              <name>AOE</name>
              <bitOffset>14</bitOffset>
              <bitWidth>1</bitWidth>
            </field>
            <field>
              <name>MOE</name>
              <bitOffset>15</bitOffset>
              <bitWidth>1</bitWidth>
            </field>
            <field>
              <name>BKF</name>
              <bitOffset>16</bitOffset>
              <bitWidth>4</bitWidth>
            </field>
            <field>
              <name>BK2F</name>
              <bitOffset>20</bitOffset>
              <bitWidth>4</bitWidth>
            </field>
            <field>
              <name>BK2E</name>
              <bitOffset>24</bitOffset>
              <bitWidth>1</bitWidth>
            </field>
            <field>
              <name>BK2P</name>
              <bitOffset>25</bitOffset>
              <bitWidth>1</bitWidth>
            </field>
            <field>
              <name>BKDSRM</name>
              <bitOffset>26</bitOffset>
              <bitWidth>1</bitWidth>
            </field>
            <field>
              <name>BK2DSRM</name>
              <bitOffset>27</bitOffset>
              <bitWidth>1</bitWidth>
            </field>
            <field>
              <name>BKBID</name>
              <bitOffset>28</bitOffset>
              <bitWidth>1</bitWidth>
            </field>
            <field>
              <name>BK2BID</name>
              <bitOffset>29</bitOffset>
              <bitWidth>1</bitWidth>
            </field>
          </fields>
        </register>
        <register>
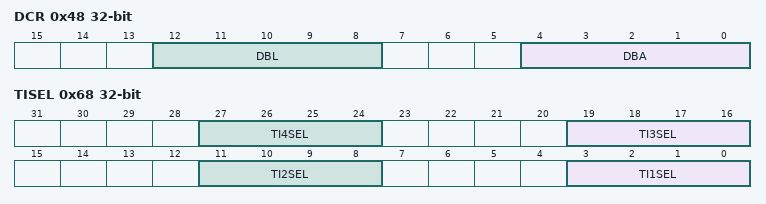
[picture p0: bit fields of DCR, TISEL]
          <name>DCR</name>
          <addressOffset>0x48</addressOffset>
          <size>0x20</size>
          <fields>
            <field>
              <name>DBA</name>
              <bitOffset>0</bitOffset>
              <bitWidth>5</bitWidth>
            </field>
            <field>
              <name>DBL</name>
              <bitOffset>8</bitOffset>
              <bitWidth>5</bitWidth>
            </field>
          </fields>
        </register>
        <register>
          <name>DMAR</name>
          <addressOffset>0x4c</addressOffset>
          <size>0x20</size>
          <fields>
            <field>
              <name>DMAB</name>
              <bitOffset>0</bitOffset>
              <bitWidth>16</bitWidth>
            </field>
          </fields>
        </register>
        <register>
          <name>CCMR3</name>
          <addressOffset>0x54</addressOffset>
          <size>0x20</size>
          <fields>
            <field>
              <name>OC5FE</name>
              <bitOffset>2</bitOffset>
              <bitWidth>1</bitWidth>
            </field>
            <field>
              <name>OC5PE</name>
              <bitOffset>3</bitOffset>
              <bitWidth>1</bitWidth>
            </field>
            <field>
              <name>OC5M</name>
              <bitOffset>4</bitOffset>
              <bitWidth>13</bitWidth>
            </field>
            <field>
              <name>OC5CE</name>
              <bitOffset>7</bitOffset>
              <bitWidth>1</bitWidth>
            </field>
            <field>
              <name>OC6FE</name>
              <bitOffset>10</bitOffset>
              <bitWidth>1</bitWidth>
            </field>
            <field>
              <name>OC6PE</name>
              <bitOffset>11</bitOffset>
              <bitWidth>1</bitWidth>
            </field>
            <field>
              <name>OC6M</name>
              <bitOffset>12</bitOffset>
              <bitWidth>13</bitWidth>
            </field>
            <field>
              <name>OC6CE</name>
              <bitOffset>15</bitOffset>
              <bitWidth>1</bitWidth>
            </field>
          </fields>
        </register>
        <register>
          <name>CCR5</name>
          <addressOffset>0x58</addressOffset>
          <size>0x20</size>
          <fields>
            <field>
              <name>CCR5</name>
              <bitOffset>0</bitOffset>
              <bitWidth>32</bitWidth>
            </field>
            <field>
              <name>GC5C1</name>
              <bitOffset>29</bitOffset>
              <bitWidth>1</bitWidth>
            </field>
            <field>
              <name>GC5C2</name>
              <bitOffset>30</bitOffset>
              <bitWidth>1</bitWidth>
            </field>
            <field>
              <name>GC5C3</name>
              <bitOffset>31</bitOffset>
              <bitWidth>1</bitWidth>
            </field>
          </fields>
        </register>
        <register>
          <name>CCR6</name>
          <addressOffset>0x5c</addressOffset>
          <size>0x20</size>
          <fields>
            <field>
              <name>CCR6</name>
              <bitOffset>0</bitOffset>
              <bitWidth>16</bitWidth>
            </field>
          </fields>
        </register>
        <register>
          <name>AF1</name>
          <addressOffset>0x60</addressOffset>
          <size>0x20</size>
        </register>
        <register>
          <name>AF2</name>
          <addressOffset>0x64</addressOffset>
          <size>0x20</size>
        </register>
        <register>
          <name>TISEL</name>
          <addressOffset>0x68</addressOffset>
          <size>0x20</size>
          <fields>
            <field>
              <name>TI1SEL</name>
              <bitOffset>0</bitOffset>
              <bitWidth>4</bitWidth>
            </field>
            <field>
              <name>TI2SEL</name>
              <bitOffset>8</bitOffset>
              <bitWidth>4</bitWidth>
            </field>
            <field>
              <name>TI3SEL</name>
              <bitOffset>16</bitOffset>
              <bitWidth>4</bitWidth>
            </field>
            <field>
              <name>TI4SEL</name>
              <bitOffset>24</bitOffset>
              <bitWidth>4</bitWidth>
            </field>
          </fields>
        </register>
      </registers>
    </peripheral>
    <peripheral>
      <name>SPI5</name>
      <baseAddress>0x40015000</baseAddress>
      <registers>
        <register>
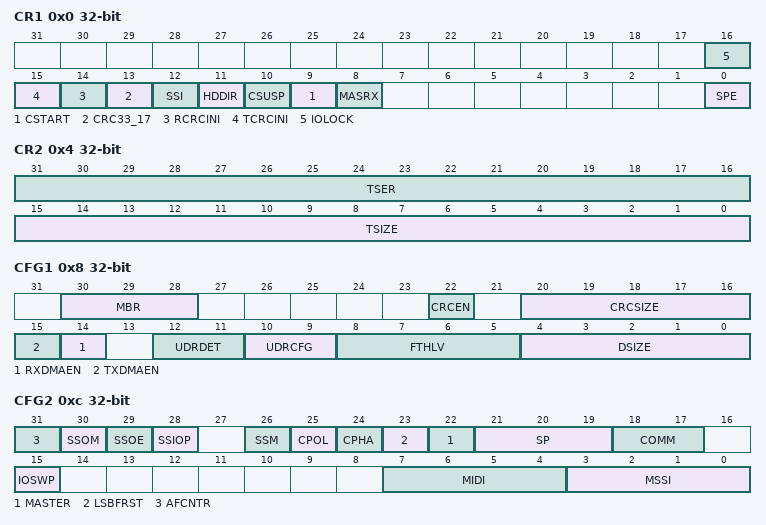
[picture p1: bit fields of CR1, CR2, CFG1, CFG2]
          <name>CR1</name>
          <addressOffset>0x0</addressOffset>
          <size>0x20</size>
          <fields>
            <field>
              <name>SPE</name>
              <bitOffset>0</bitOffset>
              <bitWidth>1</bitWidth>
            </field>
            <field>
              <name>MASRX</name>
              <bitOffset>8</bitOffset>
              <bitWidth>1</bitWidth>
            </field>
            <field>
              <name>CSTART</name>
              <bitOffset>9</bitOffset>
              <bitWidth>1</bitWidth>
            </field>
            <field>
              <name>CSUSP</name>
              <bitOffset>10</bitOffset>
              <bitWidth>1</bitWidth>
            </field>
            <field>
              <name>HDDIR</name>
              <bitOffset>11</bitOffset>
              <bitWidth>1</bitWidth>
            </field>
            <field>
              <name>SSI</name>
              <bitOffset>12</bitOffset>
              <bitWidth>1</bitWidth>
            </field>
            <field>
              <name>CRC33_17</name>
              <bitOffset>13</bitOffset>
              <bitWidth>1</bitWidth>
            </field>
            <field>
              <name>RCRCINI</name>
              <bitOffset>14</bitOffset>
              <bitWidth>1</bitWidth>
            </field>
            <field>
              <name>TCRCINI</name>
              <bitOffset>15</bitOffset>
              <bitWidth>1</bitWidth>
            </field>
            <field>
              <name>IOLOCK</name>
              <bitOffset>16</bitOffset>
              <bitWidth>1</bitWidth>
            </field>
          </fields>
        </register>
        <register>
          <name>CR2</name>
          <addressOffset>0x4</addressOffset>
          <size>0x20</size>
          <fields>
            <field>
              <name>TSIZE</name>
              <bitOffset>0</bitOffset>
              <bitWidth>16</bitWidth>
            </field>
            <field>
              <name>TSER</name>
              <bitOffset>16</bitOffset>
              <bitWidth>16</bitWidth>
            </field>
          </fields>
        </register>
        <register>
          <name>CFG1</name>
          <addressOffset>0x8</addressOffset>
          <size>0x20</size>
          <fields>
            <field>
              <name>DSIZE</name>
              <bitOffset>0</bitOffset>
              <bitWidth>5</bitWidth>
            </field>
            <field>
              <name>FTHLV</name>
              <bitOffset>5</bitOffset>
              <bitWidth>4</bitWidth>
            </field>
            <field>
              <name>UDRCFG</name>
              <bitOffset>9</bitOffset>
              <bitWidth>2</bitWidth>
            </field>
            <field>
              <name>UDRDET</name>
              <bitOffset>11</bitOffset>
              <bitWidth>2</bitWidth>
            </field>
            <field>
              <name>RXDMAEN</name>
              <bitOffset>14</bitOffset>
              <bitWidth>1</bitWidth>
            </field>
            <field>
              <name>TXDMAEN</name>
              <bitOffset>15</bitOffset>
              <bitWidth>1</bitWidth>
            </field>
            <field>
              <name>CRCSIZE</name>
              <bitOffset>16</bitOffset>
              <bitWidth>5</bitWidth>
            </field>
            <field>
              <name>CRCEN</name>
              <bitOffset>22</bitOffset>
              <bitWidth>1</bitWidth>
            </field>
            <field>
              <name>MBR</name>
              <bitOffset>28</bitOffset>
              <bitWidth>3</bitWidth>
            </field>
          </fields>
        </register>
        <register>
          <name>CFG2</name>
          <addressOffset>0xc</addressOffset>
          <size>0x20</size>
          <fields>
            <field>
              <name>MSSI</name>
              <bitOffset>0</bitOffset>
              <bitWidth>4</bitWidth>
            </field>
            <field>
              <name>MIDI</name>
              <bitOffset>4</bitOffset>
              <bitWidth>4</bitWidth>
            </field>
            <field>
              <name>IOSWP</name>
              <bitOffset>15</bitOffset>
              <bitWidth>1</bitWidth>
            </field>
            <field>
              <name>COMM</name>
              <bitOffset>17</bitOffset>
              <bitWidth>2</bitWidth>
            </field>
            <field>
              <name>SP</name>
              <bitOffset>19</bitOffset>
              <bitWidth>3</bitWidth>
            </field>
            <field>
              <name>MASTER</name>
              <bitOffset>22</bitOffset>
              <bitWidth>1</bitWidth>
            </field>
            <field>
              <name>LSBFRST</name>
              <bitOffset>23</bitOffset>
              <bitWidth>1</bitWidth>
            </field>
            <field>
              <name>CPHA</name>
              <bitOffset>24</bitOffset>
              <bitWidth>1</bitWidth>
            </field>
            <field>
              <name>CPOL</name>
              <bitOffset>25</bitOffset>
              <bitWidth>1</bitWidth>
            </field>
            <field>
              <name>SSM</name>
              <bitOffset>26</bitOffset>
              <bitWidth>1</bitWidth>
            </field>
            <field>
              <name>SSIOP</name>
              <bitOffset>28</bitOffset>
              <bitWidth>1</bitWidth>
            </field>
            <field>
              <name>SSOE</name>
              <bitOffset>29</bitOffset>
              <bitWidth>1</bitWidth>
            </field>
            <field>
              <name>SSOM</name>
              <bitOffset>30</bitOffset>
              <bitWidth>1</bitWidth>
            </field>
            <field>
              <name>AFCNTR</name>
              <bitOffset>31</bitOffset>
              <bitWidth>1</bitWidth>
            </field>
          </fields>
        </register>
        <register>
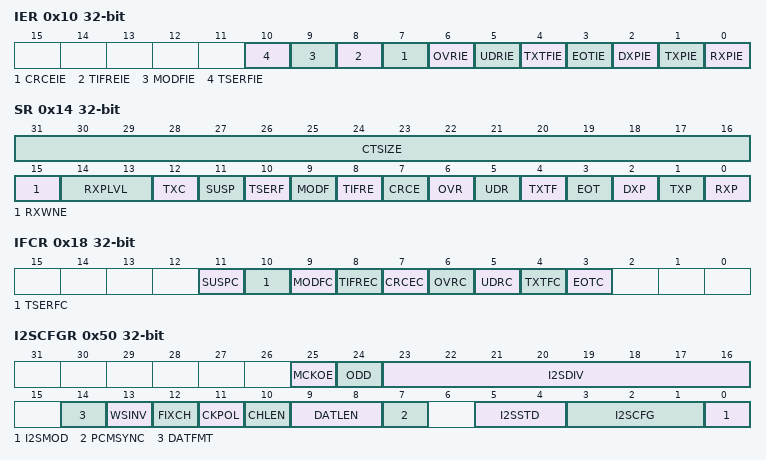
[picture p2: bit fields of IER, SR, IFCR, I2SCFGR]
          <name>IER</name>
          <addressOffset>0x10</addressOffset>
          <size>0x20</size>
          <fields>
            <field>
              <name>RXPIE</name>
              <bitOffset>0</bitOffset>
              <bitWidth>1</bitWidth>
            </field>
            <field>
              <name>TXPIE</name>
              <bitOffset>1</bitOffset>
              <bitWidth>1</bitWidth>
            </field>
            <field>
              <name>DXPIE</name>
              <bitOffset>2</bitOffset>
              <bitWidth>1</bitWidth>
            </field>
            <field>
              <name>EOTIE</name>
              <bitOffset>3</bitOffset>
              <bitWidth>1</bitWidth>
            </field>
            <field>
              <name>TXTFIE</name>
              <bitOffset>4</bitOffset>
              <bitWidth>1</bitWidth>
            </field>
            <field>
              <name>UDRIE</name>
              <bitOffset>5</bitOffset>
              <bitWidth>1</bitWidth>
            </field>
            <field>
              <name>OVRIE</name>
              <bitOffset>6</bitOffset>
              <bitWidth>1</bitWidth>
            </field>
            <field>
              <name>CRCEIE</name>
              <bitOffset>7</bitOffset>
              <bitWidth>1</bitWidth>
            </field>
            <field>
              <name>TIFREIE</name>
              <bitOffset>8</bitOffset>
              <bitWidth>1</bitWidth>
            </field>
            <field>
              <name>MODFIE</name>
              <bitOffset>9</bitOffset>
              <bitWidth>1</bitWidth>
            </field>
            <field>
              <name>TSERFIE</name>
              <bitOffset>10</bitOffset>
              <bitWidth>1</bitWidth>
            </field>
          </fields>
        </register>
        <register>
          <name>SR</name>
          <addressOffset>0x14</addressOffset>
          <size>0x20</size>
          <fields>
            <field>
              <name>RXP</name>
              <bitOffset>0</bitOffset>
              <bitWidth>1</bitWidth>
            </field>
            <field>
              <name>TXP</name>
              <bitOffset>1</bitOffset>
              <bitWidth>1</bitWidth>
            </field>
            <field>
              <name>DXP</name>
              <bitOffset>2</bitOffset>
              <bitWidth>1</bitWidth>
            </field>
            <field>
              <name>EOT</name>
              <bitOffset>3</bitOffset>
              <bitWidth>1</bitWidth>
            </field>
            <field>
              <name>TXTF</name>
              <bitOffset>4</bitOffset>
              <bitWidth>1</bitWidth>
            </field>
            <field>
              <name>UDR</name>
              <bitOffset>5</bitOffset>
              <bitWidth>1</bitWidth>
            </field>
            <field>
              <name>OVR</name>
              <bitOffset>6</bitOffset>
              <bitWidth>1</bitWidth>
            </field>
            <field>
              <name>CRCE</name>
              <bitOffset>7</bitOffset>
              <bitWidth>1</bitWidth>
            </field>
            <field>
              <name>TIFRE</name>
              <bitOffset>8</bitOffset>
              <bitWidth>1</bitWidth>
            </field>
            <field>
              <name>MODF</name>
              <bitOffset>9</bitOffset>
              <bitWidth>1</bitWidth>
            </field>
            <field>
              <name>TSERF</name>
              <bitOffset>10</bitOffset>
              <bitWidth>1</bitWidth>
            </field>
            <field>
              <name>SUSP</name>
              <bitOffset>11</bitOffset>
              <bitWidth>1</bitWidth>
            </field>
            <field>
              <name>TXC</name>
              <bitOffset>12</bitOffset>
              <bitWidth>1</bitWidth>
            </field>
            <field>
              <name>RXPLVL</name>
              <bitOffset>13</bitOffset>
              <bitWidth>2</bitWidth>
            </field>
            <field>
              <name>RXWNE</name>
              <bitOffset>15</bitOffset>
              <bitWidth>1</bitWidth>
            </field>
            <field>
              <name>CTSIZE</name>
              <bitOffset>16</bitOffset>
              <bitWidth>16</bitWidth>
            </field>
          </fields>
        </register>
        <register>
          <name>IFCR</name>
          <addressOffset>0x18</addressOffset>
          <size>0x20</size>
          <fields>
            <field>
              <name>EOTC</name>
              <bitOffset>3</bitOffset>
              <bitWidth>1</bitWidth>
            </field>
            <field>
              <name>TXTFC</name>
              <bitOffset>4</bitOffset>
              <bitWidth>1</bitWidth>
            </field>
            <field>
              <name>UDRC</name>
              <bitOffset>5</bitOffset>
              <bitWidth>1</bitWidth>
            </field>
            <field>
              <name>OVRC</name>
              <bitOffset>6</bitOffset>
              <bitWidth>1</bitWidth>
            </field>
            <field>
              <name>CRCEC</name>
              <bitOffset>7</bitOffset>
              <bitWidth>1</bitWidth>
            </field>
            <field>
              <name>TIFREC</name>
              <bitOffset>8</bitOffset>
              <bitWidth>1</bitWidth>
            </field>
            <field>
              <name>MODFC</name>
              <bitOffset>9</bitOffset>
              <bitWidth>1</bitWidth>
            </field>
            <field>
              <name>TSERFC</name>
              <bitOffset>10</bitOffset>
              <bitWidth>1</bitWidth>
            </field>
            <field>
              <name>SUSPC</name>
              <bitOffset>11</bitOffset>
              <bitWidth>1</bitWidth>
            </field>
          </fields>
        </register>
        <register>
          <name>TXDR</name>
          <addressOffset>0x20</addressOffset>
          <size>0x20</size>
          <fields>
            <field>
              <name>TXDR</name>
              <bitOffset>0</bitOffset>
              <bitWidth>32</bitWidth>
            </field>
          </fields>
        </register>
        <register>
          <name>RXDR</name>
          <addressOffset>0x30</addressOffset>
          <size>0x20</size>
          <fields>
            <field>
              <name>RXDR</name>
              <bitOffset>0</bitOffset>
              <bitWidth>32</bitWidth>
            </field>
          </fields>
        </register>
        <register>
          <name>CRCPOLY</name>
          <addressOffset>0x40</addressOffset>
          <size>0x20</size>
          <fields>
            <field>
              <name>CRCPOLY</name>
              <bitOffset>0</bitOffset>
              <bitWidth>32</bitWidth>
            </field>
          </fields>
        </register>
        <register>
          <name>TXCRC</name>
          <addressOffset>0x44</addressOffset>
          <size>0x20</size>
          <fields>
            <field>
              <name>TXCRC</name>
              <bitOffset>0</bitOffset>
              <bitWidth>32</bitWidth>
            </field>
          </fields>
        </register>
        <register>
          <name>RXCRC</name>
          <addressOffset>0x48</addressOffset>
          <size>0x20</size>
          <fields>
            <field>
              <name>RXCRC</name>
              <bitOffset>0</bitOffset>
              <bitWidth>32</bitWidth>
            </field>
          </fields>
        </register>
        <register>
          <name>UDRDR</name>
          <addressOffset>0x4c</addressOffset>
          <size>0x20</size>
          <fields>
            <field>
              <name>UDRDR</name>
              <bitOffset>0</bitOffset>
              <bitWidth>32</bitWidth>
            </field>
          </fields>
        </register>
        <register>
          <name>I2SCFGR</name>
          <addressOffset>0x50</addressOffset>
          <size>0x20</size>
          <fields>
            <field>
              <name>I2SMOD</name>
              <bitOffset>0</bitOffset>
              <bitWidth>1</bitWidth>
            </field>
            <field>
              <name>I2SCFG</name>
              <bitOffset>1</bitOffset>
              <bitWidth>3</bitWidth>
            </field>
            <field>
              <name>I2SSTD</name>
              <bitOffset>4</bitOffset>
              <bitWidth>2</bitWidth>
            </field>
            <field>
              <name>PCMSYNC</name>
              <bitOffset>7</bitOffset>
              <bitWidth>1</bitWidth>
            </field>
            <field>
              <name>DATLEN</name>
              <bitOffset>8</bitOffset>
              <bitWidth>2</bitWidth>
            </field>
            <field>
              <name>CHLEN</name>
              <bitOffset>10</bitOffset>
              <bitWidth>1</bitWidth>
            </field>
            <field>
              <name>CKPOL</name>
              <bitOffset>11</bitOffset>
              <bitWidth>1</bitWidth>
            </field>
            <field>
              <name>FIXCH</name>
              <bitOffset>12</bitOffset>
              <bitWidth>1</bitWidth>
            </field>
            <field>
              <name>WSINV</name>
              <bitOffset>13</bitOffset>
              <bitWidth>1</bitWidth>
            </field>
            <field>
              <name>DATFMT</name>
              <bitOffset>14</bitOffset>
              <bitWidth>1</bitWidth>
            </field>
            <field>
              <name>I2SDIV</name>
              <bitOffset>16</bitOffset>
              <bitWidth>8</bitWidth>
            </field>
            <field>
              <name>ODD</name>
              <bitOffset>24</bitOffset>
              <bitWidth>1</bitWidth>
            </field>
            <field>
              <name>MCKOE</name>
              <bitOffset>25</bitOffset>
              <bitWidth>1</bitWidth>
            </field>
          </fields>
        </register>
      </registers>
    </peripheral>
    <peripheral>
      <name>SAI1</name>
      <baseAddress>0x40015800</baseAddress>
      <registers>
        <register>
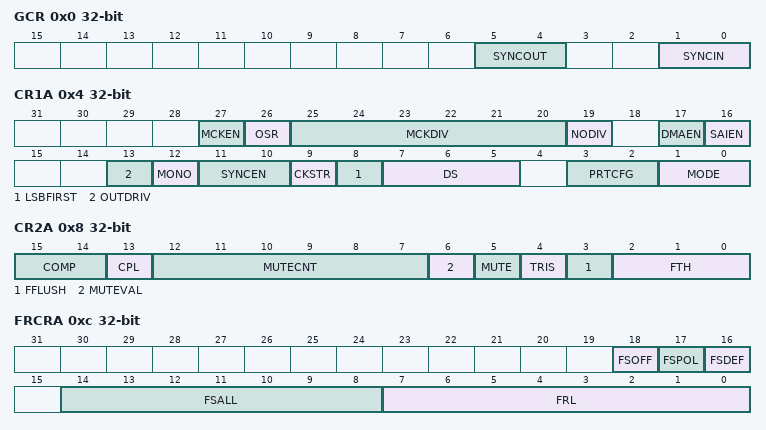
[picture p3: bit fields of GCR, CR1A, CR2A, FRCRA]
          <name>GCR</name>
          <addressOffset>0x0</addressOffset>
          <size>0x20</size>
          <fields>
            <field>
              <name>SYNCIN</name>
              <bitOffset>0</bitOffset>
              <bitWidth>2</bitWidth>
            </field>
            <field>
              <name>SYNCOUT</name>
              <bitOffset>4</bitOffset>
              <bitWidth>2</bitWidth>
            </field>
          </fields>
        </register>
        <register>
          <name>CR1A</name>
          <addressOffset>0x4</addressOffset>
          <size>0x20</size>
          <fields>
            <field>
              <name>MODE</name>
              <bitOffset>0</bitOffset>
              <bitWidth>2</bitWidth>
            </field>
            <field>
              <name>PRTCFG</name>
              <bitOffset>2</bitOffset>
              <bitWidth>2</bitWidth>
            </field>
            <field>
              <name>DS</name>
              <bitOffset>5</bitOffset>
              <bitWidth>3</bitWidth>
            </field>
            <field>
              <name>LSBFIRST</name>
              <bitOffset>8</bitOffset>
              <bitWidth>1</bitWidth>
            </field>
            <field>
              <name>CKSTR</name>
              <bitOffset>9</bitOffset>
              <bitWidth>1</bitWidth>
            </field>
            <field>
              <name>SYNCEN</name>
              <bitOffset>10</bitOffset>
              <bitWidth>2</bitWidth>
            </field>
            <field>
              <name>MONO</name>
              <bitOffset>12</bitOffset>
              <bitWidth>1</bitWidth>
            </field>
            <field>
              <name>OUTDRIV</name>
              <bitOffset>13</bitOffset>
              <bitWidth>1</bitWidth>
            </field>
            <field>
              <name>SAIEN</name>
              <bitOffset>16</bitOffset>
              <bitWidth>1</bitWidth>
            </field>
            <field>
              <name>DMAEN</name>
              <bitOffset>17</bitOffset>
              <bitWidth>1</bitWidth>
            </field>
            <field>
              <name>NODIV</name>
              <bitOffset>19</bitOffset>
              <bitWidth>1</bitWidth>
            </field>
            <field>
              <name>MCKDIV</name>
              <bitOffset>20</bitOffset>
              <bitWidth>6</bitWidth>
            </field>
            <field>
              <name>OSR</name>
              <bitOffset>26</bitOffset>
              <bitWidth>1</bitWidth>
            </field>
            <field>
              <name>MCKEN</name>
              <bitOffset>27</bitOffset>
              <bitWidth>1</bitWidth>
            </field>
          </fields>
        </register>
        <register>
          <name>CR1A</name>
          <addressOffset>0x4</addressOffset>
          <size>0x20</size>
          <fields>
            <field>
              <name>MODE</name>
              <bitOffset>0</bitOffset>
              <bitWidth>2</bitWidth>
            </field>
            <field>
              <name>PRTCFG</name>
              <bitOffset>2</bitOffset>
              <bitWidth>2</bitWidth>
            </field>
            <field>
              <name>DS</name>
              <bitOffset>5</bitOffset>
              <bitWidth>3</bitWidth>
            </field>
            <field>
              <name>LSBFIRST</name>
              <bitOffset>8</bitOffset>
              <bitWidth>1</bitWidth>
            </field>
            <field>
              <name>CKSTR</name>
              <bitOffset>9</bitOffset>
              <bitWidth>1</bitWidth>
            </field>
            <field>
              <name>SYNCEN</name>
              <bitOffset>10</bitOffset>
              <bitWidth>2</bitWidth>
            </field>
            <field>
              <name>MONO</name>
              <bitOffset>12</bitOffset>
              <bitWidth>1</bitWidth>
            </field>
            <field>
              <name>OUTDRIV</name>
              <bitOffset>13</bitOffset>
              <bitWidth>1</bitWidth>
            </field>
            <field>
              <name>SAIEN</name>
              <bitOffset>16</bitOffset>
              <bitWidth>1</bitWidth>
            </field>
            <field>
              <name>DMAEN</name>
              <bitOffset>17</bitOffset>
              <bitWidth>1</bitWidth>
            </field>
            <field>
              <name>NODIV</name>
              <bitOffset>19</bitOffset>
              <bitWidth>1</bitWidth>
            </field>
            <field>
              <name>MCKDIV</name>
              <bitOffset>20</bitOffset>
              <bitWidth>6</bitWidth>
            </field>
            <field>
              <name>OSR</name>
              <bitOffset>26</bitOffset>
              <bitWidth>1</bitWidth>
            </field>
            <field>
              <name>MCKEN</name>
              <bitOffset>27</bitOffset>
              <bitWidth>1</bitWidth>
            </field>
          </fields>
        </register>
        <register>
          <name>CR2A</name>
          <addressOffset>0x8</addressOffset>
          <size>0x20</size>
          <fields>
            <field>
              <name>FTH</name>
              <bitOffset>0</bitOffset>
              <bitWidth>3</bitWidth>
            </field>
            <field>
              <name>FFLUSH</name>
              <bitOffset>3</bitOffset>
              <bitWidth>1</bitWidth>
            </field>
            <field>
              <name>TRIS</name>
              <bitOffset>4</bitOffset>
              <bitWidth>1</bitWidth>
            </field>
            <field>
              <name>MUTE</name>
              <bitOffset>5</bitOffset>
              <bitWidth>1</bitWidth>
            </field>
            <field>
              <name>MUTEVAL</name>
              <bitOffset>6</bitOffset>
              <bitWidth>1</bitWidth>
            </field>
            <field>
              <name>MUTECNT</name>
              <bitOffset>7</bitOffset>
              <bitWidth>6</bitWidth>
            </field>
            <field>
              <name>CPL</name>
              <bitOffset>13</bitOffset>
              <bitWidth>1</bitWidth>
            </field>
            <field>
              <name>COMP</name>
              <bitOffset>14</bitOffset>
              <bitWidth>2</bitWidth>
            </field>
          </fields>
        </register>
        <register>
          <name>CR2A</name>
          <addressOffset>0x8</addressOffset>
          <size>0x20</size>
          <fields>
            <field>
              <name>FTH</name>
              <bitOffset>0</bitOffset>
              <bitWidth>3</bitWidth>
            </field>
            <field>
              <name>FFLUSH</name>
              <bitOffset>3</bitOffset>
              <bitWidth>1</bitWidth>
            </field>
            <field>
              <name>TRIS</name>
              <bitOffset>4</bitOffset>
              <bitWidth>1</bitWidth>
            </field>
            <field>
              <name>MUTE</name>
              <bitOffset>5</bitOffset>
              <bitWidth>1</bitWidth>
            </field>
            <field>
              <name>MUTEVAL</name>
              <bitOffset>6</bitOffset>
              <bitWidth>1</bitWidth>
            </field>
            <field>
              <name>MUTECNT</name>
              <bitOffset>7</bitOffset>
              <bitWidth>6</bitWidth>
            </field>
            <field>
              <name>CPL</name>
              <bitOffset>13</bitOffset>
              <bitWidth>1</bitWidth>
            </field>
            <field>
              <name>COMP</name>
              <bitOffset>14</bitOffset>
              <bitWidth>2</bitWidth>
            </field>
          </fields>
        </register>
        <register>
          <name>FRCRA</name>
          <addressOffset>0xc</addressOffset>
          <size>0x20</size>
          <fields>
            <field>
              <name>FRL</name>
              <bitOffset>0</bitOffset>
              <bitWidth>8</bitWidth>
            </field>
            <field>
              <name>FSALL</name>
              <bitOffset>8</bitOffset>
              <bitWidth>7</bitWidth>
            </field>
            <field>
              <name>FSDEF</name>
              <bitOffset>16</bitOffset>
              <bitWidth>1</bitWidth>
            </field>
            <field>
              <name>FSPOL</name>
              <bitOffset>17</bitOffset>
              <bitWidth>1</bitWidth>
            </field>
            <field>
              <name>FSOFF</name>
              <bitOffset>18</bitOffset>
              <bitWidth>1</bitWidth>
            </field>
          </fields>
        </register>
        <register>
          <name>FRCRA</name>
          <addressOffset>0xc</addressOffset>
          <size>0x20</size>
          <fields>
            <field>
              <name>FRL</name>
              <bitOffset>0</bitOffset>
              <bitWidth>8</bitWidth>
            </field>
            <field>
              <name>FSALL</name>
              <bitOffset>8</bitOffset>
              <bitWidth>7</bitWidth>
            </field>
            <field>
              <name>FSDEF</name>
              <bitOffset>16</bitOffset>
              <bitWidth>1</bitWidth>
            </field>
            <field>
              <name>FSPOL</name>
              <bitOffset>17</bitOffset>
              <bitWidth>1</bitWidth>
            </field>
            <field>
              <name>FSOFF</name>
              <bitOffset>18</bitOffset>
              <bitWidth>1</bitWidth>
            </field>
          </fields>
        </register>
        <register>
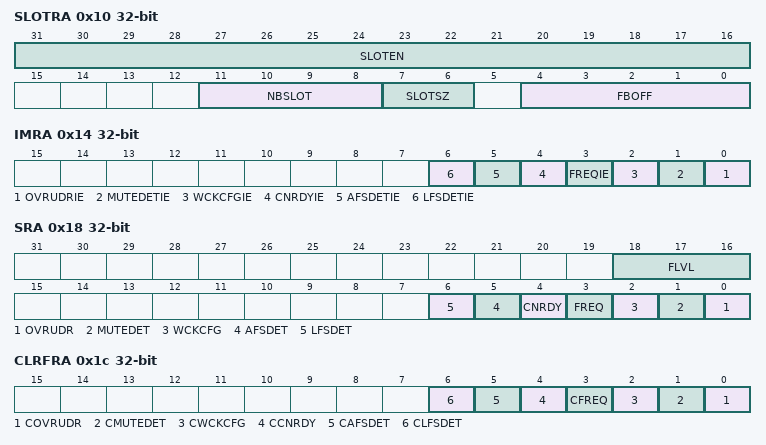
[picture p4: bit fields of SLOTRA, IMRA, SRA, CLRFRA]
          <name>SLOTRA</name>
          <addressOffset>0x10</addressOffset>
          <size>0x20</size>
          <fields>
            <field>
              <name>FBOFF</name>
              <bitOffset>0</bitOffset>
              <bitWidth>5</bitWidth>
            </field>
            <field>
              <name>SLOTSZ</name>
              <bitOffset>6</bitOffset>
              <bitWidth>2</bitWidth>
            </field>
            <field>
              <name>NBSLOT</name>
              <bitOffset>8</bitOffset>
              <bitWidth>4</bitWidth>
            </field>
            <field>
              <name>SLOTEN</name>
              <bitOffset>16</bitOffset>
              <bitWidth>16</bitWidth>
            </field>
          </fields>
        </register>
        <register>
          <name>SLOTRA</name>
          <addressOffset>0x10</addressOffset>
          <size>0x20</size>
          <fields>
            <field>
              <name>FBOFF</name>
              <bitOffset>0</bitOffset>
              <bitWidth>5</bitWidth>
            </field>
            <field>
              <name>SLOTSZ</name>
              <bitOffset>6</bitOffset>
              <bitWidth>2</bitWidth>
            </field>
            <field>
              <name>NBSLOT</name>
              <bitOffset>8</bitOffset>
              <bitWidth>4</bitWidth>
            </field>
            <field>
              <name>SLOTEN</name>
              <bitOffset>16</bitOffset>
              <bitWidth>16</bitWidth>
            </field>
          </fields>
        </register>
        <register>
          <name>IMRA</name>
          <addressOffset>0x14</addressOffset>
          <size>0x20</size>
          <fields>
            <field>
              <name>OVRUDRIE</name>
              <bitOffset>0</bitOffset>
              <bitWidth>1</bitWidth>
            </field>
            <field>
              <name>MUTEDETIE</name>
              <bitOffset>1</bitOffset>
              <bitWidth>1</bitWidth>
            </field>
            <field>
              <name>WCKCFGIE</name>
              <bitOffset>2</bitOffset>
              <bitWidth>1</bitWidth>
            </field>
            <field>
              <name>FREQIE</name>
              <bitOffset>3</bitOffset>
              <bitWidth>1</bitWidth>
            </field>
            <field>
              <name>CNRDYIE</name>
              <bitOffset>4</bitOffset>
              <bitWidth>1</bitWidth>
            </field>
            <field>
              <name>AFSDETIE</name>
              <bitOffset>5</bitOffset>
              <bitWidth>1</bitWidth>
            </field>
            <field>
              <name>LFSDETIE</name>
              <bitOffset>6</bitOffset>
              <bitWidth>1</bitWidth>
            </field>
          </fields>
        </register>
        <register>
          <name>IMRA</name>
          <addressOffset>0x14</addressOffset>
          <size>0x20</size>
          <fields>
            <field>
              <name>OVRUDRIE</name>
              <bitOffset>0</bitOffset>
              <bitWidth>1</bitWidth>
            </field>
            <field>
              <name>MUTEDETIE</name>
              <bitOffset>1</bitOffset>
              <bitWidth>1</bitWidth>
            </field>
            <field>
              <name>WCKCFGIE</name>
              <bitOffset>2</bitOffset>
              <bitWidth>1</bitWidth>
            </field>
            <field>
              <name>FREQIE</name>
              <bitOffset>3</bitOffset>
              <bitWidth>1</bitWidth>
            </field>
            <field>
              <name>CNRDYIE</name>
              <bitOffset>4</bitOffset>
              <bitWidth>1</bitWidth>
            </field>
            <field>
              <name>AFSDETIE</name>
              <bitOffset>5</bitOffset>
              <bitWidth>1</bitWidth>
            </field>
            <field>
              <name>LFSDETIE</name>
              <bitOffset>6</bitOffset>
              <bitWidth>1</bitWidth>
            </field>
          </fields>
        </register>
        <register>
          <name>SRA</name>
          <addressOffset>0x18</addressOffset>
          <size>0x20</size>
          <fields>
            <field>
              <name>OVRUDR</name>
              <bitOffset>0</bitOffset>
              <bitWidth>1</bitWidth>
            </field>
            <field>
              <name>MUTEDET</name>
              <bitOffset>1</bitOffset>
              <bitWidth>1</bitWidth>
            </field>
            <field>
              <name>WCKCFG</name>
              <bitOffset>2</bitOffset>
              <bitWidth>1</bitWidth>
            </field>
            <field>
              <name>FREQ</name>
              <bitOffset>3</bitOffset>
              <bitWidth>1</bitWidth>
            </field>
            <field>
              <name>CNRDY</name>
              <bitOffset>4</bitOffset>
              <bitWidth>1</bitWidth>
            </field>
            <field>
              <name>AFSDET</name>
              <bitOffset>5</bitOffset>
              <bitWidth>1</bitWidth>
            </field>
            <field>
              <name>LFSDET</name>
              <bitOffset>6</bitOffset>
              <bitWidth>1</bitWidth>
            </field>
            <field>
              <name>FLVL</name>
              <bitOffset>16</bitOffset>
              <bitWidth>3</bitWidth>
            </field>
          </fields>
        </register>
        <register>
          <name>SRA</name>
          <addressOffset>0x18</addressOffset>
          <size>0x20</size>
          <fields>
            <field>
              <name>OVRUDR</name>
              <bitOffset>0</bitOffset>
              <bitWidth>1</bitWidth>
            </field>
            <field>
              <name>MUTEDET</name>
              <bitOffset>1</bitOffset>
              <bitWidth>1</bitWidth>
            </field>
            <field>
              <name>WCKCFG</name>
              <bitOffset>2</bitOffset>
              <bitWidth>1</bitWidth>
            </field>
            <field>
              <name>FREQ</name>
              <bitOffset>3</bitOffset>
              <bitWidth>1</bitWidth>
            </field>
            <field>
              <name>CNRDY</name>
              <bitOffset>4</bitOffset>
              <bitWidth>1</bitWidth>
            </field>
            <field>
              <name>AFSDET</name>
              <bitOffset>5</bitOffset>
              <bitWidth>1</bitWidth>
            </field>
            <field>
              <name>LFSDET</name>
              <bitOffset>6</bitOffset>
              <bitWidth>1</bitWidth>
            </field>
            <field>
              <name>FLVL</name>
              <bitOffset>16</bitOffset>
              <bitWidth>3</bitWidth>
            </field>
          </fields>
        </register>
        <register>
          <name>CLRFRA</name>
          <addressOffset>0x1c</addressOffset>
          <size>0x20</size>
          <fields>
            <field>
              <name>COVRUDR</name>
              <bitOffset>0</bitOffset>
              <bitWidth>1</bitWidth>
            </field>
            <field>
              <name>CMUTEDET</name>
              <bitOffset>1</bitOffset>
              <bitWidth>1</bitWidth>
            </field>
            <field>
              <name>CWCKCFG</name>
              <bitOffset>2</bitOffset>
              <bitWidth>1</bitWidth>
            </field>
            <field>
              <name>CFREQ</name>
              <bitOffset>3</bitOffset>
              <bitWidth>1</bitWidth>
            </field>
            <field>
              <name>CCNRDY</name>
              <bitOffset>4</bitOffset>
              <bitWidth>1</bitWidth>
            </field>
            <field>
              <name>CAFSDET</name>
              <bitOffset>5</bitOffset>
              <bitWidth>1</bitWidth>
            </field>
            <field>
              <name>CLFSDET</name>
              <bitOffset>6</bitOffset>
              <bitWidth>1</bitWidth>
            </field>
          </fields>
        </register>
        <register>
          <name>CLRFRA</name>
          <addressOffset>0x1c</addressOffset>
          <size>0x20</size>
          <fields>
            <field>
              <name>COVRUDR</name>
              <bitOffset>0</bitOffset>
              <bitWidth>1</bitWidth>
            </field>
            <field>
              <name>CMUTEDET</name>
              <bitOffset>1</bitOffset>
              <bitWidth>1</bitWidth>
            </field>
            <field>
              <name>CWCKCFG</name>
              <bitOffset>2</bitOffset>
              <bitWidth>1</bitWidth>
            </field>
            <field>
              <name>CFREQ</name>
              <bitOffset>3</bitOffset>
              <bitWidth>1</bitWidth>
            </field>
            <field>
              <name>CCNRDY</name>
              <bitOffset>4</bitOffset>
              <bitWidth>1</bitWidth>
            </field>
            <field>
              <name>CAFSDET</name>
              <bitOffset>5</bitOffset>
              <bitWidth>1</bitWidth>
            </field>
            <field>
              <name>CLFSDET</name>
              <bitOffset>6</bitOffset>
              <bitWidth>1</bitWidth>
            </field>
          </fields>
        </register>
        <register>
          <name>DRA</name>
          <addressOffset>0x20</addressOffset>
          <size>0x20</size>
          <fields>
            <field>
              <name>DATA</name>
              <bitOffset>0</bitOffset>
              <bitWidth>32</bitWidth>
            </field>
          </fields>
        </register>
        <register>
          <name>DRA</name>
          <addressOffset>0x20</addressOffset>
          <size>0x20</size>
          <fields>
            <field>
              <name>DATA</name>
              <bitOffset>0</bitOffset>
              <bitWidth>32</bitWidth>
            </field>
          </fields>
        </register>
        <register>
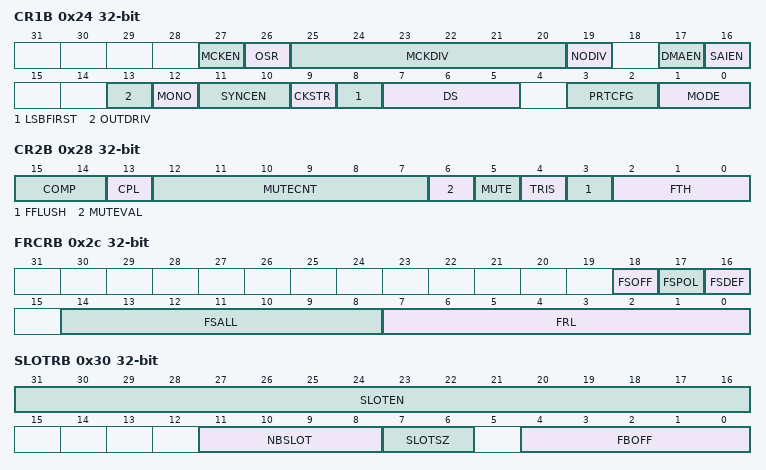
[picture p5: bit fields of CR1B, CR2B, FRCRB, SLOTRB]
          <name>CR1B</name>
          <addressOffset>0x24</addressOffset>
          <size>0x20</size>
          <fields>
            <field>
              <name>MODE</name>
              <bitOffset>0</bitOffset>
              <bitWidth>2</bitWidth>
            </field>
            <field>
              <name>PRTCFG</name>
              <bitOffset>2</bitOffset>
              <bitWidth>2</bitWidth>
            </field>
            <field>
              <name>DS</name>
              <bitOffset>5</bitOffset>
              <bitWidth>3</bitWidth>
            </field>
            <field>
              <name>LSBFIRST</name>
              <bitOffset>8</bitOffset>
              <bitWidth>1</bitWidth>
            </field>
            <field>
              <name>CKSTR</name>
              <bitOffset>9</bitOffset>
              <bitWidth>1</bitWidth>
            </field>
            <field>
              <name>SYNCEN</name>
              <bitOffset>10</bitOffset>
              <bitWidth>2</bitWidth>
            </field>
            <field>
              <name>MONO</name>
              <bitOffset>12</bitOffset>
              <bitWidth>1</bitWidth>
            </field>
            <field>
              <name>OUTDRIV</name>
              <bitOffset>13</bitOffset>
              <bitWidth>1</bitWidth>
            </field>
            <field>
              <name>SAIEN</name>
              <bitOffset>16</bitOffset>
              <bitWidth>1</bitWidth>
            </field>
            <field>
              <name>DMAEN</name>
              <bitOffset>17</bitOffset>
              <bitWidth>1</bitWidth>
            </field>
            <field>
              <name>NODIV</name>
              <bitOffset>19</bitOffset>
              <bitWidth>1</bitWidth>
            </field>
            <field>
              <name>MCKDIV</name>
              <bitOffset>20</bitOffset>
              <bitWidth>6</bitWidth>
            </field>
            <field>
              <name>OSR</name>
              <bitOffset>26</bitOffset>
              <bitWidth>1</bitWidth>
            </field>
            <field>
              <name>MCKEN</name>
              <bitOffset>27</bitOffset>
              <bitWidth>1</bitWidth>
            </field>
          </fields>
        </register>
        <register>
          <name>CR1B</name>
          <addressOffset>0x24</addressOffset>
          <size>0x20</size>
          <fields>
            <field>
              <name>MODE</name>
              <bitOffset>0</bitOffset>
              <bitWidth>2</bitWidth>
            </field>
            <field>
              <name>PRTCFG</name>
              <bitOffset>2</bitOffset>
              <bitWidth>2</bitWidth>
            </field>
            <field>
              <name>DS</name>
              <bitOffset>5</bitOffset>
              <bitWidth>3</bitWidth>
            </field>
            <field>
              <name>LSBFIRST</name>
              <bitOffset>8</bitOffset>
              <bitWidth>1</bitWidth>
            </field>
            <field>
              <name>CKSTR</name>
              <bitOffset>9</bitOffset>
              <bitWidth>1</bitWidth>
            </field>
            <field>
              <name>SYNCEN</name>
              <bitOffset>10</bitOffset>
              <bitWidth>2</bitWidth>
            </field>
            <field>
              <name>MONO</name>
              <bitOffset>12</bitOffset>
              <bitWidth>1</bitWidth>
            </field>
            <field>
              <name>OUTDRIV</name>
              <bitOffset>13</bitOffset>
              <bitWidth>1</bitWidth>
            </field>
            <field>
              <name>SAIEN</name>
              <bitOffset>16</bitOffset>
              <bitWidth>1</bitWidth>
            </field>
            <field>
              <name>DMAEN</name>
              <bitOffset>17</bitOffset>
              <bitWidth>1</bitWidth>
            </field>
            <field>
              <name>NODIV</name>
              <bitOffset>19</bitOffset>
              <bitWidth>1</bitWidth>
            </field>
            <field>
              <name>MCKDIV</name>
              <bitOffset>20</bitOffset>
              <bitWidth>6</bitWidth>
            </field>
            <field>
              <name>OSR</name>
              <bitOffset>26</bitOffset>
              <bitWidth>1</bitWidth>
            </field>
            <field>
              <name>MCKEN</name>
              <bitOffset>27</bitOffset>
              <bitWidth>1</bitWidth>
            </field>
          </fields>
        </register>
        <register>
          <name>CR2B</name>
          <addressOffset>0x28</addressOffset>
          <size>0x20</size>
          <fields>
            <field>
              <name>FTH</name>
              <bitOffset>0</bitOffset>
              <bitWidth>3</bitWidth>
            </field>
            <field>
              <name>FFLUSH</name>
              <bitOffset>3</bitOffset>
              <bitWidth>1</bitWidth>
            </field>
            <field>
              <name>TRIS</name>
              <bitOffset>4</bitOffset>
              <bitWidth>1</bitWidth>
            </field>
            <field>
              <name>MUTE</name>
              <bitOffset>5</bitOffset>
              <bitWidth>1</bitWidth>
            </field>
            <field>
              <name>MUTEVAL</name>
              <bitOffset>6</bitOffset>
              <bitWidth>1</bitWidth>
            </field>
            <field>
              <name>MUTECNT</name>
              <bitOffset>7</bitOffset>
              <bitWidth>6</bitWidth>
            </field>
            <field>
              <name>CPL</name>
              <bitOffset>13</bitOffset>
              <bitWidth>1</bitWidth>
            </field>
            <field>
              <name>COMP</name>
              <bitOffset>14</bitOffset>
              <bitWidth>2</bitWidth>
            </field>
          </fields>
        </register>
        <register>
          <name>CR2B</name>
          <addressOffset>0x28</addressOffset>
          <size>0x20</size>
          <fields>
            <field>
              <name>FTH</name>
              <bitOffset>0</bitOffset>
              <bitWidth>3</bitWidth>
            </field>
            <field>
              <name>FFLUSH</name>
              <bitOffset>3</bitOffset>
              <bitWidth>1</bitWidth>
            </field>
            <field>
              <name>TRIS</name>
              <bitOffset>4</bitOffset>
              <bitWidth>1</bitWidth>
            </field>
            <field>
              <name>MUTE</name>
              <bitOffset>5</bitOffset>
              <bitWidth>1</bitWidth>
            </field>
            <field>
              <name>MUTEVAL</name>
              <bitOffset>6</bitOffset>
              <bitWidth>1</bitWidth>
            </field>
            <field>
              <name>MUTECNT</name>
              <bitOffset>7</bitOffset>
              <bitWidth>6</bitWidth>
            </field>
            <field>
              <name>CPL</name>
              <bitOffset>13</bitOffset>
              <bitWidth>1</bitWidth>
            </field>
            <field>
              <name>COMP</name>
              <bitOffset>14</bitOffset>
              <bitWidth>2</bitWidth>
            </field>
          </fields>
        </register>
        <register>
          <name>FRCRB</name>
          <addressOffset>0x2c</addressOffset>
          <size>0x20</size>
          <fields>
            <field>
              <name>FRL</name>
              <bitOffset>0</bitOffset>
              <bitWidth>8</bitWidth>
            </field>
            <field>
              <name>FSALL</name>
              <bitOffset>8</bitOffset>
              <bitWidth>7</bitWidth>
            </field>
            <field>
              <name>FSDEF</name>
              <bitOffset>16</bitOffset>
              <bitWidth>1</bitWidth>
            </field>
            <field>
              <name>FSPOL</name>
              <bitOffset>17</bitOffset>
              <bitWidth>1</bitWidth>
            </field>
            <field>
              <name>FSOFF</name>
              <bitOffset>18</bitOffset>
              <bitWidth>1</bitWidth>
            </field>
          </fields>
        </register>
        <register>
          <name>FRCRB</name>
          <addressOffset>0x2c</addressOffset>
          <size>0x20</size>
          <fields>
            <field>
              <name>FRL</name>
              <bitOffset>0</bitOffset>
              <bitWidth>8</bitWidth>
            </field>
            <field>
              <name>FSALL</name>
              <bitOffset>8</bitOffset>
              <bitWidth>7</bitWidth>
            </field>
            <field>
              <name>FSDEF</name>
              <bitOffset>16</bitOffset>
              <bitWidth>1</bitWidth>
            </field>
            <field>
              <name>FSPOL</name>
              <bitOffset>17</bitOffset>
              <bitWidth>1</bitWidth>
            </field>
            <field>
              <name>FSOFF</name>
              <bitOffset>18</bitOffset>
              <bitWidth>1</bitWidth>
            </field>
          </fields>
        </register>
        <register>
          <name>SLOTRB</name>
          <addressOffset>0x30</addressOffset>
          <size>0x20</size>
          <fields>
            <field>
              <name>FBOFF</name>
              <bitOffset>0</bitOffset>
              <bitWidth>5</bitWidth>
            </field>
            <field>
              <name>SLOTSZ</name>
              <bitOffset>6</bitOffset>
              <bitWidth>2</bitWidth>
            </field>
            <field>
              <name>NBSLOT</name>
              <bitOffset>8</bitOffset>
              <bitWidth>4</bitWidth>
            </field>
            <field>
              <name>SLOTEN</name>
              <bitOffset>16</bitOffset>
              <bitWidth>16</bitWidth>
            </field>
          </fields>
        </register>
        <register>
          <name>SLOTRB</name>
          <addressOffset>0x30</addressOffset>
          <size>0x20</size>
          <fields>
            <field>
              <name>FBOFF</name>
              <bitOffset>0</bitOffset>
              <bitWidth>5</bitWidth>
            </field>
            <field>
              <name>SLOTSZ</name>
              <bitOffset>6</bitOffset>
              <bitWidth>2</bitWidth>
            </field>
            <field>
              <name>NBSLOT</name>
              <bitOffset>8</bitOffset>
              <bitWidth>4</bitWidth>
            </field>
            <field>
              <name>SLOTEN</name>
              <bitOffset>16</bitOffset>
              <bitWidth>16</bitWidth>
            </field>
          </fields>
        </register>
        <register>
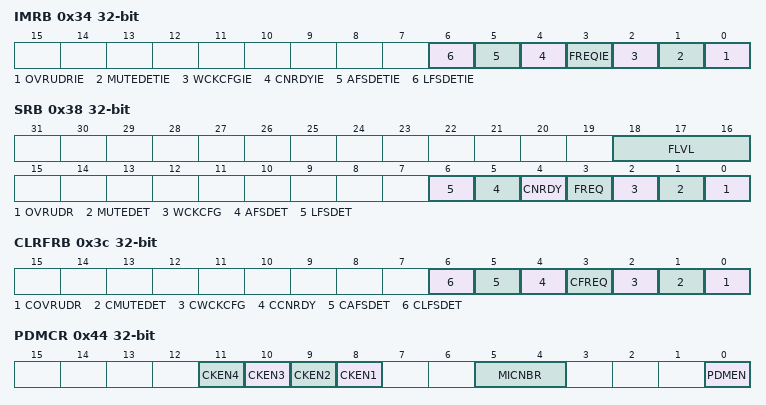
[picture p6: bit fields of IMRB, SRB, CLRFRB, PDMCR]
          <name>IMRB</name>
          <addressOffset>0x34</addressOffset>
          <size>0x20</size>
          <fields>
            <field>
              <name>OVRUDRIE</name>
              <bitOffset>0</bitOffset>
              <bitWidth>1</bitWidth>
            </field>
            <field>
              <name>MUTEDETIE</name>
              <bitOffset>1</bitOffset>
              <bitWidth>1</bitWidth>
            </field>
            <field>
              <name>WCKCFGIE</name>
              <bitOffset>2</bitOffset>
              <bitWidth>1</bitWidth>
            </field>
            <field>
              <name>FREQIE</name>
              <bitOffset>3</bitOffset>
              <bitWidth>1</bitWidth>
            </field>
            <field>
              <name>CNRDYIE</name>
              <bitOffset>4</bitOffset>
              <bitWidth>1</bitWidth>
            </field>
            <field>
              <name>AFSDETIE</name>
              <bitOffset>5</bitOffset>
              <bitWidth>1</bitWidth>
            </field>
            <field>
              <name>LFSDETIE</name>
              <bitOffset>6</bitOffset>
              <bitWidth>1</bitWidth>
            </field>
          </fields>
        </register>
        <register>
          <name>IMRB</name>
          <addressOffset>0x34</addressOffset>
          <size>0x20</size>
          <fields>
            <field>
              <name>OVRUDRIE</name>
              <bitOffset>0</bitOffset>
              <bitWidth>1</bitWidth>
            </field>
            <field>
              <name>MUTEDETIE</name>
              <bitOffset>1</bitOffset>
              <bitWidth>1</bitWidth>
            </field>
            <field>
              <name>WCKCFGIE</name>
              <bitOffset>2</bitOffset>
              <bitWidth>1</bitWidth>
            </field>
            <field>
              <name>FREQIE</name>
              <bitOffset>3</bitOffset>
              <bitWidth>1</bitWidth>
            </field>
            <field>
              <name>CNRDYIE</name>
              <bitOffset>4</bitOffset>
              <bitWidth>1</bitWidth>
            </field>
            <field>
              <name>AFSDETIE</name>
              <bitOffset>5</bitOffset>
              <bitWidth>1</bitWidth>
            </field>
            <field>
              <name>LFSDETIE</name>
              <bitOffset>6</bitOffset>
              <bitWidth>1</bitWidth>
            </field>
          </fields>
        </register>
        <register>
          <name>SRB</name>
          <addressOffset>0x38</addressOffset>
          <size>0x20</size>
          <fields>
            <field>
              <name>OVRUDR</name>
              <bitOffset>0</bitOffset>
              <bitWidth>1</bitWidth>
            </field>
            <field>
              <name>MUTEDET</name>
              <bitOffset>1</bitOffset>
              <bitWidth>1</bitWidth>
            </field>
            <field>
              <name>WCKCFG</name>
              <bitOffset>2</bitOffset>
              <bitWidth>1</bitWidth>
            </field>
            <field>
              <name>FREQ</name>
              <bitOffset>3</bitOffset>
              <bitWidth>1</bitWidth>
            </field>
            <field>
              <name>CNRDY</name>
              <bitOffset>4</bitOffset>
              <bitWidth>1</bitWidth>
            </field>
            <field>
              <name>AFSDET</name>
              <bitOffset>5</bitOffset>
              <bitWidth>1</bitWidth>
            </field>
            <field>
              <name>LFSDET</name>
              <bitOffset>6</bitOffset>
              <bitWidth>1</bitWidth>
            </field>
            <field>
              <name>FLVL</name>
              <bitOffset>16</bitOffset>
              <bitWidth>3</bitWidth>
            </field>
          </fields>
        </register>
        <register>
          <name>SRB</name>
          <addressOffset>0x38</addressOffset>
          <size>0x20</size>
          <fields>
            <field>
              <name>OVRUDR</name>
              <bitOffset>0</bitOffset>
              <bitWidth>1</bitWidth>
            </field>
            <field>
              <name>MUTEDET</name>
              <bitOffset>1</bitOffset>
              <bitWidth>1</bitWidth>
            </field>
            <field>
              <name>WCKCFG</name>
              <bitOffset>2</bitOffset>
              <bitWidth>1</bitWidth>
            </field>
            <field>
              <name>FREQ</name>
              <bitOffset>3</bitOffset>
              <bitWidth>1</bitWidth>
            </field>
            <field>
              <name>CNRDY</name>
              <bitOffset>4</bitOffset>
              <bitWidth>1</bitWidth>
            </field>
            <field>
              <name>AFSDET</name>
              <bitOffset>5</bitOffset>
              <bitWidth>1</bitWidth>
            </field>
            <field>
              <name>LFSDET</name>
              <bitOffset>6</bitOffset>
              <bitWidth>1</bitWidth>
            </field>
            <field>
              <name>FLVL</name>
              <bitOffset>16</bitOffset>
              <bitWidth>3</bitWidth>
            </field>
          </fields>
        </register>
        <register>
          <name>CLRFRB</name>
          <addressOffset>0x3c</addressOffset>
          <size>0x20</size>
          <fields>
            <field>
              <name>COVRUDR</name>
              <bitOffset>0</bitOffset>
              <bitWidth>1</bitWidth>
            </field>
            <field>
              <name>CMUTEDET</name>
              <bitOffset>1</bitOffset>
              <bitWidth>1</bitWidth>
            </field>
            <field>
              <name>CWCKCFG</name>
              <bitOffset>2</bitOffset>
              <bitWidth>1</bitWidth>
            </field>
            <field>
              <name>CFREQ</name>
              <bitOffset>3</bitOffset>
              <bitWidth>1</bitWidth>
            </field>
            <field>
              <name>CCNRDY</name>
              <bitOffset>4</bitOffset>
              <bitWidth>1</bitWidth>
            </field>
            <field>
              <name>CAFSDET</name>
              <bitOffset>5</bitOffset>
              <bitWidth>1</bitWidth>
            </field>
            <field>
              <name>CLFSDET</name>
              <bitOffset>6</bitOffset>
              <bitWidth>1</bitWidth>
            </field>
          </fields>
        </register>
        <register>
          <name>CLRFRB</name>
          <addressOffset>0x3c</addressOffset>
          <size>0x20</size>
          <fields>
            <field>
              <name>COVRUDR</name>
              <bitOffset>0</bitOffset>
              <bitWidth>1</bitWidth>
            </field>
            <field>
              <name>CMUTEDET</name>
              <bitOffset>1</bitOffset>
              <bitWidth>1</bitWidth>
            </field>
            <field>
              <name>CWCKCFG</name>
              <bitOffset>2</bitOffset>
              <bitWidth>1</bitWidth>
            </field>
            <field>
              <name>CFREQ</name>
              <bitOffset>3</bitOffset>
              <bitWidth>1</bitWidth>
            </field>
            <field>
              <name>CCNRDY</name>
              <bitOffset>4</bitOffset>
              <bitWidth>1</bitWidth>
            </field>
            <field>
              <name>CAFSDET</name>
              <bitOffset>5</bitOffset>
              <bitWidth>1</bitWidth>
            </field>
            <field>
              <name>CLFSDET</name>
              <bitOffset>6</bitOffset>
              <bitWidth>1</bitWidth>
            </field>
          </fields>
        </register>
        <register>
          <name>DRB</name>
          <addressOffset>0x40</addressOffset>
          <size>0x20</size>
          <fields>
            <field>
              <name>DATA</name>
              <bitOffset>0</bitOffset>
              <bitWidth>32</bitWidth>
            </field>
          </fields>
        </register>
        <register>
          <name>DRB</name>
          <addressOffset>0x40</addressOffset>
          <size>0x20</size>
          <fields>
            <field>
              <name>DATA</name>
              <bitOffset>0</bitOffset>
              <bitWidth>32</bitWidth>
            </field>
          </fields>
        </register>
        <register>
          <name>PDMCR</name>
          <addressOffset>0x44</addressOffset>
          <size>0x20</size>
          <fields>
            <field>
              <name>PDMEN</name>
              <bitOffset>0</bitOffset>
              <bitWidth>1</bitWidth>
            </field>
            <field>
              <name>MICNBR</name>
              <bitOffset>4</bitOffset>
              <bitWidth>2</bitWidth>
            </field>
            <field>
              <name>CKEN1</name>
              <bitOffset>8</bitOffset>
              <bitWidth>1</bitWidth>
            </field>
            <field>
              <name>CKEN2</name>
              <bitOffset>9</bitOffset>
              <bitWidth>1</bitWidth>
            </field>
            <field>
              <name>CKEN3</name>
              <bitOffset>10</bitOffset>
              <bitWidth>1</bitWidth>
            </field>
            <field>
              <name>CKEN4</name>
              <bitOffset>11</bitOffset>
              <bitWidth>1</bitWidth>
            </field>
          </fields>
        </register>
        <register>
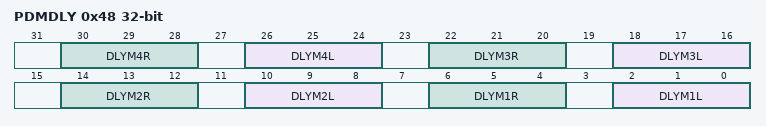
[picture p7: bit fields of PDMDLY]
          <name>PDMDLY</name>
          <addressOffset>0x48</addressOffset>
          <size>0x20</size>
          <fields>
            <field>
              <name>DLYM1L</name>
              <bitOffset>0</bitOffset>
              <bitWidth>3</bitWidth>
            </field>
            <field>
              <name>DLYM1R</name>
              <bitOffset>4</bitOffset>
              <bitWidth>3</bitWidth>
            </field>
            <field>
              <name>DLYM2L</name>
              <bitOffset>8</bitOffset>
              <bitWidth>3</bitWidth>
            </field>
            <field>
              <name>DLYM2R</name>
              <bitOffset>12</bitOffset>
              <bitWidth>3</bitWidth>
            </field>
            <field>
              <name>DLYM3L</name>
              <bitOffset>16</bitOffset>
              <bitWidth>3</bitWidth>
            </field>
            <field>
              <name>DLYM3R</name>
              <bitOffset>20</bitOffset>
              <bitWidth>3</bitWidth>
            </field>
            <field>
              <name>DLYM4L</name>
              <bitOffset>24</bitOffset>
              <bitWidth>3</bitWidth>
            </field>
            <field>
              <name>DLYM4R</name>
              <bitOffset>28</bitOffset>
              <bitWidth>3</bitWidth>
            </field>
          </fields>
        </register>
      </registers>
    </peripheral>
    <peripheral>
      <name>DFSDM1</name>
      <baseAddress>0x40017800</baseAddress>
      <registers>
        <register>
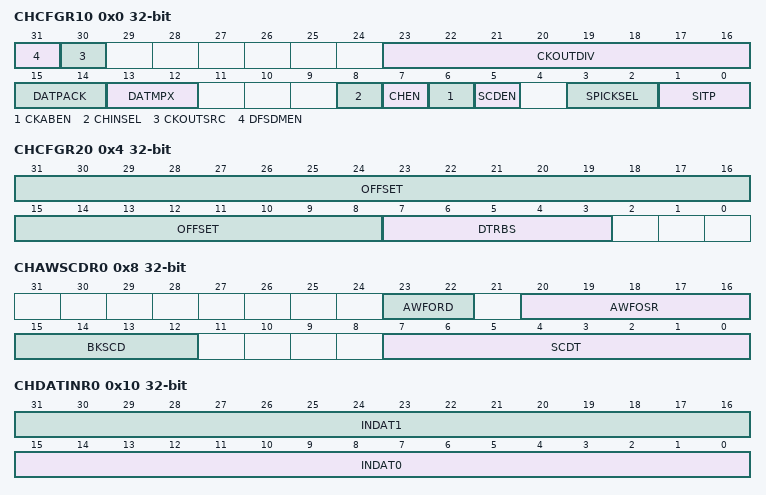
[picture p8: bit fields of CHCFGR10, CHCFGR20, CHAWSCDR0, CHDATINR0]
          <name>CHCFGR10</name>
          <addressOffset>0x0</addressOffset>
          <size>0x20</size>
          <fields>
            <field>
              <name>SITP</name>
              <bitOffset>0</bitOffset>
              <bitWidth>2</bitWidth>
            </field>
            <field>
              <name>SPICKSEL</name>
              <bitOffset>2</bitOffset>
              <bitWidth>2</bitWidth>
            </field>
            <field>
              <name>SCDEN</name>
              <bitOffset>5</bitOffset>
              <bitWidth>1</bitWidth>
            </field>
            <field>
              <name>CKABEN</name>
              <bitOffset>6</bitOffset>
              <bitWidth>1</bitWidth>
            </field>
            <field>
              <name>CHEN</name>
              <bitOffset>7</bitOffset>
              <bitWidth>1</bitWidth>
            </field>
            <field>
              <name>CHINSEL</name>
              <bitOffset>8</bitOffset>
              <bitWidth>1</bitWidth>
            </field>
            <field>
              <name>DATMPX</name>
              <bitOffset>12</bitOffset>
              <bitWidth>2</bitWidth>
            </field>
            <field>
              <name>DATPACK</name>
              <bitOffset>14</bitOffset>
              <bitWidth>2</bitWidth>
            </field>
            <field>
              <name>CKOUTDIV</name>
              <bitOffset>16</bitOffset>
              <bitWidth>8</bitWidth>
            </field>
            <field>
              <name>CKOUTSRC</name>
              <bitOffset>30</bitOffset>
              <bitWidth>1</bitWidth>
            </field>
            <field>
              <name>DFSDMEN</name>
              <bitOffset>31</bitOffset>
              <bitWidth>1</bitWidth>
            </field>
          </fields>
        </register>
        <register>
          <name>CHCFGR20</name>
          <addressOffset>0x4</addressOffset>
          <size>0x20</size>
          <fields>
            <field>
              <name>DTRBS</name>
              <bitOffset>3</bitOffset>
              <bitWidth>5</bitWidth>
            </field>
            <field>
              <name>OFFSET</name>
              <bitOffset>8</bitOffset>
              <bitWidth>24</bitWidth>
            </field>
          </fields>
        </register>
        <register>
          <name>CHAWSCDR0</name>
          <addressOffset>0x8</addressOffset>
          <size>0x20</size>
          <fields>
            <field>
              <name>SCDT</name>
              <bitOffset>0</bitOffset>
              <bitWidth>8</bitWidth>
            </field>
            <field>
              <name>BKSCD</name>
              <bitOffset>12</bitOffset>
              <bitWidth>4</bitWidth>
            </field>
            <field>
              <name>AWFOSR</name>
              <bitOffset>16</bitOffset>
              <bitWidth>5</bitWidth>
            </field>
            <field>
              <name>AWFORD</name>
              <bitOffset>22</bitOffset>
              <bitWidth>2</bitWidth>
            </field>
          </fields>
        </register>
        <register>
          <name>CHWDATAR0</name>
          <addressOffset>0xc</addressOffset>
          <size>0x20</size>
        </register>
        <register>
          <name>CHDATINR0</name>
          <addressOffset>0x10</addressOffset>
          <size>0x20</size>
          <fields>
            <field>
              <name>INDAT0</name>
              <bitOffset>0</bitOffset>
              <bitWidth>16</bitWidth>
            </field>
            <field>
              <name>INDAT1</name>
              <bitOffset>16</bitOffset>
              <bitWidth>16</bitWidth>
            </field>
          </fields>
        </register>
        <register>
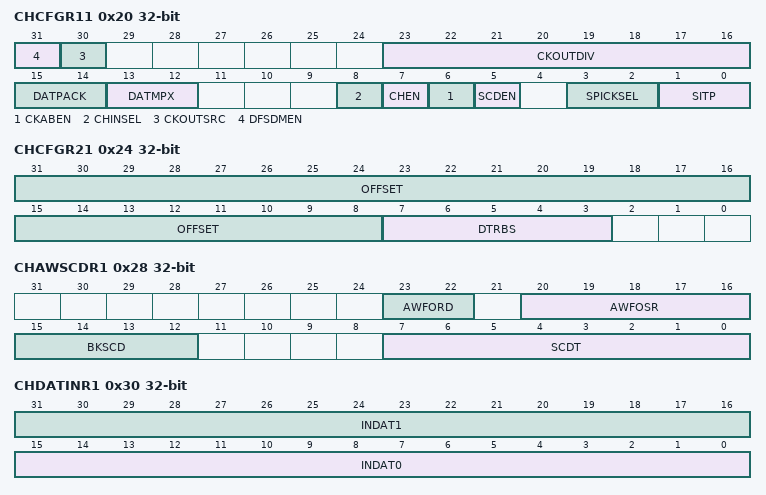
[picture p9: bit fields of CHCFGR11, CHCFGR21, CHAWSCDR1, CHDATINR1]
          <name>CHCFGR11</name>
          <addressOffset>0x20</addressOffset>
          <size>0x20</size>
          <fields>
            <field>
              <name>SITP</name>
              <bitOffset>0</bitOffset>
              <bitWidth>2</bitWidth>
            </field>
            <field>
              <name>SPICKSEL</name>
              <bitOffset>2</bitOffset>
              <bitWidth>2</bitWidth>
            </field>
            <field>
              <name>SCDEN</name>
              <bitOffset>5</bitOffset>
              <bitWidth>1</bitWidth>
            </field>
            <field>
              <name>CKABEN</name>
              <bitOffset>6</bitOffset>
              <bitWidth>1</bitWidth>
            </field>
            <field>
              <name>CHEN</name>
              <bitOffset>7</bitOffset>
              <bitWidth>1</bitWidth>
            </field>
            <field>
              <name>CHINSEL</name>
              <bitOffset>8</bitOffset>
              <bitWidth>1</bitWidth>
            </field>
            <field>
              <name>DATMPX</name>
              <bitOffset>12</bitOffset>
              <bitWidth>2</bitWidth>
            </field>
            <field>
              <name>DATPACK</name>
              <bitOffset>14</bitOffset>
              <bitWidth>2</bitWidth>
            </field>
            <field>
              <name>CKOUTDIV</name>
              <bitOffset>16</bitOffset>
              <bitWidth>8</bitWidth>
            </field>
            <field>
              <name>CKOUTSRC</name>
              <bitOffset>30</bitOffset>
              <bitWidth>1</bitWidth>
            </field>
            <field>
              <name>DFSDMEN</name>
              <bitOffset>31</bitOffset>
              <bitWidth>1</bitWidth>
            </field>
          </fields>
        </register>
        <register>
          <name>CHCFGR21</name>
          <addressOffset>0x24</addressOffset>
          <size>0x20</size>
          <fields>
            <field>
              <name>DTRBS</name>
              <bitOffset>3</bitOffset>
              <bitWidth>5</bitWidth>
            </field>
            <field>
              <name>OFFSET</name>
              <bitOffset>8</bitOffset>
              <bitWidth>24</bitWidth>
            </field>
          </fields>
        </register>
        <register>
          <name>CHAWSCDR1</name>
          <addressOffset>0x28</addressOffset>
          <size>0x20</size>
          <fields>
            <field>
              <name>SCDT</name>
              <bitOffset>0</bitOffset>
              <bitWidth>8</bitWidth>
            </field>
            <field>
              <name>BKSCD</name>
              <bitOffset>12</bitOffset>
              <bitWidth>4</bitWidth>
            </field>
            <field>
              <name>AWFOSR</name>
              <bitOffset>16</bitOffset>
              <bitWidth>5</bitWidth>
            </field>
            <field>
              <name>AWFORD</name>
              <bitOffset>22</bitOffset>
              <bitWidth>2</bitWidth>
            </field>
          </fields>
        </register>
        <register>
          <name>CHWDATAR1</name>
          <addressOffset>0x2c</addressOffset>
          <size>0x20</size>
        </register>
        <register>
          <name>CHDATINR1</name>
          <addressOffset>0x30</addressOffset>
          <size>0x20</size>
          <fields>
            <field>
              <name>INDAT0</name>
              <bitOffset>0</bitOffset>
              <bitWidth>16</bitWidth>
            </field>
            <field>
              <name>INDAT1</name>
              <bitOffset>16</bitOffset>
              <bitWidth>16</bitWidth>
            </field>
          </fields>
        </register>
        <register>
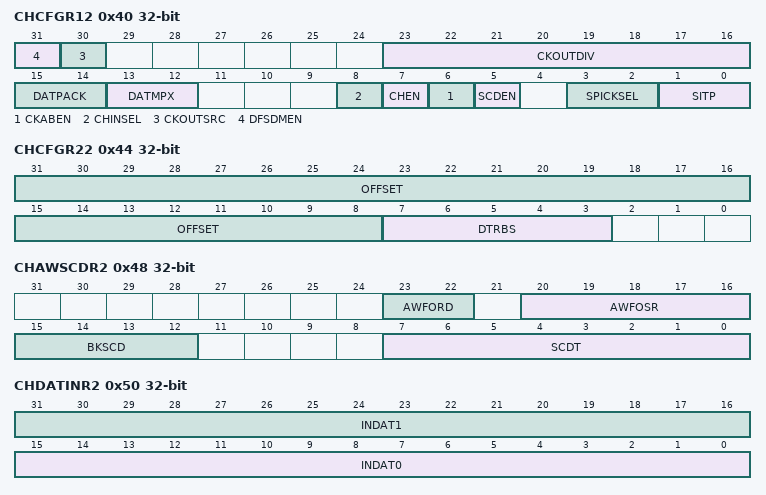
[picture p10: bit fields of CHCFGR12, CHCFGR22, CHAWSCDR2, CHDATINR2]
          <name>CHCFGR12</name>
          <addressOffset>0x40</addressOffset>
          <size>0x20</size>
          <fields>
            <field>
              <name>SITP</name>
              <bitOffset>0</bitOffset>
              <bitWidth>2</bitWidth>
            </field>
            <field>
              <name>SPICKSEL</name>
              <bitOffset>2</bitOffset>
              <bitWidth>2</bitWidth>
            </field>
            <field>
              <name>SCDEN</name>
              <bitOffset>5</bitOffset>
              <bitWidth>1</bitWidth>
            </field>
            <field>
              <name>CKABEN</name>
              <bitOffset>6</bitOffset>
              <bitWidth>1</bitWidth>
            </field>
            <field>
              <name>CHEN</name>
              <bitOffset>7</bitOffset>
              <bitWidth>1</bitWidth>
            </field>
            <field>
              <name>CHINSEL</name>
              <bitOffset>8</bitOffset>
              <bitWidth>1</bitWidth>
            </field>
            <field>
              <name>DATMPX</name>
              <bitOffset>12</bitOffset>
              <bitWidth>2</bitWidth>
            </field>
            <field>
              <name>DATPACK</name>
              <bitOffset>14</bitOffset>
              <bitWidth>2</bitWidth>
            </field>
            <field>
              <name>CKOUTDIV</name>
              <bitOffset>16</bitOffset>
              <bitWidth>8</bitWidth>
            </field>
            <field>
              <name>CKOUTSRC</name>
              <bitOffset>30</bitOffset>
              <bitWidth>1</bitWidth>
            </field>
            <field>
              <name>DFSDMEN</name>
              <bitOffset>31</bitOffset>
              <bitWidth>1</bitWidth>
            </field>
          </fields>
        </register>
        <register>
          <name>CHCFGR22</name>
          <addressOffset>0x44</addressOffset>
          <size>0x20</size>
          <fields>
            <field>
              <name>DTRBS</name>
              <bitOffset>3</bitOffset>
              <bitWidth>5</bitWidth>
            </field>
            <field>
              <name>OFFSET</name>
              <bitOffset>8</bitOffset>
              <bitWidth>24</bitWidth>
            </field>
          </fields>
        </register>
        <register>
          <name>CHAWSCDR2</name>
          <addressOffset>0x48</addressOffset>
          <size>0x20</size>
          <fields>
            <field>
              <name>SCDT</name>
              <bitOffset>0</bitOffset>
              <bitWidth>8</bitWidth>
            </field>
            <field>
              <name>BKSCD</name>
              <bitOffset>12</bitOffset>
              <bitWidth>4</bitWidth>
            </field>
            <field>
              <name>AWFOSR</name>
              <bitOffset>16</bitOffset>
              <bitWidth>5</bitWidth>
            </field>
            <field>
              <name>AWFORD</name>
              <bitOffset>22</bitOffset>
              <bitWidth>2</bitWidth>
            </field>
          </fields>
        </register>
        <register>
          <name>CHWDATAR2</name>
          <addressOffset>0x4c</addressOffset>
          <size>0x20</size>
        </register>
        <register>
          <name>CHDATINR2</name>
          <addressOffset>0x50</addressOffset>
          <size>0x20</size>
          <fields>
            <field>
              <name>INDAT0</name>
              <bitOffset>0</bitOffset>
              <bitWidth>16</bitWidth>
            </field>
            <field>
              <name>INDAT1</name>
              <bitOffset>16</bitOffset>
              <bitWidth>16</bitWidth>
            </field>
          </fields>
        </register>
        <register>
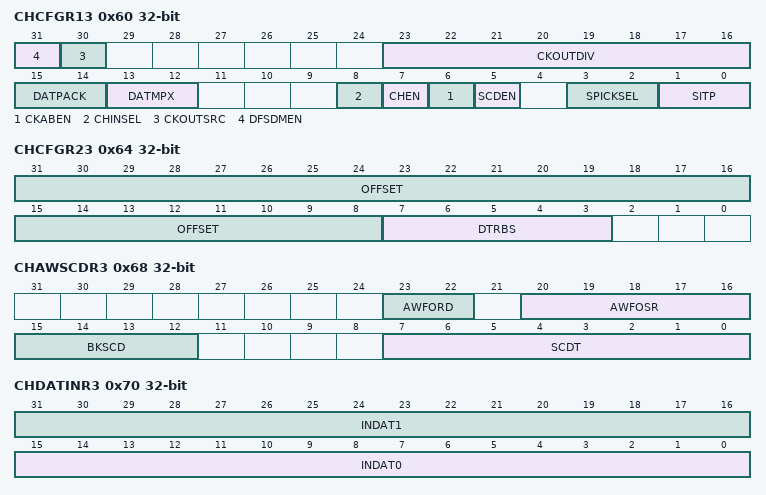
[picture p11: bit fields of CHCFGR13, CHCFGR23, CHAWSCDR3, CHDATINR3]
          <name>CHCFGR13</name>
          <addressOffset>0x60</addressOffset>
          <size>0x20</size>
          <fields>
            <field>
              <name>SITP</name>
              <bitOffset>0</bitOffset>
              <bitWidth>2</bitWidth>
            </field>
            <field>
              <name>SPICKSEL</name>
              <bitOffset>2</bitOffset>
              <bitWidth>2</bitWidth>
            </field>
            <field>
              <name>SCDEN</name>
              <bitOffset>5</bitOffset>
              <bitWidth>1</bitWidth>
            </field>
            <field>
              <name>CKABEN</name>
              <bitOffset>6</bitOffset>
              <bitWidth>1</bitWidth>
            </field>
            <field>
              <name>CHEN</name>
              <bitOffset>7</bitOffset>
              <bitWidth>1</bitWidth>
            </field>
            <field>
              <name>CHINSEL</name>
              <bitOffset>8</bitOffset>
              <bitWidth>1</bitWidth>
            </field>
            <field>
              <name>DATMPX</name>
              <bitOffset>12</bitOffset>
              <bitWidth>2</bitWidth>
            </field>
            <field>
              <name>DATPACK</name>
              <bitOffset>14</bitOffset>
              <bitWidth>2</bitWidth>
            </field>
            <field>
              <name>CKOUTDIV</name>
              <bitOffset>16</bitOffset>
              <bitWidth>8</bitWidth>
            </field>
            <field>
              <name>CKOUTSRC</name>
              <bitOffset>30</bitOffset>
              <bitWidth>1</bitWidth>
            </field>
            <field>
              <name>DFSDMEN</name>
              <bitOffset>31</bitOffset>
              <bitWidth>1</bitWidth>
            </field>
          </fields>
        </register>
        <register>
          <name>CHCFGR23</name>
          <addressOffset>0x64</addressOffset>
          <size>0x20</size>
          <fields>
            <field>
              <name>DTRBS</name>
              <bitOffset>3</bitOffset>
              <bitWidth>5</bitWidth>
            </field>
            <field>
              <name>OFFSET</name>
              <bitOffset>8</bitOffset>
              <bitWidth>24</bitWidth>
            </field>
          </fields>
        </register>
        <register>
          <name>CHAWSCDR3</name>
          <addressOffset>0x68</addressOffset>
          <size>0x20</size>
          <fields>
            <field>
              <name>SCDT</name>
              <bitOffset>0</bitOffset>
              <bitWidth>8</bitWidth>
            </field>
            <field>
              <name>BKSCD</name>
              <bitOffset>12</bitOffset>
              <bitWidth>4</bitWidth>
            </field>
            <field>
              <name>AWFOSR</name>
              <bitOffset>16</bitOffset>
              <bitWidth>5</bitWidth>
            </field>
            <field>
              <name>AWFORD</name>
              <bitOffset>22</bitOffset>
              <bitWidth>2</bitWidth>
            </field>
          </fields>
        </register>
        <register>
          <name>CHWDATAR3</name>
          <addressOffset>0x6c</addressOffset>
          <size>0x20</size>
        </register>
        <register>
          <name>CHDATINR3</name>
          <addressOffset>0x70</addressOffset>
          <size>0x20</size>
          <fields>
            <field>
              <name>INDAT0</name>
              <bitOffset>0</bitOffset>
              <bitWidth>16</bitWidth>
            </field>
            <field>
              <name>INDAT1</name>
              <bitOffset>16</bitOffset>
              <bitWidth>16</bitWidth>
            </field>
          </fields>
        </register>
        <register>
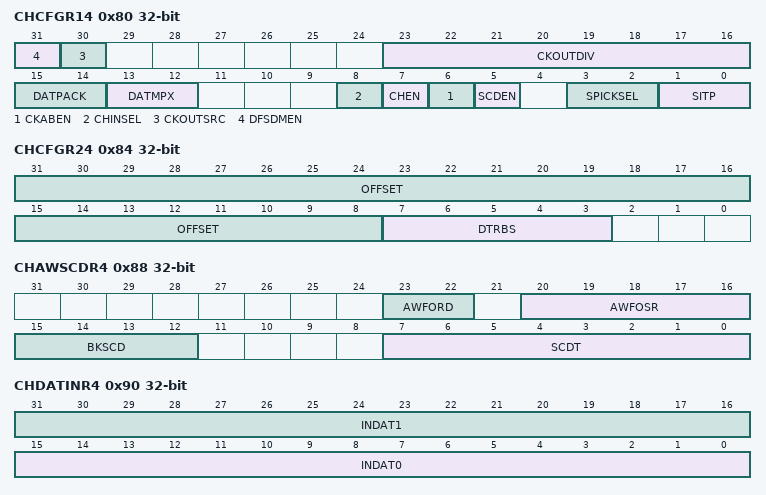
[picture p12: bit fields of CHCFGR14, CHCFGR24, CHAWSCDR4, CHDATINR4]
          <name>CHCFGR14</name>
          <addressOffset>0x80</addressOffset>
          <size>0x20</size>
          <fields>
            <field>
              <name>SITP</name>
              <bitOffset>0</bitOffset>
              <bitWidth>2</bitWidth>
            </field>
            <field>
              <name>SPICKSEL</name>
              <bitOffset>2</bitOffset>
              <bitWidth>2</bitWidth>
            </field>
            <field>
              <name>SCDEN</name>
              <bitOffset>5</bitOffset>
              <bitWidth>1</bitWidth>
            </field>
            <field>
              <name>CKABEN</name>
              <bitOffset>6</bitOffset>
              <bitWidth>1</bitWidth>
            </field>
            <field>
              <name>CHEN</name>
              <bitOffset>7</bitOffset>
              <bitWidth>1</bitWidth>
            </field>
            <field>
              <name>CHINSEL</name>
              <bitOffset>8</bitOffset>
              <bitWidth>1</bitWidth>
            </field>
            <field>
              <name>DATMPX</name>
              <bitOffset>12</bitOffset>
              <bitWidth>2</bitWidth>
            </field>
            <field>
              <name>DATPACK</name>
              <bitOffset>14</bitOffset>
              <bitWidth>2</bitWidth>
            </field>
            <field>
              <name>CKOUTDIV</name>
              <bitOffset>16</bitOffset>
              <bitWidth>8</bitWidth>
            </field>
            <field>
              <name>CKOUTSRC</name>
              <bitOffset>30</bitOffset>
              <bitWidth>1</bitWidth>
            </field>
            <field>
              <name>DFSDMEN</name>
              <bitOffset>31</bitOffset>
              <bitWidth>1</bitWidth>
            </field>
          </fields>
        </register>
        <register>
          <name>CHCFGR24</name>
          <addressOffset>0x84</addressOffset>
          <size>0x20</size>
          <fields>
            <field>
              <name>DTRBS</name>
              <bitOffset>3</bitOffset>
              <bitWidth>5</bitWidth>
            </field>
            <field>
              <name>OFFSET</name>
              <bitOffset>8</bitOffset>
              <bitWidth>24</bitWidth>
            </field>
          </fields>
        </register>
        <register>
          <name>CHAWSCDR4</name>
          <addressOffset>0x88</addressOffset>
          <size>0x20</size>
          <fields>
            <field>
              <name>SCDT</name>
              <bitOffset>0</bitOffset>
              <bitWidth>8</bitWidth>
            </field>
            <field>
              <name>BKSCD</name>
              <bitOffset>12</bitOffset>
              <bitWidth>4</bitWidth>
            </field>
            <field>
              <name>AWFOSR</name>
              <bitOffset>16</bitOffset>
              <bitWidth>5</bitWidth>
            </field>
            <field>
              <name>AWFORD</name>
              <bitOffset>22</bitOffset>
              <bitWidth>2</bitWidth>
            </field>
          </fields>
        </register>
        <register>
          <name>CHWDATAR4</name>
          <addressOffset>0x8c</addressOffset>
          <size>0x20</size>
        </register>
        <register>
          <name>CHDATINR4</name>
          <addressOffset>0x90</addressOffset>
          <size>0x20</size>
          <fields>
            <field>
              <name>INDAT0</name>
              <bitOffset>0</bitOffset>
              <bitWidth>16</bitWidth>
            </field>
            <field>
              <name>INDAT1</name>
              <bitOffset>16</bitOffset>
              <bitWidth>16</bitWidth>
            </field>
          </fields>
        </register>
        <register>
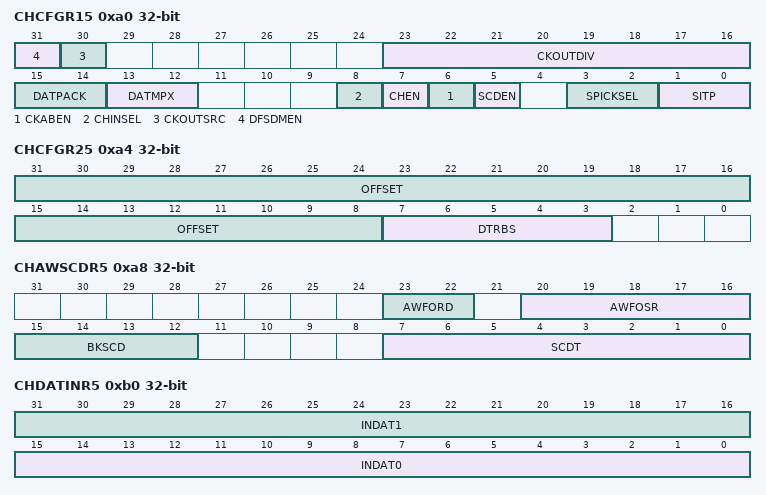
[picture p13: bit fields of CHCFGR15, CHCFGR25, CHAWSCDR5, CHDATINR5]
          <name>CHCFGR15</name>
          <addressOffset>0xa0</addressOffset>
          <size>0x20</size>
          <fields>
            <field>
              <name>SITP</name>
              <bitOffset>0</bitOffset>
              <bitWidth>2</bitWidth>
            </field>
            <field>
              <name>SPICKSEL</name>
              <bitOffset>2</bitOffset>
              <bitWidth>2</bitWidth>
            </field>
            <field>
              <name>SCDEN</name>
              <bitOffset>5</bitOffset>
              <bitWidth>1</bitWidth>
            </field>
            <field>
              <name>CKABEN</name>
              <bitOffset>6</bitOffset>
              <bitWidth>1</bitWidth>
            </field>
            <field>
              <name>CHEN</name>
              <bitOffset>7</bitOffset>
              <bitWidth>1</bitWidth>
            </field>
            <field>
              <name>CHINSEL</name>
              <bitOffset>8</bitOffset>
              <bitWidth>1</bitWidth>
            </field>
            <field>
              <name>DATMPX</name>
              <bitOffset>12</bitOffset>
              <bitWidth>2</bitWidth>
            </field>
            <field>
              <name>DATPACK</name>
              <bitOffset>14</bitOffset>
              <bitWidth>2</bitWidth>
            </field>
            <field>
              <name>CKOUTDIV</name>
              <bitOffset>16</bitOffset>
              <bitWidth>8</bitWidth>
            </field>
            <field>
              <name>CKOUTSRC</name>
              <bitOffset>30</bitOffset>
              <bitWidth>1</bitWidth>
            </field>
            <field>
              <name>DFSDMEN</name>
              <bitOffset>31</bitOffset>
              <bitWidth>1</bitWidth>
            </field>
          </fields>
        </register>
        <register>
          <name>CHCFGR25</name>
          <addressOffset>0xa4</addressOffset>
          <size>0x20</size>
          <fields>
            <field>
              <name>DTRBS</name>
              <bitOffset>3</bitOffset>
              <bitWidth>5</bitWidth>
            </field>
            <field>
              <name>OFFSET</name>
              <bitOffset>8</bitOffset>
              <bitWidth>24</bitWidth>
            </field>
          </fields>
        </register>
        <register>
          <name>CHAWSCDR5</name>
          <addressOffset>0xa8</addressOffset>
          <size>0x20</size>
          <fields>
            <field>
              <name>SCDT</name>
              <bitOffset>0</bitOffset>
              <bitWidth>8</bitWidth>
            </field>
            <field>
              <name>BKSCD</name>
              <bitOffset>12</bitOffset>
              <bitWidth>4</bitWidth>
            </field>
            <field>
              <name>AWFOSR</name>
              <bitOffset>16</bitOffset>
              <bitWidth>5</bitWidth>
            </field>
            <field>
              <name>AWFORD</name>
              <bitOffset>22</bitOffset>
              <bitWidth>2</bitWidth>
            </field>
          </fields>
        </register>
        <register>
          <name>CHWDATAR5</name>
          <addressOffset>0xac</addressOffset>
          <size>0x20</size>
        </register>
        <register>
          <name>CHDATINR5</name>
          <addressOffset>0xb0</addressOffset>
          <size>0x20</size>
          <fields>
            <field>
              <name>INDAT0</name>
              <bitOffset>0</bitOffset>
              <bitWidth>16</bitWidth>
            </field>
            <field>
              <name>INDAT1</name>
              <bitOffset>16</bitOffset>
              <bitWidth>16</bitWidth>
            </field>
          </fields>
        </register>
        <register>
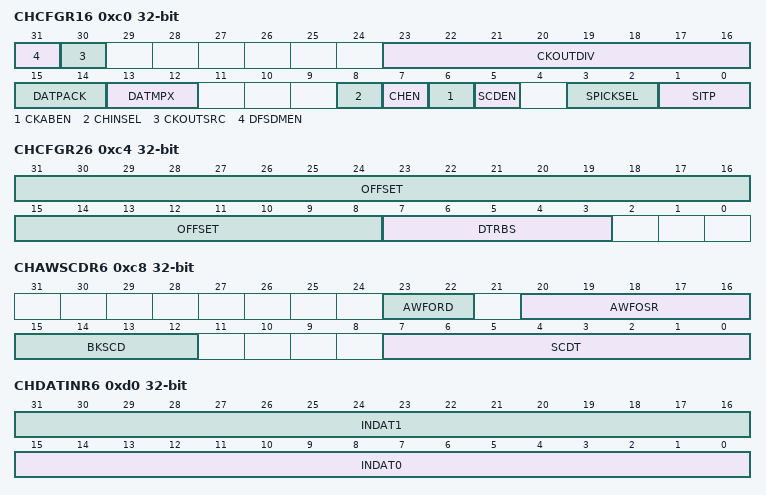
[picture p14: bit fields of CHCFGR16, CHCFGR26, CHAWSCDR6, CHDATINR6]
          <name>CHCFGR16</name>
          <addressOffset>0xc0</addressOffset>
          <size>0x20</size>
          <fields>
            <field>
              <name>SITP</name>
              <bitOffset>0</bitOffset>
              <bitWidth>2</bitWidth>
            </field>
            <field>
              <name>SPICKSEL</name>
              <bitOffset>2</bitOffset>
              <bitWidth>2</bitWidth>
            </field>
            <field>
              <name>SCDEN</name>
              <bitOffset>5</bitOffset>
              <bitWidth>1</bitWidth>
            </field>
            <field>
              <name>CKABEN</name>
              <bitOffset>6</bitOffset>
              <bitWidth>1</bitWidth>
            </field>
            <field>
              <name>CHEN</name>
              <bitOffset>7</bitOffset>
              <bitWidth>1</bitWidth>
            </field>
            <field>
              <name>CHINSEL</name>
              <bitOffset>8</bitOffset>
              <bitWidth>1</bitWidth>
            </field>
            <field>
              <name>DATMPX</name>
              <bitOffset>12</bitOffset>
              <bitWidth>2</bitWidth>
            </field>
            <field>
              <name>DATPACK</name>
              <bitOffset>14</bitOffset>
              <bitWidth>2</bitWidth>
            </field>
            <field>
              <name>CKOUTDIV</name>
              <bitOffset>16</bitOffset>
              <bitWidth>8</bitWidth>
            </field>
            <field>
              <name>CKOUTSRC</name>
              <bitOffset>30</bitOffset>
              <bitWidth>1</bitWidth>
            </field>
            <field>
              <name>DFSDMEN</name>
              <bitOffset>31</bitOffset>
              <bitWidth>1</bitWidth>
            </field>
          </fields>
        </register>
        <register>
          <name>CHCFGR26</name>
          <addressOffset>0xc4</addressOffset>
          <size>0x20</size>
          <fields>
            <field>
              <name>DTRBS</name>
              <bitOffset>3</bitOffset>
              <bitWidth>5</bitWidth>
            </field>
            <field>
              <name>OFFSET</name>
              <bitOffset>8</bitOffset>
              <bitWidth>24</bitWidth>
            </field>
          </fields>
        </register>
        <register>
          <name>CHAWSCDR6</name>
          <addressOffset>0xc8</addressOffset>
          <size>0x20</size>
          <fields>
            <field>
              <name>SCDT</name>
              <bitOffset>0</bitOffset>
              <bitWidth>8</bitWidth>
            </field>
            <field>
              <name>BKSCD</name>
              <bitOffset>12</bitOffset>
              <bitWidth>4</bitWidth>
            </field>
            <field>
              <name>AWFOSR</name>
              <bitOffset>16</bitOffset>
              <bitWidth>5</bitWidth>
            </field>
            <field>
              <name>AWFORD</name>
              <bitOffset>22</bitOffset>
              <bitWidth>2</bitWidth>
            </field>
          </fields>
        </register>
        <register>
          <name>CHWDATAR6</name>
          <addressOffset>0xcc</addressOffset>
          <size>0x20</size>
        </register>
        <register>
          <name>CHDATINR6</name>
          <addressOffset>0xd0</addressOffset>
          <size>0x20</size>
          <fields>
            <field>
              <name>INDAT0</name>
              <bitOffset>0</bitOffset>
              <bitWidth>16</bitWidth>
            </field>
            <field>
              <name>INDAT1</name>
              <bitOffset>16</bitOffset>
              <bitWidth>16</bitWidth>
            </field>
          </fields>
        </register>
        <register>
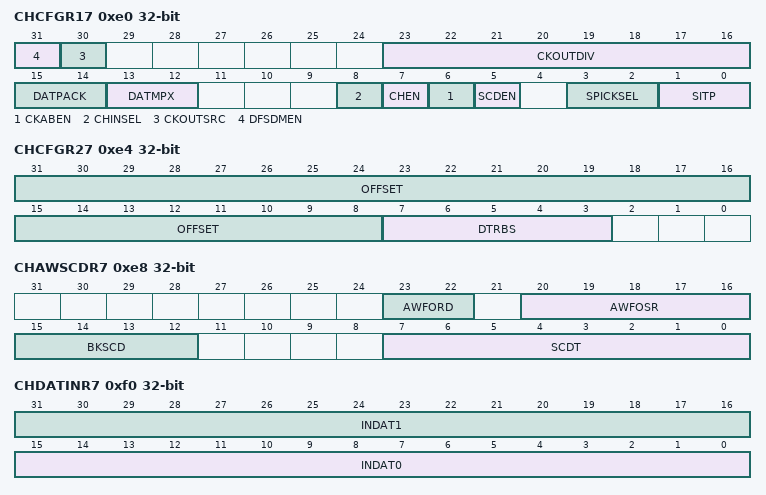
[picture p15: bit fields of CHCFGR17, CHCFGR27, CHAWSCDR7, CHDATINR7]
          <name>CHCFGR17</name>
          <addressOffset>0xe0</addressOffset>
          <size>0x20</size>
          <fields>
            <field>
              <name>SITP</name>
              <bitOffset>0</bitOffset>
              <bitWidth>2</bitWidth>
            </field>
            <field>
              <name>SPICKSEL</name>
              <bitOffset>2</bitOffset>
              <bitWidth>2</bitWidth>
            </field>
            <field>
              <name>SCDEN</name>
              <bitOffset>5</bitOffset>
              <bitWidth>1</bitWidth>
            </field>
            <field>
              <name>CKABEN</name>
              <bitOffset>6</bitOffset>
              <bitWidth>1</bitWidth>
            </field>
            <field>
              <name>CHEN</name>
              <bitOffset>7</bitOffset>
              <bitWidth>1</bitWidth>
            </field>
            <field>
              <name>CHINSEL</name>
              <bitOffset>8</bitOffset>
              <bitWidth>1</bitWidth>
            </field>
            <field>
              <name>DATMPX</name>
              <bitOffset>12</bitOffset>
              <bitWidth>2</bitWidth>
            </field>
            <field>
              <name>DATPACK</name>
              <bitOffset>14</bitOffset>
              <bitWidth>2</bitWidth>
            </field>
            <field>
              <name>CKOUTDIV</name>
              <bitOffset>16</bitOffset>
              <bitWidth>8</bitWidth>
            </field>
            <field>
              <name>CKOUTSRC</name>
              <bitOffset>30</bitOffset>
              <bitWidth>1</bitWidth>
            </field>
            <field>
              <name>DFSDMEN</name>
              <bitOffset>31</bitOffset>
              <bitWidth>1</bitWidth>
            </field>
          </fields>
        </register>
        <register>
          <name>CHCFGR27</name>
          <addressOffset>0xe4</addressOffset>
          <size>0x20</size>
          <fields>
            <field>
              <name>DTRBS</name>
              <bitOffset>3</bitOffset>
              <bitWidth>5</bitWidth>
            </field>
            <field>
              <name>OFFSET</name>
              <bitOffset>8</bitOffset>
              <bitWidth>24</bitWidth>
            </field>
          </fields>
        </register>
        <register>
          <name>CHAWSCDR7</name>
          <addressOffset>0xe8</addressOffset>
          <size>0x20</size>
          <fields>
            <field>
              <name>SCDT</name>
              <bitOffset>0</bitOffset>
              <bitWidth>8</bitWidth>
            </field>
            <field>
              <name>BKSCD</name>
              <bitOffset>12</bitOffset>
              <bitWidth>4</bitWidth>
            </field>
            <field>
              <name>AWFOSR</name>
              <bitOffset>16</bitOffset>
              <bitWidth>5</bitWidth>
            </field>
            <field>
              <name>AWFORD</name>
              <bitOffset>22</bitOffset>
              <bitWidth>2</bitWidth>
            </field>
          </fields>
        </register>
        <register>
          <name>CHWDATAR7</name>
          <addressOffset>0xec</addressOffset>
          <size>0x20</size>
        </register>
        <register>
          <name>CHDATINR7</name>
          <addressOffset>0xf0</addressOffset>
          <size>0x20</size>
          <fields>
            <field>
              <name>INDAT0</name>
              <bitOffset>0</bitOffset>
              <bitWidth>16</bitWidth>
            </field>
            <field>
              <name>INDAT1</name>
              <bitOffset>16</bitOffset>
              <bitWidth>16</bitWidth>
            </field>
          </fields>
        </register>
        <register>
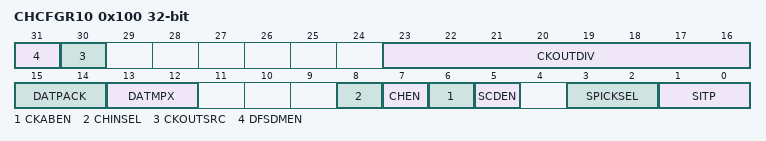
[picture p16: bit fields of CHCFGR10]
          <name>CHCFGR10</name>
          <addressOffset>0x100</addressOffset>
          <size>0x20</size>
          <fields>
            <field>
              <name>SITP</name>
              <bitOffset>0</bitOffset>
              <bitWidth>2</bitWidth>
            </field>
            <field>
              <name>SPICKSEL</name>
              <bitOffset>2</bitOffset>
              <bitWidth>2</bitWidth>
            </field>
            <field>
              <name>SCDEN</name>
              <bitOffset>5</bitOffset>
              <bitWidth>1</bitWidth>
            </field>
            <field>
              <name>CKABEN</name>
              <bitOffset>6</bitOffset>
              <bitWidth>1</bitWidth>
            </field>
            <field>
              <name>CHEN</name>
              <bitOffset>7</bitOffset>
              <bitWidth>1</bitWidth>
            </field>
            <field>
              <name>CHINSEL</name>
              <bitOffset>8</bitOffset>
              <bitWidth>1</bitWidth>
            </field>
            <field>
              <name>DATMPX</name>
              <bitOffset>12</bitOffset>
              <bitWidth>2</bitWidth>
            </field>
            <field>
              <name>DATPACK</name>
              <bitOffset>14</bitOffset>
              <bitWidth>2</bitWidth>
            </field>
            <field>
              <name>CKOUTDIV</name>
              <bitOffset>16</bitOffset>
              <bitWidth>8</bitWidth>
            </field>
            <field>
              <name>CKOUTSRC</name>
              <bitOffset>30</bitOffset>
              <bitWidth>1</bitWidth>
            </field>
            <field>
              <name>DFSDMEN</name>
              <bitOffset>31</bitOffset>
              <bitWidth>1</bitWidth>
            </field>
          </fields>
        </register>
        <register>
          <name>CHCFGR20</name>
          <addressOffset>0x104</addressOffset>
          <size>0x20</size>
          <fields>
            <field>
              <name>DTRBS</name>
              <bitOffset>3</bitOffset>
              <bitWidth>5</bitWidth>
            </field>
            <field>
              <name>OFFSET</name>
              <bitOffset>8</bitOffset>
              <bitWidth>24</bitWidth>
            </field>
          </fields>
        </register>
        <register>
          <name>CHAWSCDR0</name>
          <addressOffset>0x108</addressOffset>
          <size>0x20</size>
          <fields>
            <field>
              <name>SCDT</name>
              <bitOffset>0</bitOffset>
              <bitWidth>8</bitWidth>
            </field>
            <field>
              <name>BKSCD</name>
              <bitOffset>12</bitOffset>
              <bitWidth>4</bitWidth>
            </field>
            <field>
              <name>AWFOSR</name>
              <bitOffset>16</bitOffset>
              <bitWidth>5</bitWidth>
            </field>
            <field>
              <name>AWFORD</name>
              <bitOffset>22</bitOffset>
              <bitWidth>2</bitWidth>
            </field>
          </fields>
        </register>
        <register>
          <name>CHWDATAR0</name>
          <addressOffset>0x10c</addressOffset>
          <size>0x20</size>
        </register>
        <register>
          <name>CHDATINR0</name>
          <addressOffset>0x110</addressOffset>
          <size>0x20</size>
          <fields>
            <field>
              <name>INDAT0</name>
              <bitOffset>0</bitOffset>
              <bitWidth>16</bitWidth>
            </field>
            <field>
              <name>INDAT1</name>
              <bitOffset>16</bitOffset>
              <bitWidth>16</bitWidth>
            </field>
          </fields>
        </register>
        <register>
          <name>CHCFGR11</name>
          <addressOffset>0x180</addressOffset>
          <size>0x20</size>
          <fields>
            <field>
              <name>SITP</name>
              <bitOffset>0</bitOffset>
              <bitWidth>2</bitWidth>
            </field>
            <field>
              <name>SPICKSEL</name>
              <bitOffset>2</bitOffset>
              <bitWidth>2</bitWidth>
            </field>
            <field>
              <name>SCDEN</name>
              <bitOffset>5</bitOffset>
              <bitWidth>1</bitWidth>
            </field>
            <field>
              <name>CKABEN</name>
              <bitOffset>6</bitOffset>
              <bitWidth>1</bitWidth>
            </field>
            <field>
              <name>CHEN</name>
              <bitOffset>7</bitOffset>
              <bitWidth>1</bitWidth>
            </field>
            <field>
              <name>CHINSEL</name>
              <bitOffset>8</bitOffset>
              <bitWidth>1</bitWidth>
            </field>
            <field>
              <name>DATMPX</name>
              <bitOffset>12</bitOffset>
              <bitWidth>2</bitWidth>
            </field>
            <field>
              <name>DATPACK</name>
              <bitOffset>14</bitOffset>
              <bitWidth>2</bitWidth>
            </field>
            <field>
              <name>CKOUTDIV</name>
              <bitOffset>16</bitOffset>
              <bitWidth>8</bitWidth>
            </field>
            <field>
              <name>CKOUTSRC</name>
              <bitOffset>30</bitOffset>
              <bitWidth>1</bitWidth>
            </field>
            <field>
              <name>DFSDMEN</name>
              <bitOffset>31</bitOffset>
              <bitWidth>1</bitWidth>
            </field>
          </fields>
        </register>
        <register>
          <name>CHCFGR21</name>
          <addressOffset>0x184</addressOffset>
          <size>0x20</size>
          <fields>
            <field>
              <name>DTRBS</name>
              <bitOffset>3</bitOffset>
              <bitWidth>5</bitWidth>
            </field>
            <field>
              <name>OFFSET</name>
              <bitOffset>8</bitOffset>
              <bitWidth>24</bitWidth>
            </field>
          </fields>
        </register>
        <register>
          <name>CHAWSCDR1</name>
          <addressOffset>0x188</addressOffset>
          <size>0x20</size>
          <fields>
            <field>
              <name>SCDT</name>
              <bitOffset>0</bitOffset>
              <bitWidth>8</bitWidth>
            </field>
            <field>
              <name>BKSCD</name>
              <bitOffset>12</bitOffset>
              <bitWidth>4</bitWidth>
            </field>
            <field>
              <name>AWFOSR</name>
              <bitOffset>16</bitOffset>
              <bitWidth>5</bitWidth>
            </field>
            <field>
              <name>AWFORD</name>
              <bitOffset>22</bitOffset>
              <bitWidth>2</bitWidth>
            </field>
          </fields>
        </register>
        <register>
          <name>CHWDATAR1</name>
          <addressOffset>0x18c</addressOffset>
          <size>0x20</size>
        </register>
        <register>
          <name>CHDATINR1</name>
          <addressOffset>0x190</addressOffset>
          <size>0x20</size>
          <fields>
            <field>
              <name>INDAT0</name>
              <bitOffset>0</bitOffset>
              <bitWidth>16</bitWidth>
            </field>
            <field>
              <name>INDAT1</name>
              <bitOffset>16</bitOffset>
              <bitWidth>16</bitWidth>
            </field>
          </fields>
        </register>
        <register>
          <name>CHCFGR12</name>
          <addressOffset>0x200</addressOffset>
          <size>0x20</size>
          <fields>
            <field>
              <name>SITP</name>
              <bitOffset>0</bitOffset>
              <bitWidth>2</bitWidth>
            </field>
            <field>
              <name>SPICKSEL</name>
              <bitOffset>2</bitOffset>
              <bitWidth>2</bitWidth>
            </field>
            <field>
              <name>SCDEN</name>
              <bitOffset>5</bitOffset>
              <bitWidth>1</bitWidth>
            </field>
            <field>
              <name>CKABEN</name>
              <bitOffset>6</bitOffset>
              <bitWidth>1</bitWidth>
            </field>
            <field>
              <name>CHEN</name>
              <bitOffset>7</bitOffset>
              <bitWidth>1</bitWidth>
            </field>
            <field>
              <name>CHINSEL</name>
              <bitOffset>8</bitOffset>
              <bitWidth>1</bitWidth>
            </field>
            <field>
              <name>DATMPX</name>
              <bitOffset>12</bitOffset>
              <bitWidth>2</bitWidth>
            </field>
            <field>
              <name>DATPACK</name>
              <bitOffset>14</bitOffset>
              <bitWidth>2</bitWidth>
            </field>
            <field>
              <name>CKOUTDIV</name>
              <bitOffset>16</bitOffset>
              <bitWidth>8</bitWidth>
            </field>
            <field>
              <name>CKOUTSRC</name>
              <bitOffset>30</bitOffset>
              <bitWidth>1</bitWidth>
            </field>
            <field>
              <name>DFSDMEN</name>
              <bitOffset>31</bitOffset>
              <bitWidth>1</bitWidth>
            </field>
          </fields>
        </register>
        <register>
          <name>CHCFGR22</name>
          <addressOffset>0x204</addressOffset>
          <size>0x20</size>
          <fields>
            <field>
              <name>DTRBS</name>
              <bitOffset>3</bitOffset>
              <bitWidth>5</bitWidth>
            </field>
            <field>
              <name>OFFSET</name>
              <bitOffset>8</bitOffset>
              <bitWidth>24</bitWidth>
            </field>
          </fields>
        </register>
        <register>
          <name>CHAWSCDR2</name>
          <addressOffset>0x208</addressOffset>
          <size>0x20</size>
          <fields>
            <field>
              <name>SCDT</name>
              <bitOffset>0</bitOffset>
              <bitWidth>8</bitWidth>
            </field>
            <field>
              <name>BKSCD</name>
              <bitOffset>12</bitOffset>
              <bitWidth>4</bitWidth>
            </field>
            <field>
              <name>AWFOSR</name>
              <bitOffset>16</bitOffset>
              <bitWidth>5</bitWidth>
            </field>
            <field>
              <name>AWFORD</name>
              <bitOffset>22</bitOffset>
              <bitWidth>2</bitWidth>
            </field>
          </fields>
        </register>
        <register>
          <name>CHWDATAR2</name>
          <addressOffset>0x20c</addressOffset>
          <size>0x20</size>
        </register>
        <register>
          <name>CHDATINR2</name>
          <addressOffset>0x210</addressOffset>
          <size>0x20</size>
          <fields>
            <field>
              <name>INDAT0</name>
              <bitOffset>0</bitOffset>
              <bitWidth>16</bitWidth>
            </field>
            <field>
              <name>INDAT1</name>
              <bitOffset>16</bitOffset>
              <bitWidth>16</bitWidth>
            </field>
          </fields>
        </register>
        <register>
          <name>CHCFGR13</name>
          <addressOffset>0x280</addressOffset>
          <size>0x20</size>
          <fields>
            <field>
              <name>SITP</name>
              <bitOffset>0</bitOffset>
              <bitWidth>2</bitWidth>
            </field>
            <field>
              <name>SPICKSEL</name>
              <bitOffset>2</bitOffset>
              <bitWidth>2</bitWidth>
            </field>
            <field>
              <name>SCDEN</name>
              <bitOffset>5</bitOffset>
              <bitWidth>1</bitWidth>
            </field>
            <field>
              <name>CKABEN</name>
              <bitOffset>6</bitOffset>
              <bitWidth>1</bitWidth>
            </field>
            <field>
              <name>CHEN</name>
              <bitOffset>7</bitOffset>
              <bitWidth>1</bitWidth>
            </field>
            <field>
              <name>CHINSEL</name>
              <bitOffset>8</bitOffset>
              <bitWidth>1</bitWidth>
            </field>
            <field>
              <name>DATMPX</name>
              <bitOffset>12</bitOffset>
              <bitWidth>2</bitWidth>
            </field>
            <field>
              <name>DATPACK</name>
              <bitOffset>14</bitOffset>
              <bitWidth>2</bitWidth>
            </field>
            <field>
              <name>CKOUTDIV</name>
              <bitOffset>16</bitOffset>
              <bitWidth>8</bitWidth>
            </field>
            <field>
              <name>CKOUTSRC</name>
              <bitOffset>30</bitOffset>
              <bitWidth>1</bitWidth>
            </field>
            <field>
              <name>DFSDMEN</name>
              <bitOffset>31</bitOffset>
              <bitWidth>1</bitWidth>
            </field>
          </fields>
        </register>
        <register>
          <name>CHCFGR23</name>
          <addressOffset>0x284</addressOffset>
          <size>0x20</size>
          <fields>
            <field>
              <name>DTRBS</name>
              <bitOffset>3</bitOffset>
              <bitWidth>5</bitWidth>
            </field>
            <field>
              <name>OFFSET</name>
              <bitOffset>8</bitOffset>
              <bitWidth>24</bitWidth>
            </field>
          </fields>
        </register>
        <register>
          <name>CHAWSCDR3</name>
          <addressOffset>0x288</addressOffset>
          <size>0x20</size>
          <fields>
            <field>
              <name>SCDT</name>
              <bitOffset>0</bitOffset>
              <bitWidth>8</bitWidth>
            </field>
            <field>
              <name>BKSCD</name>
              <bitOffset>12</bitOffset>
              <bitWidth>4</bitWidth>
            </field>
            <field>
              <name>AWFOSR</name>
              <bitOffset>16</bitOffset>
              <bitWidth>5</bitWidth>
            </field>
            <field>
              <name>AWFORD</name>
              <bitOffset>22</bitOffset>
              <bitWidth>2</bitWidth>
            </field>
          </fields>
        </register>
        <register>
          <name>CHWDATAR3</name>
          <addressOffset>0x28c</addressOffset>
          <size>0x20</size>
        </register>
        <register>
          <name>CHDATINR3</name>
          <addressOffset>0x290</addressOffset>
          <size>0x20</size>
          <fields>
            <field>
              <name>INDAT0</name>
              <bitOffset>0</bitOffset>
              <bitWidth>16</bitWidth>
            </field>
            <field>
              <name>INDAT1</name>
              <bitOffset>16</bitOffset>
              <bitWidth>16</bitWidth>
            </field>
          </fields>
        </register>
      </registers>
    </peripheral>
    <peripheral>
      <name>DMA1</name>
      <baseAddress>0x40020000</baseAddress>
      <registers>
        <register>
          <name>LISR</name>
          <addressOffset>0x0</addressOffset>
          <size>0x20</size>
          <fields>
            <field>
              <name>FEIF0</name>
              <bitOffset>0</bitOffset>
              <bitWidth>1</bitWidth>
            </field>
            <field>
              <name>DMEIF0</name>
              <bitOffset>2</bitOffset>
              <bitWidth>1</bitWidth>
            </field>
            <field>
              <name>TEIF0</name>
              <bitOffset>3</bitOffset>
              <bitWidth>1</bitWidth>
            </field>
            <field>
              <name>HTIF0</name>
              <bitOffset>4</bitOffset>
              <bitWidth>1</bitWidth>
            </field>
            <field>
              <name>TCIF0</name>
              <bitOffset>5</bitOffset>
              <bitWidth>1</bitWidth>
            </field>
            <field>
              <name>FEIF1</name>
              <bitOffset>6</bitOffset>
              <bitWidth>1</bitWidth>
            </field>
            <field>
              <name>DMEIF1</name>
              <bitOffset>8</bitOffset>
              <bitWidth>1</bitWidth>
            </field>
            <field>
              <name>TEIF1</name>
              <bitOffset>9</bitOffset>
              <bitWidth>1</bitWidth>
            </field>
            <field>
              <name>HTIF1</name>
              <bitOffset>10</bitOffset>
              <bitWidth>1</bitWidth>
            </field>
            <field>
              <name>TCIF1</name>
              <bitOffset>11</bitOffset>
              <bitWidth>1</bitWidth>
            </field>
            <field>
              <name>FEIF2</name>
              <bitOffset>16</bitOffset>
              <bitWidth>1</bitWidth>
            </field>
            <field>
              <name>DMEIF2</name>
              <bitOffset>18</bitOffset>
              <bitWidth>1</bitWidth>
            </field>
            <field>
              <name>TEIF2</name>
              <bitOffset>19</bitOffset>
              <bitWidth>1</bitWidth>
            </field>
            <field>
              <name>HTIF2</name>
              <bitOffset>20</bitOffset>
              <bitWidth>1</bitWidth>
            </field>
            <field>
              <name>TCIF2</name>
              <bitOffset>21</bitOffset>
              <bitWidth>1</bitWidth>
            </field>
            <field>
              <name>FEIF3</name>
              <bitOffset>22</bitOffset>
              <bitWidth>1</bitWidth>
            </field>
            <field>
              <name>DMEIF3</name>
              <bitOffset>24</bitOffset>
              <bitWidth>1</bitWidth>
            </field>
            <field>
              <name>TEIF3</name>
              <bitOffset>25</bitOffset>
              <bitWidth>1</bitWidth>
            </field>
            <field>
              <name>HTIF3</name>
              <bitOffset>26</bitOffset>
              <bitWidth>1</bitWidth>
            </field>
            <field>
              <name>TCIF3</name>
              <bitOffset>27</bitOffset>
              <bitWidth>1</bitWidth>
            </field>
          </fields>
        </register>
        <register>
          <name>HISR</name>
          <addressOffset>0x4</addressOffset>
          <size>0x20</size>
          <fields>
            <field>
              <name>FEIF4</name>
              <bitOffset>0</bitOffset>
              <bitWidth>1</bitWidth>
            </field>
            <field>
              <name>DMEIF4</name>
              <bitOffset>2</bitOffset>
              <bitWidth>1</bitWidth>
            </field>
            <field>
              <name>TEIF4</name>
              <bitOffset>3</bitOffset>
              <bitWidth>1</bitWidth>
            </field>
            <field>
              <name>HTIF4</name>
              <bitOffset>4</bitOffset>
              <bitWidth>1</bitWidth>
            </field>
            <field>
              <name>TCIF4</name>
              <bitOffset>5</bitOffset>
              <bitWidth>1</bitWidth>
            </field>
            <field>
              <name>FEIF5</name>
              <bitOffset>6</bitOffset>
              <bitWidth>1</bitWidth>
            </field>
            <field>
              <name>DMEIF5</name>
              <bitOffset>8</bitOffset>
              <bitWidth>1</bitWidth>
            </field>
            <field>
              <name>TEIF5</name>
              <bitOffset>9</bitOffset>
              <bitWidth>1</bitWidth>
            </field>
            <field>
              <name>HTIF5</name>
              <bitOffset>10</bitOffset>
              <bitWidth>1</bitWidth>
            </field>
            <field>
              <name>TCIF5</name>
              <bitOffset>11</bitOffset>
              <bitWidth>1</bitWidth>
            </field>
            <field>
              <name>FEIF6</name>
              <bitOffset>16</bitOffset>
              <bitWidth>1</bitWidth>
            </field>
            <field>
              <name>DMEIF6</name>
              <bitOffset>18</bitOffset>
              <bitWidth>1</bitWidth>
            </field>
            <field>
              <name>TEIF6</name>
              <bitOffset>19</bitOffset>
              <bitWidth>1</bitWidth>
            </field>
            <field>
              <name>HTIF6</name>
              <bitOffset>20</bitOffset>
              <bitWidth>1</bitWidth>
            </field>
            <field>
              <name>TCIF6</name>
              <bitOffset>21</bitOffset>
              <bitWidth>1</bitWidth>
            </field>
            <field>
              <name>FEIF7</name>
              <bitOffset>22</bitOffset>
              <bitWidth>1</bitWidth>
            </field>
            <field>
              <name>DMEIF7</name>
              <bitOffset>24</bitOffset>
              <bitWidth>1</bitWidth>
            </field>
            <field>
              <name>TEIF7</name>
              <bitOffset>25</bitOffset>
              <bitWidth>1</bitWidth>
            </field>
            <field>
              <name>HTIF7</name>
              <bitOffset>26</bitOffset>
              <bitWidth>1</bitWidth>
            </field>
            <field>
              <name>TCIF7</name>
              <bitOffset>27</bitOffset>
              <bitWidth>1</bitWidth>
            </field>
          </fields>
        </register>
        <register>
          <name>LIFCR</name>
          <addressOffset>0x8</addressOffset>
          <size>0x20</size>
          <fields>
            <field>
              <name>CFEIF0</name>
              <bitOffset>0</bitOffset>
              <bitWidth>1</bitWidth>
            </field>
            <field>
              <name>CDMEIF0</name>
              <bitOffset>2</bitOffset>
              <bitWidth>1</bitWidth>
            </field>
            <field>
              <name>CTEIF0</name>
              <bitOffset>3</bitOffset>
              <bitWidth>1</bitWidth>
            </field>
            <field>
              <name>CHTIF0</name>
              <bitOffset>4</bitOffset>
              <bitWidth>1</bitWidth>
            </field>
            <field>
              <name>CTCIF0</name>
              <bitOffset>5</bitOffset>
              <bitWidth>1</bitWidth>
            </field>
            <field>
              <name>CFEIF1</name>
              <bitOffset>6</bitOffset>
              <bitWidth>1</bitWidth>
            </field>
            <field>
              <name>CDMEIF1</name>
              <bitOffset>8</bitOffset>
              <bitWidth>1</bitWidth>
            </field>
            <field>
              <name>CTEIF1</name>
              <bitOffset>9</bitOffset>
              <bitWidth>1</bitWidth>
            </field>
            <field>
              <name>CHTIF1</name>
              <bitOffset>10</bitOffset>
              <bitWidth>1</bitWidth>
            </field>
            <field>
              <name>CTCIF1</name>
              <bitOffset>11</bitOffset>
              <bitWidth>1</bitWidth>
            </field>
            <field>
              <name>CFEIF2</name>
              <bitOffset>16</bitOffset>
              <bitWidth>1</bitWidth>
            </field>
            <field>
              <name>CDMEIF2</name>
              <bitOffset>18</bitOffset>
              <bitWidth>1</bitWidth>
            </field>
            <field>
              <name>CTEIF2</name>
              <bitOffset>19</bitOffset>
              <bitWidth>1</bitWidth>
            </field>
            <field>
              <name>CHTIF2</name>
              <bitOffset>20</bitOffset>
              <bitWidth>1</bitWidth>
            </field>
            <field>
              <name>CTCIF2</name>
              <bitOffset>21</bitOffset>
              <bitWidth>1</bitWidth>
            </field>
            <field>
              <name>CFEIF3</name>
              <bitOffset>22</bitOffset>
              <bitWidth>1</bitWidth>
            </field>
            <field>
              <name>CDMEIF3</name>
              <bitOffset>24</bitOffset>
              <bitWidth>1</bitWidth>
            </field>
            <field>
              <name>CTEIF3</name>
              <bitOffset>25</bitOffset>
              <bitWidth>1</bitWidth>
            </field>
            <field>
              <name>CHTIF3</name>
              <bitOffset>26</bitOffset>
              <bitWidth>1</bitWidth>
            </field>
            <field>
              <name>CTCIF3</name>
              <bitOffset>27</bitOffset>
              <bitWidth>1</bitWidth>
            </field>
          </fields>
        </register>
        <register>
          <name>HIFCR</name>
          <addressOffset>0xc</addressOffset>
          <size>0x20</size>
          <fields>
            <field>
              <name>CFEIF4</name>
              <bitOffset>0</bitOffset>
              <bitWidth>1</bitWidth>
            </field>
            <field>
              <name>CDMEIF4</name>
              <bitOffset>2</bitOffset>
              <bitWidth>1</bitWidth>
            </field>
            <field>
              <name>CTEIF4</name>
              <bitOffset>3</bitOffset>
              <bitWidth>1</bitWidth>
            </field>
            <field>
              <name>CHTIF4</name>
              <bitOffset>4</bitOffset>
              <bitWidth>1</bitWidth>
            </field>
            <field>
              <name>CTCIF4</name>
              <bitOffset>5</bitOffset>
              <bitWidth>1</bitWidth>
            </field>
            <field>
              <name>CFEIF5</name>
              <bitOffset>6</bitOffset>
              <bitWidth>1</bitWidth>
            </field>
            <field>
              <name>CDMEIF5</name>
              <bitOffset>8</bitOffset>
              <bitWidth>1</bitWidth>
            </field>
            <field>
              <name>CTEIF5</name>
              <bitOffset>9</bitOffset>
              <bitWidth>1</bitWidth>
            </field>
            <field>
              <name>CHTIF5</name>
              <bitOffset>10</bitOffset>
              <bitWidth>1</bitWidth>
            </field>
            <field>
              <name>CTCIF5</name>
              <bitOffset>11</bitOffset>
              <bitWidth>1</bitWidth>
            </field>
            <field>
              <name>CFEIF6</name>
              <bitOffset>16</bitOffset>
              <bitWidth>1</bitWidth>
            </field>
            <field>
              <name>CDMEIF6</name>
              <bitOffset>18</bitOffset>
              <bitWidth>1</bitWidth>
            </field>
            <field>
              <name>CTEIF6</name>
              <bitOffset>19</bitOffset>
              <bitWidth>1</bitWidth>
            </field>
            <field>
              <name>CHTIF6</name>
              <bitOffset>20</bitOffset>
              <bitWidth>1</bitWidth>
            </field>
            <field>
              <name>CTCIF6</name>
              <bitOffset>21</bitOffset>
              <bitWidth>1</bitWidth>
            </field>
            <field>
              <name>CFEIF7</name>
              <bitOffset>22</bitOffset>
              <bitWidth>1</bitWidth>
            </field>
            <field>
              <name>CDMEIF7</name>
              <bitOffset>24</bitOffset>
              <bitWidth>1</bitWidth>
            </field>
            <field>
              <name>CTEIF7</name>
              <bitOffset>25</bitOffset>
              <bitWidth>1</bitWidth>
            </field>
            <field>
              <name>CHTIF7</name>
              <bitOffset>26</bitOffset>
              <bitWidth>1</bitWidth>
            </field>
            <field>
              <name>CTCIF7</name>
              <bitOffset>27</bitOffset>
              <bitWidth>1</bitWidth>
            </field>
          </fields>
        </register>
        <register>
          <name>CR0</name>
          <addressOffset>0x10</addressOffset>
          <size>0x20</size>
        </register>
        <register>
          <name>CR0</name>
          <addressOffset>0x10</addressOffset>
          <size>0x20</size>
        </register>
        <register>
          <name>NDTR0</name>
          <addressOffset>0x14</addressOffset>
          <size>0x20</size>
        </register>
        <register>
          <name>NDTR0</name>
          <addressOffset>0x14</addressOffset>
          <size>0x20</size>
        </register>
        <register>
          <name>PAR0</name>
          <addressOffset>0x18</addressOffset>
          <size>0x20</size>
        </register>
        <register>
          <name>PAR0</name>
          <addressOffset>0x18</addressOffset>
          <size>0x20</size>
        </register>
        <register>
          <name>M0AR0</name>
          <addressOffset>0x1c</addressOffset>
          <size>0x20</size>
        </register>
        <register>
          <name>M0AR0</name>
          <addressOffset>0x1c</addressOffset>
          <size>0x20</size>
        </register>
        <register>
          <name>M1AR0</name>
          <addressOffset>0x20</addressOffset>
          <size>0x20</size>
        </register>
        <register>
          <name>M1AR0</name>
          <addressOffset>0x20</addressOffset>
          <size>0x20</size>
        </register>
        <register>
          <name>FCR0</name>
          <addressOffset>0x24</addressOffset>
          <size>0x20</size>
        </register>
        <register>
          <name>FCR0</name>
          <addressOffset>0x24</addressOffset>
          <size>0x20</size>
        </register>
        <register>
          <name>CR1</name>
          <addressOffset>0x28</addressOffset>
          <size>0x20</size>
        </register>
        <register>
          <name>CR1</name>
          <addressOffset>0x28</addressOffset>
          <size>0x20</size>
        </register>
        <register>
          <name>NDTR1</name>
          <addressOffset>0x2c</addressOffset>
          <size>0x20</size>
        </register>
        <register>
          <name>NDTR1</name>
          <addressOffset>0x2c</addressOffset>
          <size>0x20</size>
        </register>
        <register>
          <name>PAR1</name>
          <addressOffset>0x30</addressOffset>
          <size>0x20</size>
        </register>
        <register>
          <name>PAR1</name>
          <addressOffset>0x30</addressOffset>
          <size>0x20</size>
        </register>
        <register>
          <name>M0AR1</name>
          <addressOffset>0x34</addressOffset>
          <size>0x20</size>
        </register>
        <register>
          <name>M0AR1</name>
          <addressOffset>0x34</addressOffset>
          <size>0x20</size>
        </register>
        <register>
          <name>M1AR1</name>
          <addressOffset>0x38</addressOffset>
          <size>0x20</size>
        </register>
        <register>
          <name>M1AR1</name>
          <addressOffset>0x38</addressOffset>
          <size>0x20</size>
        </register>
        <register>
          <name>FCR1</name>
          <addressOffset>0x3c</addressOffset>
          <size>0x20</size>
        </register>
        <register>
          <name>FCR1</name>
          <addressOffset>0x3c</addressOffset>
          <size>0x20</size>
        </register>
        <register>
          <name>CR2</name>
          <addressOffset>0x40</addressOffset>
          <size>0x20</size>
        </register>
        <register>
          <name>CR2</name>
          <addressOffset>0x40</addressOffset>
          <size>0x20</size>
        </register>
        <register>
          <name>NDTR2</name>
          <addressOffset>0x44</addressOffset>
          <size>0x20</size>
        </register>
        <register>
          <name>NDTR2</name>
          <addressOffset>0x44</addressOffset>
          <size>0x20</size>
        </register>
        <register>
          <name>PAR2</name>
          <addressOffset>0x48</addressOffset>
          <size>0x20</size>
        </register>
        <register>
          <name>PAR2</name>
          <addressOffset>0x48</addressOffset>
          <size>0x20</size>
        </register>
        <register>
          <name>M0AR2</name>
          <addressOffset>0x4c</addressOffset>
          <size>0x20</size>
        </register>
        <register>
          <name>M0AR2</name>
          <addressOffset>0x4c</addressOffset>
          <size>0x20</size>
        </register>
        <register>
          <name>M1AR2</name>
          <addressOffset>0x50</addressOffset>
          <size>0x20</size>
        </register>
        <register>
          <name>M1AR2</name>
          <addressOffset>0x50</addressOffset>
          <size>0x20</size>
        </register>
        <register>
          <name>FCR2</name>
          <addressOffset>0x54</addressOffset>
          <size>0x20</size>
        </register>
        <register>
          <name>FCR2</name>
          <addressOffset>0x54</addressOffset>
          <size>0x20</size>
        </register>
        <register>
          <name>CR3</name>
          <addressOffset>0x58</addressOffset>
          <size>0x20</size>
        </register>
        <register>
          <name>CR3</name>
          <addressOffset>0x58</addressOffset>
          <size>0x20</size>
        </register>
        <register>
          <name>NDTR3</name>
          <addressOffset>0x5c</addressOffset>
          <size>0x20</size>
        </register>
        <register>
          <name>NDTR3</name>
          <addressOffset>0x5c</addressOffset>
          <size>0x20</size>
        </register>
        <register>
          <name>PAR3</name>
          <addressOffset>0x60</addressOffset>
          <size>0x20</size>
        </register>
        <register>
          <name>PAR3</name>
          <addressOffset>0x60</addressOffset>
          <size>0x20</size>
        </register>
        <register>
          <name>M0AR3</name>
          <addressOffset>0x64</addressOffset>
          <size>0x20</size>
        </register>
        <register>
          <name>M0AR3</name>
          <addressOffset>0x64</addressOffset>
          <size>0x20</size>
        </register>
        <register>
          <name>M1AR3</name>
          <addressOffset>0x68</addressOffset>
          <size>0x20</size>
        </register>
        <register>
          <name>M1AR3</name>
          <addressOffset>0x68</addressOffset>
          <size>0x20</size>
        </register>
        <register>
          <name>FCR3</name>
          <addressOffset>0x6c</addressOffset>
          <size>0x20</size>
        </register>
        <register>
          <name>FCR3</name>
          <addressOffset>0x6c</addressOffset>
          <size>0x20</size>
        </register>
        <register>
          <name>CR4</name>
          <addressOffset>0x70</addressOffset>
          <size>0x20</size>
        </register>
        <register>
          <name>CR4</name>
          <addressOffset>0x70</addressOffset>
          <size>0x20</size>
        </register>
        <register>
          <name>NDTR4</name>
          <addressOffset>0x74</addressOffset>
          <size>0x20</size>
        </register>
        <register>
          <name>NDTR4</name>
          <addressOffset>0x74</addressOffset>
          <size>0x20</size>
        </register>
        <register>
          <name>PAR4</name>
          <addressOffset>0x78</addressOffset>
          <size>0x20</size>
        </register>
        <register>
          <name>PAR4</name>
          <addressOffset>0x78</addressOffset>
          <size>0x20</size>
        </register>
        <register>
          <name>M0AR4</name>
          <addressOffset>0x7c</addressOffset>
          <size>0x20</size>
        </register>
        <register>
          <name>M0AR4</name>
          <addressOffset>0x7c</addressOffset>
          <size>0x20</size>
        </register>
        <register>
          <name>M1AR4</name>
          <addressOffset>0x80</addressOffset>
          <size>0x20</size>
        </register>
        <register>
          <name>M1AR4</name>
          <addressOffset>0x80</addressOffset>
          <size>0x20</size>
        </register>
        <register>
          <name>FCR4</name>
          <addressOffset>0x84</addressOffset>
          <size>0x20</size>
        </register>
        <register>
          <name>FCR4</name>
          <addressOffset>0x84</addressOffset>
          <size>0x20</size>
        </register>
        <register>
          <name>CR5</name>
          <addressOffset>0x88</addressOffset>
          <size>0x20</size>
        </register>
        <register>
          <name>CR5</name>
          <addressOffset>0x88</addressOffset>
          <size>0x20</size>
        </register>
        <register>
          <name>NDTR5</name>
          <addressOffset>0x8c</addressOffset>
          <size>0x20</size>
        </register>
        <register>
          <name>NDTR5</name>
          <addressOffset>0x8c</addressOffset>
          <size>0x20</size>
        </register>
        <register>
          <name>PAR5</name>
          <addressOffset>0x90</addressOffset>
          <size>0x20</size>
        </register>
        <register>
          <name>PAR5</name>
          <addressOffset>0x90</addressOffset>
          <size>0x20</size>
        </register>
        <register>
          <name>M0AR5</name>
          <addressOffset>0x94</addressOffset>
          <size>0x20</size>
        </register>
        <register>
          <name>M0AR5</name>
          <addressOffset>0x94</addressOffset>
          <size>0x20</size>
        </register>
        <register>
          <name>M1AR5</name>
          <addressOffset>0x98</addressOffset>
          <size>0x20</size>
        </register>
        <register>
          <name>M1AR5</name>
          <addressOffset>0x98</addressOffset>
          <size>0x20</size>
        </register>
        <register>
          <name>FCR5</name>
          <addressOffset>0x9c</addressOffset>
          <size>0x20</size>
        </register>
        <register>
          <name>FCR5</name>
          <addressOffset>0x9c</addressOffset>
          <size>0x20</size>
        </register>
        <register>
          <name>CR6</name>
          <addressOffset>0xa0</addressOffset>
          <size>0x20</size>
        </register>
        <register>
          <name>CR6</name>
          <addressOffset>0xa0</addressOffset>
          <size>0x20</size>
        </register>
        <register>
          <name>NDTR6</name>
          <addressOffset>0xa4</addressOffset>
          <size>0x20</size>
        </register>
        <register>
          <name>NDTR6</name>
          <addressOffset>0xa4</addressOffset>
          <size>0x20</size>
        </register>
        <register>
          <name>PAR6</name>
          <addressOffset>0xa8</addressOffset>
          <size>0x20</size>
        </register>
        <register>
          <name>PAR6</name>
          <addressOffset>0xa8</addressOffset>
          <size>0x20</size>
        </register>
        <register>
          <name>M0AR6</name>
          <addressOffset>0xac</addressOffset>
          <size>0x20</size>
        </register>
        <register>
          <name>M0AR6</name>
          <addressOffset>0xac</addressOffset>
          <size>0x20</size>
        </register>
        <register>
          <name>M1AR6</name>
          <addressOffset>0xb0</addressOffset>
          <size>0x20</size>
        </register>
        <register>
          <name>M1AR6</name>
          <addressOffset>0xb0</addressOffset>
          <size>0x20</size>
        </register>
        <register>
          <name>FCR6</name>
          <addressOffset>0xb4</addressOffset>
          <size>0x20</size>
        </register>
        <register>
          <name>FCR6</name>
          <addressOffset>0xb4</addressOffset>
          <size>0x20</size>
        </register>
        <register>
          <name>CR7</name>
          <addressOffset>0xb8</addressOffset>
          <size>0x20</size>
        </register>
        <register>
          <name>CR7</name>
          <addressOffset>0xb8</addressOffset>
          <size>0x20</size>
        </register>
        <register>
          <name>NDTR7</name>
          <addressOffset>0xbc</addressOffset>
          <size>0x20</size>
        </register>
        <register>
          <name>NDTR7</name>
          <addressOffset>0xbc</addressOffset>
          <size>0x20</size>
        </register>
        <register>
          <name>PAR7</name>
          <addressOffset>0xc0</addressOffset>
          <size>0x20</size>
        </register>
        <register>
          <name>PAR7</name>
          <addressOffset>0xc0</addressOffset>
          <size>0x20</size>
        </register>
        <register>
          <name>M0AR7</name>
          <addressOffset>0xc4</addressOffset>
          <size>0x20</size>
        </register>
        <register>
          <name>M0AR7</name>
          <addressOffset>0xc4</addressOffset>
          <size>0x20</size>
        </register>
        <register>
          <name>M1AR7</name>
          <addressOffset>0xc8</addressOffset>
          <size>0x20</size>
        </register>
        <register>
          <name>M1AR7</name>
          <addressOffset>0xc8</addressOffset>
          <size>0x20</size>
        </register>
        <register>
          <name>FCR7</name>
          <addressOffset>0xcc</addressOffset>
          <size>0x20</size>
        </register>
        <register>
          <name>FCR7</name>
          <addressOffset>0xcc</addressOffset>
          <size>0x20</size>
        </register>
      </registers>
    </peripheral>
    <peripheral>
      <name>DMA2</name>
      <baseAddress>0x40020400</baseAddress>
      <registers>
        <register>
          <name>LISR</name>
          <addressOffset>0x0</addressOffset>
          <size>0x20</size>
          <fields>
            <field>
              <name>FEIF0</name>
              <bitOffset>0</bitOffset>
              <bitWidth>1</bitWidth>
            </field>
            <field>
              <name>DMEIF0</name>
              <bitOffset>2</bitOffset>
              <bitWidth>1</bitWidth>
            </field>
            <field>
              <name>TEIF0</name>
              <bitOffset>3</bitOffset>
              <bitWidth>1</bitWidth>
            </field>
            <field>
              <name>HTIF0</name>
              <bitOffset>4</bitOffset>
              <bitWidth>1</bitWidth>
            </field>
            <field>
              <name>TCIF0</name>
              <bitOffset>5</bitOffset>
              <bitWidth>1</bitWidth>
            </field>
            <field>
              <name>FEIF1</name>
              <bitOffset>6</bitOffset>
              <bitWidth>1</bitWidth>
            </field>
            <field>
              <name>DMEIF1</name>
              <bitOffset>8</bitOffset>
              <bitWidth>1</bitWidth>
            </field>
            <field>
              <name>TEIF1</name>
              <bitOffset>9</bitOffset>
              <bitWidth>1</bitWidth>
            </field>
            <field>
              <name>HTIF1</name>
              <bitOffset>10</bitOffset>
              <bitWidth>1</bitWidth>
            </field>
            <field>
              <name>TCIF1</name>
              <bitOffset>11</bitOffset>
              <bitWidth>1</bitWidth>
            </field>
            <field>
              <name>FEIF2</name>
              <bitOffset>16</bitOffset>
              <bitWidth>1</bitWidth>
            </field>
            <field>
              <name>DMEIF2</name>
              <bitOffset>18</bitOffset>
              <bitWidth>1</bitWidth>
            </field>
            <field>
              <name>TEIF2</name>
              <bitOffset>19</bitOffset>
              <bitWidth>1</bitWidth>
            </field>
            <field>
              <name>HTIF2</name>
              <bitOffset>20</bitOffset>
              <bitWidth>1</bitWidth>
            </field>
            <field>
              <name>TCIF2</name>
              <bitOffset>21</bitOffset>
              <bitWidth>1</bitWidth>
            </field>
            <field>
              <name>FEIF3</name>
              <bitOffset>22</bitOffset>
              <bitWidth>1</bitWidth>
            </field>
            <field>
              <name>DMEIF3</name>
              <bitOffset>24</bitOffset>
              <bitWidth>1</bitWidth>
            </field>
            <field>
              <name>TEIF3</name>
              <bitOffset>25</bitOffset>
              <bitWidth>1</bitWidth>
            </field>
            <field>
              <name>HTIF3</name>
              <bitOffset>26</bitOffset>
              <bitWidth>1</bitWidth>
            </field>
            <field>
              <name>TCIF3</name>
              <bitOffset>27</bitOffset>
              <bitWidth>1</bitWidth>
            </field>
          </fields>
        </register>
        <register>
          <name>HISR</name>
          <addressOffset>0x4</addressOffset>
          <size>0x20</size>
          <fields>
            <field>
              <name>FEIF4</name>
              <bitOffset>0</bitOffset>
              <bitWidth>1</bitWidth>
            </field>
            <field>
              <name>DMEIF4</name>
              <bitOffset>2</bitOffset>
              <bitWidth>1</bitWidth>
            </field>
            <field>
              <name>TEIF4</name>
              <bitOffset>3</bitOffset>
              <bitWidth>1</bitWidth>
            </field>
            <field>
              <name>HTIF4</name>
              <bitOffset>4</bitOffset>
              <bitWidth>1</bitWidth>
            </field>
            <field>
              <name>TCIF4</name>
              <bitOffset>5</bitOffset>
              <bitWidth>1</bitWidth>
            </field>
            <field>
              <name>FEIF5</name>
              <bitOffset>6</bitOffset>
              <bitWidth>1</bitWidth>
            </field>
            <field>
              <name>DMEIF5</name>
              <bitOffset>8</bitOffset>
              <bitWidth>1</bitWidth>
            </field>
            <field>
              <name>TEIF5</name>
              <bitOffset>9</bitOffset>
              <bitWidth>1</bitWidth>
            </field>
            <field>
              <name>HTIF5</name>
              <bitOffset>10</bitOffset>
              <bitWidth>1</bitWidth>
            </field>
            <field>
              <name>TCIF5</name>
              <bitOffset>11</bitOffset>
              <bitWidth>1</bitWidth>
            </field>
            <field>
              <name>FEIF6</name>
              <bitOffset>16</bitOffset>
              <bitWidth>1</bitWidth>
            </field>
            <field>
              <name>DMEIF6</name>
              <bitOffset>18</bitOffset>
              <bitWidth>1</bitWidth>
            </field>
            <field>
              <name>TEIF6</name>
              <bitOffset>19</bitOffset>
              <bitWidth>1</bitWidth>
            </field>
            <field>
              <name>HTIF6</name>
              <bitOffset>20</bitOffset>
              <bitWidth>1</bitWidth>
            </field>
            <field>
              <name>TCIF6</name>
              <bitOffset>21</bitOffset>
              <bitWidth>1</bitWidth>
            </field>
            <field>
              <name>FEIF7</name>
              <bitOffset>22</bitOffset>
              <bitWidth>1</bitWidth>
            </field>
            <field>
              <name>DMEIF7</name>
              <bitOffset>24</bitOffset>
              <bitWidth>1</bitWidth>
            </field>
            <field>
              <name>TEIF7</name>
              <bitOffset>25</bitOffset>
              <bitWidth>1</bitWidth>
            </field>
            <field>
              <name>HTIF7</name>
              <bitOffset>26</bitOffset>
              <bitWidth>1</bitWidth>
            </field>
            <field>
              <name>TCIF7</name>
              <bitOffset>27</bitOffset>
              <bitWidth>1</bitWidth>
            </field>
          </fields>
        </register>
        <register>
          <name>LIFCR</name>
          <addressOffset>0x8</addressOffset>
          <size>0x20</size>
          <fields>
            <field>
              <name>CFEIF0</name>
              <bitOffset>0</bitOffset>
              <bitWidth>1</bitWidth>
            </field>
            <field>
              <name>CDMEIF0</name>
              <bitOffset>2</bitOffset>
              <bitWidth>1</bitWidth>
            </field>
            <field>
              <name>CTEIF0</name>
              <bitOffset>3</bitOffset>
              <bitWidth>1</bitWidth>
            </field>
            <field>
              <name>CHTIF0</name>
              <bitOffset>4</bitOffset>
              <bitWidth>1</bitWidth>
            </field>
            <field>
              <name>CTCIF0</name>
              <bitOffset>5</bitOffset>
              <bitWidth>1</bitWidth>
            </field>
            <field>
              <name>CFEIF1</name>
              <bitOffset>6</bitOffset>
              <bitWidth>1</bitWidth>
            </field>
            <field>
              <name>CDMEIF1</name>
              <bitOffset>8</bitOffset>
              <bitWidth>1</bitWidth>
            </field>
            <field>
              <name>CTEIF1</name>
              <bitOffset>9</bitOffset>
              <bitWidth>1</bitWidth>
            </field>
            <field>
              <name>CHTIF1</name>
              <bitOffset>10</bitOffset>
              <bitWidth>1</bitWidth>
            </field>
            <field>
              <name>CTCIF1</name>
              <bitOffset>11</bitOffset>
              <bitWidth>1</bitWidth>
            </field>
            <field>
              <name>CFEIF2</name>
              <bitOffset>16</bitOffset>
              <bitWidth>1</bitWidth>
            </field>
            <field>
              <name>CDMEIF2</name>
              <bitOffset>18</bitOffset>
              <bitWidth>1</bitWidth>
            </field>
            <field>
              <name>CTEIF2</name>
              <bitOffset>19</bitOffset>
              <bitWidth>1</bitWidth>
            </field>
            <field>
              <name>CHTIF2</name>
              <bitOffset>20</bitOffset>
              <bitWidth>1</bitWidth>
            </field>
            <field>
              <name>CTCIF2</name>
              <bitOffset>21</bitOffset>
              <bitWidth>1</bitWidth>
            </field>
            <field>
              <name>CFEIF3</name>
              <bitOffset>22</bitOffset>
              <bitWidth>1</bitWidth>
            </field>
            <field>
              <name>CDMEIF3</name>
              <bitOffset>24</bitOffset>
              <bitWidth>1</bitWidth>
            </field>
            <field>
              <name>CTEIF3</name>
              <bitOffset>25</bitOffset>
              <bitWidth>1</bitWidth>
            </field>
            <field>
              <name>CHTIF3</name>
              <bitOffset>26</bitOffset>
              <bitWidth>1</bitWidth>
            </field>
            <field>
              <name>CTCIF3</name>
              <bitOffset>27</bitOffset>
              <bitWidth>1</bitWidth>
            </field>
          </fields>
        </register>
        <register>
          <name>HIFCR</name>
          <addressOffset>0xc</addressOffset>
          <size>0x20</size>
          <fields>
            <field>
              <name>CFEIF4</name>
              <bitOffset>0</bitOffset>
              <bitWidth>1</bitWidth>
            </field>
            <field>
              <name>CDMEIF4</name>
              <bitOffset>2</bitOffset>
              <bitWidth>1</bitWidth>
            </field>
            <field>
              <name>CTEIF4</name>
              <bitOffset>3</bitOffset>
              <bitWidth>1</bitWidth>
            </field>
            <field>
              <name>CHTIF4</name>
              <bitOffset>4</bitOffset>
              <bitWidth>1</bitWidth>
            </field>
            <field>
              <name>CTCIF4</name>
              <bitOffset>5</bitOffset>
              <bitWidth>1</bitWidth>
            </field>
            <field>
              <name>CFEIF5</name>
              <bitOffset>6</bitOffset>
              <bitWidth>1</bitWidth>
            </field>
            <field>
              <name>CDMEIF5</name>
              <bitOffset>8</bitOffset>
              <bitWidth>1</bitWidth>
            </field>
            <field>
              <name>CTEIF5</name>
              <bitOffset>9</bitOffset>
              <bitWidth>1</bitWidth>
            </field>
            <field>
              <name>CHTIF5</name>
              <bitOffset>10</bitOffset>
              <bitWidth>1</bitWidth>
            </field>
            <field>
              <name>CTCIF5</name>
              <bitOffset>11</bitOffset>
              <bitWidth>1</bitWidth>
            </field>
            <field>
              <name>CFEIF6</name>
              <bitOffset>16</bitOffset>
              <bitWidth>1</bitWidth>
            </field>
            <field>
              <name>CDMEIF6</name>
              <bitOffset>18</bitOffset>
              <bitWidth>1</bitWidth>
            </field>
            <field>
              <name>CTEIF6</name>
              <bitOffset>19</bitOffset>
              <bitWidth>1</bitWidth>
            </field>
            <field>
              <name>CHTIF6</name>
              <bitOffset>20</bitOffset>
              <bitWidth>1</bitWidth>
            </field>
            <field>
              <name>CTCIF6</name>
              <bitOffset>21</bitOffset>
              <bitWidth>1</bitWidth>
            </field>
            <field>
              <name>CFEIF7</name>
              <bitOffset>22</bitOffset>
              <bitWidth>1</bitWidth>
            </field>
            <field>
              <name>CDMEIF7</name>
              <bitOffset>24</bitOffset>
              <bitWidth>1</bitWidth>
            </field>
            <field>
              <name>CTEIF7</name>
              <bitOffset>25</bitOffset>
              <bitWidth>1</bitWidth>
            </field>
            <field>
              <name>CHTIF7</name>
              <bitOffset>26</bitOffset>
              <bitWidth>1</bitWidth>
            </field>
            <field>
              <name>CTCIF7</name>
              <bitOffset>27</bitOffset>
              <bitWidth>1</bitWidth>
            </field>
          </fields>
        </register>
        <register>
          <name>CR0</name>
          <addressOffset>0x10</addressOffset>
          <size>0x20</size>
        </register>
        <register>
          <name>CR0</name>
          <addressOffset>0x10</addressOffset>
          <size>0x20</size>
        </register>
        <register>
          <name>NDTR0</name>
          <addressOffset>0x14</addressOffset>
          <size>0x20</size>
        </register>
        <register>
          <name>NDTR0</name>
          <addressOffset>0x14</addressOffset>
          <size>0x20</size>
        </register>
        <register>
          <name>PAR0</name>
          <addressOffset>0x18</addressOffset>
          <size>0x20</size>
        </register>
        <register>
          <name>PAR0</name>
          <addressOffset>0x18</addressOffset>
          <size>0x20</size>
        </register>
        <register>
          <name>M0AR0</name>
          <addressOffset>0x1c</addressOffset>
          <size>0x20</size>
        </register>
        <register>
          <name>M0AR0</name>
          <addressOffset>0x1c</addressOffset>
          <size>0x20</size>
        </register>
        <register>
          <name>M1AR0</name>
          <addressOffset>0x20</addressOffset>
          <size>0x20</size>
        </register>
        <register>
          <name>M1AR0</name>
          <addressOffset>0x20</addressOffset>
          <size>0x20</size>
        </register>
        <register>
          <name>FCR0</name>
          <addressOffset>0x24</addressOffset>
          <size>0x20</size>
        </register>
        <register>
          <name>FCR0</name>
          <addressOffset>0x24</addressOffset>
          <size>0x20</size>
        </register>
        <register>
          <name>CR1</name>
          <addressOffset>0x28</addressOffset>
          <size>0x20</size>
        </register>
        <register>
          <name>CR1</name>
          <addressOffset>0x28</addressOffset>
          <size>0x20</size>
        </register>
        <register>
          <name>NDTR1</name>
          <addressOffset>0x2c</addressOffset>
          <size>0x20</size>
        </register>
        <register>
          <name>NDTR1</name>
          <addressOffset>0x2c</addressOffset>
          <size>0x20</size>
        </register>
        <register>
          <name>PAR1</name>
          <addressOffset>0x30</addressOffset>
          <size>0x20</size>
        </register>
        <register>
          <name>PAR1</name>
          <addressOffset>0x30</addressOffset>
          <size>0x20</size>
        </register>
        <register>
          <name>M0AR1</name>
          <addressOffset>0x34</addressOffset>
          <size>0x20</size>
        </register>
        <register>
          <name>M0AR1</name>
          <addressOffset>0x34</addressOffset>
          <size>0x20</size>
        </register>
        <register>
          <name>M1AR1</name>
          <addressOffset>0x38</addressOffset>
          <size>0x20</size>
        </register>
        <register>
          <name>M1AR1</name>
          <addressOffset>0x38</addressOffset>
          <size>0x20</size>
        </register>
        <register>
          <name>FCR1</name>
          <addressOffset>0x3c</addressOffset>
          <size>0x20</size>
        </register>
        <register>
          <name>FCR1</name>
          <addressOffset>0x3c</addressOffset>
          <size>0x20</size>
        </register>
        <register>
          <name>CR2</name>
          <addressOffset>0x40</addressOffset>
          <size>0x20</size>
        </register>
        <register>
          <name>CR2</name>
          <addressOffset>0x40</addressOffset>
          <size>0x20</size>
        </register>
        <register>
          <name>NDTR2</name>
          <addressOffset>0x44</addressOffset>
          <size>0x20</size>
        </register>
        <register>
          <name>NDTR2</name>
          <addressOffset>0x44</addressOffset>
          <size>0x20</size>
        </register>
        <register>
          <name>PAR2</name>
          <addressOffset>0x48</addressOffset>
          <size>0x20</size>
        </register>
        <register>
          <name>PAR2</name>
          <addressOffset>0x48</addressOffset>
          <size>0x20</size>
        </register>
        <register>
          <name>M0AR2</name>
          <addressOffset>0x4c</addressOffset>
          <size>0x20</size>
        </register>
        <register>
          <name>M0AR2</name>
          <addressOffset>0x4c</addressOffset>
          <size>0x20</size>
        </register>
        <register>
          <name>M1AR2</name>
          <addressOffset>0x50</addressOffset>
          <size>0x20</size>
        </register>
        <register>
          <name>M1AR2</name>
          <addressOffset>0x50</addressOffset>
          <size>0x20</size>
        </register>
        <register>
          <name>FCR2</name>
          <addressOffset>0x54</addressOffset>
          <size>0x20</size>
        </register>
        <register>
          <name>FCR2</name>
          <addressOffset>0x54</addressOffset>
          <size>0x20</size>
        </register>
        <register>
          <name>CR3</name>
          <addressOffset>0x58</addressOffset>
          <size>0x20</size>
        </register>
        <register>
          <name>CR3</name>
          <addressOffset>0x58</addressOffset>
          <size>0x20</size>
        </register>
        <register>
          <name>NDTR3</name>
          <addressOffset>0x5c</addressOffset>
          <size>0x20</size>
        </register>
        <register>
          <name>NDTR3</name>
          <addressOffset>0x5c</addressOffset>
          <size>0x20</size>
        </register>
        <register>
          <name>PAR3</name>
          <addressOffset>0x60</addressOffset>
          <size>0x20</size>
        </register>
        <register>
          <name>PAR3</name>
          <addressOffset>0x60</addressOffset>
          <size>0x20</size>
        </register>
        <register>
          <name>M0AR3</name>
          <addressOffset>0x64</addressOffset>
          <size>0x20</size>
        </register>
        <register>
          <name>M0AR3</name>
          <addressOffset>0x64</addressOffset>
          <size>0x20</size>
        </register>
        <register>
          <name>M1AR3</name>
          <addressOffset>0x68</addressOffset>
          <size>0x20</size>
        </register>
        <register>
          <name>M1AR3</name>
          <addressOffset>0x68</addressOffset>
          <size>0x20</size>
        </register>
        <register>
          <name>FCR3</name>
          <addressOffset>0x6c</addressOffset>
          <size>0x20</size>
        </register>
        <register>
          <name>FCR3</name>
          <addressOffset>0x6c</addressOffset>
          <size>0x20</size>
        </register>
        <register>
          <name>CR4</name>
          <addressOffset>0x70</addressOffset>
          <size>0x20</size>
        </register>
        <register>
          <name>CR4</name>
          <addressOffset>0x70</addressOffset>
          <size>0x20</size>
        </register>
        <register>
          <name>NDTR4</name>
          <addressOffset>0x74</addressOffset>
          <size>0x20</size>
        </register>
        <register>
          <name>NDTR4</name>
          <addressOffset>0x74</addressOffset>
          <size>0x20</size>
        </register>
        <register>
          <name>PAR4</name>
          <addressOffset>0x78</addressOffset>
          <size>0x20</size>
        </register>
        <register>
          <name>PAR4</name>
          <addressOffset>0x78</addressOffset>
          <size>0x20</size>
        </register>
        <register>
          <name>M0AR4</name>
          <addressOffset>0x7c</addressOffset>
          <size>0x20</size>
        </register>
        <register>
          <name>M0AR4</name>
          <addressOffset>0x7c</addressOffset>
          <size>0x20</size>
        </register>
        <register>
          <name>M1AR4</name>
          <addressOffset>0x80</addressOffset>
          <size>0x20</size>
        </register>
        <register>
          <name>M1AR4</name>
          <addressOffset>0x80</addressOffset>
          <size>0x20</size>
        </register>
        <register>
          <name>FCR4</name>
          <addressOffset>0x84</addressOffset>
          <size>0x20</size>
        </register>
        <register>
          <name>FCR4</name>
          <addressOffset>0x84</addressOffset>
          <size>0x20</size>
        </register>
        <register>
          <name>CR5</name>
          <addressOffset>0x88</addressOffset>
          <size>0x20</size>
        </register>
        <register>
          <name>CR5</name>
          <addressOffset>0x88</addressOffset>
          <size>0x20</size>
        </register>
        <register>
          <name>NDTR5</name>
          <addressOffset>0x8c</addressOffset>
          <size>0x20</size>
        </register>
        <register>
          <name>NDTR5</name>
          <addressOffset>0x8c</addressOffset>
          <size>0x20</size>
        </register>
        <register>
          <name>PAR5</name>
          <addressOffset>0x90</addressOffset>
          <size>0x20</size>
        </register>
        <register>
          <name>PAR5</name>
          <addressOffset>0x90</addressOffset>
          <size>0x20</size>
        </register>
        <register>
          <name>M0AR5</name>
          <addressOffset>0x94</addressOffset>
          <size>0x20</size>
        </register>
        <register>
          <name>M0AR5</name>
          <addressOffset>0x94</addressOffset>
          <size>0x20</size>
        </register>
        <register>
          <name>M1AR5</name>
          <addressOffset>0x98</addressOffset>
          <size>0x20</size>
        </register>
        <register>
          <name>M1AR5</name>
          <addressOffset>0x98</addressOffset>
          <size>0x20</size>
        </register>
        <register>
          <name>FCR5</name>
          <addressOffset>0x9c</addressOffset>
          <size>0x20</size>
        </register>
        <register>
          <name>FCR5</name>
          <addressOffset>0x9c</addressOffset>
          <size>0x20</size>
        </register>
        <register>
          <name>CR6</name>
          <addressOffset>0xa0</addressOffset>
          <size>0x20</size>
        </register>
        <register>
          <name>CR6</name>
          <addressOffset>0xa0</addressOffset>
          <size>0x20</size>
        </register>
        <register>
          <name>NDTR6</name>
          <addressOffset>0xa4</addressOffset>
          <size>0x20</size>
        </register>
        <register>
          <name>NDTR6</name>
          <addressOffset>0xa4</addressOffset>
          <size>0x20</size>
        </register>
        <register>
          <name>PAR6</name>
          <addressOffset>0xa8</addressOffset>
          <size>0x20</size>
        </register>
        <register>
          <name>PAR6</name>
          <addressOffset>0xa8</addressOffset>
          <size>0x20</size>
        </register>
        <register>
          <name>M0AR6</name>
          <addressOffset>0xac</addressOffset>
          <size>0x20</size>
        </register>
        <register>
          <name>M0AR6</name>
          <addressOffset>0xac</addressOffset>
          <size>0x20</size>
        </register>
        <register>
          <name>M1AR6</name>
          <addressOffset>0xb0</addressOffset>
          <size>0x20</size>
        </register>
        <register>
          <name>M1AR6</name>
          <addressOffset>0xb0</addressOffset>
          <size>0x20</size>
        </register>
        <register>
          <name>FCR6</name>
          <addressOffset>0xb4</addressOffset>
          <size>0x20</size>
        </register>
        <register>
          <name>FCR6</name>
          <addressOffset>0xb4</addressOffset>
          <size>0x20</size>
        </register>
        <register>
          <name>CR7</name>
          <addressOffset>0xb8</addressOffset>
          <size>0x20</size>
        </register>
        <register>
          <name>CR7</name>
          <addressOffset>0xb8</addressOffset>
          <size>0x20</size>
        </register>
        <register>
          <name>NDTR7</name>
          <addressOffset>0xbc</addressOffset>
          <size>0x20</size>
        </register>
        <register>
          <name>NDTR7</name>
          <addressOffset>0xbc</addressOffset>
          <size>0x20</size>
        </register>
        <register>
          <name>PAR7</name>
          <addressOffset>0xc0</addressOffset>
          <size>0x20</size>
        </register>
        <register>
          <name>PAR7</name>
          <addressOffset>0xc0</addressOffset>
          <size>0x20</size>
        </register>
        <register>
          <name>M0AR7</name>
          <addressOffset>0xc4</addressOffset>
          <size>0x20</size>
        </register>
        <register>
          <name>M0AR7</name>
          <addressOffset>0xc4</addressOffset>
          <size>0x20</size>
        </register>
        <register>
          <name>M1AR7</name>
          <addressOffset>0xc8</addressOffset>
          <size>0x20</size>
        </register>
        <register>
          <name>M1AR7</name>
          <addressOffset>0xc8</addressOffset>
          <size>0x20</size>
        </register>
        <register>
          <name>FCR7</name>
          <addressOffset>0xcc</addressOffset>
          <size>0x20</size>
        </register>
        <register>
          <name>FCR7</name>
          <addressOffset>0xcc</addressOffset>
          <size>0x20</size>
        </register>
      </registers>
    </peripheral>
    <peripheral>
      <name>DMAMUX1</name>
      <baseAddress>0x40020800</baseAddress>
      <registers>
        <register>
          <name>CCR0</name>
          <addressOffset>0x0</addressOffset>
          <size>0x20</size>
        </register>
        <register>
          <name>CCR0</name>
          <addressOffset>0x0</addressOffset>
          <size>0x20</size>
        </register>
        <register>
          <name>CCR1</name>
          <addressOffset>0x4</addressOffset>
          <size>0x20</size>
        </register>
        <register>
          <name>CCR1</name>
          <addressOffset>0x4</addressOffset>
          <size>0x20</size>
        </register>
        <register>
          <name>CCR2</name>
          <addressOffset>0x8</addressOffset>
          <size>0x20</size>
        </register>
        <register>
          <name>CCR2</name>
          <addressOffset>0x8</addressOffset>
          <size>0x20</size>
        </register>
        <register>
          <name>CCR3</name>
          <addressOffset>0xc</addressOffset>
          <size>0x20</size>
        </register>
        <register>
          <name>CCR3</name>
          <addressOffset>0xc</addressOffset>
          <size>0x20</size>
        </register>
        <register>
          <name>CCR4</name>
          <addressOffset>0x10</addressOffset>
          <size>0x20</size>
        </register>
        <register>
          <name>CCR4</name>
          <addressOffset>0x10</addressOffset>
          <size>0x20</size>
        </register>
        <register>
          <name>CCR5</name>
          <addressOffset>0x14</addressOffset>
          <size>0x20</size>
        </register>
        <register>
          <name>CCR5</name>
          <addressOffset>0x14</addressOffset>
          <size>0x20</size>
        </register>
        <register>
          <name>CCR6</name>
          <addressOffset>0x18</addressOffset>
          <size>0x20</size>
        </register>
        <register>
          <name>CCR6</name>
          <addressOffset>0x18</addressOffset>
          <size>0x20</size>
        </register>
        <register>
          <name>CCR7</name>
          <addressOffset>0x1c</addressOffset>
          <size>0x20</size>
        </register>
        <register>
          <name>CCR7</name>
          <addressOffset>0x1c</addressOffset>
          <size>0x20</size>
        </register>
        <register>
          <name>CCR8</name>
          <addressOffset>0x20</addressOffset>
          <size>0x20</size>
        </register>
        <register>
          <name>CCR9</name>
          <addressOffset>0x24</addressOffset>
          <size>0x20</size>
        </register>
        <register>
          <name>CCR0</name>
          <addressOffset>0x28</addressOffset>
          <size>0x20</size>
        </register>
        <register>
          <name>CCR1</name>
          <addressOffset>0x2c</addressOffset>
          <size>0x20</size>
        </register>
        <register>
          <name>CCR2</name>
          <addressOffset>0x30</addressOffset>
          <size>0x20</size>
        </register>
        <register>
          <name>CCR3</name>
          <addressOffset>0x34</addressOffset>
          <size>0x20</size>
        </register>
        <register>
          <name>CCR4</name>
          <addressOffset>0x38</addressOffset>
          <size>0x20</size>
        </register>
        <register>
          <name>CCR5</name>
          <addressOffset>0x3c</addressOffset>
          <size>0x20</size>
        </register>
        <register>
          <name>CCRs</name>
          <addressOffset>0x80</addressOffset>
          <size>0x20</size>
        </register>
        <register>
          <name>CCRs</name>
          <addressOffset>0x80</addressOffset>
          <size>0x20</size>
        </register>
        <register>
          <name>CCR0</name>
          <addressOffset>0x100</addressOffset>
          <size>0x20</size>
        </register>
        <register>
          <name>CCR0</name>
          <addressOffset>0x100</addressOffset>
          <size>0x20</size>
        </register>
        <register>
          <name>CCR1</name>
          <addressOffset>0x104</addressOffset>
          <size>0x20</size>
        </register>
        <register>
          <name>CCR1</name>
          <addressOffset>0x104</addressOffset>
          <size>0x20</size>
        </register>
        <register>
          <name>CCR2</name>
          <addressOffset>0x108</addressOffset>
          <size>0x20</size>
        </register>
        <register>
          <name>CCR2</name>
          <addressOffset>0x108</addressOffset>
          <size>0x20</size>
        </register>
        <register>
          <name>CCR3</name>
          <addressOffset>0x10c</addressOffset>
          <size>0x20</size>
        </register>
        <register>
          <name>CCR3</name>
          <addressOffset>0x10c</addressOffset>
          <size>0x20</size>
        </register>
        <register>
          <name>CCR4</name>
          <addressOffset>0x110</addressOffset>
          <size>0x20</size>
        </register>
        <register>
          <name>CCR4</name>
          <addressOffset>0x110</addressOffset>
          <size>0x20</size>
        </register>
        <register>
          <name>CCR5</name>
          <addressOffset>0x114</addressOffset>
          <size>0x20</size>
        </register>
        <register>
          <name>CCR5</name>
          <addressOffset>0x114</addressOffset>
          <size>0x20</size>
        </register>
        <register>
          <name>CCR6</name>
          <addressOffset>0x118</addressOffset>
          <size>0x20</size>
        </register>
        <register>
          <name>CCR6</name>
          <addressOffset>0x118</addressOffset>
          <size>0x20</size>
        </register>
        <register>
          <name>CCR7</name>
          <addressOffset>0x11c</addressOffset>
          <size>0x20</size>
        </register>
        <register>
          <name>CCR7</name>
          <addressOffset>0x11c</addressOffset>
          <size>0x20</size>
        </register>
        <register>
          <name>CCRs</name>
          <addressOffset>0x140</addressOffset>
          <size>0x20</size>
        </register>
        <register>
          <name>CCRs</name>
          <addressOffset>0x140</addressOffset>
          <size>0x20</size>
        </register>
      </registers>
    </peripheral>
    <peripheral>
      <name>ADC1</name>
      <baseAddress>0x40022000</baseAddress>
      <registers>
        <register>
          <name>ISR</name>
          <addressOffset>0x0</addressOffset>
          <size>0x20</size>
          <fields>
            <field>
              <name>ADRDY</name>
              <bitOffset>0</bitOffset>
              <bitWidth>1</bitWidth>
            </field>
            <field>
              <name>EOSMP</name>
              <bitOffset>1</bitOffset>
              <bitWidth>1</bitWidth>
            </field>
            <field>
              <name>EOC</name>
              <bitOffset>2</bitOffset>
              <bitWidth>1</bitWidth>
            </field>
            <field>
              <name>EOS</name>
              <bitOffset>3</bitOffset>
              <bitWidth>1</bitWidth>
            </field>
            <field>
              <name>OVR</name>
              <bitOffset>4</bitOffset>
              <bitWidth>1</bitWidth>
            </field>
            <field>
              <name>JEOC</name>
              <bitOffset>5</bitOffset>
              <bitWidth>1</bitWidth>
            </field>
            <field>
              <name>JEOS</name>
              <bitOffset>6</bitOffset>
              <bitWidth>1</bitWidth>
            </field>
            <field>
              <name>AWD1</name>
              <bitOffset>7</bitOffset>
              <bitWidth>1</bitWidth>
            </field>
            <field>
              <name>AWD2</name>
              <bitOffset>8</bitOffset>
              <bitWidth>1</bitWidth>
            </field>
            <field>
              <name>AWD3</name>
              <bitOffset>9</bitOffset>
              <bitWidth>1</bitWidth>
            </field>
            <field>
              <name>JQOVF</name>
              <bitOffset>10</bitOffset>
              <bitWidth>1</bitWidth>
            </field>
            <field>
              <name>LDORDY</name>
              <bitOffset>12</bitOffset>
              <bitWidth>1</bitWidth>
            </field>
          </fields>
        </register>
        <register>
          <name>IER</name>
          <addressOffset>0x4</addressOffset>
          <size>0x20</size>
          <fields>
            <field>
              <name>ADRDYIE</name>
              <bitOffset>0</bitOffset>
              <bitWidth>1</bitWidth>
            </field>
            <field>
              <name>EOSMPIE</name>
              <bitOffset>1</bitOffset>
              <bitWidth>1</bitWidth>
            </field>
            <field>
              <name>EOCIE</name>
              <bitOffset>2</bitOffset>
              <bitWidth>1</bitWidth>
            </field>
            <field>
              <name>EOSIE</name>
              <bitOffset>3</bitOffset>
              <bitWidth>1</bitWidth>
            </field>
            <field>
              <name>OVRIE</name>
              <bitOffset>4</bitOffset>
              <bitWidth>1</bitWidth>
            </field>
            <field>
              <name>JEOCIE</name>
              <bitOffset>5</bitOffset>
              <bitWidth>1</bitWidth>
            </field>
            <field>
              <name>JEOSIE</name>
              <bitOffset>6</bitOffset>
              <bitWidth>1</bitWidth>
            </field>
            <field>
              <name>AWD1IE</name>
              <bitOffset>7</bitOffset>
              <bitWidth>1</bitWidth>
            </field>
            <field>
              <name>AWD2IE</name>
              <bitOffset>8</bitOffset>
              <bitWidth>1</bitWidth>
            </field>
            <field>
              <name>AWD3IE</name>
              <bitOffset>9</bitOffset>
              <bitWidth>1</bitWidth>
            </field>
            <field>
              <name>JQOVFIE</name>
              <bitOffset>10</bitOffset>
              <bitWidth>1</bitWidth>
            </field>
          </fields>
        </register>
        <register>
          <name>CR</name>
          <addressOffset>0x8</addressOffset>
          <size>0x20</size>
          <fields>
            <field>
              <name>ADEN</name>
              <bitOffset>0</bitOffset>
              <bitWidth>1</bitWidth>
            </field>
            <field>
              <name>ADDIS</name>
              <bitOffset>1</bitOffset>
              <bitWidth>1</bitWidth>
            </field>
            <field>
              <name>ADSTART</name>
              <bitOffset>2</bitOffset>
              <bitWidth>1</bitWidth>
            </field>
            <field>
              <name>JADSTART</name>
              <bitOffset>3</bitOffset>
              <bitWidth>1</bitWidth>
            </field>
            <field>
              <name>ADSTP</name>
              <bitOffset>4</bitOffset>
              <bitWidth>1</bitWidth>
            </field>
            <field>
              <name>JADSTP</name>
              <bitOffset>5</bitOffset>
              <bitWidth>1</bitWidth>
            </field>
            <field>
              <name>BOOST</name>
              <bitOffset>8</bitOffset>
              <bitWidth>2</bitWidth>
            </field>
            <field>
              <name>ADCALLIN</name>
              <bitOffset>16</bitOffset>
              <bitWidth>1</bitWidth>
            </field>
            <field>
              <name>LINCALRDYW1</name>
              <bitOffset>22</bitOffset>
              <bitWidth>1</bitWidth>
            </field>
            <field>
              <name>LINCALRDYW2</name>
              <bitOffset>23</bitOffset>
              <bitWidth>1</bitWidth>
            </field>
            <field>
              <name>LINCALRDYW3</name>
              <bitOffset>24</bitOffset>
              <bitWidth>1</bitWidth>
            </field>
            <field>
              <name>LINCALRDYW4</name>
              <bitOffset>25</bitOffset>
              <bitWidth>1</bitWidth>
            </field>
            <field>
              <name>LINCALRDYW5</name>
              <bitOffset>26</bitOffset>
              <bitWidth>1</bitWidth>
            </field>
            <field>
              <name>LINCALRDYW6</name>
              <bitOffset>27</bitOffset>
              <bitWidth>1</bitWidth>
            </field>
            <field>
              <name>ADVREGEN</name>
              <bitOffset>28</bitOffset>
              <bitWidth>1</bitWidth>
            </field>
            <field>
              <name>DEEPPWD</name>
              <bitOffset>29</bitOffset>
              <bitWidth>1</bitWidth>
            </field>
            <field>
              <name>ADCALDIF</name>
              <bitOffset>30</bitOffset>
              <bitWidth>1</bitWidth>
            </field>
            <field>
              <name>ADCAL</name>
              <bitOffset>31</bitOffset>
              <bitWidth>1</bitWidth>
            </field>
          </fields>
        </register>
        <register>
          <name>CFGR</name>
          <addressOffset>0xc</addressOffset>
          <size>0x20</size>
          <fields>
            <field>
              <name>DMNGT</name>
              <bitOffset>0</bitOffset>
              <bitWidth>2</bitWidth>
            </field>
            <field>
              <name>RES</name>
              <bitOffset>2</bitOffset>
              <bitWidth>3</bitWidth>
            </field>
            <field>
              <name>EXTSEL</name>
              <bitOffset>5</bitOffset>
              <bitWidth>5</bitWidth>
            </field>
            <field>
              <name>EXTEN</name>
              <bitOffset>10</bitOffset>
              <bitWidth>2</bitWidth>
            </field>
            <field>
              <name>OVRMOD</name>
              <bitOffset>12</bitOffset>
              <bitWidth>1</bitWidth>
            </field>
            <field>
              <name>CONT</name>
              <bitOffset>13</bitOffset>
              <bitWidth>1</bitWidth>
            </field>
            <field>
              <name>AUTDLY</name>
              <bitOffset>14</bitOffset>
              <bitWidth>1</bitWidth>
            </field>
            <field>
              <name>DISCEN</name>
              <bitOffset>16</bitOffset>
              <bitWidth>1</bitWidth>
            </field>
            <field>
              <name>DISCNUM</name>
              <bitOffset>17</bitOffset>
              <bitWidth>3</bitWidth>
            </field>
            <field>
              <name>JDISCEN</name>
              <bitOffset>20</bitOffset>
              <bitWidth>1</bitWidth>
            </field>
            <field>
              <name>JQM</name>
              <bitOffset>21</bitOffset>
              <bitWidth>1</bitWidth>
            </field>
            <field>
              <name>AWD1SGL</name>
              <bitOffset>22</bitOffset>
              <bitWidth>1</bitWidth>
            </field>
            <field>
              <name>AWD1EN</name>
              <bitOffset>23</bitOffset>
              <bitWidth>1</bitWidth>
            </field>
            <field>
              <name>JAWD1EN</name>
              <bitOffset>24</bitOffset>
              <bitWidth>1</bitWidth>
            </field>
            <field>
              <name>JAUTO</name>
              <bitOffset>25</bitOffset>
              <bitWidth>1</bitWidth>
            </field>
            <field>
              <name>AWD1CH</name>
              <bitOffset>26</bitOffset>
              <bitWidth>5</bitWidth>
            </field>
            <field>
              <name>JQDIS</name>
              <bitOffset>31</bitOffset>
              <bitWidth>1</bitWidth>
            </field>
          </fields>
        </register>
        <register>
          <name>CFGR2</name>
          <addressOffset>0x10</addressOffset>
          <size>0x20</size>
          <fields>
            <field>
              <name>ROVSE</name>
              <bitOffset>0</bitOffset>
              <bitWidth>1</bitWidth>
            </field>
            <field>
              <name>JOVSE</name>
              <bitOffset>1</bitOffset>
              <bitWidth>1</bitWidth>
            </field>
            <field>
              <name>OVSS</name>
              <bitOffset>5</bitOffset>
              <bitWidth>4</bitWidth>
            </field>
            <field>
              <name>TROVS</name>
              <bitOffset>9</bitOffset>
              <bitWidth>1</bitWidth>
            </field>
            <field>
              <name>ROVSM</name>
              <bitOffset>10</bitOffset>
              <bitWidth>1</bitWidth>
            </field>
            <field>
              <name>RSHIFT1</name>
              <bitOffset>11</bitOffset>
              <bitWidth>1</bitWidth>
            </field>
            <field>
              <name>RSHIFT2</name>
              <bitOffset>12</bitOffset>
              <bitWidth>1</bitWidth>
            </field>
            <field>
              <name>RSHIFT3</name>
              <bitOffset>13</bitOffset>
              <bitWidth>1</bitWidth>
            </field>
            <field>
              <name>RSHIFT4</name>
              <bitOffset>14</bitOffset>
              <bitWidth>1</bitWidth>
            </field>
            <field>
              <name>OVSR</name>
              <bitOffset>16</bitOffset>
              <bitWidth>10</bitWidth>
            </field>
            <field>
              <name>LSHIFT</name>
              <bitOffset>28</bitOffset>
              <bitWidth>4</bitWidth>
            </field>
          </fields>
        </register>
        <register>
          <name>SMPR1</name>
          <addressOffset>0x14</addressOffset>
          <size>0x20</size>
          <fields>
            <field>
              <name>SMP0</name>
              <bitOffset>0</bitOffset>
              <bitWidth>3</bitWidth>
            </field>
            <field>
              <name>SMP1</name>
              <bitOffset>3</bitOffset>
              <bitWidth>3</bitWidth>
            </field>
            <field>
              <name>SMP2</name>
              <bitOffset>6</bitOffset>
              <bitWidth>3</bitWidth>
            </field>
            <field>
              <name>SMP3</name>
              <bitOffset>9</bitOffset>
              <bitWidth>3</bitWidth>
            </field>
            <field>
              <name>SMP4</name>
              <bitOffset>12</bitOffset>
              <bitWidth>3</bitWidth>
            </field>
            <field>
              <name>SMP5</name>
              <bitOffset>15</bitOffset>
              <bitWidth>3</bitWidth>
            </field>
            <field>
              <name>SMP6</name>
              <bitOffset>18</bitOffset>
              <bitWidth>3</bitWidth>
            </field>
            <field>
              <name>SMP7</name>
              <bitOffset>21</bitOffset>
              <bitWidth>3</bitWidth>
            </field>
            <field>
              <name>SMP8</name>
              <bitOffset>24</bitOffset>
              <bitWidth>3</bitWidth>
            </field>
            <field>
              <name>SMP9</name>
              <bitOffset>27</bitOffset>
              <bitWidth>3</bitWidth>
            </field>
          </fields>
        </register>
        <register>
          <name>SMPR2</name>
          <addressOffset>0x18</addressOffset>
          <size>0x20</size>
          <fields>
            <field>
              <name>SMP10</name>
              <bitOffset>0</bitOffset>
              <bitWidth>3</bitWidth>
            </field>
            <field>
              <name>SMP11</name>
              <bitOffset>3</bitOffset>
              <bitWidth>3</bitWidth>
            </field>
            <field>
              <name>SMP12</name>
              <bitOffset>6</bitOffset>
              <bitWidth>3</bitWidth>
            </field>
            <field>
              <name>SMP13</name>
              <bitOffset>9</bitOffset>
              <bitWidth>3</bitWidth>
            </field>
            <field>
              <name>SMP14</name>
              <bitOffset>12</bitOffset>
              <bitWidth>3</bitWidth>
            </field>
            <field>
              <name>SMP15</name>
              <bitOffset>15</bitOffset>
              <bitWidth>3</bitWidth>
            </field>
            <field>
              <name>SMP16</name>
              <bitOffset>18</bitOffset>
              <bitWidth>3</bitWidth>
            </field>
            <field>
              <name>SMP17</name>
              <bitOffset>21</bitOffset>
              <bitWidth>3</bitWidth>
            </field>
            <field>
              <name>SMP18</name>
              <bitOffset>24</bitOffset>
              <bitWidth>3</bitWidth>
            </field>
            <field>
              <name>SMP19</name>
              <bitOffset>27</bitOffset>
              <bitWidth>3</bitWidth>
            </field>
          </fields>
        </register>
        <register>
          <name>PCSEL_RES0</name>
          <addressOffset>0x1c</addressOffset>
          <size>0x20</size>
        </register>
        <register>
          <name>LTR1_TR1</name>
          <addressOffset>0x20</addressOffset>
          <size>0x20</size>
        </register>
        <register>
          <name>HTR1_TR2</name>
          <addressOffset>0x24</addressOffset>
          <size>0x20</size>
        </register>
        <register>
          <name>RES1_TR3</name>
          <addressOffset>0x28</addressOffset>
          <size>0x20</size>
        </register>
        <register>
          <name>SQR1</name>
          <addressOffset>0x30</addressOffset>
          <size>0x20</size>
          <fields>
            <field>
              <name>L</name>
              <bitOffset>0</bitOffset>
              <bitWidth>4</bitWidth>
            </field>
            <field>
              <name>SQ1</name>
              <bitOffset>6</bitOffset>
              <bitWidth>5</bitWidth>
            </field>
            <field>
              <name>SQ2</name>
              <bitOffset>12</bitOffset>
              <bitWidth>5</bitWidth>
            </field>
            <field>
              <name>SQ3</name>
              <bitOffset>18</bitOffset>
              <bitWidth>5</bitWidth>
            </field>
            <field>
              <name>SQ4</name>
              <bitOffset>24</bitOffset>
              <bitWidth>5</bitWidth>
            </field>
          </fields>
        </register>
        <register>
          <name>SQR2</name>
          <addressOffset>0x34</addressOffset>
          <size>0x20</size>
          <fields>
            <field>
              <name>SQ5</name>
              <bitOffset>0</bitOffset>
              <bitWidth>5</bitWidth>
            </field>
            <field>
              <name>SQ6</name>
              <bitOffset>6</bitOffset>
              <bitWidth>5</bitWidth>
            </field>
            <field>
              <name>SQ7</name>
              <bitOffset>12</bitOffset>
              <bitWidth>5</bitWidth>
            </field>
            <field>
              <name>SQ8</name>
              <bitOffset>18</bitOffset>
              <bitWidth>5</bitWidth>
            </field>
            <field>
              <name>SQ9</name>
              <bitOffset>24</bitOffset>
              <bitWidth>5</bitWidth>
            </field>
          </fields>
        </register>
        <register>
          <name>SQR3</name>
          <addressOffset>0x38</addressOffset>
          <size>0x20</size>
          <fields>
            <field>
              <name>SQ10</name>
              <bitOffset>0</bitOffset>
              <bitWidth>5</bitWidth>
            </field>
            <field>
              <name>SQ11</name>
              <bitOffset>6</bitOffset>
              <bitWidth>5</bitWidth>
            </field>
            <field>
              <name>SQ12</name>
              <bitOffset>12</bitOffset>
              <bitWidth>5</bitWidth>
            </field>
            <field>
              <name>SQ13</name>
              <bitOffset>18</bitOffset>
              <bitWidth>5</bitWidth>
            </field>
            <field>
              <name>SQ14</name>
              <bitOffset>24</bitOffset>
              <bitWidth>5</bitWidth>
            </field>
          </fields>
        </register>
        <register>
          <name>SQR4</name>
          <addressOffset>0x3c</addressOffset>
          <size>0x20</size>
          <fields>
            <field>
              <name>SQ15</name>
              <bitOffset>0</bitOffset>
              <bitWidth>5</bitWidth>
            </field>
            <field>
              <name>SQ16</name>
              <bitOffset>6</bitOffset>
              <bitWidth>5</bitWidth>
            </field>
          </fields>
        </register>
        <register>
          <name>DR</name>
          <addressOffset>0x40</addressOffset>
          <size>0x20</size>
          <fields>
            <field>
              <name>RDATA</name>
              <bitOffset>0</bitOffset>
              <bitWidth>32</bitWidth>
            </field>
          </fields>
        </register>
        <register>
          <name>JSQR</name>
          <addressOffset>0x4c</addressOffset>
          <size>0x20</size>
          <fields>
            <field>
              <name>JL</name>
              <bitOffset>0</bitOffset>
              <bitWidth>2</bitWidth>
            </field>
            <field>
              <name>JEXTSEL</name>
              <bitOffset>2</bitOffset>
              <bitWidth>5</bitWidth>
            </field>
            <field>
              <name>JEXTEN</name>
              <bitOffset>7</bitOffset>
              <bitWidth>2</bitWidth>
            </field>
            <field>
              <name>JSQ1</name>
              <bitOffset>9</bitOffset>
              <bitWidth>5</bitWidth>
            </field>
            <field>
              <name>JSQ2</name>
              <bitOffset>15</bitOffset>
              <bitWidth>5</bitWidth>
            </field>
            <field>
              <name>JSQ3</name>
              <bitOffset>21</bitOffset>
              <bitWidth>5</bitWidth>
            </field>
            <field>
              <name>JSQ4</name>
              <bitOffset>27</bitOffset>
              <bitWidth>5</bitWidth>
            </field>
          </fields>
        </register>
        <register>
          <name>OFR1</name>
          <addressOffset>0x60</addressOffset>
          <size>0x20</size>
          <fields>
            <field>
              <name>OFFSET1</name>
              <bitOffset>0</bitOffset>
              <bitWidth>26</bitWidth>
            </field>
            <field>
              <name>OFFSET1_CH</name>
              <bitOffset>26</bitOffset>
              <bitWidth>5</bitWidth>
            </field>
            <field>
              <name>SSATE</name>
              <bitOffset>31</bitOffset>
              <bitWidth>1</bitWidth>
            </field>
          </fields>
        </register>
        <register>
          <name>OFR2</name>
          <addressOffset>0x64</addressOffset>
          <size>0x20</size>
          <fields>
            <field>
              <name>OFFSET2</name>
              <bitOffset>0</bitOffset>
              <bitWidth>26</bitWidth>
            </field>
            <field>
              <name>OFFSET2_CH</name>
              <bitOffset>26</bitOffset>
              <bitWidth>5</bitWidth>
            </field>
            <field>
              <name>SSATE</name>
              <bitOffset>31</bitOffset>
              <bitWidth>1</bitWidth>
            </field>
          </fields>
        </register>
        <register>
          <name>OFR3</name>
          <addressOffset>0x68</addressOffset>
          <size>0x20</size>
          <fields>
            <field>
              <name>OFFSET3</name>
              <bitOffset>0</bitOffset>
              <bitWidth>26</bitWidth>
            </field>
            <field>
              <name>OFFSET3_CH</name>
              <bitOffset>26</bitOffset>
              <bitWidth>5</bitWidth>
            </field>
            <field>
              <name>SSATE</name>
              <bitOffset>31</bitOffset>
              <bitWidth>1</bitWidth>
            </field>
          </fields>
        </register>
        <register>
          <name>OFR4</name>
          <addressOffset>0x6c</addressOffset>
          <size>0x20</size>
          <fields>
            <field>
              <name>OFFSET4</name>
              <bitOffset>0</bitOffset>
              <bitWidth>26</bitWidth>
            </field>
            <field>
              <name>OFFSET4_CH</name>
              <bitOffset>26</bitOffset>
              <bitWidth>5</bitWidth>
            </field>
            <field>
              <name>SSATE</name>
              <bitOffset>31</bitOffset>
              <bitWidth>1</bitWidth>
            </field>
          </fields>
        </register>
        <register>
          <name>JDR1</name>
          <addressOffset>0x80</addressOffset>
          <size>0x20</size>
          <fields>
            <field>
              <name>JDATA</name>
              <bitOffset>0</bitOffset>
              <bitWidth>32</bitWidth>
            </field>
          </fields>
        </register>
        <register>
          <name>JDR2</name>
          <addressOffset>0x84</addressOffset>
          <size>0x20</size>
          <fields>
            <field>
              <name>JDATA</name>
              <bitOffset>0</bitOffset>
              <bitWidth>32</bitWidth>
            </field>
          </fields>
        </register>
        <register>
          <name>JDR3</name>
          <addressOffset>0x88</addressOffset>
          <size>0x20</size>
          <fields>
            <field>
              <name>JDATA</name>
              <bitOffset>0</bitOffset>
              <bitWidth>32</bitWidth>
            </field>
          </fields>
        </register>
        <register>
          <name>JDR4</name>
          <addressOffset>0x8c</addressOffset>
          <size>0x20</size>
          <fields>
            <field>
              <name>JDATA</name>
              <bitOffset>0</bitOffset>
              <bitWidth>32</bitWidth>
            </field>
          </fields>
        </register>
        <register>
          <name>AWD2CR</name>
          <addressOffset>0xa0</addressOffset>
          <size>0x20</size>
          <fields>
            <field>
              <name>AWD2CH</name>
              <bitOffset>0</bitOffset>
              <bitWidth>20</bitWidth>
            </field>
          </fields>
        </register>
        <register>
          <name>AWD3CR</name>
          <addressOffset>0xa4</addressOffset>
          <size>0x20</size>
          <fields>
            <field>
              <name>AWD3CH</name>
              <bitOffset>0</bitOffset>
              <bitWidth>20</bitWidth>
            </field>
          </fields>
        </register>
        <register>
          <name>LTR2_DIFSEL</name>
          <addressOffset>0xb0</addressOffset>
          <size>0x20</size>
        </register>
        <register>
          <name>HTR2_CALFACT</name>
          <addressOffset>0xb4</addressOffset>
          <size>0x20</size>
        </register>
        <register>
          <name>LTR3_RES10</name>
          <addressOffset>0xb8</addressOffset>
          <size>0x20</size>
        </register>
        <register>
          <name>HTR3_RES11</name>
          <addressOffset>0xbc</addressOffset>
          <size>0x20</size>
        </register>
        <register>
          <name>DIFSEL_RES12</name>
          <addressOffset>0xc0</addressOffset>
          <size>0x20</size>
        </register>
        <register>
          <name>CALFACT_RES13</name>
          <addressOffset>0xc4</addressOffset>
          <size>0x20</size>
        </register>
        <register>
          <name>CALFACT2_RES14</name>
          <addressOffset>0xc8</addressOffset>
          <size>0x20</size>
        </register>
      </registers>
    </peripheral>
    <peripheral>
      <name>ADC2</name>
      <baseAddress>0x40022100</baseAddress>
      <registers>
        <register>
          <name>ISR</name>
          <addressOffset>0x0</addressOffset>
          <size>0x20</size>
          <fields>
            <field>
              <name>ADRDY</name>
              <bitOffset>0</bitOffset>
              <bitWidth>1</bitWidth>
            </field>
            <field>
              <name>EOSMP</name>
              <bitOffset>1</bitOffset>
              <bitWidth>1</bitWidth>
            </field>
            <field>
              <name>EOC</name>
              <bitOffset>2</bitOffset>
              <bitWidth>1</bitWidth>
            </field>
            <field>
              <name>EOS</name>
              <bitOffset>3</bitOffset>
              <bitWidth>1</bitWidth>
            </field>
            <field>
              <name>OVR</name>
              <bitOffset>4</bitOffset>
              <bitWidth>1</bitWidth>
            </field>
            <field>
              <name>JEOC</name>
              <bitOffset>5</bitOffset>
              <bitWidth>1</bitWidth>
            </field>
            <field>
              <name>JEOS</name>
              <bitOffset>6</bitOffset>
              <bitWidth>1</bitWidth>
            </field>
            <field>
              <name>AWD1</name>
              <bitOffset>7</bitOffset>
              <bitWidth>1</bitWidth>
            </field>
            <field>
              <name>AWD2</name>
              <bitOffset>8</bitOffset>
              <bitWidth>1</bitWidth>
            </field>
            <field>
              <name>AWD3</name>
              <bitOffset>9</bitOffset>
              <bitWidth>1</bitWidth>
            </field>
            <field>
              <name>JQOVF</name>
              <bitOffset>10</bitOffset>
              <bitWidth>1</bitWidth>
            </field>
            <field>
              <name>LDORDY</name>
              <bitOffset>12</bitOffset>
              <bitWidth>1</bitWidth>
            </field>
          </fields>
        </register>
        <register>
          <name>IER</name>
          <addressOffset>0x4</addressOffset>
          <size>0x20</size>
          <fields>
            <field>
              <name>ADRDYIE</name>
              <bitOffset>0</bitOffset>
              <bitWidth>1</bitWidth>
            </field>
            <field>
              <name>EOSMPIE</name>
              <bitOffset>1</bitOffset>
              <bitWidth>1</bitWidth>
            </field>
            <field>
              <name>EOCIE</name>
              <bitOffset>2</bitOffset>
              <bitWidth>1</bitWidth>
            </field>
            <field>
              <name>EOSIE</name>
              <bitOffset>3</bitOffset>
              <bitWidth>1</bitWidth>
            </field>
            <field>
              <name>OVRIE</name>
              <bitOffset>4</bitOffset>
              <bitWidth>1</bitWidth>
            </field>
            <field>
              <name>JEOCIE</name>
              <bitOffset>5</bitOffset>
              <bitWidth>1</bitWidth>
            </field>
            <field>
              <name>JEOSIE</name>
              <bitOffset>6</bitOffset>
              <bitWidth>1</bitWidth>
            </field>
            <field>
              <name>AWD1IE</name>
              <bitOffset>7</bitOffset>
              <bitWidth>1</bitWidth>
            </field>
            <field>
              <name>AWD2IE</name>
              <bitOffset>8</bitOffset>
              <bitWidth>1</bitWidth>
            </field>
            <field>
              <name>AWD3IE</name>
              <bitOffset>9</bitOffset>
              <bitWidth>1</bitWidth>
            </field>
            <field>
              <name>JQOVFIE</name>
              <bitOffset>10</bitOffset>
              <bitWidth>1</bitWidth>
            </field>
          </fields>
        </register>
        <register>
          <name>CR</name>
          <addressOffset>0x8</addressOffset>
          <size>0x20</size>
          <fields>
            <field>
              <name>ADEN</name>
              <bitOffset>0</bitOffset>
              <bitWidth>1</bitWidth>
            </field>
            <field>
              <name>ADDIS</name>
              <bitOffset>1</bitOffset>
              <bitWidth>1</bitWidth>
            </field>
            <field>
              <name>ADSTART</name>
              <bitOffset>2</bitOffset>
              <bitWidth>1</bitWidth>
            </field>
            <field>
              <name>JADSTART</name>
              <bitOffset>3</bitOffset>
              <bitWidth>1</bitWidth>
            </field>
            <field>
              <name>ADSTP</name>
              <bitOffset>4</bitOffset>
              <bitWidth>1</bitWidth>
            </field>
            <field>
              <name>JADSTP</name>
              <bitOffset>5</bitOffset>
              <bitWidth>1</bitWidth>
            </field>
            <field>
              <name>BOOST</name>
              <bitOffset>8</bitOffset>
              <bitWidth>2</bitWidth>
            </field>
            <field>
              <name>ADCALLIN</name>
              <bitOffset>16</bitOffset>
              <bitWidth>1</bitWidth>
            </field>
            <field>
              <name>LINCALRDYW1</name>
              <bitOffset>22</bitOffset>
              <bitWidth>1</bitWidth>
            </field>
            <field>
              <name>LINCALRDYW2</name>
              <bitOffset>23</bitOffset>
              <bitWidth>1</bitWidth>
            </field>
            <field>
              <name>LINCALRDYW3</name>
              <bitOffset>24</bitOffset>
              <bitWidth>1</bitWidth>
            </field>
            <field>
              <name>LINCALRDYW4</name>
              <bitOffset>25</bitOffset>
              <bitWidth>1</bitWidth>
            </field>
            <field>
              <name>LINCALRDYW5</name>
              <bitOffset>26</bitOffset>
              <bitWidth>1</bitWidth>
            </field>
            <field>
              <name>LINCALRDYW6</name>
              <bitOffset>27</bitOffset>
              <bitWidth>1</bitWidth>
            </field>
            <field>
              <name>ADVREGEN</name>
              <bitOffset>28</bitOffset>
              <bitWidth>1</bitWidth>
            </field>
            <field>
              <name>DEEPPWD</name>
              <bitOffset>29</bitOffset>
              <bitWidth>1</bitWidth>
            </field>
            <field>
              <name>ADCALDIF</name>
              <bitOffset>30</bitOffset>
              <bitWidth>1</bitWidth>
            </field>
            <field>
              <name>ADCAL</name>
              <bitOffset>31</bitOffset>
              <bitWidth>1</bitWidth>
            </field>
          </fields>
        </register>
        <register>
          <name>CFGR</name>
          <addressOffset>0xc</addressOffset>
          <size>0x20</size>
          <fields>
            <field>
              <name>DMNGT</name>
              <bitOffset>0</bitOffset>
              <bitWidth>2</bitWidth>
            </field>
            <field>
              <name>RES</name>
              <bitOffset>2</bitOffset>
              <bitWidth>3</bitWidth>
            </field>
            <field>
              <name>EXTSEL</name>
              <bitOffset>5</bitOffset>
              <bitWidth>5</bitWidth>
            </field>
            <field>
              <name>EXTEN</name>
              <bitOffset>10</bitOffset>
              <bitWidth>2</bitWidth>
            </field>
            <field>
              <name>OVRMOD</name>
              <bitOffset>12</bitOffset>
              <bitWidth>1</bitWidth>
            </field>
            <field>
              <name>CONT</name>
              <bitOffset>13</bitOffset>
              <bitWidth>1</bitWidth>
            </field>
            <field>
              <name>AUTDLY</name>
              <bitOffset>14</bitOffset>
              <bitWidth>1</bitWidth>
            </field>
            <field>
              <name>DISCEN</name>
              <bitOffset>16</bitOffset>
              <bitWidth>1</bitWidth>
            </field>
            <field>
              <name>DISCNUM</name>
              <bitOffset>17</bitOffset>
              <bitWidth>3</bitWidth>
            </field>
            <field>
              <name>JDISCEN</name>
              <bitOffset>20</bitOffset>
              <bitWidth>1</bitWidth>
            </field>
            <field>
              <name>JQM</name>
              <bitOffset>21</bitOffset>
              <bitWidth>1</bitWidth>
            </field>
            <field>
              <name>AWD1SGL</name>
              <bitOffset>22</bitOffset>
              <bitWidth>1</bitWidth>
            </field>
            <field>
              <name>AWD1EN</name>
              <bitOffset>23</bitOffset>
              <bitWidth>1</bitWidth>
            </field>
            <field>
              <name>JAWD1EN</name>
              <bitOffset>24</bitOffset>
              <bitWidth>1</bitWidth>
            </field>
            <field>
              <name>JAUTO</name>
              <bitOffset>25</bitOffset>
              <bitWidth>1</bitWidth>
            </field>
            <field>
              <name>AWD1CH</name>
              <bitOffset>26</bitOffset>
              <bitWidth>5</bitWidth>
            </field>
            <field>
              <name>JQDIS</name>
              <bitOffset>31</bitOffset>
              <bitWidth>1</bitWidth>
            </field>
          </fields>
        </register>
        <register>
          <name>CFGR2</name>
          <addressOffset>0x10</addressOffset>
          <size>0x20</size>
          <fields>
            <field>
              <name>ROVSE</name>
              <bitOffset>0</bitOffset>
              <bitWidth>1</bitWidth>
            </field>
            <field>
              <name>JOVSE</name>
              <bitOffset>1</bitOffset>
              <bitWidth>1</bitWidth>
            </field>
            <field>
              <name>OVSS</name>
              <bitOffset>5</bitOffset>
              <bitWidth>4</bitWidth>
            </field>
            <field>
              <name>TROVS</name>
              <bitOffset>9</bitOffset>
              <bitWidth>1</bitWidth>
            </field>
            <field>
              <name>ROVSM</name>
              <bitOffset>10</bitOffset>
              <bitWidth>1</bitWidth>
            </field>
            <field>
              <name>RSHIFT1</name>
              <bitOffset>11</bitOffset>
              <bitWidth>1</bitWidth>
            </field>
            <field>
              <name>RSHIFT2</name>
              <bitOffset>12</bitOffset>
              <bitWidth>1</bitWidth>
            </field>
            <field>
              <name>RSHIFT3</name>
              <bitOffset>13</bitOffset>
              <bitWidth>1</bitWidth>
            </field>
            <field>
              <name>RSHIFT4</name>
              <bitOffset>14</bitOffset>
              <bitWidth>1</bitWidth>
            </field>
            <field>
              <name>OVSR</name>
              <bitOffset>16</bitOffset>
              <bitWidth>10</bitWidth>
            </field>
            <field>
              <name>LSHIFT</name>
              <bitOffset>28</bitOffset>
              <bitWidth>4</bitWidth>
            </field>
          </fields>
        </register>
        <register>
          <name>SMPR1</name>
          <addressOffset>0x14</addressOffset>
          <size>0x20</size>
          <fields>
            <field>
              <name>SMP0</name>
              <bitOffset>0</bitOffset>
              <bitWidth>3</bitWidth>
            </field>
            <field>
              <name>SMP1</name>
              <bitOffset>3</bitOffset>
              <bitWidth>3</bitWidth>
            </field>
            <field>
              <name>SMP2</name>
              <bitOffset>6</bitOffset>
              <bitWidth>3</bitWidth>
            </field>
            <field>
              <name>SMP3</name>
              <bitOffset>9</bitOffset>
              <bitWidth>3</bitWidth>
            </field>
            <field>
              <name>SMP4</name>
              <bitOffset>12</bitOffset>
              <bitWidth>3</bitWidth>
            </field>
            <field>
              <name>SMP5</name>
              <bitOffset>15</bitOffset>
              <bitWidth>3</bitWidth>
            </field>
            <field>
              <name>SMP6</name>
              <bitOffset>18</bitOffset>
              <bitWidth>3</bitWidth>
            </field>
            <field>
              <name>SMP7</name>
              <bitOffset>21</bitOffset>
              <bitWidth>3</bitWidth>
            </field>
            <field>
              <name>SMP8</name>
              <bitOffset>24</bitOffset>
              <bitWidth>3</bitWidth>
            </field>
            <field>
              <name>SMP9</name>
              <bitOffset>27</bitOffset>
              <bitWidth>3</bitWidth>
            </field>
          </fields>
        </register>
        <register>
          <name>SMPR2</name>
          <addressOffset>0x18</addressOffset>
          <size>0x20</size>
          <fields>
            <field>
              <name>SMP10</name>
              <bitOffset>0</bitOffset>
              <bitWidth>3</bitWidth>
            </field>
            <field>
              <name>SMP11</name>
              <bitOffset>3</bitOffset>
              <bitWidth>3</bitWidth>
            </field>
            <field>
              <name>SMP12</name>
              <bitOffset>6</bitOffset>
              <bitWidth>3</bitWidth>
            </field>
            <field>
              <name>SMP13</name>
              <bitOffset>9</bitOffset>
              <bitWidth>3</bitWidth>
            </field>
            <field>
              <name>SMP14</name>
              <bitOffset>12</bitOffset>
              <bitWidth>3</bitWidth>
            </field>
            <field>
              <name>SMP15</name>
              <bitOffset>15</bitOffset>
              <bitWidth>3</bitWidth>
            </field>
            <field>
              <name>SMP16</name>
              <bitOffset>18</bitOffset>
              <bitWidth>3</bitWidth>
            </field>
            <field>
              <name>SMP17</name>
              <bitOffset>21</bitOffset>
              <bitWidth>3</bitWidth>
            </field>
            <field>
              <name>SMP18</name>
              <bitOffset>24</bitOffset>
              <bitWidth>3</bitWidth>
            </field>
            <field>
              <name>SMP19</name>
              <bitOffset>27</bitOffset>
              <bitWidth>3</bitWidth>
            </field>
          </fields>
        </register>
        <register>
          <name>PCSEL_RES0</name>
          <addressOffset>0x1c</addressOffset>
          <size>0x20</size>
        </register>
        <register>
          <name>LTR1_TR1</name>
          <addressOffset>0x20</addressOffset>
          <size>0x20</size>
        </register>
        <register>
          <name>HTR1_TR2</name>
          <addressOffset>0x24</addressOffset>
          <size>0x20</size>
        </register>
        <register>
          <name>RES1_TR3</name>
          <addressOffset>0x28</addressOffset>
          <size>0x20</size>
        </register>
        <register>
          <name>SQR1</name>
          <addressOffset>0x30</addressOffset>
          <size>0x20</size>
          <fields>
            <field>
              <name>L</name>
              <bitOffset>0</bitOffset>
              <bitWidth>4</bitWidth>
            </field>
            <field>
              <name>SQ1</name>
              <bitOffset>6</bitOffset>
              <bitWidth>5</bitWidth>
            </field>
            <field>
              <name>SQ2</name>
              <bitOffset>12</bitOffset>
              <bitWidth>5</bitWidth>
            </field>
            <field>
              <name>SQ3</name>
              <bitOffset>18</bitOffset>
              <bitWidth>5</bitWidth>
            </field>
            <field>
              <name>SQ4</name>
              <bitOffset>24</bitOffset>
              <bitWidth>5</bitWidth>
            </field>
          </fields>
        </register>
        <register>
          <name>SQR2</name>
          <addressOffset>0x34</addressOffset>
          <size>0x20</size>
          <fields>
            <field>
              <name>SQ5</name>
              <bitOffset>0</bitOffset>
              <bitWidth>5</bitWidth>
            </field>
            <field>
              <name>SQ6</name>
              <bitOffset>6</bitOffset>
              <bitWidth>5</bitWidth>
            </field>
            <field>
              <name>SQ7</name>
              <bitOffset>12</bitOffset>
              <bitWidth>5</bitWidth>
            </field>
            <field>
              <name>SQ8</name>
              <bitOffset>18</bitOffset>
              <bitWidth>5</bitWidth>
            </field>
            <field>
              <name>SQ9</name>
              <bitOffset>24</bitOffset>
              <bitWidth>5</bitWidth>
            </field>
          </fields>
        </register>
        <register>
          <name>SQR3</name>
          <addressOffset>0x38</addressOffset>
          <size>0x20</size>
          <fields>
            <field>
              <name>SQ10</name>
              <bitOffset>0</bitOffset>
              <bitWidth>5</bitWidth>
            </field>
            <field>
              <name>SQ11</name>
              <bitOffset>6</bitOffset>
              <bitWidth>5</bitWidth>
            </field>
            <field>
              <name>SQ12</name>
              <bitOffset>12</bitOffset>
              <bitWidth>5</bitWidth>
            </field>
            <field>
              <name>SQ13</name>
              <bitOffset>18</bitOffset>
              <bitWidth>5</bitWidth>
            </field>
            <field>
              <name>SQ14</name>
              <bitOffset>24</bitOffset>
              <bitWidth>5</bitWidth>
            </field>
          </fields>
        </register>
        <register>
          <name>SQR4</name>
          <addressOffset>0x3c</addressOffset>
          <size>0x20</size>
          <fields>
            <field>
              <name>SQ15</name>
              <bitOffset>0</bitOffset>
              <bitWidth>5</bitWidth>
            </field>
            <field>
              <name>SQ16</name>
              <bitOffset>6</bitOffset>
              <bitWidth>5</bitWidth>
            </field>
          </fields>
        </register>
        <register>
          <name>DR</name>
          <addressOffset>0x40</addressOffset>
          <size>0x20</size>
          <fields>
            <field>
              <name>RDATA</name>
              <bitOffset>0</bitOffset>
              <bitWidth>32</bitWidth>
            </field>
          </fields>
        </register>
        <register>
          <name>JSQR</name>
          <addressOffset>0x4c</addressOffset>
          <size>0x20</size>
          <fields>
            <field>
              <name>JL</name>
              <bitOffset>0</bitOffset>
              <bitWidth>2</bitWidth>
            </field>
            <field>
              <name>JEXTSEL</name>
              <bitOffset>2</bitOffset>
              <bitWidth>5</bitWidth>
            </field>
            <field>
              <name>JEXTEN</name>
              <bitOffset>7</bitOffset>
              <bitWidth>2</bitWidth>
            </field>
            <field>
              <name>JSQ1</name>
              <bitOffset>9</bitOffset>
              <bitWidth>5</bitWidth>
            </field>
            <field>
              <name>JSQ2</name>
              <bitOffset>15</bitOffset>
              <bitWidth>5</bitWidth>
            </field>
            <field>
              <name>JSQ3</name>
              <bitOffset>21</bitOffset>
              <bitWidth>5</bitWidth>
            </field>
            <field>
              <name>JSQ4</name>
              <bitOffset>27</bitOffset>
              <bitWidth>5</bitWidth>
            </field>
          </fields>
        </register>
        <register>
          <name>OFR1</name>
          <addressOffset>0x60</addressOffset>
          <size>0x20</size>
          <fields>
            <field>
              <name>OFFSET1</name>
              <bitOffset>0</bitOffset>
              <bitWidth>26</bitWidth>
            </field>
            <field>
              <name>OFFSET1_CH</name>
              <bitOffset>26</bitOffset>
              <bitWidth>5</bitWidth>
            </field>
            <field>
              <name>SSATE</name>
              <bitOffset>31</bitOffset>
              <bitWidth>1</bitWidth>
            </field>
          </fields>
        </register>
        <register>
          <name>OFR2</name>
          <addressOffset>0x64</addressOffset>
          <size>0x20</size>
          <fields>
            <field>
              <name>OFFSET2</name>
              <bitOffset>0</bitOffset>
              <bitWidth>26</bitWidth>
            </field>
            <field>
              <name>OFFSET2_CH</name>
              <bitOffset>26</bitOffset>
              <bitWidth>5</bitWidth>
            </field>
            <field>
              <name>SSATE</name>
              <bitOffset>31</bitOffset>
              <bitWidth>1</bitWidth>
            </field>
          </fields>
        </register>
        <register>
          <name>OFR3</name>
          <addressOffset>0x68</addressOffset>
          <size>0x20</size>
          <fields>
            <field>
              <name>OFFSET3</name>
              <bitOffset>0</bitOffset>
              <bitWidth>26</bitWidth>
            </field>
            <field>
              <name>OFFSET3_CH</name>
              <bitOffset>26</bitOffset>
              <bitWidth>5</bitWidth>
            </field>
            <field>
              <name>SSATE</name>
              <bitOffset>31</bitOffset>
              <bitWidth>1</bitWidth>
            </field>
          </fields>
        </register>
        <register>
          <name>OFR4</name>
          <addressOffset>0x6c</addressOffset>
          <size>0x20</size>
          <fields>
            <field>
              <name>OFFSET4</name>
              <bitOffset>0</bitOffset>
              <bitWidth>26</bitWidth>
            </field>
            <field>
              <name>OFFSET4_CH</name>
              <bitOffset>26</bitOffset>
              <bitWidth>5</bitWidth>
            </field>
            <field>
              <name>SSATE</name>
              <bitOffset>31</bitOffset>
              <bitWidth>1</bitWidth>
            </field>
          </fields>
        </register>
        <register>
          <name>JDR1</name>
          <addressOffset>0x80</addressOffset>
          <size>0x20</size>
          <fields>
            <field>
              <name>JDATA</name>
              <bitOffset>0</bitOffset>
              <bitWidth>32</bitWidth>
            </field>
          </fields>
        </register>
        <register>
          <name>JDR2</name>
          <addressOffset>0x84</addressOffset>
          <size>0x20</size>
          <fields>
            <field>
              <name>JDATA</name>
              <bitOffset>0</bitOffset>
              <bitWidth>32</bitWidth>
            </field>
          </fields>
        </register>
        <register>
          <name>JDR3</name>
          <addressOffset>0x88</addressOffset>
          <size>0x20</size>
          <fields>
            <field>
              <name>JDATA</name>
              <bitOffset>0</bitOffset>
              <bitWidth>32</bitWidth>
            </field>
          </fields>
        </register>
        <register>
          <name>JDR4</name>
          <addressOffset>0x8c</addressOffset>
          <size>0x20</size>
          <fields>
            <field>
              <name>JDATA</name>
              <bitOffset>0</bitOffset>
              <bitWidth>32</bitWidth>
            </field>
          </fields>
        </register>
        <register>
          <name>AWD2CR</name>
          <addressOffset>0xa0</addressOffset>
          <size>0x20</size>
          <fields>
            <field>
              <name>AWD2CH</name>
              <bitOffset>0</bitOffset>
              <bitWidth>20</bitWidth>
            </field>
          </fields>
        </register>
        <register>
          <name>AWD3CR</name>
          <addressOffset>0xa4</addressOffset>
          <size>0x20</size>
          <fields>
            <field>
              <name>AWD3CH</name>
              <bitOffset>0</bitOffset>
              <bitWidth>20</bitWidth>
            </field>
          </fields>
        </register>
        <register>
          <name>LTR2_DIFSEL</name>
          <addressOffset>0xb0</addressOffset>
          <size>0x20</size>
        </register>
        <register>
          <name>HTR2_CALFACT</name>
          <addressOffset>0xb4</addressOffset>
          <size>0x20</size>
        </register>
        <register>
          <name>LTR3_RES10</name>
          <addressOffset>0xb8</addressOffset>
          <size>0x20</size>
        </register>
        <register>
          <name>HTR3_RES11</name>
          <addressOffset>0xbc</addressOffset>
          <size>0x20</size>
        </register>
        <register>
          <name>DIFSEL_RES12</name>
          <addressOffset>0xc0</addressOffset>
          <size>0x20</size>
        </register>
        <register>
          <name>CALFACT_RES13</name>
          <addressOffset>0xc4</addressOffset>
          <size>0x20</size>
        </register>
        <register>
          <name>CALFACT2_RES14</name>
          <addressOffset>0xc8</addressOffset>
          <size>0x20</size>
        </register>
      </registers>
    </peripheral>
    <peripheral>
      <name>ADC12_COMMON</name>
      <baseAddress>0x40022300</baseAddress>
      <registers>
        <register>
          <name>CSR</name>
          <addressOffset>0x0</addressOffset>
          <size>0x20</size>
          <fields>
            <field>
              <name>ADRDY_MST</name>
              <bitOffset>0</bitOffset>
              <bitWidth>1</bitWidth>
            </field>
            <field>
              <name>EOSMP_MST</name>
              <bitOffset>1</bitOffset>
              <bitWidth>1</bitWidth>
            </field>
            <field>
              <name>EOC_MST</name>
              <bitOffset>2</bitOffset>
              <bitWidth>1</bitWidth>
            </field>
            <field>
              <name>EOS_MST</name>
              <bitOffset>3</bitOffset>
              <bitWidth>1</bitWidth>
            </field>
            <field>
              <name>OVR_MST</name>
              <bitOffset>4</bitOffset>
              <bitWidth>1</bitWidth>
            </field>
            <field>
              <name>JEOC_MST</name>
              <bitOffset>5</bitOffset>
              <bitWidth>1</bitWidth>
            </field>
            <field>
              <name>JEOS_MST</name>
              <bitOffset>6</bitOffset>
              <bitWidth>1</bitWidth>
            </field>
            <field>
              <name>AWD1_MST</name>
              <bitOffset>7</bitOffset>
              <bitWidth>1</bitWidth>
            </field>
            <field>
              <name>AWD2_MST</name>
              <bitOffset>8</bitOffset>
              <bitWidth>1</bitWidth>
            </field>
            <field>
              <name>AWD3_MST</name>
              <bitOffset>9</bitOffset>
              <bitWidth>1</bitWidth>
            </field>
            <field>
              <name>JQOVF_MST</name>
              <bitOffset>10</bitOffset>
              <bitWidth>1</bitWidth>
            </field>
            <field>
              <name>ADRDY_SLV</name>
              <bitOffset>16</bitOffset>
              <bitWidth>1</bitWidth>
            </field>
            <field>
              <name>EOSMP_SLV</name>
              <bitOffset>17</bitOffset>
              <bitWidth>1</bitWidth>
            </field>
            <field>
              <name>EOC_SLV</name>
              <bitOffset>18</bitOffset>
              <bitWidth>1</bitWidth>
            </field>
            <field>
              <name>EOS_SLV</name>
              <bitOffset>19</bitOffset>
              <bitWidth>1</bitWidth>
            </field>
            <field>
              <name>OVR_SLV</name>
              <bitOffset>20</bitOffset>
              <bitWidth>1</bitWidth>
            </field>
            <field>
              <name>JEOC_SLV</name>
              <bitOffset>21</bitOffset>
              <bitWidth>1</bitWidth>
            </field>
            <field>
              <name>JEOS_SLV</name>
              <bitOffset>22</bitOffset>
              <bitWidth>1</bitWidth>
            </field>
            <field>
              <name>AWD1_SLV</name>
              <bitOffset>23</bitOffset>
              <bitWidth>1</bitWidth>
            </field>
            <field>
              <name>AWD2_SLV</name>
              <bitOffset>24</bitOffset>
              <bitWidth>1</bitWidth>
            </field>
            <field>
              <name>AWD3_SLV</name>
              <bitOffset>25</bitOffset>
              <bitWidth>1</bitWidth>
            </field>
            <field>
              <name>JQOVF_SLV</name>
              <bitOffset>26</bitOffset>
              <bitWidth>1</bitWidth>
            </field>
          </fields>
        </register>
        <register>
          <name>CCR</name>
          <addressOffset>0x8</addressOffset>
          <size>0x20</size>
          <fields>
            <field>
              <name>DUAL</name>
              <bitOffset>0</bitOffset>
              <bitWidth>5</bitWidth>
            </field>
            <field>
              <name>DELAY</name>
              <bitOffset>8</bitOffset>
              <bitWidth>4</bitWidth>
            </field>
            <field>
              <name>DAMDF</name>
              <bitOffset>14</bitOffset>
              <bitWidth>2</bitWidth>
            </field>
            <field>
              <name>CKMODE</name>
              <bitOffset>16</bitOffset>
              <bitWidth>2</bitWidth>
            </field>
            <field>
              <name>PRESC</name>
              <bitOffset>18</bitOffset>
              <bitWidth>4</bitWidth>
            </field>
            <field>
              <name>VREFEN</name>
              <bitOffset>22</bitOffset>
              <bitWidth>1</bitWidth>
            </field>
            <field>
              <name>TSEN</name>
              <bitOffset>23</bitOffset>
              <bitWidth>1</bitWidth>
            </field>
            <field>
              <name>VBATEN</name>
              <bitOffset>24</bitOffset>
              <bitWidth>1</bitWidth>
            </field>
          </fields>
        </register>
        <register>
          <name>CDR</name>
          <addressOffset>0xc</addressOffset>
          <size>0x20</size>
          <fields>
            <field>
              <name>RDATA_MST</name>
              <bitOffset>0</bitOffset>
              <bitWidth>16</bitWidth>
            </field>
            <field>
              <name>RDATA_SLV</name>
              <bitOffset>16</bitOffset>
              <bitWidth>16</bitWidth>
            </field>
          </fields>
        </register>
        <register>
          <name>CDR2</name>
          <addressOffset>0x10</addressOffset>
          <size>0x20</size>
          <fields>
            <field>
              <name>RDATA_ALT</name>
              <bitOffset>0</bitOffset>
              <bitWidth>32</bitWidth>
            </field>
          </fields>
        </register>
      </registers>
    </peripheral>
    <peripheral>
      <name>ETH</name>
      <baseAddress>0x40028000</baseAddress>
      <registers>
        <register>
          <name>MACCR</name>
          <addressOffset>0x0</addressOffset>
          <size>0x20</size>
          <fields>
            <field>
              <name>RE</name>
              <bitOffset>0</bitOffset>
              <bitWidth>1</bitWidth>
            </field>
            <field>
              <name>TE</name>
              <bitOffset>1</bitOffset>
              <bitWidth>1</bitWidth>
            </field>
            <field>
              <name>PRELEN</name>
              <bitOffset>2</bitOffset>
              <bitWidth>2</bitWidth>
            </field>
            <field>
              <name>DC</name>
              <bitOffset>4</bitOffset>
              <bitWidth>1</bitWidth>
            </field>
            <field>
              <name>BL</name>
              <bitOffset>5</bitOffset>
              <bitWidth>2</bitWidth>
            </field>
            <field>
              <name>DR</name>
              <bitOffset>8</bitOffset>
              <bitWidth>1</bitWidth>
            </field>
            <field>
              <name>DCRS</name>
              <bitOffset>9</bitOffset>
              <bitWidth>1</bitWidth>
            </field>
            <field>
              <name>DO</name>
              <bitOffset>10</bitOffset>
              <bitWidth>1</bitWidth>
            </field>
            <field>
              <name>ECRSFD</name>
              <bitOffset>11</bitOffset>
              <bitWidth>1</bitWidth>
            </field>
            <field>
              <name>LM</name>
              <bitOffset>12</bitOffset>
              <bitWidth>1</bitWidth>
            </field>
            <field>
              <name>DM</name>
              <bitOffset>13</bitOffset>
              <bitWidth>1</bitWidth>
            </field>
            <field>
              <name>FES</name>
              <bitOffset>14</bitOffset>
              <bitWidth>1</bitWidth>
            </field>
            <field>
              <name>JE</name>
              <bitOffset>16</bitOffset>
              <bitWidth>1</bitWidth>
            </field>
            <field>
              <name>JD</name>
              <bitOffset>17</bitOffset>
              <bitWidth>1</bitWidth>
            </field>
            <field>
              <name>WD</name>
              <bitOffset>19</bitOffset>
              <bitWidth>1</bitWidth>
            </field>
            <field>
              <name>ACS</name>
              <bitOffset>20</bitOffset>
              <bitWidth>1</bitWidth>
            </field>
            <field>
              <name>CST</name>
              <bitOffset>21</bitOffset>
              <bitWidth>1</bitWidth>
            </field>
            <field>
              <name>S2KP</name>
              <bitOffset>22</bitOffset>
              <bitWidth>1</bitWidth>
            </field>
            <field>
              <name>GPSLCE</name>
              <bitOffset>23</bitOffset>
              <bitWidth>1</bitWidth>
            </field>
            <field>
              <name>IPG</name>
              <bitOffset>24</bitOffset>
              <bitWidth>3</bitWidth>
            </field>
            <field>
              <name>IPC</name>
              <bitOffset>27</bitOffset>
              <bitWidth>1</bitWidth>
            </field>
            <field>
              <name>SARC_REPADDR1</name>
              <bitOffset>28</bitOffset>
              <bitWidth>3</bitWidth>
            </field>
            <field>
              <name>SARC_INSADDR1</name>
              <bitOffset>29</bitOffset>
              <bitWidth>2</bitWidth>
            </field>
            <field>
              <name>ARP</name>
              <bitOffset>31</bitOffset>
              <bitWidth>1</bitWidth>
            </field>
          </fields>
        </register>
        <register>
          <name>MACECR</name>
          <addressOffset>0x4</addressOffset>
          <size>0x20</size>
          <fields>
            <field>
              <name>GPSL</name>
              <bitOffset>0</bitOffset>
              <bitWidth>14</bitWidth>
            </field>
            <field>
              <name>DCRCC</name>
              <bitOffset>16</bitOffset>
              <bitWidth>1</bitWidth>
            </field>
            <field>
              <name>SPEN</name>
              <bitOffset>17</bitOffset>
              <bitWidth>1</bitWidth>
            </field>
            <field>
              <name>USP</name>
              <bitOffset>18</bitOffset>
              <bitWidth>1</bitWidth>
            </field>
            <field>
              <name>EIPGEN</name>
              <bitOffset>24</bitOffset>
              <bitWidth>1</bitWidth>
            </field>
            <field>
              <name>EIPG</name>
              <bitOffset>25</bitOffset>
              <bitWidth>5</bitWidth>
            </field>
          </fields>
        </register>
        <register>
          <name>MACPFR</name>
          <addressOffset>0x8</addressOffset>
          <size>0x20</size>
          <fields>
            <field>
              <name>PR</name>
              <bitOffset>0</bitOffset>
              <bitWidth>1</bitWidth>
            </field>
            <field>
              <name>HUC</name>
              <bitOffset>1</bitOffset>
              <bitWidth>1</bitWidth>
            </field>
            <field>
              <name>HMC</name>
              <bitOffset>2</bitOffset>
              <bitWidth>1</bitWidth>
            </field>
            <field>
              <name>DAIF</name>
              <bitOffset>3</bitOffset>
              <bitWidth>1</bitWidth>
            </field>
            <field>
              <name>PM</name>
              <bitOffset>4</bitOffset>
              <bitWidth>1</bitWidth>
            </field>
            <field>
              <name>DBF</name>
              <bitOffset>5</bitOffset>
              <bitWidth>1</bitWidth>
            </field>
            <field>
              <name>PCF_FORWARDPASSEDADDRFILTER</name>
              <bitOffset>6</bitOffset>
              <bitWidth>2</bitWidth>
            </field>
            <field>
              <name>PCF_FORWARDALL</name>
              <bitOffset>7</bitOffset>
              <bitWidth>1</bitWidth>
            </field>
            <field>
              <name>SAIF</name>
              <bitOffset>8</bitOffset>
              <bitWidth>1</bitWidth>
            </field>
            <field>
              <name>SAF</name>
              <bitOffset>9</bitOffset>
              <bitWidth>1</bitWidth>
            </field>
            <field>
              <name>HPF</name>
              <bitOffset>10</bitOffset>
              <bitWidth>1</bitWidth>
            </field>
            <field>
              <name>VTFE</name>
              <bitOffset>16</bitOffset>
              <bitWidth>1</bitWidth>
            </field>
            <field>
              <name>IPFE</name>
              <bitOffset>20</bitOffset>
              <bitWidth>1</bitWidth>
            </field>
            <field>
              <name>DNTU</name>
              <bitOffset>21</bitOffset>
              <bitWidth>1</bitWidth>
            </field>
            <field>
              <name>RA</name>
              <bitOffset>31</bitOffset>
              <bitWidth>1</bitWidth>
            </field>
          </fields>
        </register>
        <register>
          <name>MACWTR</name>
          <addressOffset>0xc</addressOffset>
          <size>0x20</size>
          <fields>
            <field>
              <name>WTO</name>
              <bitOffset>0</bitOffset>
              <bitWidth>4</bitWidth>
            </field>
            <field>
              <name>PWE</name>
              <bitOffset>8</bitOffset>
              <bitWidth>1</bitWidth>
            </field>
          </fields>
        </register>
        <register>
          <name>MACHT0R</name>
          <addressOffset>0x10</addressOffset>
          <size>0x20</size>
        </register>
        <register>
          <name>MACHT1R</name>
          <addressOffset>0x14</addressOffset>
          <size>0x20</size>
        </register>
        <register>
          <name>MACVTR</name>
          <addressOffset>0x50</addressOffset>
          <size>0x20</size>
          <fields>
            <field>
              <name>VL_VID</name>
              <bitOffset>0</bitOffset>
              <bitWidth>12</bitWidth>
            </field>
            <field>
              <name>VL_CFIDEI</name>
              <bitOffset>12</bitOffset>
              <bitWidth>1</bitWidth>
            </field>
            <field>
              <name>VL_UP</name>
              <bitOffset>13</bitOffset>
              <bitWidth>3</bitWidth>
            </field>
            <field>
              <name>ETV</name>
              <bitOffset>16</bitOffset>
              <bitWidth>1</bitWidth>
            </field>
            <field>
              <name>VTIM</name>
              <bitOffset>17</bitOffset>
              <bitWidth>1</bitWidth>
            </field>
            <field>
              <name>ESVL</name>
              <bitOffset>18</bitOffset>
              <bitWidth>1</bitWidth>
            </field>
            <field>
              <name>ERSVLM</name>
              <bitOffset>19</bitOffset>
              <bitWidth>1</bitWidth>
            </field>
            <field>
              <name>DOVLTC</name>
              <bitOffset>20</bitOffset>
              <bitWidth>1</bitWidth>
            </field>
            <field>
              <name>EVLS_STRIPIFPASS</name>
              <bitOffset>21</bitOffset>
              <bitWidth>1</bitWidth>
            </field>
            <field>
              <name>EVLS_STRIPIFFAILS</name>
              <bitOffset>22</bitOffset>
              <bitWidth>1</bitWidth>
            </field>
            <field>
              <name>EVLRXS</name>
              <bitOffset>24</bitOffset>
              <bitWidth>1</bitWidth>
            </field>
            <field>
              <name>VTHM</name>
              <bitOffset>25</bitOffset>
              <bitWidth>1</bitWidth>
            </field>
            <field>
              <name>EDVLP</name>
              <bitOffset>26</bitOffset>
              <bitWidth>1</bitWidth>
            </field>
            <field>
              <name>ERIVLT</name>
              <bitOffset>27</bitOffset>
              <bitWidth>1</bitWidth>
            </field>
            <field>
              <name>EIVLS_STRIPIFPASS</name>
              <bitOffset>28</bitOffset>
              <bitWidth>1</bitWidth>
            </field>
            <field>
              <name>EIVLS_STRIPIFFAILS</name>
              <bitOffset>29</bitOffset>
              <bitWidth>1</bitWidth>
            </field>
            <field>
              <name>EIVLRXS</name>
              <bitOffset>31</bitOffset>
              <bitWidth>1</bitWidth>
            </field>
          </fields>
        </register>
        <register>
          <name>MACVHTR</name>
          <addressOffset>0x58</addressOffset>
          <size>0x20</size>
          <fields>
            <field>
              <name>VLHT</name>
              <bitOffset>0</bitOffset>
              <bitWidth>16</bitWidth>
            </field>
          </fields>
        </register>
        <register>
          <name>MACVIR</name>
          <addressOffset>0x60</addressOffset>
          <size>0x20</size>
          <fields>
            <field>
              <name>VLT_VID</name>
              <bitOffset>0</bitOffset>
              <bitWidth>12</bitWidth>
            </field>
            <field>
              <name>VLT_CFIDEI</name>
              <bitOffset>12</bitOffset>
              <bitWidth>1</bitWidth>
            </field>
            <field>
              <name>VLT_UP</name>
              <bitOffset>13</bitOffset>
              <bitWidth>3</bitWidth>
            </field>
            <field>
              <name>VLC_VLANTAGREPLACE</name>
              <bitOffset>16</bitOffset>
              <bitWidth>2</bitWidth>
            </field>
            <field>
              <name>VLC_VLANTAGINSERT</name>
              <bitOffset>17</bitOffset>
              <bitWidth>1</bitWidth>
            </field>
            <field>
              <name>VLP</name>
              <bitOffset>18</bitOffset>
              <bitWidth>1</bitWidth>
            </field>
            <field>
              <name>CSVL</name>
              <bitOffset>19</bitOffset>
              <bitWidth>1</bitWidth>
            </field>
            <field>
              <name>VLTI</name>
              <bitOffset>20</bitOffset>
              <bitWidth>1</bitWidth>
            </field>
          </fields>
        </register>
        <register>
          <name>MACIVIR</name>
          <addressOffset>0x64</addressOffset>
          <size>0x20</size>
          <fields>
            <field>
              <name>VLT_VID</name>
              <bitOffset>0</bitOffset>
              <bitWidth>12</bitWidth>
            </field>
            <field>
              <name>VLT_CFIDEI</name>
              <bitOffset>12</bitOffset>
              <bitWidth>1</bitWidth>
            </field>
            <field>
              <name>VLT_UP</name>
              <bitOffset>13</bitOffset>
              <bitWidth>3</bitWidth>
            </field>
            <field>
              <name>VLC_VLANTAGREPLACE</name>
              <bitOffset>16</bitOffset>
              <bitWidth>2</bitWidth>
            </field>
            <field>
              <name>VLC_VLANTAGINSERT</name>
              <bitOffset>17</bitOffset>
              <bitWidth>1</bitWidth>
            </field>
            <field>
              <name>VLP</name>
              <bitOffset>18</bitOffset>
              <bitWidth>1</bitWidth>
            </field>
            <field>
              <name>CSVL</name>
              <bitOffset>19</bitOffset>
              <bitWidth>1</bitWidth>
            </field>
            <field>
              <name>VLTI</name>
              <bitOffset>20</bitOffset>
              <bitWidth>1</bitWidth>
            </field>
          </fields>
        </register>
        <register>
          <name>MACTFCR</name>
          <addressOffset>0x70</addressOffset>
          <size>0x20</size>
          <fields>
            <field>
              <name>FCB</name>
              <bitOffset>0</bitOffset>
              <bitWidth>1</bitWidth>
            </field>
            <field>
              <name>TFE</name>
              <bitOffset>1</bitOffset>
              <bitWidth>1</bitWidth>
            </field>
            <field>
              <name>PLT_MINUS512</name>
              <bitOffset>4</bitOffset>
              <bitWidth>3</bitWidth>
            </field>
            <field>
              <name>PLT_MINUS36</name>
              <bitOffset>5</bitOffset>
              <bitWidth>1</bitWidth>
            </field>
            <field>
              <name>PLT_MINUS256</name>
              <bitOffset>6</bitOffset>
              <bitWidth>1</bitWidth>
            </field>
            <field>
              <name>DZPQ</name>
              <bitOffset>7</bitOffset>
              <bitWidth>1</bitWidth>
            </field>
            <field>
              <name>PT</name>
              <bitOffset>16</bitOffset>
              <bitWidth>16</bitWidth>
            </field>
          </fields>
        </register>
        <register>
          <name>MACRFCR</name>
          <addressOffset>0x90</addressOffset>
          <size>0x20</size>
          <fields>
            <field>
              <name>RFE</name>
              <bitOffset>0</bitOffset>
              <bitWidth>1</bitWidth>
            </field>
            <field>
              <name>UP</name>
              <bitOffset>1</bitOffset>
              <bitWidth>1</bitWidth>
            </field>
          </fields>
        </register>
        <register>
          <name>MACISR</name>
          <addressOffset>0xb0</addressOffset>
          <size>0x20</size>
          <fields>
            <field>
              <name>PHYIS</name>
              <bitOffset>3</bitOffset>
              <bitWidth>1</bitWidth>
            </field>
            <field>
              <name>PMTIS</name>
              <bitOffset>4</bitOffset>
              <bitWidth>1</bitWidth>
            </field>
            <field>
              <name>LPIIS</name>
              <bitOffset>5</bitOffset>
              <bitWidth>1</bitWidth>
            </field>
            <field>
              <name>MMCIS</name>
              <bitOffset>8</bitOffset>
              <bitWidth>1</bitWidth>
            </field>
            <field>
              <name>MMCRXIS</name>
              <bitOffset>9</bitOffset>
              <bitWidth>1</bitWidth>
            </field>
            <field>
              <name>MMCTXIS</name>
              <bitOffset>10</bitOffset>
              <bitWidth>1</bitWidth>
            </field>
            <field>
              <name>TSIS</name>
              <bitOffset>12</bitOffset>
              <bitWidth>1</bitWidth>
            </field>
            <field>
              <name>TXSTSIS</name>
              <bitOffset>13</bitOffset>
              <bitWidth>1</bitWidth>
            </field>
            <field>
              <name>RXSTSIS</name>
              <bitOffset>14</bitOffset>
              <bitWidth>1</bitWidth>
            </field>
          </fields>
        </register>
        <register>
          <name>MACIER</name>
          <addressOffset>0xb4</addressOffset>
          <size>0x20</size>
          <fields>
            <field>
              <name>PHYIE</name>
              <bitOffset>3</bitOffset>
              <bitWidth>1</bitWidth>
            </field>
            <field>
              <name>PMTIE</name>
              <bitOffset>4</bitOffset>
              <bitWidth>1</bitWidth>
            </field>
            <field>
              <name>LPIIE</name>
              <bitOffset>5</bitOffset>
              <bitWidth>1</bitWidth>
            </field>
            <field>
              <name>TSIE</name>
              <bitOffset>12</bitOffset>
              <bitWidth>1</bitWidth>
            </field>
            <field>
              <name>TXSTSIE</name>
              <bitOffset>13</bitOffset>
              <bitWidth>1</bitWidth>
            </field>
            <field>
              <name>RXSTSIE</name>
              <bitOffset>14</bitOffset>
              <bitWidth>1</bitWidth>
            </field>
          </fields>
        </register>
        <register>
          <name>MACRXTXSR</name>
          <addressOffset>0xb8</addressOffset>
          <size>0x20</size>
          <fields>
            <field>
              <name>TJT</name>
              <bitOffset>0</bitOffset>
              <bitWidth>1</bitWidth>
            </field>
            <field>
              <name>NCARR</name>
              <bitOffset>1</bitOffset>
              <bitWidth>1</bitWidth>
            </field>
            <field>
              <name>LCARR</name>
              <bitOffset>2</bitOffset>
              <bitWidth>1</bitWidth>
            </field>
            <field>
              <name>EXDEF</name>
              <bitOffset>3</bitOffset>
              <bitWidth>1</bitWidth>
            </field>
            <field>
              <name>LCOL</name>
              <bitOffset>4</bitOffset>
              <bitWidth>1</bitWidth>
            </field>
            <field>
              <name>EXCOL</name>
              <bitOffset>5</bitOffset>
              <bitWidth>1</bitWidth>
            </field>
            <field>
              <name>RWT</name>
              <bitOffset>8</bitOffset>
              <bitWidth>1</bitWidth>
            </field>
          </fields>
        </register>
        <register>
          <name>MACPCSR</name>
          <addressOffset>0xc0</addressOffset>
          <size>0x20</size>
          <fields>
            <field>
              <name>PWRDWN</name>
              <bitOffset>0</bitOffset>
              <bitWidth>1</bitWidth>
            </field>
            <field>
              <name>MGKPKTEN</name>
              <bitOffset>1</bitOffset>
              <bitWidth>1</bitWidth>
            </field>
            <field>
              <name>RWKPKTEN</name>
              <bitOffset>2</bitOffset>
              <bitWidth>1</bitWidth>
            </field>
            <field>
              <name>MGKPRCVD</name>
              <bitOffset>5</bitOffset>
              <bitWidth>1</bitWidth>
            </field>
            <field>
              <name>RWKPRCVD</name>
              <bitOffset>6</bitOffset>
              <bitWidth>1</bitWidth>
            </field>
            <field>
              <name>GLBLUCAST</name>
              <bitOffset>9</bitOffset>
              <bitWidth>1</bitWidth>
            </field>
            <field>
              <name>RWKPFE</name>
              <bitOffset>10</bitOffset>
              <bitWidth>1</bitWidth>
            </field>
            <field>
              <name>RWKPTR</name>
              <bitOffset>24</bitOffset>
              <bitWidth>5</bitWidth>
            </field>
            <field>
              <name>RWKFILTRST</name>
              <bitOffset>31</bitOffset>
              <bitWidth>1</bitWidth>
            </field>
          </fields>
        </register>
        <register>
          <name>MACRWKPFR</name>
          <addressOffset>0xc4</addressOffset>
          <size>0x20</size>
        </register>
        <register>
          <name>MACLCSR</name>
          <addressOffset>0xd0</addressOffset>
          <size>0x20</size>
          <fields>
            <field>
              <name>TLPIEN</name>
              <bitOffset>0</bitOffset>
              <bitWidth>1</bitWidth>
            </field>
            <field>
              <name>TLPIEX</name>
              <bitOffset>1</bitOffset>
              <bitWidth>1</bitWidth>
            </field>
            <field>
              <name>RLPIEN</name>
              <bitOffset>2</bitOffset>
              <bitWidth>1</bitWidth>
            </field>
            <field>
              <name>RLPIEX</name>
              <bitOffset>3</bitOffset>
              <bitWidth>1</bitWidth>
            </field>
            <field>
              <name>TLPIST</name>
              <bitOffset>8</bitOffset>
              <bitWidth>1</bitWidth>
            </field>
            <field>
              <name>RLPIST</name>
              <bitOffset>9</bitOffset>
              <bitWidth>1</bitWidth>
            </field>
            <field>
              <name>LPIEN</name>
              <bitOffset>16</bitOffset>
              <bitWidth>1</bitWidth>
            </field>
            <field>
              <name>PLS</name>
              <bitOffset>17</bitOffset>
              <bitWidth>1</bitWidth>
            </field>
            <field>
              <name>LPITXA</name>
              <bitOffset>19</bitOffset>
              <bitWidth>1</bitWidth>
            </field>
            <field>
              <name>LPITE</name>
              <bitOffset>20</bitOffset>
              <bitWidth>1</bitWidth>
            </field>
            <field>
              <name>LPITCSE</name>
              <bitOffset>21</bitOffset>
              <bitWidth>1</bitWidth>
            </field>
          </fields>
        </register>
        <register>
          <name>MACLTCR</name>
          <addressOffset>0xd4</addressOffset>
          <size>0x20</size>
          <fields>
            <field>
              <name>TWT</name>
              <bitOffset>0</bitOffset>
              <bitWidth>16</bitWidth>
            </field>
            <field>
              <name>LST</name>
              <bitOffset>16</bitOffset>
              <bitWidth>10</bitWidth>
            </field>
          </fields>
        </register>
        <register>
          <name>MACLETR</name>
          <addressOffset>0xd8</addressOffset>
          <size>0x20</size>
          <fields>
            <field>
              <name>LPIET</name>
              <bitOffset>0</bitOffset>
              <bitWidth>20</bitWidth>
            </field>
          </fields>
        </register>
        <register>
          <name>MAC1USTCR</name>
          <addressOffset>0xdc</addressOffset>
          <size>0x20</size>
          <fields>
            <field>
              <name>TIC1USCNTR</name>
              <bitOffset>0</bitOffset>
              <bitWidth>12</bitWidth>
            </field>
          </fields>
        </register>
        <register>
          <name>MACVR</name>
          <addressOffset>0x110</addressOffset>
          <size>0x20</size>
          <fields>
            <field>
              <name>SNPSVER</name>
              <bitOffset>0</bitOffset>
              <bitWidth>8</bitWidth>
            </field>
            <field>
              <name>USERVER</name>
              <bitOffset>8</bitOffset>
              <bitWidth>8</bitWidth>
            </field>
          </fields>
        </register>
        <register>
          <name>MACDR</name>
          <addressOffset>0x114</addressOffset>
          <size>0x20</size>
          <fields>
            <field>
              <name>RPESTS</name>
              <bitOffset>0</bitOffset>
              <bitWidth>1</bitWidth>
            </field>
            <field>
              <name>RFCFCSTS</name>
              <bitOffset>1</bitOffset>
              <bitWidth>2</bitWidth>
            </field>
            <field>
              <name>TPESTS</name>
              <bitOffset>16</bitOffset>
              <bitWidth>1</bitWidth>
            </field>
            <field>
              <name>TFCSTS_WAIT</name>
              <bitOffset>17</bitOffset>
              <bitWidth>1</bitWidth>
            </field>
            <field>
              <name>TFCSTS_GENERATEPCP</name>
              <bitOffset>18</bitOffset>
              <bitWidth>1</bitWidth>
            </field>
          </fields>
        </register>
        <register>
          <name>MACHWF0R</name>
          <addressOffset>0x11c</addressOffset>
          <size>0x20</size>
          <fields>
            <field>
              <name>MIISEL</name>
              <bitOffset>0</bitOffset>
              <bitWidth>1</bitWidth>
            </field>
            <field>
              <name>GMIISEL</name>
              <bitOffset>1</bitOffset>
              <bitWidth>1</bitWidth>
            </field>
            <field>
              <name>HDSEL</name>
              <bitOffset>2</bitOffset>
              <bitWidth>1</bitWidth>
            </field>
            <field>
              <name>PCSSEL</name>
              <bitOffset>3</bitOffset>
              <bitWidth>1</bitWidth>
            </field>
            <field>
              <name>VLHASH</name>
              <bitOffset>4</bitOffset>
              <bitWidth>1</bitWidth>
            </field>
            <field>
              <name>SMASEL</name>
              <bitOffset>5</bitOffset>
              <bitWidth>1</bitWidth>
            </field>
            <field>
              <name>RWKSEL</name>
              <bitOffset>6</bitOffset>
              <bitWidth>1</bitWidth>
            </field>
            <field>
              <name>MGKSEL</name>
              <bitOffset>7</bitOffset>
              <bitWidth>1</bitWidth>
            </field>
            <field>
              <name>MMCSEL</name>
              <bitOffset>8</bitOffset>
              <bitWidth>1</bitWidth>
            </field>
            <field>
              <name>ARPOFFSEL</name>
              <bitOffset>9</bitOffset>
              <bitWidth>1</bitWidth>
            </field>
            <field>
              <name>TSSEL</name>
              <bitOffset>12</bitOffset>
              <bitWidth>1</bitWidth>
            </field>
            <field>
              <name>EEESEL</name>
              <bitOffset>13</bitOffset>
              <bitWidth>1</bitWidth>
            </field>
            <field>
              <name>TXCOESEL</name>
              <bitOffset>14</bitOffset>
              <bitWidth>1</bitWidth>
            </field>
            <field>
              <name>RXCOESEL</name>
              <bitOffset>16</bitOffset>
              <bitWidth>1</bitWidth>
            </field>
            <field>
              <name>ADDMACADRSEL</name>
              <bitOffset>18</bitOffset>
              <bitWidth>5</bitWidth>
            </field>
            <field>
              <name>MACADR32SEL</name>
              <bitOffset>23</bitOffset>
              <bitWidth>1</bitWidth>
            </field>
            <field>
              <name>MACADR64SEL</name>
              <bitOffset>24</bitOffset>
              <bitWidth>1</bitWidth>
            </field>
            <field>
              <name>TSSTSSEL_INTERNAL</name>
              <bitOffset>25</bitOffset>
              <bitWidth>1</bitWidth>
            </field>
            <field>
              <name>TSSTSSEL_EXTERNAL</name>
              <bitOffset>26</bitOffset>
              <bitWidth>1</bitWidth>
            </field>
            <field>
              <name>SAVLANINS</name>
              <bitOffset>27</bitOffset>
              <bitWidth>1</bitWidth>
            </field>
            <field>
              <name>ACTPHYSEL_REVMII</name>
              <bitOffset>28</bitOffset>
              <bitWidth>3</bitWidth>
            </field>
            <field>
              <name>ACTPHYSEL_RMII</name>
              <bitOffset>30</bitOffset>
              <bitWidth>1</bitWidth>
            </field>
          </fields>
        </register>
        <register>
          <name>MACHWF1R</name>
          <addressOffset>0x120</addressOffset>
          <size>0x20</size>
          <fields>
            <field>
              <name>RXFIFOSIZE</name>
              <bitOffset>0</bitOffset>
              <bitWidth>5</bitWidth>
            </field>
            <field>
              <name>TXFIFOSIZE</name>
              <bitOffset>6</bitOffset>
              <bitWidth>5</bitWidth>
            </field>
            <field>
              <name>OSTEN</name>
              <bitOffset>11</bitOffset>
              <bitWidth>1</bitWidth>
            </field>
            <field>
              <name>PTOEN</name>
              <bitOffset>12</bitOffset>
              <bitWidth>1</bitWidth>
            </field>
            <field>
              <name>ADVTHWORD</name>
              <bitOffset>13</bitOffset>
              <bitWidth>1</bitWidth>
            </field>
            <field>
              <name>ADDR64</name>
              <bitOffset>14</bitOffset>
              <bitWidth>2</bitWidth>
            </field>
            <field>
              <name>DCBEN</name>
              <bitOffset>16</bitOffset>
              <bitWidth>1</bitWidth>
            </field>
            <field>
              <name>SPHEN</name>
              <bitOffset>17</bitOffset>
              <bitWidth>1</bitWidth>
            </field>
            <field>
              <name>TSOEN</name>
              <bitOffset>18</bitOffset>
              <bitWidth>1</bitWidth>
            </field>
            <field>
              <name>DBGMEMA</name>
              <bitOffset>19</bitOffset>
              <bitWidth>1</bitWidth>
            </field>
            <field>
              <name>AVSEL</name>
              <bitOffset>20</bitOffset>
              <bitWidth>1</bitWidth>
            </field>
            <field>
              <name>HASHTBLSZ</name>
              <bitOffset>24</bitOffset>
              <bitWidth>2</bitWidth>
            </field>
            <field>
              <name>L3L4FNUM</name>
              <bitOffset>27</bitOffset>
              <bitWidth>4</bitWidth>
            </field>
          </fields>
        </register>
        <register>
          <name>MACHWF2R</name>
          <addressOffset>0x124</addressOffset>
          <size>0x20</size>
          <fields>
            <field>
              <name>RXQCNT</name>
              <bitOffset>0</bitOffset>
              <bitWidth>4</bitWidth>
            </field>
            <field>
              <name>TXQCNT</name>
              <bitOffset>6</bitOffset>
              <bitWidth>4</bitWidth>
            </field>
            <field>
              <name>RXCHCNT</name>
              <bitOffset>13</bitOffset>
              <bitWidth>3</bitWidth>
            </field>
            <field>
              <name>TXCHCNT</name>
              <bitOffset>18</bitOffset>
              <bitWidth>4</bitWidth>
            </field>
            <field>
              <name>PPSOUTNUM</name>
              <bitOffset>24</bitOffset>
              <bitWidth>3</bitWidth>
            </field>
            <field>
              <name>AUXSNAPNUM</name>
              <bitOffset>28</bitOffset>
              <bitWidth>3</bitWidth>
            </field>
          </fields>
        </register>
        <register>
          <name>MACMDIOAR</name>
          <addressOffset>0x200</addressOffset>
          <size>0x20</size>
          <fields>
            <field>
              <name>MB</name>
              <bitOffset>0</bitOffset>
              <bitWidth>1</bitWidth>
            </field>
            <field>
              <name>C45E</name>
              <bitOffset>1</bitOffset>
              <bitWidth>1</bitWidth>
            </field>
            <field>
              <name>MOC_WR</name>
              <bitOffset>2</bitOffset>
              <bitWidth>1</bitWidth>
            </field>
            <field>
              <name>MOC_PRDIA</name>
              <bitOffset>3</bitOffset>
              <bitWidth>1</bitWidth>
            </field>
            <field>
              <name>SKAP</name>
              <bitOffset>4</bitOffset>
              <bitWidth>1</bitWidth>
            </field>
            <field>
              <name>CR_DIV6AR</name>
              <bitOffset>8</bitOffset>
              <bitWidth>4</bitWidth>
            </field>
            <field>
              <name>CR_DIV8AR</name>
              <bitOffset>9</bitOffset>
              <bitWidth>3</bitWidth>
            </field>
            <field>
              <name>CR_DIV12AR</name>
              <bitOffset>10</bitOffset>
              <bitWidth>2</bitWidth>
            </field>
            <field>
              <name>CR_DIV4AR</name>
              <bitOffset>11</bitOffset>
              <bitWidth>1</bitWidth>
            </field>
            <field>
              <name>NTC</name>
              <bitOffset>12</bitOffset>
              <bitWidth>3</bitWidth>
            </field>
            <field>
              <name>RDA</name>
              <bitOffset>16</bitOffset>
              <bitWidth>5</bitWidth>
            </field>
            <field>
              <name>PA</name>
              <bitOffset>21</bitOffset>
              <bitWidth>5</bitWidth>
            </field>
            <field>
              <name>BTB</name>
              <bitOffset>26</bitOffset>
              <bitWidth>1</bitWidth>
            </field>
            <field>
              <name>PSE</name>
              <bitOffset>27</bitOffset>
              <bitWidth>1</bitWidth>
            </field>
          </fields>
        </register>
        <register>
          <name>MACMDIODR</name>
          <addressOffset>0x204</addressOffset>
          <size>0x20</size>
          <fields>
            <field>
              <name>MD</name>
              <bitOffset>0</bitOffset>
              <bitWidth>16</bitWidth>
            </field>
            <field>
              <name>RA</name>
              <bitOffset>16</bitOffset>
              <bitWidth>16</bitWidth>
            </field>
          </fields>
        </register>
        <register>
          <name>MACARPAR</name>
          <addressOffset>0x210</addressOffset>
          <size>0x20</size>
          <fields>
            <field>
              <name>ARPPA</name>
              <bitOffset>0</bitOffset>
              <bitWidth>32</bitWidth>
            </field>
          </fields>
        </register>
        <register>
          <name>MACA0HR</name>
          <addressOffset>0x300</addressOffset>
          <size>0x20</size>
          <fields>
            <field>
              <name>ADDRHI</name>
              <bitOffset>0</bitOffset>
              <bitWidth>16</bitWidth>
            </field>
            <field>
              <name>AE</name>
              <bitOffset>31</bitOffset>
              <bitWidth>1</bitWidth>
            </field>
          </fields>
        </register>
        <register>
          <name>MACA0LR</name>
          <addressOffset>0x304</addressOffset>
          <size>0x20</size>
          <fields>
            <field>
              <name>ADDRLO</name>
              <bitOffset>0</bitOffset>
              <bitWidth>32</bitWidth>
            </field>
          </fields>
        </register>
        <register>
          <name>MACA1HR</name>
          <addressOffset>0x308</addressOffset>
          <size>0x20</size>
          <fields>
            <field>
              <name>ADDRHI</name>
              <bitOffset>0</bitOffset>
              <bitWidth>16</bitWidth>
            </field>
            <field>
              <name>MBC</name>
              <bitOffset>24</bitOffset>
              <bitWidth>6</bitWidth>
            </field>
            <field>
              <name>SA</name>
              <bitOffset>30</bitOffset>
              <bitWidth>1</bitWidth>
            </field>
            <field>
              <name>AE</name>
              <bitOffset>31</bitOffset>
              <bitWidth>1</bitWidth>
            </field>
          </fields>
        </register>
        <register>
          <name>MACA1LR</name>
          <addressOffset>0x30c</addressOffset>
          <size>0x20</size>
          <fields>
            <field>
              <name>ADDRLO</name>
              <bitOffset>0</bitOffset>
              <bitWidth>32</bitWidth>
            </field>
          </fields>
        </register>
        <register>
          <name>MACA2HR</name>
          <addressOffset>0x310</addressOffset>
          <size>0x20</size>
          <fields>
            <field>
              <name>ADDRHI</name>
              <bitOffset>0</bitOffset>
              <bitWidth>16</bitWidth>
            </field>
            <field>
              <name>MBC</name>
              <bitOffset>24</bitOffset>
              <bitWidth>6</bitWidth>
            </field>
            <field>
              <name>SA</name>
              <bitOffset>30</bitOffset>
              <bitWidth>1</bitWidth>
            </field>
            <field>
              <name>AE</name>
              <bitOffset>31</bitOffset>
              <bitWidth>1</bitWidth>
            </field>
          </fields>
        </register>
        <register>
          <name>MACA2LR</name>
          <addressOffset>0x314</addressOffset>
          <size>0x20</size>
          <fields>
            <field>
              <name>ADDRLO</name>
              <bitOffset>0</bitOffset>
              <bitWidth>32</bitWidth>
            </field>
          </fields>
        </register>
        <register>
          <name>MACA3HR</name>
          <addressOffset>0x318</addressOffset>
          <size>0x20</size>
          <fields>
            <field>
              <name>ADDRHI</name>
              <bitOffset>0</bitOffset>
              <bitWidth>16</bitWidth>
            </field>
            <field>
              <name>MBC</name>
              <bitOffset>24</bitOffset>
              <bitWidth>6</bitWidth>
            </field>
            <field>
              <name>SA</name>
              <bitOffset>30</bitOffset>
              <bitWidth>1</bitWidth>
            </field>
            <field>
              <name>AE</name>
              <bitOffset>31</bitOffset>
              <bitWidth>1</bitWidth>
            </field>
          </fields>
        </register>
        <register>
          <name>MACA3LR</name>
          <addressOffset>0x31c</addressOffset>
          <size>0x20</size>
          <fields>
            <field>
              <name>ADDRLO</name>
              <bitOffset>0</bitOffset>
              <bitWidth>32</bitWidth>
            </field>
          </fields>
        </register>
        <register>
          <name>MMCCR</name>
          <addressOffset>0x700</addressOffset>
          <size>0x20</size>
          <fields>
            <field>
              <name>CNTRST</name>
              <bitOffset>0</bitOffset>
              <bitWidth>1</bitWidth>
            </field>
            <field>
              <name>CNTSTOPRO</name>
              <bitOffset>1</bitOffset>
              <bitWidth>1</bitWidth>
            </field>
            <field>
              <name>RSTONRD</name>
              <bitOffset>2</bitOffset>
              <bitWidth>1</bitWidth>
            </field>
            <field>
              <name>CNTFREEZ</name>
              <bitOffset>3</bitOffset>
              <bitWidth>1</bitWidth>
            </field>
            <field>
              <name>CNTPRST</name>
              <bitOffset>4</bitOffset>
              <bitWidth>1</bitWidth>
            </field>
            <field>
              <name>CNTPRSTLVL</name>
              <bitOffset>5</bitOffset>
              <bitWidth>1</bitWidth>
            </field>
            <field>
              <name>UCDBC</name>
              <bitOffset>8</bitOffset>
              <bitWidth>1</bitWidth>
            </field>
          </fields>
        </register>
        <register>
          <name>MMCRIR</name>
          <addressOffset>0x704</addressOffset>
          <size>0x20</size>
          <fields>
            <field>
              <name>RXCRCERPIS</name>
              <bitOffset>5</bitOffset>
              <bitWidth>1</bitWidth>
            </field>
            <field>
              <name>RXALGNERPIS</name>
              <bitOffset>6</bitOffset>
              <bitWidth>1</bitWidth>
            </field>
            <field>
              <name>RXUCGPIS</name>
              <bitOffset>17</bitOffset>
              <bitWidth>1</bitWidth>
            </field>
            <field>
              <name>RXLPIUSCIS</name>
              <bitOffset>26</bitOffset>
              <bitWidth>1</bitWidth>
            </field>
            <field>
              <name>RXLPITRCIS</name>
              <bitOffset>27</bitOffset>
              <bitWidth>1</bitWidth>
            </field>
          </fields>
        </register>
        <register>
          <name>MMCTIR</name>
          <addressOffset>0x708</addressOffset>
          <size>0x20</size>
          <fields>
            <field>
              <name>TXSCOLGPIS</name>
              <bitOffset>14</bitOffset>
              <bitWidth>1</bitWidth>
            </field>
            <field>
              <name>TXMCOLGPIS</name>
              <bitOffset>15</bitOffset>
              <bitWidth>1</bitWidth>
            </field>
            <field>
              <name>TXGPKTIS</name>
              <bitOffset>21</bitOffset>
              <bitWidth>1</bitWidth>
            </field>
            <field>
              <name>TXLPIUSCIS</name>
              <bitOffset>26</bitOffset>
              <bitWidth>1</bitWidth>
            </field>
            <field>
              <name>TXLPITRCIS</name>
              <bitOffset>27</bitOffset>
              <bitWidth>1</bitWidth>
            </field>
          </fields>
        </register>
        <register>
          <name>MMCRIMR</name>
          <addressOffset>0x70c</addressOffset>
          <size>0x20</size>
          <fields>
            <field>
              <name>RXCRCERPIM</name>
              <bitOffset>5</bitOffset>
              <bitWidth>1</bitWidth>
            </field>
            <field>
              <name>RXALGNERPIM</name>
              <bitOffset>6</bitOffset>
              <bitWidth>1</bitWidth>
            </field>
            <field>
              <name>RXUCGPIM</name>
              <bitOffset>17</bitOffset>
              <bitWidth>1</bitWidth>
            </field>
            <field>
              <name>RXLPIUSCIM</name>
              <bitOffset>26</bitOffset>
              <bitWidth>1</bitWidth>
            </field>
            <field>
              <name>RXLPITRCIM</name>
              <bitOffset>27</bitOffset>
              <bitWidth>1</bitWidth>
            </field>
          </fields>
        </register>
        <register>
          <name>MMCTIMR</name>
          <addressOffset>0x710</addressOffset>
          <size>0x20</size>
          <fields>
            <field>
              <name>TXSCOLGPIM</name>
              <bitOffset>14</bitOffset>
              <bitWidth>1</bitWidth>
            </field>
            <field>
              <name>TXMCOLGPIM</name>
              <bitOffset>15</bitOffset>
              <bitWidth>1</bitWidth>
            </field>
            <field>
              <name>TXGPKTIM</name>
              <bitOffset>21</bitOffset>
              <bitWidth>1</bitWidth>
            </field>
            <field>
              <name>TXLPIUSCIM</name>
              <bitOffset>26</bitOffset>
              <bitWidth>1</bitWidth>
            </field>
            <field>
              <name>TXLPITRCIM</name>
              <bitOffset>27</bitOffset>
              <bitWidth>1</bitWidth>
            </field>
          </fields>
        </register>
        <register>
          <name>MMCTSCGPR</name>
          <addressOffset>0x74c</addressOffset>
          <size>0x20</size>
        </register>
        <register>
          <name>MMCTMCGPR</name>
          <addressOffset>0x750</addressOffset>
          <size>0x20</size>
        </register>
        <register>
          <name>MMCTPCGR</name>
          <addressOffset>0x768</addressOffset>
          <size>0x20</size>
        </register>
        <register>
          <name>MMCRCRCEPR</name>
          <addressOffset>0x794</addressOffset>
          <size>0x20</size>
        </register>
        <register>
          <name>MMCRAEPR</name>
          <addressOffset>0x798</addressOffset>
          <size>0x20</size>
        </register>
        <register>
          <name>MMCRUPGR</name>
          <addressOffset>0x7c4</addressOffset>
          <size>0x20</size>
        </register>
        <register>
          <name>MMCTLPIMSTR</name>
          <addressOffset>0x7ec</addressOffset>
          <size>0x20</size>
        </register>
        <register>
          <name>MMCTLPITCR</name>
          <addressOffset>0x7f0</addressOffset>
          <size>0x20</size>
        </register>
        <register>
          <name>MMCRLPIMSTR</name>
          <addressOffset>0x7f4</addressOffset>
          <size>0x20</size>
        </register>
        <register>
          <name>MMCRLPITCR</name>
          <addressOffset>0x7f8</addressOffset>
          <size>0x20</size>
        </register>
        <register>
          <name>MACL3L4C0R</name>
          <addressOffset>0x900</addressOffset>
          <size>0x20</size>
        </register>
        <register>
          <name>MACL4A0R</name>
          <addressOffset>0x904</addressOffset>
          <size>0x20</size>
        </register>
        <register>
          <name>MACL3A0R0R</name>
          <addressOffset>0x910</addressOffset>
          <size>0x20</size>
        </register>
        <register>
          <name>MACL3A1R0R</name>
          <addressOffset>0x914</addressOffset>
          <size>0x20</size>
        </register>
        <register>
          <name>MACL3A2R0R</name>
          <addressOffset>0x918</addressOffset>
          <size>0x20</size>
        </register>
        <register>
          <name>MACL3A3R0R</name>
          <addressOffset>0x91c</addressOffset>
          <size>0x20</size>
        </register>
        <register>
          <name>MACL3L4C1R</name>
          <addressOffset>0x930</addressOffset>
          <size>0x20</size>
        </register>
        <register>
          <name>MACL4A1R</name>
          <addressOffset>0x934</addressOffset>
          <size>0x20</size>
        </register>
        <register>
          <name>MACL3A0R1R</name>
          <addressOffset>0x940</addressOffset>
          <size>0x20</size>
        </register>
        <register>
          <name>MACL3A1R1R</name>
          <addressOffset>0x944</addressOffset>
          <size>0x20</size>
        </register>
        <register>
          <name>MACL3A2R1R</name>
          <addressOffset>0x948</addressOffset>
          <size>0x20</size>
        </register>
        <register>
          <name>MACL3A3R1R</name>
          <addressOffset>0x94c</addressOffset>
          <size>0x20</size>
        </register>
        <register>
          <name>MACTSCR</name>
          <addressOffset>0xb00</addressOffset>
          <size>0x20</size>
          <fields>
            <field>
              <name>TSENA</name>
              <bitOffset>0</bitOffset>
              <bitWidth>1</bitWidth>
            </field>
            <field>
              <name>TSCFUPDT</name>
              <bitOffset>1</bitOffset>
              <bitWidth>1</bitWidth>
            </field>
            <field>
              <name>TSINIT</name>
              <bitOffset>2</bitOffset>
              <bitWidth>1</bitWidth>
            </field>
            <field>
              <name>TSUPDT</name>
              <bitOffset>3</bitOffset>
              <bitWidth>1</bitWidth>
            </field>
            <field>
              <name>TSADDREG</name>
              <bitOffset>5</bitOffset>
              <bitWidth>1</bitWidth>
            </field>
            <field>
              <name>TSENALL</name>
              <bitOffset>8</bitOffset>
              <bitWidth>1</bitWidth>
            </field>
            <field>
              <name>TSCTRLSSR</name>
              <bitOffset>9</bitOffset>
              <bitWidth>1</bitWidth>
            </field>
            <field>
              <name>TSVER2ENA</name>
              <bitOffset>10</bitOffset>
              <bitWidth>1</bitWidth>
            </field>
            <field>
              <name>TSIPENA</name>
              <bitOffset>11</bitOffset>
              <bitWidth>1</bitWidth>
            </field>
            <field>
              <name>TSIPV6ENA</name>
              <bitOffset>12</bitOffset>
              <bitWidth>1</bitWidth>
            </field>
            <field>
              <name>TSIPV4ENA</name>
              <bitOffset>13</bitOffset>
              <bitWidth>1</bitWidth>
            </field>
            <field>
              <name>TSEVNTENA</name>
              <bitOffset>14</bitOffset>
              <bitWidth>1</bitWidth>
            </field>
            <field>
              <name>TSMSTRENA</name>
              <bitOffset>15</bitOffset>
              <bitWidth>1</bitWidth>
            </field>
            <field>
              <name>SNAPTYPSEL</name>
              <bitOffset>16</bitOffset>
              <bitWidth>2</bitWidth>
            </field>
            <field>
              <name>TSENMACADDR</name>
              <bitOffset>18</bitOffset>
              <bitWidth>1</bitWidth>
            </field>
            <field>
              <name>CSC</name>
              <bitOffset>19</bitOffset>
              <bitWidth>1</bitWidth>
            </field>
            <field>
              <name>TXTSSTSM</name>
              <bitOffset>24</bitOffset>
              <bitWidth>1</bitWidth>
            </field>
          </fields>
        </register>
        <register>
          <name>MACSSIR</name>
          <addressOffset>0xb04</addressOffset>
          <size>0x20</size>
        </register>
        <register>
          <name>MACSTSR</name>
          <addressOffset>0xb08</addressOffset>
          <size>0x20</size>
          <fields>
            <field>
              <name>TSS</name>
              <bitOffset>0</bitOffset>
              <bitWidth>32</bitWidth>
            </field>
          </fields>
        </register>
        <register>
          <name>MACSTNR</name>
          <addressOffset>0xb0c</addressOffset>
          <size>0x20</size>
          <fields>
            <field>
              <name>TSSS</name>
              <bitOffset>0</bitOffset>
              <bitWidth>31</bitWidth>
            </field>
          </fields>
        </register>
        <register>
          <name>MACSTSUR</name>
          <addressOffset>0xb10</addressOffset>
          <size>0x20</size>
          <fields>
            <field>
              <name>TSS</name>
              <bitOffset>0</bitOffset>
              <bitWidth>32</bitWidth>
            </field>
          </fields>
        </register>
        <register>
          <name>MACSTNUR</name>
          <addressOffset>0xb14</addressOffset>
          <size>0x20</size>
          <fields>
            <field>
              <name>TSSS</name>
              <bitOffset>0</bitOffset>
              <bitWidth>31</bitWidth>
            </field>
            <field>
              <name>ADDSUB</name>
              <bitOffset>31</bitOffset>
              <bitWidth>1</bitWidth>
            </field>
          </fields>
        </register>
        <register>
          <name>MACTSAR</name>
          <addressOffset>0xb18</addressOffset>
          <size>0x20</size>
          <fields>
            <field>
              <name>TSAR</name>
              <bitOffset>0</bitOffset>
              <bitWidth>32</bitWidth>
            </field>
          </fields>
        </register>
        <register>
          <name>MACTSSR</name>
          <addressOffset>0xb20</addressOffset>
          <size>0x20</size>
          <fields>
            <field>
              <name>TSSOVF</name>
              <bitOffset>0</bitOffset>
              <bitWidth>1</bitWidth>
            </field>
            <field>
              <name>TSTARGT0</name>
              <bitOffset>1</bitOffset>
              <bitWidth>1</bitWidth>
            </field>
            <field>
              <name>AUXTSTRIG</name>
              <bitOffset>2</bitOffset>
              <bitWidth>1</bitWidth>
            </field>
            <field>
              <name>TSTRGTERR0</name>
              <bitOffset>3</bitOffset>
              <bitWidth>1</bitWidth>
            </field>
            <field>
              <name>TXTSSIS</name>
              <bitOffset>15</bitOffset>
              <bitWidth>1</bitWidth>
            </field>
            <field>
              <name>ATSSTN</name>
              <bitOffset>16</bitOffset>
              <bitWidth>4</bitWidth>
            </field>
            <field>
              <name>ATSSTM</name>
              <bitOffset>24</bitOffset>
              <bitWidth>1</bitWidth>
            </field>
            <field>
              <name>ATSNS</name>
              <bitOffset>25</bitOffset>
              <bitWidth>5</bitWidth>
            </field>
          </fields>
        </register>
        <register>
          <name>MACTTSSNR</name>
          <addressOffset>0xb30</addressOffset>
          <size>0x20</size>
          <fields>
            <field>
              <name>TXTSSLO</name>
              <bitOffset>0</bitOffset>
              <bitWidth>31</bitWidth>
            </field>
            <field>
              <name>TXTSSMIS</name>
              <bitOffset>31</bitOffset>
              <bitWidth>1</bitWidth>
            </field>
          </fields>
        </register>
        <register>
          <name>MACTTSSSR</name>
          <addressOffset>0xb34</addressOffset>
          <size>0x20</size>
          <fields>
            <field>
              <name>TXTSSHI</name>
              <bitOffset>0</bitOffset>
              <bitWidth>32</bitWidth>
            </field>
          </fields>
        </register>
        <register>
          <name>MACACR</name>
          <addressOffset>0xb40</addressOffset>
          <size>0x20</size>
          <fields>
            <field>
              <name>ATSFC</name>
              <bitOffset>0</bitOffset>
              <bitWidth>1</bitWidth>
            </field>
            <field>
              <name>ATSEN0</name>
              <bitOffset>4</bitOffset>
              <bitWidth>1</bitWidth>
            </field>
            <field>
              <name>ATSEN1</name>
              <bitOffset>5</bitOffset>
              <bitWidth>1</bitWidth>
            </field>
            <field>
              <name>ATSEN2</name>
              <bitOffset>6</bitOffset>
              <bitWidth>1</bitWidth>
            </field>
            <field>
              <name>ATSEN3</name>
              <bitOffset>7</bitOffset>
              <bitWidth>1</bitWidth>
            </field>
          </fields>
        </register>
        <register>
          <name>MACATSNR</name>
          <addressOffset>0xb48</addressOffset>
          <size>0x20</size>
          <fields>
            <field>
              <name>AUXTSLO</name>
              <bitOffset>0</bitOffset>
              <bitWidth>31</bitWidth>
            </field>
          </fields>
        </register>
        <register>
          <name>MACATSSR</name>
          <addressOffset>0xb4c</addressOffset>
          <size>0x20</size>
          <fields>
            <field>
              <name>AUXTSHI</name>
              <bitOffset>0</bitOffset>
              <bitWidth>32</bitWidth>
            </field>
          </fields>
        </register>
        <register>
          <name>MACTSIACR</name>
          <addressOffset>0xb50</addressOffset>
          <size>0x20</size>
          <fields>
            <field>
              <name>OSTIAC</name>
              <bitOffset>0</bitOffset>
              <bitWidth>32</bitWidth>
            </field>
          </fields>
        </register>
        <register>
          <name>MACTSEACR</name>
          <addressOffset>0xb54</addressOffset>
          <size>0x20</size>
          <fields>
            <field>
              <name>OSTEAC</name>
              <bitOffset>0</bitOffset>
              <bitWidth>32</bitWidth>
            </field>
          </fields>
        </register>
        <register>
          <name>MACTSICNR</name>
          <addressOffset>0xb58</addressOffset>
          <size>0x20</size>
          <fields>
            <field>
              <name>TSIC</name>
              <bitOffset>0</bitOffset>
              <bitWidth>32</bitWidth>
            </field>
          </fields>
        </register>
        <register>
          <name>MACTSECNR</name>
          <addressOffset>0xb5c</addressOffset>
          <size>0x20</size>
          <fields>
            <field>
              <name>TSEC</name>
              <bitOffset>0</bitOffset>
              <bitWidth>32</bitWidth>
            </field>
          </fields>
        </register>
        <register>
          <name>MACPPSCR</name>
          <addressOffset>0xb70</addressOffset>
          <size>0x20</size>
          <fields>
            <field>
              <name>PPSCTRL</name>
              <bitOffset>0</bitOffset>
              <bitWidth>4</bitWidth>
            </field>
            <field>
              <name>PPSEN0</name>
              <bitOffset>4</bitOffset>
              <bitWidth>1</bitWidth>
            </field>
            <field>
              <name>TRGTMODSEL0</name>
              <bitOffset>5</bitOffset>
              <bitWidth>2</bitWidth>
            </field>
          </fields>
        </register>
        <register>
          <name>MACPPSTTSR</name>
          <addressOffset>0xb80</addressOffset>
          <size>0x20</size>
          <fields>
            <field>
              <name>TSTRH0</name>
              <bitOffset>0</bitOffset>
              <bitWidth>32</bitWidth>
            </field>
          </fields>
        </register>
        <register>
          <name>MACPPSTTNR</name>
          <addressOffset>0xb84</addressOffset>
          <size>0x20</size>
          <fields>
            <field>
              <name>TTSL0</name>
              <bitOffset>0</bitOffset>
              <bitWidth>31</bitWidth>
            </field>
            <field>
              <name>TRGTBUSY0</name>
              <bitOffset>31</bitOffset>
              <bitWidth>1</bitWidth>
            </field>
          </fields>
        </register>
        <register>
          <name>MACPPSIR</name>
          <addressOffset>0xb88</addressOffset>
          <size>0x20</size>
          <fields>
            <field>
              <name>PPSINT0</name>
              <bitOffset>0</bitOffset>
              <bitWidth>32</bitWidth>
            </field>
          </fields>
        </register>
        <register>
          <name>MACPPSWR</name>
          <addressOffset>0xb8c</addressOffset>
          <size>0x20</size>
          <fields>
            <field>
              <name>PPSWIDTH0</name>
              <bitOffset>0</bitOffset>
              <bitWidth>32</bitWidth>
            </field>
          </fields>
        </register>
        <register>
          <name>MACPOCR</name>
          <addressOffset>0xbc0</addressOffset>
          <size>0x20</size>
          <fields>
            <field>
              <name>PTOEN</name>
              <bitOffset>0</bitOffset>
              <bitWidth>1</bitWidth>
            </field>
            <field>
              <name>ASYNCEN</name>
              <bitOffset>1</bitOffset>
              <bitWidth>1</bitWidth>
            </field>
            <field>
              <name>APDREQEN</name>
              <bitOffset>2</bitOffset>
              <bitWidth>1</bitWidth>
            </field>
            <field>
              <name>ASYNCTRIG</name>
              <bitOffset>4</bitOffset>
              <bitWidth>1</bitWidth>
            </field>
            <field>
              <name>APDREQTRIG</name>
              <bitOffset>5</bitOffset>
              <bitWidth>1</bitWidth>
            </field>
            <field>
              <name>DRRDIS</name>
              <bitOffset>6</bitOffset>
              <bitWidth>1</bitWidth>
            </field>
            <field>
              <name>DN</name>
              <bitOffset>8</bitOffset>
              <bitWidth>8</bitWidth>
            </field>
          </fields>
        </register>
        <register>
          <name>MACSPI0R</name>
          <addressOffset>0xbc4</addressOffset>
          <size>0x20</size>
          <fields>
            <field>
              <name>SPI0</name>
              <bitOffset>0</bitOffset>
              <bitWidth>32</bitWidth>
            </field>
          </fields>
        </register>
        <register>
          <name>MACSPI1R</name>
          <addressOffset>0xbc8</addressOffset>
          <size>0x20</size>
          <fields>
            <field>
              <name>SPI1</name>
              <bitOffset>0</bitOffset>
              <bitWidth>32</bitWidth>
            </field>
          </fields>
        </register>
        <register>
          <name>MACSPI2R</name>
          <addressOffset>0xbcc</addressOffset>
          <size>0x20</size>
          <fields>
            <field>
              <name>SPI2</name>
              <bitOffset>0</bitOffset>
              <bitWidth>16</bitWidth>
            </field>
          </fields>
        </register>
        <register>
          <name>MACLMIR</name>
          <addressOffset>0xbd0</addressOffset>
          <size>0x20</size>
          <fields>
            <field>
              <name>LSI</name>
              <bitOffset>0</bitOffset>
              <bitWidth>8</bitWidth>
            </field>
            <field>
              <name>DRSYNCR</name>
              <bitOffset>8</bitOffset>
              <bitWidth>3</bitWidth>
            </field>
            <field>
              <name>LMPDRI</name>
              <bitOffset>24</bitOffset>
              <bitWidth>8</bitWidth>
            </field>
          </fields>
        </register>
        <register>
          <name>MTLOMR</name>
          <addressOffset>0xc00</addressOffset>
          <size>0x20</size>
          <fields>
            <field>
              <name>DTXSTS</name>
              <bitOffset>1</bitOffset>
              <bitWidth>1</bitWidth>
            </field>
            <field>
              <name>CNTPRST</name>
              <bitOffset>8</bitOffset>
              <bitWidth>1</bitWidth>
            </field>
            <field>
              <name>CNTCLR</name>
              <bitOffset>9</bitOffset>
              <bitWidth>1</bitWidth>
            </field>
          </fields>
        </register>
        <register>
          <name>MTLISR</name>
          <addressOffset>0xc20</addressOffset>
          <size>0x20</size>
          <fields>
            <field>
              <name>QIS</name>
              <bitOffset>0</bitOffset>
              <bitWidth>1</bitWidth>
            </field>
            <field>
              <name>MACIS</name>
              <bitOffset>16</bitOffset>
              <bitWidth>1</bitWidth>
            </field>
          </fields>
        </register>
        <register>
          <name>MTLTQOMR</name>
          <addressOffset>0xd00</addressOffset>
          <size>0x20</size>
          <fields>
            <field>
              <name>FTQ</name>
              <bitOffset>0</bitOffset>
              <bitWidth>1</bitWidth>
            </field>
            <field>
              <name>TSF</name>
              <bitOffset>1</bitOffset>
              <bitWidth>1</bitWidth>
            </field>
            <field>
              <name>TTC</name>
              <bitOffset>4</bitOffset>
              <bitWidth>3</bitWidth>
            </field>
          </fields>
        </register>
        <register>
          <name>MTLTQUR</name>
          <addressOffset>0xd04</addressOffset>
          <size>0x20</size>
          <fields>
            <field>
              <name>UFPKTCNT</name>
              <bitOffset>0</bitOffset>
              <bitWidth>11</bitWidth>
            </field>
            <field>
              <name>UFCNTOVF</name>
              <bitOffset>11</bitOffset>
              <bitWidth>1</bitWidth>
            </field>
          </fields>
        </register>
        <register>
          <name>MTLTQDR</name>
          <addressOffset>0xd08</addressOffset>
          <size>0x20</size>
          <fields>
            <field>
              <name>TXQPAUSED</name>
              <bitOffset>0</bitOffset>
              <bitWidth>1</bitWidth>
            </field>
            <field>
              <name>TRCSTS</name>
              <bitOffset>1</bitOffset>
              <bitWidth>2</bitWidth>
            </field>
            <field>
              <name>TWCSTS</name>
              <bitOffset>3</bitOffset>
              <bitWidth>1</bitWidth>
            </field>
            <field>
              <name>TXQSTS</name>
              <bitOffset>4</bitOffset>
              <bitWidth>1</bitWidth>
            </field>
            <field>
              <name>TXSTSFSTS</name>
              <bitOffset>5</bitOffset>
              <bitWidth>1</bitWidth>
            </field>
            <field>
              <name>PTXQ</name>
              <bitOffset>16</bitOffset>
              <bitWidth>3</bitWidth>
            </field>
            <field>
              <name>STXSTSF</name>
              <bitOffset>20</bitOffset>
              <bitWidth>3</bitWidth>
            </field>
          </fields>
        </register>
        <register>
          <name>MTLQICSR</name>
          <addressOffset>0xd2c</addressOffset>
          <size>0x20</size>
          <fields>
            <field>
              <name>TXUNFIS</name>
              <bitOffset>0</bitOffset>
              <bitWidth>1</bitWidth>
            </field>
            <field>
              <name>TXUIE</name>
              <bitOffset>8</bitOffset>
              <bitWidth>1</bitWidth>
            </field>
            <field>
              <name>RXOVFIS</name>
              <bitOffset>16</bitOffset>
              <bitWidth>1</bitWidth>
            </field>
            <field>
              <name>RXOIE</name>
              <bitOffset>24</bitOffset>
              <bitWidth>1</bitWidth>
            </field>
          </fields>
        </register>
        <register>
          <name>MTLRQOMR</name>
          <addressOffset>0xd30</addressOffset>
          <size>0x20</size>
          <fields>
            <field>
              <name>RTC</name>
              <bitOffset>0</bitOffset>
              <bitWidth>2</bitWidth>
            </field>
            <field>
              <name>FUP</name>
              <bitOffset>3</bitOffset>
              <bitWidth>1</bitWidth>
            </field>
            <field>
              <name>FEP</name>
              <bitOffset>4</bitOffset>
              <bitWidth>1</bitWidth>
            </field>
            <field>
              <name>RSF</name>
              <bitOffset>5</bitOffset>
              <bitWidth>1</bitWidth>
            </field>
            <field>
              <name>DISTCPEF</name>
              <bitOffset>6</bitOffset>
              <bitWidth>1</bitWidth>
            </field>
            <field>
              <name>EHFC</name>
              <bitOffset>7</bitOffset>
              <bitWidth>1</bitWidth>
            </field>
            <field>
              <name>RFA</name>
              <bitOffset>8</bitOffset>
              <bitWidth>3</bitWidth>
            </field>
            <field>
              <name>RFD</name>
              <bitOffset>14</bitOffset>
              <bitWidth>3</bitWidth>
            </field>
            <field>
              <name>RQS</name>
              <bitOffset>20</bitOffset>
              <bitWidth>3</bitWidth>
            </field>
          </fields>
        </register>
        <register>
          <name>MTLRQMPOCR</name>
          <addressOffset>0xd34</addressOffset>
          <size>0x20</size>
          <fields>
            <field>
              <name>OVFPKTCNT</name>
              <bitOffset>0</bitOffset>
              <bitWidth>11</bitWidth>
            </field>
            <field>
              <name>OVFCNTOVF</name>
              <bitOffset>11</bitOffset>
              <bitWidth>1</bitWidth>
            </field>
            <field>
              <name>MISPKTCNT</name>
              <bitOffset>16</bitOffset>
              <bitWidth>11</bitWidth>
            </field>
            <field>
              <name>MISCNTOVF</name>
              <bitOffset>27</bitOffset>
              <bitWidth>1</bitWidth>
            </field>
          </fields>
        </register>
        <register>
          <name>MTLRQDR</name>
          <addressOffset>0xd38</addressOffset>
          <size>0x20</size>
          <fields>
            <field>
              <name>RWCSTS</name>
              <bitOffset>0</bitOffset>
              <bitWidth>1</bitWidth>
            </field>
            <field>
              <name>RRCSTS_READINGDATA</name>
              <bitOffset>1</bitOffset>
              <bitWidth>1</bitWidth>
            </field>
            <field>
              <name>RRCSTS_READINGSTATUS</name>
              <bitOffset>2</bitOffset>
              <bitWidth>1</bitWidth>
            </field>
            <field>
              <name>RXQSTS_FULL</name>
              <bitOffset>4</bitOffset>
              <bitWidth>2</bitWidth>
            </field>
            <field>
              <name>RXQSTS_ABOVETHRESHOLD</name>
              <bitOffset>5</bitOffset>
              <bitWidth>1</bitWidth>
            </field>
            <field>
              <name>PRXQ</name>
              <bitOffset>16</bitOffset>
              <bitWidth>14</bitWidth>
            </field>
          </fields>
        </register>
        <register>
          <name>DMAMR</name>
          <addressOffset>0x1000</addressOffset>
          <size>0x20</size>
          <fields>
            <field>
              <name>SWR</name>
              <bitOffset>0</bitOffset>
              <bitWidth>1</bitWidth>
            </field>
            <field>
              <name>DA</name>
              <bitOffset>1</bitOffset>
              <bitWidth>1</bitWidth>
            </field>
            <field>
              <name>TXPR</name>
              <bitOffset>11</bitOffset>
              <bitWidth>1</bitWidth>
            </field>
            <field>
              <name>PR</name>
              <bitOffset>12</bitOffset>
              <bitWidth>3</bitWidth>
            </field>
            <field>
              <name>INTM</name>
              <bitOffset>16</bitOffset>
              <bitWidth>2</bitWidth>
            </field>
          </fields>
        </register>
        <register>
          <name>DMASBMR</name>
          <addressOffset>0x1004</addressOffset>
          <size>0x20</size>
          <fields>
            <field>
              <name>FB</name>
              <bitOffset>0</bitOffset>
              <bitWidth>1</bitWidth>
            </field>
            <field>
              <name>AAL</name>
              <bitOffset>12</bitOffset>
              <bitWidth>1</bitWidth>
            </field>
            <field>
              <name>MB</name>
              <bitOffset>14</bitOffset>
              <bitWidth>1</bitWidth>
            </field>
            <field>
              <name>RB</name>
              <bitOffset>15</bitOffset>
              <bitWidth>1</bitWidth>
            </field>
          </fields>
        </register>
        <register>
          <name>DMAISR</name>
          <addressOffset>0x1008</addressOffset>
          <size>0x20</size>
          <fields>
            <field>
              <name>DMACIS</name>
              <bitOffset>0</bitOffset>
              <bitWidth>1</bitWidth>
            </field>
            <field>
              <name>MTLIS</name>
              <bitOffset>16</bitOffset>
              <bitWidth>1</bitWidth>
            </field>
            <field>
              <name>MACIS</name>
              <bitOffset>17</bitOffset>
              <bitWidth>1</bitWidth>
            </field>
          </fields>
        </register>
        <register>
          <name>DMADSR</name>
          <addressOffset>0x100c</addressOffset>
          <size>0x20</size>
          <fields>
            <field>
              <name>RPS</name>
              <bitOffset>8</bitOffset>
              <bitWidth>4</bitWidth>
            </field>
            <field>
              <name>TPS_READING</name>
              <bitOffset>12</bitOffset>
              <bitWidth>2</bitWidth>
            </field>
            <field>
              <name>TPS_WAITING</name>
              <bitOffset>13</bitOffset>
              <bitWidth>1</bitWidth>
            </field>
            <field>
              <name>TPS_TIMESTAMP_WR</name>
              <bitOffset>14</bitOffset>
              <bitWidth>1</bitWidth>
            </field>
          </fields>
        </register>
        <register>
          <name>DMACCR</name>
          <addressOffset>0x1100</addressOffset>
          <size>0x20</size>
          <fields>
            <field>
              <name>MSS</name>
              <bitOffset>0</bitOffset>
              <bitWidth>14</bitWidth>
            </field>
            <field>
              <name>DSL</name>
              <bitOffset>18</bitOffset>
              <bitWidth>3</bitWidth>
            </field>
          </fields>
        </register>
        <register>
          <name>DMACTCR</name>
          <addressOffset>0x1104</addressOffset>
          <size>0x20</size>
          <fields>
            <field>
              <name>ST</name>
              <bitOffset>0</bitOffset>
              <bitWidth>1</bitWidth>
            </field>
            <field>
              <name>OSP</name>
              <bitOffset>4</bitOffset>
              <bitWidth>1</bitWidth>
            </field>
            <field>
              <name>TSE</name>
              <bitOffset>12</bitOffset>
              <bitWidth>1</bitWidth>
            </field>
            <field>
              <name>TPBL</name>
              <bitOffset>16</bitOffset>
              <bitWidth>6</bitWidth>
            </field>
          </fields>
        </register>
        <register>
          <name>DMACRCR</name>
          <addressOffset>0x1108</addressOffset>
          <size>0x20</size>
          <fields>
            <field>
              <name>SR</name>
              <bitOffset>0</bitOffset>
              <bitWidth>1</bitWidth>
            </field>
            <field>
              <name>RBSZ</name>
              <bitOffset>1</bitOffset>
              <bitWidth>14</bitWidth>
            </field>
            <field>
              <name>RPBL</name>
              <bitOffset>16</bitOffset>
              <bitWidth>6</bitWidth>
            </field>
            <field>
              <name>RPF</name>
              <bitOffset>31</bitOffset>
              <bitWidth>1</bitWidth>
            </field>
          </fields>
        </register>
        <register>
          <name>DMACTDLAR</name>
          <addressOffset>0x1114</addressOffset>
          <size>0x20</size>
          <fields>
            <field>
              <name>TDESLA</name>
              <bitOffset>2</bitOffset>
              <bitWidth>30</bitWidth>
            </field>
          </fields>
        </register>
        <register>
          <name>DMACRDLAR</name>
          <addressOffset>0x111c</addressOffset>
          <size>0x20</size>
          <fields>
            <field>
              <name>RDESLA</name>
              <bitOffset>2</bitOffset>
              <bitWidth>30</bitWidth>
            </field>
          </fields>
        </register>
        <register>
          <name>DMACTDTPR</name>
          <addressOffset>0x1120</addressOffset>
          <size>0x20</size>
          <fields>
            <field>
              <name>TDT</name>
              <bitOffset>2</bitOffset>
              <bitWidth>30</bitWidth>
            </field>
          </fields>
        </register>
        <register>
          <name>DMACRDTPR</name>
          <addressOffset>0x1128</addressOffset>
          <size>0x20</size>
          <fields>
            <field>
              <name>RDT</name>
              <bitOffset>2</bitOffset>
              <bitWidth>30</bitWidth>
            </field>
          </fields>
        </register>
        <register>
          <name>DMACTDRLR</name>
          <addressOffset>0x112c</addressOffset>
          <size>0x20</size>
          <fields>
            <field>
              <name>TDRL</name>
              <bitOffset>0</bitOffset>
              <bitWidth>10</bitWidth>
            </field>
          </fields>
        </register>
        <register>
          <name>DMACRDRLR</name>
          <addressOffset>0x1130</addressOffset>
          <size>0x20</size>
          <fields>
            <field>
              <name>RDRL</name>
              <bitOffset>0</bitOffset>
              <bitWidth>10</bitWidth>
            </field>
          </fields>
        </register>
        <register>
          <name>DMACIER</name>
          <addressOffset>0x1134</addressOffset>
          <size>0x20</size>
          <fields>
            <field>
              <name>TIE</name>
              <bitOffset>0</bitOffset>
              <bitWidth>1</bitWidth>
            </field>
            <field>
              <name>TXSE</name>
              <bitOffset>1</bitOffset>
              <bitWidth>1</bitWidth>
            </field>
            <field>
              <name>TBUE</name>
              <bitOffset>2</bitOffset>
              <bitWidth>1</bitWidth>
            </field>
            <field>
              <name>RIE</name>
              <bitOffset>6</bitOffset>
              <bitWidth>1</bitWidth>
            </field>
            <field>
              <name>RBUE</name>
              <bitOffset>7</bitOffset>
              <bitWidth>1</bitWidth>
            </field>
            <field>
              <name>RSE</name>
              <bitOffset>8</bitOffset>
              <bitWidth>1</bitWidth>
            </field>
            <field>
              <name>RWTE</name>
              <bitOffset>9</bitOffset>
              <bitWidth>1</bitWidth>
            </field>
            <field>
              <name>ETIE</name>
              <bitOffset>10</bitOffset>
              <bitWidth>1</bitWidth>
            </field>
            <field>
              <name>ERIE</name>
              <bitOffset>11</bitOffset>
              <bitWidth>1</bitWidth>
            </field>
            <field>
              <name>FBEE</name>
              <bitOffset>12</bitOffset>
              <bitWidth>1</bitWidth>
            </field>
            <field>
              <name>CDEE</name>
              <bitOffset>13</bitOffset>
              <bitWidth>1</bitWidth>
            </field>
            <field>
              <name>AIE</name>
              <bitOffset>14</bitOffset>
              <bitWidth>1</bitWidth>
            </field>
            <field>
              <name>NIE</name>
              <bitOffset>15</bitOffset>
              <bitWidth>1</bitWidth>
            </field>
          </fields>
        </register>
        <register>
          <name>DMACRIWTR</name>
          <addressOffset>0x1138</addressOffset>
          <size>0x20</size>
          <fields>
            <field>
              <name>RWT</name>
              <bitOffset>0</bitOffset>
              <bitWidth>8</bitWidth>
            </field>
          </fields>
        </register>
        <register>
          <name>DMACSFCSR</name>
          <addressOffset>0x113c</addressOffset>
          <size>0x20</size>
        </register>
        <register>
          <name>DMACCATDR</name>
          <addressOffset>0x1144</addressOffset>
          <size>0x20</size>
          <fields>
            <field>
              <name>CURTDESAPTR</name>
              <bitOffset>0</bitOffset>
              <bitWidth>32</bitWidth>
            </field>
          </fields>
        </register>
        <register>
          <name>DMACCARDR</name>
          <addressOffset>0x114c</addressOffset>
          <size>0x20</size>
          <fields>
            <field>
              <name>CURRDESAPTR</name>
              <bitOffset>0</bitOffset>
              <bitWidth>32</bitWidth>
            </field>
          </fields>
        </register>
        <register>
          <name>DMACCATBR</name>
          <addressOffset>0x1154</addressOffset>
          <size>0x20</size>
          <fields>
            <field>
              <name>CURTBUFAPTR</name>
              <bitOffset>0</bitOffset>
              <bitWidth>32</bitWidth>
            </field>
          </fields>
        </register>
        <register>
          <name>DMACCARBR</name>
          <addressOffset>0x115c</addressOffset>
          <size>0x20</size>
          <fields>
            <field>
              <name>CURRBUFAPTR</name>
              <bitOffset>0</bitOffset>
              <bitWidth>32</bitWidth>
            </field>
          </fields>
        </register>
        <register>
          <name>DMACSR</name>
          <addressOffset>0x1160</addressOffset>
          <size>0x20</size>
          <fields>
            <field>
              <name>TI</name>
              <bitOffset>0</bitOffset>
              <bitWidth>1</bitWidth>
            </field>
            <field>
              <name>TPS</name>
              <bitOffset>1</bitOffset>
              <bitWidth>1</bitWidth>
            </field>
            <field>
              <name>TBU</name>
              <bitOffset>2</bitOffset>
              <bitWidth>1</bitWidth>
            </field>
            <field>
              <name>RI</name>
              <bitOffset>6</bitOffset>
              <bitWidth>1</bitWidth>
            </field>
            <field>
              <name>RBU</name>
              <bitOffset>7</bitOffset>
              <bitWidth>1</bitWidth>
            </field>
            <field>
              <name>RPS</name>
              <bitOffset>8</bitOffset>
              <bitWidth>1</bitWidth>
            </field>
            <field>
              <name>RWT</name>
              <bitOffset>9</bitOffset>
              <bitWidth>1</bitWidth>
            </field>
            <field>
              <name>ETI</name>
              <bitOffset>10</bitOffset>
              <bitWidth>1</bitWidth>
            </field>
            <field>
              <name>ERI</name>
              <bitOffset>11</bitOffset>
              <bitWidth>1</bitWidth>
            </field>
            <field>
              <name>FBE</name>
              <bitOffset>12</bitOffset>
              <bitWidth>1</bitWidth>
            </field>
            <field>
              <name>CDE</name>
              <bitOffset>13</bitOffset>
              <bitWidth>1</bitWidth>
            </field>
            <field>
              <name>AIS</name>
              <bitOffset>14</bitOffset>
              <bitWidth>1</bitWidth>
            </field>
            <field>
              <name>NIS</name>
              <bitOffset>15</bitOffset>
              <bitWidth>1</bitWidth>
            </field>
            <field>
              <name>TEB</name>
              <bitOffset>16</bitOffset>
              <bitWidth>3</bitWidth>
            </field>
            <field>
              <name>REB</name>
              <bitOffset>19</bitOffset>
              <bitWidth>3</bitWidth>
            </field>
          </fields>
        </register>
        <register>
          <name>DMACMFCR</name>
          <addressOffset>0x116c</addressOffset>
          <size>0x20</size>
          <fields>
            <field>
              <name>MFC</name>
              <bitOffset>0</bitOffset>
              <bitWidth>11</bitWidth>
            </field>
            <field>
              <name>MFCO</name>
              <bitOffset>15</bitOffset>
              <bitWidth>1</bitWidth>
            </field>
          </fields>
        </register>
      </registers>
    </peripheral>
    <peripheral>
      <name>USB1_OTG_HS</name>
      <baseAddress>0x40040000</baseAddress>
      <registers>
        <register>
          <name>GOTGCTL</name>
          <addressOffset>0x0</addressOffset>
          <size>0x20</size>
          <fields>
            <field>
              <name>SRQSCS</name>
              <bitOffset>0</bitOffset>
              <bitWidth>1</bitWidth>
            </field>
            <field>
              <name>SRQ</name>
              <bitOffset>1</bitOffset>
              <bitWidth>1</bitWidth>
            </field>
            <field>
              <name>VBVALOEN</name>
              <bitOffset>2</bitOffset>
              <bitWidth>1</bitWidth>
            </field>
            <field>
              <name>VBVALOVAL</name>
              <bitOffset>3</bitOffset>
              <bitWidth>1</bitWidth>
            </field>
            <field>
              <name>AVALOEN</name>
              <bitOffset>4</bitOffset>
              <bitWidth>1</bitWidth>
            </field>
            <field>
              <name>AVALOVAL</name>
              <bitOffset>5</bitOffset>
              <bitWidth>1</bitWidth>
            </field>
            <field>
              <name>BVALOEN</name>
              <bitOffset>6</bitOffset>
              <bitWidth>1</bitWidth>
            </field>
            <field>
              <name>BVALOVAL</name>
              <bitOffset>7</bitOffset>
              <bitWidth>1</bitWidth>
            </field>
            <field>
              <name>HNGSCS</name>
              <bitOffset>8</bitOffset>
              <bitWidth>1</bitWidth>
            </field>
            <field>
              <name>HNPRQ</name>
              <bitOffset>9</bitOffset>
              <bitWidth>1</bitWidth>
            </field>
            <field>
              <name>HSHNPEN</name>
              <bitOffset>10</bitOffset>
              <bitWidth>1</bitWidth>
            </field>
            <field>
              <name>DHNPEN</name>
              <bitOffset>11</bitOffset>
              <bitWidth>1</bitWidth>
            </field>
            <field>
              <name>EHEN</name>
              <bitOffset>12</bitOffset>
              <bitWidth>1</bitWidth>
            </field>
            <field>
              <name>CIDSTS</name>
              <bitOffset>16</bitOffset>
              <bitWidth>1</bitWidth>
            </field>
            <field>
              <name>DBCT</name>
              <bitOffset>17</bitOffset>
              <bitWidth>1</bitWidth>
            </field>
            <field>
              <name>ASVLD</name>
              <bitOffset>18</bitOffset>
              <bitWidth>1</bitWidth>
            </field>
            <field>
              <name>BSESVLD</name>
              <bitOffset>19</bitOffset>
              <bitWidth>1</bitWidth>
            </field>
            <field>
              <name>OTGVER</name>
              <bitOffset>20</bitOffset>
              <bitWidth>1</bitWidth>
            </field>
          </fields>
        </register>
        <register>
          <name>GOTGINT</name>
          <addressOffset>0x4</addressOffset>
          <size>0x20</size>
          <fields>
            <field>
              <name>SEDET</name>
              <bitOffset>2</bitOffset>
              <bitWidth>1</bitWidth>
            </field>
            <field>
              <name>SRSSCHG</name>
              <bitOffset>8</bitOffset>
              <bitWidth>1</bitWidth>
            </field>
            <field>
              <name>HNSSCHG</name>
              <bitOffset>9</bitOffset>
              <bitWidth>1</bitWidth>
            </field>
            <field>
              <name>HNGDET</name>
              <bitOffset>17</bitOffset>
              <bitWidth>1</bitWidth>
            </field>
            <field>
              <name>ADTOCHG</name>
              <bitOffset>18</bitOffset>
              <bitWidth>1</bitWidth>
            </field>
            <field>
              <name>DBCDNE</name>
              <bitOffset>19</bitOffset>
              <bitWidth>1</bitWidth>
            </field>
          </fields>
        </register>
        <register>
          <name>GAHBCFG</name>
          <addressOffset>0x8</addressOffset>
          <size>0x20</size>
          <fields>
            <field>
              <name>GINT</name>
              <bitOffset>0</bitOffset>
              <bitWidth>1</bitWidth>
            </field>
            <field>
              <name>HBSTLEN</name>
              <bitOffset>1</bitOffset>
              <bitWidth>4</bitWidth>
            </field>
            <field>
              <name>DMAEN</name>
              <bitOffset>5</bitOffset>
              <bitWidth>1</bitWidth>
            </field>
            <field>
              <name>TXFELVL</name>
              <bitOffset>7</bitOffset>
              <bitWidth>1</bitWidth>
            </field>
            <field>
              <name>PTXFELVL</name>
              <bitOffset>8</bitOffset>
              <bitWidth>1</bitWidth>
            </field>
          </fields>
        </register>
        <register>
          <name>GUSBCFG</name>
          <addressOffset>0xc</addressOffset>
          <size>0x20</size>
          <fields>
            <field>
              <name>TOCAL</name>
              <bitOffset>0</bitOffset>
              <bitWidth>3</bitWidth>
            </field>
            <field>
              <name>PHYSEL</name>
              <bitOffset>6</bitOffset>
              <bitWidth>1</bitWidth>
            </field>
            <field>
              <name>SRPCAP</name>
              <bitOffset>8</bitOffset>
              <bitWidth>1</bitWidth>
            </field>
            <field>
              <name>HNPCAP</name>
              <bitOffset>9</bitOffset>
              <bitWidth>1</bitWidth>
            </field>
            <field>
              <name>TRDT</name>
              <bitOffset>10</bitOffset>
              <bitWidth>4</bitWidth>
            </field>
            <field>
              <name>PHYLPCS</name>
              <bitOffset>15</bitOffset>
              <bitWidth>1</bitWidth>
            </field>
            <field>
              <name>ULPIFSLS</name>
              <bitOffset>17</bitOffset>
              <bitWidth>1</bitWidth>
            </field>
            <field>
              <name>ULPIAR</name>
              <bitOffset>18</bitOffset>
              <bitWidth>1</bitWidth>
            </field>
            <field>
              <name>ULPICSM</name>
              <bitOffset>19</bitOffset>
              <bitWidth>1</bitWidth>
            </field>
            <field>
              <name>ULPIEVBUSD</name>
              <bitOffset>20</bitOffset>
              <bitWidth>1</bitWidth>
            </field>
            <field>
              <name>ULPIEVBUSI</name>
              <bitOffset>21</bitOffset>
              <bitWidth>1</bitWidth>
            </field>
            <field>
              <name>TSDPS</name>
              <bitOffset>22</bitOffset>
              <bitWidth>1</bitWidth>
            </field>
            <field>
              <name>PCCI</name>
              <bitOffset>23</bitOffset>
              <bitWidth>1</bitWidth>
            </field>
            <field>
              <name>PTCI</name>
              <bitOffset>24</bitOffset>
              <bitWidth>1</bitWidth>
            </field>
            <field>
              <name>ULPIIPD</name>
              <bitOffset>25</bitOffset>
              <bitWidth>1</bitWidth>
            </field>
            <field>
              <name>FHMOD</name>
              <bitOffset>29</bitOffset>
              <bitWidth>1</bitWidth>
            </field>
            <field>
              <name>FDMOD</name>
              <bitOffset>30</bitOffset>
              <bitWidth>1</bitWidth>
            </field>
            <field>
              <name>CTXPKT</name>
              <bitOffset>31</bitOffset>
              <bitWidth>1</bitWidth>
            </field>
          </fields>
        </register>
        <register>
          <name>GRSTCTL</name>
          <addressOffset>0x10</addressOffset>
          <size>0x20</size>
          <fields>
            <field>
              <name>CSRST</name>
              <bitOffset>0</bitOffset>
              <bitWidth>1</bitWidth>
            </field>
            <field>
              <name>HSRST</name>
              <bitOffset>1</bitOffset>
              <bitWidth>1</bitWidth>
            </field>
            <field>
              <name>FCRST</name>
              <bitOffset>2</bitOffset>
              <bitWidth>1</bitWidth>
            </field>
            <field>
              <name>RXFFLSH</name>
              <bitOffset>4</bitOffset>
              <bitWidth>1</bitWidth>
            </field>
            <field>
              <name>TXFFLSH</name>
              <bitOffset>5</bitOffset>
              <bitWidth>1</bitWidth>
            </field>
            <field>
              <name>TXFNUM</name>
              <bitOffset>6</bitOffset>
              <bitWidth>5</bitWidth>
            </field>
            <field>
              <name>DMAREQ</name>
              <bitOffset>30</bitOffset>
              <bitWidth>1</bitWidth>
            </field>
            <field>
              <name>AHBIDL</name>
              <bitOffset>31</bitOffset>
              <bitWidth>1</bitWidth>
            </field>
          </fields>
        </register>
        <register>
          <name>GINTSTS</name>
          <addressOffset>0x14</addressOffset>
          <size>0x20</size>
          <fields>
            <field>
              <name>CMOD</name>
              <bitOffset>0</bitOffset>
              <bitWidth>1</bitWidth>
            </field>
            <field>
              <name>MMIS</name>
              <bitOffset>1</bitOffset>
              <bitWidth>1</bitWidth>
            </field>
            <field>
              <name>OTGINT</name>
              <bitOffset>2</bitOffset>
              <bitWidth>1</bitWidth>
            </field>
            <field>
              <name>SOF</name>
              <bitOffset>3</bitOffset>
              <bitWidth>1</bitWidth>
            </field>
            <field>
              <name>RXFLVL</name>
              <bitOffset>4</bitOffset>
              <bitWidth>1</bitWidth>
            </field>
            <field>
              <name>NPTXFE</name>
              <bitOffset>5</bitOffset>
              <bitWidth>1</bitWidth>
            </field>
            <field>
              <name>GINAKEFF</name>
              <bitOffset>6</bitOffset>
              <bitWidth>1</bitWidth>
            </field>
            <field>
              <name>BOUTNAKEFF</name>
              <bitOffset>7</bitOffset>
              <bitWidth>1</bitWidth>
            </field>
            <field>
              <name>ESUSP</name>
              <bitOffset>10</bitOffset>
              <bitWidth>1</bitWidth>
            </field>
            <field>
              <name>USBSUSP</name>
              <bitOffset>11</bitOffset>
              <bitWidth>1</bitWidth>
            </field>
            <field>
              <name>USBRST</name>
              <bitOffset>12</bitOffset>
              <bitWidth>1</bitWidth>
            </field>
            <field>
              <name>ENUMDNE</name>
              <bitOffset>13</bitOffset>
              <bitWidth>1</bitWidth>
            </field>
            <field>
              <name>ISOODRP</name>
              <bitOffset>14</bitOffset>
              <bitWidth>1</bitWidth>
            </field>
            <field>
              <name>EOPF</name>
              <bitOffset>15</bitOffset>
              <bitWidth>1</bitWidth>
            </field>
            <field>
              <name>IEPINT</name>
              <bitOffset>18</bitOffset>
              <bitWidth>1</bitWidth>
            </field>
            <field>
              <name>OEPINT</name>
              <bitOffset>19</bitOffset>
              <bitWidth>1</bitWidth>
            </field>
            <field>
              <name>IISOIXFR</name>
              <bitOffset>20</bitOffset>
              <bitWidth>1</bitWidth>
            </field>
            <field>
              <name>PXFR_INCOMPISOOUT</name>
              <bitOffset>21</bitOffset>
              <bitWidth>1</bitWidth>
            </field>
            <field>
              <name>DATAFSUSP</name>
              <bitOffset>22</bitOffset>
              <bitWidth>1</bitWidth>
            </field>
            <field>
              <name>RSTDET</name>
              <bitOffset>23</bitOffset>
              <bitWidth>1</bitWidth>
            </field>
            <field>
              <name>HPRTINT</name>
              <bitOffset>24</bitOffset>
              <bitWidth>1</bitWidth>
            </field>
            <field>
              <name>HCINT</name>
              <bitOffset>25</bitOffset>
              <bitWidth>1</bitWidth>
            </field>
            <field>
              <name>PTXFE</name>
              <bitOffset>26</bitOffset>
              <bitWidth>1</bitWidth>
            </field>
            <field>
              <name>LPMINT</name>
              <bitOffset>27</bitOffset>
              <bitWidth>1</bitWidth>
            </field>
            <field>
              <name>CIDSCHG</name>
              <bitOffset>28</bitOffset>
              <bitWidth>1</bitWidth>
            </field>
            <field>
              <name>DISCINT</name>
              <bitOffset>29</bitOffset>
              <bitWidth>1</bitWidth>
            </field>
            <field>
              <name>SRQINT</name>
              <bitOffset>30</bitOffset>
              <bitWidth>1</bitWidth>
            </field>
            <field>
              <name>WKUINT</name>
              <bitOffset>31</bitOffset>
              <bitWidth>1</bitWidth>
            </field>
          </fields>
        </register>
        <register>
          <name>GINTMSK</name>
          <addressOffset>0x18</addressOffset>
          <size>0x20</size>
          <fields>
            <field>
              <name>MMISM</name>
              <bitOffset>1</bitOffset>
              <bitWidth>1</bitWidth>
            </field>
            <field>
              <name>OTGINT</name>
              <bitOffset>2</bitOffset>
              <bitWidth>1</bitWidth>
            </field>
            <field>
              <name>SOFM</name>
              <bitOffset>3</bitOffset>
              <bitWidth>1</bitWidth>
            </field>
            <field>
              <name>RXFLVLM</name>
              <bitOffset>4</bitOffset>
              <bitWidth>1</bitWidth>
            </field>
            <field>
              <name>NPTXFEM</name>
              <bitOffset>5</bitOffset>
              <bitWidth>1</bitWidth>
            </field>
            <field>
              <name>GINAKEFFM</name>
              <bitOffset>6</bitOffset>
              <bitWidth>1</bitWidth>
            </field>
            <field>
              <name>GONAKEFFM</name>
              <bitOffset>7</bitOffset>
              <bitWidth>1</bitWidth>
            </field>
            <field>
              <name>ESUSPM</name>
              <bitOffset>10</bitOffset>
              <bitWidth>1</bitWidth>
            </field>
            <field>
              <name>USBSUSPM</name>
              <bitOffset>11</bitOffset>
              <bitWidth>1</bitWidth>
            </field>
            <field>
              <name>USBRST</name>
              <bitOffset>12</bitOffset>
              <bitWidth>1</bitWidth>
            </field>
            <field>
              <name>ENUMDNEM</name>
              <bitOffset>13</bitOffset>
              <bitWidth>1</bitWidth>
            </field>
            <field>
              <name>ISOODRPM</name>
              <bitOffset>14</bitOffset>
              <bitWidth>1</bitWidth>
            </field>
            <field>
              <name>EOPFM</name>
              <bitOffset>15</bitOffset>
              <bitWidth>1</bitWidth>
            </field>
            <field>
              <name>EPMISM</name>
              <bitOffset>17</bitOffset>
              <bitWidth>1</bitWidth>
            </field>
            <field>
              <name>IEPINT</name>
              <bitOffset>18</bitOffset>
              <bitWidth>1</bitWidth>
            </field>
            <field>
              <name>OEPINT</name>
              <bitOffset>19</bitOffset>
              <bitWidth>1</bitWidth>
            </field>
            <field>
              <name>IISOIXFRM</name>
              <bitOffset>20</bitOffset>
              <bitWidth>1</bitWidth>
            </field>
            <field>
              <name>PXFRM_IISOOXFRM</name>
              <bitOffset>21</bitOffset>
              <bitWidth>1</bitWidth>
            </field>
            <field>
              <name>FSUSPM</name>
              <bitOffset>22</bitOffset>
              <bitWidth>1</bitWidth>
            </field>
            <field>
              <name>RSTDEM</name>
              <bitOffset>23</bitOffset>
              <bitWidth>1</bitWidth>
            </field>
            <field>
              <name>PRTIM</name>
              <bitOffset>24</bitOffset>
              <bitWidth>1</bitWidth>
            </field>
            <field>
              <name>HCIM</name>
              <bitOffset>25</bitOffset>
              <bitWidth>1</bitWidth>
            </field>
            <field>
              <name>PTXFEM</name>
              <bitOffset>26</bitOffset>
              <bitWidth>1</bitWidth>
            </field>
            <field>
              <name>LPMINTM</name>
              <bitOffset>27</bitOffset>
              <bitWidth>1</bitWidth>
            </field>
            <field>
              <name>CIDSCHGM</name>
              <bitOffset>28</bitOffset>
              <bitWidth>1</bitWidth>
            </field>
            <field>
              <name>DISCINT</name>
              <bitOffset>29</bitOffset>
              <bitWidth>1</bitWidth>
            </field>
            <field>
              <name>SRQIM</name>
              <bitOffset>30</bitOffset>
              <bitWidth>1</bitWidth>
            </field>
            <field>
              <name>WUIM</name>
              <bitOffset>31</bitOffset>
              <bitWidth>1</bitWidth>
            </field>
          </fields>
        </register>
        <register>
          <name>GRXSTSR</name>
          <addressOffset>0x1c</addressOffset>
          <size>0x20</size>
        </register>
        <register>
          <name>GRXSTSP</name>
          <addressOffset>0x20</addressOffset>
          <size>0x20</size>
          <fields>
            <field>
              <name>EPNUM</name>
              <bitOffset>0</bitOffset>
              <bitWidth>4</bitWidth>
            </field>
            <field>
              <name>BCNT</name>
              <bitOffset>4</bitOffset>
              <bitWidth>11</bitWidth>
            </field>
            <field>
              <name>DPID</name>
              <bitOffset>15</bitOffset>
              <bitWidth>2</bitWidth>
            </field>
            <field>
              <name>PKTSTS</name>
              <bitOffset>17</bitOffset>
              <bitWidth>4</bitWidth>
            </field>
          </fields>
        </register>
        <register>
          <name>GRXFSIZ</name>
          <addressOffset>0x24</addressOffset>
          <size>0x20</size>
          <fields>
            <field>
              <name>RXFD</name>
              <bitOffset>0</bitOffset>
              <bitWidth>16</bitWidth>
            </field>
          </fields>
        </register>
        <register>
          <name>DIEPTXF0_HNPTXFSIZ</name>
          <addressOffset>0x28</addressOffset>
          <size>0x20</size>
        </register>
        <register>
          <name>HNPTXSTS</name>
          <addressOffset>0x2c</addressOffset>
          <size>0x20</size>
        </register>
        <register>
          <name>GCCFG</name>
          <addressOffset>0x38</addressOffset>
          <size>0x20</size>
          <fields>
            <field>
              <name>DCDET</name>
              <bitOffset>0</bitOffset>
              <bitWidth>1</bitWidth>
            </field>
            <field>
              <name>PDET</name>
              <bitOffset>1</bitOffset>
              <bitWidth>1</bitWidth>
            </field>
            <field>
              <name>SDET</name>
              <bitOffset>2</bitOffset>
              <bitWidth>1</bitWidth>
            </field>
            <field>
              <name>PS2DET</name>
              <bitOffset>3</bitOffset>
              <bitWidth>1</bitWidth>
            </field>
            <field>
              <name>PWRDWN</name>
              <bitOffset>16</bitOffset>
              <bitWidth>1</bitWidth>
            </field>
            <field>
              <name>BCDEN</name>
              <bitOffset>17</bitOffset>
              <bitWidth>1</bitWidth>
            </field>
            <field>
              <name>DCDEN</name>
              <bitOffset>18</bitOffset>
              <bitWidth>1</bitWidth>
            </field>
            <field>
              <name>PDEN</name>
              <bitOffset>19</bitOffset>
              <bitWidth>1</bitWidth>
            </field>
            <field>
              <name>SDEN</name>
              <bitOffset>20</bitOffset>
              <bitWidth>1</bitWidth>
            </field>
            <field>
              <name>VBDEN</name>
              <bitOffset>21</bitOffset>
              <bitWidth>1</bitWidth>
            </field>
          </fields>
        </register>
        <register>
          <name>CID</name>
          <addressOffset>0x3c</addressOffset>
          <size>0x20</size>
          <fields>
            <field>
              <name>PRODUCT_ID</name>
              <bitOffset>0</bitOffset>
              <bitWidth>32</bitWidth>
            </field>
          </fields>
        </register>
        <register>
          <name>GSNPSID</name>
          <addressOffset>0x40</addressOffset>
          <size>0x20</size>
        </register>
        <register>
          <name>GHWCFG1</name>
          <addressOffset>0x44</addressOffset>
          <size>0x20</size>
        </register>
        <register>
          <name>GHWCFG2</name>
          <addressOffset>0x48</addressOffset>
          <size>0x20</size>
        </register>
        <register>
          <name>GHWCFG3</name>
          <addressOffset>0x4c</addressOffset>
          <size>0x20</size>
        </register>
        <register>
          <name>GLPMCFG</name>
          <addressOffset>0x54</addressOffset>
          <size>0x20</size>
          <fields>
            <field>
              <name>LPMEN</name>
              <bitOffset>0</bitOffset>
              <bitWidth>1</bitWidth>
            </field>
            <field>
              <name>LPMACK</name>
              <bitOffset>1</bitOffset>
              <bitWidth>1</bitWidth>
            </field>
            <field>
              <name>BESL</name>
              <bitOffset>2</bitOffset>
              <bitWidth>4</bitWidth>
            </field>
            <field>
              <name>REMWAKE</name>
              <bitOffset>6</bitOffset>
              <bitWidth>1</bitWidth>
            </field>
            <field>
              <name>L1SSEN</name>
              <bitOffset>7</bitOffset>
              <bitWidth>1</bitWidth>
            </field>
            <field>
              <name>BESLTHRS</name>
              <bitOffset>8</bitOffset>
              <bitWidth>4</bitWidth>
            </field>
            <field>
              <name>L1DSEN</name>
              <bitOffset>12</bitOffset>
              <bitWidth>1</bitWidth>
            </field>
            <field>
              <name>LPMRSP</name>
              <bitOffset>13</bitOffset>
              <bitWidth>2</bitWidth>
            </field>
            <field>
              <name>SLPSTS</name>
              <bitOffset>15</bitOffset>
              <bitWidth>1</bitWidth>
            </field>
            <field>
              <name>L1RSMOK</name>
              <bitOffset>16</bitOffset>
              <bitWidth>1</bitWidth>
            </field>
            <field>
              <name>LPMCHIDX</name>
              <bitOffset>17</bitOffset>
              <bitWidth>4</bitWidth>
            </field>
            <field>
              <name>LPMRCNT</name>
              <bitOffset>21</bitOffset>
              <bitWidth>3</bitWidth>
            </field>
            <field>
              <name>SNDLPM</name>
              <bitOffset>24</bitOffset>
              <bitWidth>1</bitWidth>
            </field>
            <field>
              <name>LPMRCNTSTS</name>
              <bitOffset>25</bitOffset>
              <bitWidth>3</bitWidth>
            </field>
            <field>
              <name>ENBESL</name>
              <bitOffset>28</bitOffset>
              <bitWidth>1</bitWidth>
            </field>
          </fields>
        </register>
        <register>
          <name>GPWRDN</name>
          <addressOffset>0x58</addressOffset>
          <size>0x20</size>
          <fields>
            <field>
              <name>ADPMEN</name>
              <bitOffset>0</bitOffset>
              <bitWidth>1</bitWidth>
            </field>
            <field>
              <name>ADPIF</name>
              <bitOffset>23</bitOffset>
              <bitWidth>1</bitWidth>
            </field>
          </fields>
        </register>
        <register>
          <name>GDFIFOCFG</name>
          <addressOffset>0x5c</addressOffset>
          <size>0x20</size>
        </register>
        <register>
          <name>GADPCTL</name>
          <addressOffset>0x60</addressOffset>
          <size>0x20</size>
        </register>
        <register>
          <name>HPTXFSIZ</name>
          <addressOffset>0x100</addressOffset>
          <size>0x20</size>
          <fields>
            <field>
              <name>PTXSA</name>
              <bitOffset>0</bitOffset>
              <bitWidth>16</bitWidth>
            </field>
            <field>
              <name>PTXFD</name>
              <bitOffset>16</bitOffset>
              <bitWidth>16</bitWidth>
            </field>
          </fields>
        </register>
        <register>
          <name>DIEPTXF.0</name>
          <addressOffset>0x104</addressOffset>
          <size>0x20</size>
          <fields>
            <field>
              <name>INEPTXSA</name>
              <bitOffset>0</bitOffset>
              <bitWidth>16</bitWidth>
            </field>
            <field>
              <name>INEPTXFD</name>
              <bitOffset>16</bitOffset>
              <bitWidth>16</bitWidth>
            </field>
          </fields>
        </register>
        <register>
          <name>DIEPTXF.1</name>
          <addressOffset>0x108</addressOffset>
          <size>0x20</size>
          <fields>
            <field>
              <name>INEPTXSA</name>
              <bitOffset>0</bitOffset>
              <bitWidth>16</bitWidth>
            </field>
            <field>
              <name>INEPTXFD</name>
              <bitOffset>16</bitOffset>
              <bitWidth>16</bitWidth>
            </field>
          </fields>
        </register>
        <register>
          <name>DIEPTXF.2</name>
          <addressOffset>0x10c</addressOffset>
          <size>0x20</size>
          <fields>
            <field>
              <name>INEPTXSA</name>
              <bitOffset>0</bitOffset>
              <bitWidth>16</bitWidth>
            </field>
            <field>
              <name>INEPTXFD</name>
              <bitOffset>16</bitOffset>
              <bitWidth>16</bitWidth>
            </field>
          </fields>
        </register>
        <register>
          <name>DIEPTXF.3</name>
          <addressOffset>0x110</addressOffset>
          <size>0x20</size>
          <fields>
            <field>
              <name>INEPTXSA</name>
              <bitOffset>0</bitOffset>
              <bitWidth>16</bitWidth>
            </field>
            <field>
              <name>INEPTXFD</name>
              <bitOffset>16</bitOffset>
              <bitWidth>16</bitWidth>
            </field>
          </fields>
        </register>
        <register>
          <name>DIEPTXF.4</name>
          <addressOffset>0x114</addressOffset>
          <size>0x20</size>
          <fields>
            <field>
              <name>INEPTXSA</name>
              <bitOffset>0</bitOffset>
              <bitWidth>16</bitWidth>
            </field>
            <field>
              <name>INEPTXFD</name>
              <bitOffset>16</bitOffset>
              <bitWidth>16</bitWidth>
            </field>
          </fields>
        </register>
        <register>
          <name>DIEPTXF.5</name>
          <addressOffset>0x118</addressOffset>
          <size>0x20</size>
          <fields>
            <field>
              <name>INEPTXSA</name>
              <bitOffset>0</bitOffset>
              <bitWidth>16</bitWidth>
            </field>
            <field>
              <name>INEPTXFD</name>
              <bitOffset>16</bitOffset>
              <bitWidth>16</bitWidth>
            </field>
          </fields>
        </register>
        <register>
          <name>DIEPTXF.6</name>
          <addressOffset>0x11c</addressOffset>
          <size>0x20</size>
          <fields>
            <field>
              <name>INEPTXSA</name>
              <bitOffset>0</bitOffset>
              <bitWidth>16</bitWidth>
            </field>
            <field>
              <name>INEPTXFD</name>
              <bitOffset>16</bitOffset>
              <bitWidth>16</bitWidth>
            </field>
          </fields>
        </register>
        <register>
          <name>DIEPTXF.7</name>
          <addressOffset>0x120</addressOffset>
          <size>0x20</size>
          <fields>
            <field>
              <name>INEPTXSA</name>
              <bitOffset>0</bitOffset>
              <bitWidth>16</bitWidth>
            </field>
            <field>
              <name>INEPTXFD</name>
              <bitOffset>16</bitOffset>
              <bitWidth>16</bitWidth>
            </field>
          </fields>
        </register>
        <register>
          <name>DIEPTXF.8</name>
          <addressOffset>0x124</addressOffset>
          <size>0x20</size>
          <fields>
            <field>
              <name>INEPTXSA</name>
              <bitOffset>0</bitOffset>
              <bitWidth>16</bitWidth>
            </field>
            <field>
              <name>INEPTXFD</name>
              <bitOffset>16</bitOffset>
              <bitWidth>16</bitWidth>
            </field>
          </fields>
        </register>
        <register>
          <name>DIEPTXF.9</name>
          <addressOffset>0x128</addressOffset>
          <size>0x20</size>
          <fields>
            <field>
              <name>INEPTXSA</name>
              <bitOffset>0</bitOffset>
              <bitWidth>16</bitWidth>
            </field>
            <field>
              <name>INEPTXFD</name>
              <bitOffset>16</bitOffset>
              <bitWidth>16</bitWidth>
            </field>
          </fields>
        </register>
        <register>
          <name>DIEPTXF.10</name>
          <addressOffset>0x12c</addressOffset>
          <size>0x20</size>
          <fields>
            <field>
              <name>INEPTXSA</name>
              <bitOffset>0</bitOffset>
              <bitWidth>16</bitWidth>
            </field>
            <field>
              <name>INEPTXFD</name>
              <bitOffset>16</bitOffset>
              <bitWidth>16</bitWidth>
            </field>
          </fields>
        </register>
        <register>
          <name>DIEPTXF.11</name>
          <addressOffset>0x130</addressOffset>
          <size>0x20</size>
          <fields>
            <field>
              <name>INEPTXSA</name>
              <bitOffset>0</bitOffset>
              <bitWidth>16</bitWidth>
            </field>
            <field>
              <name>INEPTXFD</name>
              <bitOffset>16</bitOffset>
              <bitWidth>16</bitWidth>
            </field>
          </fields>
        </register>
        <register>
          <name>DIEPTXF.12</name>
          <addressOffset>0x134</addressOffset>
          <size>0x20</size>
          <fields>
            <field>
              <name>INEPTXSA</name>
              <bitOffset>0</bitOffset>
              <bitWidth>16</bitWidth>
            </field>
            <field>
              <name>INEPTXFD</name>
              <bitOffset>16</bitOffset>
              <bitWidth>16</bitWidth>
            </field>
          </fields>
        </register>
        <register>
          <name>DIEPTXF.13</name>
          <addressOffset>0x138</addressOffset>
          <size>0x20</size>
          <fields>
            <field>
              <name>INEPTXSA</name>
              <bitOffset>0</bitOffset>
              <bitWidth>16</bitWidth>
            </field>
            <field>
              <name>INEPTXFD</name>
              <bitOffset>16</bitOffset>
              <bitWidth>16</bitWidth>
            </field>
          </fields>
        </register>
        <register>
          <name>DIEPTXF.14</name>
          <addressOffset>0x13c</addressOffset>
          <size>0x20</size>
          <fields>
            <field>
              <name>INEPTXSA</name>
              <bitOffset>0</bitOffset>
              <bitWidth>16</bitWidth>
            </field>
            <field>
              <name>INEPTXFD</name>
              <bitOffset>16</bitOffset>
              <bitWidth>16</bitWidth>
            </field>
          </fields>
        </register>
      </registers>
    </peripheral>
    <peripheral>
      <name>DCMI</name>
      <baseAddress>0x48020000</baseAddress>
      <registers>
        <register>
          <name>CR</name>
          <addressOffset>0x0</addressOffset>
          <size>0x20</size>
          <fields>
            <field>
              <name>CAPTURE</name>
              <bitOffset>0</bitOffset>
              <bitWidth>1</bitWidth>
            </field>
            <field>
              <name>CM</name>
              <bitOffset>1</bitOffset>
              <bitWidth>1</bitWidth>
            </field>
            <field>
              <name>CROP</name>
              <bitOffset>2</bitOffset>
              <bitWidth>1</bitWidth>
            </field>
            <field>
              <name>JPEG</name>
              <bitOffset>3</bitOffset>
              <bitWidth>1</bitWidth>
            </field>
            <field>
              <name>ESS</name>
              <bitOffset>4</bitOffset>
              <bitWidth>1</bitWidth>
            </field>
            <field>
              <name>PCKPOL</name>
              <bitOffset>5</bitOffset>
              <bitWidth>1</bitWidth>
            </field>
            <field>
              <name>HSPOL</name>
              <bitOffset>6</bitOffset>
              <bitWidth>1</bitWidth>
            </field>
            <field>
              <name>VSPOL</name>
              <bitOffset>7</bitOffset>
              <bitWidth>1</bitWidth>
            </field>
            <field>
              <name>CRE</name>
              <bitOffset>12</bitOffset>
              <bitWidth>1</bitWidth>
            </field>
            <field>
              <name>ENABLE</name>
              <bitOffset>14</bitOffset>
              <bitWidth>1</bitWidth>
            </field>
            <field>
              <name>BSM</name>
              <bitOffset>16</bitOffset>
              <bitWidth>2</bitWidth>
            </field>
            <field>
              <name>OEBS</name>
              <bitOffset>18</bitOffset>
              <bitWidth>1</bitWidth>
            </field>
            <field>
              <name>LSM</name>
              <bitOffset>19</bitOffset>
              <bitWidth>1</bitWidth>
            </field>
            <field>
              <name>OELS</name>
              <bitOffset>20</bitOffset>
              <bitWidth>1</bitWidth>
            </field>
          </fields>
        </register>
        <register>
          <name>SR</name>
          <addressOffset>0x4</addressOffset>
          <size>0x20</size>
          <fields>
            <field>
              <name>HSYNC</name>
              <bitOffset>0</bitOffset>
              <bitWidth>1</bitWidth>
            </field>
            <field>
              <name>VSYNC</name>
              <bitOffset>1</bitOffset>
              <bitWidth>1</bitWidth>
            </field>
            <field>
              <name>FNE</name>
              <bitOffset>2</bitOffset>
              <bitWidth>1</bitWidth>
            </field>
          </fields>
        </register>
        <register>
          <name>RISR</name>
          <addressOffset>0x8</addressOffset>
          <size>0x20</size>
        </register>
        <register>
          <name>IER</name>
          <addressOffset>0xc</addressOffset>
          <size>0x20</size>
          <fields>
            <field>
              <name>FRAME_IE</name>
              <bitOffset>0</bitOffset>
              <bitWidth>1</bitWidth>
            </field>
            <field>
              <name>OVR_IE</name>
              <bitOffset>1</bitOffset>
              <bitWidth>1</bitWidth>
            </field>
            <field>
              <name>ERR_IE</name>
              <bitOffset>2</bitOffset>
              <bitWidth>1</bitWidth>
            </field>
            <field>
              <name>VSYNC_IE</name>
              <bitOffset>3</bitOffset>
              <bitWidth>1</bitWidth>
            </field>
            <field>
              <name>LINE_IE</name>
              <bitOffset>4</bitOffset>
              <bitWidth>1</bitWidth>
            </field>
          </fields>
        </register>
        <register>
          <name>MISR</name>
          <addressOffset>0x10</addressOffset>
          <size>0x20</size>
        </register>
        <register>
          <name>ICR</name>
          <addressOffset>0x14</addressOffset>
          <size>0x20</size>
          <fields>
            <field>
              <name>FRAME_ISC</name>
              <bitOffset>0</bitOffset>
              <bitWidth>1</bitWidth>
            </field>
            <field>
              <name>OVR_ISC</name>
              <bitOffset>1</bitOffset>
              <bitWidth>1</bitWidth>
            </field>
            <field>
              <name>ERR_ISC</name>
              <bitOffset>2</bitOffset>
              <bitWidth>1</bitWidth>
            </field>
            <field>
              <name>VSYNC_ISC</name>
              <bitOffset>3</bitOffset>
              <bitWidth>1</bitWidth>
            </field>
            <field>
              <name>LINE_ISC</name>
              <bitOffset>4</bitOffset>
              <bitWidth>1</bitWidth>
            </field>
          </fields>
        </register>
        <register>
          <name>ESCR</name>
          <addressOffset>0x18</addressOffset>
          <size>0x20</size>
          <fields>
            <field>
              <name>FSC</name>
              <bitOffset>0</bitOffset>
              <bitWidth>8</bitWidth>
            </field>
            <field>
              <name>LSC</name>
              <bitOffset>8</bitOffset>
              <bitWidth>8</bitWidth>
            </field>
            <field>
              <name>LEC</name>
              <bitOffset>16</bitOffset>
              <bitWidth>8</bitWidth>
            </field>
            <field>
              <name>FEC</name>
              <bitOffset>24</bitOffset>
              <bitWidth>8</bitWidth>
            </field>
          </fields>
        </register>
        <register>
          <name>ESUR</name>
          <addressOffset>0x1c</addressOffset>
          <size>0x20</size>
          <fields>
            <field>
              <name>FSU</name>
              <bitOffset>0</bitOffset>
              <bitWidth>8</bitWidth>
            </field>
            <field>
              <name>LSU</name>
              <bitOffset>8</bitOffset>
              <bitWidth>8</bitWidth>
            </field>
            <field>
              <name>LEU</name>
              <bitOffset>16</bitOffset>
              <bitWidth>8</bitWidth>
            </field>
            <field>
              <name>FEU</name>
              <bitOffset>24</bitOffset>
              <bitWidth>8</bitWidth>
            </field>
          </fields>
        </register>
        <register>
          <name>CWSTRTR</name>
          <addressOffset>0x20</addressOffset>
          <size>0x20</size>
        </register>
        <register>
          <name>CWSIZER</name>
          <addressOffset>0x24</addressOffset>
          <size>0x20</size>
        </register>
        <register>
          <name>DR</name>
          <addressOffset>0x28</addressOffset>
          <size>0x20</size>
          <fields>
            <field>
              <name>BYTE0</name>
              <bitOffset>0</bitOffset>
              <bitWidth>8</bitWidth>
            </field>
            <field>
              <name>BYTE1</name>
              <bitOffset>8</bitOffset>
              <bitWidth>8</bitWidth>
            </field>
            <field>
              <name>BYTE2</name>
              <bitOffset>16</bitOffset>
              <bitWidth>8</bitWidth>
            </field>
            <field>
              <name>BYTE3</name>
              <bitOffset>24</bitOffset>
              <bitWidth>8</bitWidth>
            </field>
          </fields>
        </register>
      </registers>
    </peripheral>
    <peripheral>
      <name>PSSI</name>
      <baseAddress>0x48020400</baseAddress>
      <registers>
        <register>
          <name>CR</name>
          <addressOffset>0x0</addressOffset>
          <size>0x20</size>
          <fields>
            <field>
              <name>CKPOL</name>
              <bitOffset>5</bitOffset>
              <bitWidth>1</bitWidth>
            </field>
            <field>
              <name>DEPOL</name>
              <bitOffset>6</bitOffset>
              <bitWidth>1</bitWidth>
            </field>
            <field>
              <name>RDYPOL</name>
              <bitOffset>8</bitOffset>
              <bitWidth>1</bitWidth>
            </field>
            <field>
              <name>EDM</name>
              <bitOffset>10</bitOffset>
              <bitWidth>2</bitWidth>
            </field>
            <field>
              <name>ENABLE</name>
              <bitOffset>14</bitOffset>
              <bitWidth>1</bitWidth>
            </field>
            <field>
              <name>DERDYCFG</name>
              <bitOffset>18</bitOffset>
              <bitWidth>3</bitWidth>
            </field>
            <field>
              <name>DMAEN</name>
              <bitOffset>30</bitOffset>
              <bitWidth>1</bitWidth>
            </field>
            <field>
              <name>OUTEN</name>
              <bitOffset>31</bitOffset>
              <bitWidth>1</bitWidth>
            </field>
          </fields>
        </register>
        <register>
          <name>SR</name>
          <addressOffset>0x4</addressOffset>
          <size>0x20</size>
          <fields>
            <field>
              <name>RTT4B</name>
              <bitOffset>2</bitOffset>
              <bitWidth>1</bitWidth>
            </field>
            <field>
              <name>RTT1B</name>
              <bitOffset>3</bitOffset>
              <bitWidth>1</bitWidth>
            </field>
          </fields>
        </register>
        <register>
          <name>RIS</name>
          <addressOffset>0x8</addressOffset>
          <size>0x20</size>
          <fields>
            <field>
              <name>OVR_RIS</name>
              <bitOffset>1</bitOffset>
              <bitWidth>1</bitWidth>
            </field>
          </fields>
        </register>
        <register>
          <name>IER</name>
          <addressOffset>0xc</addressOffset>
          <size>0x20</size>
          <fields>
            <field>
              <name>OVR_IE</name>
              <bitOffset>1</bitOffset>
              <bitWidth>1</bitWidth>
            </field>
          </fields>
        </register>
        <register>
          <name>MIS</name>
          <addressOffset>0x10</addressOffset>
          <size>0x20</size>
          <fields>
            <field>
              <name>OVR_MIS</name>
              <bitOffset>1</bitOffset>
              <bitWidth>1</bitWidth>
            </field>
          </fields>
        </register>
        <register>
          <name>ICR</name>
          <addressOffset>0x14</addressOffset>
          <size>0x20</size>
          <fields>
            <field>
              <name>OVR_ISC</name>
              <bitOffset>1</bitOffset>
              <bitWidth>1</bitWidth>
            </field>
          </fields>
        </register>
        <register>
          <name>DR</name>
          <addressOffset>0x28</addressOffset>
          <size>0x20</size>
          <fields>
            <field>
              <name>DR</name>
              <bitOffset>0</bitOffset>
              <bitWidth>32</bitWidth>
            </field>
          </fields>
        </register>
        <register>
          <name>HWCFGR</name>
          <addressOffset>0x3f0</addressOffset>
          <size>0x20</size>
        </register>
        <register>
          <name>VERR</name>
          <addressOffset>0x3f4</addressOffset>
          <size>0x20</size>
        </register>
        <register>
          <name>IPIDR</name>
          <addressOffset>0x3f8</addressOffset>
          <size>0x20</size>
        </register>
        <register>
          <name>SIDR</name>
          <addressOffset>0x3fc</addressOffset>
          <size>0x20</size>
        </register>
      </registers>
    </peripheral>
    <peripheral>
      <name>RNG</name>
      <baseAddress>0x48021800</baseAddress>
      <registers>
        <register>
          <name>CR</name>
          <addressOffset>0x0</addressOffset>
          <size>0x20</size>
          <fields>
            <field>
              <name>RNGEN</name>
              <bitOffset>2</bitOffset>
              <bitWidth>1</bitWidth>
            </field>
            <field>
              <name>IE</name>
              <bitOffset>3</bitOffset>
              <bitWidth>1</bitWidth>
            </field>
            <field>
              <name>CED</name>
              <bitOffset>5</bitOffset>
              <bitWidth>1</bitWidth>
            </field>
            <field>
              <name>RNG_CONFIG3</name>
              <bitOffset>8</bitOffset>
              <bitWidth>4</bitWidth>
            </field>
            <field>
              <name>NISTC</name>
              <bitOffset>12</bitOffset>
              <bitWidth>1</bitWidth>
            </field>
            <field>
              <name>RNG_CONFIG2</name>
              <bitOffset>13</bitOffset>
              <bitWidth>3</bitWidth>
            </field>
            <field>
              <name>CLKDIV</name>
              <bitOffset>16</bitOffset>
              <bitWidth>4</bitWidth>
            </field>
            <field>
              <name>RNG_CONFIG1</name>
              <bitOffset>20</bitOffset>
              <bitWidth>6</bitWidth>
            </field>
            <field>
              <name>CONDRST</name>
              <bitOffset>30</bitOffset>
              <bitWidth>1</bitWidth>
            </field>
            <field>
              <name>CONFIGLOCK</name>
              <bitOffset>31</bitOffset>
              <bitWidth>1</bitWidth>
            </field>
          </fields>
        </register>
        <register>
          <name>SR</name>
          <addressOffset>0x4</addressOffset>
          <size>0x20</size>
          <fields>
            <field>
              <name>DRDY</name>
              <bitOffset>0</bitOffset>
              <bitWidth>1</bitWidth>
            </field>
            <field>
              <name>CECS</name>
              <bitOffset>1</bitOffset>
              <bitWidth>1</bitWidth>
            </field>
            <field>
              <name>SECS</name>
              <bitOffset>2</bitOffset>
              <bitWidth>1</bitWidth>
            </field>
            <field>
              <name>CEIS</name>
              <bitOffset>5</bitOffset>
              <bitWidth>1</bitWidth>
            </field>
            <field>
              <name>SEIS</name>
              <bitOffset>6</bitOffset>
              <bitWidth>1</bitWidth>
            </field>
          </fields>
        </register>
        <register>
          <name>DR</name>
          <addressOffset>0x8</addressOffset>
          <size>0x20</size>
        </register>
        <register>
          <name>HTCR</name>
          <addressOffset>0x10</addressOffset>
          <size>0x20</size>
        </register>
      </registers>
    </peripheral>
    <peripheral>
      <name>SDMMC2</name>
      <baseAddress>0x48022400</baseAddress>
      <registers>
        <register>
          <name>POWER</name>
          <addressOffset>0x0</addressOffset>
          <size>0x20</size>
          <fields>
            <field>
              <name>PWRCTRL</name>
              <bitOffset>0</bitOffset>
              <bitWidth>2</bitWidth>
            </field>
            <field>
              <name>VSWITCH</name>
              <bitOffset>2</bitOffset>
              <bitWidth>1</bitWidth>
            </field>
            <field>
              <name>VSWITCHEN</name>
              <bitOffset>3</bitOffset>
              <bitWidth>1</bitWidth>
            </field>
            <field>
              <name>DIRPOL</name>
              <bitOffset>4</bitOffset>
              <bitWidth>1</bitWidth>
            </field>
          </fields>
        </register>
        <register>
          <name>CLKCR</name>
          <addressOffset>0x4</addressOffset>
          <size>0x20</size>
          <fields>
            <field>
              <name>CLKDIV</name>
              <bitOffset>0</bitOffset>
              <bitWidth>10</bitWidth>
            </field>
            <field>
              <name>PWRSAV</name>
              <bitOffset>12</bitOffset>
              <bitWidth>1</bitWidth>
            </field>
            <field>
              <name>WIDBUS</name>
              <bitOffset>14</bitOffset>
              <bitWidth>2</bitWidth>
            </field>
            <field>
              <name>NEGEDGE</name>
              <bitOffset>16</bitOffset>
              <bitWidth>1</bitWidth>
            </field>
            <field>
              <name>HWFC_EN</name>
              <bitOffset>17</bitOffset>
              <bitWidth>1</bitWidth>
            </field>
            <field>
              <name>DDR</name>
              <bitOffset>18</bitOffset>
              <bitWidth>1</bitWidth>
            </field>
            <field>
              <name>BUSSPEED</name>
              <bitOffset>19</bitOffset>
              <bitWidth>1</bitWidth>
            </field>
            <field>
              <name>SELCLKRX</name>
              <bitOffset>20</bitOffset>
              <bitWidth>2</bitWidth>
            </field>
          </fields>
        </register>
        <register>
          <name>ARG</name>
          <addressOffset>0x8</addressOffset>
          <size>0x20</size>
          <fields>
            <field>
              <name>CMDARG</name>
              <bitOffset>0</bitOffset>
              <bitWidth>32</bitWidth>
            </field>
          </fields>
        </register>
        <register>
          <name>CMD</name>
          <addressOffset>0xc</addressOffset>
          <size>0x20</size>
          <fields>
            <field>
              <name>CMDINDEX</name>
              <bitOffset>0</bitOffset>
              <bitWidth>6</bitWidth>
            </field>
            <field>
              <name>CMDTRANS</name>
              <bitOffset>6</bitOffset>
              <bitWidth>1</bitWidth>
            </field>
            <field>
              <name>CMDSTOP</name>
              <bitOffset>7</bitOffset>
              <bitWidth>1</bitWidth>
            </field>
            <field>
              <name>WAITRESP</name>
              <bitOffset>8</bitOffset>
              <bitWidth>2</bitWidth>
            </field>
            <field>
              <name>WAITINT</name>
              <bitOffset>10</bitOffset>
              <bitWidth>1</bitWidth>
            </field>
            <field>
              <name>WAITPEND</name>
              <bitOffset>11</bitOffset>
              <bitWidth>1</bitWidth>
            </field>
            <field>
              <name>CPSMEN</name>
              <bitOffset>12</bitOffset>
              <bitWidth>1</bitWidth>
            </field>
            <field>
              <name>DTHOLD</name>
              <bitOffset>13</bitOffset>
              <bitWidth>1</bitWidth>
            </field>
            <field>
              <name>BOOTMODE</name>
              <bitOffset>14</bitOffset>
              <bitWidth>1</bitWidth>
            </field>
            <field>
              <name>BOOTEN</name>
              <bitOffset>15</bitOffset>
              <bitWidth>1</bitWidth>
            </field>
            <field>
              <name>CMDSUSPEND</name>
              <bitOffset>16</bitOffset>
              <bitWidth>1</bitWidth>
            </field>
          </fields>
        </register>
        <register>
          <name>RESPCMD</name>
          <addressOffset>0x10</addressOffset>
          <size>0x20</size>
          <fields>
            <field>
              <name>RESPCMD</name>
              <bitOffset>0</bitOffset>
              <bitWidth>6</bitWidth>
            </field>
          </fields>
        </register>
        <register>
          <name>RESP1</name>
          <addressOffset>0x14</addressOffset>
          <size>0x20</size>
          <fields>
            <field>
              <name>CARDSTATUS1</name>
              <bitOffset>0</bitOffset>
              <bitWidth>32</bitWidth>
            </field>
          </fields>
        </register>
        <register>
          <name>RESP2</name>
          <addressOffset>0x18</addressOffset>
          <size>0x20</size>
          <fields>
            <field>
              <name>CARDSTATUS2</name>
              <bitOffset>0</bitOffset>
              <bitWidth>32</bitWidth>
            </field>
          </fields>
        </register>
        <register>
          <name>RESP3</name>
          <addressOffset>0x1c</addressOffset>
          <size>0x20</size>
          <fields>
            <field>
              <name>CARDSTATUS3</name>
              <bitOffset>0</bitOffset>
              <bitWidth>32</bitWidth>
            </field>
          </fields>
        </register>
        <register>
          <name>RESP4</name>
          <addressOffset>0x20</addressOffset>
          <size>0x20</size>
          <fields>
            <field>
              <name>CARDSTATUS4</name>
              <bitOffset>0</bitOffset>
              <bitWidth>32</bitWidth>
            </field>
          </fields>
        </register>
        <register>
          <name>DTIMER</name>
          <addressOffset>0x24</addressOffset>
          <size>0x20</size>
          <fields>
            <field>
              <name>DATATIME</name>
              <bitOffset>0</bitOffset>
              <bitWidth>32</bitWidth>
            </field>
          </fields>
        </register>
        <register>
          <name>DLEN</name>
          <addressOffset>0x28</addressOffset>
          <size>0x20</size>
          <fields>
            <field>
              <name>DATALENGTH</name>
              <bitOffset>0</bitOffset>
              <bitWidth>25</bitWidth>
            </field>
          </fields>
        </register>
        <register>
          <name>DCTRL</name>
          <addressOffset>0x2c</addressOffset>
          <size>0x20</size>
          <fields>
            <field>
              <name>DTEN</name>
              <bitOffset>0</bitOffset>
              <bitWidth>1</bitWidth>
            </field>
            <field>
              <name>DTDIR</name>
              <bitOffset>1</bitOffset>
              <bitWidth>1</bitWidth>
            </field>
            <field>
              <name>DTMODE</name>
              <bitOffset>2</bitOffset>
              <bitWidth>2</bitWidth>
            </field>
            <field>
              <name>DBLOCKSIZE</name>
              <bitOffset>4</bitOffset>
              <bitWidth>4</bitWidth>
            </field>
            <field>
              <name>RWSTART</name>
              <bitOffset>8</bitOffset>
              <bitWidth>1</bitWidth>
            </field>
            <field>
              <name>RWSTOP</name>
              <bitOffset>9</bitOffset>
              <bitWidth>1</bitWidth>
            </field>
            <field>
              <name>RWMOD</name>
              <bitOffset>10</bitOffset>
              <bitWidth>1</bitWidth>
            </field>
            <field>
              <name>SDIOEN</name>
              <bitOffset>11</bitOffset>
              <bitWidth>1</bitWidth>
            </field>
            <field>
              <name>BOOTACKEN</name>
              <bitOffset>12</bitOffset>
              <bitWidth>1</bitWidth>
            </field>
            <field>
              <name>FIFORST</name>
              <bitOffset>13</bitOffset>
              <bitWidth>1</bitWidth>
            </field>
          </fields>
        </register>
        <register>
          <name>DCOUNT</name>
          <addressOffset>0x30</addressOffset>
          <size>0x20</size>
          <fields>
            <field>
              <name>DATACOUNT</name>
              <bitOffset>0</bitOffset>
              <bitWidth>25</bitWidth>
            </field>
          </fields>
        </register>
        <register>
          <name>STA</name>
          <addressOffset>0x34</addressOffset>
          <size>0x20</size>
          <fields>
            <field>
              <name>CCRCFAIL</name>
              <bitOffset>0</bitOffset>
              <bitWidth>1</bitWidth>
            </field>
            <field>
              <name>DCRCFAIL</name>
              <bitOffset>1</bitOffset>
              <bitWidth>1</bitWidth>
            </field>
            <field>
              <name>CTIMEOUT</name>
              <bitOffset>2</bitOffset>
              <bitWidth>1</bitWidth>
            </field>
            <field>
              <name>DTIMEOUT</name>
              <bitOffset>3</bitOffset>
              <bitWidth>1</bitWidth>
            </field>
            <field>
              <name>TXUNDERR</name>
              <bitOffset>4</bitOffset>
              <bitWidth>1</bitWidth>
            </field>
            <field>
              <name>RXOVERR</name>
              <bitOffset>5</bitOffset>
              <bitWidth>1</bitWidth>
            </field>
            <field>
              <name>CMDREND</name>
              <bitOffset>6</bitOffset>
              <bitWidth>1</bitWidth>
            </field>
            <field>
              <name>CMDSENT</name>
              <bitOffset>7</bitOffset>
              <bitWidth>1</bitWidth>
            </field>
            <field>
              <name>DATAEND</name>
              <bitOffset>8</bitOffset>
              <bitWidth>1</bitWidth>
            </field>
            <field>
              <name>DHOLD</name>
              <bitOffset>9</bitOffset>
              <bitWidth>1</bitWidth>
            </field>
            <field>
              <name>DBCKEND</name>
              <bitOffset>10</bitOffset>
              <bitWidth>1</bitWidth>
            </field>
            <field>
              <name>DABORT</name>
              <bitOffset>11</bitOffset>
              <bitWidth>1</bitWidth>
            </field>
            <field>
              <name>DPSMACT</name>
              <bitOffset>12</bitOffset>
              <bitWidth>1</bitWidth>
            </field>
            <field>
              <name>CPSMACT</name>
              <bitOffset>13</bitOffset>
              <bitWidth>1</bitWidth>
            </field>
            <field>
              <name>TXFIFOHE</name>
              <bitOffset>14</bitOffset>
              <bitWidth>1</bitWidth>
            </field>
            <field>
              <name>RXFIFOHF</name>
              <bitOffset>15</bitOffset>
              <bitWidth>1</bitWidth>
            </field>
            <field>
              <name>TXFIFOF</name>
              <bitOffset>16</bitOffset>
              <bitWidth>1</bitWidth>
            </field>
            <field>
              <name>RXFIFOF</name>
              <bitOffset>17</bitOffset>
              <bitWidth>1</bitWidth>
            </field>
            <field>
              <name>TXFIFOE</name>
              <bitOffset>18</bitOffset>
              <bitWidth>1</bitWidth>
            </field>
            <field>
              <name>RXFIFOE</name>
              <bitOffset>19</bitOffset>
              <bitWidth>1</bitWidth>
            </field>
            <field>
              <name>BUSYD0</name>
              <bitOffset>20</bitOffset>
              <bitWidth>1</bitWidth>
            </field>
            <field>
              <name>BUSYD0END</name>
              <bitOffset>21</bitOffset>
              <bitWidth>1</bitWidth>
            </field>
            <field>
              <name>SDIOIT</name>
              <bitOffset>22</bitOffset>
              <bitWidth>1</bitWidth>
            </field>
            <field>
              <name>ACKFAIL</name>
              <bitOffset>23</bitOffset>
              <bitWidth>1</bitWidth>
            </field>
            <field>
              <name>ACKTIMEOUT</name>
              <bitOffset>24</bitOffset>
              <bitWidth>1</bitWidth>
            </field>
            <field>
              <name>VSWEND</name>
              <bitOffset>25</bitOffset>
              <bitWidth>1</bitWidth>
            </field>
            <field>
              <name>CKSTOP</name>
              <bitOffset>26</bitOffset>
              <bitWidth>1</bitWidth>
            </field>
            <field>
              <name>IDMATE</name>
              <bitOffset>27</bitOffset>
              <bitWidth>1</bitWidth>
            </field>
            <field>
              <name>IDMABTC</name>
              <bitOffset>28</bitOffset>
              <bitWidth>1</bitWidth>
            </field>
          </fields>
        </register>
        <register>
          <name>ICR</name>
          <addressOffset>0x38</addressOffset>
          <size>0x20</size>
          <fields>
            <field>
              <name>CCRCFAILC</name>
              <bitOffset>0</bitOffset>
              <bitWidth>1</bitWidth>
            </field>
            <field>
              <name>DCRCFAILC</name>
              <bitOffset>1</bitOffset>
              <bitWidth>1</bitWidth>
            </field>
            <field>
              <name>CTIMEOUTC</name>
              <bitOffset>2</bitOffset>
              <bitWidth>1</bitWidth>
            </field>
            <field>
              <name>DTIMEOUTC</name>
              <bitOffset>3</bitOffset>
              <bitWidth>1</bitWidth>
            </field>
            <field>
              <name>TXUNDERRC</name>
              <bitOffset>4</bitOffset>
              <bitWidth>1</bitWidth>
            </field>
            <field>
              <name>RXOVERRC</name>
              <bitOffset>5</bitOffset>
              <bitWidth>1</bitWidth>
            </field>
            <field>
              <name>CMDRENDC</name>
              <bitOffset>6</bitOffset>
              <bitWidth>1</bitWidth>
            </field>
            <field>
              <name>CMDSENTC</name>
              <bitOffset>7</bitOffset>
              <bitWidth>1</bitWidth>
            </field>
            <field>
              <name>DATAENDC</name>
              <bitOffset>8</bitOffset>
              <bitWidth>1</bitWidth>
            </field>
            <field>
              <name>DHOLDC</name>
              <bitOffset>9</bitOffset>
              <bitWidth>1</bitWidth>
            </field>
            <field>
              <name>DBCKENDC</name>
              <bitOffset>10</bitOffset>
              <bitWidth>1</bitWidth>
            </field>
            <field>
              <name>DABORTC</name>
              <bitOffset>11</bitOffset>
              <bitWidth>1</bitWidth>
            </field>
            <field>
              <name>BUSYD0ENDC</name>
              <bitOffset>21</bitOffset>
              <bitWidth>1</bitWidth>
            </field>
            <field>
              <name>SDIOITC</name>
              <bitOffset>22</bitOffset>
              <bitWidth>1</bitWidth>
            </field>
            <field>
              <name>ACKFAILC</name>
              <bitOffset>23</bitOffset>
              <bitWidth>1</bitWidth>
            </field>
            <field>
              <name>ACKTIMEOUTC</name>
              <bitOffset>24</bitOffset>
              <bitWidth>1</bitWidth>
            </field>
            <field>
              <name>VSWENDC</name>
              <bitOffset>25</bitOffset>
              <bitWidth>1</bitWidth>
            </field>
            <field>
              <name>CKSTOPC</name>
              <bitOffset>26</bitOffset>
              <bitWidth>1</bitWidth>
            </field>
            <field>
              <name>IDMATEC</name>
              <bitOffset>27</bitOffset>
              <bitWidth>1</bitWidth>
            </field>
            <field>
              <name>IDMABTCC</name>
              <bitOffset>28</bitOffset>
              <bitWidth>1</bitWidth>
            </field>
          </fields>
        </register>
        <register>
          <name>MASK</name>
          <addressOffset>0x3c</addressOffset>
          <size>0x20</size>
          <fields>
            <field>
              <name>CCRCFAILIE</name>
              <bitOffset>0</bitOffset>
              <bitWidth>1</bitWidth>
            </field>
            <field>
              <name>DCRCFAILIE</name>
              <bitOffset>1</bitOffset>
              <bitWidth>1</bitWidth>
            </field>
            <field>
              <name>CTIMEOUTIE</name>
              <bitOffset>2</bitOffset>
              <bitWidth>1</bitWidth>
            </field>
            <field>
              <name>DTIMEOUTIE</name>
              <bitOffset>3</bitOffset>
              <bitWidth>1</bitWidth>
            </field>
            <field>
              <name>TXUNDERRIE</name>
              <bitOffset>4</bitOffset>
              <bitWidth>1</bitWidth>
            </field>
            <field>
              <name>RXOVERRIE</name>
              <bitOffset>5</bitOffset>
              <bitWidth>1</bitWidth>
            </field>
            <field>
              <name>CMDRENDIE</name>
              <bitOffset>6</bitOffset>
              <bitWidth>1</bitWidth>
            </field>
            <field>
              <name>CMDSENTIE</name>
              <bitOffset>7</bitOffset>
              <bitWidth>1</bitWidth>
            </field>
            <field>
              <name>DATAENDIE</name>
              <bitOffset>8</bitOffset>
              <bitWidth>1</bitWidth>
            </field>
            <field>
              <name>DHOLDIE</name>
              <bitOffset>9</bitOffset>
              <bitWidth>1</bitWidth>
            </field>
            <field>
              <name>DBCKENDIE</name>
              <bitOffset>10</bitOffset>
              <bitWidth>1</bitWidth>
            </field>
            <field>
              <name>DABORTIE</name>
              <bitOffset>11</bitOffset>
              <bitWidth>1</bitWidth>
            </field>
            <field>
              <name>TXFIFOHEIE</name>
              <bitOffset>14</bitOffset>
              <bitWidth>1</bitWidth>
            </field>
            <field>
              <name>RXFIFOHFIE</name>
              <bitOffset>15</bitOffset>
              <bitWidth>1</bitWidth>
            </field>
            <field>
              <name>RXFIFOFIE</name>
              <bitOffset>17</bitOffset>
              <bitWidth>1</bitWidth>
            </field>
            <field>
              <name>TXFIFOEIE</name>
              <bitOffset>18</bitOffset>
              <bitWidth>1</bitWidth>
            </field>
            <field>
              <name>BUSYD0ENDIE</name>
              <bitOffset>21</bitOffset>
              <bitWidth>1</bitWidth>
            </field>
            <field>
              <name>SDIOITIE</name>
              <bitOffset>22</bitOffset>
              <bitWidth>1</bitWidth>
            </field>
            <field>
              <name>ACKFAILIE</name>
              <bitOffset>23</bitOffset>
              <bitWidth>1</bitWidth>
            </field>
            <field>
              <name>ACKTIMEOUTIE</name>
              <bitOffset>24</bitOffset>
              <bitWidth>1</bitWidth>
            </field>
            <field>
              <name>VSWENDIE</name>
              <bitOffset>25</bitOffset>
              <bitWidth>1</bitWidth>
            </field>
            <field>
              <name>CKSTOPIE</name>
              <bitOffset>26</bitOffset>
              <bitWidth>1</bitWidth>
            </field>
            <field>
              <name>IDMABTCIE</name>
              <bitOffset>28</bitOffset>
              <bitWidth>1</bitWidth>
            </field>
          </fields>
        </register>
        <register>
          <name>ACKTIME</name>
          <addressOffset>0x40</addressOffset>
          <size>0x20</size>
          <fields>
            <field>
              <name>ACKTIME</name>
              <bitOffset>0</bitOffset>
              <bitWidth>25</bitWidth>
            </field>
          </fields>
        </register>
        <register>
          <name>IDMACTRL</name>
          <addressOffset>0x50</addressOffset>
          <size>0x20</size>
        </register>
        <register>
          <name>IDMABSIZE</name>
          <addressOffset>0x54</addressOffset>
          <size>0x20</size>
          <fields>
            <field>
              <name>IDMABNDT</name>
              <bitOffset>5</bitOffset>
              <bitWidth>8</bitWidth>
            </field>
          </fields>
        </register>
        <register>
          <name>IDMABASE0</name>
          <addressOffset>0x58</addressOffset>
          <size>0x20</size>
        </register>
        <register>
          <name>IDMABASE1</name>
          <addressOffset>0x5c</addressOffset>
          <size>0x20</size>
        </register>
        <register>
          <name>FIFO</name>
          <addressOffset>0x80</addressOffset>
          <size>0x20</size>
          <fields>
            <field>
              <name>FIFODATA</name>
              <bitOffset>0</bitOffset>
              <bitWidth>32</bitWidth>
            </field>
          </fields>
        </register>
        <register>
          <name>IPVR</name>
          <addressOffset>0x3fc</addressOffset>
          <size>0x20</size>
        </register>
      </registers>
    </peripheral>
    <peripheral>
      <name>DLYB_SDMMC2</name>
      <baseAddress>0x48022800</baseAddress>
      <registers>
        <register>
          <name>CR</name>
          <addressOffset>0x0</addressOffset>
          <size>0x20</size>
          <fields>
            <field>
              <name>DEN</name>
              <bitOffset>0</bitOffset>
              <bitWidth>1</bitWidth>
            </field>
            <field>
              <name>SEN</name>
              <bitOffset>1</bitOffset>
              <bitWidth>1</bitWidth>
            </field>
          </fields>
        </register>
        <register>
          <name>CFGR</name>
          <addressOffset>0x4</addressOffset>
          <size>0x20</size>
          <fields>
            <field>
              <name>SEL</name>
              <bitOffset>0</bitOffset>
              <bitWidth>4</bitWidth>
            </field>
            <field>
              <name>UNIT</name>
              <bitOffset>8</bitOffset>
              <bitWidth>7</bitWidth>
            </field>
            <field>
              <name>LNG</name>
              <bitOffset>16</bitOffset>
              <bitWidth>12</bitWidth>
            </field>
            <field>
              <name>LNGF</name>
              <bitOffset>31</bitOffset>
              <bitWidth>1</bitWidth>
            </field>
          </fields>
        </register>
      </registers>
    </peripheral>
    <peripheral>
      <name>RAMECC2</name>
      <baseAddress>0x48023000</baseAddress>
      <registers>
        <register>
          <name>IER</name>
          <addressOffset>0x0</addressOffset>
          <size>0x20</size>
          <fields>
            <field>
              <name>GIE</name>
              <bitOffset>0</bitOffset>
              <bitWidth>1</bitWidth>
            </field>
            <field>
              <name>GECCSEIE</name>
              <bitOffset>1</bitOffset>
              <bitWidth>1</bitWidth>
            </field>
            <field>
              <name>GECCDEIE</name>
              <bitOffset>2</bitOffset>
              <bitWidth>1</bitWidth>
            </field>
            <field>
              <name>GECCDEBWIE</name>
              <bitOffset>3</bitOffset>
              <bitWidth>1</bitWidth>
            </field>
          </fields>
        </register>
        <register>
          <name>CR1</name>
          <addressOffset>0x20</addressOffset>
          <size>0x20</size>
          <fields>
            <field>
              <name>ECCSEIE</name>
              <bitOffset>2</bitOffset>
              <bitWidth>1</bitWidth>
            </field>
            <field>
              <name>ECCDEIE</name>
              <bitOffset>3</bitOffset>
              <bitWidth>1</bitWidth>
            </field>
            <field>
              <name>ECCDEBWIE</name>
              <bitOffset>4</bitOffset>
              <bitWidth>1</bitWidth>
            </field>
            <field>
              <name>ECCELEN</name>
              <bitOffset>5</bitOffset>
              <bitWidth>1</bitWidth>
            </field>
          </fields>
        </register>
        <register>
          <name>CR1</name>
          <addressOffset>0x20</addressOffset>
          <size>0x20</size>
          <fields>
            <field>
              <name>ECCSEIE</name>
              <bitOffset>2</bitOffset>
              <bitWidth>1</bitWidth>
            </field>
            <field>
              <name>ECCDEIE</name>
              <bitOffset>3</bitOffset>
              <bitWidth>1</bitWidth>
            </field>
            <field>
              <name>ECCDEBWIE</name>
              <bitOffset>4</bitOffset>
              <bitWidth>1</bitWidth>
            </field>
            <field>
              <name>ECCELEN</name>
              <bitOffset>5</bitOffset>
              <bitWidth>1</bitWidth>
            </field>
          </fields>
        </register>
        <register>
          <name>CR1</name>
          <addressOffset>0x20</addressOffset>
          <size>0x20</size>
          <fields>
            <field>
              <name>ECCSEIE</name>
              <bitOffset>2</bitOffset>
              <bitWidth>1</bitWidth>
            </field>
            <field>
              <name>ECCDEIE</name>
              <bitOffset>3</bitOffset>
              <bitWidth>1</bitWidth>
            </field>
            <field>
              <name>ECCDEBWIE</name>
              <bitOffset>4</bitOffset>
              <bitWidth>1</bitWidth>
            </field>
            <field>
              <name>ECCELEN</name>
              <bitOffset>5</bitOffset>
              <bitWidth>1</bitWidth>
            </field>
          </fields>
        </register>
        <register>
          <name>SR1</name>
          <addressOffset>0x24</addressOffset>
          <size>0x20</size>
          <fields>
            <field>
              <name>SEDCF</name>
              <bitOffset>0</bitOffset>
              <bitWidth>1</bitWidth>
            </field>
            <field>
              <name>DEDF</name>
              <bitOffset>1</bitOffset>
              <bitWidth>1</bitWidth>
            </field>
            <field>
              <name>DEBWDF</name>
              <bitOffset>2</bitOffset>
              <bitWidth>1</bitWidth>
            </field>
          </fields>
        </register>
        <register>
          <name>SR1</name>
          <addressOffset>0x24</addressOffset>
          <size>0x20</size>
          <fields>
            <field>
              <name>SEDCF</name>
              <bitOffset>0</bitOffset>
              <bitWidth>1</bitWidth>
            </field>
            <field>
              <name>DEDF</name>
              <bitOffset>1</bitOffset>
              <bitWidth>1</bitWidth>
            </field>
            <field>
              <name>DEBWDF</name>
              <bitOffset>2</bitOffset>
              <bitWidth>1</bitWidth>
            </field>
          </fields>
        </register>
        <register>
          <name>SR1</name>
          <addressOffset>0x24</addressOffset>
          <size>0x20</size>
          <fields>
            <field>
              <name>SEDCF</name>
              <bitOffset>0</bitOffset>
              <bitWidth>1</bitWidth>
            </field>
            <field>
              <name>DEDF</name>
              <bitOffset>1</bitOffset>
              <bitWidth>1</bitWidth>
            </field>
            <field>
              <name>DEBWDF</name>
              <bitOffset>2</bitOffset>
              <bitWidth>1</bitWidth>
            </field>
          </fields>
        </register>
        <register>
          <name>FAR1</name>
          <addressOffset>0x28</addressOffset>
          <size>0x20</size>
          <fields>
            <field>
              <name>FDATAL</name>
              <bitOffset>0</bitOffset>
              <bitWidth>32</bitWidth>
            </field>
          </fields>
        </register>
        <register>
          <name>FAR1</name>
          <addressOffset>0x28</addressOffset>
          <size>0x20</size>
          <fields>
            <field>
              <name>FDATAL</name>
              <bitOffset>0</bitOffset>
              <bitWidth>32</bitWidth>
            </field>
          </fields>
        </register>
        <register>
          <name>FAR1</name>
          <addressOffset>0x28</addressOffset>
          <size>0x20</size>
          <fields>
            <field>
              <name>FDATAL</name>
              <bitOffset>0</bitOffset>
              <bitWidth>32</bitWidth>
            </field>
          </fields>
        </register>
        <register>
          <name>FDRL1</name>
          <addressOffset>0x2c</addressOffset>
          <size>0x20</size>
        </register>
        <register>
          <name>FDRL1</name>
          <addressOffset>0x2c</addressOffset>
          <size>0x20</size>
        </register>
        <register>
          <name>FDRL1</name>
          <addressOffset>0x2c</addressOffset>
          <size>0x20</size>
        </register>
        <register>
          <name>FDRH1</name>
          <addressOffset>0x30</addressOffset>
          <size>0x20</size>
        </register>
        <register>
          <name>FDRH1</name>
          <addressOffset>0x30</addressOffset>
          <size>0x20</size>
        </register>
        <register>
          <name>FDRH1</name>
          <addressOffset>0x30</addressOffset>
          <size>0x20</size>
        </register>
        <register>
          <name>FECR1</name>
          <addressOffset>0x34</addressOffset>
          <size>0x20</size>
          <fields>
            <field>
              <name>FEC</name>
              <bitOffset>0</bitOffset>
              <bitWidth>32</bitWidth>
            </field>
          </fields>
        </register>
        <register>
          <name>FECR1</name>
          <addressOffset>0x34</addressOffset>
          <size>0x20</size>
          <fields>
            <field>
              <name>FEC</name>
              <bitOffset>0</bitOffset>
              <bitWidth>32</bitWidth>
            </field>
          </fields>
        </register>
        <register>
          <name>FECR1</name>
          <addressOffset>0x34</addressOffset>
          <size>0x20</size>
          <fields>
            <field>
              <name>FEC</name>
              <bitOffset>0</bitOffset>
              <bitWidth>32</bitWidth>
            </field>
          </fields>
        </register>
        <register>
          <name>CR2</name>
          <addressOffset>0x40</addressOffset>
          <size>0x20</size>
          <fields>
            <field>
              <name>ECCSEIE</name>
              <bitOffset>2</bitOffset>
              <bitWidth>1</bitWidth>
            </field>
            <field>
              <name>ECCDEIE</name>
              <bitOffset>3</bitOffset>
              <bitWidth>1</bitWidth>
            </field>
            <field>
              <name>ECCDEBWIE</name>
              <bitOffset>4</bitOffset>
              <bitWidth>1</bitWidth>
            </field>
            <field>
              <name>ECCELEN</name>
              <bitOffset>5</bitOffset>
              <bitWidth>1</bitWidth>
            </field>
          </fields>
        </register>
        <register>
          <name>CR2</name>
          <addressOffset>0x40</addressOffset>
          <size>0x20</size>
          <fields>
            <field>
              <name>ECCSEIE</name>
              <bitOffset>2</bitOffset>
              <bitWidth>1</bitWidth>
            </field>
            <field>
              <name>ECCDEIE</name>
              <bitOffset>3</bitOffset>
              <bitWidth>1</bitWidth>
            </field>
            <field>
              <name>ECCDEBWIE</name>
              <bitOffset>4</bitOffset>
              <bitWidth>1</bitWidth>
            </field>
            <field>
              <name>ECCELEN</name>
              <bitOffset>5</bitOffset>
              <bitWidth>1</bitWidth>
            </field>
          </fields>
        </register>
        <register>
          <name>CR2</name>
          <addressOffset>0x40</addressOffset>
          <size>0x20</size>
          <fields>
            <field>
              <name>ECCSEIE</name>
              <bitOffset>2</bitOffset>
              <bitWidth>1</bitWidth>
            </field>
            <field>
              <name>ECCDEIE</name>
              <bitOffset>3</bitOffset>
              <bitWidth>1</bitWidth>
            </field>
            <field>
              <name>ECCDEBWIE</name>
              <bitOffset>4</bitOffset>
              <bitWidth>1</bitWidth>
            </field>
            <field>
              <name>ECCELEN</name>
              <bitOffset>5</bitOffset>
              <bitWidth>1</bitWidth>
            </field>
          </fields>
        </register>
        <register>
          <name>SR2</name>
          <addressOffset>0x44</addressOffset>
          <size>0x20</size>
          <fields>
            <field>
              <name>SEDCF</name>
              <bitOffset>0</bitOffset>
              <bitWidth>1</bitWidth>
            </field>
            <field>
              <name>DEDF</name>
              <bitOffset>1</bitOffset>
              <bitWidth>1</bitWidth>
            </field>
            <field>
              <name>DEBWDF</name>
              <bitOffset>2</bitOffset>
              <bitWidth>1</bitWidth>
            </field>
          </fields>
        </register>
        <register>
          <name>SR2</name>
          <addressOffset>0x44</addressOffset>
          <size>0x20</size>
          <fields>
            <field>
              <name>SEDCF</name>
              <bitOffset>0</bitOffset>
              <bitWidth>1</bitWidth>
            </field>
            <field>
              <name>DEDF</name>
              <bitOffset>1</bitOffset>
              <bitWidth>1</bitWidth>
            </field>
            <field>
              <name>DEBWDF</name>
              <bitOffset>2</bitOffset>
              <bitWidth>1</bitWidth>
            </field>
          </fields>
        </register>
        <register>
          <name>SR2</name>
          <addressOffset>0x44</addressOffset>
          <size>0x20</size>
          <fields>
            <field>
              <name>SEDCF</name>
              <bitOffset>0</bitOffset>
              <bitWidth>1</bitWidth>
            </field>
            <field>
              <name>DEDF</name>
              <bitOffset>1</bitOffset>
              <bitWidth>1</bitWidth>
            </field>
            <field>
              <name>DEBWDF</name>
              <bitOffset>2</bitOffset>
              <bitWidth>1</bitWidth>
            </field>
          </fields>
        </register>
        <register>
          <name>FAR2</name>
          <addressOffset>0x48</addressOffset>
          <size>0x20</size>
          <fields>
            <field>
              <name>FDATAL</name>
              <bitOffset>0</bitOffset>
              <bitWidth>32</bitWidth>
            </field>
          </fields>
        </register>
        <register>
          <name>FAR2</name>
          <addressOffset>0x48</addressOffset>
          <size>0x20</size>
          <fields>
            <field>
              <name>FDATAL</name>
              <bitOffset>0</bitOffset>
              <bitWidth>32</bitWidth>
            </field>
          </fields>
        </register>
        <register>
          <name>FAR2</name>
          <addressOffset>0x48</addressOffset>
          <size>0x20</size>
          <fields>
            <field>
              <name>FDATAL</name>
              <bitOffset>0</bitOffset>
              <bitWidth>32</bitWidth>
            </field>
          </fields>
        </register>
        <register>
          <name>FDRL2</name>
          <addressOffset>0x4c</addressOffset>
          <size>0x20</size>
        </register>
        <register>
          <name>FDRL2</name>
          <addressOffset>0x4c</addressOffset>
          <size>0x20</size>
        </register>
        <register>
          <name>FDRL2</name>
          <addressOffset>0x4c</addressOffset>
          <size>0x20</size>
        </register>
        <register>
          <name>FDRH2</name>
          <addressOffset>0x50</addressOffset>
          <size>0x20</size>
        </register>
        <register>
          <name>FDRH2</name>
          <addressOffset>0x50</addressOffset>
          <size>0x20</size>
        </register>
        <register>
          <name>FDRH2</name>
          <addressOffset>0x50</addressOffset>
          <size>0x20</size>
        </register>
        <register>
          <name>FECR2</name>
          <addressOffset>0x54</addressOffset>
          <size>0x20</size>
          <fields>
            <field>
              <name>FEC</name>
              <bitOffset>0</bitOffset>
              <bitWidth>32</bitWidth>
            </field>
          </fields>
        </register>
        <register>
          <name>FECR2</name>
          <addressOffset>0x54</addressOffset>
          <size>0x20</size>
          <fields>
            <field>
              <name>FEC</name>
              <bitOffset>0</bitOffset>
              <bitWidth>32</bitWidth>
            </field>
          </fields>
        </register>
        <register>
          <name>FECR2</name>
          <addressOffset>0x54</addressOffset>
          <size>0x20</size>
          <fields>
            <field>
              <name>FEC</name>
              <bitOffset>0</bitOffset>
              <bitWidth>32</bitWidth>
            </field>
          </fields>
        </register>
        <register>
          <name>CR3</name>
          <addressOffset>0x60</addressOffset>
          <size>0x20</size>
          <fields>
            <field>
              <name>ECCSEIE</name>
              <bitOffset>2</bitOffset>
              <bitWidth>1</bitWidth>
            </field>
            <field>
              <name>ECCDEIE</name>
              <bitOffset>3</bitOffset>
              <bitWidth>1</bitWidth>
            </field>
            <field>
              <name>ECCDEBWIE</name>
              <bitOffset>4</bitOffset>
              <bitWidth>1</bitWidth>
            </field>
            <field>
              <name>ECCELEN</name>
              <bitOffset>5</bitOffset>
              <bitWidth>1</bitWidth>
            </field>
          </fields>
        </register>
        <register>
          <name>CR3</name>
          <addressOffset>0x60</addressOffset>
          <size>0x20</size>
          <fields>
            <field>
              <name>ECCSEIE</name>
              <bitOffset>2</bitOffset>
              <bitWidth>1</bitWidth>
            </field>
            <field>
              <name>ECCDEIE</name>
              <bitOffset>3</bitOffset>
              <bitWidth>1</bitWidth>
            </field>
            <field>
              <name>ECCDEBWIE</name>
              <bitOffset>4</bitOffset>
              <bitWidth>1</bitWidth>
            </field>
            <field>
              <name>ECCELEN</name>
              <bitOffset>5</bitOffset>
              <bitWidth>1</bitWidth>
            </field>
          </fields>
        </register>
        <register>
          <name>SR3</name>
          <addressOffset>0x64</addressOffset>
          <size>0x20</size>
          <fields>
            <field>
              <name>SEDCF</name>
              <bitOffset>0</bitOffset>
              <bitWidth>1</bitWidth>
            </field>
            <field>
              <name>DEDF</name>
              <bitOffset>1</bitOffset>
              <bitWidth>1</bitWidth>
            </field>
            <field>
              <name>DEBWDF</name>
              <bitOffset>2</bitOffset>
              <bitWidth>1</bitWidth>
            </field>
          </fields>
        </register>
        <register>
          <name>SR3</name>
          <addressOffset>0x64</addressOffset>
          <size>0x20</size>
          <fields>
            <field>
              <name>SEDCF</name>
              <bitOffset>0</bitOffset>
              <bitWidth>1</bitWidth>
            </field>
            <field>
              <name>DEDF</name>
              <bitOffset>1</bitOffset>
              <bitWidth>1</bitWidth>
            </field>
            <field>
              <name>DEBWDF</name>
              <bitOffset>2</bitOffset>
              <bitWidth>1</bitWidth>
            </field>
          </fields>
        </register>
        <register>
          <name>FAR3</name>
          <addressOffset>0x68</addressOffset>
          <size>0x20</size>
          <fields>
            <field>
              <name>FDATAL</name>
              <bitOffset>0</bitOffset>
              <bitWidth>32</bitWidth>
            </field>
          </fields>
        </register>
        <register>
          <name>FAR3</name>
          <addressOffset>0x68</addressOffset>
          <size>0x20</size>
          <fields>
            <field>
              <name>FDATAL</name>
              <bitOffset>0</bitOffset>
              <bitWidth>32</bitWidth>
            </field>
          </fields>
        </register>
        <register>
          <name>FDRL3</name>
          <addressOffset>0x6c</addressOffset>
          <size>0x20</size>
        </register>
        <register>
          <name>FDRL3</name>
          <addressOffset>0x6c</addressOffset>
          <size>0x20</size>
        </register>
        <register>
          <name>FDRH3</name>
          <addressOffset>0x70</addressOffset>
          <size>0x20</size>
        </register>
        <register>
          <name>FDRH3</name>
          <addressOffset>0x70</addressOffset>
          <size>0x20</size>
        </register>
        <register>
          <name>FECR3</name>
          <addressOffset>0x74</addressOffset>
          <size>0x20</size>
          <fields>
            <field>
              <name>FEC</name>
              <bitOffset>0</bitOffset>
              <bitWidth>32</bitWidth>
            </field>
          </fields>
        </register>
        <register>
          <name>FECR3</name>
          <addressOffset>0x74</addressOffset>
          <size>0x20</size>
          <fields>
            <field>
              <name>FEC</name>
              <bitOffset>0</bitOffset>
              <bitWidth>32</bitWidth>
            </field>
          </fields>
        </register>
        <register>
          <name>CR4</name>
          <addressOffset>0x80</addressOffset>
          <size>0x20</size>
          <fields>
            <field>
              <name>ECCSEIE</name>
              <bitOffset>2</bitOffset>
              <bitWidth>1</bitWidth>
            </field>
            <field>
              <name>ECCDEIE</name>
              <bitOffset>3</bitOffset>
              <bitWidth>1</bitWidth>
            </field>
            <field>
              <name>ECCDEBWIE</name>
              <bitOffset>4</bitOffset>
              <bitWidth>1</bitWidth>
            </field>
            <field>
              <name>ECCELEN</name>
              <bitOffset>5</bitOffset>
              <bitWidth>1</bitWidth>
            </field>
          </fields>
        </register>
        <register>
          <name>SR4</name>
          <addressOffset>0x84</addressOffset>
          <size>0x20</size>
          <fields>
            <field>
              <name>SEDCF</name>
              <bitOffset>0</bitOffset>
              <bitWidth>1</bitWidth>
            </field>
            <field>
              <name>DEDF</name>
              <bitOffset>1</bitOffset>
              <bitWidth>1</bitWidth>
            </field>
            <field>
              <name>DEBWDF</name>
              <bitOffset>2</bitOffset>
              <bitWidth>1</bitWidth>
            </field>
          </fields>
        </register>
        <register>
          <name>FAR4</name>
          <addressOffset>0x88</addressOffset>
          <size>0x20</size>
          <fields>
            <field>
              <name>FDATAL</name>
              <bitOffset>0</bitOffset>
              <bitWidth>32</bitWidth>
            </field>
          </fields>
        </register>
        <register>
          <name>FDRL4</name>
          <addressOffset>0x8c</addressOffset>
          <size>0x20</size>
        </register>
        <register>
          <name>FDRH4</name>
          <addressOffset>0x90</addressOffset>
          <size>0x20</size>
        </register>
        <register>
          <name>FECR4</name>
          <addressOffset>0x94</addressOffset>
          <size>0x20</size>
          <fields>
            <field>
              <name>FEC</name>
              <bitOffset>0</bitOffset>
              <bitWidth>32</bitWidth>
            </field>
          </fields>
        </register>
        <register>
          <name>CR5</name>
          <addressOffset>0xa0</addressOffset>
          <size>0x20</size>
          <fields>
            <field>
              <name>ECCSEIE</name>
              <bitOffset>2</bitOffset>
              <bitWidth>1</bitWidth>
            </field>
            <field>
              <name>ECCDEIE</name>
              <bitOffset>3</bitOffset>
              <bitWidth>1</bitWidth>
            </field>
            <field>
              <name>ECCDEBWIE</name>
              <bitOffset>4</bitOffset>
              <bitWidth>1</bitWidth>
            </field>
            <field>
              <name>ECCELEN</name>
              <bitOffset>5</bitOffset>
              <bitWidth>1</bitWidth>
            </field>
          </fields>
        </register>
        <register>
          <name>SR5</name>
          <addressOffset>0xa4</addressOffset>
          <size>0x20</size>
          <fields>
            <field>
              <name>SEDCF</name>
              <bitOffset>0</bitOffset>
              <bitWidth>1</bitWidth>
            </field>
            <field>
              <name>DEDF</name>
              <bitOffset>1</bitOffset>
              <bitWidth>1</bitWidth>
            </field>
            <field>
              <name>DEBWDF</name>
              <bitOffset>2</bitOffset>
              <bitWidth>1</bitWidth>
            </field>
          </fields>
        </register>
        <register>
          <name>FAR5</name>
          <addressOffset>0xa8</addressOffset>
          <size>0x20</size>
          <fields>
            <field>
              <name>FDATAL</name>
              <bitOffset>0</bitOffset>
              <bitWidth>32</bitWidth>
            </field>
          </fields>
        </register>
        <register>
          <name>FDRL5</name>
          <addressOffset>0xac</addressOffset>
          <size>0x20</size>
        </register>
        <register>
          <name>FDRH5</name>
          <addressOffset>0xb0</addressOffset>
          <size>0x20</size>
        </register>
        <register>
          <name>FECR5</name>
          <addressOffset>0xb4</addressOffset>
          <size>0x20</size>
          <fields>
            <field>
              <name>FEC</name>
              <bitOffset>0</bitOffset>
              <bitWidth>32</bitWidth>
            </field>
          </fields>
        </register>
        <register>
          <name>CR6</name>
          <addressOffset>0xc0</addressOffset>
          <size>0x20</size>
          <fields>
            <field>
              <name>ECCSEIE</name>
              <bitOffset>2</bitOffset>
              <bitWidth>1</bitWidth>
            </field>
            <field>
              <name>ECCDEIE</name>
              <bitOffset>3</bitOffset>
              <bitWidth>1</bitWidth>
            </field>
            <field>
              <name>ECCDEBWIE</name>
              <bitOffset>4</bitOffset>
              <bitWidth>1</bitWidth>
            </field>
            <field>
              <name>ECCELEN</name>
              <bitOffset>5</bitOffset>
              <bitWidth>1</bitWidth>
            </field>
          </fields>
        </register>
        <register>
          <name>SR6</name>
          <addressOffset>0xc4</addressOffset>
          <size>0x20</size>
          <fields>
            <field>
              <name>SEDCF</name>
              <bitOffset>0</bitOffset>
              <bitWidth>1</bitWidth>
            </field>
            <field>
              <name>DEDF</name>
              <bitOffset>1</bitOffset>
              <bitWidth>1</bitWidth>
            </field>
            <field>
              <name>DEBWDF</name>
              <bitOffset>2</bitOffset>
              <bitWidth>1</bitWidth>
            </field>
          </fields>
        </register>
        <register>
          <name>FAR6</name>
          <addressOffset>0xc8</addressOffset>
          <size>0x20</size>
          <fields>
            <field>
              <name>FDATAL</name>
              <bitOffset>0</bitOffset>
              <bitWidth>32</bitWidth>
            </field>
          </fields>
        </register>
        <register>
          <name>FDRL6</name>
          <addressOffset>0xcc</addressOffset>
          <size>0x20</size>
        </register>
        <register>
          <name>FDRH6</name>
          <addressOffset>0xd0</addressOffset>
          <size>0x20</size>
        </register>
        <register>
          <name>FECR6</name>
          <addressOffset>0xd4</addressOffset>
          <size>0x20</size>
          <fields>
            <field>
              <name>FEC</name>
              <bitOffset>0</bitOffset>
              <bitWidth>32</bitWidth>
            </field>
          </fields>
        </register>
      </registers>
    </peripheral>
    <peripheral>
      <name>FMAC</name>
      <baseAddress>0x48024000</baseAddress>
      <registers>
        <register>
          <name>X1BUFCFG</name>
          <addressOffset>0x0</addressOffset>
          <size>0x20</size>
          <fields>
            <field>
              <name>X1_BASE</name>
              <bitOffset>0</bitOffset>
              <bitWidth>8</bitWidth>
            </field>
            <field>
              <name>X1_BUF_SIZE</name>
              <bitOffset>8</bitOffset>
              <bitWidth>8</bitWidth>
            </field>
            <field>
              <name>FULL_WM</name>
              <bitOffset>24</bitOffset>
              <bitWidth>2</bitWidth>
            </field>
          </fields>
        </register>
        <register>
          <name>X2BUFCFG</name>
          <addressOffset>0x4</addressOffset>
          <size>0x20</size>
          <fields>
            <field>
              <name>X2_BASE</name>
              <bitOffset>0</bitOffset>
              <bitWidth>8</bitWidth>
            </field>
            <field>
              <name>X2_BUF_SIZE</name>
              <bitOffset>8</bitOffset>
              <bitWidth>8</bitWidth>
            </field>
          </fields>
        </register>
        <register>
          <name>YBUFCFG</name>
          <addressOffset>0x8</addressOffset>
          <size>0x20</size>
          <fields>
            <field>
              <name>Y_BASE</name>
              <bitOffset>0</bitOffset>
              <bitWidth>8</bitWidth>
            </field>
            <field>
              <name>Y_BUF_SIZE</name>
              <bitOffset>8</bitOffset>
              <bitWidth>8</bitWidth>
            </field>
            <field>
              <name>EMPTY_WM</name>
              <bitOffset>24</bitOffset>
              <bitWidth>2</bitWidth>
            </field>
          </fields>
        </register>
        <register>
          <name>PARAM</name>
          <addressOffset>0xc</addressOffset>
          <size>0x20</size>
          <fields>
            <field>
              <name>P</name>
              <bitOffset>0</bitOffset>
              <bitWidth>8</bitWidth>
            </field>
            <field>
              <name>Q</name>
              <bitOffset>8</bitOffset>
              <bitWidth>8</bitWidth>
            </field>
            <field>
              <name>R</name>
              <bitOffset>16</bitOffset>
              <bitWidth>8</bitWidth>
            </field>
            <field>
              <name>FUNC</name>
              <bitOffset>24</bitOffset>
              <bitWidth>7</bitWidth>
            </field>
            <field>
              <name>START</name>
              <bitOffset>31</bitOffset>
              <bitWidth>1</bitWidth>
            </field>
          </fields>
        </register>
        <register>
          <name>CR</name>
          <addressOffset>0x10</addressOffset>
          <size>0x20</size>
          <fields>
            <field>
              <name>RIEN</name>
              <bitOffset>0</bitOffset>
              <bitWidth>1</bitWidth>
            </field>
            <field>
              <name>WIEN</name>
              <bitOffset>1</bitOffset>
              <bitWidth>1</bitWidth>
            </field>
            <field>
              <name>OVFLIEN</name>
              <bitOffset>2</bitOffset>
              <bitWidth>1</bitWidth>
            </field>
            <field>
              <name>UNFLIEN</name>
              <bitOffset>3</bitOffset>
              <bitWidth>1</bitWidth>
            </field>
            <field>
              <name>SATIEN</name>
              <bitOffset>4</bitOffset>
              <bitWidth>1</bitWidth>
            </field>
            <field>
              <name>DMAREN</name>
              <bitOffset>8</bitOffset>
              <bitWidth>1</bitWidth>
            </field>
            <field>
              <name>DMAWEN</name>
              <bitOffset>9</bitOffset>
              <bitWidth>1</bitWidth>
            </field>
            <field>
              <name>CLIPEN</name>
              <bitOffset>15</bitOffset>
              <bitWidth>1</bitWidth>
            </field>
            <field>
              <name>RESET</name>
              <bitOffset>16</bitOffset>
              <bitWidth>1</bitWidth>
            </field>
          </fields>
        </register>
        <register>
          <name>SR</name>
          <addressOffset>0x14</addressOffset>
          <size>0x20</size>
          <fields>
            <field>
              <name>YEMPTY</name>
              <bitOffset>0</bitOffset>
              <bitWidth>1</bitWidth>
            </field>
            <field>
              <name>X1FULL</name>
              <bitOffset>1</bitOffset>
              <bitWidth>1</bitWidth>
            </field>
            <field>
              <name>OVFL</name>
              <bitOffset>8</bitOffset>
              <bitWidth>1</bitWidth>
            </field>
            <field>
              <name>UNFL</name>
              <bitOffset>9</bitOffset>
              <bitWidth>1</bitWidth>
            </field>
            <field>
              <name>SAT</name>
              <bitOffset>10</bitOffset>
              <bitWidth>1</bitWidth>
            </field>
          </fields>
        </register>
        <register>
          <name>WDATA</name>
          <addressOffset>0x18</addressOffset>
          <size>0x20</size>
          <fields>
            <field>
              <name>WDATA</name>
              <bitOffset>0</bitOffset>
              <bitWidth>16</bitWidth>
            </field>
          </fields>
        </register>
        <register>
          <name>RDATA</name>
          <addressOffset>0x1c</addressOffset>
          <size>0x20</size>
          <fields>
            <field>
              <name>RDATA</name>
              <bitOffset>0</bitOffset>
              <bitWidth>16</bitWidth>
            </field>
          </fields>
        </register>
      </registers>
    </peripheral>
    <peripheral>
      <name>CORDIC</name>
      <baseAddress>0x48024400</baseAddress>
      <registers>
        <register>
          <name>CSR</name>
          <addressOffset>0x0</addressOffset>
          <size>0x20</size>
          <fields>
            <field>
              <name>FUNC</name>
              <bitOffset>0</bitOffset>
              <bitWidth>4</bitWidth>
            </field>
            <field>
              <name>PRECISION</name>
              <bitOffset>4</bitOffset>
              <bitWidth>4</bitWidth>
            </field>
            <field>
              <name>SCALE</name>
              <bitOffset>8</bitOffset>
              <bitWidth>3</bitWidth>
            </field>
            <field>
              <name>IEN</name>
              <bitOffset>16</bitOffset>
              <bitWidth>1</bitWidth>
            </field>
            <field>
              <name>DMAREN</name>
              <bitOffset>17</bitOffset>
              <bitWidth>1</bitWidth>
            </field>
            <field>
              <name>DMAWEN</name>
              <bitOffset>18</bitOffset>
              <bitWidth>1</bitWidth>
            </field>
            <field>
              <name>NRES</name>
              <bitOffset>19</bitOffset>
              <bitWidth>1</bitWidth>
            </field>
            <field>
              <name>NARGS</name>
              <bitOffset>20</bitOffset>
              <bitWidth>1</bitWidth>
            </field>
            <field>
              <name>RESSIZE</name>
              <bitOffset>21</bitOffset>
              <bitWidth>1</bitWidth>
            </field>
            <field>
              <name>ARGSIZE</name>
              <bitOffset>22</bitOffset>
              <bitWidth>1</bitWidth>
            </field>
            <field>
              <name>RRDY</name>
              <bitOffset>31</bitOffset>
              <bitWidth>1</bitWidth>
            </field>
          </fields>
        </register>
        <register>
          <name>WDATA</name>
          <addressOffset>0x4</addressOffset>
          <size>0x20</size>
          <fields>
            <field>
              <name>ARG</name>
              <bitOffset>0</bitOffset>
              <bitWidth>32</bitWidth>
            </field>
          </fields>
        </register>
        <register>
          <name>RDATA</name>
          <addressOffset>0x8</addressOffset>
          <size>0x20</size>
          <fields>
            <field>
              <name>RES</name>
              <bitOffset>0</bitOffset>
              <bitWidth>32</bitWidth>
            </field>
          </fields>
        </register>
      </registers>
    </peripheral>
    <peripheral>
      <name>LTDC</name>
      <baseAddress>0x50001000</baseAddress>
      <registers>
        <register>
          <name>SSCR</name>
          <addressOffset>0x8</addressOffset>
          <size>0x20</size>
          <fields>
            <field>
              <name>VSH</name>
              <bitOffset>0</bitOffset>
              <bitWidth>11</bitWidth>
            </field>
            <field>
              <name>HSW</name>
              <bitOffset>16</bitOffset>
              <bitWidth>12</bitWidth>
            </field>
          </fields>
        </register>
        <register>
          <name>BPCR</name>
          <addressOffset>0xc</addressOffset>
          <size>0x20</size>
          <fields>
            <field>
              <name>AVBP</name>
              <bitOffset>0</bitOffset>
              <bitWidth>11</bitWidth>
            </field>
            <field>
              <name>AHBP</name>
              <bitOffset>16</bitOffset>
              <bitWidth>12</bitWidth>
            </field>
          </fields>
        </register>
        <register>
          <name>AWCR</name>
          <addressOffset>0x10</addressOffset>
          <size>0x20</size>
          <fields>
            <field>
              <name>AAH</name>
              <bitOffset>0</bitOffset>
              <bitWidth>11</bitWidth>
            </field>
            <field>
              <name>AAW</name>
              <bitOffset>16</bitOffset>
              <bitWidth>12</bitWidth>
            </field>
          </fields>
        </register>
        <register>
          <name>TWCR</name>
          <addressOffset>0x14</addressOffset>
          <size>0x20</size>
          <fields>
            <field>
              <name>TOTALH</name>
              <bitOffset>0</bitOffset>
              <bitWidth>11</bitWidth>
            </field>
            <field>
              <name>TOTALW</name>
              <bitOffset>16</bitOffset>
              <bitWidth>12</bitWidth>
            </field>
          </fields>
        </register>
        <register>
          <name>GCR</name>
          <addressOffset>0x18</addressOffset>
          <size>0x20</size>
          <fields>
            <field>
              <name>LTDCEN</name>
              <bitOffset>0</bitOffset>
              <bitWidth>1</bitWidth>
            </field>
            <field>
              <name>DBW</name>
              <bitOffset>4</bitOffset>
              <bitWidth>3</bitWidth>
            </field>
            <field>
              <name>DGW</name>
              <bitOffset>8</bitOffset>
              <bitWidth>3</bitWidth>
            </field>
            <field>
              <name>DRW</name>
              <bitOffset>12</bitOffset>
              <bitWidth>3</bitWidth>
            </field>
            <field>
              <name>DEN</name>
              <bitOffset>16</bitOffset>
              <bitWidth>1</bitWidth>
            </field>
            <field>
              <name>PCPOL</name>
              <bitOffset>28</bitOffset>
              <bitWidth>1</bitWidth>
            </field>
            <field>
              <name>DEPOL</name>
              <bitOffset>29</bitOffset>
              <bitWidth>1</bitWidth>
            </field>
            <field>
              <name>VSPOL</name>
              <bitOffset>30</bitOffset>
              <bitWidth>1</bitWidth>
            </field>
            <field>
              <name>HSPOL</name>
              <bitOffset>31</bitOffset>
              <bitWidth>1</bitWidth>
            </field>
          </fields>
        </register>
        <register>
          <name>SRCR</name>
          <addressOffset>0x24</addressOffset>
          <size>0x20</size>
          <fields>
            <field>
              <name>IMR</name>
              <bitOffset>0</bitOffset>
              <bitWidth>1</bitWidth>
            </field>
            <field>
              <name>VBR</name>
              <bitOffset>1</bitOffset>
              <bitWidth>1</bitWidth>
            </field>
          </fields>
        </register>
        <register>
          <name>BCCR</name>
          <addressOffset>0x2c</addressOffset>
          <size>0x20</size>
          <fields>
            <field>
              <name>BCBLUE</name>
              <bitOffset>0</bitOffset>
              <bitWidth>8</bitWidth>
            </field>
            <field>
              <name>BCGREEN</name>
              <bitOffset>8</bitOffset>
              <bitWidth>8</bitWidth>
            </field>
            <field>
              <name>BCRED</name>
              <bitOffset>16</bitOffset>
              <bitWidth>8</bitWidth>
            </field>
          </fields>
        </register>
        <register>
          <name>IER</name>
          <addressOffset>0x34</addressOffset>
          <size>0x20</size>
          <fields>
            <field>
              <name>LIE</name>
              <bitOffset>0</bitOffset>
              <bitWidth>1</bitWidth>
            </field>
            <field>
              <name>FUIE</name>
              <bitOffset>1</bitOffset>
              <bitWidth>1</bitWidth>
            </field>
            <field>
              <name>TERRIE</name>
              <bitOffset>2</bitOffset>
              <bitWidth>1</bitWidth>
            </field>
            <field>
              <name>RRIE</name>
              <bitOffset>3</bitOffset>
              <bitWidth>1</bitWidth>
            </field>
          </fields>
        </register>
        <register>
          <name>ISR</name>
          <addressOffset>0x38</addressOffset>
          <size>0x20</size>
          <fields>
            <field>
              <name>LIF</name>
              <bitOffset>0</bitOffset>
              <bitWidth>1</bitWidth>
            </field>
            <field>
              <name>FUIF</name>
              <bitOffset>1</bitOffset>
              <bitWidth>1</bitWidth>
            </field>
            <field>
              <name>TERRIF</name>
              <bitOffset>2</bitOffset>
              <bitWidth>1</bitWidth>
            </field>
            <field>
              <name>RRIF</name>
              <bitOffset>3</bitOffset>
              <bitWidth>1</bitWidth>
            </field>
          </fields>
        </register>
        <register>
          <name>ICR</name>
          <addressOffset>0x3c</addressOffset>
          <size>0x20</size>
          <fields>
            <field>
              <name>CLIF</name>
              <bitOffset>0</bitOffset>
              <bitWidth>1</bitWidth>
            </field>
            <field>
              <name>CFUIF</name>
              <bitOffset>1</bitOffset>
              <bitWidth>1</bitWidth>
            </field>
            <field>
              <name>CTERRIF</name>
              <bitOffset>2</bitOffset>
              <bitWidth>1</bitWidth>
            </field>
            <field>
              <name>CRRIF</name>
              <bitOffset>3</bitOffset>
              <bitWidth>1</bitWidth>
            </field>
          </fields>
        </register>
        <register>
          <name>LIPCR</name>
          <addressOffset>0x40</addressOffset>
          <size>0x20</size>
          <fields>
            <field>
              <name>LIPOS</name>
              <bitOffset>0</bitOffset>
              <bitWidth>11</bitWidth>
            </field>
          </fields>
        </register>
        <register>
          <name>CPSR</name>
          <addressOffset>0x44</addressOffset>
          <size>0x20</size>
          <fields>
            <field>
              <name>CYPOS</name>
              <bitOffset>0</bitOffset>
              <bitWidth>16</bitWidth>
            </field>
            <field>
              <name>CXPOS</name>
              <bitOffset>16</bitOffset>
              <bitWidth>16</bitWidth>
            </field>
          </fields>
        </register>
        <register>
          <name>CDSR</name>
          <addressOffset>0x48</addressOffset>
          <size>0x20</size>
          <fields>
            <field>
              <name>VDES</name>
              <bitOffset>0</bitOffset>
              <bitWidth>1</bitWidth>
            </field>
            <field>
              <name>HDES</name>
              <bitOffset>1</bitOffset>
              <bitWidth>1</bitWidth>
            </field>
            <field>
              <name>VSYNCS</name>
              <bitOffset>2</bitOffset>
              <bitWidth>1</bitWidth>
            </field>
            <field>
              <name>HSYNCS</name>
              <bitOffset>3</bitOffset>
              <bitWidth>1</bitWidth>
            </field>
          </fields>
        </register>
        <register>
          <name>CR1</name>
          <addressOffset>0x84</addressOffset>
          <size>0x20</size>
        </register>
        <register>
          <name>WHPCR1</name>
          <addressOffset>0x88</addressOffset>
          <size>0x20</size>
        </register>
        <register>
          <name>WVPCR1</name>
          <addressOffset>0x8c</addressOffset>
          <size>0x20</size>
        </register>
        <register>
          <name>CKCR1</name>
          <addressOffset>0x90</addressOffset>
          <size>0x20</size>
        </register>
        <register>
          <name>PFCR1</name>
          <addressOffset>0x94</addressOffset>
          <size>0x20</size>
        </register>
        <register>
          <name>CACR1</name>
          <addressOffset>0x98</addressOffset>
          <size>0x20</size>
        </register>
        <register>
          <name>DCCR1</name>
          <addressOffset>0x9c</addressOffset>
          <size>0x20</size>
        </register>
        <register>
          <name>BFCR1</name>
          <addressOffset>0xa0</addressOffset>
          <size>0x20</size>
        </register>
        <register>
          <name>CFBAR1</name>
          <addressOffset>0xac</addressOffset>
          <size>0x20</size>
        </register>
        <register>
          <name>CFBLR1</name>
          <addressOffset>0xb0</addressOffset>
          <size>0x20</size>
        </register>
        <register>
          <name>CFBLNR1</name>
          <addressOffset>0xb4</addressOffset>
          <size>0x20</size>
        </register>
        <register>
          <name>CLUTWR1</name>
          <addressOffset>0xc4</addressOffset>
          <size>0x20</size>
        </register>
        <register>
          <name>CR2</name>
          <addressOffset>0x104</addressOffset>
          <size>0x20</size>
        </register>
        <register>
          <name>WHPCR2</name>
          <addressOffset>0x108</addressOffset>
          <size>0x20</size>
        </register>
        <register>
          <name>WVPCR2</name>
          <addressOffset>0x10c</addressOffset>
          <size>0x20</size>
        </register>
        <register>
          <name>CKCR2</name>
          <addressOffset>0x110</addressOffset>
          <size>0x20</size>
        </register>
        <register>
          <name>PFCR2</name>
          <addressOffset>0x114</addressOffset>
          <size>0x20</size>
        </register>
        <register>
          <name>CACR2</name>
          <addressOffset>0x118</addressOffset>
          <size>0x20</size>
        </register>
        <register>
          <name>DCCR2</name>
          <addressOffset>0x11c</addressOffset>
          <size>0x20</size>
        </register>
        <register>
          <name>BFCR2</name>
          <addressOffset>0x120</addressOffset>
          <size>0x20</size>
        </register>
        <register>
          <name>CFBAR2</name>
          <addressOffset>0x12c</addressOffset>
          <size>0x20</size>
        </register>
        <register>
          <name>CFBLR2</name>
          <addressOffset>0x130</addressOffset>
          <size>0x20</size>
        </register>
        <register>
          <name>CFBLNR2</name>
          <addressOffset>0x134</addressOffset>
          <size>0x20</size>
        </register>
        <register>
          <name>CLUTWR2</name>
          <addressOffset>0x144</addressOffset>
          <size>0x20</size>
        </register>
      </registers>
    </peripheral>
    <peripheral>
      <name>WWDG1</name>
      <baseAddress>0x50003000</baseAddress>
      <registers>
        <register>
          <name>CR</name>
          <addressOffset>0x0</addressOffset>
          <size>0x20</size>
          <fields>
            <field>
              <name>T</name>
              <bitOffset>0</bitOffset>
              <bitWidth>7</bitWidth>
            </field>
            <field>
              <name>WDGA</name>
              <bitOffset>7</bitOffset>
              <bitWidth>1</bitWidth>
            </field>
          </fields>
        </register>
        <register>
          <name>CFR</name>
          <addressOffset>0x4</addressOffset>
          <size>0x20</size>
          <fields>
            <field>
              <name>W</name>
              <bitOffset>0</bitOffset>
              <bitWidth>7</bitWidth>
            </field>
            <field>
              <name>EWI</name>
              <bitOffset>9</bitOffset>
              <bitWidth>1</bitWidth>
            </field>
            <field>
              <name>WDGTB</name>
              <bitOffset>11</bitOffset>
              <bitWidth>3</bitWidth>
            </field>
          </fields>
        </register>
        <register>
          <name>SR</name>
          <addressOffset>0x8</addressOffset>
          <size>0x20</size>
          <fields>
            <field>
              <name>EWIF</name>
              <bitOffset>0</bitOffset>
              <bitWidth>1</bitWidth>
            </field>
          </fields>
        </register>
      </registers>
    </peripheral>
    <peripheral>
      <name>GPV</name>
      <baseAddress>0x51000000</baseAddress>
      <registers>
        <register>
          <name>AXI_PERIPH_ID_4</name>
          <addressOffset>0x1fd0</addressOffset>
          <size>0x20</size>
        </register>
        <register>
          <name>AXI_PERIPH_ID_5</name>
          <addressOffset>0x1fd4</addressOffset>
          <size>0x20</size>
        </register>
        <register>
          <name>AXI_PERIPH_ID_6</name>
          <addressOffset>0x1fd8</addressOffset>
          <size>0x20</size>
        </register>
        <register>
          <name>AXI_PERIPH_ID_7</name>
          <addressOffset>0x1fdc</addressOffset>
          <size>0x20</size>
        </register>
        <register>
          <name>AXI_PERIPH_ID_0</name>
          <addressOffset>0x1fe0</addressOffset>
          <size>0x20</size>
        </register>
        <register>
          <name>AXI_PERIPH_ID_1</name>
          <addressOffset>0x1fe4</addressOffset>
          <size>0x20</size>
        </register>
        <register>
          <name>AXI_PERIPH_ID_2</name>
          <addressOffset>0x1fe8</addressOffset>
          <size>0x20</size>
        </register>
        <register>
          <name>AXI_PERIPH_ID_3</name>
          <addressOffset>0x1fec</addressOffset>
          <size>0x20</size>
        </register>
        <register>
          <name>AXI_COMP_ID_0</name>
          <addressOffset>0x1ff0</addressOffset>
          <size>0x20</size>
        </register>
        <register>
          <name>AXI_COMP_ID_1</name>
          <addressOffset>0x1ff4</addressOffset>
          <size>0x20</size>
        </register>
        <register>
          <name>AXI_COMP_ID_2</name>
          <addressOffset>0x1ff8</addressOffset>
          <size>0x20</size>
        </register>
        <register>
          <name>AXI_COMP_ID_3</name>
          <addressOffset>0x1ffc</addressOffset>
          <size>0x20</size>
        </register>
        <register>
          <name>AXI_TARG1_FN_MOD_ISS_BM</name>
          <addressOffset>0x2008</addressOffset>
          <size>0x20</size>
        </register>
        <register>
          <name>AXI_TARG1_FN_MOD2</name>
          <addressOffset>0x2024</addressOffset>
          <size>0x20</size>
        </register>
        <register>
          <name>AXI_TARG1_FN_MOD_LB</name>
          <addressOffset>0x202c</addressOffset>
          <size>0x20</size>
        </register>
        <register>
          <name>AXI_TARG1_FN_MOD</name>
          <addressOffset>0x2108</addressOffset>
          <size>0x20</size>
        </register>
        <register>
          <name>AXI_TARG2_FN_MOD_ISS_BM</name>
          <addressOffset>0x3008</addressOffset>
          <size>0x20</size>
        </register>
        <register>
          <name>AXI_TARG2_FN_MOD2</name>
          <addressOffset>0x3024</addressOffset>
          <size>0x20</size>
        </register>
        <register>
          <name>AXI_TARG2_FN_MOD_LB</name>
          <addressOffset>0x302c</addressOffset>
          <size>0x20</size>
        </register>
        <register>
          <name>AXI_TARG2_FN_MOD</name>
          <addressOffset>0x3108</addressOffset>
          <size>0x20</size>
        </register>
        <register>
          <name>AXI_TARG3_FN_MOD_ISS_BM</name>
          <addressOffset>0x4008</addressOffset>
          <size>0x20</size>
        </register>
        <register>
          <name>AXI_TARG4_FN_MOD_ISS_BM</name>
          <addressOffset>0x5008</addressOffset>
          <size>0x20</size>
        </register>
        <register>
          <name>AXI_TARG5_FN_MOD_ISS_BM</name>
          <addressOffset>0x6008</addressOffset>
          <size>0x20</size>
        </register>
        <register>
          <name>AXI_TARG6_FN_MOD_ISS_BM</name>
          <addressOffset>0x7008</addressOffset>
          <size>0x20</size>
        </register>
        <register>
          <name>AXI_TARG7_FN_MOD_ISS_BM</name>
          <addressOffset>0x8008</addressOffset>
          <size>0x20</size>
        </register>
        <register>
          <name>AXI_TARG7_FN_MOD2</name>
          <addressOffset>0x8024</addressOffset>
          <size>0x20</size>
        </register>
        <register>
          <name>AXI_TARG7_FN_MOD_LB</name>
          <addressOffset>0x802c</addressOffset>
          <size>0x20</size>
        </register>
        <register>
          <name>AXI_TARG7_FN_MOD</name>
          <addressOffset>0x8108</addressOffset>
          <size>0x20</size>
        </register>
        <register>
          <name>AXI_TARG8_FN_MOD_ISS_BM</name>
          <addressOffset>0x9008</addressOffset>
          <size>0x20</size>
        </register>
        <register>
          <name>AXI_TARG8_FN_MOD2</name>
          <addressOffset>0x9024</addressOffset>
          <size>0x20</size>
        </register>
        <register>
          <name>AXI_TARG8_FN_MOD</name>
          <addressOffset>0x9108</addressOffset>
          <size>0x20</size>
        </register>
        <register>
          <name>AXI_INI1_FN_MOD2</name>
          <addressOffset>0x42024</addressOffset>
          <size>0x20</size>
        </register>
        <register>
          <name>AXI_INI1_FN_MOD_AHB</name>
          <addressOffset>0x42028</addressOffset>
          <size>0x20</size>
        </register>
        <register>
          <name>AXI_INI1_READ_QOS</name>
          <addressOffset>0x42100</addressOffset>
          <size>0x20</size>
        </register>
        <register>
          <name>AXI_INI1_WRITE_QOS</name>
          <addressOffset>0x42104</addressOffset>
          <size>0x20</size>
        </register>
        <register>
          <name>AXI_INI1_FN_MOD</name>
          <addressOffset>0x42108</addressOffset>
          <size>0x20</size>
        </register>
        <register>
          <name>AXI_INI2_READ_QOS</name>
          <addressOffset>0x43100</addressOffset>
          <size>0x20</size>
        </register>
        <register>
          <name>AXI_INI2_WRITE_QOS</name>
          <addressOffset>0x43104</addressOffset>
          <size>0x20</size>
        </register>
        <register>
          <name>AXI_INI2_FN_MOD</name>
          <addressOffset>0x43108</addressOffset>
          <size>0x20</size>
        </register>
        <register>
          <name>AXI_INI3_FN_MOD2</name>
          <addressOffset>0x44024</addressOffset>
          <size>0x20</size>
        </register>
        <register>
          <name>AXI_INI3_FN_MOD_AHB</name>
          <addressOffset>0x44028</addressOffset>
          <size>0x20</size>
        </register>
        <register>
          <name>AXI_INI3_READ_QOS</name>
          <addressOffset>0x44100</addressOffset>
          <size>0x20</size>
        </register>
        <register>
          <name>AXI_INI3_WRITE_QOS</name>
          <addressOffset>0x44104</addressOffset>
          <size>0x20</size>
        </register>
        <register>
          <name>AXI_INI3_FN_MOD</name>
          <addressOffset>0x44108</addressOffset>
          <size>0x20</size>
        </register>
        <register>
          <name>AXI_INI4_READ_QOS</name>
          <addressOffset>0x45100</addressOffset>
          <size>0x20</size>
        </register>
        <register>
          <name>AXI_INI4_WRITE_QOS</name>
          <addressOffset>0x45104</addressOffset>
          <size>0x20</size>
        </register>
        <register>
          <name>AXI_INI4_FN_MOD</name>
          <addressOffset>0x45108</addressOffset>
          <size>0x20</size>
        </register>
        <register>
          <name>AXI_INI5_READ_QOS</name>
          <addressOffset>0x46100</addressOffset>
          <size>0x20</size>
        </register>
        <register>
          <name>AXI_INI5_WRITE_QOS</name>
          <addressOffset>0x46104</addressOffset>
          <size>0x20</size>
        </register>
        <register>
          <name>AXI_INI5_FN_MOD</name>
          <addressOffset>0x46108</addressOffset>
          <size>0x20</size>
        </register>
        <register>
          <name>AXI_INI6_READ_QOS</name>
          <addressOffset>0x47100</addressOffset>
          <size>0x20</size>
        </register>
        <register>
          <name>AXI_INI6_WRITE_QOS</name>
          <addressOffset>0x47104</addressOffset>
          <size>0x20</size>
        </register>
        <register>
          <name>AXI_INI6_FN_MOD</name>
          <addressOffset>0x47108</addressOffset>
          <size>0x20</size>
        </register>
      </registers>
    </peripheral>
    <peripheral>
      <name>MDMA</name>
      <baseAddress>0x52000000</baseAddress>
      <registers>
        <register>
          <name>GISR0</name>
          <addressOffset>0x0</addressOffset>
          <size>0x20</size>
          <fields>
            <field>
              <name>GIF0</name>
              <bitOffset>0</bitOffset>
              <bitWidth>1</bitWidth>
            </field>
            <field>
              <name>GIF1</name>
              <bitOffset>1</bitOffset>
              <bitWidth>1</bitWidth>
            </field>
            <field>
              <name>GIF2</name>
              <bitOffset>2</bitOffset>
              <bitWidth>1</bitWidth>
            </field>
            <field>
              <name>GIF3</name>
              <bitOffset>3</bitOffset>
              <bitWidth>1</bitWidth>
            </field>
            <field>
              <name>GIF4</name>
              <bitOffset>4</bitOffset>
              <bitWidth>1</bitWidth>
            </field>
            <field>
              <name>GIF5</name>
              <bitOffset>5</bitOffset>
              <bitWidth>1</bitWidth>
            </field>
            <field>
              <name>GIF6</name>
              <bitOffset>6</bitOffset>
              <bitWidth>1</bitWidth>
            </field>
            <field>
              <name>GIF7</name>
              <bitOffset>7</bitOffset>
              <bitWidth>1</bitWidth>
            </field>
            <field>
              <name>GIF8</name>
              <bitOffset>8</bitOffset>
              <bitWidth>1</bitWidth>
            </field>
            <field>
              <name>GIF9</name>
              <bitOffset>9</bitOffset>
              <bitWidth>1</bitWidth>
            </field>
            <field>
              <name>GIF10</name>
              <bitOffset>10</bitOffset>
              <bitWidth>1</bitWidth>
            </field>
            <field>
              <name>GIF11</name>
              <bitOffset>11</bitOffset>
              <bitWidth>1</bitWidth>
            </field>
            <field>
              <name>GIF12</name>
              <bitOffset>12</bitOffset>
              <bitWidth>1</bitWidth>
            </field>
            <field>
              <name>GIF13</name>
              <bitOffset>13</bitOffset>
              <bitWidth>1</bitWidth>
            </field>
            <field>
              <name>GIF14</name>
              <bitOffset>14</bitOffset>
              <bitWidth>1</bitWidth>
            </field>
            <field>
              <name>GIF15</name>
              <bitOffset>15</bitOffset>
              <bitWidth>1</bitWidth>
            </field>
          </fields>
        </register>
        <register>
          <name>CISR0</name>
          <addressOffset>0x40</addressOffset>
          <size>0x20</size>
          <fields>
            <field>
              <name>TEIF</name>
              <bitOffset>0</bitOffset>
              <bitWidth>1</bitWidth>
            </field>
            <field>
              <name>CTCIF</name>
              <bitOffset>1</bitOffset>
              <bitWidth>1</bitWidth>
            </field>
            <field>
              <name>BRTIF</name>
              <bitOffset>2</bitOffset>
              <bitWidth>1</bitWidth>
            </field>
            <field>
              <name>BTIF</name>
              <bitOffset>3</bitOffset>
              <bitWidth>1</bitWidth>
            </field>
            <field>
              <name>TCIF</name>
              <bitOffset>4</bitOffset>
              <bitWidth>1</bitWidth>
            </field>
            <field>
              <name>CRQA</name>
              <bitOffset>16</bitOffset>
              <bitWidth>1</bitWidth>
            </field>
          </fields>
        </register>
        <register>
          <name>CIFCR0</name>
          <addressOffset>0x44</addressOffset>
          <size>0x20</size>
          <fields>
            <field>
              <name>CTEIF</name>
              <bitOffset>0</bitOffset>
              <bitWidth>1</bitWidth>
            </field>
            <field>
              <name>CCTCIF</name>
              <bitOffset>1</bitOffset>
              <bitWidth>1</bitWidth>
            </field>
            <field>
              <name>CBRTIF</name>
              <bitOffset>2</bitOffset>
              <bitWidth>1</bitWidth>
            </field>
            <field>
              <name>CBTIF</name>
              <bitOffset>3</bitOffset>
              <bitWidth>1</bitWidth>
            </field>
            <field>
              <name>CLTCIF</name>
              <bitOffset>4</bitOffset>
              <bitWidth>1</bitWidth>
            </field>
          </fields>
        </register>
        <register>
          <name>CESR0</name>
          <addressOffset>0x48</addressOffset>
          <size>0x20</size>
          <fields>
            <field>
              <name>TEA</name>
              <bitOffset>0</bitOffset>
              <bitWidth>7</bitWidth>
            </field>
            <field>
              <name>TED</name>
              <bitOffset>7</bitOffset>
              <bitWidth>1</bitWidth>
            </field>
            <field>
              <name>TELD</name>
              <bitOffset>8</bitOffset>
              <bitWidth>1</bitWidth>
            </field>
            <field>
              <name>TEMD</name>
              <bitOffset>9</bitOffset>
              <bitWidth>1</bitWidth>
            </field>
            <field>
              <name>ASE</name>
              <bitOffset>10</bitOffset>
              <bitWidth>1</bitWidth>
            </field>
            <field>
              <name>BSE</name>
              <bitOffset>11</bitOffset>
              <bitWidth>1</bitWidth>
            </field>
          </fields>
        </register>
        <register>
          <name>CCR0</name>
          <addressOffset>0x4c</addressOffset>
          <size>0x20</size>
          <fields>
            <field>
              <name>EN</name>
              <bitOffset>0</bitOffset>
              <bitWidth>1</bitWidth>
            </field>
            <field>
              <name>TEIE</name>
              <bitOffset>1</bitOffset>
              <bitWidth>1</bitWidth>
            </field>
            <field>
              <name>CTCIE</name>
              <bitOffset>2</bitOffset>
              <bitWidth>1</bitWidth>
            </field>
            <field>
              <name>BRTIE</name>
              <bitOffset>3</bitOffset>
              <bitWidth>1</bitWidth>
            </field>
            <field>
              <name>BTIE</name>
              <bitOffset>4</bitOffset>
              <bitWidth>1</bitWidth>
            </field>
            <field>
              <name>TCIE</name>
              <bitOffset>5</bitOffset>
              <bitWidth>1</bitWidth>
            </field>
            <field>
              <name>PL</name>
              <bitOffset>6</bitOffset>
              <bitWidth>2</bitWidth>
            </field>
            <field>
              <name>BEX</name>
              <bitOffset>12</bitOffset>
              <bitWidth>1</bitWidth>
            </field>
            <field>
              <name>HEX</name>
              <bitOffset>13</bitOffset>
              <bitWidth>1</bitWidth>
            </field>
            <field>
              <name>WEX</name>
              <bitOffset>14</bitOffset>
              <bitWidth>1</bitWidth>
            </field>
            <field>
              <name>SWRQ</name>
              <bitOffset>16</bitOffset>
              <bitWidth>1</bitWidth>
            </field>
          </fields>
        </register>
        <register>
          <name>CTCR0</name>
          <addressOffset>0x50</addressOffset>
          <size>0x20</size>
          <fields>
            <field>
              <name>SINC</name>
              <bitOffset>0</bitOffset>
              <bitWidth>2</bitWidth>
            </field>
            <field>
              <name>DINC</name>
              <bitOffset>2</bitOffset>
              <bitWidth>2</bitWidth>
            </field>
            <field>
              <name>SSIZE</name>
              <bitOffset>4</bitOffset>
              <bitWidth>2</bitWidth>
            </field>
            <field>
              <name>DSIZE</name>
              <bitOffset>6</bitOffset>
              <bitWidth>2</bitWidth>
            </field>
            <field>
              <name>SINCOS</name>
              <bitOffset>8</bitOffset>
              <bitWidth>2</bitWidth>
            </field>
            <field>
              <name>DINCOS</name>
              <bitOffset>10</bitOffset>
              <bitWidth>2</bitWidth>
            </field>
            <field>
              <name>SBURST</name>
              <bitOffset>12</bitOffset>
              <bitWidth>3</bitWidth>
            </field>
            <field>
              <name>DBURST</name>
              <bitOffset>15</bitOffset>
              <bitWidth>3</bitWidth>
            </field>
            <field>
              <name>TLEN</name>
              <bitOffset>18</bitOffset>
              <bitWidth>7</bitWidth>
            </field>
            <field>
              <name>PKE</name>
              <bitOffset>25</bitOffset>
              <bitWidth>1</bitWidth>
            </field>
            <field>
              <name>PAM</name>
              <bitOffset>26</bitOffset>
              <bitWidth>2</bitWidth>
            </field>
            <field>
              <name>TRGM</name>
              <bitOffset>28</bitOffset>
              <bitWidth>2</bitWidth>
            </field>
            <field>
              <name>SWRM</name>
              <bitOffset>30</bitOffset>
              <bitWidth>1</bitWidth>
            </field>
            <field>
              <name>BWM</name>
              <bitOffset>31</bitOffset>
              <bitWidth>1</bitWidth>
            </field>
          </fields>
        </register>
        <register>
          <name>CBNDTR0</name>
          <addressOffset>0x54</addressOffset>
          <size>0x20</size>
          <fields>
            <field>
              <name>BNDT</name>
              <bitOffset>0</bitOffset>
              <bitWidth>17</bitWidth>
            </field>
            <field>
              <name>BRSUM</name>
              <bitOffset>18</bitOffset>
              <bitWidth>1</bitWidth>
            </field>
            <field>
              <name>BRDUM</name>
              <bitOffset>19</bitOffset>
              <bitWidth>1</bitWidth>
            </field>
            <field>
              <name>BRC</name>
              <bitOffset>20</bitOffset>
              <bitWidth>12</bitWidth>
            </field>
          </fields>
        </register>
        <register>
          <name>CSAR0</name>
          <addressOffset>0x58</addressOffset>
          <size>0x20</size>
          <fields>
            <field>
              <name>SAR</name>
              <bitOffset>0</bitOffset>
              <bitWidth>32</bitWidth>
            </field>
          </fields>
        </register>
        <register>
          <name>CDAR0</name>
          <addressOffset>0x5c</addressOffset>
          <size>0x20</size>
          <fields>
            <field>
              <name>DAR</name>
              <bitOffset>0</bitOffset>
              <bitWidth>32</bitWidth>
            </field>
          </fields>
        </register>
        <register>
          <name>CBRUR0</name>
          <addressOffset>0x60</addressOffset>
          <size>0x20</size>
          <fields>
            <field>
              <name>SUV</name>
              <bitOffset>0</bitOffset>
              <bitWidth>16</bitWidth>
            </field>
            <field>
              <name>DUV</name>
              <bitOffset>16</bitOffset>
              <bitWidth>16</bitWidth>
            </field>
          </fields>
        </register>
        <register>
          <name>CLAR0</name>
          <addressOffset>0x64</addressOffset>
          <size>0x20</size>
          <fields>
            <field>
              <name>LAR</name>
              <bitOffset>0</bitOffset>
              <bitWidth>32</bitWidth>
            </field>
          </fields>
        </register>
        <register>
          <name>CTBR0</name>
          <addressOffset>0x68</addressOffset>
          <size>0x20</size>
          <fields>
            <field>
              <name>TSEL</name>
              <bitOffset>0</bitOffset>
              <bitWidth>8</bitWidth>
            </field>
            <field>
              <name>SBUS</name>
              <bitOffset>16</bitOffset>
              <bitWidth>1</bitWidth>
            </field>
            <field>
              <name>DBUS</name>
              <bitOffset>17</bitOffset>
              <bitWidth>1</bitWidth>
            </field>
          </fields>
        </register>
        <register>
          <name>CMAR0</name>
          <addressOffset>0x70</addressOffset>
          <size>0x20</size>
          <fields>
            <field>
              <name>MAR</name>
              <bitOffset>0</bitOffset>
              <bitWidth>32</bitWidth>
            </field>
          </fields>
        </register>
        <register>
          <name>CMDR0</name>
          <addressOffset>0x74</addressOffset>
          <size>0x20</size>
          <fields>
            <field>
              <name>MDR</name>
              <bitOffset>0</bitOffset>
              <bitWidth>32</bitWidth>
            </field>
          </fields>
        </register>
        <register>
          <name>CISR1</name>
          <addressOffset>0x80</addressOffset>
          <size>0x20</size>
          <fields>
            <field>
              <name>TEIF</name>
              <bitOffset>0</bitOffset>
              <bitWidth>1</bitWidth>
            </field>
            <field>
              <name>CTCIF</name>
              <bitOffset>1</bitOffset>
              <bitWidth>1</bitWidth>
            </field>
            <field>
              <name>BRTIF</name>
              <bitOffset>2</bitOffset>
              <bitWidth>1</bitWidth>
            </field>
            <field>
              <name>BTIF</name>
              <bitOffset>3</bitOffset>
              <bitWidth>1</bitWidth>
            </field>
            <field>
              <name>TCIF</name>
              <bitOffset>4</bitOffset>
              <bitWidth>1</bitWidth>
            </field>
            <field>
              <name>CRQA</name>
              <bitOffset>16</bitOffset>
              <bitWidth>1</bitWidth>
            </field>
          </fields>
        </register>
        <register>
          <name>CIFCR1</name>
          <addressOffset>0x84</addressOffset>
          <size>0x20</size>
          <fields>
            <field>
              <name>CTEIF</name>
              <bitOffset>0</bitOffset>
              <bitWidth>1</bitWidth>
            </field>
            <field>
              <name>CCTCIF</name>
              <bitOffset>1</bitOffset>
              <bitWidth>1</bitWidth>
            </field>
            <field>
              <name>CBRTIF</name>
              <bitOffset>2</bitOffset>
              <bitWidth>1</bitWidth>
            </field>
            <field>
              <name>CBTIF</name>
              <bitOffset>3</bitOffset>
              <bitWidth>1</bitWidth>
            </field>
            <field>
              <name>CLTCIF</name>
              <bitOffset>4</bitOffset>
              <bitWidth>1</bitWidth>
            </field>
          </fields>
        </register>
        <register>
          <name>CESR1</name>
          <addressOffset>0x88</addressOffset>
          <size>0x20</size>
          <fields>
            <field>
              <name>TEA</name>
              <bitOffset>0</bitOffset>
              <bitWidth>7</bitWidth>
            </field>
            <field>
              <name>TED</name>
              <bitOffset>7</bitOffset>
              <bitWidth>1</bitWidth>
            </field>
            <field>
              <name>TELD</name>
              <bitOffset>8</bitOffset>
              <bitWidth>1</bitWidth>
            </field>
            <field>
              <name>TEMD</name>
              <bitOffset>9</bitOffset>
              <bitWidth>1</bitWidth>
            </field>
            <field>
              <name>ASE</name>
              <bitOffset>10</bitOffset>
              <bitWidth>1</bitWidth>
            </field>
            <field>
              <name>BSE</name>
              <bitOffset>11</bitOffset>
              <bitWidth>1</bitWidth>
            </field>
          </fields>
        </register>
        <register>
          <name>CCR1</name>
          <addressOffset>0x8c</addressOffset>
          <size>0x20</size>
          <fields>
            <field>
              <name>EN</name>
              <bitOffset>0</bitOffset>
              <bitWidth>1</bitWidth>
            </field>
            <field>
              <name>TEIE</name>
              <bitOffset>1</bitOffset>
              <bitWidth>1</bitWidth>
            </field>
            <field>
              <name>CTCIE</name>
              <bitOffset>2</bitOffset>
              <bitWidth>1</bitWidth>
            </field>
            <field>
              <name>BRTIE</name>
              <bitOffset>3</bitOffset>
              <bitWidth>1</bitWidth>
            </field>
            <field>
              <name>BTIE</name>
              <bitOffset>4</bitOffset>
              <bitWidth>1</bitWidth>
            </field>
            <field>
              <name>TCIE</name>
              <bitOffset>5</bitOffset>
              <bitWidth>1</bitWidth>
            </field>
            <field>
              <name>PL</name>
              <bitOffset>6</bitOffset>
              <bitWidth>2</bitWidth>
            </field>
            <field>
              <name>BEX</name>
              <bitOffset>12</bitOffset>
              <bitWidth>1</bitWidth>
            </field>
            <field>
              <name>HEX</name>
              <bitOffset>13</bitOffset>
              <bitWidth>1</bitWidth>
            </field>
            <field>
              <name>WEX</name>
              <bitOffset>14</bitOffset>
              <bitWidth>1</bitWidth>
            </field>
            <field>
              <name>SWRQ</name>
              <bitOffset>16</bitOffset>
              <bitWidth>1</bitWidth>
            </field>
          </fields>
        </register>
        <register>
          <name>CTCR1</name>
          <addressOffset>0x90</addressOffset>
          <size>0x20</size>
          <fields>
            <field>
              <name>SINC</name>
              <bitOffset>0</bitOffset>
              <bitWidth>2</bitWidth>
            </field>
            <field>
              <name>DINC</name>
              <bitOffset>2</bitOffset>
              <bitWidth>2</bitWidth>
            </field>
            <field>
              <name>SSIZE</name>
              <bitOffset>4</bitOffset>
              <bitWidth>2</bitWidth>
            </field>
            <field>
              <name>DSIZE</name>
              <bitOffset>6</bitOffset>
              <bitWidth>2</bitWidth>
            </field>
            <field>
              <name>SINCOS</name>
              <bitOffset>8</bitOffset>
              <bitWidth>2</bitWidth>
            </field>
            <field>
              <name>DINCOS</name>
              <bitOffset>10</bitOffset>
              <bitWidth>2</bitWidth>
            </field>
            <field>
              <name>SBURST</name>
              <bitOffset>12</bitOffset>
              <bitWidth>3</bitWidth>
            </field>
            <field>
              <name>DBURST</name>
              <bitOffset>15</bitOffset>
              <bitWidth>3</bitWidth>
            </field>
            <field>
              <name>TLEN</name>
              <bitOffset>18</bitOffset>
              <bitWidth>7</bitWidth>
            </field>
            <field>
              <name>PKE</name>
              <bitOffset>25</bitOffset>
              <bitWidth>1</bitWidth>
            </field>
            <field>
              <name>PAM</name>
              <bitOffset>26</bitOffset>
              <bitWidth>2</bitWidth>
            </field>
            <field>
              <name>TRGM</name>
              <bitOffset>28</bitOffset>
              <bitWidth>2</bitWidth>
            </field>
            <field>
              <name>SWRM</name>
              <bitOffset>30</bitOffset>
              <bitWidth>1</bitWidth>
            </field>
            <field>
              <name>BWM</name>
              <bitOffset>31</bitOffset>
              <bitWidth>1</bitWidth>
            </field>
          </fields>
        </register>
        <register>
          <name>CBNDTR1</name>
          <addressOffset>0x94</addressOffset>
          <size>0x20</size>
          <fields>
            <field>
              <name>BNDT</name>
              <bitOffset>0</bitOffset>
              <bitWidth>17</bitWidth>
            </field>
            <field>
              <name>BRSUM</name>
              <bitOffset>18</bitOffset>
              <bitWidth>1</bitWidth>
            </field>
            <field>
              <name>BRDUM</name>
              <bitOffset>19</bitOffset>
              <bitWidth>1</bitWidth>
            </field>
            <field>
              <name>BRC</name>
              <bitOffset>20</bitOffset>
              <bitWidth>12</bitWidth>
            </field>
          </fields>
        </register>
        <register>
          <name>CSAR1</name>
          <addressOffset>0x98</addressOffset>
          <size>0x20</size>
          <fields>
            <field>
              <name>SAR</name>
              <bitOffset>0</bitOffset>
              <bitWidth>32</bitWidth>
            </field>
          </fields>
        </register>
        <register>
          <name>CDAR1</name>
          <addressOffset>0x9c</addressOffset>
          <size>0x20</size>
          <fields>
            <field>
              <name>DAR</name>
              <bitOffset>0</bitOffset>
              <bitWidth>32</bitWidth>
            </field>
          </fields>
        </register>
        <register>
          <name>CBRUR1</name>
          <addressOffset>0xa0</addressOffset>
          <size>0x20</size>
          <fields>
            <field>
              <name>SUV</name>
              <bitOffset>0</bitOffset>
              <bitWidth>16</bitWidth>
            </field>
            <field>
              <name>DUV</name>
              <bitOffset>16</bitOffset>
              <bitWidth>16</bitWidth>
            </field>
          </fields>
        </register>
        <register>
          <name>CLAR1</name>
          <addressOffset>0xa4</addressOffset>
          <size>0x20</size>
          <fields>
            <field>
              <name>LAR</name>
              <bitOffset>0</bitOffset>
              <bitWidth>32</bitWidth>
            </field>
          </fields>
        </register>
        <register>
          <name>CTBR1</name>
          <addressOffset>0xa8</addressOffset>
          <size>0x20</size>
          <fields>
            <field>
              <name>TSEL</name>
              <bitOffset>0</bitOffset>
              <bitWidth>8</bitWidth>
            </field>
            <field>
              <name>SBUS</name>
              <bitOffset>16</bitOffset>
              <bitWidth>1</bitWidth>
            </field>
            <field>
              <name>DBUS</name>
              <bitOffset>17</bitOffset>
              <bitWidth>1</bitWidth>
            </field>
          </fields>
        </register>
        <register>
          <name>CMAR1</name>
          <addressOffset>0xb0</addressOffset>
          <size>0x20</size>
          <fields>
            <field>
              <name>MAR</name>
              <bitOffset>0</bitOffset>
              <bitWidth>32</bitWidth>
            </field>
          </fields>
        </register>
        <register>
          <name>CMDR1</name>
          <addressOffset>0xb4</addressOffset>
          <size>0x20</size>
          <fields>
            <field>
              <name>MDR</name>
              <bitOffset>0</bitOffset>
              <bitWidth>32</bitWidth>
            </field>
          </fields>
        </register>
        <register>
          <name>CISR2</name>
          <addressOffset>0xc0</addressOffset>
          <size>0x20</size>
          <fields>
            <field>
              <name>TEIF</name>
              <bitOffset>0</bitOffset>
              <bitWidth>1</bitWidth>
            </field>
            <field>
              <name>CTCIF</name>
              <bitOffset>1</bitOffset>
              <bitWidth>1</bitWidth>
            </field>
            <field>
              <name>BRTIF</name>
              <bitOffset>2</bitOffset>
              <bitWidth>1</bitWidth>
            </field>
            <field>
              <name>BTIF</name>
              <bitOffset>3</bitOffset>
              <bitWidth>1</bitWidth>
            </field>
            <field>
              <name>TCIF</name>
              <bitOffset>4</bitOffset>
              <bitWidth>1</bitWidth>
            </field>
            <field>
              <name>CRQA</name>
              <bitOffset>16</bitOffset>
              <bitWidth>1</bitWidth>
            </field>
          </fields>
        </register>
        <register>
          <name>CIFCR2</name>
          <addressOffset>0xc4</addressOffset>
          <size>0x20</size>
          <fields>
            <field>
              <name>CTEIF</name>
              <bitOffset>0</bitOffset>
              <bitWidth>1</bitWidth>
            </field>
            <field>
              <name>CCTCIF</name>
              <bitOffset>1</bitOffset>
              <bitWidth>1</bitWidth>
            </field>
            <field>
              <name>CBRTIF</name>
              <bitOffset>2</bitOffset>
              <bitWidth>1</bitWidth>
            </field>
            <field>
              <name>CBTIF</name>
              <bitOffset>3</bitOffset>
              <bitWidth>1</bitWidth>
            </field>
            <field>
              <name>CLTCIF</name>
              <bitOffset>4</bitOffset>
              <bitWidth>1</bitWidth>
            </field>
          </fields>
        </register>
        <register>
          <name>CESR2</name>
          <addressOffset>0xc8</addressOffset>
          <size>0x20</size>
          <fields>
            <field>
              <name>TEA</name>
              <bitOffset>0</bitOffset>
              <bitWidth>7</bitWidth>
            </field>
            <field>
              <name>TED</name>
              <bitOffset>7</bitOffset>
              <bitWidth>1</bitWidth>
            </field>
            <field>
              <name>TELD</name>
              <bitOffset>8</bitOffset>
              <bitWidth>1</bitWidth>
            </field>
            <field>
              <name>TEMD</name>
              <bitOffset>9</bitOffset>
              <bitWidth>1</bitWidth>
            </field>
            <field>
              <name>ASE</name>
              <bitOffset>10</bitOffset>
              <bitWidth>1</bitWidth>
            </field>
            <field>
              <name>BSE</name>
              <bitOffset>11</bitOffset>
              <bitWidth>1</bitWidth>
            </field>
          </fields>
        </register>
        <register>
          <name>CCR2</name>
          <addressOffset>0xcc</addressOffset>
          <size>0x20</size>
          <fields>
            <field>
              <name>EN</name>
              <bitOffset>0</bitOffset>
              <bitWidth>1</bitWidth>
            </field>
            <field>
              <name>TEIE</name>
              <bitOffset>1</bitOffset>
              <bitWidth>1</bitWidth>
            </field>
            <field>
              <name>CTCIE</name>
              <bitOffset>2</bitOffset>
              <bitWidth>1</bitWidth>
            </field>
            <field>
              <name>BRTIE</name>
              <bitOffset>3</bitOffset>
              <bitWidth>1</bitWidth>
            </field>
            <field>
              <name>BTIE</name>
              <bitOffset>4</bitOffset>
              <bitWidth>1</bitWidth>
            </field>
            <field>
              <name>TCIE</name>
              <bitOffset>5</bitOffset>
              <bitWidth>1</bitWidth>
            </field>
            <field>
              <name>PL</name>
              <bitOffset>6</bitOffset>
              <bitWidth>2</bitWidth>
            </field>
            <field>
              <name>BEX</name>
              <bitOffset>12</bitOffset>
              <bitWidth>1</bitWidth>
            </field>
            <field>
              <name>HEX</name>
              <bitOffset>13</bitOffset>
              <bitWidth>1</bitWidth>
            </field>
            <field>
              <name>WEX</name>
              <bitOffset>14</bitOffset>
              <bitWidth>1</bitWidth>
            </field>
            <field>
              <name>SWRQ</name>
              <bitOffset>16</bitOffset>
              <bitWidth>1</bitWidth>
            </field>
          </fields>
        </register>
        <register>
          <name>CTCR2</name>
          <addressOffset>0xd0</addressOffset>
          <size>0x20</size>
          <fields>
            <field>
              <name>SINC</name>
              <bitOffset>0</bitOffset>
              <bitWidth>2</bitWidth>
            </field>
            <field>
              <name>DINC</name>
              <bitOffset>2</bitOffset>
              <bitWidth>2</bitWidth>
            </field>
            <field>
              <name>SSIZE</name>
              <bitOffset>4</bitOffset>
              <bitWidth>2</bitWidth>
            </field>
            <field>
              <name>DSIZE</name>
              <bitOffset>6</bitOffset>
              <bitWidth>2</bitWidth>
            </field>
            <field>
              <name>SINCOS</name>
              <bitOffset>8</bitOffset>
              <bitWidth>2</bitWidth>
            </field>
            <field>
              <name>DINCOS</name>
              <bitOffset>10</bitOffset>
              <bitWidth>2</bitWidth>
            </field>
            <field>
              <name>SBURST</name>
              <bitOffset>12</bitOffset>
              <bitWidth>3</bitWidth>
            </field>
            <field>
              <name>DBURST</name>
              <bitOffset>15</bitOffset>
              <bitWidth>3</bitWidth>
            </field>
            <field>
              <name>TLEN</name>
              <bitOffset>18</bitOffset>
              <bitWidth>7</bitWidth>
            </field>
            <field>
              <name>PKE</name>
              <bitOffset>25</bitOffset>
              <bitWidth>1</bitWidth>
            </field>
            <field>
              <name>PAM</name>
              <bitOffset>26</bitOffset>
              <bitWidth>2</bitWidth>
            </field>
            <field>
              <name>TRGM</name>
              <bitOffset>28</bitOffset>
              <bitWidth>2</bitWidth>
            </field>
            <field>
              <name>SWRM</name>
              <bitOffset>30</bitOffset>
              <bitWidth>1</bitWidth>
            </field>
            <field>
              <name>BWM</name>
              <bitOffset>31</bitOffset>
              <bitWidth>1</bitWidth>
            </field>
          </fields>
        </register>
        <register>
          <name>CBNDTR2</name>
          <addressOffset>0xd4</addressOffset>
          <size>0x20</size>
          <fields>
            <field>
              <name>BNDT</name>
              <bitOffset>0</bitOffset>
              <bitWidth>17</bitWidth>
            </field>
            <field>
              <name>BRSUM</name>
              <bitOffset>18</bitOffset>
              <bitWidth>1</bitWidth>
            </field>
            <field>
              <name>BRDUM</name>
              <bitOffset>19</bitOffset>
              <bitWidth>1</bitWidth>
            </field>
            <field>
              <name>BRC</name>
              <bitOffset>20</bitOffset>
              <bitWidth>12</bitWidth>
            </field>
          </fields>
        </register>
        <register>
          <name>CSAR2</name>
          <addressOffset>0xd8</addressOffset>
          <size>0x20</size>
          <fields>
            <field>
              <name>SAR</name>
              <bitOffset>0</bitOffset>
              <bitWidth>32</bitWidth>
            </field>
          </fields>
        </register>
        <register>
          <name>CDAR2</name>
          <addressOffset>0xdc</addressOffset>
          <size>0x20</size>
          <fields>
            <field>
              <name>DAR</name>
              <bitOffset>0</bitOffset>
              <bitWidth>32</bitWidth>
            </field>
          </fields>
        </register>
        <register>
          <name>CBRUR2</name>
          <addressOffset>0xe0</addressOffset>
          <size>0x20</size>
          <fields>
            <field>
              <name>SUV</name>
              <bitOffset>0</bitOffset>
              <bitWidth>16</bitWidth>
            </field>
            <field>
              <name>DUV</name>
              <bitOffset>16</bitOffset>
              <bitWidth>16</bitWidth>
            </field>
          </fields>
        </register>
        <register>
          <name>CLAR2</name>
          <addressOffset>0xe4</addressOffset>
          <size>0x20</size>
          <fields>
            <field>
              <name>LAR</name>
              <bitOffset>0</bitOffset>
              <bitWidth>32</bitWidth>
            </field>
          </fields>
        </register>
        <register>
          <name>CTBR2</name>
          <addressOffset>0xe8</addressOffset>
          <size>0x20</size>
          <fields>
            <field>
              <name>TSEL</name>
              <bitOffset>0</bitOffset>
              <bitWidth>8</bitWidth>
            </field>
            <field>
              <name>SBUS</name>
              <bitOffset>16</bitOffset>
              <bitWidth>1</bitWidth>
            </field>
            <field>
              <name>DBUS</name>
              <bitOffset>17</bitOffset>
              <bitWidth>1</bitWidth>
            </field>
          </fields>
        </register>
        <register>
          <name>CMAR2</name>
          <addressOffset>0xf0</addressOffset>
          <size>0x20</size>
          <fields>
            <field>
              <name>MAR</name>
              <bitOffset>0</bitOffset>
              <bitWidth>32</bitWidth>
            </field>
          </fields>
        </register>
        <register>
          <name>CMDR2</name>
          <addressOffset>0xf4</addressOffset>
          <size>0x20</size>
          <fields>
            <field>
              <name>MDR</name>
              <bitOffset>0</bitOffset>
              <bitWidth>32</bitWidth>
            </field>
          </fields>
        </register>
        <register>
          <name>CISR3</name>
          <addressOffset>0x100</addressOffset>
          <size>0x20</size>
          <fields>
            <field>
              <name>TEIF</name>
              <bitOffset>0</bitOffset>
              <bitWidth>1</bitWidth>
            </field>
            <field>
              <name>CTCIF</name>
              <bitOffset>1</bitOffset>
              <bitWidth>1</bitWidth>
            </field>
            <field>
              <name>BRTIF</name>
              <bitOffset>2</bitOffset>
              <bitWidth>1</bitWidth>
            </field>
            <field>
              <name>BTIF</name>
              <bitOffset>3</bitOffset>
              <bitWidth>1</bitWidth>
            </field>
            <field>
              <name>TCIF</name>
              <bitOffset>4</bitOffset>
              <bitWidth>1</bitWidth>
            </field>
            <field>
              <name>CRQA</name>
              <bitOffset>16</bitOffset>
              <bitWidth>1</bitWidth>
            </field>
          </fields>
        </register>
        <register>
          <name>CIFCR3</name>
          <addressOffset>0x104</addressOffset>
          <size>0x20</size>
          <fields>
            <field>
              <name>CTEIF</name>
              <bitOffset>0</bitOffset>
              <bitWidth>1</bitWidth>
            </field>
            <field>
              <name>CCTCIF</name>
              <bitOffset>1</bitOffset>
              <bitWidth>1</bitWidth>
            </field>
            <field>
              <name>CBRTIF</name>
              <bitOffset>2</bitOffset>
              <bitWidth>1</bitWidth>
            </field>
            <field>
              <name>CBTIF</name>
              <bitOffset>3</bitOffset>
              <bitWidth>1</bitWidth>
            </field>
            <field>
              <name>CLTCIF</name>
              <bitOffset>4</bitOffset>
              <bitWidth>1</bitWidth>
            </field>
          </fields>
        </register>
        <register>
          <name>CESR3</name>
          <addressOffset>0x108</addressOffset>
          <size>0x20</size>
          <fields>
            <field>
              <name>TEA</name>
              <bitOffset>0</bitOffset>
              <bitWidth>7</bitWidth>
            </field>
            <field>
              <name>TED</name>
              <bitOffset>7</bitOffset>
              <bitWidth>1</bitWidth>
            </field>
            <field>
              <name>TELD</name>
              <bitOffset>8</bitOffset>
              <bitWidth>1</bitWidth>
            </field>
            <field>
              <name>TEMD</name>
              <bitOffset>9</bitOffset>
              <bitWidth>1</bitWidth>
            </field>
            <field>
              <name>ASE</name>
              <bitOffset>10</bitOffset>
              <bitWidth>1</bitWidth>
            </field>
            <field>
              <name>BSE</name>
              <bitOffset>11</bitOffset>
              <bitWidth>1</bitWidth>
            </field>
          </fields>
        </register>
        <register>
          <name>CCR3</name>
          <addressOffset>0x10c</addressOffset>
          <size>0x20</size>
          <fields>
            <field>
              <name>EN</name>
              <bitOffset>0</bitOffset>
              <bitWidth>1</bitWidth>
            </field>
            <field>
              <name>TEIE</name>
              <bitOffset>1</bitOffset>
              <bitWidth>1</bitWidth>
            </field>
            <field>
              <name>CTCIE</name>
              <bitOffset>2</bitOffset>
              <bitWidth>1</bitWidth>
            </field>
            <field>
              <name>BRTIE</name>
              <bitOffset>3</bitOffset>
              <bitWidth>1</bitWidth>
            </field>
            <field>
              <name>BTIE</name>
              <bitOffset>4</bitOffset>
              <bitWidth>1</bitWidth>
            </field>
            <field>
              <name>TCIE</name>
              <bitOffset>5</bitOffset>
              <bitWidth>1</bitWidth>
            </field>
            <field>
              <name>PL</name>
              <bitOffset>6</bitOffset>
              <bitWidth>2</bitWidth>
            </field>
            <field>
              <name>BEX</name>
              <bitOffset>12</bitOffset>
              <bitWidth>1</bitWidth>
            </field>
            <field>
              <name>HEX</name>
              <bitOffset>13</bitOffset>
              <bitWidth>1</bitWidth>
            </field>
            <field>
              <name>WEX</name>
              <bitOffset>14</bitOffset>
              <bitWidth>1</bitWidth>
            </field>
            <field>
              <name>SWRQ</name>
              <bitOffset>16</bitOffset>
              <bitWidth>1</bitWidth>
            </field>
          </fields>
        </register>
        <register>
          <name>CTCR3</name>
          <addressOffset>0x110</addressOffset>
          <size>0x20</size>
          <fields>
            <field>
              <name>SINC</name>
              <bitOffset>0</bitOffset>
              <bitWidth>2</bitWidth>
            </field>
            <field>
              <name>DINC</name>
              <bitOffset>2</bitOffset>
              <bitWidth>2</bitWidth>
            </field>
            <field>
              <name>SSIZE</name>
              <bitOffset>4</bitOffset>
              <bitWidth>2</bitWidth>
            </field>
            <field>
              <name>DSIZE</name>
              <bitOffset>6</bitOffset>
              <bitWidth>2</bitWidth>
            </field>
            <field>
              <name>SINCOS</name>
              <bitOffset>8</bitOffset>
              <bitWidth>2</bitWidth>
            </field>
            <field>
              <name>DINCOS</name>
              <bitOffset>10</bitOffset>
              <bitWidth>2</bitWidth>
            </field>
            <field>
              <name>SBURST</name>
              <bitOffset>12</bitOffset>
              <bitWidth>3</bitWidth>
            </field>
            <field>
              <name>DBURST</name>
              <bitOffset>15</bitOffset>
              <bitWidth>3</bitWidth>
            </field>
            <field>
              <name>TLEN</name>
              <bitOffset>18</bitOffset>
              <bitWidth>7</bitWidth>
            </field>
            <field>
              <name>PKE</name>
              <bitOffset>25</bitOffset>
              <bitWidth>1</bitWidth>
            </field>
            <field>
              <name>PAM</name>
              <bitOffset>26</bitOffset>
              <bitWidth>2</bitWidth>
            </field>
            <field>
              <name>TRGM</name>
              <bitOffset>28</bitOffset>
              <bitWidth>2</bitWidth>
            </field>
            <field>
              <name>SWRM</name>
              <bitOffset>30</bitOffset>
              <bitWidth>1</bitWidth>
            </field>
            <field>
              <name>BWM</name>
              <bitOffset>31</bitOffset>
              <bitWidth>1</bitWidth>
            </field>
          </fields>
        </register>
        <register>
          <name>CBNDTR3</name>
          <addressOffset>0x114</addressOffset>
          <size>0x20</size>
          <fields>
            <field>
              <name>BNDT</name>
              <bitOffset>0</bitOffset>
              <bitWidth>17</bitWidth>
            </field>
            <field>
              <name>BRSUM</name>
              <bitOffset>18</bitOffset>
              <bitWidth>1</bitWidth>
            </field>
            <field>
              <name>BRDUM</name>
              <bitOffset>19</bitOffset>
              <bitWidth>1</bitWidth>
            </field>
            <field>
              <name>BRC</name>
              <bitOffset>20</bitOffset>
              <bitWidth>12</bitWidth>
            </field>
          </fields>
        </register>
        <register>
          <name>CSAR3</name>
          <addressOffset>0x118</addressOffset>
          <size>0x20</size>
          <fields>
            <field>
              <name>SAR</name>
              <bitOffset>0</bitOffset>
              <bitWidth>32</bitWidth>
            </field>
          </fields>
        </register>
        <register>
          <name>CDAR3</name>
          <addressOffset>0x11c</addressOffset>
          <size>0x20</size>
          <fields>
            <field>
              <name>DAR</name>
              <bitOffset>0</bitOffset>
              <bitWidth>32</bitWidth>
            </field>
          </fields>
        </register>
        <register>
          <name>CBRUR3</name>
          <addressOffset>0x120</addressOffset>
          <size>0x20</size>
          <fields>
            <field>
              <name>SUV</name>
              <bitOffset>0</bitOffset>
              <bitWidth>16</bitWidth>
            </field>
            <field>
              <name>DUV</name>
              <bitOffset>16</bitOffset>
              <bitWidth>16</bitWidth>
            </field>
          </fields>
        </register>
        <register>
          <name>CLAR3</name>
          <addressOffset>0x124</addressOffset>
          <size>0x20</size>
          <fields>
            <field>
              <name>LAR</name>
              <bitOffset>0</bitOffset>
              <bitWidth>32</bitWidth>
            </field>
          </fields>
        </register>
        <register>
          <name>CTBR3</name>
          <addressOffset>0x128</addressOffset>
          <size>0x20</size>
          <fields>
            <field>
              <name>TSEL</name>
              <bitOffset>0</bitOffset>
              <bitWidth>8</bitWidth>
            </field>
            <field>
              <name>SBUS</name>
              <bitOffset>16</bitOffset>
              <bitWidth>1</bitWidth>
            </field>
            <field>
              <name>DBUS</name>
              <bitOffset>17</bitOffset>
              <bitWidth>1</bitWidth>
            </field>
          </fields>
        </register>
        <register>
          <name>CMAR3</name>
          <addressOffset>0x130</addressOffset>
          <size>0x20</size>
          <fields>
            <field>
              <name>MAR</name>
              <bitOffset>0</bitOffset>
              <bitWidth>32</bitWidth>
            </field>
          </fields>
        </register>
        <register>
          <name>CMDR3</name>
          <addressOffset>0x134</addressOffset>
          <size>0x20</size>
          <fields>
            <field>
              <name>MDR</name>
              <bitOffset>0</bitOffset>
              <bitWidth>32</bitWidth>
            </field>
          </fields>
        </register>
        <register>
          <name>CISR4</name>
          <addressOffset>0x140</addressOffset>
          <size>0x20</size>
          <fields>
            <field>
              <name>TEIF</name>
              <bitOffset>0</bitOffset>
              <bitWidth>1</bitWidth>
            </field>
            <field>
              <name>CTCIF</name>
              <bitOffset>1</bitOffset>
              <bitWidth>1</bitWidth>
            </field>
            <field>
              <name>BRTIF</name>
              <bitOffset>2</bitOffset>
              <bitWidth>1</bitWidth>
            </field>
            <field>
              <name>BTIF</name>
              <bitOffset>3</bitOffset>
              <bitWidth>1</bitWidth>
            </field>
            <field>
              <name>TCIF</name>
              <bitOffset>4</bitOffset>
              <bitWidth>1</bitWidth>
            </field>
            <field>
              <name>CRQA</name>
              <bitOffset>16</bitOffset>
              <bitWidth>1</bitWidth>
            </field>
          </fields>
        </register>
        <register>
          <name>CIFCR4</name>
          <addressOffset>0x144</addressOffset>
          <size>0x20</size>
          <fields>
            <field>
              <name>CTEIF</name>
              <bitOffset>0</bitOffset>
              <bitWidth>1</bitWidth>
            </field>
            <field>
              <name>CCTCIF</name>
              <bitOffset>1</bitOffset>
              <bitWidth>1</bitWidth>
            </field>
            <field>
              <name>CBRTIF</name>
              <bitOffset>2</bitOffset>
              <bitWidth>1</bitWidth>
            </field>
            <field>
              <name>CBTIF</name>
              <bitOffset>3</bitOffset>
              <bitWidth>1</bitWidth>
            </field>
            <field>
              <name>CLTCIF</name>
              <bitOffset>4</bitOffset>
              <bitWidth>1</bitWidth>
            </field>
          </fields>
        </register>
        <register>
          <name>CESR4</name>
          <addressOffset>0x148</addressOffset>
          <size>0x20</size>
          <fields>
            <field>
              <name>TEA</name>
              <bitOffset>0</bitOffset>
              <bitWidth>7</bitWidth>
            </field>
            <field>
              <name>TED</name>
              <bitOffset>7</bitOffset>
              <bitWidth>1</bitWidth>
            </field>
            <field>
              <name>TELD</name>
              <bitOffset>8</bitOffset>
              <bitWidth>1</bitWidth>
            </field>
            <field>
              <name>TEMD</name>
              <bitOffset>9</bitOffset>
              <bitWidth>1</bitWidth>
            </field>
            <field>
              <name>ASE</name>
              <bitOffset>10</bitOffset>
              <bitWidth>1</bitWidth>
            </field>
            <field>
              <name>BSE</name>
              <bitOffset>11</bitOffset>
              <bitWidth>1</bitWidth>
            </field>
          </fields>
        </register>
        <register>
          <name>CCR4</name>
          <addressOffset>0x14c</addressOffset>
          <size>0x20</size>
          <fields>
            <field>
              <name>EN</name>
              <bitOffset>0</bitOffset>
              <bitWidth>1</bitWidth>
            </field>
            <field>
              <name>TEIE</name>
              <bitOffset>1</bitOffset>
              <bitWidth>1</bitWidth>
            </field>
            <field>
              <name>CTCIE</name>
              <bitOffset>2</bitOffset>
              <bitWidth>1</bitWidth>
            </field>
            <field>
              <name>BRTIE</name>
              <bitOffset>3</bitOffset>
              <bitWidth>1</bitWidth>
            </field>
            <field>
              <name>BTIE</name>
              <bitOffset>4</bitOffset>
              <bitWidth>1</bitWidth>
            </field>
            <field>
              <name>TCIE</name>
              <bitOffset>5</bitOffset>
              <bitWidth>1</bitWidth>
            </field>
            <field>
              <name>PL</name>
              <bitOffset>6</bitOffset>
              <bitWidth>2</bitWidth>
            </field>
            <field>
              <name>BEX</name>
              <bitOffset>12</bitOffset>
              <bitWidth>1</bitWidth>
            </field>
            <field>
              <name>HEX</name>
              <bitOffset>13</bitOffset>
              <bitWidth>1</bitWidth>
            </field>
            <field>
              <name>WEX</name>
              <bitOffset>14</bitOffset>
              <bitWidth>1</bitWidth>
            </field>
            <field>
              <name>SWRQ</name>
              <bitOffset>16</bitOffset>
              <bitWidth>1</bitWidth>
            </field>
          </fields>
        </register>
        <register>
          <name>CTCR4</name>
          <addressOffset>0x150</addressOffset>
          <size>0x20</size>
          <fields>
            <field>
              <name>SINC</name>
              <bitOffset>0</bitOffset>
              <bitWidth>2</bitWidth>
            </field>
            <field>
              <name>DINC</name>
              <bitOffset>2</bitOffset>
              <bitWidth>2</bitWidth>
            </field>
            <field>
              <name>SSIZE</name>
              <bitOffset>4</bitOffset>
              <bitWidth>2</bitWidth>
            </field>
            <field>
              <name>DSIZE</name>
              <bitOffset>6</bitOffset>
              <bitWidth>2</bitWidth>
            </field>
            <field>
              <name>SINCOS</name>
              <bitOffset>8</bitOffset>
              <bitWidth>2</bitWidth>
            </field>
            <field>
              <name>DINCOS</name>
              <bitOffset>10</bitOffset>
              <bitWidth>2</bitWidth>
            </field>
            <field>
              <name>SBURST</name>
              <bitOffset>12</bitOffset>
              <bitWidth>3</bitWidth>
            </field>
            <field>
              <name>DBURST</name>
              <bitOffset>15</bitOffset>
              <bitWidth>3</bitWidth>
            </field>
            <field>
              <name>TLEN</name>
              <bitOffset>18</bitOffset>
              <bitWidth>7</bitWidth>
            </field>
            <field>
              <name>PKE</name>
              <bitOffset>25</bitOffset>
              <bitWidth>1</bitWidth>
            </field>
            <field>
              <name>PAM</name>
              <bitOffset>26</bitOffset>
              <bitWidth>2</bitWidth>
            </field>
            <field>
              <name>TRGM</name>
              <bitOffset>28</bitOffset>
              <bitWidth>2</bitWidth>
            </field>
            <field>
              <name>SWRM</name>
              <bitOffset>30</bitOffset>
              <bitWidth>1</bitWidth>
            </field>
            <field>
              <name>BWM</name>
              <bitOffset>31</bitOffset>
              <bitWidth>1</bitWidth>
            </field>
          </fields>
        </register>
        <register>
          <name>CBNDTR4</name>
          <addressOffset>0x154</addressOffset>
          <size>0x20</size>
          <fields>
            <field>
              <name>BNDT</name>
              <bitOffset>0</bitOffset>
              <bitWidth>17</bitWidth>
            </field>
            <field>
              <name>BRSUM</name>
              <bitOffset>18</bitOffset>
              <bitWidth>1</bitWidth>
            </field>
            <field>
              <name>BRDUM</name>
              <bitOffset>19</bitOffset>
              <bitWidth>1</bitWidth>
            </field>
            <field>
              <name>BRC</name>
              <bitOffset>20</bitOffset>
              <bitWidth>12</bitWidth>
            </field>
          </fields>
        </register>
        <register>
          <name>CSAR4</name>
          <addressOffset>0x158</addressOffset>
          <size>0x20</size>
          <fields>
            <field>
              <name>SAR</name>
              <bitOffset>0</bitOffset>
              <bitWidth>32</bitWidth>
            </field>
          </fields>
        </register>
        <register>
          <name>CDAR4</name>
          <addressOffset>0x15c</addressOffset>
          <size>0x20</size>
          <fields>
            <field>
              <name>DAR</name>
              <bitOffset>0</bitOffset>
              <bitWidth>32</bitWidth>
            </field>
          </fields>
        </register>
        <register>
          <name>CBRUR4</name>
          <addressOffset>0x160</addressOffset>
          <size>0x20</size>
          <fields>
            <field>
              <name>SUV</name>
              <bitOffset>0</bitOffset>
              <bitWidth>16</bitWidth>
            </field>
            <field>
              <name>DUV</name>
              <bitOffset>16</bitOffset>
              <bitWidth>16</bitWidth>
            </field>
          </fields>
        </register>
        <register>
          <name>CLAR4</name>
          <addressOffset>0x164</addressOffset>
          <size>0x20</size>
          <fields>
            <field>
              <name>LAR</name>
              <bitOffset>0</bitOffset>
              <bitWidth>32</bitWidth>
            </field>
          </fields>
        </register>
        <register>
          <name>CTBR4</name>
          <addressOffset>0x168</addressOffset>
          <size>0x20</size>
          <fields>
            <field>
              <name>TSEL</name>
              <bitOffset>0</bitOffset>
              <bitWidth>8</bitWidth>
            </field>
            <field>
              <name>SBUS</name>
              <bitOffset>16</bitOffset>
              <bitWidth>1</bitWidth>
            </field>
            <field>
              <name>DBUS</name>
              <bitOffset>17</bitOffset>
              <bitWidth>1</bitWidth>
            </field>
          </fields>
        </register>
        <register>
          <name>CMAR4</name>
          <addressOffset>0x170</addressOffset>
          <size>0x20</size>
          <fields>
            <field>
              <name>MAR</name>
              <bitOffset>0</bitOffset>
              <bitWidth>32</bitWidth>
            </field>
          </fields>
        </register>
        <register>
          <name>CMDR4</name>
          <addressOffset>0x174</addressOffset>
          <size>0x20</size>
          <fields>
            <field>
              <name>MDR</name>
              <bitOffset>0</bitOffset>
              <bitWidth>32</bitWidth>
            </field>
          </fields>
        </register>
        <register>
          <name>CISR5</name>
          <addressOffset>0x180</addressOffset>
          <size>0x20</size>
          <fields>
            <field>
              <name>TEIF</name>
              <bitOffset>0</bitOffset>
              <bitWidth>1</bitWidth>
            </field>
            <field>
              <name>CTCIF</name>
              <bitOffset>1</bitOffset>
              <bitWidth>1</bitWidth>
            </field>
            <field>
              <name>BRTIF</name>
              <bitOffset>2</bitOffset>
              <bitWidth>1</bitWidth>
            </field>
            <field>
              <name>BTIF</name>
              <bitOffset>3</bitOffset>
              <bitWidth>1</bitWidth>
            </field>
            <field>
              <name>TCIF</name>
              <bitOffset>4</bitOffset>
              <bitWidth>1</bitWidth>
            </field>
            <field>
              <name>CRQA</name>
              <bitOffset>16</bitOffset>
              <bitWidth>1</bitWidth>
            </field>
          </fields>
        </register>
        <register>
          <name>CIFCR5</name>
          <addressOffset>0x184</addressOffset>
          <size>0x20</size>
          <fields>
            <field>
              <name>CTEIF</name>
              <bitOffset>0</bitOffset>
              <bitWidth>1</bitWidth>
            </field>
            <field>
              <name>CCTCIF</name>
              <bitOffset>1</bitOffset>
              <bitWidth>1</bitWidth>
            </field>
            <field>
              <name>CBRTIF</name>
              <bitOffset>2</bitOffset>
              <bitWidth>1</bitWidth>
            </field>
            <field>
              <name>CBTIF</name>
              <bitOffset>3</bitOffset>
              <bitWidth>1</bitWidth>
            </field>
            <field>
              <name>CLTCIF</name>
              <bitOffset>4</bitOffset>
              <bitWidth>1</bitWidth>
            </field>
          </fields>
        </register>
        <register>
          <name>CESR5</name>
          <addressOffset>0x188</addressOffset>
          <size>0x20</size>
          <fields>
            <field>
              <name>TEA</name>
              <bitOffset>0</bitOffset>
              <bitWidth>7</bitWidth>
            </field>
            <field>
              <name>TED</name>
              <bitOffset>7</bitOffset>
              <bitWidth>1</bitWidth>
            </field>
            <field>
              <name>TELD</name>
              <bitOffset>8</bitOffset>
              <bitWidth>1</bitWidth>
            </field>
            <field>
              <name>TEMD</name>
              <bitOffset>9</bitOffset>
              <bitWidth>1</bitWidth>
            </field>
            <field>
              <name>ASE</name>
              <bitOffset>10</bitOffset>
              <bitWidth>1</bitWidth>
            </field>
            <field>
              <name>BSE</name>
              <bitOffset>11</bitOffset>
              <bitWidth>1</bitWidth>
            </field>
          </fields>
        </register>
        <register>
          <name>CCR5</name>
          <addressOffset>0x18c</addressOffset>
          <size>0x20</size>
          <fields>
            <field>
              <name>EN</name>
              <bitOffset>0</bitOffset>
              <bitWidth>1</bitWidth>
            </field>
            <field>
              <name>TEIE</name>
              <bitOffset>1</bitOffset>
              <bitWidth>1</bitWidth>
            </field>
            <field>
              <name>CTCIE</name>
              <bitOffset>2</bitOffset>
              <bitWidth>1</bitWidth>
            </field>
            <field>
              <name>BRTIE</name>
              <bitOffset>3</bitOffset>
              <bitWidth>1</bitWidth>
            </field>
            <field>
              <name>BTIE</name>
              <bitOffset>4</bitOffset>
              <bitWidth>1</bitWidth>
            </field>
            <field>
              <name>TCIE</name>
              <bitOffset>5</bitOffset>
              <bitWidth>1</bitWidth>
            </field>
            <field>
              <name>PL</name>
              <bitOffset>6</bitOffset>
              <bitWidth>2</bitWidth>
            </field>
            <field>
              <name>BEX</name>
              <bitOffset>12</bitOffset>
              <bitWidth>1</bitWidth>
            </field>
            <field>
              <name>HEX</name>
              <bitOffset>13</bitOffset>
              <bitWidth>1</bitWidth>
            </field>
            <field>
              <name>WEX</name>
              <bitOffset>14</bitOffset>
              <bitWidth>1</bitWidth>
            </field>
            <field>
              <name>SWRQ</name>
              <bitOffset>16</bitOffset>
              <bitWidth>1</bitWidth>
            </field>
          </fields>
        </register>
        <register>
          <name>CTCR5</name>
          <addressOffset>0x190</addressOffset>
          <size>0x20</size>
          <fields>
            <field>
              <name>SINC</name>
              <bitOffset>0</bitOffset>
              <bitWidth>2</bitWidth>
            </field>
            <field>
              <name>DINC</name>
              <bitOffset>2</bitOffset>
              <bitWidth>2</bitWidth>
            </field>
            <field>
              <name>SSIZE</name>
              <bitOffset>4</bitOffset>
              <bitWidth>2</bitWidth>
            </field>
            <field>
              <name>DSIZE</name>
              <bitOffset>6</bitOffset>
              <bitWidth>2</bitWidth>
            </field>
            <field>
              <name>SINCOS</name>
              <bitOffset>8</bitOffset>
              <bitWidth>2</bitWidth>
            </field>
            <field>
              <name>DINCOS</name>
              <bitOffset>10</bitOffset>
              <bitWidth>2</bitWidth>
            </field>
            <field>
              <name>SBURST</name>
              <bitOffset>12</bitOffset>
              <bitWidth>3</bitWidth>
            </field>
            <field>
              <name>DBURST</name>
              <bitOffset>15</bitOffset>
              <bitWidth>3</bitWidth>
            </field>
            <field>
              <name>TLEN</name>
              <bitOffset>18</bitOffset>
              <bitWidth>7</bitWidth>
            </field>
            <field>
              <name>PKE</name>
              <bitOffset>25</bitOffset>
              <bitWidth>1</bitWidth>
            </field>
            <field>
              <name>PAM</name>
              <bitOffset>26</bitOffset>
              <bitWidth>2</bitWidth>
            </field>
            <field>
              <name>TRGM</name>
              <bitOffset>28</bitOffset>
              <bitWidth>2</bitWidth>
            </field>
            <field>
              <name>SWRM</name>
              <bitOffset>30</bitOffset>
              <bitWidth>1</bitWidth>
            </field>
            <field>
              <name>BWM</name>
              <bitOffset>31</bitOffset>
              <bitWidth>1</bitWidth>
            </field>
          </fields>
        </register>
        <register>
          <name>CBNDTR5</name>
          <addressOffset>0x194</addressOffset>
          <size>0x20</size>
          <fields>
            <field>
              <name>BNDT</name>
              <bitOffset>0</bitOffset>
              <bitWidth>17</bitWidth>
            </field>
            <field>
              <name>BRSUM</name>
              <bitOffset>18</bitOffset>
              <bitWidth>1</bitWidth>
            </field>
            <field>
              <name>BRDUM</name>
              <bitOffset>19</bitOffset>
              <bitWidth>1</bitWidth>
            </field>
            <field>
              <name>BRC</name>
              <bitOffset>20</bitOffset>
              <bitWidth>12</bitWidth>
            </field>
          </fields>
        </register>
        <register>
          <name>CSAR5</name>
          <addressOffset>0x198</addressOffset>
          <size>0x20</size>
          <fields>
            <field>
              <name>SAR</name>
              <bitOffset>0</bitOffset>
              <bitWidth>32</bitWidth>
            </field>
          </fields>
        </register>
        <register>
          <name>CDAR5</name>
          <addressOffset>0x19c</addressOffset>
          <size>0x20</size>
          <fields>
            <field>
              <name>DAR</name>
              <bitOffset>0</bitOffset>
              <bitWidth>32</bitWidth>
            </field>
          </fields>
        </register>
        <register>
          <name>CBRUR5</name>
          <addressOffset>0x1a0</addressOffset>
          <size>0x20</size>
          <fields>
            <field>
              <name>SUV</name>
              <bitOffset>0</bitOffset>
              <bitWidth>16</bitWidth>
            </field>
            <field>
              <name>DUV</name>
              <bitOffset>16</bitOffset>
              <bitWidth>16</bitWidth>
            </field>
          </fields>
        </register>
        <register>
          <name>CLAR5</name>
          <addressOffset>0x1a4</addressOffset>
          <size>0x20</size>
          <fields>
            <field>
              <name>LAR</name>
              <bitOffset>0</bitOffset>
              <bitWidth>32</bitWidth>
            </field>
          </fields>
        </register>
        <register>
          <name>CTBR5</name>
          <addressOffset>0x1a8</addressOffset>
          <size>0x20</size>
          <fields>
            <field>
              <name>TSEL</name>
              <bitOffset>0</bitOffset>
              <bitWidth>8</bitWidth>
            </field>
            <field>
              <name>SBUS</name>
              <bitOffset>16</bitOffset>
              <bitWidth>1</bitWidth>
            </field>
            <field>
              <name>DBUS</name>
              <bitOffset>17</bitOffset>
              <bitWidth>1</bitWidth>
            </field>
          </fields>
        </register>
        <register>
          <name>CMAR5</name>
          <addressOffset>0x1b0</addressOffset>
          <size>0x20</size>
          <fields>
            <field>
              <name>MAR</name>
              <bitOffset>0</bitOffset>
              <bitWidth>32</bitWidth>
            </field>
          </fields>
        </register>
        <register>
          <name>CMDR5</name>
          <addressOffset>0x1b4</addressOffset>
          <size>0x20</size>
          <fields>
            <field>
              <name>MDR</name>
              <bitOffset>0</bitOffset>
              <bitWidth>32</bitWidth>
            </field>
          </fields>
        </register>
        <register>
          <name>CISR6</name>
          <addressOffset>0x1c0</addressOffset>
          <size>0x20</size>
          <fields>
            <field>
              <name>TEIF</name>
              <bitOffset>0</bitOffset>
              <bitWidth>1</bitWidth>
            </field>
            <field>
              <name>CTCIF</name>
              <bitOffset>1</bitOffset>
              <bitWidth>1</bitWidth>
            </field>
            <field>
              <name>BRTIF</name>
              <bitOffset>2</bitOffset>
              <bitWidth>1</bitWidth>
            </field>
            <field>
              <name>BTIF</name>
              <bitOffset>3</bitOffset>
              <bitWidth>1</bitWidth>
            </field>
            <field>
              <name>TCIF</name>
              <bitOffset>4</bitOffset>
              <bitWidth>1</bitWidth>
            </field>
            <field>
              <name>CRQA</name>
              <bitOffset>16</bitOffset>
              <bitWidth>1</bitWidth>
            </field>
          </fields>
        </register>
        <register>
          <name>CIFCR6</name>
          <addressOffset>0x1c4</addressOffset>
          <size>0x20</size>
          <fields>
            <field>
              <name>CTEIF</name>
              <bitOffset>0</bitOffset>
              <bitWidth>1</bitWidth>
            </field>
            <field>
              <name>CCTCIF</name>
              <bitOffset>1</bitOffset>
              <bitWidth>1</bitWidth>
            </field>
            <field>
              <name>CBRTIF</name>
              <bitOffset>2</bitOffset>
              <bitWidth>1</bitWidth>
            </field>
            <field>
              <name>CBTIF</name>
              <bitOffset>3</bitOffset>
              <bitWidth>1</bitWidth>
            </field>
            <field>
              <name>CLTCIF</name>
              <bitOffset>4</bitOffset>
              <bitWidth>1</bitWidth>
            </field>
          </fields>
        </register>
        <register>
          <name>CESR6</name>
          <addressOffset>0x1c8</addressOffset>
          <size>0x20</size>
          <fields>
            <field>
              <name>TEA</name>
              <bitOffset>0</bitOffset>
              <bitWidth>7</bitWidth>
            </field>
            <field>
              <name>TED</name>
              <bitOffset>7</bitOffset>
              <bitWidth>1</bitWidth>
            </field>
            <field>
              <name>TELD</name>
              <bitOffset>8</bitOffset>
              <bitWidth>1</bitWidth>
            </field>
            <field>
              <name>TEMD</name>
              <bitOffset>9</bitOffset>
              <bitWidth>1</bitWidth>
            </field>
            <field>
              <name>ASE</name>
              <bitOffset>10</bitOffset>
              <bitWidth>1</bitWidth>
            </field>
            <field>
              <name>BSE</name>
              <bitOffset>11</bitOffset>
              <bitWidth>1</bitWidth>
            </field>
          </fields>
        </register>
        <register>
          <name>CCR6</name>
          <addressOffset>0x1cc</addressOffset>
          <size>0x20</size>
          <fields>
            <field>
              <name>EN</name>
              <bitOffset>0</bitOffset>
              <bitWidth>1</bitWidth>
            </field>
            <field>
              <name>TEIE</name>
              <bitOffset>1</bitOffset>
              <bitWidth>1</bitWidth>
            </field>
            <field>
              <name>CTCIE</name>
              <bitOffset>2</bitOffset>
              <bitWidth>1</bitWidth>
            </field>
            <field>
              <name>BRTIE</name>
              <bitOffset>3</bitOffset>
              <bitWidth>1</bitWidth>
            </field>
            <field>
              <name>BTIE</name>
              <bitOffset>4</bitOffset>
              <bitWidth>1</bitWidth>
            </field>
            <field>
              <name>TCIE</name>
              <bitOffset>5</bitOffset>
              <bitWidth>1</bitWidth>
            </field>
            <field>
              <name>PL</name>
              <bitOffset>6</bitOffset>
              <bitWidth>2</bitWidth>
            </field>
            <field>
              <name>BEX</name>
              <bitOffset>12</bitOffset>
              <bitWidth>1</bitWidth>
            </field>
            <field>
              <name>HEX</name>
              <bitOffset>13</bitOffset>
              <bitWidth>1</bitWidth>
            </field>
            <field>
              <name>WEX</name>
              <bitOffset>14</bitOffset>
              <bitWidth>1</bitWidth>
            </field>
            <field>
              <name>SWRQ</name>
              <bitOffset>16</bitOffset>
              <bitWidth>1</bitWidth>
            </field>
          </fields>
        </register>
        <register>
          <name>CTCR6</name>
          <addressOffset>0x1d0</addressOffset>
          <size>0x20</size>
          <fields>
            <field>
              <name>SINC</name>
              <bitOffset>0</bitOffset>
              <bitWidth>2</bitWidth>
            </field>
            <field>
              <name>DINC</name>
              <bitOffset>2</bitOffset>
              <bitWidth>2</bitWidth>
            </field>
            <field>
              <name>SSIZE</name>
              <bitOffset>4</bitOffset>
              <bitWidth>2</bitWidth>
            </field>
            <field>
              <name>DSIZE</name>
              <bitOffset>6</bitOffset>
              <bitWidth>2</bitWidth>
            </field>
            <field>
              <name>SINCOS</name>
              <bitOffset>8</bitOffset>
              <bitWidth>2</bitWidth>
            </field>
            <field>
              <name>DINCOS</name>
              <bitOffset>10</bitOffset>
              <bitWidth>2</bitWidth>
            </field>
            <field>
              <name>SBURST</name>
              <bitOffset>12</bitOffset>
              <bitWidth>3</bitWidth>
            </field>
            <field>
              <name>DBURST</name>
              <bitOffset>15</bitOffset>
              <bitWidth>3</bitWidth>
            </field>
            <field>
              <name>TLEN</name>
              <bitOffset>18</bitOffset>
              <bitWidth>7</bitWidth>
            </field>
            <field>
              <name>PKE</name>
              <bitOffset>25</bitOffset>
              <bitWidth>1</bitWidth>
            </field>
            <field>
              <name>PAM</name>
              <bitOffset>26</bitOffset>
              <bitWidth>2</bitWidth>
            </field>
            <field>
              <name>TRGM</name>
              <bitOffset>28</bitOffset>
              <bitWidth>2</bitWidth>
            </field>
            <field>
              <name>SWRM</name>
              <bitOffset>30</bitOffset>
              <bitWidth>1</bitWidth>
            </field>
            <field>
              <name>BWM</name>
              <bitOffset>31</bitOffset>
              <bitWidth>1</bitWidth>
            </field>
          </fields>
        </register>
        <register>
          <name>CBNDTR6</name>
          <addressOffset>0x1d4</addressOffset>
          <size>0x20</size>
          <fields>
            <field>
              <name>BNDT</name>
              <bitOffset>0</bitOffset>
              <bitWidth>17</bitWidth>
            </field>
            <field>
              <name>BRSUM</name>
              <bitOffset>18</bitOffset>
              <bitWidth>1</bitWidth>
            </field>
            <field>
              <name>BRDUM</name>
              <bitOffset>19</bitOffset>
              <bitWidth>1</bitWidth>
            </field>
            <field>
              <name>BRC</name>
              <bitOffset>20</bitOffset>
              <bitWidth>12</bitWidth>
            </field>
          </fields>
        </register>
        <register>
          <name>CSAR6</name>
          <addressOffset>0x1d8</addressOffset>
          <size>0x20</size>
          <fields>
            <field>
              <name>SAR</name>
              <bitOffset>0</bitOffset>
              <bitWidth>32</bitWidth>
            </field>
          </fields>
        </register>
        <register>
          <name>CDAR6</name>
          <addressOffset>0x1dc</addressOffset>
          <size>0x20</size>
          <fields>
            <field>
              <name>DAR</name>
              <bitOffset>0</bitOffset>
              <bitWidth>32</bitWidth>
            </field>
          </fields>
        </register>
        <register>
          <name>CBRUR6</name>
          <addressOffset>0x1e0</addressOffset>
          <size>0x20</size>
          <fields>
            <field>
              <name>SUV</name>
              <bitOffset>0</bitOffset>
              <bitWidth>16</bitWidth>
            </field>
            <field>
              <name>DUV</name>
              <bitOffset>16</bitOffset>
              <bitWidth>16</bitWidth>
            </field>
          </fields>
        </register>
        <register>
          <name>CLAR6</name>
          <addressOffset>0x1e4</addressOffset>
          <size>0x20</size>
          <fields>
            <field>
              <name>LAR</name>
              <bitOffset>0</bitOffset>
              <bitWidth>32</bitWidth>
            </field>
          </fields>
        </register>
        <register>
          <name>CTBR6</name>
          <addressOffset>0x1e8</addressOffset>
          <size>0x20</size>
          <fields>
            <field>
              <name>TSEL</name>
              <bitOffset>0</bitOffset>
              <bitWidth>8</bitWidth>
            </field>
            <field>
              <name>SBUS</name>
              <bitOffset>16</bitOffset>
              <bitWidth>1</bitWidth>
            </field>
            <field>
              <name>DBUS</name>
              <bitOffset>17</bitOffset>
              <bitWidth>1</bitWidth>
            </field>
          </fields>
        </register>
        <register>
          <name>CMAR6</name>
          <addressOffset>0x1f0</addressOffset>
          <size>0x20</size>
          <fields>
            <field>
              <name>MAR</name>
              <bitOffset>0</bitOffset>
              <bitWidth>32</bitWidth>
            </field>
          </fields>
        </register>
        <register>
          <name>CMDR6</name>
          <addressOffset>0x1f4</addressOffset>
          <size>0x20</size>
          <fields>
            <field>
              <name>MDR</name>
              <bitOffset>0</bitOffset>
              <bitWidth>32</bitWidth>
            </field>
          </fields>
        </register>
        <register>
          <name>CISR7</name>
          <addressOffset>0x200</addressOffset>
          <size>0x20</size>
          <fields>
            <field>
              <name>TEIF</name>
              <bitOffset>0</bitOffset>
              <bitWidth>1</bitWidth>
            </field>
            <field>
              <name>CTCIF</name>
              <bitOffset>1</bitOffset>
              <bitWidth>1</bitWidth>
            </field>
            <field>
              <name>BRTIF</name>
              <bitOffset>2</bitOffset>
              <bitWidth>1</bitWidth>
            </field>
            <field>
              <name>BTIF</name>
              <bitOffset>3</bitOffset>
              <bitWidth>1</bitWidth>
            </field>
            <field>
              <name>TCIF</name>
              <bitOffset>4</bitOffset>
              <bitWidth>1</bitWidth>
            </field>
            <field>
              <name>CRQA</name>
              <bitOffset>16</bitOffset>
              <bitWidth>1</bitWidth>
            </field>
          </fields>
        </register>
        <register>
          <name>CIFCR7</name>
          <addressOffset>0x204</addressOffset>
          <size>0x20</size>
          <fields>
            <field>
              <name>CTEIF</name>
              <bitOffset>0</bitOffset>
              <bitWidth>1</bitWidth>
            </field>
            <field>
              <name>CCTCIF</name>
              <bitOffset>1</bitOffset>
              <bitWidth>1</bitWidth>
            </field>
            <field>
              <name>CBRTIF</name>
              <bitOffset>2</bitOffset>
              <bitWidth>1</bitWidth>
            </field>
            <field>
              <name>CBTIF</name>
              <bitOffset>3</bitOffset>
              <bitWidth>1</bitWidth>
            </field>
            <field>
              <name>CLTCIF</name>
              <bitOffset>4</bitOffset>
              <bitWidth>1</bitWidth>
            </field>
          </fields>
        </register>
        <register>
          <name>CESR7</name>
          <addressOffset>0x208</addressOffset>
          <size>0x20</size>
          <fields>
            <field>
              <name>TEA</name>
              <bitOffset>0</bitOffset>
              <bitWidth>7</bitWidth>
            </field>
            <field>
              <name>TED</name>
              <bitOffset>7</bitOffset>
              <bitWidth>1</bitWidth>
            </field>
            <field>
              <name>TELD</name>
              <bitOffset>8</bitOffset>
              <bitWidth>1</bitWidth>
            </field>
            <field>
              <name>TEMD</name>
              <bitOffset>9</bitOffset>
              <bitWidth>1</bitWidth>
            </field>
            <field>
              <name>ASE</name>
              <bitOffset>10</bitOffset>
              <bitWidth>1</bitWidth>
            </field>
            <field>
              <name>BSE</name>
              <bitOffset>11</bitOffset>
              <bitWidth>1</bitWidth>
            </field>
          </fields>
        </register>
        <register>
          <name>CCR7</name>
          <addressOffset>0x20c</addressOffset>
          <size>0x20</size>
          <fields>
            <field>
              <name>EN</name>
              <bitOffset>0</bitOffset>
              <bitWidth>1</bitWidth>
            </field>
            <field>
              <name>TEIE</name>
              <bitOffset>1</bitOffset>
              <bitWidth>1</bitWidth>
            </field>
            <field>
              <name>CTCIE</name>
              <bitOffset>2</bitOffset>
              <bitWidth>1</bitWidth>
            </field>
            <field>
              <name>BRTIE</name>
              <bitOffset>3</bitOffset>
              <bitWidth>1</bitWidth>
            </field>
            <field>
              <name>BTIE</name>
              <bitOffset>4</bitOffset>
              <bitWidth>1</bitWidth>
            </field>
            <field>
              <name>TCIE</name>
              <bitOffset>5</bitOffset>
              <bitWidth>1</bitWidth>
            </field>
            <field>
              <name>PL</name>
              <bitOffset>6</bitOffset>
              <bitWidth>2</bitWidth>
            </field>
            <field>
              <name>BEX</name>
              <bitOffset>12</bitOffset>
              <bitWidth>1</bitWidth>
            </field>
            <field>
              <name>HEX</name>
              <bitOffset>13</bitOffset>
              <bitWidth>1</bitWidth>
            </field>
            <field>
              <name>WEX</name>
              <bitOffset>14</bitOffset>
              <bitWidth>1</bitWidth>
            </field>
            <field>
              <name>SWRQ</name>
              <bitOffset>16</bitOffset>
              <bitWidth>1</bitWidth>
            </field>
          </fields>
        </register>
        <register>
          <name>CTCR7</name>
          <addressOffset>0x210</addressOffset>
          <size>0x20</size>
          <fields>
            <field>
              <name>SINC</name>
              <bitOffset>0</bitOffset>
              <bitWidth>2</bitWidth>
            </field>
            <field>
              <name>DINC</name>
              <bitOffset>2</bitOffset>
              <bitWidth>2</bitWidth>
            </field>
            <field>
              <name>SSIZE</name>
              <bitOffset>4</bitOffset>
              <bitWidth>2</bitWidth>
            </field>
            <field>
              <name>DSIZE</name>
              <bitOffset>6</bitOffset>
              <bitWidth>2</bitWidth>
            </field>
            <field>
              <name>SINCOS</name>
              <bitOffset>8</bitOffset>
              <bitWidth>2</bitWidth>
            </field>
            <field>
              <name>DINCOS</name>
              <bitOffset>10</bitOffset>
              <bitWidth>2</bitWidth>
            </field>
            <field>
              <name>SBURST</name>
              <bitOffset>12</bitOffset>
              <bitWidth>3</bitWidth>
            </field>
            <field>
              <name>DBURST</name>
              <bitOffset>15</bitOffset>
              <bitWidth>3</bitWidth>
            </field>
            <field>
              <name>TLEN</name>
              <bitOffset>18</bitOffset>
              <bitWidth>7</bitWidth>
            </field>
            <field>
              <name>PKE</name>
              <bitOffset>25</bitOffset>
              <bitWidth>1</bitWidth>
            </field>
            <field>
              <name>PAM</name>
              <bitOffset>26</bitOffset>
              <bitWidth>2</bitWidth>
            </field>
            <field>
              <name>TRGM</name>
              <bitOffset>28</bitOffset>
              <bitWidth>2</bitWidth>
            </field>
            <field>
              <name>SWRM</name>
              <bitOffset>30</bitOffset>
              <bitWidth>1</bitWidth>
            </field>
            <field>
              <name>BWM</name>
              <bitOffset>31</bitOffset>
              <bitWidth>1</bitWidth>
            </field>
          </fields>
        </register>
        <register>
          <name>CBNDTR7</name>
          <addressOffset>0x214</addressOffset>
          <size>0x20</size>
          <fields>
            <field>
              <name>BNDT</name>
              <bitOffset>0</bitOffset>
              <bitWidth>17</bitWidth>
            </field>
            <field>
              <name>BRSUM</name>
              <bitOffset>18</bitOffset>
              <bitWidth>1</bitWidth>
            </field>
            <field>
              <name>BRDUM</name>
              <bitOffset>19</bitOffset>
              <bitWidth>1</bitWidth>
            </field>
            <field>
              <name>BRC</name>
              <bitOffset>20</bitOffset>
              <bitWidth>12</bitWidth>
            </field>
          </fields>
        </register>
        <register>
          <name>CSAR7</name>
          <addressOffset>0x218</addressOffset>
          <size>0x20</size>
          <fields>
            <field>
              <name>SAR</name>
              <bitOffset>0</bitOffset>
              <bitWidth>32</bitWidth>
            </field>
          </fields>
        </register>
        <register>
          <name>CDAR7</name>
          <addressOffset>0x21c</addressOffset>
          <size>0x20</size>
          <fields>
            <field>
              <name>DAR</name>
              <bitOffset>0</bitOffset>
              <bitWidth>32</bitWidth>
            </field>
          </fields>
        </register>
        <register>
          <name>CBRUR7</name>
          <addressOffset>0x220</addressOffset>
          <size>0x20</size>
          <fields>
            <field>
              <name>SUV</name>
              <bitOffset>0</bitOffset>
              <bitWidth>16</bitWidth>
            </field>
            <field>
              <name>DUV</name>
              <bitOffset>16</bitOffset>
              <bitWidth>16</bitWidth>
            </field>
          </fields>
        </register>
        <register>
          <name>CLAR7</name>
          <addressOffset>0x224</addressOffset>
          <size>0x20</size>
          <fields>
            <field>
              <name>LAR</name>
              <bitOffset>0</bitOffset>
              <bitWidth>32</bitWidth>
            </field>
          </fields>
        </register>
        <register>
          <name>CTBR7</name>
          <addressOffset>0x228</addressOffset>
          <size>0x20</size>
          <fields>
            <field>
              <name>TSEL</name>
              <bitOffset>0</bitOffset>
              <bitWidth>8</bitWidth>
            </field>
            <field>
              <name>SBUS</name>
              <bitOffset>16</bitOffset>
              <bitWidth>1</bitWidth>
            </field>
            <field>
              <name>DBUS</name>
              <bitOffset>17</bitOffset>
              <bitWidth>1</bitWidth>
            </field>
          </fields>
        </register>
        <register>
          <name>CMAR7</name>
          <addressOffset>0x230</addressOffset>
          <size>0x20</size>
          <fields>
            <field>
              <name>MAR</name>
              <bitOffset>0</bitOffset>
              <bitWidth>32</bitWidth>
            </field>
          </fields>
        </register>
        <register>
          <name>CMDR7</name>
          <addressOffset>0x234</addressOffset>
          <size>0x20</size>
          <fields>
            <field>
              <name>MDR</name>
              <bitOffset>0</bitOffset>
              <bitWidth>32</bitWidth>
            </field>
          </fields>
        </register>
        <register>
          <name>CISR8</name>
          <addressOffset>0x240</addressOffset>
          <size>0x20</size>
          <fields>
            <field>
              <name>TEIF</name>
              <bitOffset>0</bitOffset>
              <bitWidth>1</bitWidth>
            </field>
            <field>
              <name>CTCIF</name>
              <bitOffset>1</bitOffset>
              <bitWidth>1</bitWidth>
            </field>
            <field>
              <name>BRTIF</name>
              <bitOffset>2</bitOffset>
              <bitWidth>1</bitWidth>
            </field>
            <field>
              <name>BTIF</name>
              <bitOffset>3</bitOffset>
              <bitWidth>1</bitWidth>
            </field>
            <field>
              <name>TCIF</name>
              <bitOffset>4</bitOffset>
              <bitWidth>1</bitWidth>
            </field>
            <field>
              <name>CRQA</name>
              <bitOffset>16</bitOffset>
              <bitWidth>1</bitWidth>
            </field>
          </fields>
        </register>
        <register>
          <name>CIFCR8</name>
          <addressOffset>0x244</addressOffset>
          <size>0x20</size>
          <fields>
            <field>
              <name>CTEIF</name>
              <bitOffset>0</bitOffset>
              <bitWidth>1</bitWidth>
            </field>
            <field>
              <name>CCTCIF</name>
              <bitOffset>1</bitOffset>
              <bitWidth>1</bitWidth>
            </field>
            <field>
              <name>CBRTIF</name>
              <bitOffset>2</bitOffset>
              <bitWidth>1</bitWidth>
            </field>
            <field>
              <name>CBTIF</name>
              <bitOffset>3</bitOffset>
              <bitWidth>1</bitWidth>
            </field>
            <field>
              <name>CLTCIF</name>
              <bitOffset>4</bitOffset>
              <bitWidth>1</bitWidth>
            </field>
          </fields>
        </register>
        <register>
          <name>CESR8</name>
          <addressOffset>0x248</addressOffset>
          <size>0x20</size>
          <fields>
            <field>
              <name>TEA</name>
              <bitOffset>0</bitOffset>
              <bitWidth>7</bitWidth>
            </field>
            <field>
              <name>TED</name>
              <bitOffset>7</bitOffset>
              <bitWidth>1</bitWidth>
            </field>
            <field>
              <name>TELD</name>
              <bitOffset>8</bitOffset>
              <bitWidth>1</bitWidth>
            </field>
            <field>
              <name>TEMD</name>
              <bitOffset>9</bitOffset>
              <bitWidth>1</bitWidth>
            </field>
            <field>
              <name>ASE</name>
              <bitOffset>10</bitOffset>
              <bitWidth>1</bitWidth>
            </field>
            <field>
              <name>BSE</name>
              <bitOffset>11</bitOffset>
              <bitWidth>1</bitWidth>
            </field>
          </fields>
        </register>
        <register>
          <name>CCR8</name>
          <addressOffset>0x24c</addressOffset>
          <size>0x20</size>
          <fields>
            <field>
              <name>EN</name>
              <bitOffset>0</bitOffset>
              <bitWidth>1</bitWidth>
            </field>
            <field>
              <name>TEIE</name>
              <bitOffset>1</bitOffset>
              <bitWidth>1</bitWidth>
            </field>
            <field>
              <name>CTCIE</name>
              <bitOffset>2</bitOffset>
              <bitWidth>1</bitWidth>
            </field>
            <field>
              <name>BRTIE</name>
              <bitOffset>3</bitOffset>
              <bitWidth>1</bitWidth>
            </field>
            <field>
              <name>BTIE</name>
              <bitOffset>4</bitOffset>
              <bitWidth>1</bitWidth>
            </field>
            <field>
              <name>TCIE</name>
              <bitOffset>5</bitOffset>
              <bitWidth>1</bitWidth>
            </field>
            <field>
              <name>PL</name>
              <bitOffset>6</bitOffset>
              <bitWidth>2</bitWidth>
            </field>
            <field>
              <name>BEX</name>
              <bitOffset>12</bitOffset>
              <bitWidth>1</bitWidth>
            </field>
            <field>
              <name>HEX</name>
              <bitOffset>13</bitOffset>
              <bitWidth>1</bitWidth>
            </field>
            <field>
              <name>WEX</name>
              <bitOffset>14</bitOffset>
              <bitWidth>1</bitWidth>
            </field>
            <field>
              <name>SWRQ</name>
              <bitOffset>16</bitOffset>
              <bitWidth>1</bitWidth>
            </field>
          </fields>
        </register>
        <register>
          <name>CTCR8</name>
          <addressOffset>0x250</addressOffset>
          <size>0x20</size>
          <fields>
            <field>
              <name>SINC</name>
              <bitOffset>0</bitOffset>
              <bitWidth>2</bitWidth>
            </field>
            <field>
              <name>DINC</name>
              <bitOffset>2</bitOffset>
              <bitWidth>2</bitWidth>
            </field>
            <field>
              <name>SSIZE</name>
              <bitOffset>4</bitOffset>
              <bitWidth>2</bitWidth>
            </field>
            <field>
              <name>DSIZE</name>
              <bitOffset>6</bitOffset>
              <bitWidth>2</bitWidth>
            </field>
            <field>
              <name>SINCOS</name>
              <bitOffset>8</bitOffset>
              <bitWidth>2</bitWidth>
            </field>
            <field>
              <name>DINCOS</name>
              <bitOffset>10</bitOffset>
              <bitWidth>2</bitWidth>
            </field>
            <field>
              <name>SBURST</name>
              <bitOffset>12</bitOffset>
              <bitWidth>3</bitWidth>
            </field>
            <field>
              <name>DBURST</name>
              <bitOffset>15</bitOffset>
              <bitWidth>3</bitWidth>
            </field>
            <field>
              <name>TLEN</name>
              <bitOffset>18</bitOffset>
              <bitWidth>7</bitWidth>
            </field>
            <field>
              <name>PKE</name>
              <bitOffset>25</bitOffset>
              <bitWidth>1</bitWidth>
            </field>
            <field>
              <name>PAM</name>
              <bitOffset>26</bitOffset>
              <bitWidth>2</bitWidth>
            </field>
            <field>
              <name>TRGM</name>
              <bitOffset>28</bitOffset>
              <bitWidth>2</bitWidth>
            </field>
            <field>
              <name>SWRM</name>
              <bitOffset>30</bitOffset>
              <bitWidth>1</bitWidth>
            </field>
            <field>
              <name>BWM</name>
              <bitOffset>31</bitOffset>
              <bitWidth>1</bitWidth>
            </field>
          </fields>
        </register>
        <register>
          <name>CBNDTR8</name>
          <addressOffset>0x254</addressOffset>
          <size>0x20</size>
          <fields>
            <field>
              <name>BNDT</name>
              <bitOffset>0</bitOffset>
              <bitWidth>17</bitWidth>
            </field>
            <field>
              <name>BRSUM</name>
              <bitOffset>18</bitOffset>
              <bitWidth>1</bitWidth>
            </field>
            <field>
              <name>BRDUM</name>
              <bitOffset>19</bitOffset>
              <bitWidth>1</bitWidth>
            </field>
            <field>
              <name>BRC</name>
              <bitOffset>20</bitOffset>
              <bitWidth>12</bitWidth>
            </field>
          </fields>
        </register>
        <register>
          <name>CSAR8</name>
          <addressOffset>0x258</addressOffset>
          <size>0x20</size>
          <fields>
            <field>
              <name>SAR</name>
              <bitOffset>0</bitOffset>
              <bitWidth>32</bitWidth>
            </field>
          </fields>
        </register>
        <register>
          <name>CDAR8</name>
          <addressOffset>0x25c</addressOffset>
          <size>0x20</size>
          <fields>
            <field>
              <name>DAR</name>
              <bitOffset>0</bitOffset>
              <bitWidth>32</bitWidth>
            </field>
          </fields>
        </register>
        <register>
          <name>CBRUR8</name>
          <addressOffset>0x260</addressOffset>
          <size>0x20</size>
          <fields>
            <field>
              <name>SUV</name>
              <bitOffset>0</bitOffset>
              <bitWidth>16</bitWidth>
            </field>
            <field>
              <name>DUV</name>
              <bitOffset>16</bitOffset>
              <bitWidth>16</bitWidth>
            </field>
          </fields>
        </register>
        <register>
          <name>CLAR8</name>
          <addressOffset>0x264</addressOffset>
          <size>0x20</size>
          <fields>
            <field>
              <name>LAR</name>
              <bitOffset>0</bitOffset>
              <bitWidth>32</bitWidth>
            </field>
          </fields>
        </register>
        <register>
          <name>CTBR8</name>
          <addressOffset>0x268</addressOffset>
          <size>0x20</size>
          <fields>
            <field>
              <name>TSEL</name>
              <bitOffset>0</bitOffset>
              <bitWidth>8</bitWidth>
            </field>
            <field>
              <name>SBUS</name>
              <bitOffset>16</bitOffset>
              <bitWidth>1</bitWidth>
            </field>
            <field>
              <name>DBUS</name>
              <bitOffset>17</bitOffset>
              <bitWidth>1</bitWidth>
            </field>
          </fields>
        </register>
        <register>
          <name>CMAR8</name>
          <addressOffset>0x270</addressOffset>
          <size>0x20</size>
          <fields>
            <field>
              <name>MAR</name>
              <bitOffset>0</bitOffset>
              <bitWidth>32</bitWidth>
            </field>
          </fields>
        </register>
        <register>
          <name>CMDR8</name>
          <addressOffset>0x274</addressOffset>
          <size>0x20</size>
          <fields>
            <field>
              <name>MDR</name>
              <bitOffset>0</bitOffset>
              <bitWidth>32</bitWidth>
            </field>
          </fields>
        </register>
        <register>
          <name>CISR9</name>
          <addressOffset>0x280</addressOffset>
          <size>0x20</size>
          <fields>
            <field>
              <name>TEIF</name>
              <bitOffset>0</bitOffset>
              <bitWidth>1</bitWidth>
            </field>
            <field>
              <name>CTCIF</name>
              <bitOffset>1</bitOffset>
              <bitWidth>1</bitWidth>
            </field>
            <field>
              <name>BRTIF</name>
              <bitOffset>2</bitOffset>
              <bitWidth>1</bitWidth>
            </field>
            <field>
              <name>BTIF</name>
              <bitOffset>3</bitOffset>
              <bitWidth>1</bitWidth>
            </field>
            <field>
              <name>TCIF</name>
              <bitOffset>4</bitOffset>
              <bitWidth>1</bitWidth>
            </field>
            <field>
              <name>CRQA</name>
              <bitOffset>16</bitOffset>
              <bitWidth>1</bitWidth>
            </field>
          </fields>
        </register>
        <register>
          <name>CIFCR9</name>
          <addressOffset>0x284</addressOffset>
          <size>0x20</size>
          <fields>
            <field>
              <name>CTEIF</name>
              <bitOffset>0</bitOffset>
              <bitWidth>1</bitWidth>
            </field>
            <field>
              <name>CCTCIF</name>
              <bitOffset>1</bitOffset>
              <bitWidth>1</bitWidth>
            </field>
            <field>
              <name>CBRTIF</name>
              <bitOffset>2</bitOffset>
              <bitWidth>1</bitWidth>
            </field>
            <field>
              <name>CBTIF</name>
              <bitOffset>3</bitOffset>
              <bitWidth>1</bitWidth>
            </field>
            <field>
              <name>CLTCIF</name>
              <bitOffset>4</bitOffset>
              <bitWidth>1</bitWidth>
            </field>
          </fields>
        </register>
        <register>
          <name>CESR9</name>
          <addressOffset>0x288</addressOffset>
          <size>0x20</size>
          <fields>
            <field>
              <name>TEA</name>
              <bitOffset>0</bitOffset>
              <bitWidth>7</bitWidth>
            </field>
            <field>
              <name>TED</name>
              <bitOffset>7</bitOffset>
              <bitWidth>1</bitWidth>
            </field>
            <field>
              <name>TELD</name>
              <bitOffset>8</bitOffset>
              <bitWidth>1</bitWidth>
            </field>
            <field>
              <name>TEMD</name>
              <bitOffset>9</bitOffset>
              <bitWidth>1</bitWidth>
            </field>
            <field>
              <name>ASE</name>
              <bitOffset>10</bitOffset>
              <bitWidth>1</bitWidth>
            </field>
            <field>
              <name>BSE</name>
              <bitOffset>11</bitOffset>
              <bitWidth>1</bitWidth>
            </field>
          </fields>
        </register>
        <register>
          <name>CCR9</name>
          <addressOffset>0x28c</addressOffset>
          <size>0x20</size>
          <fields>
            <field>
              <name>EN</name>
              <bitOffset>0</bitOffset>
              <bitWidth>1</bitWidth>
            </field>
            <field>
              <name>TEIE</name>
              <bitOffset>1</bitOffset>
              <bitWidth>1</bitWidth>
            </field>
            <field>
              <name>CTCIE</name>
              <bitOffset>2</bitOffset>
              <bitWidth>1</bitWidth>
            </field>
            <field>
              <name>BRTIE</name>
              <bitOffset>3</bitOffset>
              <bitWidth>1</bitWidth>
            </field>
            <field>
              <name>BTIE</name>
              <bitOffset>4</bitOffset>
              <bitWidth>1</bitWidth>
            </field>
            <field>
              <name>TCIE</name>
              <bitOffset>5</bitOffset>
              <bitWidth>1</bitWidth>
            </field>
            <field>
              <name>PL</name>
              <bitOffset>6</bitOffset>
              <bitWidth>2</bitWidth>
            </field>
            <field>
              <name>BEX</name>
              <bitOffset>12</bitOffset>
              <bitWidth>1</bitWidth>
            </field>
            <field>
              <name>HEX</name>
              <bitOffset>13</bitOffset>
              <bitWidth>1</bitWidth>
            </field>
            <field>
              <name>WEX</name>
              <bitOffset>14</bitOffset>
              <bitWidth>1</bitWidth>
            </field>
            <field>
              <name>SWRQ</name>
              <bitOffset>16</bitOffset>
              <bitWidth>1</bitWidth>
            </field>
          </fields>
        </register>
        <register>
          <name>CTCR9</name>
          <addressOffset>0x290</addressOffset>
          <size>0x20</size>
          <fields>
            <field>
              <name>SINC</name>
              <bitOffset>0</bitOffset>
              <bitWidth>2</bitWidth>
            </field>
            <field>
              <name>DINC</name>
              <bitOffset>2</bitOffset>
              <bitWidth>2</bitWidth>
            </field>
            <field>
              <name>SSIZE</name>
              <bitOffset>4</bitOffset>
              <bitWidth>2</bitWidth>
            </field>
            <field>
              <name>DSIZE</name>
              <bitOffset>6</bitOffset>
              <bitWidth>2</bitWidth>
            </field>
            <field>
              <name>SINCOS</name>
              <bitOffset>8</bitOffset>
              <bitWidth>2</bitWidth>
            </field>
            <field>
              <name>DINCOS</name>
              <bitOffset>10</bitOffset>
              <bitWidth>2</bitWidth>
            </field>
            <field>
              <name>SBURST</name>
              <bitOffset>12</bitOffset>
              <bitWidth>3</bitWidth>
            </field>
            <field>
              <name>DBURST</name>
              <bitOffset>15</bitOffset>
              <bitWidth>3</bitWidth>
            </field>
            <field>
              <name>TLEN</name>
              <bitOffset>18</bitOffset>
              <bitWidth>7</bitWidth>
            </field>
            <field>
              <name>PKE</name>
              <bitOffset>25</bitOffset>
              <bitWidth>1</bitWidth>
            </field>
            <field>
              <name>PAM</name>
              <bitOffset>26</bitOffset>
              <bitWidth>2</bitWidth>
            </field>
            <field>
              <name>TRGM</name>
              <bitOffset>28</bitOffset>
              <bitWidth>2</bitWidth>
            </field>
            <field>
              <name>SWRM</name>
              <bitOffset>30</bitOffset>
              <bitWidth>1</bitWidth>
            </field>
            <field>
              <name>BWM</name>
              <bitOffset>31</bitOffset>
              <bitWidth>1</bitWidth>
            </field>
          </fields>
        </register>
        <register>
          <name>CBNDTR9</name>
          <addressOffset>0x294</addressOffset>
          <size>0x20</size>
          <fields>
            <field>
              <name>BNDT</name>
              <bitOffset>0</bitOffset>
              <bitWidth>17</bitWidth>
            </field>
            <field>
              <name>BRSUM</name>
              <bitOffset>18</bitOffset>
              <bitWidth>1</bitWidth>
            </field>
            <field>
              <name>BRDUM</name>
              <bitOffset>19</bitOffset>
              <bitWidth>1</bitWidth>
            </field>
            <field>
              <name>BRC</name>
              <bitOffset>20</bitOffset>
              <bitWidth>12</bitWidth>
            </field>
          </fields>
        </register>
        <register>
          <name>CSAR9</name>
          <addressOffset>0x298</addressOffset>
          <size>0x20</size>
          <fields>
            <field>
              <name>SAR</name>
              <bitOffset>0</bitOffset>
              <bitWidth>32</bitWidth>
            </field>
          </fields>
        </register>
        <register>
          <name>CDAR9</name>
          <addressOffset>0x29c</addressOffset>
          <size>0x20</size>
          <fields>
            <field>
              <name>DAR</name>
              <bitOffset>0</bitOffset>
              <bitWidth>32</bitWidth>
            </field>
          </fields>
        </register>
        <register>
          <name>CBRUR9</name>
          <addressOffset>0x2a0</addressOffset>
          <size>0x20</size>
          <fields>
            <field>
              <name>SUV</name>
              <bitOffset>0</bitOffset>
              <bitWidth>16</bitWidth>
            </field>
            <field>
              <name>DUV</name>
              <bitOffset>16</bitOffset>
              <bitWidth>16</bitWidth>
            </field>
          </fields>
        </register>
        <register>
          <name>CLAR9</name>
          <addressOffset>0x2a4</addressOffset>
          <size>0x20</size>
          <fields>
            <field>
              <name>LAR</name>
              <bitOffset>0</bitOffset>
              <bitWidth>32</bitWidth>
            </field>
          </fields>
        </register>
        <register>
          <name>CTBR9</name>
          <addressOffset>0x2a8</addressOffset>
          <size>0x20</size>
          <fields>
            <field>
              <name>TSEL</name>
              <bitOffset>0</bitOffset>
              <bitWidth>8</bitWidth>
            </field>
            <field>
              <name>SBUS</name>
              <bitOffset>16</bitOffset>
              <bitWidth>1</bitWidth>
            </field>
            <field>
              <name>DBUS</name>
              <bitOffset>17</bitOffset>
              <bitWidth>1</bitWidth>
            </field>
          </fields>
        </register>
        <register>
          <name>CMAR9</name>
          <addressOffset>0x2b0</addressOffset>
          <size>0x20</size>
          <fields>
            <field>
              <name>MAR</name>
              <bitOffset>0</bitOffset>
              <bitWidth>32</bitWidth>
            </field>
          </fields>
        </register>
        <register>
          <name>CMDR9</name>
          <addressOffset>0x2b4</addressOffset>
          <size>0x20</size>
          <fields>
            <field>
              <name>MDR</name>
              <bitOffset>0</bitOffset>
              <bitWidth>32</bitWidth>
            </field>
          </fields>
        </register>
        <register>
          <name>CISR0</name>
          <addressOffset>0x2c0</addressOffset>
          <size>0x20</size>
          <fields>
            <field>
              <name>TEIF</name>
              <bitOffset>0</bitOffset>
              <bitWidth>1</bitWidth>
            </field>
            <field>
              <name>CTCIF</name>
              <bitOffset>1</bitOffset>
              <bitWidth>1</bitWidth>
            </field>
            <field>
              <name>BRTIF</name>
              <bitOffset>2</bitOffset>
              <bitWidth>1</bitWidth>
            </field>
            <field>
              <name>BTIF</name>
              <bitOffset>3</bitOffset>
              <bitWidth>1</bitWidth>
            </field>
            <field>
              <name>TCIF</name>
              <bitOffset>4</bitOffset>
              <bitWidth>1</bitWidth>
            </field>
            <field>
              <name>CRQA</name>
              <bitOffset>16</bitOffset>
              <bitWidth>1</bitWidth>
            </field>
          </fields>
        </register>
        <register>
          <name>CIFCR0</name>
          <addressOffset>0x2c4</addressOffset>
          <size>0x20</size>
          <fields>
            <field>
              <name>CTEIF</name>
              <bitOffset>0</bitOffset>
              <bitWidth>1</bitWidth>
            </field>
            <field>
              <name>CCTCIF</name>
              <bitOffset>1</bitOffset>
              <bitWidth>1</bitWidth>
            </field>
            <field>
              <name>CBRTIF</name>
              <bitOffset>2</bitOffset>
              <bitWidth>1</bitWidth>
            </field>
            <field>
              <name>CBTIF</name>
              <bitOffset>3</bitOffset>
              <bitWidth>1</bitWidth>
            </field>
            <field>
              <name>CLTCIF</name>
              <bitOffset>4</bitOffset>
              <bitWidth>1</bitWidth>
            </field>
          </fields>
        </register>
        <register>
          <name>CESR0</name>
          <addressOffset>0x2c8</addressOffset>
          <size>0x20</size>
          <fields>
            <field>
              <name>TEA</name>
              <bitOffset>0</bitOffset>
              <bitWidth>7</bitWidth>
            </field>
            <field>
              <name>TED</name>
              <bitOffset>7</bitOffset>
              <bitWidth>1</bitWidth>
            </field>
            <field>
              <name>TELD</name>
              <bitOffset>8</bitOffset>
              <bitWidth>1</bitWidth>
            </field>
            <field>
              <name>TEMD</name>
              <bitOffset>9</bitOffset>
              <bitWidth>1</bitWidth>
            </field>
            <field>
              <name>ASE</name>
              <bitOffset>10</bitOffset>
              <bitWidth>1</bitWidth>
            </field>
            <field>
              <name>BSE</name>
              <bitOffset>11</bitOffset>
              <bitWidth>1</bitWidth>
            </field>
          </fields>
        </register>
        <register>
          <name>CCR0</name>
          <addressOffset>0x2cc</addressOffset>
          <size>0x20</size>
          <fields>
            <field>
              <name>EN</name>
              <bitOffset>0</bitOffset>
              <bitWidth>1</bitWidth>
            </field>
            <field>
              <name>TEIE</name>
              <bitOffset>1</bitOffset>
              <bitWidth>1</bitWidth>
            </field>
            <field>
              <name>CTCIE</name>
              <bitOffset>2</bitOffset>
              <bitWidth>1</bitWidth>
            </field>
            <field>
              <name>BRTIE</name>
              <bitOffset>3</bitOffset>
              <bitWidth>1</bitWidth>
            </field>
            <field>
              <name>BTIE</name>
              <bitOffset>4</bitOffset>
              <bitWidth>1</bitWidth>
            </field>
            <field>
              <name>TCIE</name>
              <bitOffset>5</bitOffset>
              <bitWidth>1</bitWidth>
            </field>
            <field>
              <name>PL</name>
              <bitOffset>6</bitOffset>
              <bitWidth>2</bitWidth>
            </field>
            <field>
              <name>BEX</name>
              <bitOffset>12</bitOffset>
              <bitWidth>1</bitWidth>
            </field>
            <field>
              <name>HEX</name>
              <bitOffset>13</bitOffset>
              <bitWidth>1</bitWidth>
            </field>
            <field>
              <name>WEX</name>
              <bitOffset>14</bitOffset>
              <bitWidth>1</bitWidth>
            </field>
            <field>
              <name>SWRQ</name>
              <bitOffset>16</bitOffset>
              <bitWidth>1</bitWidth>
            </field>
          </fields>
        </register>
        <register>
          <name>CTCR0</name>
          <addressOffset>0x2d0</addressOffset>
          <size>0x20</size>
          <fields>
            <field>
              <name>SINC</name>
              <bitOffset>0</bitOffset>
              <bitWidth>2</bitWidth>
            </field>
            <field>
              <name>DINC</name>
              <bitOffset>2</bitOffset>
              <bitWidth>2</bitWidth>
            </field>
            <field>
              <name>SSIZE</name>
              <bitOffset>4</bitOffset>
              <bitWidth>2</bitWidth>
            </field>
            <field>
              <name>DSIZE</name>
              <bitOffset>6</bitOffset>
              <bitWidth>2</bitWidth>
            </field>
            <field>
              <name>SINCOS</name>
              <bitOffset>8</bitOffset>
              <bitWidth>2</bitWidth>
            </field>
            <field>
              <name>DINCOS</name>
              <bitOffset>10</bitOffset>
              <bitWidth>2</bitWidth>
            </field>
            <field>
              <name>SBURST</name>
              <bitOffset>12</bitOffset>
              <bitWidth>3</bitWidth>
            </field>
            <field>
              <name>DBURST</name>
              <bitOffset>15</bitOffset>
              <bitWidth>3</bitWidth>
            </field>
            <field>
              <name>TLEN</name>
              <bitOffset>18</bitOffset>
              <bitWidth>7</bitWidth>
            </field>
            <field>
              <name>PKE</name>
              <bitOffset>25</bitOffset>
              <bitWidth>1</bitWidth>
            </field>
            <field>
              <name>PAM</name>
              <bitOffset>26</bitOffset>
              <bitWidth>2</bitWidth>
            </field>
            <field>
              <name>TRGM</name>
              <bitOffset>28</bitOffset>
              <bitWidth>2</bitWidth>
            </field>
            <field>
              <name>SWRM</name>
              <bitOffset>30</bitOffset>
              <bitWidth>1</bitWidth>
            </field>
            <field>
              <name>BWM</name>
              <bitOffset>31</bitOffset>
              <bitWidth>1</bitWidth>
            </field>
          </fields>
        </register>
        <register>
          <name>CBNDTR0</name>
          <addressOffset>0x2d4</addressOffset>
          <size>0x20</size>
          <fields>
            <field>
              <name>BNDT</name>
              <bitOffset>0</bitOffset>
              <bitWidth>17</bitWidth>
            </field>
            <field>
              <name>BRSUM</name>
              <bitOffset>18</bitOffset>
              <bitWidth>1</bitWidth>
            </field>
            <field>
              <name>BRDUM</name>
              <bitOffset>19</bitOffset>
              <bitWidth>1</bitWidth>
            </field>
            <field>
              <name>BRC</name>
              <bitOffset>20</bitOffset>
              <bitWidth>12</bitWidth>
            </field>
          </fields>
        </register>
        <register>
          <name>CSAR0</name>
          <addressOffset>0x2d8</addressOffset>
          <size>0x20</size>
          <fields>
            <field>
              <name>SAR</name>
              <bitOffset>0</bitOffset>
              <bitWidth>32</bitWidth>
            </field>
          </fields>
        </register>
        <register>
          <name>CDAR0</name>
          <addressOffset>0x2dc</addressOffset>
          <size>0x20</size>
          <fields>
            <field>
              <name>DAR</name>
              <bitOffset>0</bitOffset>
              <bitWidth>32</bitWidth>
            </field>
          </fields>
        </register>
        <register>
          <name>CBRUR0</name>
          <addressOffset>0x2e0</addressOffset>
          <size>0x20</size>
          <fields>
            <field>
              <name>SUV</name>
              <bitOffset>0</bitOffset>
              <bitWidth>16</bitWidth>
            </field>
            <field>
              <name>DUV</name>
              <bitOffset>16</bitOffset>
              <bitWidth>16</bitWidth>
            </field>
          </fields>
        </register>
        <register>
          <name>CLAR0</name>
          <addressOffset>0x2e4</addressOffset>
          <size>0x20</size>
          <fields>
            <field>
              <name>LAR</name>
              <bitOffset>0</bitOffset>
              <bitWidth>32</bitWidth>
            </field>
          </fields>
        </register>
        <register>
          <name>CTBR0</name>
          <addressOffset>0x2e8</addressOffset>
          <size>0x20</size>
          <fields>
            <field>
              <name>TSEL</name>
              <bitOffset>0</bitOffset>
              <bitWidth>8</bitWidth>
            </field>
            <field>
              <name>SBUS</name>
              <bitOffset>16</bitOffset>
              <bitWidth>1</bitWidth>
            </field>
            <field>
              <name>DBUS</name>
              <bitOffset>17</bitOffset>
              <bitWidth>1</bitWidth>
            </field>
          </fields>
        </register>
        <register>
          <name>CMAR0</name>
          <addressOffset>0x2f0</addressOffset>
          <size>0x20</size>
          <fields>
            <field>
              <name>MAR</name>
              <bitOffset>0</bitOffset>
              <bitWidth>32</bitWidth>
            </field>
          </fields>
        </register>
        <register>
          <name>CMDR0</name>
          <addressOffset>0x2f4</addressOffset>
          <size>0x20</size>
          <fields>
            <field>
              <name>MDR</name>
              <bitOffset>0</bitOffset>
              <bitWidth>32</bitWidth>
            </field>
          </fields>
        </register>
        <register>
          <name>CISR1</name>
          <addressOffset>0x300</addressOffset>
          <size>0x20</size>
          <fields>
            <field>
              <name>TEIF</name>
              <bitOffset>0</bitOffset>
              <bitWidth>1</bitWidth>
            </field>
            <field>
              <name>CTCIF</name>
              <bitOffset>1</bitOffset>
              <bitWidth>1</bitWidth>
            </field>
            <field>
              <name>BRTIF</name>
              <bitOffset>2</bitOffset>
              <bitWidth>1</bitWidth>
            </field>
            <field>
              <name>BTIF</name>
              <bitOffset>3</bitOffset>
              <bitWidth>1</bitWidth>
            </field>
            <field>
              <name>TCIF</name>
              <bitOffset>4</bitOffset>
              <bitWidth>1</bitWidth>
            </field>
            <field>
              <name>CRQA</name>
              <bitOffset>16</bitOffset>
              <bitWidth>1</bitWidth>
            </field>
          </fields>
        </register>
        <register>
          <name>CIFCR1</name>
          <addressOffset>0x304</addressOffset>
          <size>0x20</size>
          <fields>
            <field>
              <name>CTEIF</name>
              <bitOffset>0</bitOffset>
              <bitWidth>1</bitWidth>
            </field>
            <field>
              <name>CCTCIF</name>
              <bitOffset>1</bitOffset>
              <bitWidth>1</bitWidth>
            </field>
            <field>
              <name>CBRTIF</name>
              <bitOffset>2</bitOffset>
              <bitWidth>1</bitWidth>
            </field>
            <field>
              <name>CBTIF</name>
              <bitOffset>3</bitOffset>
              <bitWidth>1</bitWidth>
            </field>
            <field>
              <name>CLTCIF</name>
              <bitOffset>4</bitOffset>
              <bitWidth>1</bitWidth>
            </field>
          </fields>
        </register>
        <register>
          <name>CESR1</name>
          <addressOffset>0x308</addressOffset>
          <size>0x20</size>
          <fields>
            <field>
              <name>TEA</name>
              <bitOffset>0</bitOffset>
              <bitWidth>7</bitWidth>
            </field>
            <field>
              <name>TED</name>
              <bitOffset>7</bitOffset>
              <bitWidth>1</bitWidth>
            </field>
            <field>
              <name>TELD</name>
              <bitOffset>8</bitOffset>
              <bitWidth>1</bitWidth>
            </field>
            <field>
              <name>TEMD</name>
              <bitOffset>9</bitOffset>
              <bitWidth>1</bitWidth>
            </field>
            <field>
              <name>ASE</name>
              <bitOffset>10</bitOffset>
              <bitWidth>1</bitWidth>
            </field>
            <field>
              <name>BSE</name>
              <bitOffset>11</bitOffset>
              <bitWidth>1</bitWidth>
            </field>
          </fields>
        </register>
        <register>
          <name>CCR1</name>
          <addressOffset>0x30c</addressOffset>
          <size>0x20</size>
          <fields>
            <field>
              <name>EN</name>
              <bitOffset>0</bitOffset>
              <bitWidth>1</bitWidth>
            </field>
            <field>
              <name>TEIE</name>
              <bitOffset>1</bitOffset>
              <bitWidth>1</bitWidth>
            </field>
            <field>
              <name>CTCIE</name>
              <bitOffset>2</bitOffset>
              <bitWidth>1</bitWidth>
            </field>
            <field>
              <name>BRTIE</name>
              <bitOffset>3</bitOffset>
              <bitWidth>1</bitWidth>
            </field>
            <field>
              <name>BTIE</name>
              <bitOffset>4</bitOffset>
              <bitWidth>1</bitWidth>
            </field>
            <field>
              <name>TCIE</name>
              <bitOffset>5</bitOffset>
              <bitWidth>1</bitWidth>
            </field>
            <field>
              <name>PL</name>
              <bitOffset>6</bitOffset>
              <bitWidth>2</bitWidth>
            </field>
            <field>
              <name>BEX</name>
              <bitOffset>12</bitOffset>
              <bitWidth>1</bitWidth>
            </field>
            <field>
              <name>HEX</name>
              <bitOffset>13</bitOffset>
              <bitWidth>1</bitWidth>
            </field>
            <field>
              <name>WEX</name>
              <bitOffset>14</bitOffset>
              <bitWidth>1</bitWidth>
            </field>
            <field>
              <name>SWRQ</name>
              <bitOffset>16</bitOffset>
              <bitWidth>1</bitWidth>
            </field>
          </fields>
        </register>
        <register>
          <name>CTCR1</name>
          <addressOffset>0x310</addressOffset>
          <size>0x20</size>
          <fields>
            <field>
              <name>SINC</name>
              <bitOffset>0</bitOffset>
              <bitWidth>2</bitWidth>
            </field>
            <field>
              <name>DINC</name>
              <bitOffset>2</bitOffset>
              <bitWidth>2</bitWidth>
            </field>
            <field>
              <name>SSIZE</name>
              <bitOffset>4</bitOffset>
              <bitWidth>2</bitWidth>
            </field>
            <field>
              <name>DSIZE</name>
              <bitOffset>6</bitOffset>
              <bitWidth>2</bitWidth>
            </field>
            <field>
              <name>SINCOS</name>
              <bitOffset>8</bitOffset>
              <bitWidth>2</bitWidth>
            </field>
            <field>
              <name>DINCOS</name>
              <bitOffset>10</bitOffset>
              <bitWidth>2</bitWidth>
            </field>
            <field>
              <name>SBURST</name>
              <bitOffset>12</bitOffset>
              <bitWidth>3</bitWidth>
            </field>
            <field>
              <name>DBURST</name>
              <bitOffset>15</bitOffset>
              <bitWidth>3</bitWidth>
            </field>
            <field>
              <name>TLEN</name>
              <bitOffset>18</bitOffset>
              <bitWidth>7</bitWidth>
            </field>
            <field>
              <name>PKE</name>
              <bitOffset>25</bitOffset>
              <bitWidth>1</bitWidth>
            </field>
            <field>
              <name>PAM</name>
              <bitOffset>26</bitOffset>
              <bitWidth>2</bitWidth>
            </field>
            <field>
              <name>TRGM</name>
              <bitOffset>28</bitOffset>
              <bitWidth>2</bitWidth>
            </field>
            <field>
              <name>SWRM</name>
              <bitOffset>30</bitOffset>
              <bitWidth>1</bitWidth>
            </field>
            <field>
              <name>BWM</name>
              <bitOffset>31</bitOffset>
              <bitWidth>1</bitWidth>
            </field>
          </fields>
        </register>
        <register>
          <name>CBNDTR1</name>
          <addressOffset>0x314</addressOffset>
          <size>0x20</size>
          <fields>
            <field>
              <name>BNDT</name>
              <bitOffset>0</bitOffset>
              <bitWidth>17</bitWidth>
            </field>
            <field>
              <name>BRSUM</name>
              <bitOffset>18</bitOffset>
              <bitWidth>1</bitWidth>
            </field>
            <field>
              <name>BRDUM</name>
              <bitOffset>19</bitOffset>
              <bitWidth>1</bitWidth>
            </field>
            <field>
              <name>BRC</name>
              <bitOffset>20</bitOffset>
              <bitWidth>12</bitWidth>
            </field>
          </fields>
        </register>
        <register>
          <name>CSAR1</name>
          <addressOffset>0x318</addressOffset>
          <size>0x20</size>
          <fields>
            <field>
              <name>SAR</name>
              <bitOffset>0</bitOffset>
              <bitWidth>32</bitWidth>
            </field>
          </fields>
        </register>
        <register>
          <name>CDAR1</name>
          <addressOffset>0x31c</addressOffset>
          <size>0x20</size>
          <fields>
            <field>
              <name>DAR</name>
              <bitOffset>0</bitOffset>
              <bitWidth>32</bitWidth>
            </field>
          </fields>
        </register>
        <register>
          <name>CBRUR1</name>
          <addressOffset>0x320</addressOffset>
          <size>0x20</size>
          <fields>
            <field>
              <name>SUV</name>
              <bitOffset>0</bitOffset>
              <bitWidth>16</bitWidth>
            </field>
            <field>
              <name>DUV</name>
              <bitOffset>16</bitOffset>
              <bitWidth>16</bitWidth>
            </field>
          </fields>
        </register>
        <register>
          <name>CLAR1</name>
          <addressOffset>0x324</addressOffset>
          <size>0x20</size>
          <fields>
            <field>
              <name>LAR</name>
              <bitOffset>0</bitOffset>
              <bitWidth>32</bitWidth>
            </field>
          </fields>
        </register>
        <register>
          <name>CTBR1</name>
          <addressOffset>0x328</addressOffset>
          <size>0x20</size>
          <fields>
            <field>
              <name>TSEL</name>
              <bitOffset>0</bitOffset>
              <bitWidth>8</bitWidth>
            </field>
            <field>
              <name>SBUS</name>
              <bitOffset>16</bitOffset>
              <bitWidth>1</bitWidth>
            </field>
            <field>
              <name>DBUS</name>
              <bitOffset>17</bitOffset>
              <bitWidth>1</bitWidth>
            </field>
          </fields>
        </register>
        <register>
          <name>CMAR1</name>
          <addressOffset>0x330</addressOffset>
          <size>0x20</size>
          <fields>
            <field>
              <name>MAR</name>
              <bitOffset>0</bitOffset>
              <bitWidth>32</bitWidth>
            </field>
          </fields>
        </register>
        <register>
          <name>CMDR1</name>
          <addressOffset>0x334</addressOffset>
          <size>0x20</size>
          <fields>
            <field>
              <name>MDR</name>
              <bitOffset>0</bitOffset>
              <bitWidth>32</bitWidth>
            </field>
          </fields>
        </register>
        <register>
          <name>CISR2</name>
          <addressOffset>0x340</addressOffset>
          <size>0x20</size>
          <fields>
            <field>
              <name>TEIF</name>
              <bitOffset>0</bitOffset>
              <bitWidth>1</bitWidth>
            </field>
            <field>
              <name>CTCIF</name>
              <bitOffset>1</bitOffset>
              <bitWidth>1</bitWidth>
            </field>
            <field>
              <name>BRTIF</name>
              <bitOffset>2</bitOffset>
              <bitWidth>1</bitWidth>
            </field>
            <field>
              <name>BTIF</name>
              <bitOffset>3</bitOffset>
              <bitWidth>1</bitWidth>
            </field>
            <field>
              <name>TCIF</name>
              <bitOffset>4</bitOffset>
              <bitWidth>1</bitWidth>
            </field>
            <field>
              <name>CRQA</name>
              <bitOffset>16</bitOffset>
              <bitWidth>1</bitWidth>
            </field>
          </fields>
        </register>
        <register>
          <name>CIFCR2</name>
          <addressOffset>0x344</addressOffset>
          <size>0x20</size>
          <fields>
            <field>
              <name>CTEIF</name>
              <bitOffset>0</bitOffset>
              <bitWidth>1</bitWidth>
            </field>
            <field>
              <name>CCTCIF</name>
              <bitOffset>1</bitOffset>
              <bitWidth>1</bitWidth>
            </field>
            <field>
              <name>CBRTIF</name>
              <bitOffset>2</bitOffset>
              <bitWidth>1</bitWidth>
            </field>
            <field>
              <name>CBTIF</name>
              <bitOffset>3</bitOffset>
              <bitWidth>1</bitWidth>
            </field>
            <field>
              <name>CLTCIF</name>
              <bitOffset>4</bitOffset>
              <bitWidth>1</bitWidth>
            </field>
          </fields>
        </register>
        <register>
          <name>CESR2</name>
          <addressOffset>0x348</addressOffset>
          <size>0x20</size>
          <fields>
            <field>
              <name>TEA</name>
              <bitOffset>0</bitOffset>
              <bitWidth>7</bitWidth>
            </field>
            <field>
              <name>TED</name>
              <bitOffset>7</bitOffset>
              <bitWidth>1</bitWidth>
            </field>
            <field>
              <name>TELD</name>
              <bitOffset>8</bitOffset>
              <bitWidth>1</bitWidth>
            </field>
            <field>
              <name>TEMD</name>
              <bitOffset>9</bitOffset>
              <bitWidth>1</bitWidth>
            </field>
            <field>
              <name>ASE</name>
              <bitOffset>10</bitOffset>
              <bitWidth>1</bitWidth>
            </field>
            <field>
              <name>BSE</name>
              <bitOffset>11</bitOffset>
              <bitWidth>1</bitWidth>
            </field>
          </fields>
        </register>
        <register>
          <name>CCR2</name>
          <addressOffset>0x34c</addressOffset>
          <size>0x20</size>
          <fields>
            <field>
              <name>EN</name>
              <bitOffset>0</bitOffset>
              <bitWidth>1</bitWidth>
            </field>
            <field>
              <name>TEIE</name>
              <bitOffset>1</bitOffset>
              <bitWidth>1</bitWidth>
            </field>
            <field>
              <name>CTCIE</name>
              <bitOffset>2</bitOffset>
              <bitWidth>1</bitWidth>
            </field>
            <field>
              <name>BRTIE</name>
              <bitOffset>3</bitOffset>
              <bitWidth>1</bitWidth>
            </field>
            <field>
              <name>BTIE</name>
              <bitOffset>4</bitOffset>
              <bitWidth>1</bitWidth>
            </field>
            <field>
              <name>TCIE</name>
              <bitOffset>5</bitOffset>
              <bitWidth>1</bitWidth>
            </field>
            <field>
              <name>PL</name>
              <bitOffset>6</bitOffset>
              <bitWidth>2</bitWidth>
            </field>
            <field>
              <name>BEX</name>
              <bitOffset>12</bitOffset>
              <bitWidth>1</bitWidth>
            </field>
            <field>
              <name>HEX</name>
              <bitOffset>13</bitOffset>
              <bitWidth>1</bitWidth>
            </field>
            <field>
              <name>WEX</name>
              <bitOffset>14</bitOffset>
              <bitWidth>1</bitWidth>
            </field>
            <field>
              <name>SWRQ</name>
              <bitOffset>16</bitOffset>
              <bitWidth>1</bitWidth>
            </field>
          </fields>
        </register>
        <register>
          <name>CTCR2</name>
          <addressOffset>0x350</addressOffset>
          <size>0x20</size>
          <fields>
            <field>
              <name>SINC</name>
              <bitOffset>0</bitOffset>
              <bitWidth>2</bitWidth>
            </field>
            <field>
              <name>DINC</name>
              <bitOffset>2</bitOffset>
              <bitWidth>2</bitWidth>
            </field>
            <field>
              <name>SSIZE</name>
              <bitOffset>4</bitOffset>
              <bitWidth>2</bitWidth>
            </field>
            <field>
              <name>DSIZE</name>
              <bitOffset>6</bitOffset>
              <bitWidth>2</bitWidth>
            </field>
            <field>
              <name>SINCOS</name>
              <bitOffset>8</bitOffset>
              <bitWidth>2</bitWidth>
            </field>
            <field>
              <name>DINCOS</name>
              <bitOffset>10</bitOffset>
              <bitWidth>2</bitWidth>
            </field>
            <field>
              <name>SBURST</name>
              <bitOffset>12</bitOffset>
              <bitWidth>3</bitWidth>
            </field>
            <field>
              <name>DBURST</name>
              <bitOffset>15</bitOffset>
              <bitWidth>3</bitWidth>
            </field>
            <field>
              <name>TLEN</name>
              <bitOffset>18</bitOffset>
              <bitWidth>7</bitWidth>
            </field>
            <field>
              <name>PKE</name>
              <bitOffset>25</bitOffset>
              <bitWidth>1</bitWidth>
            </field>
            <field>
              <name>PAM</name>
              <bitOffset>26</bitOffset>
              <bitWidth>2</bitWidth>
            </field>
            <field>
              <name>TRGM</name>
              <bitOffset>28</bitOffset>
              <bitWidth>2</bitWidth>
            </field>
            <field>
              <name>SWRM</name>
              <bitOffset>30</bitOffset>
              <bitWidth>1</bitWidth>
            </field>
            <field>
              <name>BWM</name>
              <bitOffset>31</bitOffset>
              <bitWidth>1</bitWidth>
            </field>
          </fields>
        </register>
        <register>
          <name>CBNDTR2</name>
          <addressOffset>0x354</addressOffset>
          <size>0x20</size>
          <fields>
            <field>
              <name>BNDT</name>
              <bitOffset>0</bitOffset>
              <bitWidth>17</bitWidth>
            </field>
            <field>
              <name>BRSUM</name>
              <bitOffset>18</bitOffset>
              <bitWidth>1</bitWidth>
            </field>
            <field>
              <name>BRDUM</name>
              <bitOffset>19</bitOffset>
              <bitWidth>1</bitWidth>
            </field>
            <field>
              <name>BRC</name>
              <bitOffset>20</bitOffset>
              <bitWidth>12</bitWidth>
            </field>
          </fields>
        </register>
        <register>
          <name>CSAR2</name>
          <addressOffset>0x358</addressOffset>
          <size>0x20</size>
          <fields>
            <field>
              <name>SAR</name>
              <bitOffset>0</bitOffset>
              <bitWidth>32</bitWidth>
            </field>
          </fields>
        </register>
        <register>
          <name>CDAR2</name>
          <addressOffset>0x35c</addressOffset>
          <size>0x20</size>
          <fields>
            <field>
              <name>DAR</name>
              <bitOffset>0</bitOffset>
              <bitWidth>32</bitWidth>
            </field>
          </fields>
        </register>
        <register>
          <name>CBRUR2</name>
          <addressOffset>0x360</addressOffset>
          <size>0x20</size>
          <fields>
            <field>
              <name>SUV</name>
              <bitOffset>0</bitOffset>
              <bitWidth>16</bitWidth>
            </field>
            <field>
              <name>DUV</name>
              <bitOffset>16</bitOffset>
              <bitWidth>16</bitWidth>
            </field>
          </fields>
        </register>
        <register>
          <name>CLAR2</name>
          <addressOffset>0x364</addressOffset>
          <size>0x20</size>
          <fields>
            <field>
              <name>LAR</name>
              <bitOffset>0</bitOffset>
              <bitWidth>32</bitWidth>
            </field>
          </fields>
        </register>
        <register>
          <name>CTBR2</name>
          <addressOffset>0x368</addressOffset>
          <size>0x20</size>
          <fields>
            <field>
              <name>TSEL</name>
              <bitOffset>0</bitOffset>
              <bitWidth>8</bitWidth>
            </field>
            <field>
              <name>SBUS</name>
              <bitOffset>16</bitOffset>
              <bitWidth>1</bitWidth>
            </field>
            <field>
              <name>DBUS</name>
              <bitOffset>17</bitOffset>
              <bitWidth>1</bitWidth>
            </field>
          </fields>
        </register>
        <register>
          <name>CMAR2</name>
          <addressOffset>0x370</addressOffset>
          <size>0x20</size>
          <fields>
            <field>
              <name>MAR</name>
              <bitOffset>0</bitOffset>
              <bitWidth>32</bitWidth>
            </field>
          </fields>
        </register>
        <register>
          <name>CMDR2</name>
          <addressOffset>0x374</addressOffset>
          <size>0x20</size>
          <fields>
            <field>
              <name>MDR</name>
              <bitOffset>0</bitOffset>
              <bitWidth>32</bitWidth>
            </field>
          </fields>
        </register>
        <register>
          <name>CISR3</name>
          <addressOffset>0x380</addressOffset>
          <size>0x20</size>
          <fields>
            <field>
              <name>TEIF</name>
              <bitOffset>0</bitOffset>
              <bitWidth>1</bitWidth>
            </field>
            <field>
              <name>CTCIF</name>
              <bitOffset>1</bitOffset>
              <bitWidth>1</bitWidth>
            </field>
            <field>
              <name>BRTIF</name>
              <bitOffset>2</bitOffset>
              <bitWidth>1</bitWidth>
            </field>
            <field>
              <name>BTIF</name>
              <bitOffset>3</bitOffset>
              <bitWidth>1</bitWidth>
            </field>
            <field>
              <name>TCIF</name>
              <bitOffset>4</bitOffset>
              <bitWidth>1</bitWidth>
            </field>
            <field>
              <name>CRQA</name>
              <bitOffset>16</bitOffset>
              <bitWidth>1</bitWidth>
            </field>
          </fields>
        </register>
        <register>
          <name>CIFCR3</name>
          <addressOffset>0x384</addressOffset>
          <size>0x20</size>
          <fields>
            <field>
              <name>CTEIF</name>
              <bitOffset>0</bitOffset>
              <bitWidth>1</bitWidth>
            </field>
            <field>
              <name>CCTCIF</name>
              <bitOffset>1</bitOffset>
              <bitWidth>1</bitWidth>
            </field>
            <field>
              <name>CBRTIF</name>
              <bitOffset>2</bitOffset>
              <bitWidth>1</bitWidth>
            </field>
            <field>
              <name>CBTIF</name>
              <bitOffset>3</bitOffset>
              <bitWidth>1</bitWidth>
            </field>
            <field>
              <name>CLTCIF</name>
              <bitOffset>4</bitOffset>
              <bitWidth>1</bitWidth>
            </field>
          </fields>
        </register>
        <register>
          <name>CESR3</name>
          <addressOffset>0x388</addressOffset>
          <size>0x20</size>
          <fields>
            <field>
              <name>TEA</name>
              <bitOffset>0</bitOffset>
              <bitWidth>7</bitWidth>
            </field>
            <field>
              <name>TED</name>
              <bitOffset>7</bitOffset>
              <bitWidth>1</bitWidth>
            </field>
            <field>
              <name>TELD</name>
              <bitOffset>8</bitOffset>
              <bitWidth>1</bitWidth>
            </field>
            <field>
              <name>TEMD</name>
              <bitOffset>9</bitOffset>
              <bitWidth>1</bitWidth>
            </field>
            <field>
              <name>ASE</name>
              <bitOffset>10</bitOffset>
              <bitWidth>1</bitWidth>
            </field>
            <field>
              <name>BSE</name>
              <bitOffset>11</bitOffset>
              <bitWidth>1</bitWidth>
            </field>
          </fields>
        </register>
        <register>
          <name>CCR3</name>
          <addressOffset>0x38c</addressOffset>
          <size>0x20</size>
          <fields>
            <field>
              <name>EN</name>
              <bitOffset>0</bitOffset>
              <bitWidth>1</bitWidth>
            </field>
            <field>
              <name>TEIE</name>
              <bitOffset>1</bitOffset>
              <bitWidth>1</bitWidth>
            </field>
            <field>
              <name>CTCIE</name>
              <bitOffset>2</bitOffset>
              <bitWidth>1</bitWidth>
            </field>
            <field>
              <name>BRTIE</name>
              <bitOffset>3</bitOffset>
              <bitWidth>1</bitWidth>
            </field>
            <field>
              <name>BTIE</name>
              <bitOffset>4</bitOffset>
              <bitWidth>1</bitWidth>
            </field>
            <field>
              <name>TCIE</name>
              <bitOffset>5</bitOffset>
              <bitWidth>1</bitWidth>
            </field>
            <field>
              <name>PL</name>
              <bitOffset>6</bitOffset>
              <bitWidth>2</bitWidth>
            </field>
            <field>
              <name>BEX</name>
              <bitOffset>12</bitOffset>
              <bitWidth>1</bitWidth>
            </field>
            <field>
              <name>HEX</name>
              <bitOffset>13</bitOffset>
              <bitWidth>1</bitWidth>
            </field>
            <field>
              <name>WEX</name>
              <bitOffset>14</bitOffset>
              <bitWidth>1</bitWidth>
            </field>
            <field>
              <name>SWRQ</name>
              <bitOffset>16</bitOffset>
              <bitWidth>1</bitWidth>
            </field>
          </fields>
        </register>
        <register>
          <name>CTCR3</name>
          <addressOffset>0x390</addressOffset>
          <size>0x20</size>
          <fields>
            <field>
              <name>SINC</name>
              <bitOffset>0</bitOffset>
              <bitWidth>2</bitWidth>
            </field>
            <field>
              <name>DINC</name>
              <bitOffset>2</bitOffset>
              <bitWidth>2</bitWidth>
            </field>
            <field>
              <name>SSIZE</name>
              <bitOffset>4</bitOffset>
              <bitWidth>2</bitWidth>
            </field>
            <field>
              <name>DSIZE</name>
              <bitOffset>6</bitOffset>
              <bitWidth>2</bitWidth>
            </field>
            <field>
              <name>SINCOS</name>
              <bitOffset>8</bitOffset>
              <bitWidth>2</bitWidth>
            </field>
            <field>
              <name>DINCOS</name>
              <bitOffset>10</bitOffset>
              <bitWidth>2</bitWidth>
            </field>
            <field>
              <name>SBURST</name>
              <bitOffset>12</bitOffset>
              <bitWidth>3</bitWidth>
            </field>
            <field>
              <name>DBURST</name>
              <bitOffset>15</bitOffset>
              <bitWidth>3</bitWidth>
            </field>
            <field>
              <name>TLEN</name>
              <bitOffset>18</bitOffset>
              <bitWidth>7</bitWidth>
            </field>
            <field>
              <name>PKE</name>
              <bitOffset>25</bitOffset>
              <bitWidth>1</bitWidth>
            </field>
            <field>
              <name>PAM</name>
              <bitOffset>26</bitOffset>
              <bitWidth>2</bitWidth>
            </field>
            <field>
              <name>TRGM</name>
              <bitOffset>28</bitOffset>
              <bitWidth>2</bitWidth>
            </field>
            <field>
              <name>SWRM</name>
              <bitOffset>30</bitOffset>
              <bitWidth>1</bitWidth>
            </field>
            <field>
              <name>BWM</name>
              <bitOffset>31</bitOffset>
              <bitWidth>1</bitWidth>
            </field>
          </fields>
        </register>
        <register>
          <name>CBNDTR3</name>
          <addressOffset>0x394</addressOffset>
          <size>0x20</size>
          <fields>
            <field>
              <name>BNDT</name>
              <bitOffset>0</bitOffset>
              <bitWidth>17</bitWidth>
            </field>
            <field>
              <name>BRSUM</name>
              <bitOffset>18</bitOffset>
              <bitWidth>1</bitWidth>
            </field>
            <field>
              <name>BRDUM</name>
              <bitOffset>19</bitOffset>
              <bitWidth>1</bitWidth>
            </field>
            <field>
              <name>BRC</name>
              <bitOffset>20</bitOffset>
              <bitWidth>12</bitWidth>
            </field>
          </fields>
        </register>
        <register>
          <name>CSAR3</name>
          <addressOffset>0x398</addressOffset>
          <size>0x20</size>
          <fields>
            <field>
              <name>SAR</name>
              <bitOffset>0</bitOffset>
              <bitWidth>32</bitWidth>
            </field>
          </fields>
        </register>
        <register>
          <name>CDAR3</name>
          <addressOffset>0x39c</addressOffset>
          <size>0x20</size>
          <fields>
            <field>
              <name>DAR</name>
              <bitOffset>0</bitOffset>
              <bitWidth>32</bitWidth>
            </field>
          </fields>
        </register>
        <register>
          <name>CBRUR3</name>
          <addressOffset>0x3a0</addressOffset>
          <size>0x20</size>
          <fields>
            <field>
              <name>SUV</name>
              <bitOffset>0</bitOffset>
              <bitWidth>16</bitWidth>
            </field>
            <field>
              <name>DUV</name>
              <bitOffset>16</bitOffset>
              <bitWidth>16</bitWidth>
            </field>
          </fields>
        </register>
        <register>
          <name>CLAR3</name>
          <addressOffset>0x3a4</addressOffset>
          <size>0x20</size>
          <fields>
            <field>
              <name>LAR</name>
              <bitOffset>0</bitOffset>
              <bitWidth>32</bitWidth>
            </field>
          </fields>
        </register>
        <register>
          <name>CTBR3</name>
          <addressOffset>0x3a8</addressOffset>
          <size>0x20</size>
          <fields>
            <field>
              <name>TSEL</name>
              <bitOffset>0</bitOffset>
              <bitWidth>8</bitWidth>
            </field>
            <field>
              <name>SBUS</name>
              <bitOffset>16</bitOffset>
              <bitWidth>1</bitWidth>
            </field>
            <field>
              <name>DBUS</name>
              <bitOffset>17</bitOffset>
              <bitWidth>1</bitWidth>
            </field>
          </fields>
        </register>
        <register>
          <name>CMAR3</name>
          <addressOffset>0x3b0</addressOffset>
          <size>0x20</size>
          <fields>
            <field>
              <name>MAR</name>
              <bitOffset>0</bitOffset>
              <bitWidth>32</bitWidth>
            </field>
          </fields>
        </register>
        <register>
          <name>CMDR3</name>
          <addressOffset>0x3b4</addressOffset>
          <size>0x20</size>
          <fields>
            <field>
              <name>MDR</name>
              <bitOffset>0</bitOffset>
              <bitWidth>32</bitWidth>
            </field>
          </fields>
        </register>
        <register>
          <name>CISR4</name>
          <addressOffset>0x3c0</addressOffset>
          <size>0x20</size>
          <fields>
            <field>
              <name>TEIF</name>
              <bitOffset>0</bitOffset>
              <bitWidth>1</bitWidth>
            </field>
            <field>
              <name>CTCIF</name>
              <bitOffset>1</bitOffset>
              <bitWidth>1</bitWidth>
            </field>
            <field>
              <name>BRTIF</name>
              <bitOffset>2</bitOffset>
              <bitWidth>1</bitWidth>
            </field>
            <field>
              <name>BTIF</name>
              <bitOffset>3</bitOffset>
              <bitWidth>1</bitWidth>
            </field>
            <field>
              <name>TCIF</name>
              <bitOffset>4</bitOffset>
              <bitWidth>1</bitWidth>
            </field>
            <field>
              <name>CRQA</name>
              <bitOffset>16</bitOffset>
              <bitWidth>1</bitWidth>
            </field>
          </fields>
        </register>
        <register>
          <name>CIFCR4</name>
          <addressOffset>0x3c4</addressOffset>
          <size>0x20</size>
          <fields>
            <field>
              <name>CTEIF</name>
              <bitOffset>0</bitOffset>
              <bitWidth>1</bitWidth>
            </field>
            <field>
              <name>CCTCIF</name>
              <bitOffset>1</bitOffset>
              <bitWidth>1</bitWidth>
            </field>
            <field>
              <name>CBRTIF</name>
              <bitOffset>2</bitOffset>
              <bitWidth>1</bitWidth>
            </field>
            <field>
              <name>CBTIF</name>
              <bitOffset>3</bitOffset>
              <bitWidth>1</bitWidth>
            </field>
            <field>
              <name>CLTCIF</name>
              <bitOffset>4</bitOffset>
              <bitWidth>1</bitWidth>
            </field>
          </fields>
        </register>
        <register>
          <name>CESR4</name>
          <addressOffset>0x3c8</addressOffset>
          <size>0x20</size>
          <fields>
            <field>
              <name>TEA</name>
              <bitOffset>0</bitOffset>
              <bitWidth>7</bitWidth>
            </field>
            <field>
              <name>TED</name>
              <bitOffset>7</bitOffset>
              <bitWidth>1</bitWidth>
            </field>
            <field>
              <name>TELD</name>
              <bitOffset>8</bitOffset>
              <bitWidth>1</bitWidth>
            </field>
            <field>
              <name>TEMD</name>
              <bitOffset>9</bitOffset>
              <bitWidth>1</bitWidth>
            </field>
            <field>
              <name>ASE</name>
              <bitOffset>10</bitOffset>
              <bitWidth>1</bitWidth>
            </field>
            <field>
              <name>BSE</name>
              <bitOffset>11</bitOffset>
              <bitWidth>1</bitWidth>
            </field>
          </fields>
        </register>
        <register>
          <name>CCR4</name>
          <addressOffset>0x3cc</addressOffset>
          <size>0x20</size>
          <fields>
            <field>
              <name>EN</name>
              <bitOffset>0</bitOffset>
              <bitWidth>1</bitWidth>
            </field>
            <field>
              <name>TEIE</name>
              <bitOffset>1</bitOffset>
              <bitWidth>1</bitWidth>
            </field>
            <field>
              <name>CTCIE</name>
              <bitOffset>2</bitOffset>
              <bitWidth>1</bitWidth>
            </field>
            <field>
              <name>BRTIE</name>
              <bitOffset>3</bitOffset>
              <bitWidth>1</bitWidth>
            </field>
            <field>
              <name>BTIE</name>
              <bitOffset>4</bitOffset>
              <bitWidth>1</bitWidth>
            </field>
            <field>
              <name>TCIE</name>
              <bitOffset>5</bitOffset>
              <bitWidth>1</bitWidth>
            </field>
            <field>
              <name>PL</name>
              <bitOffset>6</bitOffset>
              <bitWidth>2</bitWidth>
            </field>
            <field>
              <name>BEX</name>
              <bitOffset>12</bitOffset>
              <bitWidth>1</bitWidth>
            </field>
            <field>
              <name>HEX</name>
              <bitOffset>13</bitOffset>
              <bitWidth>1</bitWidth>
            </field>
            <field>
              <name>WEX</name>
              <bitOffset>14</bitOffset>
              <bitWidth>1</bitWidth>
            </field>
            <field>
              <name>SWRQ</name>
              <bitOffset>16</bitOffset>
              <bitWidth>1</bitWidth>
            </field>
          </fields>
        </register>
        <register>
          <name>CTCR4</name>
          <addressOffset>0x3d0</addressOffset>
          <size>0x20</size>
          <fields>
            <field>
              <name>SINC</name>
              <bitOffset>0</bitOffset>
              <bitWidth>2</bitWidth>
            </field>
            <field>
              <name>DINC</name>
              <bitOffset>2</bitOffset>
              <bitWidth>2</bitWidth>
            </field>
            <field>
              <name>SSIZE</name>
              <bitOffset>4</bitOffset>
              <bitWidth>2</bitWidth>
            </field>
            <field>
              <name>DSIZE</name>
              <bitOffset>6</bitOffset>
              <bitWidth>2</bitWidth>
            </field>
            <field>
              <name>SINCOS</name>
              <bitOffset>8</bitOffset>
              <bitWidth>2</bitWidth>
            </field>
            <field>
              <name>DINCOS</name>
              <bitOffset>10</bitOffset>
              <bitWidth>2</bitWidth>
            </field>
            <field>
              <name>SBURST</name>
              <bitOffset>12</bitOffset>
              <bitWidth>3</bitWidth>
            </field>
            <field>
              <name>DBURST</name>
              <bitOffset>15</bitOffset>
              <bitWidth>3</bitWidth>
            </field>
            <field>
              <name>TLEN</name>
              <bitOffset>18</bitOffset>
              <bitWidth>7</bitWidth>
            </field>
            <field>
              <name>PKE</name>
              <bitOffset>25</bitOffset>
              <bitWidth>1</bitWidth>
            </field>
            <field>
              <name>PAM</name>
              <bitOffset>26</bitOffset>
              <bitWidth>2</bitWidth>
            </field>
            <field>
              <name>TRGM</name>
              <bitOffset>28</bitOffset>
              <bitWidth>2</bitWidth>
            </field>
            <field>
              <name>SWRM</name>
              <bitOffset>30</bitOffset>
              <bitWidth>1</bitWidth>
            </field>
            <field>
              <name>BWM</name>
              <bitOffset>31</bitOffset>
              <bitWidth>1</bitWidth>
            </field>
          </fields>
        </register>
        <register>
          <name>CBNDTR4</name>
          <addressOffset>0x3d4</addressOffset>
          <size>0x20</size>
          <fields>
            <field>
              <name>BNDT</name>
              <bitOffset>0</bitOffset>
              <bitWidth>17</bitWidth>
            </field>
            <field>
              <name>BRSUM</name>
              <bitOffset>18</bitOffset>
              <bitWidth>1</bitWidth>
            </field>
            <field>
              <name>BRDUM</name>
              <bitOffset>19</bitOffset>
              <bitWidth>1</bitWidth>
            </field>
            <field>
              <name>BRC</name>
              <bitOffset>20</bitOffset>
              <bitWidth>12</bitWidth>
            </field>
          </fields>
        </register>
        <register>
          <name>CSAR4</name>
          <addressOffset>0x3d8</addressOffset>
          <size>0x20</size>
          <fields>
            <field>
              <name>SAR</name>
              <bitOffset>0</bitOffset>
              <bitWidth>32</bitWidth>
            </field>
          </fields>
        </register>
        <register>
          <name>CDAR4</name>
          <addressOffset>0x3dc</addressOffset>
          <size>0x20</size>
          <fields>
            <field>
              <name>DAR</name>
              <bitOffset>0</bitOffset>
              <bitWidth>32</bitWidth>
            </field>
          </fields>
        </register>
        <register>
          <name>CBRUR4</name>
          <addressOffset>0x3e0</addressOffset>
          <size>0x20</size>
          <fields>
            <field>
              <name>SUV</name>
              <bitOffset>0</bitOffset>
              <bitWidth>16</bitWidth>
            </field>
            <field>
              <name>DUV</name>
              <bitOffset>16</bitOffset>
              <bitWidth>16</bitWidth>
            </field>
          </fields>
        </register>
        <register>
          <name>CLAR4</name>
          <addressOffset>0x3e4</addressOffset>
          <size>0x20</size>
          <fields>
            <field>
              <name>LAR</name>
              <bitOffset>0</bitOffset>
              <bitWidth>32</bitWidth>
            </field>
          </fields>
        </register>
        <register>
          <name>CTBR4</name>
          <addressOffset>0x3e8</addressOffset>
          <size>0x20</size>
          <fields>
            <field>
              <name>TSEL</name>
              <bitOffset>0</bitOffset>
              <bitWidth>8</bitWidth>
            </field>
            <field>
              <name>SBUS</name>
              <bitOffset>16</bitOffset>
              <bitWidth>1</bitWidth>
            </field>
            <field>
              <name>DBUS</name>
              <bitOffset>17</bitOffset>
              <bitWidth>1</bitWidth>
            </field>
          </fields>
        </register>
        <register>
          <name>CMAR4</name>
          <addressOffset>0x3f0</addressOffset>
          <size>0x20</size>
          <fields>
            <field>
              <name>MAR</name>
              <bitOffset>0</bitOffset>
              <bitWidth>32</bitWidth>
            </field>
          </fields>
        </register>
        <register>
          <name>CMDR4</name>
          <addressOffset>0x3f4</addressOffset>
          <size>0x20</size>
          <fields>
            <field>
              <name>MDR</name>
              <bitOffset>0</bitOffset>
              <bitWidth>32</bitWidth>
            </field>
          </fields>
        </register>
        <register>
          <name>CISR5</name>
          <addressOffset>0x400</addressOffset>
          <size>0x20</size>
          <fields>
            <field>
              <name>TEIF</name>
              <bitOffset>0</bitOffset>
              <bitWidth>1</bitWidth>
            </field>
            <field>
              <name>CTCIF</name>
              <bitOffset>1</bitOffset>
              <bitWidth>1</bitWidth>
            </field>
            <field>
              <name>BRTIF</name>
              <bitOffset>2</bitOffset>
              <bitWidth>1</bitWidth>
            </field>
            <field>
              <name>BTIF</name>
              <bitOffset>3</bitOffset>
              <bitWidth>1</bitWidth>
            </field>
            <field>
              <name>TCIF</name>
              <bitOffset>4</bitOffset>
              <bitWidth>1</bitWidth>
            </field>
            <field>
              <name>CRQA</name>
              <bitOffset>16</bitOffset>
              <bitWidth>1</bitWidth>
            </field>
          </fields>
        </register>
        <register>
          <name>CIFCR5</name>
          <addressOffset>0x404</addressOffset>
          <size>0x20</size>
          <fields>
            <field>
              <name>CTEIF</name>
              <bitOffset>0</bitOffset>
              <bitWidth>1</bitWidth>
            </field>
            <field>
              <name>CCTCIF</name>
              <bitOffset>1</bitOffset>
              <bitWidth>1</bitWidth>
            </field>
            <field>
              <name>CBRTIF</name>
              <bitOffset>2</bitOffset>
              <bitWidth>1</bitWidth>
            </field>
            <field>
              <name>CBTIF</name>
              <bitOffset>3</bitOffset>
              <bitWidth>1</bitWidth>
            </field>
            <field>
              <name>CLTCIF</name>
              <bitOffset>4</bitOffset>
              <bitWidth>1</bitWidth>
            </field>
          </fields>
        </register>
        <register>
          <name>CESR5</name>
          <addressOffset>0x408</addressOffset>
          <size>0x20</size>
          <fields>
            <field>
              <name>TEA</name>
              <bitOffset>0</bitOffset>
              <bitWidth>7</bitWidth>
            </field>
            <field>
              <name>TED</name>
              <bitOffset>7</bitOffset>
              <bitWidth>1</bitWidth>
            </field>
            <field>
              <name>TELD</name>
              <bitOffset>8</bitOffset>
              <bitWidth>1</bitWidth>
            </field>
            <field>
              <name>TEMD</name>
              <bitOffset>9</bitOffset>
              <bitWidth>1</bitWidth>
            </field>
            <field>
              <name>ASE</name>
              <bitOffset>10</bitOffset>
              <bitWidth>1</bitWidth>
            </field>
            <field>
              <name>BSE</name>
              <bitOffset>11</bitOffset>
              <bitWidth>1</bitWidth>
            </field>
          </fields>
        </register>
        <register>
          <name>CCR5</name>
          <addressOffset>0x40c</addressOffset>
          <size>0x20</size>
          <fields>
            <field>
              <name>EN</name>
              <bitOffset>0</bitOffset>
              <bitWidth>1</bitWidth>
            </field>
            <field>
              <name>TEIE</name>
              <bitOffset>1</bitOffset>
              <bitWidth>1</bitWidth>
            </field>
            <field>
              <name>CTCIE</name>
              <bitOffset>2</bitOffset>
              <bitWidth>1</bitWidth>
            </field>
            <field>
              <name>BRTIE</name>
              <bitOffset>3</bitOffset>
              <bitWidth>1</bitWidth>
            </field>
            <field>
              <name>BTIE</name>
              <bitOffset>4</bitOffset>
              <bitWidth>1</bitWidth>
            </field>
            <field>
              <name>TCIE</name>
              <bitOffset>5</bitOffset>
              <bitWidth>1</bitWidth>
            </field>
            <field>
              <name>PL</name>
              <bitOffset>6</bitOffset>
              <bitWidth>2</bitWidth>
            </field>
            <field>
              <name>BEX</name>
              <bitOffset>12</bitOffset>
              <bitWidth>1</bitWidth>
            </field>
            <field>
              <name>HEX</name>
              <bitOffset>13</bitOffset>
              <bitWidth>1</bitWidth>
            </field>
            <field>
              <name>WEX</name>
              <bitOffset>14</bitOffset>
              <bitWidth>1</bitWidth>
            </field>
            <field>
              <name>SWRQ</name>
              <bitOffset>16</bitOffset>
              <bitWidth>1</bitWidth>
            </field>
          </fields>
        </register>
        <register>
          <name>CTCR5</name>
          <addressOffset>0x410</addressOffset>
          <size>0x20</size>
          <fields>
            <field>
              <name>SINC</name>
              <bitOffset>0</bitOffset>
              <bitWidth>2</bitWidth>
            </field>
            <field>
              <name>DINC</name>
              <bitOffset>2</bitOffset>
              <bitWidth>2</bitWidth>
            </field>
            <field>
              <name>SSIZE</name>
              <bitOffset>4</bitOffset>
              <bitWidth>2</bitWidth>
            </field>
            <field>
              <name>DSIZE</name>
              <bitOffset>6</bitOffset>
              <bitWidth>2</bitWidth>
            </field>
            <field>
              <name>SINCOS</name>
              <bitOffset>8</bitOffset>
              <bitWidth>2</bitWidth>
            </field>
            <field>
              <name>DINCOS</name>
              <bitOffset>10</bitOffset>
              <bitWidth>2</bitWidth>
            </field>
            <field>
              <name>SBURST</name>
              <bitOffset>12</bitOffset>
              <bitWidth>3</bitWidth>
            </field>
            <field>
              <name>DBURST</name>
              <bitOffset>15</bitOffset>
              <bitWidth>3</bitWidth>
            </field>
            <field>
              <name>TLEN</name>
              <bitOffset>18</bitOffset>
              <bitWidth>7</bitWidth>
            </field>
            <field>
              <name>PKE</name>
              <bitOffset>25</bitOffset>
              <bitWidth>1</bitWidth>
            </field>
            <field>
              <name>PAM</name>
              <bitOffset>26</bitOffset>
              <bitWidth>2</bitWidth>
            </field>
            <field>
              <name>TRGM</name>
              <bitOffset>28</bitOffset>
              <bitWidth>2</bitWidth>
            </field>
            <field>
              <name>SWRM</name>
              <bitOffset>30</bitOffset>
              <bitWidth>1</bitWidth>
            </field>
            <field>
              <name>BWM</name>
              <bitOffset>31</bitOffset>
              <bitWidth>1</bitWidth>
            </field>
          </fields>
        </register>
        <register>
          <name>CBNDTR5</name>
          <addressOffset>0x414</addressOffset>
          <size>0x20</size>
          <fields>
            <field>
              <name>BNDT</name>
              <bitOffset>0</bitOffset>
              <bitWidth>17</bitWidth>
            </field>
            <field>
              <name>BRSUM</name>
              <bitOffset>18</bitOffset>
              <bitWidth>1</bitWidth>
            </field>
            <field>
              <name>BRDUM</name>
              <bitOffset>19</bitOffset>
              <bitWidth>1</bitWidth>
            </field>
            <field>
              <name>BRC</name>
              <bitOffset>20</bitOffset>
              <bitWidth>12</bitWidth>
            </field>
          </fields>
        </register>
        <register>
          <name>CSAR5</name>
          <addressOffset>0x418</addressOffset>
          <size>0x20</size>
          <fields>
            <field>
              <name>SAR</name>
              <bitOffset>0</bitOffset>
              <bitWidth>32</bitWidth>
            </field>
          </fields>
        </register>
        <register>
          <name>CDAR5</name>
          <addressOffset>0x41c</addressOffset>
          <size>0x20</size>
          <fields>
            <field>
              <name>DAR</name>
              <bitOffset>0</bitOffset>
              <bitWidth>32</bitWidth>
            </field>
          </fields>
        </register>
        <register>
          <name>CBRUR5</name>
          <addressOffset>0x420</addressOffset>
          <size>0x20</size>
          <fields>
            <field>
              <name>SUV</name>
              <bitOffset>0</bitOffset>
              <bitWidth>16</bitWidth>
            </field>
            <field>
              <name>DUV</name>
              <bitOffset>16</bitOffset>
              <bitWidth>16</bitWidth>
            </field>
          </fields>
        </register>
        <register>
          <name>CLAR5</name>
          <addressOffset>0x424</addressOffset>
          <size>0x20</size>
          <fields>
            <field>
              <name>LAR</name>
              <bitOffset>0</bitOffset>
              <bitWidth>32</bitWidth>
            </field>
          </fields>
        </register>
        <register>
          <name>CTBR5</name>
          <addressOffset>0x428</addressOffset>
          <size>0x20</size>
          <fields>
            <field>
              <name>TSEL</name>
              <bitOffset>0</bitOffset>
              <bitWidth>8</bitWidth>
            </field>
            <field>
              <name>SBUS</name>
              <bitOffset>16</bitOffset>
              <bitWidth>1</bitWidth>
            </field>
            <field>
              <name>DBUS</name>
              <bitOffset>17</bitOffset>
              <bitWidth>1</bitWidth>
            </field>
          </fields>
        </register>
        <register>
          <name>CMAR5</name>
          <addressOffset>0x430</addressOffset>
          <size>0x20</size>
          <fields>
            <field>
              <name>MAR</name>
              <bitOffset>0</bitOffset>
              <bitWidth>32</bitWidth>
            </field>
          </fields>
        </register>
        <register>
          <name>CMDR5</name>
          <addressOffset>0x434</addressOffset>
          <size>0x20</size>
          <fields>
            <field>
              <name>MDR</name>
              <bitOffset>0</bitOffset>
              <bitWidth>32</bitWidth>
            </field>
          </fields>
        </register>
      </registers>
    </peripheral>
    <peripheral>
      <name>DMA2D</name>
      <baseAddress>0x52001000</baseAddress>
      <registers>
        <register>
          <name>CR</name>
          <addressOffset>0x0</addressOffset>
          <size>0x20</size>
          <fields>
            <field>
              <name>START</name>
              <bitOffset>0</bitOffset>
              <bitWidth>1</bitWidth>
            </field>
            <field>
              <name>SUSP</name>
              <bitOffset>1</bitOffset>
              <bitWidth>1</bitWidth>
            </field>
            <field>
              <name>ABORT</name>
              <bitOffset>2</bitOffset>
              <bitWidth>1</bitWidth>
            </field>
            <field>
              <name>LOM</name>
              <bitOffset>6</bitOffset>
              <bitWidth>1</bitWidth>
            </field>
            <field>
              <name>TEIE</name>
              <bitOffset>8</bitOffset>
              <bitWidth>1</bitWidth>
            </field>
            <field>
              <name>TCIE</name>
              <bitOffset>9</bitOffset>
              <bitWidth>1</bitWidth>
            </field>
            <field>
              <name>TWIE</name>
              <bitOffset>10</bitOffset>
              <bitWidth>1</bitWidth>
            </field>
            <field>
              <name>CAEIE</name>
              <bitOffset>11</bitOffset>
              <bitWidth>1</bitWidth>
            </field>
            <field>
              <name>CTCIE</name>
              <bitOffset>12</bitOffset>
              <bitWidth>1</bitWidth>
            </field>
            <field>
              <name>CEIE</name>
              <bitOffset>13</bitOffset>
              <bitWidth>1</bitWidth>
            </field>
            <field>
              <name>MODE</name>
              <bitOffset>16</bitOffset>
              <bitWidth>3</bitWidth>
            </field>
          </fields>
        </register>
        <register>
          <name>ISR</name>
          <addressOffset>0x4</addressOffset>
          <size>0x20</size>
          <fields>
            <field>
              <name>TEIF</name>
              <bitOffset>0</bitOffset>
              <bitWidth>1</bitWidth>
            </field>
            <field>
              <name>TCIF</name>
              <bitOffset>1</bitOffset>
              <bitWidth>1</bitWidth>
            </field>
            <field>
              <name>TWIF</name>
              <bitOffset>2</bitOffset>
              <bitWidth>1</bitWidth>
            </field>
            <field>
              <name>CAEIF</name>
              <bitOffset>3</bitOffset>
              <bitWidth>1</bitWidth>
            </field>
            <field>
              <name>CTCIF</name>
              <bitOffset>4</bitOffset>
              <bitWidth>1</bitWidth>
            </field>
            <field>
              <name>CEIF</name>
              <bitOffset>5</bitOffset>
              <bitWidth>1</bitWidth>
            </field>
          </fields>
        </register>
        <register>
          <name>IFCR</name>
          <addressOffset>0x8</addressOffset>
          <size>0x20</size>
          <fields>
            <field>
              <name>CTEIF</name>
              <bitOffset>0</bitOffset>
              <bitWidth>1</bitWidth>
            </field>
            <field>
              <name>CTCIF</name>
              <bitOffset>1</bitOffset>
              <bitWidth>1</bitWidth>
            </field>
            <field>
              <name>CTWIF</name>
              <bitOffset>2</bitOffset>
              <bitWidth>1</bitWidth>
            </field>
            <field>
              <name>CAECIF</name>
              <bitOffset>3</bitOffset>
              <bitWidth>1</bitWidth>
            </field>
            <field>
              <name>CCTCIF</name>
              <bitOffset>4</bitOffset>
              <bitWidth>1</bitWidth>
            </field>
            <field>
              <name>CCEIF</name>
              <bitOffset>5</bitOffset>
              <bitWidth>1</bitWidth>
            </field>
          </fields>
        </register>
        <register>
          <name>FGMAR</name>
          <addressOffset>0xc</addressOffset>
          <size>0x20</size>
          <fields>
            <field>
              <name>MA</name>
              <bitOffset>0</bitOffset>
              <bitWidth>32</bitWidth>
            </field>
          </fields>
        </register>
        <register>
          <name>FGOR</name>
          <addressOffset>0x10</addressOffset>
          <size>0x20</size>
          <fields>
            <field>
              <name>LO</name>
              <bitOffset>0</bitOffset>
              <bitWidth>16</bitWidth>
            </field>
          </fields>
        </register>
        <register>
          <name>BGMAR</name>
          <addressOffset>0x14</addressOffset>
          <size>0x20</size>
          <fields>
            <field>
              <name>MA</name>
              <bitOffset>0</bitOffset>
              <bitWidth>32</bitWidth>
            </field>
          </fields>
        </register>
        <register>
          <name>BGOR</name>
          <addressOffset>0x18</addressOffset>
          <size>0x20</size>
          <fields>
            <field>
              <name>LO</name>
              <bitOffset>0</bitOffset>
              <bitWidth>16</bitWidth>
            </field>
          </fields>
        </register>
        <register>
          <name>FGPFCCR</name>
          <addressOffset>0x1c</addressOffset>
          <size>0x20</size>
          <fields>
            <field>
              <name>CM</name>
              <bitOffset>0</bitOffset>
              <bitWidth>4</bitWidth>
            </field>
            <field>
              <name>CCM</name>
              <bitOffset>4</bitOffset>
              <bitWidth>1</bitWidth>
            </field>
            <field>
              <name>START</name>
              <bitOffset>5</bitOffset>
              <bitWidth>1</bitWidth>
            </field>
            <field>
              <name>CS</name>
              <bitOffset>8</bitOffset>
              <bitWidth>8</bitWidth>
            </field>
            <field>
              <name>AM</name>
              <bitOffset>16</bitOffset>
              <bitWidth>2</bitWidth>
            </field>
            <field>
              <name>CSS</name>
              <bitOffset>18</bitOffset>
              <bitWidth>2</bitWidth>
            </field>
            <field>
              <name>AI</name>
              <bitOffset>20</bitOffset>
              <bitWidth>1</bitWidth>
            </field>
            <field>
              <name>RBS</name>
              <bitOffset>21</bitOffset>
              <bitWidth>1</bitWidth>
            </field>
            <field>
              <name>ALPHA</name>
              <bitOffset>24</bitOffset>
              <bitWidth>8</bitWidth>
            </field>
          </fields>
        </register>
        <register>
          <name>FGCOLR</name>
          <addressOffset>0x20</addressOffset>
          <size>0x20</size>
          <fields>
            <field>
              <name>BLUE</name>
              <bitOffset>0</bitOffset>
              <bitWidth>8</bitWidth>
            </field>
            <field>
              <name>GREEN</name>
              <bitOffset>8</bitOffset>
              <bitWidth>8</bitWidth>
            </field>
            <field>
              <name>RED</name>
              <bitOffset>16</bitOffset>
              <bitWidth>8</bitWidth>
            </field>
          </fields>
        </register>
        <register>
          <name>BGPFCCR</name>
          <addressOffset>0x24</addressOffset>
          <size>0x20</size>
          <fields>
            <field>
              <name>CM</name>
              <bitOffset>0</bitOffset>
              <bitWidth>4</bitWidth>
            </field>
            <field>
              <name>CCM</name>
              <bitOffset>4</bitOffset>
              <bitWidth>1</bitWidth>
            </field>
            <field>
              <name>START</name>
              <bitOffset>5</bitOffset>
              <bitWidth>1</bitWidth>
            </field>
            <field>
              <name>CS</name>
              <bitOffset>8</bitOffset>
              <bitWidth>8</bitWidth>
            </field>
            <field>
              <name>AM</name>
              <bitOffset>16</bitOffset>
              <bitWidth>2</bitWidth>
            </field>
            <field>
              <name>AI</name>
              <bitOffset>20</bitOffset>
              <bitWidth>1</bitWidth>
            </field>
            <field>
              <name>RBS</name>
              <bitOffset>21</bitOffset>
              <bitWidth>1</bitWidth>
            </field>
            <field>
              <name>ALPHA</name>
              <bitOffset>24</bitOffset>
              <bitWidth>8</bitWidth>
            </field>
          </fields>
        </register>
        <register>
          <name>BGCOLR</name>
          <addressOffset>0x28</addressOffset>
          <size>0x20</size>
          <fields>
            <field>
              <name>BLUE</name>
              <bitOffset>0</bitOffset>
              <bitWidth>8</bitWidth>
            </field>
            <field>
              <name>GREEN</name>
              <bitOffset>8</bitOffset>
              <bitWidth>8</bitWidth>
            </field>
            <field>
              <name>RED</name>
              <bitOffset>16</bitOffset>
              <bitWidth>8</bitWidth>
            </field>
          </fields>
        </register>
        <register>
          <name>FGCMAR</name>
          <addressOffset>0x2c</addressOffset>
          <size>0x20</size>
          <fields>
            <field>
              <name>MA</name>
              <bitOffset>0</bitOffset>
              <bitWidth>32</bitWidth>
            </field>
          </fields>
        </register>
        <register>
          <name>BGCMAR</name>
          <addressOffset>0x30</addressOffset>
          <size>0x20</size>
          <fields>
            <field>
              <name>MA</name>
              <bitOffset>0</bitOffset>
              <bitWidth>32</bitWidth>
            </field>
          </fields>
        </register>
        <register>
          <name>OPFCCR</name>
          <addressOffset>0x34</addressOffset>
          <size>0x20</size>
          <fields>
            <field>
              <name>CM</name>
              <bitOffset>0</bitOffset>
              <bitWidth>3</bitWidth>
            </field>
            <field>
              <name>SB</name>
              <bitOffset>8</bitOffset>
              <bitWidth>1</bitWidth>
            </field>
            <field>
              <name>AI</name>
              <bitOffset>20</bitOffset>
              <bitWidth>1</bitWidth>
            </field>
            <field>
              <name>RBS</name>
              <bitOffset>21</bitOffset>
              <bitWidth>1</bitWidth>
            </field>
          </fields>
        </register>
        <register>
          <name>OCOLR</name>
          <addressOffset>0x38</addressOffset>
          <size>0x20</size>
          <fields>
            <field>
              <name>BLUE_4</name>
              <bitOffset>0</bitOffset>
              <bitWidth>4</bitWidth>
            </field>
            <field>
              <name>GREEN_4</name>
              <bitOffset>4</bitOffset>
              <bitWidth>4</bitWidth>
            </field>
            <field>
              <name>GREEN_3</name>
              <bitOffset>5</bitOffset>
              <bitWidth>6</bitWidth>
            </field>
            <field>
              <name>RED_4</name>
              <bitOffset>8</bitOffset>
              <bitWidth>4</bitWidth>
            </field>
            <field>
              <name>RED_3</name>
              <bitOffset>10</bitOffset>
              <bitWidth>7</bitWidth>
            </field>
            <field>
              <name>RED_2</name>
              <bitOffset>11</bitOffset>
              <bitWidth>8</bitWidth>
            </field>
            <field>
              <name>ALPHA_4</name>
              <bitOffset>12</bitOffset>
              <bitWidth>4</bitWidth>
            </field>
            <field>
              <name>ALPHA_3</name>
              <bitOffset>15</bitOffset>
              <bitWidth>1</bitWidth>
            </field>
            <field>
              <name>RED_1</name>
              <bitOffset>16</bitOffset>
              <bitWidth>8</bitWidth>
            </field>
            <field>
              <name>ALPHA_1</name>
              <bitOffset>24</bitOffset>
              <bitWidth>8</bitWidth>
            </field>
          </fields>
        </register>
        <register>
          <name>OMAR</name>
          <addressOffset>0x3c</addressOffset>
          <size>0x20</size>
          <fields>
            <field>
              <name>MA</name>
              <bitOffset>0</bitOffset>
              <bitWidth>32</bitWidth>
            </field>
          </fields>
        </register>
        <register>
          <name>OOR</name>
          <addressOffset>0x40</addressOffset>
          <size>0x20</size>
          <fields>
            <field>
              <name>LO</name>
              <bitOffset>0</bitOffset>
              <bitWidth>16</bitWidth>
            </field>
          </fields>
        </register>
        <register>
          <name>NLR</name>
          <addressOffset>0x44</addressOffset>
          <size>0x20</size>
          <fields>
            <field>
              <name>NL</name>
              <bitOffset>0</bitOffset>
              <bitWidth>16</bitWidth>
            </field>
            <field>
              <name>PL</name>
              <bitOffset>16</bitOffset>
              <bitWidth>14</bitWidth>
            </field>
          </fields>
        </register>
        <register>
          <name>LWR</name>
          <addressOffset>0x48</addressOffset>
          <size>0x20</size>
          <fields>
            <field>
              <name>LW</name>
              <bitOffset>0</bitOffset>
              <bitWidth>16</bitWidth>
            </field>
          </fields>
        </register>
        <register>
          <name>AMTCR</name>
          <addressOffset>0x4c</addressOffset>
          <size>0x20</size>
          <fields>
            <field>
              <name>EN</name>
              <bitOffset>0</bitOffset>
              <bitWidth>1</bitWidth>
            </field>
            <field>
              <name>DT</name>
              <bitOffset>8</bitOffset>
              <bitWidth>8</bitWidth>
            </field>
          </fields>
        </register>
        <register>
          <name>FGCLUT.0</name>
          <addressOffset>0x400</addressOffset>
          <size>0x20</size>
        </register>
        <register>
          <name>FGCLUT.1</name>
          <addressOffset>0x404</addressOffset>
          <size>0x20</size>
        </register>
        <register>
          <name>FGCLUT.2</name>
          <addressOffset>0x408</addressOffset>
          <size>0x20</size>
        </register>
        <register>
          <name>FGCLUT.3</name>
          <addressOffset>0x40c</addressOffset>
          <size>0x20</size>
        </register>
        <register>
          <name>FGCLUT.4</name>
          <addressOffset>0x410</addressOffset>
          <size>0x20</size>
        </register>
        <register>
          <name>FGCLUT.5</name>
          <addressOffset>0x414</addressOffset>
          <size>0x20</size>
        </register>
        <register>
          <name>FGCLUT.6</name>
          <addressOffset>0x418</addressOffset>
          <size>0x20</size>
        </register>
        <register>
          <name>FGCLUT.7</name>
          <addressOffset>0x41c</addressOffset>
          <size>0x20</size>
        </register>
        <register>
          <name>FGCLUT.8</name>
          <addressOffset>0x420</addressOffset>
          <size>0x20</size>
        </register>
        <register>
          <name>FGCLUT.9</name>
          <addressOffset>0x424</addressOffset>
          <size>0x20</size>
        </register>
        <register>
          <name>FGCLUT.10</name>
          <addressOffset>0x428</addressOffset>
          <size>0x20</size>
        </register>
        <register>
          <name>FGCLUT.11</name>
          <addressOffset>0x42c</addressOffset>
          <size>0x20</size>
        </register>
        <register>
          <name>FGCLUT.12</name>
          <addressOffset>0x430</addressOffset>
          <size>0x20</size>
        </register>
        <register>
          <name>FGCLUT.13</name>
          <addressOffset>0x434</addressOffset>
          <size>0x20</size>
        </register>
        <register>
          <name>FGCLUT.14</name>
          <addressOffset>0x438</addressOffset>
          <size>0x20</size>
        </register>
        <register>
          <name>FGCLUT.15</name>
          <addressOffset>0x43c</addressOffset>
          <size>0x20</size>
        </register>
        <register>
          <name>FGCLUT.16</name>
          <addressOffset>0x440</addressOffset>
          <size>0x20</size>
        </register>
        <register>
          <name>FGCLUT.17</name>
          <addressOffset>0x444</addressOffset>
          <size>0x20</size>
        </register>
        <register>
          <name>FGCLUT.18</name>
          <addressOffset>0x448</addressOffset>
          <size>0x20</size>
        </register>
        <register>
          <name>FGCLUT.19</name>
          <addressOffset>0x44c</addressOffset>
          <size>0x20</size>
        </register>
        <register>
          <name>FGCLUT.20</name>
          <addressOffset>0x450</addressOffset>
          <size>0x20</size>
        </register>
        <register>
          <name>FGCLUT.21</name>
          <addressOffset>0x454</addressOffset>
          <size>0x20</size>
        </register>
        <register>
          <name>FGCLUT.22</name>
          <addressOffset>0x458</addressOffset>
          <size>0x20</size>
        </register>
        <register>
          <name>FGCLUT.23</name>
          <addressOffset>0x45c</addressOffset>
          <size>0x20</size>
        </register>
        <register>
          <name>FGCLUT.24</name>
          <addressOffset>0x460</addressOffset>
          <size>0x20</size>
        </register>
        <register>
          <name>FGCLUT.25</name>
          <addressOffset>0x464</addressOffset>
          <size>0x20</size>
        </register>
        <register>
          <name>FGCLUT.26</name>
          <addressOffset>0x468</addressOffset>
          <size>0x20</size>
        </register>
        <register>
          <name>FGCLUT.27</name>
          <addressOffset>0x46c</addressOffset>
          <size>0x20</size>
        </register>
        <register>
          <name>FGCLUT.28</name>
          <addressOffset>0x470</addressOffset>
          <size>0x20</size>
        </register>
        <register>
          <name>FGCLUT.29</name>
          <addressOffset>0x474</addressOffset>
          <size>0x20</size>
        </register>
        <register>
          <name>FGCLUT.30</name>
          <addressOffset>0x478</addressOffset>
          <size>0x20</size>
        </register>
        <register>
          <name>FGCLUT.31</name>
          <addressOffset>0x47c</addressOffset>
          <size>0x20</size>
        </register>
        <register>
          <name>FGCLUT.32</name>
          <addressOffset>0x480</addressOffset>
          <size>0x20</size>
        </register>
        <register>
          <name>FGCLUT.33</name>
          <addressOffset>0x484</addressOffset>
          <size>0x20</size>
        </register>
        <register>
          <name>FGCLUT.34</name>
          <addressOffset>0x488</addressOffset>
          <size>0x20</size>
        </register>
        <register>
          <name>FGCLUT.35</name>
          <addressOffset>0x48c</addressOffset>
          <size>0x20</size>
        </register>
        <register>
          <name>FGCLUT.36</name>
          <addressOffset>0x490</addressOffset>
          <size>0x20</size>
        </register>
        <register>
          <name>FGCLUT.37</name>
          <addressOffset>0x494</addressOffset>
          <size>0x20</size>
        </register>
        <register>
          <name>FGCLUT.38</name>
          <addressOffset>0x498</addressOffset>
          <size>0x20</size>
        </register>
        <register>
          <name>FGCLUT.39</name>
          <addressOffset>0x49c</addressOffset>
          <size>0x20</size>
        </register>
        <register>
          <name>FGCLUT.40</name>
          <addressOffset>0x4a0</addressOffset>
          <size>0x20</size>
        </register>
        <register>
          <name>FGCLUT.41</name>
          <addressOffset>0x4a4</addressOffset>
          <size>0x20</size>
        </register>
        <register>
          <name>FGCLUT.42</name>
          <addressOffset>0x4a8</addressOffset>
          <size>0x20</size>
        </register>
        <register>
          <name>FGCLUT.43</name>
          <addressOffset>0x4ac</addressOffset>
          <size>0x20</size>
        </register>
        <register>
          <name>FGCLUT.44</name>
          <addressOffset>0x4b0</addressOffset>
          <size>0x20</size>
        </register>
        <register>
          <name>FGCLUT.45</name>
          <addressOffset>0x4b4</addressOffset>
          <size>0x20</size>
        </register>
        <register>
          <name>FGCLUT.46</name>
          <addressOffset>0x4b8</addressOffset>
          <size>0x20</size>
        </register>
        <register>
          <name>FGCLUT.47</name>
          <addressOffset>0x4bc</addressOffset>
          <size>0x20</size>
        </register>
        <register>
          <name>FGCLUT.48</name>
          <addressOffset>0x4c0</addressOffset>
          <size>0x20</size>
        </register>
        <register>
          <name>FGCLUT.49</name>
          <addressOffset>0x4c4</addressOffset>
          <size>0x20</size>
        </register>
        <register>
          <name>FGCLUT.50</name>
          <addressOffset>0x4c8</addressOffset>
          <size>0x20</size>
        </register>
        <register>
          <name>FGCLUT.51</name>
          <addressOffset>0x4cc</addressOffset>
          <size>0x20</size>
        </register>
        <register>
          <name>FGCLUT.52</name>
          <addressOffset>0x4d0</addressOffset>
          <size>0x20</size>
        </register>
        <register>
          <name>FGCLUT.53</name>
          <addressOffset>0x4d4</addressOffset>
          <size>0x20</size>
        </register>
        <register>
          <name>FGCLUT.54</name>
          <addressOffset>0x4d8</addressOffset>
          <size>0x20</size>
        </register>
        <register>
          <name>FGCLUT.55</name>
          <addressOffset>0x4dc</addressOffset>
          <size>0x20</size>
        </register>
        <register>
          <name>FGCLUT.56</name>
          <addressOffset>0x4e0</addressOffset>
          <size>0x20</size>
        </register>
        <register>
          <name>FGCLUT.57</name>
          <addressOffset>0x4e4</addressOffset>
          <size>0x20</size>
        </register>
        <register>
          <name>FGCLUT.58</name>
          <addressOffset>0x4e8</addressOffset>
          <size>0x20</size>
        </register>
        <register>
          <name>FGCLUT.59</name>
          <addressOffset>0x4ec</addressOffset>
          <size>0x20</size>
        </register>
        <register>
          <name>FGCLUT.60</name>
          <addressOffset>0x4f0</addressOffset>
          <size>0x20</size>
        </register>
        <register>
          <name>FGCLUT.61</name>
          <addressOffset>0x4f4</addressOffset>
          <size>0x20</size>
        </register>
        <register>
          <name>FGCLUT.62</name>
          <addressOffset>0x4f8</addressOffset>
          <size>0x20</size>
        </register>
        <register>
          <name>FGCLUT.63</name>
          <addressOffset>0x4fc</addressOffset>
          <size>0x20</size>
        </register>
        <register>
          <name>FGCLUT.64</name>
          <addressOffset>0x500</addressOffset>
          <size>0x20</size>
        </register>
        <register>
          <name>FGCLUT.65</name>
          <addressOffset>0x504</addressOffset>
          <size>0x20</size>
        </register>
        <register>
          <name>FGCLUT.66</name>
          <addressOffset>0x508</addressOffset>
          <size>0x20</size>
        </register>
        <register>
          <name>FGCLUT.67</name>
          <addressOffset>0x50c</addressOffset>
          <size>0x20</size>
        </register>
        <register>
          <name>FGCLUT.68</name>
          <addressOffset>0x510</addressOffset>
          <size>0x20</size>
        </register>
        <register>
          <name>FGCLUT.69</name>
          <addressOffset>0x514</addressOffset>
          <size>0x20</size>
        </register>
        <register>
          <name>FGCLUT.70</name>
          <addressOffset>0x518</addressOffset>
          <size>0x20</size>
        </register>
        <register>
          <name>FGCLUT.71</name>
          <addressOffset>0x51c</addressOffset>
          <size>0x20</size>
        </register>
        <register>
          <name>FGCLUT.72</name>
          <addressOffset>0x520</addressOffset>
          <size>0x20</size>
        </register>
        <register>
          <name>FGCLUT.73</name>
          <addressOffset>0x524</addressOffset>
          <size>0x20</size>
        </register>
        <register>
          <name>FGCLUT.74</name>
          <addressOffset>0x528</addressOffset>
          <size>0x20</size>
        </register>
        <register>
          <name>FGCLUT.75</name>
          <addressOffset>0x52c</addressOffset>
          <size>0x20</size>
        </register>
        <register>
          <name>FGCLUT.76</name>
          <addressOffset>0x530</addressOffset>
          <size>0x20</size>
        </register>
        <register>
          <name>FGCLUT.77</name>
          <addressOffset>0x534</addressOffset>
          <size>0x20</size>
        </register>
        <register>
          <name>FGCLUT.78</name>
          <addressOffset>0x538</addressOffset>
          <size>0x20</size>
        </register>
        <register>
          <name>FGCLUT.79</name>
          <addressOffset>0x53c</addressOffset>
          <size>0x20</size>
        </register>
        <register>
          <name>FGCLUT.80</name>
          <addressOffset>0x540</addressOffset>
          <size>0x20</size>
        </register>
        <register>
          <name>FGCLUT.81</name>
          <addressOffset>0x544</addressOffset>
          <size>0x20</size>
        </register>
        <register>
          <name>FGCLUT.82</name>
          <addressOffset>0x548</addressOffset>
          <size>0x20</size>
        </register>
        <register>
          <name>FGCLUT.83</name>
          <addressOffset>0x54c</addressOffset>
          <size>0x20</size>
        </register>
        <register>
          <name>FGCLUT.84</name>
          <addressOffset>0x550</addressOffset>
          <size>0x20</size>
        </register>
        <register>
          <name>FGCLUT.85</name>
          <addressOffset>0x554</addressOffset>
          <size>0x20</size>
        </register>
        <register>
          <name>FGCLUT.86</name>
          <addressOffset>0x558</addressOffset>
          <size>0x20</size>
        </register>
        <register>
          <name>FGCLUT.87</name>
          <addressOffset>0x55c</addressOffset>
          <size>0x20</size>
        </register>
        <register>
          <name>FGCLUT.88</name>
          <addressOffset>0x560</addressOffset>
          <size>0x20</size>
        </register>
        <register>
          <name>FGCLUT.89</name>
          <addressOffset>0x564</addressOffset>
          <size>0x20</size>
        </register>
        <register>
          <name>FGCLUT.90</name>
          <addressOffset>0x568</addressOffset>
          <size>0x20</size>
        </register>
        <register>
          <name>FGCLUT.91</name>
          <addressOffset>0x56c</addressOffset>
          <size>0x20</size>
        </register>
        <register>
          <name>FGCLUT.92</name>
          <addressOffset>0x570</addressOffset>
          <size>0x20</size>
        </register>
        <register>
          <name>FGCLUT.93</name>
          <addressOffset>0x574</addressOffset>
          <size>0x20</size>
        </register>
        <register>
          <name>FGCLUT.94</name>
          <addressOffset>0x578</addressOffset>
          <size>0x20</size>
        </register>
        <register>
          <name>FGCLUT.95</name>
          <addressOffset>0x57c</addressOffset>
          <size>0x20</size>
        </register>
        <register>
          <name>FGCLUT.96</name>
          <addressOffset>0x580</addressOffset>
          <size>0x20</size>
        </register>
        <register>
          <name>FGCLUT.97</name>
          <addressOffset>0x584</addressOffset>
          <size>0x20</size>
        </register>
        <register>
          <name>FGCLUT.98</name>
          <addressOffset>0x588</addressOffset>
          <size>0x20</size>
        </register>
        <register>
          <name>FGCLUT.99</name>
          <addressOffset>0x58c</addressOffset>
          <size>0x20</size>
        </register>
        <register>
          <name>FGCLUT.100</name>
          <addressOffset>0x590</addressOffset>
          <size>0x20</size>
        </register>
        <register>
          <name>FGCLUT.101</name>
          <addressOffset>0x594</addressOffset>
          <size>0x20</size>
        </register>
        <register>
          <name>FGCLUT.102</name>
          <addressOffset>0x598</addressOffset>
          <size>0x20</size>
        </register>
        <register>
          <name>FGCLUT.103</name>
          <addressOffset>0x59c</addressOffset>
          <size>0x20</size>
        </register>
        <register>
          <name>FGCLUT.104</name>
          <addressOffset>0x5a0</addressOffset>
          <size>0x20</size>
        </register>
        <register>
          <name>FGCLUT.105</name>
          <addressOffset>0x5a4</addressOffset>
          <size>0x20</size>
        </register>
        <register>
          <name>FGCLUT.106</name>
          <addressOffset>0x5a8</addressOffset>
          <size>0x20</size>
        </register>
        <register>
          <name>FGCLUT.107</name>
          <addressOffset>0x5ac</addressOffset>
          <size>0x20</size>
        </register>
        <register>
          <name>FGCLUT.108</name>
          <addressOffset>0x5b0</addressOffset>
          <size>0x20</size>
        </register>
        <register>
          <name>FGCLUT.109</name>
          <addressOffset>0x5b4</addressOffset>
          <size>0x20</size>
        </register>
        <register>
          <name>FGCLUT.110</name>
          <addressOffset>0x5b8</addressOffset>
          <size>0x20</size>
        </register>
        <register>
          <name>FGCLUT.111</name>
          <addressOffset>0x5bc</addressOffset>
          <size>0x20</size>
        </register>
        <register>
          <name>FGCLUT.112</name>
          <addressOffset>0x5c0</addressOffset>
          <size>0x20</size>
        </register>
        <register>
          <name>FGCLUT.113</name>
          <addressOffset>0x5c4</addressOffset>
          <size>0x20</size>
        </register>
        <register>
          <name>FGCLUT.114</name>
          <addressOffset>0x5c8</addressOffset>
          <size>0x20</size>
        </register>
        <register>
          <name>FGCLUT.115</name>
          <addressOffset>0x5cc</addressOffset>
          <size>0x20</size>
        </register>
        <register>
          <name>FGCLUT.116</name>
          <addressOffset>0x5d0</addressOffset>
          <size>0x20</size>
        </register>
        <register>
          <name>FGCLUT.117</name>
          <addressOffset>0x5d4</addressOffset>
          <size>0x20</size>
        </register>
        <register>
          <name>FGCLUT.118</name>
          <addressOffset>0x5d8</addressOffset>
          <size>0x20</size>
        </register>
        <register>
          <name>FGCLUT.119</name>
          <addressOffset>0x5dc</addressOffset>
          <size>0x20</size>
        </register>
        <register>
          <name>FGCLUT.120</name>
          <addressOffset>0x5e0</addressOffset>
          <size>0x20</size>
        </register>
        <register>
          <name>FGCLUT.121</name>
          <addressOffset>0x5e4</addressOffset>
          <size>0x20</size>
        </register>
        <register>
          <name>FGCLUT.122</name>
          <addressOffset>0x5e8</addressOffset>
          <size>0x20</size>
        </register>
        <register>
          <name>FGCLUT.123</name>
          <addressOffset>0x5ec</addressOffset>
          <size>0x20</size>
        </register>
        <register>
          <name>FGCLUT.124</name>
          <addressOffset>0x5f0</addressOffset>
          <size>0x20</size>
        </register>
        <register>
          <name>FGCLUT.125</name>
          <addressOffset>0x5f4</addressOffset>
          <size>0x20</size>
        </register>
        <register>
          <name>FGCLUT.126</name>
          <addressOffset>0x5f8</addressOffset>
          <size>0x20</size>
        </register>
        <register>
          <name>FGCLUT.127</name>
          <addressOffset>0x5fc</addressOffset>
          <size>0x20</size>
        </register>
        <register>
          <name>FGCLUT.128</name>
          <addressOffset>0x600</addressOffset>
          <size>0x20</size>
        </register>
        <register>
          <name>FGCLUT.129</name>
          <addressOffset>0x604</addressOffset>
          <size>0x20</size>
        </register>
        <register>
          <name>FGCLUT.130</name>
          <addressOffset>0x608</addressOffset>
          <size>0x20</size>
        </register>
        <register>
          <name>FGCLUT.131</name>
          <addressOffset>0x60c</addressOffset>
          <size>0x20</size>
        </register>
        <register>
          <name>FGCLUT.132</name>
          <addressOffset>0x610</addressOffset>
          <size>0x20</size>
        </register>
        <register>
          <name>FGCLUT.133</name>
          <addressOffset>0x614</addressOffset>
          <size>0x20</size>
        </register>
        <register>
          <name>FGCLUT.134</name>
          <addressOffset>0x618</addressOffset>
          <size>0x20</size>
        </register>
        <register>
          <name>FGCLUT.135</name>
          <addressOffset>0x61c</addressOffset>
          <size>0x20</size>
        </register>
        <register>
          <name>FGCLUT.136</name>
          <addressOffset>0x620</addressOffset>
          <size>0x20</size>
        </register>
        <register>
          <name>FGCLUT.137</name>
          <addressOffset>0x624</addressOffset>
          <size>0x20</size>
        </register>
        <register>
          <name>FGCLUT.138</name>
          <addressOffset>0x628</addressOffset>
          <size>0x20</size>
        </register>
        <register>
          <name>FGCLUT.139</name>
          <addressOffset>0x62c</addressOffset>
          <size>0x20</size>
        </register>
        <register>
          <name>FGCLUT.140</name>
          <addressOffset>0x630</addressOffset>
          <size>0x20</size>
        </register>
        <register>
          <name>FGCLUT.141</name>
          <addressOffset>0x634</addressOffset>
          <size>0x20</size>
        </register>
        <register>
          <name>FGCLUT.142</name>
          <addressOffset>0x638</addressOffset>
          <size>0x20</size>
        </register>
        <register>
          <name>FGCLUT.143</name>
          <addressOffset>0x63c</addressOffset>
          <size>0x20</size>
        </register>
        <register>
          <name>FGCLUT.144</name>
          <addressOffset>0x640</addressOffset>
          <size>0x20</size>
        </register>
        <register>
          <name>FGCLUT.145</name>
          <addressOffset>0x644</addressOffset>
          <size>0x20</size>
        </register>
        <register>
          <name>FGCLUT.146</name>
          <addressOffset>0x648</addressOffset>
          <size>0x20</size>
        </register>
        <register>
          <name>FGCLUT.147</name>
          <addressOffset>0x64c</addressOffset>
          <size>0x20</size>
        </register>
        <register>
          <name>FGCLUT.148</name>
          <addressOffset>0x650</addressOffset>
          <size>0x20</size>
        </register>
        <register>
          <name>FGCLUT.149</name>
          <addressOffset>0x654</addressOffset>
          <size>0x20</size>
        </register>
        <register>
          <name>FGCLUT.150</name>
          <addressOffset>0x658</addressOffset>
          <size>0x20</size>
        </register>
        <register>
          <name>FGCLUT.151</name>
          <addressOffset>0x65c</addressOffset>
          <size>0x20</size>
        </register>
        <register>
          <name>FGCLUT.152</name>
          <addressOffset>0x660</addressOffset>
          <size>0x20</size>
        </register>
        <register>
          <name>FGCLUT.153</name>
          <addressOffset>0x664</addressOffset>
          <size>0x20</size>
        </register>
        <register>
          <name>FGCLUT.154</name>
          <addressOffset>0x668</addressOffset>
          <size>0x20</size>
        </register>
        <register>
          <name>FGCLUT.155</name>
          <addressOffset>0x66c</addressOffset>
          <size>0x20</size>
        </register>
        <register>
          <name>FGCLUT.156</name>
          <addressOffset>0x670</addressOffset>
          <size>0x20</size>
        </register>
        <register>
          <name>FGCLUT.157</name>
          <addressOffset>0x674</addressOffset>
          <size>0x20</size>
        </register>
        <register>
          <name>FGCLUT.158</name>
          <addressOffset>0x678</addressOffset>
          <size>0x20</size>
        </register>
        <register>
          <name>FGCLUT.159</name>
          <addressOffset>0x67c</addressOffset>
          <size>0x20</size>
        </register>
        <register>
          <name>FGCLUT.160</name>
          <addressOffset>0x680</addressOffset>
          <size>0x20</size>
        </register>
        <register>
          <name>FGCLUT.161</name>
          <addressOffset>0x684</addressOffset>
          <size>0x20</size>
        </register>
        <register>
          <name>FGCLUT.162</name>
          <addressOffset>0x688</addressOffset>
          <size>0x20</size>
        </register>
        <register>
          <name>FGCLUT.163</name>
          <addressOffset>0x68c</addressOffset>
          <size>0x20</size>
        </register>
        <register>
          <name>FGCLUT.164</name>
          <addressOffset>0x690</addressOffset>
          <size>0x20</size>
        </register>
        <register>
          <name>FGCLUT.165</name>
          <addressOffset>0x694</addressOffset>
          <size>0x20</size>
        </register>
        <register>
          <name>FGCLUT.166</name>
          <addressOffset>0x698</addressOffset>
          <size>0x20</size>
        </register>
        <register>
          <name>FGCLUT.167</name>
          <addressOffset>0x69c</addressOffset>
          <size>0x20</size>
        </register>
        <register>
          <name>FGCLUT.168</name>
          <addressOffset>0x6a0</addressOffset>
          <size>0x20</size>
        </register>
        <register>
          <name>FGCLUT.169</name>
          <addressOffset>0x6a4</addressOffset>
          <size>0x20</size>
        </register>
        <register>
          <name>FGCLUT.170</name>
          <addressOffset>0x6a8</addressOffset>
          <size>0x20</size>
        </register>
        <register>
          <name>FGCLUT.171</name>
          <addressOffset>0x6ac</addressOffset>
          <size>0x20</size>
        </register>
        <register>
          <name>FGCLUT.172</name>
          <addressOffset>0x6b0</addressOffset>
          <size>0x20</size>
        </register>
        <register>
          <name>FGCLUT.173</name>
          <addressOffset>0x6b4</addressOffset>
          <size>0x20</size>
        </register>
        <register>
          <name>FGCLUT.174</name>
          <addressOffset>0x6b8</addressOffset>
          <size>0x20</size>
        </register>
        <register>
          <name>FGCLUT.175</name>
          <addressOffset>0x6bc</addressOffset>
          <size>0x20</size>
        </register>
        <register>
          <name>FGCLUT.176</name>
          <addressOffset>0x6c0</addressOffset>
          <size>0x20</size>
        </register>
        <register>
          <name>FGCLUT.177</name>
          <addressOffset>0x6c4</addressOffset>
          <size>0x20</size>
        </register>
        <register>
          <name>FGCLUT.178</name>
          <addressOffset>0x6c8</addressOffset>
          <size>0x20</size>
        </register>
        <register>
          <name>FGCLUT.179</name>
          <addressOffset>0x6cc</addressOffset>
          <size>0x20</size>
        </register>
        <register>
          <name>FGCLUT.180</name>
          <addressOffset>0x6d0</addressOffset>
          <size>0x20</size>
        </register>
        <register>
          <name>FGCLUT.181</name>
          <addressOffset>0x6d4</addressOffset>
          <size>0x20</size>
        </register>
        <register>
          <name>FGCLUT.182</name>
          <addressOffset>0x6d8</addressOffset>
          <size>0x20</size>
        </register>
        <register>
          <name>FGCLUT.183</name>
          <addressOffset>0x6dc</addressOffset>
          <size>0x20</size>
        </register>
        <register>
          <name>FGCLUT.184</name>
          <addressOffset>0x6e0</addressOffset>
          <size>0x20</size>
        </register>
        <register>
          <name>FGCLUT.185</name>
          <addressOffset>0x6e4</addressOffset>
          <size>0x20</size>
        </register>
        <register>
          <name>FGCLUT.186</name>
          <addressOffset>0x6e8</addressOffset>
          <size>0x20</size>
        </register>
        <register>
          <name>FGCLUT.187</name>
          <addressOffset>0x6ec</addressOffset>
          <size>0x20</size>
        </register>
        <register>
          <name>FGCLUT.188</name>
          <addressOffset>0x6f0</addressOffset>
          <size>0x20</size>
        </register>
        <register>
          <name>FGCLUT.189</name>
          <addressOffset>0x6f4</addressOffset>
          <size>0x20</size>
        </register>
        <register>
          <name>FGCLUT.190</name>
          <addressOffset>0x6f8</addressOffset>
          <size>0x20</size>
        </register>
        <register>
          <name>FGCLUT.191</name>
          <addressOffset>0x6fc</addressOffset>
          <size>0x20</size>
        </register>
        <register>
          <name>FGCLUT.192</name>
          <addressOffset>0x700</addressOffset>
          <size>0x20</size>
        </register>
        <register>
          <name>FGCLUT.193</name>
          <addressOffset>0x704</addressOffset>
          <size>0x20</size>
        </register>
        <register>
          <name>FGCLUT.194</name>
          <addressOffset>0x708</addressOffset>
          <size>0x20</size>
        </register>
        <register>
          <name>FGCLUT.195</name>
          <addressOffset>0x70c</addressOffset>
          <size>0x20</size>
        </register>
        <register>
          <name>FGCLUT.196</name>
          <addressOffset>0x710</addressOffset>
          <size>0x20</size>
        </register>
        <register>
          <name>FGCLUT.197</name>
          <addressOffset>0x714</addressOffset>
          <size>0x20</size>
        </register>
        <register>
          <name>FGCLUT.198</name>
          <addressOffset>0x718</addressOffset>
          <size>0x20</size>
        </register>
        <register>
          <name>FGCLUT.199</name>
          <addressOffset>0x71c</addressOffset>
          <size>0x20</size>
        </register>
        <register>
          <name>FGCLUT.200</name>
          <addressOffset>0x720</addressOffset>
          <size>0x20</size>
        </register>
        <register>
          <name>FGCLUT.201</name>
          <addressOffset>0x724</addressOffset>
          <size>0x20</size>
        </register>
        <register>
          <name>FGCLUT.202</name>
          <addressOffset>0x728</addressOffset>
          <size>0x20</size>
        </register>
        <register>
          <name>FGCLUT.203</name>
          <addressOffset>0x72c</addressOffset>
          <size>0x20</size>
        </register>
        <register>
          <name>FGCLUT.204</name>
          <addressOffset>0x730</addressOffset>
          <size>0x20</size>
        </register>
        <register>
          <name>FGCLUT.205</name>
          <addressOffset>0x734</addressOffset>
          <size>0x20</size>
        </register>
        <register>
          <name>FGCLUT.206</name>
          <addressOffset>0x738</addressOffset>
          <size>0x20</size>
        </register>
        <register>
          <name>FGCLUT.207</name>
          <addressOffset>0x73c</addressOffset>
          <size>0x20</size>
        </register>
        <register>
          <name>FGCLUT.208</name>
          <addressOffset>0x740</addressOffset>
          <size>0x20</size>
        </register>
        <register>
          <name>FGCLUT.209</name>
          <addressOffset>0x744</addressOffset>
          <size>0x20</size>
        </register>
        <register>
          <name>FGCLUT.210</name>
          <addressOffset>0x748</addressOffset>
          <size>0x20</size>
        </register>
        <register>
          <name>FGCLUT.211</name>
          <addressOffset>0x74c</addressOffset>
          <size>0x20</size>
        </register>
        <register>
          <name>FGCLUT.212</name>
          <addressOffset>0x750</addressOffset>
          <size>0x20</size>
        </register>
        <register>
          <name>FGCLUT.213</name>
          <addressOffset>0x754</addressOffset>
          <size>0x20</size>
        </register>
        <register>
          <name>FGCLUT.214</name>
          <addressOffset>0x758</addressOffset>
          <size>0x20</size>
        </register>
        <register>
          <name>FGCLUT.215</name>
          <addressOffset>0x75c</addressOffset>
          <size>0x20</size>
        </register>
        <register>
          <name>FGCLUT.216</name>
          <addressOffset>0x760</addressOffset>
          <size>0x20</size>
        </register>
        <register>
          <name>FGCLUT.217</name>
          <addressOffset>0x764</addressOffset>
          <size>0x20</size>
        </register>
        <register>
          <name>FGCLUT.218</name>
          <addressOffset>0x768</addressOffset>
          <size>0x20</size>
        </register>
        <register>
          <name>FGCLUT.219</name>
          <addressOffset>0x76c</addressOffset>
          <size>0x20</size>
        </register>
        <register>
          <name>FGCLUT.220</name>
          <addressOffset>0x770</addressOffset>
          <size>0x20</size>
        </register>
        <register>
          <name>FGCLUT.221</name>
          <addressOffset>0x774</addressOffset>
          <size>0x20</size>
        </register>
        <register>
          <name>FGCLUT.222</name>
          <addressOffset>0x778</addressOffset>
          <size>0x20</size>
        </register>
        <register>
          <name>FGCLUT.223</name>
          <addressOffset>0x77c</addressOffset>
          <size>0x20</size>
        </register>
        <register>
          <name>FGCLUT.224</name>
          <addressOffset>0x780</addressOffset>
          <size>0x20</size>
        </register>
        <register>
          <name>FGCLUT.225</name>
          <addressOffset>0x784</addressOffset>
          <size>0x20</size>
        </register>
        <register>
          <name>FGCLUT.226</name>
          <addressOffset>0x788</addressOffset>
          <size>0x20</size>
        </register>
        <register>
          <name>FGCLUT.227</name>
          <addressOffset>0x78c</addressOffset>
          <size>0x20</size>
        </register>
        <register>
          <name>FGCLUT.228</name>
          <addressOffset>0x790</addressOffset>
          <size>0x20</size>
        </register>
        <register>
          <name>FGCLUT.229</name>
          <addressOffset>0x794</addressOffset>
          <size>0x20</size>
        </register>
        <register>
          <name>FGCLUT.230</name>
          <addressOffset>0x798</addressOffset>
          <size>0x20</size>
        </register>
        <register>
          <name>FGCLUT.231</name>
          <addressOffset>0x79c</addressOffset>
          <size>0x20</size>
        </register>
        <register>
          <name>FGCLUT.232</name>
          <addressOffset>0x7a0</addressOffset>
          <size>0x20</size>
        </register>
        <register>
          <name>FGCLUT.233</name>
          <addressOffset>0x7a4</addressOffset>
          <size>0x20</size>
        </register>
        <register>
          <name>FGCLUT.234</name>
          <addressOffset>0x7a8</addressOffset>
          <size>0x20</size>
        </register>
        <register>
          <name>FGCLUT.235</name>
          <addressOffset>0x7ac</addressOffset>
          <size>0x20</size>
        </register>
        <register>
          <name>FGCLUT.236</name>
          <addressOffset>0x7b0</addressOffset>
          <size>0x20</size>
        </register>
        <register>
          <name>FGCLUT.237</name>
          <addressOffset>0x7b4</addressOffset>
          <size>0x20</size>
        </register>
        <register>
          <name>FGCLUT.238</name>
          <addressOffset>0x7b8</addressOffset>
          <size>0x20</size>
        </register>
        <register>
          <name>FGCLUT.239</name>
          <addressOffset>0x7bc</addressOffset>
          <size>0x20</size>
        </register>
        <register>
          <name>FGCLUT.240</name>
          <addressOffset>0x7c0</addressOffset>
          <size>0x20</size>
        </register>
        <register>
          <name>FGCLUT.241</name>
          <addressOffset>0x7c4</addressOffset>
          <size>0x20</size>
        </register>
        <register>
          <name>FGCLUT.242</name>
          <addressOffset>0x7c8</addressOffset>
          <size>0x20</size>
        </register>
        <register>
          <name>FGCLUT.243</name>
          <addressOffset>0x7cc</addressOffset>
          <size>0x20</size>
        </register>
        <register>
          <name>FGCLUT.244</name>
          <addressOffset>0x7d0</addressOffset>
          <size>0x20</size>
        </register>
        <register>
          <name>FGCLUT.245</name>
          <addressOffset>0x7d4</addressOffset>
          <size>0x20</size>
        </register>
        <register>
          <name>FGCLUT.246</name>
          <addressOffset>0x7d8</addressOffset>
          <size>0x20</size>
        </register>
        <register>
          <name>FGCLUT.247</name>
          <addressOffset>0x7dc</addressOffset>
          <size>0x20</size>
        </register>
        <register>
          <name>FGCLUT.248</name>
          <addressOffset>0x7e0</addressOffset>
          <size>0x20</size>
        </register>
        <register>
          <name>FGCLUT.249</name>
          <addressOffset>0x7e4</addressOffset>
          <size>0x20</size>
        </register>
        <register>
          <name>FGCLUT.250</name>
          <addressOffset>0x7e8</addressOffset>
          <size>0x20</size>
        </register>
        <register>
          <name>FGCLUT.251</name>
          <addressOffset>0x7ec</addressOffset>
          <size>0x20</size>
        </register>
        <register>
          <name>FGCLUT.252</name>
          <addressOffset>0x7f0</addressOffset>
          <size>0x20</size>
        </register>
        <register>
          <name>FGCLUT.253</name>
          <addressOffset>0x7f4</addressOffset>
          <size>0x20</size>
        </register>
        <register>
          <name>FGCLUT.254</name>
          <addressOffset>0x7f8</addressOffset>
          <size>0x20</size>
        </register>
        <register>
          <name>FGCLUT.255</name>
          <addressOffset>0x7fc</addressOffset>
          <size>0x20</size>
        </register>
        <register>
          <name>BGCLUT.0</name>
          <addressOffset>0x800</addressOffset>
          <size>0x20</size>
        </register>
        <register>
          <name>BGCLUT.1</name>
          <addressOffset>0x804</addressOffset>
          <size>0x20</size>
        </register>
        <register>
          <name>BGCLUT.2</name>
          <addressOffset>0x808</addressOffset>
          <size>0x20</size>
        </register>
        <register>
          <name>BGCLUT.3</name>
          <addressOffset>0x80c</addressOffset>
          <size>0x20</size>
        </register>
        <register>
          <name>BGCLUT.4</name>
          <addressOffset>0x810</addressOffset>
          <size>0x20</size>
        </register>
        <register>
          <name>BGCLUT.5</name>
          <addressOffset>0x814</addressOffset>
          <size>0x20</size>
        </register>
        <register>
          <name>BGCLUT.6</name>
          <addressOffset>0x818</addressOffset>
          <size>0x20</size>
        </register>
        <register>
          <name>BGCLUT.7</name>
          <addressOffset>0x81c</addressOffset>
          <size>0x20</size>
        </register>
        <register>
          <name>BGCLUT.8</name>
          <addressOffset>0x820</addressOffset>
          <size>0x20</size>
        </register>
        <register>
          <name>BGCLUT.9</name>
          <addressOffset>0x824</addressOffset>
          <size>0x20</size>
        </register>
        <register>
          <name>BGCLUT.10</name>
          <addressOffset>0x828</addressOffset>
          <size>0x20</size>
        </register>
        <register>
          <name>BGCLUT.11</name>
          <addressOffset>0x82c</addressOffset>
          <size>0x20</size>
        </register>
        <register>
          <name>BGCLUT.12</name>
          <addressOffset>0x830</addressOffset>
          <size>0x20</size>
        </register>
        <register>
          <name>BGCLUT.13</name>
          <addressOffset>0x834</addressOffset>
          <size>0x20</size>
        </register>
        <register>
          <name>BGCLUT.14</name>
          <addressOffset>0x838</addressOffset>
          <size>0x20</size>
        </register>
        <register>
          <name>BGCLUT.15</name>
          <addressOffset>0x83c</addressOffset>
          <size>0x20</size>
        </register>
        <register>
          <name>BGCLUT.16</name>
          <addressOffset>0x840</addressOffset>
          <size>0x20</size>
        </register>
        <register>
          <name>BGCLUT.17</name>
          <addressOffset>0x844</addressOffset>
          <size>0x20</size>
        </register>
        <register>
          <name>BGCLUT.18</name>
          <addressOffset>0x848</addressOffset>
          <size>0x20</size>
        </register>
        <register>
          <name>BGCLUT.19</name>
          <addressOffset>0x84c</addressOffset>
          <size>0x20</size>
        </register>
        <register>
          <name>BGCLUT.20</name>
          <addressOffset>0x850</addressOffset>
          <size>0x20</size>
        </register>
        <register>
          <name>BGCLUT.21</name>
          <addressOffset>0x854</addressOffset>
          <size>0x20</size>
        </register>
        <register>
          <name>BGCLUT.22</name>
          <addressOffset>0x858</addressOffset>
          <size>0x20</size>
        </register>
        <register>
          <name>BGCLUT.23</name>
          <addressOffset>0x85c</addressOffset>
          <size>0x20</size>
        </register>
        <register>
          <name>BGCLUT.24</name>
          <addressOffset>0x860</addressOffset>
          <size>0x20</size>
        </register>
        <register>
          <name>BGCLUT.25</name>
          <addressOffset>0x864</addressOffset>
          <size>0x20</size>
        </register>
        <register>
          <name>BGCLUT.26</name>
          <addressOffset>0x868</addressOffset>
          <size>0x20</size>
        </register>
        <register>
          <name>BGCLUT.27</name>
          <addressOffset>0x86c</addressOffset>
          <size>0x20</size>
        </register>
        <register>
          <name>BGCLUT.28</name>
          <addressOffset>0x870</addressOffset>
          <size>0x20</size>
        </register>
        <register>
          <name>BGCLUT.29</name>
          <addressOffset>0x874</addressOffset>
          <size>0x20</size>
        </register>
        <register>
          <name>BGCLUT.30</name>
          <addressOffset>0x878</addressOffset>
          <size>0x20</size>
        </register>
        <register>
          <name>BGCLUT.31</name>
          <addressOffset>0x87c</addressOffset>
          <size>0x20</size>
        </register>
        <register>
          <name>BGCLUT.32</name>
          <addressOffset>0x880</addressOffset>
          <size>0x20</size>
        </register>
        <register>
          <name>BGCLUT.33</name>
          <addressOffset>0x884</addressOffset>
          <size>0x20</size>
        </register>
        <register>
          <name>BGCLUT.34</name>
          <addressOffset>0x888</addressOffset>
          <size>0x20</size>
        </register>
        <register>
          <name>BGCLUT.35</name>
          <addressOffset>0x88c</addressOffset>
          <size>0x20</size>
        </register>
        <register>
          <name>BGCLUT.36</name>
          <addressOffset>0x890</addressOffset>
          <size>0x20</size>
        </register>
        <register>
          <name>BGCLUT.37</name>
          <addressOffset>0x894</addressOffset>
          <size>0x20</size>
        </register>
        <register>
          <name>BGCLUT.38</name>
          <addressOffset>0x898</addressOffset>
          <size>0x20</size>
        </register>
        <register>
          <name>BGCLUT.39</name>
          <addressOffset>0x89c</addressOffset>
          <size>0x20</size>
        </register>
        <register>
          <name>BGCLUT.40</name>
          <addressOffset>0x8a0</addressOffset>
          <size>0x20</size>
        </register>
        <register>
          <name>BGCLUT.41</name>
          <addressOffset>0x8a4</addressOffset>
          <size>0x20</size>
        </register>
        <register>
          <name>BGCLUT.42</name>
          <addressOffset>0x8a8</addressOffset>
          <size>0x20</size>
        </register>
        <register>
          <name>BGCLUT.43</name>
          <addressOffset>0x8ac</addressOffset>
          <size>0x20</size>
        </register>
        <register>
          <name>BGCLUT.44</name>
          <addressOffset>0x8b0</addressOffset>
          <size>0x20</size>
        </register>
        <register>
          <name>BGCLUT.45</name>
          <addressOffset>0x8b4</addressOffset>
          <size>0x20</size>
        </register>
        <register>
          <name>BGCLUT.46</name>
          <addressOffset>0x8b8</addressOffset>
          <size>0x20</size>
        </register>
        <register>
          <name>BGCLUT.47</name>
          <addressOffset>0x8bc</addressOffset>
          <size>0x20</size>
        </register>
        <register>
          <name>BGCLUT.48</name>
          <addressOffset>0x8c0</addressOffset>
          <size>0x20</size>
        </register>
        <register>
          <name>BGCLUT.49</name>
          <addressOffset>0x8c4</addressOffset>
          <size>0x20</size>
        </register>
        <register>
          <name>BGCLUT.50</name>
          <addressOffset>0x8c8</addressOffset>
          <size>0x20</size>
        </register>
        <register>
          <name>BGCLUT.51</name>
          <addressOffset>0x8cc</addressOffset>
          <size>0x20</size>
        </register>
        <register>
          <name>BGCLUT.52</name>
          <addressOffset>0x8d0</addressOffset>
          <size>0x20</size>
        </register>
        <register>
          <name>BGCLUT.53</name>
          <addressOffset>0x8d4</addressOffset>
          <size>0x20</size>
        </register>
        <register>
          <name>BGCLUT.54</name>
          <addressOffset>0x8d8</addressOffset>
          <size>0x20</size>
        </register>
        <register>
          <name>BGCLUT.55</name>
          <addressOffset>0x8dc</addressOffset>
          <size>0x20</size>
        </register>
        <register>
          <name>BGCLUT.56</name>
          <addressOffset>0x8e0</addressOffset>
          <size>0x20</size>
        </register>
        <register>
          <name>BGCLUT.57</name>
          <addressOffset>0x8e4</addressOffset>
          <size>0x20</size>
        </register>
        <register>
          <name>BGCLUT.58</name>
          <addressOffset>0x8e8</addressOffset>
          <size>0x20</size>
        </register>
        <register>
          <name>BGCLUT.59</name>
          <addressOffset>0x8ec</addressOffset>
          <size>0x20</size>
        </register>
        <register>
          <name>BGCLUT.60</name>
          <addressOffset>0x8f0</addressOffset>
          <size>0x20</size>
        </register>
        <register>
          <name>BGCLUT.61</name>
          <addressOffset>0x8f4</addressOffset>
          <size>0x20</size>
        </register>
        <register>
          <name>BGCLUT.62</name>
          <addressOffset>0x8f8</addressOffset>
          <size>0x20</size>
        </register>
        <register>
          <name>BGCLUT.63</name>
          <addressOffset>0x8fc</addressOffset>
          <size>0x20</size>
        </register>
        <register>
          <name>BGCLUT.64</name>
          <addressOffset>0x900</addressOffset>
          <size>0x20</size>
        </register>
        <register>
          <name>BGCLUT.65</name>
          <addressOffset>0x904</addressOffset>
          <size>0x20</size>
        </register>
        <register>
          <name>BGCLUT.66</name>
          <addressOffset>0x908</addressOffset>
          <size>0x20</size>
        </register>
        <register>
          <name>BGCLUT.67</name>
          <addressOffset>0x90c</addressOffset>
          <size>0x20</size>
        </register>
        <register>
          <name>BGCLUT.68</name>
          <addressOffset>0x910</addressOffset>
          <size>0x20</size>
        </register>
        <register>
          <name>BGCLUT.69</name>
          <addressOffset>0x914</addressOffset>
          <size>0x20</size>
        </register>
        <register>
          <name>BGCLUT.70</name>
          <addressOffset>0x918</addressOffset>
          <size>0x20</size>
        </register>
        <register>
          <name>BGCLUT.71</name>
          <addressOffset>0x91c</addressOffset>
          <size>0x20</size>
        </register>
        <register>
          <name>BGCLUT.72</name>
          <addressOffset>0x920</addressOffset>
          <size>0x20</size>
        </register>
        <register>
          <name>BGCLUT.73</name>
          <addressOffset>0x924</addressOffset>
          <size>0x20</size>
        </register>
        <register>
          <name>BGCLUT.74</name>
          <addressOffset>0x928</addressOffset>
          <size>0x20</size>
        </register>
        <register>
          <name>BGCLUT.75</name>
          <addressOffset>0x92c</addressOffset>
          <size>0x20</size>
        </register>
        <register>
          <name>BGCLUT.76</name>
          <addressOffset>0x930</addressOffset>
          <size>0x20</size>
        </register>
        <register>
          <name>BGCLUT.77</name>
          <addressOffset>0x934</addressOffset>
          <size>0x20</size>
        </register>
        <register>
          <name>BGCLUT.78</name>
          <addressOffset>0x938</addressOffset>
          <size>0x20</size>
        </register>
        <register>
          <name>BGCLUT.79</name>
          <addressOffset>0x93c</addressOffset>
          <size>0x20</size>
        </register>
        <register>
          <name>BGCLUT.80</name>
          <addressOffset>0x940</addressOffset>
          <size>0x20</size>
        </register>
        <register>
          <name>BGCLUT.81</name>
          <addressOffset>0x944</addressOffset>
          <size>0x20</size>
        </register>
        <register>
          <name>BGCLUT.82</name>
          <addressOffset>0x948</addressOffset>
          <size>0x20</size>
        </register>
        <register>
          <name>BGCLUT.83</name>
          <addressOffset>0x94c</addressOffset>
          <size>0x20</size>
        </register>
        <register>
          <name>BGCLUT.84</name>
          <addressOffset>0x950</addressOffset>
          <size>0x20</size>
        </register>
        <register>
          <name>BGCLUT.85</name>
          <addressOffset>0x954</addressOffset>
          <size>0x20</size>
        </register>
        <register>
          <name>BGCLUT.86</name>
          <addressOffset>0x958</addressOffset>
          <size>0x20</size>
        </register>
        <register>
          <name>BGCLUT.87</name>
          <addressOffset>0x95c</addressOffset>
          <size>0x20</size>
        </register>
        <register>
          <name>BGCLUT.88</name>
          <addressOffset>0x960</addressOffset>
          <size>0x20</size>
        </register>
        <register>
          <name>BGCLUT.89</name>
          <addressOffset>0x964</addressOffset>
          <size>0x20</size>
        </register>
        <register>
          <name>BGCLUT.90</name>
          <addressOffset>0x968</addressOffset>
          <size>0x20</size>
        </register>
        <register>
          <name>BGCLUT.91</name>
          <addressOffset>0x96c</addressOffset>
          <size>0x20</size>
        </register>
        <register>
          <name>BGCLUT.92</name>
          <addressOffset>0x970</addressOffset>
          <size>0x20</size>
        </register>
        <register>
          <name>BGCLUT.93</name>
          <addressOffset>0x974</addressOffset>
          <size>0x20</size>
        </register>
        <register>
          <name>BGCLUT.94</name>
          <addressOffset>0x978</addressOffset>
          <size>0x20</size>
        </register>
        <register>
          <name>BGCLUT.95</name>
          <addressOffset>0x97c</addressOffset>
          <size>0x20</size>
        </register>
        <register>
          <name>BGCLUT.96</name>
          <addressOffset>0x980</addressOffset>
          <size>0x20</size>
        </register>
        <register>
          <name>BGCLUT.97</name>
          <addressOffset>0x984</addressOffset>
          <size>0x20</size>
        </register>
        <register>
          <name>BGCLUT.98</name>
          <addressOffset>0x988</addressOffset>
          <size>0x20</size>
        </register>
        <register>
          <name>BGCLUT.99</name>
          <addressOffset>0x98c</addressOffset>
          <size>0x20</size>
        </register>
        <register>
          <name>BGCLUT.100</name>
          <addressOffset>0x990</addressOffset>
          <size>0x20</size>
        </register>
        <register>
          <name>BGCLUT.101</name>
          <addressOffset>0x994</addressOffset>
          <size>0x20</size>
        </register>
        <register>
          <name>BGCLUT.102</name>
          <addressOffset>0x998</addressOffset>
          <size>0x20</size>
        </register>
        <register>
          <name>BGCLUT.103</name>
          <addressOffset>0x99c</addressOffset>
          <size>0x20</size>
        </register>
        <register>
          <name>BGCLUT.104</name>
          <addressOffset>0x9a0</addressOffset>
          <size>0x20</size>
        </register>
        <register>
          <name>BGCLUT.105</name>
          <addressOffset>0x9a4</addressOffset>
          <size>0x20</size>
        </register>
        <register>
          <name>BGCLUT.106</name>
          <addressOffset>0x9a8</addressOffset>
          <size>0x20</size>
        </register>
        <register>
          <name>BGCLUT.107</name>
          <addressOffset>0x9ac</addressOffset>
          <size>0x20</size>
        </register>
        <register>
          <name>BGCLUT.108</name>
          <addressOffset>0x9b0</addressOffset>
          <size>0x20</size>
        </register>
        <register>
          <name>BGCLUT.109</name>
          <addressOffset>0x9b4</addressOffset>
          <size>0x20</size>
        </register>
        <register>
          <name>BGCLUT.110</name>
          <addressOffset>0x9b8</addressOffset>
          <size>0x20</size>
        </register>
        <register>
          <name>BGCLUT.111</name>
          <addressOffset>0x9bc</addressOffset>
          <size>0x20</size>
        </register>
        <register>
          <name>BGCLUT.112</name>
          <addressOffset>0x9c0</addressOffset>
          <size>0x20</size>
        </register>
        <register>
          <name>BGCLUT.113</name>
          <addressOffset>0x9c4</addressOffset>
          <size>0x20</size>
        </register>
        <register>
          <name>BGCLUT.114</name>
          <addressOffset>0x9c8</addressOffset>
          <size>0x20</size>
        </register>
        <register>
          <name>BGCLUT.115</name>
          <addressOffset>0x9cc</addressOffset>
          <size>0x20</size>
        </register>
        <register>
          <name>BGCLUT.116</name>
          <addressOffset>0x9d0</addressOffset>
          <size>0x20</size>
        </register>
        <register>
          <name>BGCLUT.117</name>
          <addressOffset>0x9d4</addressOffset>
          <size>0x20</size>
        </register>
        <register>
          <name>BGCLUT.118</name>
          <addressOffset>0x9d8</addressOffset>
          <size>0x20</size>
        </register>
        <register>
          <name>BGCLUT.119</name>
          <addressOffset>0x9dc</addressOffset>
          <size>0x20</size>
        </register>
        <register>
          <name>BGCLUT.120</name>
          <addressOffset>0x9e0</addressOffset>
          <size>0x20</size>
        </register>
        <register>
          <name>BGCLUT.121</name>
          <addressOffset>0x9e4</addressOffset>
          <size>0x20</size>
        </register>
        <register>
          <name>BGCLUT.122</name>
          <addressOffset>0x9e8</addressOffset>
          <size>0x20</size>
        </register>
        <register>
          <name>BGCLUT.123</name>
          <addressOffset>0x9ec</addressOffset>
          <size>0x20</size>
        </register>
        <register>
          <name>BGCLUT.124</name>
          <addressOffset>0x9f0</addressOffset>
          <size>0x20</size>
        </register>
        <register>
          <name>BGCLUT.125</name>
          <addressOffset>0x9f4</addressOffset>
          <size>0x20</size>
        </register>
        <register>
          <name>BGCLUT.126</name>
          <addressOffset>0x9f8</addressOffset>
          <size>0x20</size>
        </register>
        <register>
          <name>BGCLUT.127</name>
          <addressOffset>0x9fc</addressOffset>
          <size>0x20</size>
        </register>
        <register>
          <name>BGCLUT.128</name>
          <addressOffset>0xa00</addressOffset>
          <size>0x20</size>
        </register>
        <register>
          <name>BGCLUT.129</name>
          <addressOffset>0xa04</addressOffset>
          <size>0x20</size>
        </register>
        <register>
          <name>BGCLUT.130</name>
          <addressOffset>0xa08</addressOffset>
          <size>0x20</size>
        </register>
        <register>
          <name>BGCLUT.131</name>
          <addressOffset>0xa0c</addressOffset>
          <size>0x20</size>
        </register>
        <register>
          <name>BGCLUT.132</name>
          <addressOffset>0xa10</addressOffset>
          <size>0x20</size>
        </register>
        <register>
          <name>BGCLUT.133</name>
          <addressOffset>0xa14</addressOffset>
          <size>0x20</size>
        </register>
        <register>
          <name>BGCLUT.134</name>
          <addressOffset>0xa18</addressOffset>
          <size>0x20</size>
        </register>
        <register>
          <name>BGCLUT.135</name>
          <addressOffset>0xa1c</addressOffset>
          <size>0x20</size>
        </register>
        <register>
          <name>BGCLUT.136</name>
          <addressOffset>0xa20</addressOffset>
          <size>0x20</size>
        </register>
        <register>
          <name>BGCLUT.137</name>
          <addressOffset>0xa24</addressOffset>
          <size>0x20</size>
        </register>
        <register>
          <name>BGCLUT.138</name>
          <addressOffset>0xa28</addressOffset>
          <size>0x20</size>
        </register>
        <register>
          <name>BGCLUT.139</name>
          <addressOffset>0xa2c</addressOffset>
          <size>0x20</size>
        </register>
        <register>
          <name>BGCLUT.140</name>
          <addressOffset>0xa30</addressOffset>
          <size>0x20</size>
        </register>
        <register>
          <name>BGCLUT.141</name>
          <addressOffset>0xa34</addressOffset>
          <size>0x20</size>
        </register>
        <register>
          <name>BGCLUT.142</name>
          <addressOffset>0xa38</addressOffset>
          <size>0x20</size>
        </register>
        <register>
          <name>BGCLUT.143</name>
          <addressOffset>0xa3c</addressOffset>
          <size>0x20</size>
        </register>
        <register>
          <name>BGCLUT.144</name>
          <addressOffset>0xa40</addressOffset>
          <size>0x20</size>
        </register>
        <register>
          <name>BGCLUT.145</name>
          <addressOffset>0xa44</addressOffset>
          <size>0x20</size>
        </register>
        <register>
          <name>BGCLUT.146</name>
          <addressOffset>0xa48</addressOffset>
          <size>0x20</size>
        </register>
        <register>
          <name>BGCLUT.147</name>
          <addressOffset>0xa4c</addressOffset>
          <size>0x20</size>
        </register>
        <register>
          <name>BGCLUT.148</name>
          <addressOffset>0xa50</addressOffset>
          <size>0x20</size>
        </register>
        <register>
          <name>BGCLUT.149</name>
          <addressOffset>0xa54</addressOffset>
          <size>0x20</size>
        </register>
        <register>
          <name>BGCLUT.150</name>
          <addressOffset>0xa58</addressOffset>
          <size>0x20</size>
        </register>
        <register>
          <name>BGCLUT.151</name>
          <addressOffset>0xa5c</addressOffset>
          <size>0x20</size>
        </register>
        <register>
          <name>BGCLUT.152</name>
          <addressOffset>0xa60</addressOffset>
          <size>0x20</size>
        </register>
        <register>
          <name>BGCLUT.153</name>
          <addressOffset>0xa64</addressOffset>
          <size>0x20</size>
        </register>
        <register>
          <name>BGCLUT.154</name>
          <addressOffset>0xa68</addressOffset>
          <size>0x20</size>
        </register>
        <register>
          <name>BGCLUT.155</name>
          <addressOffset>0xa6c</addressOffset>
          <size>0x20</size>
        </register>
        <register>
          <name>BGCLUT.156</name>
          <addressOffset>0xa70</addressOffset>
          <size>0x20</size>
        </register>
        <register>
          <name>BGCLUT.157</name>
          <addressOffset>0xa74</addressOffset>
          <size>0x20</size>
        </register>
        <register>
          <name>BGCLUT.158</name>
          <addressOffset>0xa78</addressOffset>
          <size>0x20</size>
        </register>
        <register>
          <name>BGCLUT.159</name>
          <addressOffset>0xa7c</addressOffset>
          <size>0x20</size>
        </register>
        <register>
          <name>BGCLUT.160</name>
          <addressOffset>0xa80</addressOffset>
          <size>0x20</size>
        </register>
        <register>
          <name>BGCLUT.161</name>
          <addressOffset>0xa84</addressOffset>
          <size>0x20</size>
        </register>
        <register>
          <name>BGCLUT.162</name>
          <addressOffset>0xa88</addressOffset>
          <size>0x20</size>
        </register>
        <register>
          <name>BGCLUT.163</name>
          <addressOffset>0xa8c</addressOffset>
          <size>0x20</size>
        </register>
        <register>
          <name>BGCLUT.164</name>
          <addressOffset>0xa90</addressOffset>
          <size>0x20</size>
        </register>
        <register>
          <name>BGCLUT.165</name>
          <addressOffset>0xa94</addressOffset>
          <size>0x20</size>
        </register>
        <register>
          <name>BGCLUT.166</name>
          <addressOffset>0xa98</addressOffset>
          <size>0x20</size>
        </register>
        <register>
          <name>BGCLUT.167</name>
          <addressOffset>0xa9c</addressOffset>
          <size>0x20</size>
        </register>
        <register>
          <name>BGCLUT.168</name>
          <addressOffset>0xaa0</addressOffset>
          <size>0x20</size>
        </register>
        <register>
          <name>BGCLUT.169</name>
          <addressOffset>0xaa4</addressOffset>
          <size>0x20</size>
        </register>
        <register>
          <name>BGCLUT.170</name>
          <addressOffset>0xaa8</addressOffset>
          <size>0x20</size>
        </register>
        <register>
          <name>BGCLUT.171</name>
          <addressOffset>0xaac</addressOffset>
          <size>0x20</size>
        </register>
        <register>
          <name>BGCLUT.172</name>
          <addressOffset>0xab0</addressOffset>
          <size>0x20</size>
        </register>
        <register>
          <name>BGCLUT.173</name>
          <addressOffset>0xab4</addressOffset>
          <size>0x20</size>
        </register>
        <register>
          <name>BGCLUT.174</name>
          <addressOffset>0xab8</addressOffset>
          <size>0x20</size>
        </register>
        <register>
          <name>BGCLUT.175</name>
          <addressOffset>0xabc</addressOffset>
          <size>0x20</size>
        </register>
        <register>
          <name>BGCLUT.176</name>
          <addressOffset>0xac0</addressOffset>
          <size>0x20</size>
        </register>
        <register>
          <name>BGCLUT.177</name>
          <addressOffset>0xac4</addressOffset>
          <size>0x20</size>
        </register>
        <register>
          <name>BGCLUT.178</name>
          <addressOffset>0xac8</addressOffset>
          <size>0x20</size>
        </register>
        <register>
          <name>BGCLUT.179</name>
          <addressOffset>0xacc</addressOffset>
          <size>0x20</size>
        </register>
        <register>
          <name>BGCLUT.180</name>
          <addressOffset>0xad0</addressOffset>
          <size>0x20</size>
        </register>
        <register>
          <name>BGCLUT.181</name>
          <addressOffset>0xad4</addressOffset>
          <size>0x20</size>
        </register>
        <register>
          <name>BGCLUT.182</name>
          <addressOffset>0xad8</addressOffset>
          <size>0x20</size>
        </register>
        <register>
          <name>BGCLUT.183</name>
          <addressOffset>0xadc</addressOffset>
          <size>0x20</size>
        </register>
        <register>
          <name>BGCLUT.184</name>
          <addressOffset>0xae0</addressOffset>
          <size>0x20</size>
        </register>
        <register>
          <name>BGCLUT.185</name>
          <addressOffset>0xae4</addressOffset>
          <size>0x20</size>
        </register>
        <register>
          <name>BGCLUT.186</name>
          <addressOffset>0xae8</addressOffset>
          <size>0x20</size>
        </register>
        <register>
          <name>BGCLUT.187</name>
          <addressOffset>0xaec</addressOffset>
          <size>0x20</size>
        </register>
        <register>
          <name>BGCLUT.188</name>
          <addressOffset>0xaf0</addressOffset>
          <size>0x20</size>
        </register>
        <register>
          <name>BGCLUT.189</name>
          <addressOffset>0xaf4</addressOffset>
          <size>0x20</size>
        </register>
        <register>
          <name>BGCLUT.190</name>
          <addressOffset>0xaf8</addressOffset>
          <size>0x20</size>
        </register>
        <register>
          <name>BGCLUT.191</name>
          <addressOffset>0xafc</addressOffset>
          <size>0x20</size>
        </register>
        <register>
          <name>BGCLUT.192</name>
          <addressOffset>0xb00</addressOffset>
          <size>0x20</size>
        </register>
        <register>
          <name>BGCLUT.193</name>
          <addressOffset>0xb04</addressOffset>
          <size>0x20</size>
        </register>
        <register>
          <name>BGCLUT.194</name>
          <addressOffset>0xb08</addressOffset>
          <size>0x20</size>
        </register>
        <register>
          <name>BGCLUT.195</name>
          <addressOffset>0xb0c</addressOffset>
          <size>0x20</size>
        </register>
        <register>
          <name>BGCLUT.196</name>
          <addressOffset>0xb10</addressOffset>
          <size>0x20</size>
        </register>
        <register>
          <name>BGCLUT.197</name>
          <addressOffset>0xb14</addressOffset>
          <size>0x20</size>
        </register>
        <register>
          <name>BGCLUT.198</name>
          <addressOffset>0xb18</addressOffset>
          <size>0x20</size>
        </register>
        <register>
          <name>BGCLUT.199</name>
          <addressOffset>0xb1c</addressOffset>
          <size>0x20</size>
        </register>
        <register>
          <name>BGCLUT.200</name>
          <addressOffset>0xb20</addressOffset>
          <size>0x20</size>
        </register>
        <register>
          <name>BGCLUT.201</name>
          <addressOffset>0xb24</addressOffset>
          <size>0x20</size>
        </register>
        <register>
          <name>BGCLUT.202</name>
          <addressOffset>0xb28</addressOffset>
          <size>0x20</size>
        </register>
        <register>
          <name>BGCLUT.203</name>
          <addressOffset>0xb2c</addressOffset>
          <size>0x20</size>
        </register>
        <register>
          <name>BGCLUT.204</name>
          <addressOffset>0xb30</addressOffset>
          <size>0x20</size>
        </register>
        <register>
          <name>BGCLUT.205</name>
          <addressOffset>0xb34</addressOffset>
          <size>0x20</size>
        </register>
        <register>
          <name>BGCLUT.206</name>
          <addressOffset>0xb38</addressOffset>
          <size>0x20</size>
        </register>
        <register>
          <name>BGCLUT.207</name>
          <addressOffset>0xb3c</addressOffset>
          <size>0x20</size>
        </register>
        <register>
          <name>BGCLUT.208</name>
          <addressOffset>0xb40</addressOffset>
          <size>0x20</size>
        </register>
        <register>
          <name>BGCLUT.209</name>
          <addressOffset>0xb44</addressOffset>
          <size>0x20</size>
        </register>
        <register>
          <name>BGCLUT.210</name>
          <addressOffset>0xb48</addressOffset>
          <size>0x20</size>
        </register>
        <register>
          <name>BGCLUT.211</name>
          <addressOffset>0xb4c</addressOffset>
          <size>0x20</size>
        </register>
        <register>
          <name>BGCLUT.212</name>
          <addressOffset>0xb50</addressOffset>
          <size>0x20</size>
        </register>
        <register>
          <name>BGCLUT.213</name>
          <addressOffset>0xb54</addressOffset>
          <size>0x20</size>
        </register>
        <register>
          <name>BGCLUT.214</name>
          <addressOffset>0xb58</addressOffset>
          <size>0x20</size>
        </register>
        <register>
          <name>BGCLUT.215</name>
          <addressOffset>0xb5c</addressOffset>
          <size>0x20</size>
        </register>
        <register>
          <name>BGCLUT.216</name>
          <addressOffset>0xb60</addressOffset>
          <size>0x20</size>
        </register>
        <register>
          <name>BGCLUT.217</name>
          <addressOffset>0xb64</addressOffset>
          <size>0x20</size>
        </register>
        <register>
          <name>BGCLUT.218</name>
          <addressOffset>0xb68</addressOffset>
          <size>0x20</size>
        </register>
        <register>
          <name>BGCLUT.219</name>
          <addressOffset>0xb6c</addressOffset>
          <size>0x20</size>
        </register>
        <register>
          <name>BGCLUT.220</name>
          <addressOffset>0xb70</addressOffset>
          <size>0x20</size>
        </register>
        <register>
          <name>BGCLUT.221</name>
          <addressOffset>0xb74</addressOffset>
          <size>0x20</size>
        </register>
        <register>
          <name>BGCLUT.222</name>
          <addressOffset>0xb78</addressOffset>
          <size>0x20</size>
        </register>
        <register>
          <name>BGCLUT.223</name>
          <addressOffset>0xb7c</addressOffset>
          <size>0x20</size>
        </register>
        <register>
          <name>BGCLUT.224</name>
          <addressOffset>0xb80</addressOffset>
          <size>0x20</size>
        </register>
        <register>
          <name>BGCLUT.225</name>
          <addressOffset>0xb84</addressOffset>
          <size>0x20</size>
        </register>
        <register>
          <name>BGCLUT.226</name>
          <addressOffset>0xb88</addressOffset>
          <size>0x20</size>
        </register>
        <register>
          <name>BGCLUT.227</name>
          <addressOffset>0xb8c</addressOffset>
          <size>0x20</size>
        </register>
        <register>
          <name>BGCLUT.228</name>
          <addressOffset>0xb90</addressOffset>
          <size>0x20</size>
        </register>
        <register>
          <name>BGCLUT.229</name>
          <addressOffset>0xb94</addressOffset>
          <size>0x20</size>
        </register>
        <register>
          <name>BGCLUT.230</name>
          <addressOffset>0xb98</addressOffset>
          <size>0x20</size>
        </register>
        <register>
          <name>BGCLUT.231</name>
          <addressOffset>0xb9c</addressOffset>
          <size>0x20</size>
        </register>
        <register>
          <name>BGCLUT.232</name>
          <addressOffset>0xba0</addressOffset>
          <size>0x20</size>
        </register>
        <register>
          <name>BGCLUT.233</name>
          <addressOffset>0xba4</addressOffset>
          <size>0x20</size>
        </register>
        <register>
          <name>BGCLUT.234</name>
          <addressOffset>0xba8</addressOffset>
          <size>0x20</size>
        </register>
        <register>
          <name>BGCLUT.235</name>
          <addressOffset>0xbac</addressOffset>
          <size>0x20</size>
        </register>
        <register>
          <name>BGCLUT.236</name>
          <addressOffset>0xbb0</addressOffset>
          <size>0x20</size>
        </register>
        <register>
          <name>BGCLUT.237</name>
          <addressOffset>0xbb4</addressOffset>
          <size>0x20</size>
        </register>
        <register>
          <name>BGCLUT.238</name>
          <addressOffset>0xbb8</addressOffset>
          <size>0x20</size>
        </register>
        <register>
          <name>BGCLUT.239</name>
          <addressOffset>0xbbc</addressOffset>
          <size>0x20</size>
        </register>
        <register>
          <name>BGCLUT.240</name>
          <addressOffset>0xbc0</addressOffset>
          <size>0x20</size>
        </register>
        <register>
          <name>BGCLUT.241</name>
          <addressOffset>0xbc4</addressOffset>
          <size>0x20</size>
        </register>
        <register>
          <name>BGCLUT.242</name>
          <addressOffset>0xbc8</addressOffset>
          <size>0x20</size>
        </register>
        <register>
          <name>BGCLUT.243</name>
          <addressOffset>0xbcc</addressOffset>
          <size>0x20</size>
        </register>
        <register>
          <name>BGCLUT.244</name>
          <addressOffset>0xbd0</addressOffset>
          <size>0x20</size>
        </register>
        <register>
          <name>BGCLUT.245</name>
          <addressOffset>0xbd4</addressOffset>
          <size>0x20</size>
        </register>
        <register>
          <name>BGCLUT.246</name>
          <addressOffset>0xbd8</addressOffset>
          <size>0x20</size>
        </register>
        <register>
          <name>BGCLUT.247</name>
          <addressOffset>0xbdc</addressOffset>
          <size>0x20</size>
        </register>
        <register>
          <name>BGCLUT.248</name>
          <addressOffset>0xbe0</addressOffset>
          <size>0x20</size>
        </register>
        <register>
          <name>BGCLUT.249</name>
          <addressOffset>0xbe4</addressOffset>
          <size>0x20</size>
        </register>
        <register>
          <name>BGCLUT.250</name>
          <addressOffset>0xbe8</addressOffset>
          <size>0x20</size>
        </register>
        <register>
          <name>BGCLUT.251</name>
          <addressOffset>0xbec</addressOffset>
          <size>0x20</size>
        </register>
        <register>
          <name>BGCLUT.252</name>
          <addressOffset>0xbf0</addressOffset>
          <size>0x20</size>
        </register>
        <register>
          <name>BGCLUT.253</name>
          <addressOffset>0xbf4</addressOffset>
          <size>0x20</size>
        </register>
        <register>
          <name>BGCLUT.254</name>
          <addressOffset>0xbf8</addressOffset>
          <size>0x20</size>
        </register>
        <register>
          <name>BGCLUT.255</name>
          <addressOffset>0xbfc</addressOffset>
          <size>0x20</size>
        </register>
      </registers>
    </peripheral>
    <peripheral>
      <name>FLASH</name>
      <baseAddress>0x52002000</baseAddress>
      <registers>
        <register>
          <name>ACR</name>
          <addressOffset>0x0</addressOffset>
          <size>0x20</size>
          <fields>
            <field>
              <name>WRHIGHFREQ</name>
              <bitOffset>4</bitOffset>
              <bitWidth>2</bitWidth>
            </field>
          </fields>
        </register>
        <register>
          <name>KEYR1</name>
          <addressOffset>0x4</addressOffset>
          <size>0x20</size>
        </register>
        <register>
          <name>OPTKEYR</name>
          <addressOffset>0x8</addressOffset>
          <size>0x20</size>
        </register>
        <register>
          <name>CR1</name>
          <addressOffset>0xc</addressOffset>
          <size>0x20</size>
        </register>
        <register>
          <name>SR1</name>
          <addressOffset>0x10</addressOffset>
          <size>0x20</size>
        </register>
        <register>
          <name>CCR1</name>
          <addressOffset>0x14</addressOffset>
          <size>0x20</size>
        </register>
        <register>
          <name>OPTCR</name>
          <addressOffset>0x18</addressOffset>
          <size>0x20</size>
          <fields>
            <field>
              <name>OPTLOCK</name>
              <bitOffset>0</bitOffset>
              <bitWidth>1</bitWidth>
            </field>
            <field>
              <name>OPTSTART</name>
              <bitOffset>1</bitOffset>
              <bitWidth>1</bitWidth>
            </field>
            <field>
              <name>OPTCHANGEERRIE</name>
              <bitOffset>30</bitOffset>
              <bitWidth>1</bitWidth>
            </field>
          </fields>
        </register>
        <register>
          <name>OPTSR_CUR</name>
          <addressOffset>0x1c</addressOffset>
          <size>0x20</size>
        </register>
        <register>
          <name>OPTSR_PRG</name>
          <addressOffset>0x20</addressOffset>
          <size>0x20</size>
        </register>
        <register>
          <name>OPTCCR</name>
          <addressOffset>0x24</addressOffset>
          <size>0x20</size>
          <fields>
            <field>
              <name>CLR_OPTCHANGEERR</name>
              <bitOffset>30</bitOffset>
              <bitWidth>1</bitWidth>
            </field>
          </fields>
        </register>
        <register>
          <name>PRAR_CUR1</name>
          <addressOffset>0x28</addressOffset>
          <size>0x20</size>
        </register>
        <register>
          <name>PRAR_PRG1</name>
          <addressOffset>0x2c</addressOffset>
          <size>0x20</size>
        </register>
        <register>
          <name>SCAR_CUR1</name>
          <addressOffset>0x30</addressOffset>
          <size>0x20</size>
        </register>
        <register>
          <name>SCAR_PRG1</name>
          <addressOffset>0x34</addressOffset>
          <size>0x20</size>
        </register>
        <register>
          <name>WPSN_CUR1</name>
          <addressOffset>0x38</addressOffset>
          <size>0x20</size>
        </register>
        <register>
          <name>WPSN_PRG1</name>
          <addressOffset>0x3c</addressOffset>
          <size>0x20</size>
        </register>
        <register>
          <name>BOOT_CUR</name>
          <addressOffset>0x40</addressOffset>
          <size>0x20</size>
        </register>
        <register>
          <name>BOOT_PRG</name>
          <addressOffset>0x44</addressOffset>
          <size>0x20</size>
        </register>
        <register>
          <name>CRCCR1</name>
          <addressOffset>0x50</addressOffset>
          <size>0x20</size>
        </register>
        <register>
          <name>CRCSADD1</name>
          <addressOffset>0x54</addressOffset>
          <size>0x20</size>
        </register>
        <register>
          <name>CRCEADD1</name>
          <addressOffset>0x58</addressOffset>
          <size>0x20</size>
        </register>
        <register>
          <name>CRCDATA</name>
          <addressOffset>0x5c</addressOffset>
          <size>0x20</size>
          <fields>
            <field>
              <name>CRC_DATA</name>
              <bitOffset>0</bitOffset>
              <bitWidth>32</bitWidth>
            </field>
          </fields>
        </register>
        <register>
          <name>ECC_FA1</name>
          <addressOffset>0x60</addressOffset>
          <size>0x20</size>
        </register>
        <register>
          <name>OPTSR2_CUR</name>
          <addressOffset>0x70</addressOffset>
          <size>0x20</size>
        </register>
        <register>
          <name>OPTSR2_PRG</name>
          <addressOffset>0x74</addressOffset>
          <size>0x20</size>
        </register>
      </registers>
    </peripheral>
    <peripheral>
      <name>FMC_Bank1_R</name>
      <baseAddress>0x52004000</baseAddress>
      <registers>
        <register>
          <name>BTCR.0</name>
          <addressOffset>0x0</addressOffset>
          <size>0x20</size>
        </register>
        <register>
          <name>BTCR.1</name>
          <addressOffset>0x4</addressOffset>
          <size>0x20</size>
        </register>
        <register>
          <name>BTCR.2</name>
          <addressOffset>0x8</addressOffset>
          <size>0x20</size>
        </register>
        <register>
          <name>BTCR.3</name>
          <addressOffset>0xc</addressOffset>
          <size>0x20</size>
        </register>
        <register>
          <name>BTCR.4</name>
          <addressOffset>0x10</addressOffset>
          <size>0x20</size>
        </register>
        <register>
          <name>BTCR.5</name>
          <addressOffset>0x14</addressOffset>
          <size>0x20</size>
        </register>
        <register>
          <name>BTCR.6</name>
          <addressOffset>0x18</addressOffset>
          <size>0x20</size>
        </register>
        <register>
          <name>BTCR.7</name>
          <addressOffset>0x1c</addressOffset>
          <size>0x20</size>
        </register>
      </registers>
    </peripheral>
    <peripheral>
      <name>FMC_Bank2_R</name>
      <baseAddress>0x52004060</baseAddress>
      <registers>
        <register>
          <name>PCR2</name>
          <addressOffset>0x0</addressOffset>
          <size>0x20</size>
        </register>
        <register>
          <name>SR2</name>
          <addressOffset>0x4</addressOffset>
          <size>0x20</size>
        </register>
        <register>
          <name>PMEM2</name>
          <addressOffset>0x8</addressOffset>
          <size>0x20</size>
        </register>
        <register>
          <name>PATT2</name>
          <addressOffset>0xc</addressOffset>
          <size>0x20</size>
        </register>
        <register>
          <name>ECCR2</name>
          <addressOffset>0x14</addressOffset>
          <size>0x20</size>
        </register>
      </registers>
    </peripheral>
    <peripheral>
      <name>FMC_Bank3_R</name>
      <baseAddress>0x52004080</baseAddress>
      <registers>
        <register>
          <name>PCR</name>
          <addressOffset>0x0</addressOffset>
          <size>0x20</size>
          <fields>
            <field>
              <name>PWAITEN</name>
              <bitOffset>1</bitOffset>
              <bitWidth>1</bitWidth>
            </field>
            <field>
              <name>PBKEN</name>
              <bitOffset>2</bitOffset>
              <bitWidth>1</bitWidth>
            </field>
            <field>
              <name>PWID</name>
              <bitOffset>4</bitOffset>
              <bitWidth>2</bitWidth>
            </field>
            <field>
              <name>ECCEN</name>
              <bitOffset>6</bitOffset>
              <bitWidth>1</bitWidth>
            </field>
            <field>
              <name>TCLR</name>
              <bitOffset>9</bitOffset>
              <bitWidth>4</bitWidth>
            </field>
            <field>
              <name>TAR</name>
              <bitOffset>13</bitOffset>
              <bitWidth>4</bitWidth>
            </field>
            <field>
              <name>ECCPS</name>
              <bitOffset>17</bitOffset>
              <bitWidth>3</bitWidth>
            </field>
          </fields>
        </register>
        <register>
          <name>SR</name>
          <addressOffset>0x4</addressOffset>
          <size>0x20</size>
          <fields>
            <field>
              <name>IRS</name>
              <bitOffset>0</bitOffset>
              <bitWidth>1</bitWidth>
            </field>
            <field>
              <name>ILS</name>
              <bitOffset>1</bitOffset>
              <bitWidth>1</bitWidth>
            </field>
            <field>
              <name>IFS</name>
              <bitOffset>2</bitOffset>
              <bitWidth>1</bitWidth>
            </field>
            <field>
              <name>IREN</name>
              <bitOffset>3</bitOffset>
              <bitWidth>1</bitWidth>
            </field>
            <field>
              <name>ILEN</name>
              <bitOffset>4</bitOffset>
              <bitWidth>1</bitWidth>
            </field>
            <field>
              <name>IFEN</name>
              <bitOffset>5</bitOffset>
              <bitWidth>1</bitWidth>
            </field>
            <field>
              <name>FEMPT</name>
              <bitOffset>6</bitOffset>
              <bitWidth>1</bitWidth>
            </field>
          </fields>
        </register>
        <register>
          <name>PMEM</name>
          <addressOffset>0x8</addressOffset>
          <size>0x20</size>
          <fields>
            <field>
              <name>MEMSET</name>
              <bitOffset>0</bitOffset>
              <bitWidth>8</bitWidth>
            </field>
            <field>
              <name>MEMWAIT</name>
              <bitOffset>8</bitOffset>
              <bitWidth>8</bitWidth>
            </field>
            <field>
              <name>MEMHOLD</name>
              <bitOffset>16</bitOffset>
              <bitWidth>8</bitWidth>
            </field>
            <field>
              <name>MEMHIZ</name>
              <bitOffset>24</bitOffset>
              <bitWidth>8</bitWidth>
            </field>
          </fields>
        </register>
        <register>
          <name>PATT</name>
          <addressOffset>0xc</addressOffset>
          <size>0x20</size>
          <fields>
            <field>
              <name>ATTSET</name>
              <bitOffset>0</bitOffset>
              <bitWidth>8</bitWidth>
            </field>
            <field>
              <name>ATTWAIT</name>
              <bitOffset>8</bitOffset>
              <bitWidth>8</bitWidth>
            </field>
            <field>
              <name>ATTHOLD</name>
              <bitOffset>16</bitOffset>
              <bitWidth>8</bitWidth>
            </field>
            <field>
              <name>ATTHIZ</name>
              <bitOffset>24</bitOffset>
              <bitWidth>8</bitWidth>
            </field>
          </fields>
        </register>
        <register>
          <name>ECCR</name>
          <addressOffset>0x14</addressOffset>
          <size>0x20</size>
        </register>
      </registers>
    </peripheral>
    <peripheral>
      <name>FMC_Bank1E_R</name>
      <baseAddress>0x52004104</baseAddress>
      <registers>
        <register>
          <name>BWTR.0</name>
          <addressOffset>0x0</addressOffset>
          <size>0x20</size>
          <fields>
            <field>
              <name>ADDSET</name>
              <bitOffset>0</bitOffset>
              <bitWidth>4</bitWidth>
            </field>
            <field>
              <name>ADDHLD</name>
              <bitOffset>4</bitOffset>
              <bitWidth>4</bitWidth>
            </field>
            <field>
              <name>DATAST</name>
              <bitOffset>8</bitOffset>
              <bitWidth>8</bitWidth>
            </field>
            <field>
              <name>BUSTURN</name>
              <bitOffset>16</bitOffset>
              <bitWidth>4</bitWidth>
            </field>
            <field>
              <name>ACCMOD</name>
              <bitOffset>28</bitOffset>
              <bitWidth>2</bitWidth>
            </field>
          </fields>
        </register>
        <register>
          <name>BWTR.1</name>
          <addressOffset>0x4</addressOffset>
          <size>0x20</size>
          <fields>
            <field>
              <name>ADDSET</name>
              <bitOffset>0</bitOffset>
              <bitWidth>4</bitWidth>
            </field>
            <field>
              <name>ADDHLD</name>
              <bitOffset>4</bitOffset>
              <bitWidth>4</bitWidth>
            </field>
            <field>
              <name>DATAST</name>
              <bitOffset>8</bitOffset>
              <bitWidth>8</bitWidth>
            </field>
            <field>
              <name>BUSTURN</name>
              <bitOffset>16</bitOffset>
              <bitWidth>4</bitWidth>
            </field>
            <field>
              <name>ACCMOD</name>
              <bitOffset>28</bitOffset>
              <bitWidth>2</bitWidth>
            </field>
          </fields>
        </register>
        <register>
          <name>BWTR.2</name>
          <addressOffset>0x8</addressOffset>
          <size>0x20</size>
          <fields>
            <field>
              <name>ADDSET</name>
              <bitOffset>0</bitOffset>
              <bitWidth>4</bitWidth>
            </field>
            <field>
              <name>ADDHLD</name>
              <bitOffset>4</bitOffset>
              <bitWidth>4</bitWidth>
            </field>
            <field>
              <name>DATAST</name>
              <bitOffset>8</bitOffset>
              <bitWidth>8</bitWidth>
            </field>
            <field>
              <name>BUSTURN</name>
              <bitOffset>16</bitOffset>
              <bitWidth>4</bitWidth>
            </field>
            <field>
              <name>ACCMOD</name>
              <bitOffset>28</bitOffset>
              <bitWidth>2</bitWidth>
            </field>
          </fields>
        </register>
        <register>
          <name>BWTR.3</name>
          <addressOffset>0xc</addressOffset>
          <size>0x20</size>
          <fields>
            <field>
              <name>ADDSET</name>
              <bitOffset>0</bitOffset>
              <bitWidth>4</bitWidth>
            </field>
            <field>
              <name>ADDHLD</name>
              <bitOffset>4</bitOffset>
              <bitWidth>4</bitWidth>
            </field>
            <field>
              <name>DATAST</name>
              <bitOffset>8</bitOffset>
              <bitWidth>8</bitWidth>
            </field>
            <field>
              <name>BUSTURN</name>
              <bitOffset>16</bitOffset>
              <bitWidth>4</bitWidth>
            </field>
            <field>
              <name>ACCMOD</name>
              <bitOffset>28</bitOffset>
              <bitWidth>2</bitWidth>
            </field>
          </fields>
        </register>
        <register>
          <name>BWTR.4</name>
          <addressOffset>0x10</addressOffset>
          <size>0x20</size>
          <fields>
            <field>
              <name>ADDSET</name>
              <bitOffset>0</bitOffset>
              <bitWidth>4</bitWidth>
            </field>
            <field>
              <name>ADDHLD</name>
              <bitOffset>4</bitOffset>
              <bitWidth>4</bitWidth>
            </field>
            <field>
              <name>DATAST</name>
              <bitOffset>8</bitOffset>
              <bitWidth>8</bitWidth>
            </field>
            <field>
              <name>BUSTURN</name>
              <bitOffset>16</bitOffset>
              <bitWidth>4</bitWidth>
            </field>
            <field>
              <name>ACCMOD</name>
              <bitOffset>28</bitOffset>
              <bitWidth>2</bitWidth>
            </field>
          </fields>
        </register>
        <register>
          <name>BWTR.5</name>
          <addressOffset>0x14</addressOffset>
          <size>0x20</size>
          <fields>
            <field>
              <name>ADDSET</name>
              <bitOffset>0</bitOffset>
              <bitWidth>4</bitWidth>
            </field>
            <field>
              <name>ADDHLD</name>
              <bitOffset>4</bitOffset>
              <bitWidth>4</bitWidth>
            </field>
            <field>
              <name>DATAST</name>
              <bitOffset>8</bitOffset>
              <bitWidth>8</bitWidth>
            </field>
            <field>
              <name>BUSTURN</name>
              <bitOffset>16</bitOffset>
              <bitWidth>4</bitWidth>
            </field>
            <field>
              <name>ACCMOD</name>
              <bitOffset>28</bitOffset>
              <bitWidth>2</bitWidth>
            </field>
          </fields>
        </register>
        <register>
          <name>BWTR.6</name>
          <addressOffset>0x18</addressOffset>
          <size>0x20</size>
          <fields>
            <field>
              <name>ADDSET</name>
              <bitOffset>0</bitOffset>
              <bitWidth>4</bitWidth>
            </field>
            <field>
              <name>ADDHLD</name>
              <bitOffset>4</bitOffset>
              <bitWidth>4</bitWidth>
            </field>
            <field>
              <name>DATAST</name>
              <bitOffset>8</bitOffset>
              <bitWidth>8</bitWidth>
            </field>
            <field>
              <name>BUSTURN</name>
              <bitOffset>16</bitOffset>
              <bitWidth>4</bitWidth>
            </field>
            <field>
              <name>ACCMOD</name>
              <bitOffset>28</bitOffset>
              <bitWidth>2</bitWidth>
            </field>
          </fields>
        </register>
      </registers>
    </peripheral>
    <peripheral>
      <name>FMC_Bank5_6_R</name>
      <baseAddress>0x52004140</baseAddress>
      <registers>
        <register>
          <name>SDCR.0</name>
          <addressOffset>0x0</addressOffset>
          <size>0x20</size>
          <fields>
            <field>
              <name>NC</name>
              <bitOffset>0</bitOffset>
              <bitWidth>2</bitWidth>
            </field>
            <field>
              <name>NR</name>
              <bitOffset>2</bitOffset>
              <bitWidth>2</bitWidth>
            </field>
            <field>
              <name>MWID</name>
              <bitOffset>4</bitOffset>
              <bitWidth>2</bitWidth>
            </field>
            <field>
              <name>NB</name>
              <bitOffset>6</bitOffset>
              <bitWidth>1</bitWidth>
            </field>
            <field>
              <name>CAS</name>
              <bitOffset>7</bitOffset>
              <bitWidth>2</bitWidth>
            </field>
            <field>
              <name>WP</name>
              <bitOffset>9</bitOffset>
              <bitWidth>1</bitWidth>
            </field>
            <field>
              <name>SDCLK</name>
              <bitOffset>10</bitOffset>
              <bitWidth>2</bitWidth>
            </field>
            <field>
              <name>RBURST</name>
              <bitOffset>12</bitOffset>
              <bitWidth>1</bitWidth>
            </field>
            <field>
              <name>RPIPE</name>
              <bitOffset>13</bitOffset>
              <bitWidth>2</bitWidth>
            </field>
          </fields>
        </register>
        <register>
          <name>SDCR.1</name>
          <addressOffset>0x4</addressOffset>
          <size>0x20</size>
          <fields>
            <field>
              <name>NC</name>
              <bitOffset>0</bitOffset>
              <bitWidth>2</bitWidth>
            </field>
            <field>
              <name>NR</name>
              <bitOffset>2</bitOffset>
              <bitWidth>2</bitWidth>
            </field>
            <field>
              <name>MWID</name>
              <bitOffset>4</bitOffset>
              <bitWidth>2</bitWidth>
            </field>
            <field>
              <name>NB</name>
              <bitOffset>6</bitOffset>
              <bitWidth>1</bitWidth>
            </field>
            <field>
              <name>CAS</name>
              <bitOffset>7</bitOffset>
              <bitWidth>2</bitWidth>
            </field>
            <field>
              <name>WP</name>
              <bitOffset>9</bitOffset>
              <bitWidth>1</bitWidth>
            </field>
            <field>
              <name>SDCLK</name>
              <bitOffset>10</bitOffset>
              <bitWidth>2</bitWidth>
            </field>
            <field>
              <name>RBURST</name>
              <bitOffset>12</bitOffset>
              <bitWidth>1</bitWidth>
            </field>
            <field>
              <name>RPIPE</name>
              <bitOffset>13</bitOffset>
              <bitWidth>2</bitWidth>
            </field>
          </fields>
        </register>
        <register>
          <name>SDTR.0</name>
          <addressOffset>0x8</addressOffset>
          <size>0x20</size>
          <fields>
            <field>
              <name>TMRD</name>
              <bitOffset>0</bitOffset>
              <bitWidth>4</bitWidth>
            </field>
            <field>
              <name>TXSR</name>
              <bitOffset>4</bitOffset>
              <bitWidth>4</bitWidth>
            </field>
            <field>
              <name>TRAS</name>
              <bitOffset>8</bitOffset>
              <bitWidth>4</bitWidth>
            </field>
            <field>
              <name>TRC</name>
              <bitOffset>12</bitOffset>
              <bitWidth>4</bitWidth>
            </field>
            <field>
              <name>TWR</name>
              <bitOffset>16</bitOffset>
              <bitWidth>4</bitWidth>
            </field>
            <field>
              <name>TRP</name>
              <bitOffset>20</bitOffset>
              <bitWidth>4</bitWidth>
            </field>
            <field>
              <name>TRCD</name>
              <bitOffset>24</bitOffset>
              <bitWidth>4</bitWidth>
            </field>
          </fields>
        </register>
        <register>
          <name>SDTR.1</name>
          <addressOffset>0xc</addressOffset>
          <size>0x20</size>
          <fields>
            <field>
              <name>TMRD</name>
              <bitOffset>0</bitOffset>
              <bitWidth>4</bitWidth>
            </field>
            <field>
              <name>TXSR</name>
              <bitOffset>4</bitOffset>
              <bitWidth>4</bitWidth>
            </field>
            <field>
              <name>TRAS</name>
              <bitOffset>8</bitOffset>
              <bitWidth>4</bitWidth>
            </field>
            <field>
              <name>TRC</name>
              <bitOffset>12</bitOffset>
              <bitWidth>4</bitWidth>
            </field>
            <field>
              <name>TWR</name>
              <bitOffset>16</bitOffset>
              <bitWidth>4</bitWidth>
            </field>
            <field>
              <name>TRP</name>
              <bitOffset>20</bitOffset>
              <bitWidth>4</bitWidth>
            </field>
            <field>
              <name>TRCD</name>
              <bitOffset>24</bitOffset>
              <bitWidth>4</bitWidth>
            </field>
          </fields>
        </register>
        <register>
          <name>SDCMR</name>
          <addressOffset>0x10</addressOffset>
          <size>0x20</size>
          <fields>
            <field>
              <name>MODE</name>
              <bitOffset>0</bitOffset>
              <bitWidth>3</bitWidth>
            </field>
            <field>
              <name>CTB2</name>
              <bitOffset>3</bitOffset>
              <bitWidth>1</bitWidth>
            </field>
            <field>
              <name>CTB1</name>
              <bitOffset>4</bitOffset>
              <bitWidth>1</bitWidth>
            </field>
            <field>
              <name>NRFS</name>
              <bitOffset>5</bitOffset>
              <bitWidth>4</bitWidth>
            </field>
            <field>
              <name>MRD</name>
              <bitOffset>9</bitOffset>
              <bitWidth>13</bitWidth>
            </field>
          </fields>
        </register>
        <register>
          <name>SDRTR</name>
          <addressOffset>0x14</addressOffset>
          <size>0x20</size>
          <fields>
            <field>
              <name>CRE</name>
              <bitOffset>0</bitOffset>
              <bitWidth>1</bitWidth>
            </field>
            <field>
              <name>COUNT</name>
              <bitOffset>1</bitOffset>
              <bitWidth>13</bitWidth>
            </field>
            <field>
              <name>REIE</name>
              <bitOffset>14</bitOffset>
              <bitWidth>1</bitWidth>
            </field>
          </fields>
        </register>
        <register>
          <name>SDSR</name>
          <addressOffset>0x18</addressOffset>
          <size>0x20</size>
          <fields>
            <field>
              <name>RE</name>
              <bitOffset>0</bitOffset>
              <bitWidth>1</bitWidth>
            </field>
            <field>
              <name>MODES1</name>
              <bitOffset>1</bitOffset>
              <bitWidth>2</bitWidth>
            </field>
            <field>
              <name>MODES2</name>
              <bitOffset>3</bitOffset>
              <bitWidth>2</bitWidth>
            </field>
          </fields>
        </register>
      </registers>
    </peripheral>
    <peripheral>
      <name>OCTOSPI1</name>
      <baseAddress>0x52005000</baseAddress>
      <registers>
        <register>
          <name>CR</name>
          <addressOffset>0x0</addressOffset>
          <size>0x20</size>
          <fields>
            <field>
              <name>EN</name>
              <bitOffset>0</bitOffset>
              <bitWidth>1</bitWidth>
            </field>
            <field>
              <name>ABORT</name>
              <bitOffset>1</bitOffset>
              <bitWidth>1</bitWidth>
            </field>
            <field>
              <name>DMAEN</name>
              <bitOffset>2</bitOffset>
              <bitWidth>1</bitWidth>
            </field>
            <field>
              <name>TCEN</name>
              <bitOffset>3</bitOffset>
              <bitWidth>1</bitWidth>
            </field>
            <field>
              <name>DQM</name>
              <bitOffset>6</bitOffset>
              <bitWidth>1</bitWidth>
            </field>
            <field>
              <name>FSEL</name>
              <bitOffset>7</bitOffset>
              <bitWidth>1</bitWidth>
            </field>
            <field>
              <name>FTHRES</name>
              <bitOffset>8</bitOffset>
              <bitWidth>5</bitWidth>
            </field>
            <field>
              <name>TEIE</name>
              <bitOffset>16</bitOffset>
              <bitWidth>1</bitWidth>
            </field>
            <field>
              <name>TCIE</name>
              <bitOffset>17</bitOffset>
              <bitWidth>1</bitWidth>
            </field>
            <field>
              <name>FTIE</name>
              <bitOffset>18</bitOffset>
              <bitWidth>1</bitWidth>
            </field>
            <field>
              <name>SMIE</name>
              <bitOffset>19</bitOffset>
              <bitWidth>1</bitWidth>
            </field>
            <field>
              <name>TOIE</name>
              <bitOffset>20</bitOffset>
              <bitWidth>1</bitWidth>
            </field>
            <field>
              <name>APMS</name>
              <bitOffset>22</bitOffset>
              <bitWidth>1</bitWidth>
            </field>
            <field>
              <name>PMM</name>
              <bitOffset>23</bitOffset>
              <bitWidth>1</bitWidth>
            </field>
            <field>
              <name>FMODE</name>
              <bitOffset>28</bitOffset>
              <bitWidth>2</bitWidth>
            </field>
          </fields>
        </register>
        <register>
          <name>DCR1</name>
          <addressOffset>0x8</addressOffset>
          <size>0x20</size>
          <fields>
            <field>
              <name>CKMODE</name>
              <bitOffset>0</bitOffset>
              <bitWidth>1</bitWidth>
            </field>
            <field>
              <name>FRCK</name>
              <bitOffset>1</bitOffset>
              <bitWidth>1</bitWidth>
            </field>
            <field>
              <name>DLYBYP</name>
              <bitOffset>3</bitOffset>
              <bitWidth>1</bitWidth>
            </field>
            <field>
              <name>CKCSHT</name>
              <bitOffset>4</bitOffset>
              <bitWidth>3</bitWidth>
            </field>
            <field>
              <name>CSHT</name>
              <bitOffset>8</bitOffset>
              <bitWidth>3</bitWidth>
            </field>
            <field>
              <name>DEVSIZE</name>
              <bitOffset>16</bitOffset>
              <bitWidth>5</bitWidth>
            </field>
            <field>
              <name>MTYP</name>
              <bitOffset>24</bitOffset>
              <bitWidth>3</bitWidth>
            </field>
          </fields>
        </register>
        <register>
          <name>DCR2</name>
          <addressOffset>0xc</addressOffset>
          <size>0x20</size>
          <fields>
            <field>
              <name>PRESCALER</name>
              <bitOffset>0</bitOffset>
              <bitWidth>8</bitWidth>
            </field>
            <field>
              <name>WRAPSIZE</name>
              <bitOffset>16</bitOffset>
              <bitWidth>3</bitWidth>
            </field>
          </fields>
        </register>
        <register>
          <name>DCR3</name>
          <addressOffset>0x10</addressOffset>
          <size>0x20</size>
          <fields>
            <field>
              <name>MAXTRAN</name>
              <bitOffset>0</bitOffset>
              <bitWidth>8</bitWidth>
            </field>
            <field>
              <name>CSBOUND</name>
              <bitOffset>16</bitOffset>
              <bitWidth>5</bitWidth>
            </field>
          </fields>
        </register>
        <register>
          <name>DCR4</name>
          <addressOffset>0x14</addressOffset>
          <size>0x20</size>
          <fields>
            <field>
              <name>REFRESH</name>
              <bitOffset>0</bitOffset>
              <bitWidth>32</bitWidth>
            </field>
          </fields>
        </register>
        <register>
          <name>SR</name>
          <addressOffset>0x20</addressOffset>
          <size>0x20</size>
          <fields>
            <field>
              <name>TEF</name>
              <bitOffset>0</bitOffset>
              <bitWidth>1</bitWidth>
            </field>
            <field>
              <name>TCF</name>
              <bitOffset>1</bitOffset>
              <bitWidth>1</bitWidth>
            </field>
            <field>
              <name>FTF</name>
              <bitOffset>2</bitOffset>
              <bitWidth>1</bitWidth>
            </field>
            <field>
              <name>SMF</name>
              <bitOffset>3</bitOffset>
              <bitWidth>1</bitWidth>
            </field>
            <field>
              <name>TOF</name>
              <bitOffset>4</bitOffset>
              <bitWidth>1</bitWidth>
            </field>
            <field>
              <name>BUSY</name>
              <bitOffset>5</bitOffset>
              <bitWidth>1</bitWidth>
            </field>
            <field>
              <name>FLEVEL</name>
              <bitOffset>8</bitOffset>
              <bitWidth>6</bitWidth>
            </field>
          </fields>
        </register>
        <register>
          <name>FCR</name>
          <addressOffset>0x24</addressOffset>
          <size>0x20</size>
          <fields>
            <field>
              <name>CTEF</name>
              <bitOffset>0</bitOffset>
              <bitWidth>1</bitWidth>
            </field>
            <field>
              <name>CTCF</name>
              <bitOffset>1</bitOffset>
              <bitWidth>1</bitWidth>
            </field>
            <field>
              <name>CSMF</name>
              <bitOffset>3</bitOffset>
              <bitWidth>1</bitWidth>
            </field>
            <field>
              <name>CTOF</name>
              <bitOffset>4</bitOffset>
              <bitWidth>1</bitWidth>
            </field>
          </fields>
        </register>
        <register>
          <name>DLR</name>
          <addressOffset>0x40</addressOffset>
          <size>0x20</size>
          <fields>
            <field>
              <name>DL</name>
              <bitOffset>0</bitOffset>
              <bitWidth>32</bitWidth>
            </field>
          </fields>
        </register>
        <register>
          <name>AR</name>
          <addressOffset>0x48</addressOffset>
          <size>0x20</size>
          <fields>
            <field>
              <name>ADDRESS</name>
              <bitOffset>0</bitOffset>
              <bitWidth>32</bitWidth>
            </field>
          </fields>
        </register>
        <register>
          <name>DR</name>
          <addressOffset>0x50</addressOffset>
          <size>0x20</size>
          <fields>
            <field>
              <name>DATA</name>
              <bitOffset>0</bitOffset>
              <bitWidth>32</bitWidth>
            </field>
          </fields>
        </register>
        <register>
          <name>PSMKR</name>
          <addressOffset>0x80</addressOffset>
          <size>0x20</size>
          <fields>
            <field>
              <name>MASK</name>
              <bitOffset>0</bitOffset>
              <bitWidth>32</bitWidth>
            </field>
          </fields>
        </register>
        <register>
          <name>PSMAR</name>
          <addressOffset>0x88</addressOffset>
          <size>0x20</size>
          <fields>
            <field>
              <name>MATCH</name>
              <bitOffset>0</bitOffset>
              <bitWidth>32</bitWidth>
            </field>
          </fields>
        </register>
        <register>
          <name>PIR</name>
          <addressOffset>0x90</addressOffset>
          <size>0x20</size>
          <fields>
            <field>
              <name>INTERVAL</name>
              <bitOffset>0</bitOffset>
              <bitWidth>16</bitWidth>
            </field>
          </fields>
        </register>
        <register>
          <name>CCR</name>
          <addressOffset>0x100</addressOffset>
          <size>0x20</size>
          <fields>
            <field>
              <name>IMODE</name>
              <bitOffset>0</bitOffset>
              <bitWidth>3</bitWidth>
            </field>
            <field>
              <name>IDTR</name>
              <bitOffset>3</bitOffset>
              <bitWidth>1</bitWidth>
            </field>
            <field>
              <name>ISIZE</name>
              <bitOffset>4</bitOffset>
              <bitWidth>2</bitWidth>
            </field>
            <field>
              <name>ADMODE</name>
              <bitOffset>8</bitOffset>
              <bitWidth>3</bitWidth>
            </field>
            <field>
              <name>ADDTR</name>
              <bitOffset>11</bitOffset>
              <bitWidth>1</bitWidth>
            </field>
            <field>
              <name>ADSIZE</name>
              <bitOffset>12</bitOffset>
              <bitWidth>2</bitWidth>
            </field>
            <field>
              <name>ABMODE</name>
              <bitOffset>16</bitOffset>
              <bitWidth>3</bitWidth>
            </field>
            <field>
              <name>ABDTR</name>
              <bitOffset>19</bitOffset>
              <bitWidth>1</bitWidth>
            </field>
            <field>
              <name>ABSIZE</name>
              <bitOffset>20</bitOffset>
              <bitWidth>2</bitWidth>
            </field>
            <field>
              <name>DMODE</name>
              <bitOffset>24</bitOffset>
              <bitWidth>3</bitWidth>
            </field>
            <field>
              <name>DDTR</name>
              <bitOffset>27</bitOffset>
              <bitWidth>1</bitWidth>
            </field>
            <field>
              <name>DQSE</name>
              <bitOffset>29</bitOffset>
              <bitWidth>1</bitWidth>
            </field>
            <field>
              <name>SIOO</name>
              <bitOffset>31</bitOffset>
              <bitWidth>1</bitWidth>
            </field>
          </fields>
        </register>
        <register>
          <name>TCR</name>
          <addressOffset>0x108</addressOffset>
          <size>0x20</size>
          <fields>
            <field>
              <name>DCYC</name>
              <bitOffset>0</bitOffset>
              <bitWidth>5</bitWidth>
            </field>
            <field>
              <name>DHQC</name>
              <bitOffset>28</bitOffset>
              <bitWidth>1</bitWidth>
            </field>
            <field>
              <name>SSHIFT</name>
              <bitOffset>30</bitOffset>
              <bitWidth>1</bitWidth>
            </field>
          </fields>
        </register>
        <register>
          <name>IR</name>
          <addressOffset>0x110</addressOffset>
          <size>0x20</size>
          <fields>
            <field>
              <name>INSTRUCTION</name>
              <bitOffset>0</bitOffset>
              <bitWidth>32</bitWidth>
            </field>
          </fields>
        </register>
        <register>
          <name>ABR</name>
          <addressOffset>0x120</addressOffset>
          <size>0x20</size>
          <fields>
            <field>
              <name>ALTERNATE</name>
              <bitOffset>0</bitOffset>
              <bitWidth>32</bitWidth>
            </field>
          </fields>
        </register>
        <register>
          <name>LPTR</name>
          <addressOffset>0x130</addressOffset>
          <size>0x20</size>
          <fields>
            <field>
              <name>TIMEOUT</name>
              <bitOffset>0</bitOffset>
              <bitWidth>16</bitWidth>
            </field>
          </fields>
        </register>
        <register>
          <name>WPCCR</name>
          <addressOffset>0x140</addressOffset>
          <size>0x20</size>
          <fields>
            <field>
              <name>IMODE</name>
              <bitOffset>0</bitOffset>
              <bitWidth>3</bitWidth>
            </field>
            <field>
              <name>IDTR</name>
              <bitOffset>3</bitOffset>
              <bitWidth>1</bitWidth>
            </field>
            <field>
              <name>ISIZE</name>
              <bitOffset>4</bitOffset>
              <bitWidth>2</bitWidth>
            </field>
            <field>
              <name>ADMODE</name>
              <bitOffset>8</bitOffset>
              <bitWidth>3</bitWidth>
            </field>
            <field>
              <name>ADDTR</name>
              <bitOffset>11</bitOffset>
              <bitWidth>1</bitWidth>
            </field>
            <field>
              <name>ADSIZE</name>
              <bitOffset>12</bitOffset>
              <bitWidth>2</bitWidth>
            </field>
            <field>
              <name>ABMODE</name>
              <bitOffset>16</bitOffset>
              <bitWidth>3</bitWidth>
            </field>
            <field>
              <name>ABDTR</name>
              <bitOffset>19</bitOffset>
              <bitWidth>1</bitWidth>
            </field>
            <field>
              <name>ABSIZE</name>
              <bitOffset>20</bitOffset>
              <bitWidth>2</bitWidth>
            </field>
            <field>
              <name>DMODE</name>
              <bitOffset>24</bitOffset>
              <bitWidth>3</bitWidth>
            </field>
            <field>
              <name>DDTR</name>
              <bitOffset>27</bitOffset>
              <bitWidth>1</bitWidth>
            </field>
            <field>
              <name>DQSE</name>
              <bitOffset>29</bitOffset>
              <bitWidth>1</bitWidth>
            </field>
            <field>
              <name>SIOO</name>
              <bitOffset>31</bitOffset>
              <bitWidth>1</bitWidth>
            </field>
          </fields>
        </register>
        <register>
          <name>WPTCR</name>
          <addressOffset>0x148</addressOffset>
          <size>0x20</size>
          <fields>
            <field>
              <name>DCYC</name>
              <bitOffset>0</bitOffset>
              <bitWidth>5</bitWidth>
            </field>
            <field>
              <name>DHQC</name>
              <bitOffset>28</bitOffset>
              <bitWidth>1</bitWidth>
            </field>
            <field>
              <name>SSHIFT</name>
              <bitOffset>30</bitOffset>
              <bitWidth>1</bitWidth>
            </field>
          </fields>
        </register>
        <register>
          <name>WPIR</name>
          <addressOffset>0x150</addressOffset>
          <size>0x20</size>
          <fields>
            <field>
              <name>INSTRUCTION</name>
              <bitOffset>0</bitOffset>
              <bitWidth>32</bitWidth>
            </field>
          </fields>
        </register>
        <register>
          <name>WPABR</name>
          <addressOffset>0x160</addressOffset>
          <size>0x20</size>
          <fields>
            <field>
              <name>ALTERNATE</name>
              <bitOffset>0</bitOffset>
              <bitWidth>32</bitWidth>
            </field>
          </fields>
        </register>
        <register>
          <name>WCCR</name>
          <addressOffset>0x180</addressOffset>
          <size>0x20</size>
          <fields>
            <field>
              <name>IMODE</name>
              <bitOffset>0</bitOffset>
              <bitWidth>3</bitWidth>
            </field>
            <field>
              <name>IDTR</name>
              <bitOffset>3</bitOffset>
              <bitWidth>1</bitWidth>
            </field>
            <field>
              <name>ISIZE</name>
              <bitOffset>4</bitOffset>
              <bitWidth>2</bitWidth>
            </field>
            <field>
              <name>ADMODE</name>
              <bitOffset>8</bitOffset>
              <bitWidth>3</bitWidth>
            </field>
            <field>
              <name>ADDTR</name>
              <bitOffset>11</bitOffset>
              <bitWidth>1</bitWidth>
            </field>
            <field>
              <name>ADSIZE</name>
              <bitOffset>12</bitOffset>
              <bitWidth>2</bitWidth>
            </field>
            <field>
              <name>ABMODE</name>
              <bitOffset>16</bitOffset>
              <bitWidth>3</bitWidth>
            </field>
            <field>
              <name>ABDTR</name>
              <bitOffset>19</bitOffset>
              <bitWidth>1</bitWidth>
            </field>
            <field>
              <name>ABSIZE</name>
              <bitOffset>20</bitOffset>
              <bitWidth>2</bitWidth>
            </field>
            <field>
              <name>DMODE</name>
              <bitOffset>24</bitOffset>
              <bitWidth>3</bitWidth>
            </field>
            <field>
              <name>DDTR</name>
              <bitOffset>27</bitOffset>
              <bitWidth>1</bitWidth>
            </field>
            <field>
              <name>DQSE</name>
              <bitOffset>29</bitOffset>
              <bitWidth>1</bitWidth>
            </field>
            <field>
              <name>SIOO</name>
              <bitOffset>31</bitOffset>
              <bitWidth>1</bitWidth>
            </field>
          </fields>
        </register>
        <register>
          <name>WTCR</name>
          <addressOffset>0x188</addressOffset>
          <size>0x20</size>
          <fields>
            <field>
              <name>DCYC</name>
              <bitOffset>0</bitOffset>
              <bitWidth>5</bitWidth>
            </field>
          </fields>
        </register>
        <register>
          <name>WIR</name>
          <addressOffset>0x190</addressOffset>
          <size>0x20</size>
          <fields>
            <field>
              <name>INSTRUCTION</name>
              <bitOffset>0</bitOffset>
              <bitWidth>32</bitWidth>
            </field>
          </fields>
        </register>
        <register>
          <name>WABR</name>
          <addressOffset>0x1a0</addressOffset>
          <size>0x20</size>
          <fields>
            <field>
              <name>ALTERNATE</name>
              <bitOffset>0</bitOffset>
              <bitWidth>32</bitWidth>
            </field>
          </fields>
        </register>
        <register>
          <name>HLCR</name>
          <addressOffset>0x200</addressOffset>
          <size>0x20</size>
          <fields>
            <field>
              <name>LM</name>
              <bitOffset>0</bitOffset>
              <bitWidth>1</bitWidth>
            </field>
            <field>
              <name>WZL</name>
              <bitOffset>1</bitOffset>
              <bitWidth>1</bitWidth>
            </field>
            <field>
              <name>TACC</name>
              <bitOffset>8</bitOffset>
              <bitWidth>8</bitWidth>
            </field>
            <field>
              <name>TRWR</name>
              <bitOffset>16</bitOffset>
              <bitWidth>8</bitWidth>
            </field>
          </fields>
        </register>
        <register>
          <name>HWCFGR</name>
          <addressOffset>0x3ec</addressOffset>
          <size>0x20</size>
        </register>
        <register>
          <name>VER</name>
          <addressOffset>0x3f0</addressOffset>
          <size>0x20</size>
          <fields>
            <field>
              <name>VER</name>
              <bitOffset>0</bitOffset>
              <bitWidth>8</bitWidth>
            </field>
          </fields>
        </register>
        <register>
          <name>ID</name>
          <addressOffset>0x3f4</addressOffset>
          <size>0x20</size>
          <fields>
            <field>
              <name>ID</name>
              <bitOffset>0</bitOffset>
              <bitWidth>32</bitWidth>
            </field>
          </fields>
        </register>
        <register>
          <name>MID</name>
          <addressOffset>0x3f8</addressOffset>
          <size>0x20</size>
          <fields>
            <field>
              <name>MID</name>
              <bitOffset>0</bitOffset>
              <bitWidth>32</bitWidth>
            </field>
          </fields>
        </register>
      </registers>
    </peripheral>
    <peripheral>
      <name>DLYB_OCTOSPI1</name>
      <baseAddress>0x52006000</baseAddress>
      <registers>
        <register>
          <name>CR</name>
          <addressOffset>0x0</addressOffset>
          <size>0x20</size>
          <fields>
            <field>
              <name>DEN</name>
              <bitOffset>0</bitOffset>
              <bitWidth>1</bitWidth>
            </field>
            <field>
              <name>SEN</name>
              <bitOffset>1</bitOffset>
              <bitWidth>1</bitWidth>
            </field>
          </fields>
        </register>
        <register>
          <name>CFGR</name>
          <addressOffset>0x4</addressOffset>
          <size>0x20</size>
          <fields>
            <field>
              <name>SEL</name>
              <bitOffset>0</bitOffset>
              <bitWidth>4</bitWidth>
            </field>
            <field>
              <name>UNIT</name>
              <bitOffset>8</bitOffset>
              <bitWidth>7</bitWidth>
            </field>
            <field>
              <name>LNG</name>
              <bitOffset>16</bitOffset>
              <bitWidth>12</bitWidth>
            </field>
            <field>
              <name>LNGF</name>
              <bitOffset>31</bitOffset>
              <bitWidth>1</bitWidth>
            </field>
          </fields>
        </register>
      </registers>
    </peripheral>
    <peripheral>
      <name>SDMMC1</name>
      <baseAddress>0x52007000</baseAddress>
      <registers>
        <register>
          <name>POWER</name>
          <addressOffset>0x0</addressOffset>
          <size>0x20</size>
          <fields>
            <field>
              <name>PWRCTRL</name>
              <bitOffset>0</bitOffset>
              <bitWidth>2</bitWidth>
            </field>
            <field>
              <name>VSWITCH</name>
              <bitOffset>2</bitOffset>
              <bitWidth>1</bitWidth>
            </field>
            <field>
              <name>VSWITCHEN</name>
              <bitOffset>3</bitOffset>
              <bitWidth>1</bitWidth>
            </field>
            <field>
              <name>DIRPOL</name>
              <bitOffset>4</bitOffset>
              <bitWidth>1</bitWidth>
            </field>
          </fields>
        </register>
        <register>
          <name>CLKCR</name>
          <addressOffset>0x4</addressOffset>
          <size>0x20</size>
          <fields>
            <field>
              <name>CLKDIV</name>
              <bitOffset>0</bitOffset>
              <bitWidth>10</bitWidth>
            </field>
            <field>
              <name>PWRSAV</name>
              <bitOffset>12</bitOffset>
              <bitWidth>1</bitWidth>
            </field>
            <field>
              <name>WIDBUS</name>
              <bitOffset>14</bitOffset>
              <bitWidth>2</bitWidth>
            </field>
            <field>
              <name>NEGEDGE</name>
              <bitOffset>16</bitOffset>
              <bitWidth>1</bitWidth>
            </field>
            <field>
              <name>HWFC_EN</name>
              <bitOffset>17</bitOffset>
              <bitWidth>1</bitWidth>
            </field>
            <field>
              <name>DDR</name>
              <bitOffset>18</bitOffset>
              <bitWidth>1</bitWidth>
            </field>
            <field>
              <name>BUSSPEED</name>
              <bitOffset>19</bitOffset>
              <bitWidth>1</bitWidth>
            </field>
            <field>
              <name>SELCLKRX</name>
              <bitOffset>20</bitOffset>
              <bitWidth>2</bitWidth>
            </field>
          </fields>
        </register>
        <register>
          <name>ARG</name>
          <addressOffset>0x8</addressOffset>
          <size>0x20</size>
          <fields>
            <field>
              <name>CMDARG</name>
              <bitOffset>0</bitOffset>
              <bitWidth>32</bitWidth>
            </field>
          </fields>
        </register>
        <register>
          <name>CMD</name>
          <addressOffset>0xc</addressOffset>
          <size>0x20</size>
          <fields>
            <field>
              <name>CMDINDEX</name>
              <bitOffset>0</bitOffset>
              <bitWidth>6</bitWidth>
            </field>
            <field>
              <name>CMDTRANS</name>
              <bitOffset>6</bitOffset>
              <bitWidth>1</bitWidth>
            </field>
            <field>
              <name>CMDSTOP</name>
              <bitOffset>7</bitOffset>
              <bitWidth>1</bitWidth>
            </field>
            <field>
              <name>WAITRESP</name>
              <bitOffset>8</bitOffset>
              <bitWidth>2</bitWidth>
            </field>
            <field>
              <name>WAITINT</name>
              <bitOffset>10</bitOffset>
              <bitWidth>1</bitWidth>
            </field>
            <field>
              <name>WAITPEND</name>
              <bitOffset>11</bitOffset>
              <bitWidth>1</bitWidth>
            </field>
            <field>
              <name>CPSMEN</name>
              <bitOffset>12</bitOffset>
              <bitWidth>1</bitWidth>
            </field>
            <field>
              <name>DTHOLD</name>
              <bitOffset>13</bitOffset>
              <bitWidth>1</bitWidth>
            </field>
            <field>
              <name>BOOTMODE</name>
              <bitOffset>14</bitOffset>
              <bitWidth>1</bitWidth>
            </field>
            <field>
              <name>BOOTEN</name>
              <bitOffset>15</bitOffset>
              <bitWidth>1</bitWidth>
            </field>
            <field>
              <name>CMDSUSPEND</name>
              <bitOffset>16</bitOffset>
              <bitWidth>1</bitWidth>
            </field>
          </fields>
        </register>
        <register>
          <name>RESPCMD</name>
          <addressOffset>0x10</addressOffset>
          <size>0x20</size>
          <fields>
            <field>
              <name>RESPCMD</name>
              <bitOffset>0</bitOffset>
              <bitWidth>6</bitWidth>
            </field>
          </fields>
        </register>
        <register>
          <name>RESP1</name>
          <addressOffset>0x14</addressOffset>
          <size>0x20</size>
          <fields>
            <field>
              <name>CARDSTATUS1</name>
              <bitOffset>0</bitOffset>
              <bitWidth>32</bitWidth>
            </field>
          </fields>
        </register>
        <register>
          <name>RESP2</name>
          <addressOffset>0x18</addressOffset>
          <size>0x20</size>
          <fields>
            <field>
              <name>CARDSTATUS2</name>
              <bitOffset>0</bitOffset>
              <bitWidth>32</bitWidth>
            </field>
          </fields>
        </register>
        <register>
          <name>RESP3</name>
          <addressOffset>0x1c</addressOffset>
          <size>0x20</size>
          <fields>
            <field>
              <name>CARDSTATUS3</name>
              <bitOffset>0</bitOffset>
              <bitWidth>32</bitWidth>
            </field>
          </fields>
        </register>
        <register>
          <name>RESP4</name>
          <addressOffset>0x20</addressOffset>
          <size>0x20</size>
          <fields>
            <field>
              <name>CARDSTATUS4</name>
              <bitOffset>0</bitOffset>
              <bitWidth>32</bitWidth>
            </field>
          </fields>
        </register>
        <register>
          <name>DTIMER</name>
          <addressOffset>0x24</addressOffset>
          <size>0x20</size>
          <fields>
            <field>
              <name>DATATIME</name>
              <bitOffset>0</bitOffset>
              <bitWidth>32</bitWidth>
            </field>
          </fields>
        </register>
        <register>
          <name>DLEN</name>
          <addressOffset>0x28</addressOffset>
          <size>0x20</size>
          <fields>
            <field>
              <name>DATALENGTH</name>
              <bitOffset>0</bitOffset>
              <bitWidth>25</bitWidth>
            </field>
          </fields>
        </register>
        <register>
          <name>DCTRL</name>
          <addressOffset>0x2c</addressOffset>
          <size>0x20</size>
          <fields>
            <field>
              <name>DTEN</name>
              <bitOffset>0</bitOffset>
              <bitWidth>1</bitWidth>
            </field>
            <field>
              <name>DTDIR</name>
              <bitOffset>1</bitOffset>
              <bitWidth>1</bitWidth>
            </field>
            <field>
              <name>DTMODE</name>
              <bitOffset>2</bitOffset>
              <bitWidth>2</bitWidth>
            </field>
            <field>
              <name>DBLOCKSIZE</name>
              <bitOffset>4</bitOffset>
              <bitWidth>4</bitWidth>
            </field>
            <field>
              <name>RWSTART</name>
              <bitOffset>8</bitOffset>
              <bitWidth>1</bitWidth>
            </field>
            <field>
              <name>RWSTOP</name>
              <bitOffset>9</bitOffset>
              <bitWidth>1</bitWidth>
            </field>
            <field>
              <name>RWMOD</name>
              <bitOffset>10</bitOffset>
              <bitWidth>1</bitWidth>
            </field>
            <field>
              <name>SDIOEN</name>
              <bitOffset>11</bitOffset>
              <bitWidth>1</bitWidth>
            </field>
            <field>
              <name>BOOTACKEN</name>
              <bitOffset>12</bitOffset>
              <bitWidth>1</bitWidth>
            </field>
            <field>
              <name>FIFORST</name>
              <bitOffset>13</bitOffset>
              <bitWidth>1</bitWidth>
            </field>
          </fields>
        </register>
        <register>
          <name>DCOUNT</name>
          <addressOffset>0x30</addressOffset>
          <size>0x20</size>
          <fields>
            <field>
              <name>DATACOUNT</name>
              <bitOffset>0</bitOffset>
              <bitWidth>25</bitWidth>
            </field>
          </fields>
        </register>
        <register>
          <name>STA</name>
          <addressOffset>0x34</addressOffset>
          <size>0x20</size>
          <fields>
            <field>
              <name>CCRCFAIL</name>
              <bitOffset>0</bitOffset>
              <bitWidth>1</bitWidth>
            </field>
            <field>
              <name>DCRCFAIL</name>
              <bitOffset>1</bitOffset>
              <bitWidth>1</bitWidth>
            </field>
            <field>
              <name>CTIMEOUT</name>
              <bitOffset>2</bitOffset>
              <bitWidth>1</bitWidth>
            </field>
            <field>
              <name>DTIMEOUT</name>
              <bitOffset>3</bitOffset>
              <bitWidth>1</bitWidth>
            </field>
            <field>
              <name>TXUNDERR</name>
              <bitOffset>4</bitOffset>
              <bitWidth>1</bitWidth>
            </field>
            <field>
              <name>RXOVERR</name>
              <bitOffset>5</bitOffset>
              <bitWidth>1</bitWidth>
            </field>
            <field>
              <name>CMDREND</name>
              <bitOffset>6</bitOffset>
              <bitWidth>1</bitWidth>
            </field>
            <field>
              <name>CMDSENT</name>
              <bitOffset>7</bitOffset>
              <bitWidth>1</bitWidth>
            </field>
            <field>
              <name>DATAEND</name>
              <bitOffset>8</bitOffset>
              <bitWidth>1</bitWidth>
            </field>
            <field>
              <name>DHOLD</name>
              <bitOffset>9</bitOffset>
              <bitWidth>1</bitWidth>
            </field>
            <field>
              <name>DBCKEND</name>
              <bitOffset>10</bitOffset>
              <bitWidth>1</bitWidth>
            </field>
            <field>
              <name>DABORT</name>
              <bitOffset>11</bitOffset>
              <bitWidth>1</bitWidth>
            </field>
            <field>
              <name>DPSMACT</name>
              <bitOffset>12</bitOffset>
              <bitWidth>1</bitWidth>
            </field>
            <field>
              <name>CPSMACT</name>
              <bitOffset>13</bitOffset>
              <bitWidth>1</bitWidth>
            </field>
            <field>
              <name>TXFIFOHE</name>
              <bitOffset>14</bitOffset>
              <bitWidth>1</bitWidth>
            </field>
            <field>
              <name>RXFIFOHF</name>
              <bitOffset>15</bitOffset>
              <bitWidth>1</bitWidth>
            </field>
            <field>
              <name>TXFIFOF</name>
              <bitOffset>16</bitOffset>
              <bitWidth>1</bitWidth>
            </field>
            <field>
              <name>RXFIFOF</name>
              <bitOffset>17</bitOffset>
              <bitWidth>1</bitWidth>
            </field>
            <field>
              <name>TXFIFOE</name>
              <bitOffset>18</bitOffset>
              <bitWidth>1</bitWidth>
            </field>
            <field>
              <name>RXFIFOE</name>
              <bitOffset>19</bitOffset>
              <bitWidth>1</bitWidth>
            </field>
            <field>
              <name>BUSYD0</name>
              <bitOffset>20</bitOffset>
              <bitWidth>1</bitWidth>
            </field>
            <field>
              <name>BUSYD0END</name>
              <bitOffset>21</bitOffset>
              <bitWidth>1</bitWidth>
            </field>
            <field>
              <name>SDIOIT</name>
              <bitOffset>22</bitOffset>
              <bitWidth>1</bitWidth>
            </field>
            <field>
              <name>ACKFAIL</name>
              <bitOffset>23</bitOffset>
              <bitWidth>1</bitWidth>
            </field>
            <field>
              <name>ACKTIMEOUT</name>
              <bitOffset>24</bitOffset>
              <bitWidth>1</bitWidth>
            </field>
            <field>
              <name>VSWEND</name>
              <bitOffset>25</bitOffset>
              <bitWidth>1</bitWidth>
            </field>
            <field>
              <name>CKSTOP</name>
              <bitOffset>26</bitOffset>
              <bitWidth>1</bitWidth>
            </field>
            <field>
              <name>IDMATE</name>
              <bitOffset>27</bitOffset>
              <bitWidth>1</bitWidth>
            </field>
            <field>
              <name>IDMABTC</name>
              <bitOffset>28</bitOffset>
              <bitWidth>1</bitWidth>
            </field>
          </fields>
        </register>
        <register>
          <name>ICR</name>
          <addressOffset>0x38</addressOffset>
          <size>0x20</size>
          <fields>
            <field>
              <name>CCRCFAILC</name>
              <bitOffset>0</bitOffset>
              <bitWidth>1</bitWidth>
            </field>
            <field>
              <name>DCRCFAILC</name>
              <bitOffset>1</bitOffset>
              <bitWidth>1</bitWidth>
            </field>
            <field>
              <name>CTIMEOUTC</name>
              <bitOffset>2</bitOffset>
              <bitWidth>1</bitWidth>
            </field>
            <field>
              <name>DTIMEOUTC</name>
              <bitOffset>3</bitOffset>
              <bitWidth>1</bitWidth>
            </field>
            <field>
              <name>TXUNDERRC</name>
              <bitOffset>4</bitOffset>
              <bitWidth>1</bitWidth>
            </field>
            <field>
              <name>RXOVERRC</name>
              <bitOffset>5</bitOffset>
              <bitWidth>1</bitWidth>
            </field>
            <field>
              <name>CMDRENDC</name>
              <bitOffset>6</bitOffset>
              <bitWidth>1</bitWidth>
            </field>
            <field>
              <name>CMDSENTC</name>
              <bitOffset>7</bitOffset>
              <bitWidth>1</bitWidth>
            </field>
            <field>
              <name>DATAENDC</name>
              <bitOffset>8</bitOffset>
              <bitWidth>1</bitWidth>
            </field>
            <field>
              <name>DHOLDC</name>
              <bitOffset>9</bitOffset>
              <bitWidth>1</bitWidth>
            </field>
            <field>
              <name>DBCKENDC</name>
              <bitOffset>10</bitOffset>
              <bitWidth>1</bitWidth>
            </field>
            <field>
              <name>DABORTC</name>
              <bitOffset>11</bitOffset>
              <bitWidth>1</bitWidth>
            </field>
            <field>
              <name>BUSYD0ENDC</name>
              <bitOffset>21</bitOffset>
              <bitWidth>1</bitWidth>
            </field>
            <field>
              <name>SDIOITC</name>
              <bitOffset>22</bitOffset>
              <bitWidth>1</bitWidth>
            </field>
            <field>
              <name>ACKFAILC</name>
              <bitOffset>23</bitOffset>
              <bitWidth>1</bitWidth>
            </field>
            <field>
              <name>ACKTIMEOUTC</name>
              <bitOffset>24</bitOffset>
              <bitWidth>1</bitWidth>
            </field>
            <field>
              <name>VSWENDC</name>
              <bitOffset>25</bitOffset>
              <bitWidth>1</bitWidth>
            </field>
            <field>
              <name>CKSTOPC</name>
              <bitOffset>26</bitOffset>
              <bitWidth>1</bitWidth>
            </field>
            <field>
              <name>IDMATEC</name>
              <bitOffset>27</bitOffset>
              <bitWidth>1</bitWidth>
            </field>
            <field>
              <name>IDMABTCC</name>
              <bitOffset>28</bitOffset>
              <bitWidth>1</bitWidth>
            </field>
          </fields>
        </register>
        <register>
          <name>MASK</name>
          <addressOffset>0x3c</addressOffset>
          <size>0x20</size>
          <fields>
            <field>
              <name>CCRCFAILIE</name>
              <bitOffset>0</bitOffset>
              <bitWidth>1</bitWidth>
            </field>
            <field>
              <name>DCRCFAILIE</name>
              <bitOffset>1</bitOffset>
              <bitWidth>1</bitWidth>
            </field>
            <field>
              <name>CTIMEOUTIE</name>
              <bitOffset>2</bitOffset>
              <bitWidth>1</bitWidth>
            </field>
            <field>
              <name>DTIMEOUTIE</name>
              <bitOffset>3</bitOffset>
              <bitWidth>1</bitWidth>
            </field>
            <field>
              <name>TXUNDERRIE</name>
              <bitOffset>4</bitOffset>
              <bitWidth>1</bitWidth>
            </field>
            <field>
              <name>RXOVERRIE</name>
              <bitOffset>5</bitOffset>
              <bitWidth>1</bitWidth>
            </field>
            <field>
              <name>CMDRENDIE</name>
              <bitOffset>6</bitOffset>
              <bitWidth>1</bitWidth>
            </field>
            <field>
              <name>CMDSENTIE</name>
              <bitOffset>7</bitOffset>
              <bitWidth>1</bitWidth>
            </field>
            <field>
              <name>DATAENDIE</name>
              <bitOffset>8</bitOffset>
              <bitWidth>1</bitWidth>
            </field>
            <field>
              <name>DHOLDIE</name>
              <bitOffset>9</bitOffset>
              <bitWidth>1</bitWidth>
            </field>
            <field>
              <name>DBCKENDIE</name>
              <bitOffset>10</bitOffset>
              <bitWidth>1</bitWidth>
            </field>
            <field>
              <name>DABORTIE</name>
              <bitOffset>11</bitOffset>
              <bitWidth>1</bitWidth>
            </field>
            <field>
              <name>TXFIFOHEIE</name>
              <bitOffset>14</bitOffset>
              <bitWidth>1</bitWidth>
            </field>
            <field>
              <name>RXFIFOHFIE</name>
              <bitOffset>15</bitOffset>
              <bitWidth>1</bitWidth>
            </field>
            <field>
              <name>RXFIFOFIE</name>
              <bitOffset>17</bitOffset>
              <bitWidth>1</bitWidth>
            </field>
            <field>
              <name>TXFIFOEIE</name>
              <bitOffset>18</bitOffset>
              <bitWidth>1</bitWidth>
            </field>
            <field>
              <name>BUSYD0ENDIE</name>
              <bitOffset>21</bitOffset>
              <bitWidth>1</bitWidth>
            </field>
            <field>
              <name>SDIOITIE</name>
              <bitOffset>22</bitOffset>
              <bitWidth>1</bitWidth>
            </field>
            <field>
              <name>ACKFAILIE</name>
              <bitOffset>23</bitOffset>
              <bitWidth>1</bitWidth>
            </field>
            <field>
              <name>ACKTIMEOUTIE</name>
              <bitOffset>24</bitOffset>
              <bitWidth>1</bitWidth>
            </field>
            <field>
              <name>VSWENDIE</name>
              <bitOffset>25</bitOffset>
              <bitWidth>1</bitWidth>
            </field>
            <field>
              <name>CKSTOPIE</name>
              <bitOffset>26</bitOffset>
              <bitWidth>1</bitWidth>
            </field>
            <field>
              <name>IDMABTCIE</name>
              <bitOffset>28</bitOffset>
              <bitWidth>1</bitWidth>
            </field>
          </fields>
        </register>
        <register>
          <name>ACKTIME</name>
          <addressOffset>0x40</addressOffset>
          <size>0x20</size>
          <fields>
            <field>
              <name>ACKTIME</name>
              <bitOffset>0</bitOffset>
              <bitWidth>25</bitWidth>
            </field>
          </fields>
        </register>
        <register>
          <name>IDMACTRL</name>
          <addressOffset>0x50</addressOffset>
          <size>0x20</size>
        </register>
        <register>
          <name>IDMABSIZE</name>
          <addressOffset>0x54</addressOffset>
          <size>0x20</size>
          <fields>
            <field>
              <name>IDMABNDT</name>
              <bitOffset>5</bitOffset>
              <bitWidth>8</bitWidth>
            </field>
          </fields>
        </register>
        <register>
          <name>IDMABASE0</name>
          <addressOffset>0x58</addressOffset>
          <size>0x20</size>
        </register>
        <register>
          <name>IDMABASE1</name>
          <addressOffset>0x5c</addressOffset>
          <size>0x20</size>
        </register>
        <register>
          <name>FIFO</name>
          <addressOffset>0x80</addressOffset>
          <size>0x20</size>
          <fields>
            <field>
              <name>FIFODATA</name>
              <bitOffset>0</bitOffset>
              <bitWidth>32</bitWidth>
            </field>
          </fields>
        </register>
        <register>
          <name>IPVR</name>
          <addressOffset>0x3fc</addressOffset>
          <size>0x20</size>
        </register>
      </registers>
    </peripheral>
    <peripheral>
      <name>DLYB_SDMMC1</name>
      <baseAddress>0x52008000</baseAddress>
      <registers>
        <register>
          <name>CR</name>
          <addressOffset>0x0</addressOffset>
          <size>0x20</size>
          <fields>
            <field>
              <name>DEN</name>
              <bitOffset>0</bitOffset>
              <bitWidth>1</bitWidth>
            </field>
            <field>
              <name>SEN</name>
              <bitOffset>1</bitOffset>
              <bitWidth>1</bitWidth>
            </field>
          </fields>
        </register>
        <register>
          <name>CFGR</name>
          <addressOffset>0x4</addressOffset>
          <size>0x20</size>
          <fields>
            <field>
              <name>SEL</name>
              <bitOffset>0</bitOffset>
              <bitWidth>4</bitWidth>
            </field>
            <field>
              <name>UNIT</name>
              <bitOffset>8</bitOffset>
              <bitWidth>7</bitWidth>
            </field>
            <field>
              <name>LNG</name>
              <bitOffset>16</bitOffset>
              <bitWidth>12</bitWidth>
            </field>
            <field>
              <name>LNGF</name>
              <bitOffset>31</bitOffset>
              <bitWidth>1</bitWidth>
            </field>
          </fields>
        </register>
      </registers>
    </peripheral>
    <peripheral>
      <name>RAMECC1</name>
      <baseAddress>0x52009000</baseAddress>
      <registers>
        <register>
          <name>IER</name>
          <addressOffset>0x0</addressOffset>
          <size>0x20</size>
          <fields>
            <field>
              <name>GIE</name>
              <bitOffset>0</bitOffset>
              <bitWidth>1</bitWidth>
            </field>
            <field>
              <name>GECCSEIE</name>
              <bitOffset>1</bitOffset>
              <bitWidth>1</bitWidth>
            </field>
            <field>
              <name>GECCDEIE</name>
              <bitOffset>2</bitOffset>
              <bitWidth>1</bitWidth>
            </field>
            <field>
              <name>GECCDEBWIE</name>
              <bitOffset>3</bitOffset>
              <bitWidth>1</bitWidth>
            </field>
          </fields>
        </register>
        <register>
          <name>CR1</name>
          <addressOffset>0x20</addressOffset>
          <size>0x20</size>
          <fields>
            <field>
              <name>ECCSEIE</name>
              <bitOffset>2</bitOffset>
              <bitWidth>1</bitWidth>
            </field>
            <field>
              <name>ECCDEIE</name>
              <bitOffset>3</bitOffset>
              <bitWidth>1</bitWidth>
            </field>
            <field>
              <name>ECCDEBWIE</name>
              <bitOffset>4</bitOffset>
              <bitWidth>1</bitWidth>
            </field>
            <field>
              <name>ECCELEN</name>
              <bitOffset>5</bitOffset>
              <bitWidth>1</bitWidth>
            </field>
          </fields>
        </register>
        <register>
          <name>CR1</name>
          <addressOffset>0x20</addressOffset>
          <size>0x20</size>
          <fields>
            <field>
              <name>ECCSEIE</name>
              <bitOffset>2</bitOffset>
              <bitWidth>1</bitWidth>
            </field>
            <field>
              <name>ECCDEIE</name>
              <bitOffset>3</bitOffset>
              <bitWidth>1</bitWidth>
            </field>
            <field>
              <name>ECCDEBWIE</name>
              <bitOffset>4</bitOffset>
              <bitWidth>1</bitWidth>
            </field>
            <field>
              <name>ECCELEN</name>
              <bitOffset>5</bitOffset>
              <bitWidth>1</bitWidth>
            </field>
          </fields>
        </register>
        <register>
          <name>CR1</name>
          <addressOffset>0x20</addressOffset>
          <size>0x20</size>
          <fields>
            <field>
              <name>ECCSEIE</name>
              <bitOffset>2</bitOffset>
              <bitWidth>1</bitWidth>
            </field>
            <field>
              <name>ECCDEIE</name>
              <bitOffset>3</bitOffset>
              <bitWidth>1</bitWidth>
            </field>
            <field>
              <name>ECCDEBWIE</name>
              <bitOffset>4</bitOffset>
              <bitWidth>1</bitWidth>
            </field>
            <field>
              <name>ECCELEN</name>
              <bitOffset>5</bitOffset>
              <bitWidth>1</bitWidth>
            </field>
          </fields>
        </register>
        <register>
          <name>SR1</name>
          <addressOffset>0x24</addressOffset>
          <size>0x20</size>
          <fields>
            <field>
              <name>SEDCF</name>
              <bitOffset>0</bitOffset>
              <bitWidth>1</bitWidth>
            </field>
            <field>
              <name>DEDF</name>
              <bitOffset>1</bitOffset>
              <bitWidth>1</bitWidth>
            </field>
            <field>
              <name>DEBWDF</name>
              <bitOffset>2</bitOffset>
              <bitWidth>1</bitWidth>
            </field>
          </fields>
        </register>
        <register>
          <name>SR1</name>
          <addressOffset>0x24</addressOffset>
          <size>0x20</size>
          <fields>
            <field>
              <name>SEDCF</name>
              <bitOffset>0</bitOffset>
              <bitWidth>1</bitWidth>
            </field>
            <field>
              <name>DEDF</name>
              <bitOffset>1</bitOffset>
              <bitWidth>1</bitWidth>
            </field>
            <field>
              <name>DEBWDF</name>
              <bitOffset>2</bitOffset>
              <bitWidth>1</bitWidth>
            </field>
          </fields>
        </register>
        <register>
          <name>SR1</name>
          <addressOffset>0x24</addressOffset>
          <size>0x20</size>
          <fields>
            <field>
              <name>SEDCF</name>
              <bitOffset>0</bitOffset>
              <bitWidth>1</bitWidth>
            </field>
            <field>
              <name>DEDF</name>
              <bitOffset>1</bitOffset>
              <bitWidth>1</bitWidth>
            </field>
            <field>
              <name>DEBWDF</name>
              <bitOffset>2</bitOffset>
              <bitWidth>1</bitWidth>
            </field>
          </fields>
        </register>
        <register>
          <name>FAR1</name>
          <addressOffset>0x28</addressOffset>
          <size>0x20</size>
          <fields>
            <field>
              <name>FDATAL</name>
              <bitOffset>0</bitOffset>
              <bitWidth>32</bitWidth>
            </field>
          </fields>
        </register>
        <register>
          <name>FAR1</name>
          <addressOffset>0x28</addressOffset>
          <size>0x20</size>
          <fields>
            <field>
              <name>FDATAL</name>
              <bitOffset>0</bitOffset>
              <bitWidth>32</bitWidth>
            </field>
          </fields>
        </register>
        <register>
          <name>FAR1</name>
          <addressOffset>0x28</addressOffset>
          <size>0x20</size>
          <fields>
            <field>
              <name>FDATAL</name>
              <bitOffset>0</bitOffset>
              <bitWidth>32</bitWidth>
            </field>
          </fields>
        </register>
        <register>
          <name>FDRL1</name>
          <addressOffset>0x2c</addressOffset>
          <size>0x20</size>
        </register>
        <register>
          <name>FDRL1</name>
          <addressOffset>0x2c</addressOffset>
          <size>0x20</size>
        </register>
        <register>
          <name>FDRL1</name>
          <addressOffset>0x2c</addressOffset>
          <size>0x20</size>
        </register>
        <register>
          <name>FDRH1</name>
          <addressOffset>0x30</addressOffset>
          <size>0x20</size>
        </register>
        <register>
          <name>FDRH1</name>
          <addressOffset>0x30</addressOffset>
          <size>0x20</size>
        </register>
        <register>
          <name>FDRH1</name>
          <addressOffset>0x30</addressOffset>
          <size>0x20</size>
        </register>
        <register>
          <name>FECR1</name>
          <addressOffset>0x34</addressOffset>
          <size>0x20</size>
          <fields>
            <field>
              <name>FEC</name>
              <bitOffset>0</bitOffset>
              <bitWidth>32</bitWidth>
            </field>
          </fields>
        </register>
        <register>
          <name>FECR1</name>
          <addressOffset>0x34</addressOffset>
          <size>0x20</size>
          <fields>
            <field>
              <name>FEC</name>
              <bitOffset>0</bitOffset>
              <bitWidth>32</bitWidth>
            </field>
          </fields>
        </register>
        <register>
          <name>FECR1</name>
          <addressOffset>0x34</addressOffset>
          <size>0x20</size>
          <fields>
            <field>
              <name>FEC</name>
              <bitOffset>0</bitOffset>
              <bitWidth>32</bitWidth>
            </field>
          </fields>
        </register>
        <register>
          <name>CR2</name>
          <addressOffset>0x40</addressOffset>
          <size>0x20</size>
          <fields>
            <field>
              <name>ECCSEIE</name>
              <bitOffset>2</bitOffset>
              <bitWidth>1</bitWidth>
            </field>
            <field>
              <name>ECCDEIE</name>
              <bitOffset>3</bitOffset>
              <bitWidth>1</bitWidth>
            </field>
            <field>
              <name>ECCDEBWIE</name>
              <bitOffset>4</bitOffset>
              <bitWidth>1</bitWidth>
            </field>
            <field>
              <name>ECCELEN</name>
              <bitOffset>5</bitOffset>
              <bitWidth>1</bitWidth>
            </field>
          </fields>
        </register>
        <register>
          <name>CR2</name>
          <addressOffset>0x40</addressOffset>
          <size>0x20</size>
          <fields>
            <field>
              <name>ECCSEIE</name>
              <bitOffset>2</bitOffset>
              <bitWidth>1</bitWidth>
            </field>
            <field>
              <name>ECCDEIE</name>
              <bitOffset>3</bitOffset>
              <bitWidth>1</bitWidth>
            </field>
            <field>
              <name>ECCDEBWIE</name>
              <bitOffset>4</bitOffset>
              <bitWidth>1</bitWidth>
            </field>
            <field>
              <name>ECCELEN</name>
              <bitOffset>5</bitOffset>
              <bitWidth>1</bitWidth>
            </field>
          </fields>
        </register>
        <register>
          <name>CR2</name>
          <addressOffset>0x40</addressOffset>
          <size>0x20</size>
          <fields>
            <field>
              <name>ECCSEIE</name>
              <bitOffset>2</bitOffset>
              <bitWidth>1</bitWidth>
            </field>
            <field>
              <name>ECCDEIE</name>
              <bitOffset>3</bitOffset>
              <bitWidth>1</bitWidth>
            </field>
            <field>
              <name>ECCDEBWIE</name>
              <bitOffset>4</bitOffset>
              <bitWidth>1</bitWidth>
            </field>
            <field>
              <name>ECCELEN</name>
              <bitOffset>5</bitOffset>
              <bitWidth>1</bitWidth>
            </field>
          </fields>
        </register>
        <register>
          <name>SR2</name>
          <addressOffset>0x44</addressOffset>
          <size>0x20</size>
          <fields>
            <field>
              <name>SEDCF</name>
              <bitOffset>0</bitOffset>
              <bitWidth>1</bitWidth>
            </field>
            <field>
              <name>DEDF</name>
              <bitOffset>1</bitOffset>
              <bitWidth>1</bitWidth>
            </field>
            <field>
              <name>DEBWDF</name>
              <bitOffset>2</bitOffset>
              <bitWidth>1</bitWidth>
            </field>
          </fields>
        </register>
        <register>
          <name>SR2</name>
          <addressOffset>0x44</addressOffset>
          <size>0x20</size>
          <fields>
            <field>
              <name>SEDCF</name>
              <bitOffset>0</bitOffset>
              <bitWidth>1</bitWidth>
            </field>
            <field>
              <name>DEDF</name>
              <bitOffset>1</bitOffset>
              <bitWidth>1</bitWidth>
            </field>
            <field>
              <name>DEBWDF</name>
              <bitOffset>2</bitOffset>
              <bitWidth>1</bitWidth>
            </field>
          </fields>
        </register>
        <register>
          <name>SR2</name>
          <addressOffset>0x44</addressOffset>
          <size>0x20</size>
          <fields>
            <field>
              <name>SEDCF</name>
              <bitOffset>0</bitOffset>
              <bitWidth>1</bitWidth>
            </field>
            <field>
              <name>DEDF</name>
              <bitOffset>1</bitOffset>
              <bitWidth>1</bitWidth>
            </field>
            <field>
              <name>DEBWDF</name>
              <bitOffset>2</bitOffset>
              <bitWidth>1</bitWidth>
            </field>
          </fields>
        </register>
        <register>
          <name>FAR2</name>
          <addressOffset>0x48</addressOffset>
          <size>0x20</size>
          <fields>
            <field>
              <name>FDATAL</name>
              <bitOffset>0</bitOffset>
              <bitWidth>32</bitWidth>
            </field>
          </fields>
        </register>
        <register>
          <name>FAR2</name>
          <addressOffset>0x48</addressOffset>
          <size>0x20</size>
          <fields>
            <field>
              <name>FDATAL</name>
              <bitOffset>0</bitOffset>
              <bitWidth>32</bitWidth>
            </field>
          </fields>
        </register>
        <register>
          <name>FAR2</name>
          <addressOffset>0x48</addressOffset>
          <size>0x20</size>
          <fields>
            <field>
              <name>FDATAL</name>
              <bitOffset>0</bitOffset>
              <bitWidth>32</bitWidth>
            </field>
          </fields>
        </register>
        <register>
          <name>FDRL2</name>
          <addressOffset>0x4c</addressOffset>
          <size>0x20</size>
        </register>
        <register>
          <name>FDRL2</name>
          <addressOffset>0x4c</addressOffset>
          <size>0x20</size>
        </register>
        <register>
          <name>FDRL2</name>
          <addressOffset>0x4c</addressOffset>
          <size>0x20</size>
        </register>
        <register>
          <name>FDRH2</name>
          <addressOffset>0x50</addressOffset>
          <size>0x20</size>
        </register>
        <register>
          <name>FDRH2</name>
          <addressOffset>0x50</addressOffset>
          <size>0x20</size>
        </register>
        <register>
          <name>FDRH2</name>
          <addressOffset>0x50</addressOffset>
          <size>0x20</size>
        </register>
        <register>
          <name>FECR2</name>
          <addressOffset>0x54</addressOffset>
          <size>0x20</size>
          <fields>
            <field>
              <name>FEC</name>
              <bitOffset>0</bitOffset>
              <bitWidth>32</bitWidth>
            </field>
          </fields>
        </register>
        <register>
          <name>FECR2</name>
          <addressOffset>0x54</addressOffset>
          <size>0x20</size>
          <fields>
            <field>
              <name>FEC</name>
              <bitOffset>0</bitOffset>
              <bitWidth>32</bitWidth>
            </field>
          </fields>
        </register>
        <register>
          <name>FECR2</name>
          <addressOffset>0x54</addressOffset>
          <size>0x20</size>
          <fields>
            <field>
              <name>FEC</name>
              <bitOffset>0</bitOffset>
              <bitWidth>32</bitWidth>
            </field>
          </fields>
        </register>
        <register>
          <name>CR3</name>
          <addressOffset>0x60</addressOffset>
          <size>0x20</size>
          <fields>
            <field>
              <name>ECCSEIE</name>
              <bitOffset>2</bitOffset>
              <bitWidth>1</bitWidth>
            </field>
            <field>
              <name>ECCDEIE</name>
              <bitOffset>3</bitOffset>
              <bitWidth>1</bitWidth>
            </field>
            <field>
              <name>ECCDEBWIE</name>
              <bitOffset>4</bitOffset>
              <bitWidth>1</bitWidth>
            </field>
            <field>
              <name>ECCELEN</name>
              <bitOffset>5</bitOffset>
              <bitWidth>1</bitWidth>
            </field>
          </fields>
        </register>
        <register>
          <name>CR3</name>
          <addressOffset>0x60</addressOffset>
          <size>0x20</size>
          <fields>
            <field>
              <name>ECCSEIE</name>
              <bitOffset>2</bitOffset>
              <bitWidth>1</bitWidth>
            </field>
            <field>
              <name>ECCDEIE</name>
              <bitOffset>3</bitOffset>
              <bitWidth>1</bitWidth>
            </field>
            <field>
              <name>ECCDEBWIE</name>
              <bitOffset>4</bitOffset>
              <bitWidth>1</bitWidth>
            </field>
            <field>
              <name>ECCELEN</name>
              <bitOffset>5</bitOffset>
              <bitWidth>1</bitWidth>
            </field>
          </fields>
        </register>
        <register>
          <name>SR3</name>
          <addressOffset>0x64</addressOffset>
          <size>0x20</size>
          <fields>
            <field>
              <name>SEDCF</name>
              <bitOffset>0</bitOffset>
              <bitWidth>1</bitWidth>
            </field>
            <field>
              <name>DEDF</name>
              <bitOffset>1</bitOffset>
              <bitWidth>1</bitWidth>
            </field>
            <field>
              <name>DEBWDF</name>
              <bitOffset>2</bitOffset>
              <bitWidth>1</bitWidth>
            </field>
          </fields>
        </register>
        <register>
          <name>SR3</name>
          <addressOffset>0x64</addressOffset>
          <size>0x20</size>
          <fields>
            <field>
              <name>SEDCF</name>
              <bitOffset>0</bitOffset>
              <bitWidth>1</bitWidth>
            </field>
            <field>
              <name>DEDF</name>
              <bitOffset>1</bitOffset>
              <bitWidth>1</bitWidth>
            </field>
            <field>
              <name>DEBWDF</name>
              <bitOffset>2</bitOffset>
              <bitWidth>1</bitWidth>
            </field>
          </fields>
        </register>
        <register>
          <name>FAR3</name>
          <addressOffset>0x68</addressOffset>
          <size>0x20</size>
          <fields>
            <field>
              <name>FDATAL</name>
              <bitOffset>0</bitOffset>
              <bitWidth>32</bitWidth>
            </field>
          </fields>
        </register>
        <register>
          <name>FAR3</name>
          <addressOffset>0x68</addressOffset>
          <size>0x20</size>
          <fields>
            <field>
              <name>FDATAL</name>
              <bitOffset>0</bitOffset>
              <bitWidth>32</bitWidth>
            </field>
          </fields>
        </register>
        <register>
          <name>FDRL3</name>
          <addressOffset>0x6c</addressOffset>
          <size>0x20</size>
        </register>
        <register>
          <name>FDRL3</name>
          <addressOffset>0x6c</addressOffset>
          <size>0x20</size>
        </register>
        <register>
          <name>FDRH3</name>
          <addressOffset>0x70</addressOffset>
          <size>0x20</size>
        </register>
        <register>
          <name>FDRH3</name>
          <addressOffset>0x70</addressOffset>
          <size>0x20</size>
        </register>
        <register>
          <name>FECR3</name>
          <addressOffset>0x74</addressOffset>
          <size>0x20</size>
          <fields>
            <field>
              <name>FEC</name>
              <bitOffset>0</bitOffset>
              <bitWidth>32</bitWidth>
            </field>
          </fields>
        </register>
        <register>
          <name>FECR3</name>
          <addressOffset>0x74</addressOffset>
          <size>0x20</size>
          <fields>
            <field>
              <name>FEC</name>
              <bitOffset>0</bitOffset>
              <bitWidth>32</bitWidth>
            </field>
          </fields>
        </register>
        <register>
          <name>CR4</name>
          <addressOffset>0x80</addressOffset>
          <size>0x20</size>
          <fields>
            <field>
              <name>ECCSEIE</name>
              <bitOffset>2</bitOffset>
              <bitWidth>1</bitWidth>
            </field>
            <field>
              <name>ECCDEIE</name>
              <bitOffset>3</bitOffset>
              <bitWidth>1</bitWidth>
            </field>
            <field>
              <name>ECCDEBWIE</name>
              <bitOffset>4</bitOffset>
              <bitWidth>1</bitWidth>
            </field>
            <field>
              <name>ECCELEN</name>
              <bitOffset>5</bitOffset>
              <bitWidth>1</bitWidth>
            </field>
          </fields>
        </register>
        <register>
          <name>SR4</name>
          <addressOffset>0x84</addressOffset>
          <size>0x20</size>
          <fields>
            <field>
              <name>SEDCF</name>
              <bitOffset>0</bitOffset>
              <bitWidth>1</bitWidth>
            </field>
            <field>
              <name>DEDF</name>
              <bitOffset>1</bitOffset>
              <bitWidth>1</bitWidth>
            </field>
            <field>
              <name>DEBWDF</name>
              <bitOffset>2</bitOffset>
              <bitWidth>1</bitWidth>
            </field>
          </fields>
        </register>
        <register>
          <name>FAR4</name>
          <addressOffset>0x88</addressOffset>
          <size>0x20</size>
          <fields>
            <field>
              <name>FDATAL</name>
              <bitOffset>0</bitOffset>
              <bitWidth>32</bitWidth>
            </field>
          </fields>
        </register>
        <register>
          <name>FDRL4</name>
          <addressOffset>0x8c</addressOffset>
          <size>0x20</size>
        </register>
        <register>
          <name>FDRH4</name>
          <addressOffset>0x90</addressOffset>
          <size>0x20</size>
        </register>
        <register>
          <name>FECR4</name>
          <addressOffset>0x94</addressOffset>
          <size>0x20</size>
          <fields>
            <field>
              <name>FEC</name>
              <bitOffset>0</bitOffset>
              <bitWidth>32</bitWidth>
            </field>
          </fields>
        </register>
        <register>
          <name>CR5</name>
          <addressOffset>0xa0</addressOffset>
          <size>0x20</size>
          <fields>
            <field>
              <name>ECCSEIE</name>
              <bitOffset>2</bitOffset>
              <bitWidth>1</bitWidth>
            </field>
            <field>
              <name>ECCDEIE</name>
              <bitOffset>3</bitOffset>
              <bitWidth>1</bitWidth>
            </field>
            <field>
              <name>ECCDEBWIE</name>
              <bitOffset>4</bitOffset>
              <bitWidth>1</bitWidth>
            </field>
            <field>
              <name>ECCELEN</name>
              <bitOffset>5</bitOffset>
              <bitWidth>1</bitWidth>
            </field>
          </fields>
        </register>
        <register>
          <name>SR5</name>
          <addressOffset>0xa4</addressOffset>
          <size>0x20</size>
          <fields>
            <field>
              <name>SEDCF</name>
              <bitOffset>0</bitOffset>
              <bitWidth>1</bitWidth>
            </field>
            <field>
              <name>DEDF</name>
              <bitOffset>1</bitOffset>
              <bitWidth>1</bitWidth>
            </field>
            <field>
              <name>DEBWDF</name>
              <bitOffset>2</bitOffset>
              <bitWidth>1</bitWidth>
            </field>
          </fields>
        </register>
        <register>
          <name>FAR5</name>
          <addressOffset>0xa8</addressOffset>
          <size>0x20</size>
          <fields>
            <field>
              <name>FDATAL</name>
              <bitOffset>0</bitOffset>
              <bitWidth>32</bitWidth>
            </field>
          </fields>
        </register>
        <register>
          <name>FDRL5</name>
          <addressOffset>0xac</addressOffset>
          <size>0x20</size>
        </register>
        <register>
          <name>FDRH5</name>
          <addressOffset>0xb0</addressOffset>
          <size>0x20</size>
        </register>
        <register>
          <name>FECR5</name>
          <addressOffset>0xb4</addressOffset>
          <size>0x20</size>
          <fields>
            <field>
              <name>FEC</name>
              <bitOffset>0</bitOffset>
              <bitWidth>32</bitWidth>
            </field>
          </fields>
        </register>
        <register>
          <name>CR6</name>
          <addressOffset>0xc0</addressOffset>
          <size>0x20</size>
          <fields>
            <field>
              <name>ECCSEIE</name>
              <bitOffset>2</bitOffset>
              <bitWidth>1</bitWidth>
            </field>
            <field>
              <name>ECCDEIE</name>
              <bitOffset>3</bitOffset>
              <bitWidth>1</bitWidth>
            </field>
            <field>
              <name>ECCDEBWIE</name>
              <bitOffset>4</bitOffset>
              <bitWidth>1</bitWidth>
            </field>
            <field>
              <name>ECCELEN</name>
              <bitOffset>5</bitOffset>
              <bitWidth>1</bitWidth>
            </field>
          </fields>
        </register>
        <register>
          <name>SR6</name>
          <addressOffset>0xc4</addressOffset>
          <size>0x20</size>
          <fields>
            <field>
              <name>SEDCF</name>
              <bitOffset>0</bitOffset>
              <bitWidth>1</bitWidth>
            </field>
            <field>
              <name>DEDF</name>
              <bitOffset>1</bitOffset>
              <bitWidth>1</bitWidth>
            </field>
            <field>
              <name>DEBWDF</name>
              <bitOffset>2</bitOffset>
              <bitWidth>1</bitWidth>
            </field>
          </fields>
        </register>
        <register>
          <name>FAR6</name>
          <addressOffset>0xc8</addressOffset>
          <size>0x20</size>
          <fields>
            <field>
              <name>FDATAL</name>
              <bitOffset>0</bitOffset>
              <bitWidth>32</bitWidth>
            </field>
          </fields>
        </register>
        <register>
          <name>FDRL6</name>
          <addressOffset>0xcc</addressOffset>
          <size>0x20</size>
        </register>
        <register>
          <name>FDRH6</name>
          <addressOffset>0xd0</addressOffset>
          <size>0x20</size>
        </register>
        <register>
          <name>FECR6</name>
          <addressOffset>0xd4</addressOffset>
          <size>0x20</size>
          <fields>
            <field>
              <name>FEC</name>
              <bitOffset>0</bitOffset>
              <bitWidth>32</bitWidth>
            </field>
          </fields>
        </register>
      </registers>
    </peripheral>
    <peripheral>
      <name>OCTOSPI2</name>
      <baseAddress>0x5200a000</baseAddress>
      <registers>
        <register>
          <name>CR</name>
          <addressOffset>0x0</addressOffset>
          <size>0x20</size>
          <fields>
            <field>
              <name>EN</name>
              <bitOffset>0</bitOffset>
              <bitWidth>1</bitWidth>
            </field>
            <field>
              <name>ABORT</name>
              <bitOffset>1</bitOffset>
              <bitWidth>1</bitWidth>
            </field>
            <field>
              <name>DMAEN</name>
              <bitOffset>2</bitOffset>
              <bitWidth>1</bitWidth>
            </field>
            <field>
              <name>TCEN</name>
              <bitOffset>3</bitOffset>
              <bitWidth>1</bitWidth>
            </field>
            <field>
              <name>DQM</name>
              <bitOffset>6</bitOffset>
              <bitWidth>1</bitWidth>
            </field>
            <field>
              <name>FSEL</name>
              <bitOffset>7</bitOffset>
              <bitWidth>1</bitWidth>
            </field>
            <field>
              <name>FTHRES</name>
              <bitOffset>8</bitOffset>
              <bitWidth>5</bitWidth>
            </field>
            <field>
              <name>TEIE</name>
              <bitOffset>16</bitOffset>
              <bitWidth>1</bitWidth>
            </field>
            <field>
              <name>TCIE</name>
              <bitOffset>17</bitOffset>
              <bitWidth>1</bitWidth>
            </field>
            <field>
              <name>FTIE</name>
              <bitOffset>18</bitOffset>
              <bitWidth>1</bitWidth>
            </field>
            <field>
              <name>SMIE</name>
              <bitOffset>19</bitOffset>
              <bitWidth>1</bitWidth>
            </field>
            <field>
              <name>TOIE</name>
              <bitOffset>20</bitOffset>
              <bitWidth>1</bitWidth>
            </field>
            <field>
              <name>APMS</name>
              <bitOffset>22</bitOffset>
              <bitWidth>1</bitWidth>
            </field>
            <field>
              <name>PMM</name>
              <bitOffset>23</bitOffset>
              <bitWidth>1</bitWidth>
            </field>
            <field>
              <name>FMODE</name>
              <bitOffset>28</bitOffset>
              <bitWidth>2</bitWidth>
            </field>
          </fields>
        </register>
        <register>
          <name>DCR1</name>
          <addressOffset>0x8</addressOffset>
          <size>0x20</size>
          <fields>
            <field>
              <name>CKMODE</name>
              <bitOffset>0</bitOffset>
              <bitWidth>1</bitWidth>
            </field>
            <field>
              <name>FRCK</name>
              <bitOffset>1</bitOffset>
              <bitWidth>1</bitWidth>
            </field>
            <field>
              <name>DLYBYP</name>
              <bitOffset>3</bitOffset>
              <bitWidth>1</bitWidth>
            </field>
            <field>
              <name>CKCSHT</name>
              <bitOffset>4</bitOffset>
              <bitWidth>3</bitWidth>
            </field>
            <field>
              <name>CSHT</name>
              <bitOffset>8</bitOffset>
              <bitWidth>3</bitWidth>
            </field>
            <field>
              <name>DEVSIZE</name>
              <bitOffset>16</bitOffset>
              <bitWidth>5</bitWidth>
            </field>
            <field>
              <name>MTYP</name>
              <bitOffset>24</bitOffset>
              <bitWidth>3</bitWidth>
            </field>
          </fields>
        </register>
        <register>
          <name>DCR2</name>
          <addressOffset>0xc</addressOffset>
          <size>0x20</size>
          <fields>
            <field>
              <name>PRESCALER</name>
              <bitOffset>0</bitOffset>
              <bitWidth>8</bitWidth>
            </field>
            <field>
              <name>WRAPSIZE</name>
              <bitOffset>16</bitOffset>
              <bitWidth>3</bitWidth>
            </field>
          </fields>
        </register>
        <register>
          <name>DCR3</name>
          <addressOffset>0x10</addressOffset>
          <size>0x20</size>
          <fields>
            <field>
              <name>MAXTRAN</name>
              <bitOffset>0</bitOffset>
              <bitWidth>8</bitWidth>
            </field>
            <field>
              <name>CSBOUND</name>
              <bitOffset>16</bitOffset>
              <bitWidth>5</bitWidth>
            </field>
          </fields>
        </register>
        <register>
          <name>DCR4</name>
          <addressOffset>0x14</addressOffset>
          <size>0x20</size>
          <fields>
            <field>
              <name>REFRESH</name>
              <bitOffset>0</bitOffset>
              <bitWidth>32</bitWidth>
            </field>
          </fields>
        </register>
        <register>
          <name>SR</name>
          <addressOffset>0x20</addressOffset>
          <size>0x20</size>
          <fields>
            <field>
              <name>TEF</name>
              <bitOffset>0</bitOffset>
              <bitWidth>1</bitWidth>
            </field>
            <field>
              <name>TCF</name>
              <bitOffset>1</bitOffset>
              <bitWidth>1</bitWidth>
            </field>
            <field>
              <name>FTF</name>
              <bitOffset>2</bitOffset>
              <bitWidth>1</bitWidth>
            </field>
            <field>
              <name>SMF</name>
              <bitOffset>3</bitOffset>
              <bitWidth>1</bitWidth>
            </field>
            <field>
              <name>TOF</name>
              <bitOffset>4</bitOffset>
              <bitWidth>1</bitWidth>
            </field>
            <field>
              <name>BUSY</name>
              <bitOffset>5</bitOffset>
              <bitWidth>1</bitWidth>
            </field>
            <field>
              <name>FLEVEL</name>
              <bitOffset>8</bitOffset>
              <bitWidth>6</bitWidth>
            </field>
          </fields>
        </register>
        <register>
          <name>FCR</name>
          <addressOffset>0x24</addressOffset>
          <size>0x20</size>
          <fields>
            <field>
              <name>CTEF</name>
              <bitOffset>0</bitOffset>
              <bitWidth>1</bitWidth>
            </field>
            <field>
              <name>CTCF</name>
              <bitOffset>1</bitOffset>
              <bitWidth>1</bitWidth>
            </field>
            <field>
              <name>CSMF</name>
              <bitOffset>3</bitOffset>
              <bitWidth>1</bitWidth>
            </field>
            <field>
              <name>CTOF</name>
              <bitOffset>4</bitOffset>
              <bitWidth>1</bitWidth>
            </field>
          </fields>
        </register>
        <register>
          <name>DLR</name>
          <addressOffset>0x40</addressOffset>
          <size>0x20</size>
          <fields>
            <field>
              <name>DL</name>
              <bitOffset>0</bitOffset>
              <bitWidth>32</bitWidth>
            </field>
          </fields>
        </register>
        <register>
          <name>AR</name>
          <addressOffset>0x48</addressOffset>
          <size>0x20</size>
          <fields>
            <field>
              <name>ADDRESS</name>
              <bitOffset>0</bitOffset>
              <bitWidth>32</bitWidth>
            </field>
          </fields>
        </register>
        <register>
          <name>DR</name>
          <addressOffset>0x50</addressOffset>
          <size>0x20</size>
          <fields>
            <field>
              <name>DATA</name>
              <bitOffset>0</bitOffset>
              <bitWidth>32</bitWidth>
            </field>
          </fields>
        </register>
        <register>
          <name>PSMKR</name>
          <addressOffset>0x80</addressOffset>
          <size>0x20</size>
          <fields>
            <field>
              <name>MASK</name>
              <bitOffset>0</bitOffset>
              <bitWidth>32</bitWidth>
            </field>
          </fields>
        </register>
        <register>
          <name>PSMAR</name>
          <addressOffset>0x88</addressOffset>
          <size>0x20</size>
          <fields>
            <field>
              <name>MATCH</name>
              <bitOffset>0</bitOffset>
              <bitWidth>32</bitWidth>
            </field>
          </fields>
        </register>
        <register>
          <name>PIR</name>
          <addressOffset>0x90</addressOffset>
          <size>0x20</size>
          <fields>
            <field>
              <name>INTERVAL</name>
              <bitOffset>0</bitOffset>
              <bitWidth>16</bitWidth>
            </field>
          </fields>
        </register>
        <register>
          <name>CCR</name>
          <addressOffset>0x100</addressOffset>
          <size>0x20</size>
          <fields>
            <field>
              <name>IMODE</name>
              <bitOffset>0</bitOffset>
              <bitWidth>3</bitWidth>
            </field>
            <field>
              <name>IDTR</name>
              <bitOffset>3</bitOffset>
              <bitWidth>1</bitWidth>
            </field>
            <field>
              <name>ISIZE</name>
              <bitOffset>4</bitOffset>
              <bitWidth>2</bitWidth>
            </field>
            <field>
              <name>ADMODE</name>
              <bitOffset>8</bitOffset>
              <bitWidth>3</bitWidth>
            </field>
            <field>
              <name>ADDTR</name>
              <bitOffset>11</bitOffset>
              <bitWidth>1</bitWidth>
            </field>
            <field>
              <name>ADSIZE</name>
              <bitOffset>12</bitOffset>
              <bitWidth>2</bitWidth>
            </field>
            <field>
              <name>ABMODE</name>
              <bitOffset>16</bitOffset>
              <bitWidth>3</bitWidth>
            </field>
            <field>
              <name>ABDTR</name>
              <bitOffset>19</bitOffset>
              <bitWidth>1</bitWidth>
            </field>
            <field>
              <name>ABSIZE</name>
              <bitOffset>20</bitOffset>
              <bitWidth>2</bitWidth>
            </field>
            <field>
              <name>DMODE</name>
              <bitOffset>24</bitOffset>
              <bitWidth>3</bitWidth>
            </field>
            <field>
              <name>DDTR</name>
              <bitOffset>27</bitOffset>
              <bitWidth>1</bitWidth>
            </field>
            <field>
              <name>DQSE</name>
              <bitOffset>29</bitOffset>
              <bitWidth>1</bitWidth>
            </field>
            <field>
              <name>SIOO</name>
              <bitOffset>31</bitOffset>
              <bitWidth>1</bitWidth>
            </field>
          </fields>
        </register>
        <register>
          <name>TCR</name>
          <addressOffset>0x108</addressOffset>
          <size>0x20</size>
          <fields>
            <field>
              <name>DCYC</name>
              <bitOffset>0</bitOffset>
              <bitWidth>5</bitWidth>
            </field>
            <field>
              <name>DHQC</name>
              <bitOffset>28</bitOffset>
              <bitWidth>1</bitWidth>
            </field>
            <field>
              <name>SSHIFT</name>
              <bitOffset>30</bitOffset>
              <bitWidth>1</bitWidth>
            </field>
          </fields>
        </register>
        <register>
          <name>IR</name>
          <addressOffset>0x110</addressOffset>
          <size>0x20</size>
          <fields>
            <field>
              <name>INSTRUCTION</name>
              <bitOffset>0</bitOffset>
              <bitWidth>32</bitWidth>
            </field>
          </fields>
        </register>
        <register>
          <name>ABR</name>
          <addressOffset>0x120</addressOffset>
          <size>0x20</size>
          <fields>
            <field>
              <name>ALTERNATE</name>
              <bitOffset>0</bitOffset>
              <bitWidth>32</bitWidth>
            </field>
          </fields>
        </register>
        <register>
          <name>LPTR</name>
          <addressOffset>0x130</addressOffset>
          <size>0x20</size>
          <fields>
            <field>
              <name>TIMEOUT</name>
              <bitOffset>0</bitOffset>
              <bitWidth>16</bitWidth>
            </field>
          </fields>
        </register>
        <register>
          <name>WPCCR</name>
          <addressOffset>0x140</addressOffset>
          <size>0x20</size>
          <fields>
            <field>
              <name>IMODE</name>
              <bitOffset>0</bitOffset>
              <bitWidth>3</bitWidth>
            </field>
            <field>
              <name>IDTR</name>
              <bitOffset>3</bitOffset>
              <bitWidth>1</bitWidth>
            </field>
            <field>
              <name>ISIZE</name>
              <bitOffset>4</bitOffset>
              <bitWidth>2</bitWidth>
            </field>
            <field>
              <name>ADMODE</name>
              <bitOffset>8</bitOffset>
              <bitWidth>3</bitWidth>
            </field>
            <field>
              <name>ADDTR</name>
              <bitOffset>11</bitOffset>
              <bitWidth>1</bitWidth>
            </field>
            <field>
              <name>ADSIZE</name>
              <bitOffset>12</bitOffset>
              <bitWidth>2</bitWidth>
            </field>
            <field>
              <name>ABMODE</name>
              <bitOffset>16</bitOffset>
              <bitWidth>3</bitWidth>
            </field>
            <field>
              <name>ABDTR</name>
              <bitOffset>19</bitOffset>
              <bitWidth>1</bitWidth>
            </field>
            <field>
              <name>ABSIZE</name>
              <bitOffset>20</bitOffset>
              <bitWidth>2</bitWidth>
            </field>
            <field>
              <name>DMODE</name>
              <bitOffset>24</bitOffset>
              <bitWidth>3</bitWidth>
            </field>
            <field>
              <name>DDTR</name>
              <bitOffset>27</bitOffset>
              <bitWidth>1</bitWidth>
            </field>
            <field>
              <name>DQSE</name>
              <bitOffset>29</bitOffset>
              <bitWidth>1</bitWidth>
            </field>
            <field>
              <name>SIOO</name>
              <bitOffset>31</bitOffset>
              <bitWidth>1</bitWidth>
            </field>
          </fields>
        </register>
        <register>
          <name>WPTCR</name>
          <addressOffset>0x148</addressOffset>
          <size>0x20</size>
          <fields>
            <field>
              <name>DCYC</name>
              <bitOffset>0</bitOffset>
              <bitWidth>5</bitWidth>
            </field>
            <field>
              <name>DHQC</name>
              <bitOffset>28</bitOffset>
              <bitWidth>1</bitWidth>
            </field>
            <field>
              <name>SSHIFT</name>
              <bitOffset>30</bitOffset>
              <bitWidth>1</bitWidth>
            </field>
          </fields>
        </register>
        <register>
          <name>WPIR</name>
          <addressOffset>0x150</addressOffset>
          <size>0x20</size>
          <fields>
            <field>
              <name>INSTRUCTION</name>
              <bitOffset>0</bitOffset>
              <bitWidth>32</bitWidth>
            </field>
          </fields>
        </register>
        <register>
          <name>WPABR</name>
          <addressOffset>0x160</addressOffset>
          <size>0x20</size>
          <fields>
            <field>
              <name>ALTERNATE</name>
              <bitOffset>0</bitOffset>
              <bitWidth>32</bitWidth>
            </field>
          </fields>
        </register>
        <register>
          <name>WCCR</name>
          <addressOffset>0x180</addressOffset>
          <size>0x20</size>
          <fields>
            <field>
              <name>IMODE</name>
              <bitOffset>0</bitOffset>
              <bitWidth>3</bitWidth>
            </field>
            <field>
              <name>IDTR</name>
              <bitOffset>3</bitOffset>
              <bitWidth>1</bitWidth>
            </field>
            <field>
              <name>ISIZE</name>
              <bitOffset>4</bitOffset>
              <bitWidth>2</bitWidth>
            </field>
            <field>
              <name>ADMODE</name>
              <bitOffset>8</bitOffset>
              <bitWidth>3</bitWidth>
            </field>
            <field>
              <name>ADDTR</name>
              <bitOffset>11</bitOffset>
              <bitWidth>1</bitWidth>
            </field>
            <field>
              <name>ADSIZE</name>
              <bitOffset>12</bitOffset>
              <bitWidth>2</bitWidth>
            </field>
            <field>
              <name>ABMODE</name>
              <bitOffset>16</bitOffset>
              <bitWidth>3</bitWidth>
            </field>
            <field>
              <name>ABDTR</name>
              <bitOffset>19</bitOffset>
              <bitWidth>1</bitWidth>
            </field>
            <field>
              <name>ABSIZE</name>
              <bitOffset>20</bitOffset>
              <bitWidth>2</bitWidth>
            </field>
            <field>
              <name>DMODE</name>
              <bitOffset>24</bitOffset>
              <bitWidth>3</bitWidth>
            </field>
            <field>
              <name>DDTR</name>
              <bitOffset>27</bitOffset>
              <bitWidth>1</bitWidth>
            </field>
            <field>
              <name>DQSE</name>
              <bitOffset>29</bitOffset>
              <bitWidth>1</bitWidth>
            </field>
            <field>
              <name>SIOO</name>
              <bitOffset>31</bitOffset>
              <bitWidth>1</bitWidth>
            </field>
          </fields>
        </register>
        <register>
          <name>WTCR</name>
          <addressOffset>0x188</addressOffset>
          <size>0x20</size>
          <fields>
            <field>
              <name>DCYC</name>
              <bitOffset>0</bitOffset>
              <bitWidth>5</bitWidth>
            </field>
          </fields>
        </register>
        <register>
          <name>WIR</name>
          <addressOffset>0x190</addressOffset>
          <size>0x20</size>
          <fields>
            <field>
              <name>INSTRUCTION</name>
              <bitOffset>0</bitOffset>
              <bitWidth>32</bitWidth>
            </field>
          </fields>
        </register>
        <register>
          <name>WABR</name>
          <addressOffset>0x1a0</addressOffset>
          <size>0x20</size>
          <fields>
            <field>
              <name>ALTERNATE</name>
              <bitOffset>0</bitOffset>
              <bitWidth>32</bitWidth>
            </field>
          </fields>
        </register>
        <register>
          <name>HLCR</name>
          <addressOffset>0x200</addressOffset>
          <size>0x20</size>
          <fields>
            <field>
              <name>LM</name>
              <bitOffset>0</bitOffset>
              <bitWidth>1</bitWidth>
            </field>
            <field>
              <name>WZL</name>
              <bitOffset>1</bitOffset>
              <bitWidth>1</bitWidth>
            </field>
            <field>
              <name>TACC</name>
              <bitOffset>8</bitOffset>
              <bitWidth>8</bitWidth>
            </field>
            <field>
              <name>TRWR</name>
              <bitOffset>16</bitOffset>
              <bitWidth>8</bitWidth>
            </field>
          </fields>
        </register>
        <register>
          <name>HWCFGR</name>
          <addressOffset>0x3ec</addressOffset>
          <size>0x20</size>
        </register>
        <register>
          <name>VER</name>
          <addressOffset>0x3f0</addressOffset>
          <size>0x20</size>
          <fields>
            <field>
              <name>VER</name>
              <bitOffset>0</bitOffset>
              <bitWidth>8</bitWidth>
            </field>
          </fields>
        </register>
        <register>
          <name>ID</name>
          <addressOffset>0x3f4</addressOffset>
          <size>0x20</size>
          <fields>
            <field>
              <name>ID</name>
              <bitOffset>0</bitOffset>
              <bitWidth>32</bitWidth>
            </field>
          </fields>
        </register>
        <register>
          <name>MID</name>
          <addressOffset>0x3f8</addressOffset>
          <size>0x20</size>
          <fields>
            <field>
              <name>MID</name>
              <bitOffset>0</bitOffset>
              <bitWidth>32</bitWidth>
            </field>
          </fields>
        </register>
      </registers>
    </peripheral>
    <peripheral>
      <name>DLYB_OCTOSPI2</name>
      <baseAddress>0x5200b000</baseAddress>
      <registers>
        <register>
          <name>CR</name>
          <addressOffset>0x0</addressOffset>
          <size>0x20</size>
          <fields>
            <field>
              <name>DEN</name>
              <bitOffset>0</bitOffset>
              <bitWidth>1</bitWidth>
            </field>
            <field>
              <name>SEN</name>
              <bitOffset>1</bitOffset>
              <bitWidth>1</bitWidth>
            </field>
          </fields>
        </register>
        <register>
          <name>CFGR</name>
          <addressOffset>0x4</addressOffset>
          <size>0x20</size>
          <fields>
            <field>
              <name>SEL</name>
              <bitOffset>0</bitOffset>
              <bitWidth>4</bitWidth>
            </field>
            <field>
              <name>UNIT</name>
              <bitOffset>8</bitOffset>
              <bitWidth>7</bitWidth>
            </field>
            <field>
              <name>LNG</name>
              <bitOffset>16</bitOffset>
              <bitWidth>12</bitWidth>
            </field>
            <field>
              <name>LNGF</name>
              <bitOffset>31</bitOffset>
              <bitWidth>1</bitWidth>
            </field>
          </fields>
        </register>
      </registers>
    </peripheral>
    <peripheral>
      <name>OCTOSPIM</name>
      <baseAddress>0x5200b400</baseAddress>
      <registers>
        <register>
          <name>CR</name>
          <addressOffset>0x0</addressOffset>
          <size>0x20</size>
          <fields>
            <field>
              <name>MUXEN</name>
              <bitOffset>0</bitOffset>
              <bitWidth>1</bitWidth>
            </field>
            <field>
              <name>REQ2ACK_TIME</name>
              <bitOffset>16</bitOffset>
              <bitWidth>8</bitWidth>
            </field>
          </fields>
        </register>
        <register>
          <name>PCR.0</name>
          <addressOffset>0x4</addressOffset>
          <size>0x20</size>
          <fields>
            <field>
              <name>CLKEN</name>
              <bitOffset>0</bitOffset>
              <bitWidth>1</bitWidth>
            </field>
            <field>
              <name>CLKSRC</name>
              <bitOffset>1</bitOffset>
              <bitWidth>1</bitWidth>
            </field>
            <field>
              <name>DQSEN</name>
              <bitOffset>4</bitOffset>
              <bitWidth>1</bitWidth>
            </field>
            <field>
              <name>DQSSRC</name>
              <bitOffset>5</bitOffset>
              <bitWidth>1</bitWidth>
            </field>
            <field>
              <name>NCSEN</name>
              <bitOffset>8</bitOffset>
              <bitWidth>1</bitWidth>
            </field>
            <field>
              <name>NCSSRC</name>
              <bitOffset>9</bitOffset>
              <bitWidth>1</bitWidth>
            </field>
            <field>
              <name>IOLEN</name>
              <bitOffset>16</bitOffset>
              <bitWidth>1</bitWidth>
            </field>
            <field>
              <name>IOLSRC</name>
              <bitOffset>17</bitOffset>
              <bitWidth>2</bitWidth>
            </field>
            <field>
              <name>IOHEN</name>
              <bitOffset>24</bitOffset>
              <bitWidth>1</bitWidth>
            </field>
            <field>
              <name>IOHSRC</name>
              <bitOffset>25</bitOffset>
              <bitWidth>2</bitWidth>
            </field>
          </fields>
        </register>
        <register>
          <name>PCR.1</name>
          <addressOffset>0x8</addressOffset>
          <size>0x20</size>
          <fields>
            <field>
              <name>CLKEN</name>
              <bitOffset>0</bitOffset>
              <bitWidth>1</bitWidth>
            </field>
            <field>
              <name>CLKSRC</name>
              <bitOffset>1</bitOffset>
              <bitWidth>1</bitWidth>
            </field>
            <field>
              <name>DQSEN</name>
              <bitOffset>4</bitOffset>
              <bitWidth>1</bitWidth>
            </field>
            <field>
              <name>DQSSRC</name>
              <bitOffset>5</bitOffset>
              <bitWidth>1</bitWidth>
            </field>
            <field>
              <name>NCSEN</name>
              <bitOffset>8</bitOffset>
              <bitWidth>1</bitWidth>
            </field>
            <field>
              <name>NCSSRC</name>
              <bitOffset>9</bitOffset>
              <bitWidth>1</bitWidth>
            </field>
            <field>
              <name>IOLEN</name>
              <bitOffset>16</bitOffset>
              <bitWidth>1</bitWidth>
            </field>
            <field>
              <name>IOLSRC</name>
              <bitOffset>17</bitOffset>
              <bitWidth>2</bitWidth>
            </field>
            <field>
              <name>IOHEN</name>
              <bitOffset>24</bitOffset>
              <bitWidth>1</bitWidth>
            </field>
            <field>
              <name>IOHSRC</name>
              <bitOffset>25</bitOffset>
              <bitWidth>2</bitWidth>
            </field>
          </fields>
        </register>
        <register>
          <name>PCR.2</name>
          <addressOffset>0xc</addressOffset>
          <size>0x20</size>
          <fields>
            <field>
              <name>CLKEN</name>
              <bitOffset>0</bitOffset>
              <bitWidth>1</bitWidth>
            </field>
            <field>
              <name>CLKSRC</name>
              <bitOffset>1</bitOffset>
              <bitWidth>1</bitWidth>
            </field>
            <field>
              <name>DQSEN</name>
              <bitOffset>4</bitOffset>
              <bitWidth>1</bitWidth>
            </field>
            <field>
              <name>DQSSRC</name>
              <bitOffset>5</bitOffset>
              <bitWidth>1</bitWidth>
            </field>
            <field>
              <name>NCSEN</name>
              <bitOffset>8</bitOffset>
              <bitWidth>1</bitWidth>
            </field>
            <field>
              <name>NCSSRC</name>
              <bitOffset>9</bitOffset>
              <bitWidth>1</bitWidth>
            </field>
            <field>
              <name>IOLEN</name>
              <bitOffset>16</bitOffset>
              <bitWidth>1</bitWidth>
            </field>
            <field>
              <name>IOLSRC</name>
              <bitOffset>17</bitOffset>
              <bitWidth>2</bitWidth>
            </field>
            <field>
              <name>IOHEN</name>
              <bitOffset>24</bitOffset>
              <bitWidth>1</bitWidth>
            </field>
            <field>
              <name>IOHSRC</name>
              <bitOffset>25</bitOffset>
              <bitWidth>2</bitWidth>
            </field>
          </fields>
        </register>
      </registers>
    </peripheral>
    <peripheral>
      <name>EXTI</name>
      <baseAddress>0x58000000</baseAddress>
      <registers>
        <register>
          <name>RTSR1</name>
          <addressOffset>0x0</addressOffset>
          <size>0x20</size>
          <fields>
            <field>
              <name>TR0</name>
              <bitOffset>0</bitOffset>
              <bitWidth>1</bitWidth>
            </field>
            <field>
              <name>TR1</name>
              <bitOffset>1</bitOffset>
              <bitWidth>1</bitWidth>
            </field>
            <field>
              <name>TR2</name>
              <bitOffset>2</bitOffset>
              <bitWidth>1</bitWidth>
            </field>
            <field>
              <name>TR3</name>
              <bitOffset>3</bitOffset>
              <bitWidth>1</bitWidth>
            </field>
            <field>
              <name>TR4</name>
              <bitOffset>4</bitOffset>
              <bitWidth>1</bitWidth>
            </field>
            <field>
              <name>TR5</name>
              <bitOffset>5</bitOffset>
              <bitWidth>1</bitWidth>
            </field>
            <field>
              <name>TR6</name>
              <bitOffset>6</bitOffset>
              <bitWidth>1</bitWidth>
            </field>
            <field>
              <name>TR7</name>
              <bitOffset>7</bitOffset>
              <bitWidth>1</bitWidth>
            </field>
            <field>
              <name>TR8</name>
              <bitOffset>8</bitOffset>
              <bitWidth>1</bitWidth>
            </field>
            <field>
              <name>TR9</name>
              <bitOffset>9</bitOffset>
              <bitWidth>1</bitWidth>
            </field>
            <field>
              <name>TR10</name>
              <bitOffset>10</bitOffset>
              <bitWidth>1</bitWidth>
            </field>
            <field>
              <name>TR11</name>
              <bitOffset>11</bitOffset>
              <bitWidth>1</bitWidth>
            </field>
            <field>
              <name>TR12</name>
              <bitOffset>12</bitOffset>
              <bitWidth>1</bitWidth>
            </field>
            <field>
              <name>TR13</name>
              <bitOffset>13</bitOffset>
              <bitWidth>1</bitWidth>
            </field>
            <field>
              <name>TR14</name>
              <bitOffset>14</bitOffset>
              <bitWidth>1</bitWidth>
            </field>
            <field>
              <name>TR15</name>
              <bitOffset>15</bitOffset>
              <bitWidth>1</bitWidth>
            </field>
            <field>
              <name>TR16</name>
              <bitOffset>16</bitOffset>
              <bitWidth>1</bitWidth>
            </field>
            <field>
              <name>TR17</name>
              <bitOffset>17</bitOffset>
              <bitWidth>1</bitWidth>
            </field>
            <field>
              <name>TR18</name>
              <bitOffset>18</bitOffset>
              <bitWidth>1</bitWidth>
            </field>
            <field>
              <name>TR19</name>
              <bitOffset>19</bitOffset>
              <bitWidth>1</bitWidth>
            </field>
            <field>
              <name>TR20</name>
              <bitOffset>20</bitOffset>
              <bitWidth>1</bitWidth>
            </field>
            <field>
              <name>TR21</name>
              <bitOffset>21</bitOffset>
              <bitWidth>1</bitWidth>
            </field>
          </fields>
        </register>
        <register>
          <name>FTSR1</name>
          <addressOffset>0x4</addressOffset>
          <size>0x20</size>
          <fields>
            <field>
              <name>TR0</name>
              <bitOffset>0</bitOffset>
              <bitWidth>1</bitWidth>
            </field>
            <field>
              <name>TR1</name>
              <bitOffset>1</bitOffset>
              <bitWidth>1</bitWidth>
            </field>
            <field>
              <name>TR2</name>
              <bitOffset>2</bitOffset>
              <bitWidth>1</bitWidth>
            </field>
            <field>
              <name>TR3</name>
              <bitOffset>3</bitOffset>
              <bitWidth>1</bitWidth>
            </field>
            <field>
              <name>TR4</name>
              <bitOffset>4</bitOffset>
              <bitWidth>1</bitWidth>
            </field>
            <field>
              <name>TR5</name>
              <bitOffset>5</bitOffset>
              <bitWidth>1</bitWidth>
            </field>
            <field>
              <name>TR6</name>
              <bitOffset>6</bitOffset>
              <bitWidth>1</bitWidth>
            </field>
            <field>
              <name>TR7</name>
              <bitOffset>7</bitOffset>
              <bitWidth>1</bitWidth>
            </field>
            <field>
              <name>TR8</name>
              <bitOffset>8</bitOffset>
              <bitWidth>1</bitWidth>
            </field>
            <field>
              <name>TR9</name>
              <bitOffset>9</bitOffset>
              <bitWidth>1</bitWidth>
            </field>
            <field>
              <name>TR10</name>
              <bitOffset>10</bitOffset>
              <bitWidth>1</bitWidth>
            </field>
            <field>
              <name>TR11</name>
              <bitOffset>11</bitOffset>
              <bitWidth>1</bitWidth>
            </field>
            <field>
              <name>TR12</name>
              <bitOffset>12</bitOffset>
              <bitWidth>1</bitWidth>
            </field>
            <field>
              <name>TR13</name>
              <bitOffset>13</bitOffset>
              <bitWidth>1</bitWidth>
            </field>
            <field>
              <name>TR14</name>
              <bitOffset>14</bitOffset>
              <bitWidth>1</bitWidth>
            </field>
            <field>
              <name>TR15</name>
              <bitOffset>15</bitOffset>
              <bitWidth>1</bitWidth>
            </field>
            <field>
              <name>TR16</name>
              <bitOffset>16</bitOffset>
              <bitWidth>1</bitWidth>
            </field>
            <field>
              <name>TR17</name>
              <bitOffset>17</bitOffset>
              <bitWidth>1</bitWidth>
            </field>
            <field>
              <name>TR18</name>
              <bitOffset>18</bitOffset>
              <bitWidth>1</bitWidth>
            </field>
            <field>
              <name>TR19</name>
              <bitOffset>19</bitOffset>
              <bitWidth>1</bitWidth>
            </field>
            <field>
              <name>TR20</name>
              <bitOffset>20</bitOffset>
              <bitWidth>1</bitWidth>
            </field>
            <field>
              <name>TR21</name>
              <bitOffset>21</bitOffset>
              <bitWidth>1</bitWidth>
            </field>
          </fields>
        </register>
        <register>
          <name>SWIER1</name>
          <addressOffset>0x8</addressOffset>
          <size>0x20</size>
          <fields>
            <field>
              <name>SWIER0</name>
              <bitOffset>0</bitOffset>
              <bitWidth>1</bitWidth>
            </field>
            <field>
              <name>SWIER1</name>
              <bitOffset>1</bitOffset>
              <bitWidth>1</bitWidth>
            </field>
            <field>
              <name>SWIER2</name>
              <bitOffset>2</bitOffset>
              <bitWidth>1</bitWidth>
            </field>
            <field>
              <name>SWIER3</name>
              <bitOffset>3</bitOffset>
              <bitWidth>1</bitWidth>
            </field>
            <field>
              <name>SWIER4</name>
              <bitOffset>4</bitOffset>
              <bitWidth>1</bitWidth>
            </field>
            <field>
              <name>SWIER5</name>
              <bitOffset>5</bitOffset>
              <bitWidth>1</bitWidth>
            </field>
            <field>
              <name>SWIER6</name>
              <bitOffset>6</bitOffset>
              <bitWidth>1</bitWidth>
            </field>
            <field>
              <name>SWIER7</name>
              <bitOffset>7</bitOffset>
              <bitWidth>1</bitWidth>
            </field>
            <field>
              <name>SWIER8</name>
              <bitOffset>8</bitOffset>
              <bitWidth>1</bitWidth>
            </field>
            <field>
              <name>SWIER9</name>
              <bitOffset>9</bitOffset>
              <bitWidth>1</bitWidth>
            </field>
            <field>
              <name>SWIER10</name>
              <bitOffset>10</bitOffset>
              <bitWidth>1</bitWidth>
            </field>
            <field>
              <name>SWIER11</name>
              <bitOffset>11</bitOffset>
              <bitWidth>1</bitWidth>
            </field>
            <field>
              <name>SWIER12</name>
              <bitOffset>12</bitOffset>
              <bitWidth>1</bitWidth>
            </field>
            <field>
              <name>SWIER13</name>
              <bitOffset>13</bitOffset>
              <bitWidth>1</bitWidth>
            </field>
            <field>
              <name>SWIER14</name>
              <bitOffset>14</bitOffset>
              <bitWidth>1</bitWidth>
            </field>
            <field>
              <name>SWIER15</name>
              <bitOffset>15</bitOffset>
              <bitWidth>1</bitWidth>
            </field>
            <field>
              <name>SWIER16</name>
              <bitOffset>16</bitOffset>
              <bitWidth>1</bitWidth>
            </field>
            <field>
              <name>SWIER17</name>
              <bitOffset>17</bitOffset>
              <bitWidth>1</bitWidth>
            </field>
            <field>
              <name>SWIER18</name>
              <bitOffset>18</bitOffset>
              <bitWidth>1</bitWidth>
            </field>
            <field>
              <name>SWIER19</name>
              <bitOffset>19</bitOffset>
              <bitWidth>1</bitWidth>
            </field>
            <field>
              <name>SWIER20</name>
              <bitOffset>20</bitOffset>
              <bitWidth>1</bitWidth>
            </field>
            <field>
              <name>SWIER21</name>
              <bitOffset>21</bitOffset>
              <bitWidth>1</bitWidth>
            </field>
          </fields>
        </register>
        <register>
          <name>D3PMR1</name>
          <addressOffset>0xc</addressOffset>
          <size>0x20</size>
          <fields>
            <field>
              <name>MR0</name>
              <bitOffset>0</bitOffset>
              <bitWidth>1</bitWidth>
            </field>
            <field>
              <name>MR1</name>
              <bitOffset>1</bitOffset>
              <bitWidth>1</bitWidth>
            </field>
            <field>
              <name>MR2</name>
              <bitOffset>2</bitOffset>
              <bitWidth>1</bitWidth>
            </field>
            <field>
              <name>MR3</name>
              <bitOffset>3</bitOffset>
              <bitWidth>1</bitWidth>
            </field>
            <field>
              <name>MR4</name>
              <bitOffset>4</bitOffset>
              <bitWidth>1</bitWidth>
            </field>
            <field>
              <name>MR5</name>
              <bitOffset>5</bitOffset>
              <bitWidth>1</bitWidth>
            </field>
            <field>
              <name>MR6</name>
              <bitOffset>6</bitOffset>
              <bitWidth>1</bitWidth>
            </field>
            <field>
              <name>MR7</name>
              <bitOffset>7</bitOffset>
              <bitWidth>1</bitWidth>
            </field>
            <field>
              <name>MR8</name>
              <bitOffset>8</bitOffset>
              <bitWidth>1</bitWidth>
            </field>
            <field>
              <name>MR9</name>
              <bitOffset>9</bitOffset>
              <bitWidth>1</bitWidth>
            </field>
            <field>
              <name>MR10</name>
              <bitOffset>10</bitOffset>
              <bitWidth>1</bitWidth>
            </field>
            <field>
              <name>MR11</name>
              <bitOffset>11</bitOffset>
              <bitWidth>1</bitWidth>
            </field>
            <field>
              <name>MR12</name>
              <bitOffset>12</bitOffset>
              <bitWidth>1</bitWidth>
            </field>
            <field>
              <name>MR13</name>
              <bitOffset>13</bitOffset>
              <bitWidth>1</bitWidth>
            </field>
            <field>
              <name>MR14</name>
              <bitOffset>14</bitOffset>
              <bitWidth>1</bitWidth>
            </field>
            <field>
              <name>MR15</name>
              <bitOffset>15</bitOffset>
              <bitWidth>1</bitWidth>
            </field>
            <field>
              <name>MR19</name>
              <bitOffset>19</bitOffset>
              <bitWidth>1</bitWidth>
            </field>
            <field>
              <name>MR20</name>
              <bitOffset>20</bitOffset>
              <bitWidth>1</bitWidth>
            </field>
            <field>
              <name>MR21</name>
              <bitOffset>21</bitOffset>
              <bitWidth>1</bitWidth>
            </field>
            <field>
              <name>MR25</name>
              <bitOffset>24</bitOffset>
              <bitWidth>1</bitWidth>
            </field>
          </fields>
        </register>
        <register>
          <name>D3PCR1L</name>
          <addressOffset>0x10</addressOffset>
          <size>0x20</size>
          <fields>
            <field>
              <name>PCS0</name>
              <bitOffset>0</bitOffset>
              <bitWidth>2</bitWidth>
            </field>
            <field>
              <name>PCS1</name>
              <bitOffset>2</bitOffset>
              <bitWidth>2</bitWidth>
            </field>
            <field>
              <name>PCS2</name>
              <bitOffset>4</bitOffset>
              <bitWidth>2</bitWidth>
            </field>
            <field>
              <name>PCS3</name>
              <bitOffset>6</bitOffset>
              <bitWidth>2</bitWidth>
            </field>
            <field>
              <name>PCS4</name>
              <bitOffset>8</bitOffset>
              <bitWidth>2</bitWidth>
            </field>
            <field>
              <name>PCS5</name>
              <bitOffset>10</bitOffset>
              <bitWidth>2</bitWidth>
            </field>
            <field>
              <name>PCS6</name>
              <bitOffset>12</bitOffset>
              <bitWidth>2</bitWidth>
            </field>
            <field>
              <name>PCS7</name>
              <bitOffset>14</bitOffset>
              <bitWidth>2</bitWidth>
            </field>
            <field>
              <name>PCS8</name>
              <bitOffset>16</bitOffset>
              <bitWidth>2</bitWidth>
            </field>
            <field>
              <name>PCS9</name>
              <bitOffset>18</bitOffset>
              <bitWidth>2</bitWidth>
            </field>
            <field>
              <name>PCS10</name>
              <bitOffset>20</bitOffset>
              <bitWidth>2</bitWidth>
            </field>
            <field>
              <name>PCS11</name>
              <bitOffset>22</bitOffset>
              <bitWidth>2</bitWidth>
            </field>
            <field>
              <name>PCS12</name>
              <bitOffset>24</bitOffset>
              <bitWidth>2</bitWidth>
            </field>
            <field>
              <name>PCS13</name>
              <bitOffset>26</bitOffset>
              <bitWidth>2</bitWidth>
            </field>
            <field>
              <name>PCS14</name>
              <bitOffset>28</bitOffset>
              <bitWidth>2</bitWidth>
            </field>
            <field>
              <name>PCS15</name>
              <bitOffset>30</bitOffset>
              <bitWidth>2</bitWidth>
            </field>
          </fields>
        </register>
        <register>
          <name>D3PCR1H</name>
          <addressOffset>0x14</addressOffset>
          <size>0x20</size>
          <fields>
            <field>
              <name>PCS19</name>
              <bitOffset>6</bitOffset>
              <bitWidth>2</bitWidth>
            </field>
            <field>
              <name>PCS20</name>
              <bitOffset>8</bitOffset>
              <bitWidth>2</bitWidth>
            </field>
            <field>
              <name>PCS21</name>
              <bitOffset>10</bitOffset>
              <bitWidth>2</bitWidth>
            </field>
            <field>
              <name>PCS25</name>
              <bitOffset>18</bitOffset>
              <bitWidth>2</bitWidth>
            </field>
          </fields>
        </register>
        <register>
          <name>RTSR2</name>
          <addressOffset>0x20</addressOffset>
          <size>0x20</size>
          <fields>
            <field>
              <name>TR49</name>
              <bitOffset>17</bitOffset>
              <bitWidth>1</bitWidth>
            </field>
            <field>
              <name>TR51</name>
              <bitOffset>19</bitOffset>
              <bitWidth>1</bitWidth>
            </field>
          </fields>
        </register>
        <register>
          <name>FTSR2</name>
          <addressOffset>0x24</addressOffset>
          <size>0x20</size>
          <fields>
            <field>
              <name>TR49</name>
              <bitOffset>17</bitOffset>
              <bitWidth>1</bitWidth>
            </field>
            <field>
              <name>TR51</name>
              <bitOffset>19</bitOffset>
              <bitWidth>1</bitWidth>
            </field>
          </fields>
        </register>
        <register>
          <name>SWIER2</name>
          <addressOffset>0x28</addressOffset>
          <size>0x20</size>
          <fields>
            <field>
              <name>SWIER49</name>
              <bitOffset>17</bitOffset>
              <bitWidth>1</bitWidth>
            </field>
            <field>
              <name>SWIER51</name>
              <bitOffset>19</bitOffset>
              <bitWidth>1</bitWidth>
            </field>
          </fields>
        </register>
        <register>
          <name>D3PMR2</name>
          <addressOffset>0x2c</addressOffset>
          <size>0x20</size>
          <fields>
            <field>
              <name>MR34</name>
              <bitOffset>2</bitOffset>
              <bitWidth>1</bitWidth>
            </field>
            <field>
              <name>MR35</name>
              <bitOffset>3</bitOffset>
              <bitWidth>1</bitWidth>
            </field>
            <field>
              <name>MR41</name>
              <bitOffset>9</bitOffset>
              <bitWidth>1</bitWidth>
            </field>
            <field>
              <name>MR48</name>
              <bitOffset>16</bitOffset>
              <bitWidth>1</bitWidth>
            </field>
            <field>
              <name>MR49</name>
              <bitOffset>17</bitOffset>
              <bitWidth>1</bitWidth>
            </field>
            <field>
              <name>MR50</name>
              <bitOffset>18</bitOffset>
              <bitWidth>1</bitWidth>
            </field>
            <field>
              <name>MR51</name>
              <bitOffset>19</bitOffset>
              <bitWidth>1</bitWidth>
            </field>
            <field>
              <name>MR52</name>
              <bitOffset>20</bitOffset>
              <bitWidth>1</bitWidth>
            </field>
            <field>
              <name>MR53</name>
              <bitOffset>21</bitOffset>
              <bitWidth>1</bitWidth>
            </field>
          </fields>
        </register>
        <register>
          <name>D3PCR2L</name>
          <addressOffset>0x30</addressOffset>
          <size>0x20</size>
          <fields>
            <field>
              <name>PCS34</name>
              <bitOffset>4</bitOffset>
              <bitWidth>2</bitWidth>
            </field>
            <field>
              <name>PCS35</name>
              <bitOffset>6</bitOffset>
              <bitWidth>2</bitWidth>
            </field>
            <field>
              <name>PCS41</name>
              <bitOffset>18</bitOffset>
              <bitWidth>2</bitWidth>
            </field>
          </fields>
        </register>
        <register>
          <name>D3PCR2H</name>
          <addressOffset>0x34</addressOffset>
          <size>0x20</size>
          <fields>
            <field>
              <name>PCS48</name>
              <bitOffset>0</bitOffset>
              <bitWidth>2</bitWidth>
            </field>
            <field>
              <name>PCS49</name>
              <bitOffset>2</bitOffset>
              <bitWidth>2</bitWidth>
            </field>
            <field>
              <name>PCS50</name>
              <bitOffset>4</bitOffset>
              <bitWidth>2</bitWidth>
            </field>
            <field>
              <name>PCS51</name>
              <bitOffset>6</bitOffset>
              <bitWidth>2</bitWidth>
            </field>
            <field>
              <name>PCS52</name>
              <bitOffset>8</bitOffset>
              <bitWidth>2</bitWidth>
            </field>
            <field>
              <name>PCS53</name>
              <bitOffset>10</bitOffset>
              <bitWidth>2</bitWidth>
            </field>
          </fields>
        </register>
        <register>
          <name>RTSR3</name>
          <addressOffset>0x40</addressOffset>
          <size>0x20</size>
          <fields>
            <field>
              <name>TR85</name>
              <bitOffset>21</bitOffset>
              <bitWidth>1</bitWidth>
            </field>
            <field>
              <name>TR86</name>
              <bitOffset>22</bitOffset>
              <bitWidth>1</bitWidth>
            </field>
          </fields>
        </register>
        <register>
          <name>FTSR3</name>
          <addressOffset>0x44</addressOffset>
          <size>0x20</size>
          <fields>
            <field>
              <name>TR85</name>
              <bitOffset>21</bitOffset>
              <bitWidth>1</bitWidth>
            </field>
            <field>
              <name>TR86</name>
              <bitOffset>22</bitOffset>
              <bitWidth>1</bitWidth>
            </field>
          </fields>
        </register>
        <register>
          <name>SWIER3</name>
          <addressOffset>0x48</addressOffset>
          <size>0x20</size>
          <fields>
            <field>
              <name>SWIER85</name>
              <bitOffset>21</bitOffset>
              <bitWidth>1</bitWidth>
            </field>
            <field>
              <name>SWIER86</name>
              <bitOffset>22</bitOffset>
              <bitWidth>1</bitWidth>
            </field>
          </fields>
        </register>
        <register>
          <name>D3PMR3</name>
          <addressOffset>0x4c</addressOffset>
          <size>0x20</size>
          <fields>
            <field>
              <name>MR88</name>
              <bitOffset>24</bitOffset>
              <bitWidth>1</bitWidth>
            </field>
          </fields>
        </register>
        <register>
          <name>D3PCR3L</name>
          <addressOffset>0x50</addressOffset>
          <size>0x20</size>
        </register>
        <register>
          <name>D3PCR3H</name>
          <addressOffset>0x54</addressOffset>
          <size>0x20</size>
          <fields>
            <field>
              <name>PCS88</name>
              <bitOffset>16</bitOffset>
              <bitWidth>2</bitWidth>
            </field>
          </fields>
        </register>
        <register>
          <name>IMR1</name>
          <addressOffset>0x80</addressOffset>
          <size>0x20</size>
          <fields>
            <field>
              <name>IM0</name>
              <bitOffset>0</bitOffset>
              <bitWidth>1</bitWidth>
            </field>
            <field>
              <name>IM1</name>
              <bitOffset>1</bitOffset>
              <bitWidth>1</bitWidth>
            </field>
            <field>
              <name>IM2</name>
              <bitOffset>2</bitOffset>
              <bitWidth>1</bitWidth>
            </field>
            <field>
              <name>IM3</name>
              <bitOffset>3</bitOffset>
              <bitWidth>1</bitWidth>
            </field>
            <field>
              <name>IM4</name>
              <bitOffset>4</bitOffset>
              <bitWidth>1</bitWidth>
            </field>
            <field>
              <name>IM5</name>
              <bitOffset>5</bitOffset>
              <bitWidth>1</bitWidth>
            </field>
            <field>
              <name>IM6</name>
              <bitOffset>6</bitOffset>
              <bitWidth>1</bitWidth>
            </field>
            <field>
              <name>IM7</name>
              <bitOffset>7</bitOffset>
              <bitWidth>1</bitWidth>
            </field>
            <field>
              <name>IM8</name>
              <bitOffset>8</bitOffset>
              <bitWidth>1</bitWidth>
            </field>
            <field>
              <name>IM9</name>
              <bitOffset>9</bitOffset>
              <bitWidth>1</bitWidth>
            </field>
            <field>
              <name>IM10</name>
              <bitOffset>10</bitOffset>
              <bitWidth>1</bitWidth>
            </field>
            <field>
              <name>IM11</name>
              <bitOffset>11</bitOffset>
              <bitWidth>1</bitWidth>
            </field>
            <field>
              <name>IM12</name>
              <bitOffset>12</bitOffset>
              <bitWidth>1</bitWidth>
            </field>
            <field>
              <name>IM13</name>
              <bitOffset>13</bitOffset>
              <bitWidth>1</bitWidth>
            </field>
            <field>
              <name>IM14</name>
              <bitOffset>14</bitOffset>
              <bitWidth>1</bitWidth>
            </field>
            <field>
              <name>IM15</name>
              <bitOffset>15</bitOffset>
              <bitWidth>1</bitWidth>
            </field>
            <field>
              <name>IM16</name>
              <bitOffset>16</bitOffset>
              <bitWidth>1</bitWidth>
            </field>
            <field>
              <name>IM17</name>
              <bitOffset>17</bitOffset>
              <bitWidth>1</bitWidth>
            </field>
            <field>
              <name>IM18</name>
              <bitOffset>18</bitOffset>
              <bitWidth>1</bitWidth>
            </field>
            <field>
              <name>IM19</name>
              <bitOffset>19</bitOffset>
              <bitWidth>1</bitWidth>
            </field>
            <field>
              <name>IM20</name>
              <bitOffset>20</bitOffset>
              <bitWidth>1</bitWidth>
            </field>
            <field>
              <name>IM21</name>
              <bitOffset>21</bitOffset>
              <bitWidth>1</bitWidth>
            </field>
            <field>
              <name>IM22</name>
              <bitOffset>22</bitOffset>
              <bitWidth>1</bitWidth>
            </field>
            <field>
              <name>IM23</name>
              <bitOffset>23</bitOffset>
              <bitWidth>1</bitWidth>
            </field>
            <field>
              <name>IM24</name>
              <bitOffset>24</bitOffset>
              <bitWidth>1</bitWidth>
            </field>
            <field>
              <name>IM25</name>
              <bitOffset>25</bitOffset>
              <bitWidth>1</bitWidth>
            </field>
            <field>
              <name>IM26</name>
              <bitOffset>26</bitOffset>
              <bitWidth>1</bitWidth>
            </field>
            <field>
              <name>IM27</name>
              <bitOffset>27</bitOffset>
              <bitWidth>1</bitWidth>
            </field>
            <field>
              <name>IM28</name>
              <bitOffset>28</bitOffset>
              <bitWidth>1</bitWidth>
            </field>
            <field>
              <name>IM29</name>
              <bitOffset>29</bitOffset>
              <bitWidth>1</bitWidth>
            </field>
            <field>
              <name>IM30</name>
              <bitOffset>30</bitOffset>
              <bitWidth>1</bitWidth>
            </field>
            <field>
              <name>IM31</name>
              <bitOffset>31</bitOffset>
              <bitWidth>1</bitWidth>
            </field>
          </fields>
        </register>
        <register>
          <name>EMR1</name>
          <addressOffset>0x84</addressOffset>
          <size>0x20</size>
          <fields>
            <field>
              <name>EM0</name>
              <bitOffset>0</bitOffset>
              <bitWidth>1</bitWidth>
            </field>
            <field>
              <name>EM1</name>
              <bitOffset>1</bitOffset>
              <bitWidth>1</bitWidth>
            </field>
            <field>
              <name>EM2</name>
              <bitOffset>2</bitOffset>
              <bitWidth>1</bitWidth>
            </field>
            <field>
              <name>EM3</name>
              <bitOffset>3</bitOffset>
              <bitWidth>1</bitWidth>
            </field>
            <field>
              <name>EM4</name>
              <bitOffset>4</bitOffset>
              <bitWidth>1</bitWidth>
            </field>
            <field>
              <name>EM5</name>
              <bitOffset>5</bitOffset>
              <bitWidth>1</bitWidth>
            </field>
            <field>
              <name>EM6</name>
              <bitOffset>6</bitOffset>
              <bitWidth>1</bitWidth>
            </field>
            <field>
              <name>EM7</name>
              <bitOffset>7</bitOffset>
              <bitWidth>1</bitWidth>
            </field>
            <field>
              <name>EM8</name>
              <bitOffset>8</bitOffset>
              <bitWidth>1</bitWidth>
            </field>
            <field>
              <name>EM9</name>
              <bitOffset>9</bitOffset>
              <bitWidth>1</bitWidth>
            </field>
            <field>
              <name>EM10</name>
              <bitOffset>10</bitOffset>
              <bitWidth>1</bitWidth>
            </field>
            <field>
              <name>EM11</name>
              <bitOffset>11</bitOffset>
              <bitWidth>1</bitWidth>
            </field>
            <field>
              <name>EM12</name>
              <bitOffset>12</bitOffset>
              <bitWidth>1</bitWidth>
            </field>
            <field>
              <name>EM13</name>
              <bitOffset>13</bitOffset>
              <bitWidth>1</bitWidth>
            </field>
            <field>
              <name>EM14</name>
              <bitOffset>14</bitOffset>
              <bitWidth>1</bitWidth>
            </field>
            <field>
              <name>EM15</name>
              <bitOffset>15</bitOffset>
              <bitWidth>1</bitWidth>
            </field>
            <field>
              <name>EM16</name>
              <bitOffset>16</bitOffset>
              <bitWidth>1</bitWidth>
            </field>
            <field>
              <name>EM17</name>
              <bitOffset>17</bitOffset>
              <bitWidth>1</bitWidth>
            </field>
            <field>
              <name>EM18</name>
              <bitOffset>18</bitOffset>
              <bitWidth>1</bitWidth>
            </field>
            <field>
              <name>EM20</name>
              <bitOffset>20</bitOffset>
              <bitWidth>1</bitWidth>
            </field>
            <field>
              <name>EM21</name>
              <bitOffset>21</bitOffset>
              <bitWidth>1</bitWidth>
            </field>
            <field>
              <name>EM22</name>
              <bitOffset>22</bitOffset>
              <bitWidth>1</bitWidth>
            </field>
            <field>
              <name>EM23</name>
              <bitOffset>23</bitOffset>
              <bitWidth>1</bitWidth>
            </field>
            <field>
              <name>EM24</name>
              <bitOffset>24</bitOffset>
              <bitWidth>1</bitWidth>
            </field>
            <field>
              <name>EM25</name>
              <bitOffset>25</bitOffset>
              <bitWidth>1</bitWidth>
            </field>
            <field>
              <name>EM26</name>
              <bitOffset>26</bitOffset>
              <bitWidth>1</bitWidth>
            </field>
            <field>
              <name>EM27</name>
              <bitOffset>27</bitOffset>
              <bitWidth>1</bitWidth>
            </field>
            <field>
              <name>EM28</name>
              <bitOffset>28</bitOffset>
              <bitWidth>1</bitWidth>
            </field>
            <field>
              <name>EM29</name>
              <bitOffset>29</bitOffset>
              <bitWidth>1</bitWidth>
            </field>
            <field>
              <name>EM30</name>
              <bitOffset>30</bitOffset>
              <bitWidth>1</bitWidth>
            </field>
            <field>
              <name>EM31</name>
              <bitOffset>31</bitOffset>
              <bitWidth>1</bitWidth>
            </field>
          </fields>
        </register>
        <register>
          <name>PR1</name>
          <addressOffset>0x88</addressOffset>
          <size>0x20</size>
          <fields>
            <field>
              <name>PR0</name>
              <bitOffset>0</bitOffset>
              <bitWidth>1</bitWidth>
            </field>
            <field>
              <name>PR1</name>
              <bitOffset>1</bitOffset>
              <bitWidth>1</bitWidth>
            </field>
            <field>
              <name>PR2</name>
              <bitOffset>2</bitOffset>
              <bitWidth>1</bitWidth>
            </field>
            <field>
              <name>PR3</name>
              <bitOffset>3</bitOffset>
              <bitWidth>1</bitWidth>
            </field>
            <field>
              <name>PR4</name>
              <bitOffset>4</bitOffset>
              <bitWidth>1</bitWidth>
            </field>
            <field>
              <name>PR5</name>
              <bitOffset>5</bitOffset>
              <bitWidth>1</bitWidth>
            </field>
            <field>
              <name>PR6</name>
              <bitOffset>6</bitOffset>
              <bitWidth>1</bitWidth>
            </field>
            <field>
              <name>PR7</name>
              <bitOffset>7</bitOffset>
              <bitWidth>1</bitWidth>
            </field>
            <field>
              <name>PR8</name>
              <bitOffset>8</bitOffset>
              <bitWidth>1</bitWidth>
            </field>
            <field>
              <name>PR9</name>
              <bitOffset>9</bitOffset>
              <bitWidth>1</bitWidth>
            </field>
            <field>
              <name>PR10</name>
              <bitOffset>10</bitOffset>
              <bitWidth>1</bitWidth>
            </field>
            <field>
              <name>PR11</name>
              <bitOffset>11</bitOffset>
              <bitWidth>1</bitWidth>
            </field>
            <field>
              <name>PR12</name>
              <bitOffset>12</bitOffset>
              <bitWidth>1</bitWidth>
            </field>
            <field>
              <name>PR13</name>
              <bitOffset>13</bitOffset>
              <bitWidth>1</bitWidth>
            </field>
            <field>
              <name>PR14</name>
              <bitOffset>14</bitOffset>
              <bitWidth>1</bitWidth>
            </field>
            <field>
              <name>PR15</name>
              <bitOffset>15</bitOffset>
              <bitWidth>1</bitWidth>
            </field>
            <field>
              <name>PR16</name>
              <bitOffset>16</bitOffset>
              <bitWidth>1</bitWidth>
            </field>
            <field>
              <name>PR17</name>
              <bitOffset>17</bitOffset>
              <bitWidth>1</bitWidth>
            </field>
            <field>
              <name>PR18</name>
              <bitOffset>18</bitOffset>
              <bitWidth>1</bitWidth>
            </field>
            <field>
              <name>PR19</name>
              <bitOffset>19</bitOffset>
              <bitWidth>1</bitWidth>
            </field>
            <field>
              <name>PR20</name>
              <bitOffset>20</bitOffset>
              <bitWidth>1</bitWidth>
            </field>
            <field>
              <name>PR21</name>
              <bitOffset>21</bitOffset>
              <bitWidth>1</bitWidth>
            </field>
          </fields>
        </register>
        <register>
          <name>IMR2</name>
          <addressOffset>0x90</addressOffset>
          <size>0x20</size>
          <fields>
            <field>
              <name>IM32</name>
              <bitOffset>0</bitOffset>
              <bitWidth>1</bitWidth>
            </field>
            <field>
              <name>IM33</name>
              <bitOffset>1</bitOffset>
              <bitWidth>1</bitWidth>
            </field>
            <field>
              <name>IM34</name>
              <bitOffset>2</bitOffset>
              <bitWidth>1</bitWidth>
            </field>
            <field>
              <name>IM35</name>
              <bitOffset>3</bitOffset>
              <bitWidth>1</bitWidth>
            </field>
            <field>
              <name>IM36</name>
              <bitOffset>4</bitOffset>
              <bitWidth>1</bitWidth>
            </field>
            <field>
              <name>IM37</name>
              <bitOffset>5</bitOffset>
              <bitWidth>1</bitWidth>
            </field>
            <field>
              <name>IM38</name>
              <bitOffset>6</bitOffset>
              <bitWidth>1</bitWidth>
            </field>
            <field>
              <name>IM39</name>
              <bitOffset>7</bitOffset>
              <bitWidth>1</bitWidth>
            </field>
            <field>
              <name>IM40</name>
              <bitOffset>8</bitOffset>
              <bitWidth>1</bitWidth>
            </field>
            <field>
              <name>IM41</name>
              <bitOffset>9</bitOffset>
              <bitWidth>1</bitWidth>
            </field>
            <field>
              <name>IM42</name>
              <bitOffset>10</bitOffset>
              <bitWidth>1</bitWidth>
            </field>
            <field>
              <name>IM43</name>
              <bitOffset>11</bitOffset>
              <bitWidth>1</bitWidth>
            </field>
            <field>
              <name>IM47</name>
              <bitOffset>15</bitOffset>
              <bitWidth>1</bitWidth>
            </field>
            <field>
              <name>IM48</name>
              <bitOffset>16</bitOffset>
              <bitWidth>1</bitWidth>
            </field>
            <field>
              <name>IM49</name>
              <bitOffset>17</bitOffset>
              <bitWidth>1</bitWidth>
            </field>
            <field>
              <name>IM50</name>
              <bitOffset>18</bitOffset>
              <bitWidth>1</bitWidth>
            </field>
            <field>
              <name>IM51</name>
              <bitOffset>19</bitOffset>
              <bitWidth>1</bitWidth>
            </field>
            <field>
              <name>IM52</name>
              <bitOffset>20</bitOffset>
              <bitWidth>1</bitWidth>
            </field>
            <field>
              <name>IM53</name>
              <bitOffset>21</bitOffset>
              <bitWidth>1</bitWidth>
            </field>
            <field>
              <name>IM54</name>
              <bitOffset>22</bitOffset>
              <bitWidth>1</bitWidth>
            </field>
            <field>
              <name>IM55</name>
              <bitOffset>23</bitOffset>
              <bitWidth>1</bitWidth>
            </field>
            <field>
              <name>IM56</name>
              <bitOffset>24</bitOffset>
              <bitWidth>1</bitWidth>
            </field>
            <field>
              <name>IM58</name>
              <bitOffset>26</bitOffset>
              <bitWidth>1</bitWidth>
            </field>
            <field>
              <name>IM60</name>
              <bitOffset>28</bitOffset>
              <bitWidth>1</bitWidth>
            </field>
            <field>
              <name>IM61</name>
              <bitOffset>29</bitOffset>
              <bitWidth>1</bitWidth>
            </field>
            <field>
              <name>IM62</name>
              <bitOffset>30</bitOffset>
              <bitWidth>1</bitWidth>
            </field>
            <field>
              <name>IM63</name>
              <bitOffset>31</bitOffset>
              <bitWidth>1</bitWidth>
            </field>
          </fields>
        </register>
        <register>
          <name>EMR2</name>
          <addressOffset>0x94</addressOffset>
          <size>0x20</size>
          <fields>
            <field>
              <name>EM32</name>
              <bitOffset>0</bitOffset>
              <bitWidth>1</bitWidth>
            </field>
            <field>
              <name>EM33</name>
              <bitOffset>1</bitOffset>
              <bitWidth>1</bitWidth>
            </field>
            <field>
              <name>EM34</name>
              <bitOffset>2</bitOffset>
              <bitWidth>1</bitWidth>
            </field>
            <field>
              <name>EM35</name>
              <bitOffset>3</bitOffset>
              <bitWidth>1</bitWidth>
            </field>
            <field>
              <name>EM36</name>
              <bitOffset>4</bitOffset>
              <bitWidth>1</bitWidth>
            </field>
            <field>
              <name>EM37</name>
              <bitOffset>5</bitOffset>
              <bitWidth>1</bitWidth>
            </field>
            <field>
              <name>EM38</name>
              <bitOffset>6</bitOffset>
              <bitWidth>1</bitWidth>
            </field>
            <field>
              <name>EM39</name>
              <bitOffset>7</bitOffset>
              <bitWidth>1</bitWidth>
            </field>
            <field>
              <name>EM40</name>
              <bitOffset>8</bitOffset>
              <bitWidth>1</bitWidth>
            </field>
            <field>
              <name>EM41</name>
              <bitOffset>9</bitOffset>
              <bitWidth>1</bitWidth>
            </field>
            <field>
              <name>EM42</name>
              <bitOffset>10</bitOffset>
              <bitWidth>1</bitWidth>
            </field>
            <field>
              <name>EM43</name>
              <bitOffset>11</bitOffset>
              <bitWidth>1</bitWidth>
            </field>
            <field>
              <name>EM47</name>
              <bitOffset>15</bitOffset>
              <bitWidth>1</bitWidth>
            </field>
            <field>
              <name>EM48</name>
              <bitOffset>16</bitOffset>
              <bitWidth>1</bitWidth>
            </field>
            <field>
              <name>EM49</name>
              <bitOffset>17</bitOffset>
              <bitWidth>1</bitWidth>
            </field>
            <field>
              <name>EM50</name>
              <bitOffset>18</bitOffset>
              <bitWidth>1</bitWidth>
            </field>
            <field>
              <name>EM51</name>
              <bitOffset>19</bitOffset>
              <bitWidth>1</bitWidth>
            </field>
            <field>
              <name>EM52</name>
              <bitOffset>20</bitOffset>
              <bitWidth>1</bitWidth>
            </field>
            <field>
              <name>EM53</name>
              <bitOffset>21</bitOffset>
              <bitWidth>1</bitWidth>
            </field>
            <field>
              <name>EM54</name>
              <bitOffset>22</bitOffset>
              <bitWidth>1</bitWidth>
            </field>
            <field>
              <name>EM55</name>
              <bitOffset>23</bitOffset>
              <bitWidth>1</bitWidth>
            </field>
            <field>
              <name>EM56</name>
              <bitOffset>24</bitOffset>
              <bitWidth>1</bitWidth>
            </field>
            <field>
              <name>EM58</name>
              <bitOffset>26</bitOffset>
              <bitWidth>1</bitWidth>
            </field>
            <field>
              <name>EM60</name>
              <bitOffset>28</bitOffset>
              <bitWidth>1</bitWidth>
            </field>
            <field>
              <name>EM61</name>
              <bitOffset>29</bitOffset>
              <bitWidth>1</bitWidth>
            </field>
            <field>
              <name>EM62</name>
              <bitOffset>30</bitOffset>
              <bitWidth>1</bitWidth>
            </field>
            <field>
              <name>EM63</name>
              <bitOffset>31</bitOffset>
              <bitWidth>1</bitWidth>
            </field>
          </fields>
        </register>
        <register>
          <name>PR2</name>
          <addressOffset>0x98</addressOffset>
          <size>0x20</size>
          <fields>
            <field>
              <name>PR49</name>
              <bitOffset>17</bitOffset>
              <bitWidth>1</bitWidth>
            </field>
            <field>
              <name>PR51</name>
              <bitOffset>19</bitOffset>
              <bitWidth>1</bitWidth>
            </field>
          </fields>
        </register>
        <register>
          <name>IMR3</name>
          <addressOffset>0xa0</addressOffset>
          <size>0x20</size>
          <fields>
            <field>
              <name>IM64</name>
              <bitOffset>0</bitOffset>
              <bitWidth>1</bitWidth>
            </field>
            <field>
              <name>IM65</name>
              <bitOffset>1</bitOffset>
              <bitWidth>1</bitWidth>
            </field>
            <field>
              <name>IM66</name>
              <bitOffset>2</bitOffset>
              <bitWidth>1</bitWidth>
            </field>
            <field>
              <name>IM67</name>
              <bitOffset>3</bitOffset>
              <bitWidth>1</bitWidth>
            </field>
            <field>
              <name>IM68</name>
              <bitOffset>4</bitOffset>
              <bitWidth>1</bitWidth>
            </field>
            <field>
              <name>IM69</name>
              <bitOffset>5</bitOffset>
              <bitWidth>1</bitWidth>
            </field>
            <field>
              <name>IM70</name>
              <bitOffset>6</bitOffset>
              <bitWidth>1</bitWidth>
            </field>
            <field>
              <name>IM71</name>
              <bitOffset>7</bitOffset>
              <bitWidth>1</bitWidth>
            </field>
            <field>
              <name>IM72</name>
              <bitOffset>8</bitOffset>
              <bitWidth>1</bitWidth>
            </field>
            <field>
              <name>IM73</name>
              <bitOffset>9</bitOffset>
              <bitWidth>1</bitWidth>
            </field>
            <field>
              <name>IM74</name>
              <bitOffset>10</bitOffset>
              <bitWidth>1</bitWidth>
            </field>
            <field>
              <name>IM75</name>
              <bitOffset>11</bitOffset>
              <bitWidth>1</bitWidth>
            </field>
            <field>
              <name>IM76</name>
              <bitOffset>12</bitOffset>
              <bitWidth>1</bitWidth>
            </field>
            <field>
              <name>IM77</name>
              <bitOffset>13</bitOffset>
              <bitWidth>1</bitWidth>
            </field>
            <field>
              <name>IM78</name>
              <bitOffset>14</bitOffset>
              <bitWidth>1</bitWidth>
            </field>
            <field>
              <name>IM80</name>
              <bitOffset>16</bitOffset>
              <bitWidth>1</bitWidth>
            </field>
            <field>
              <name>IM85</name>
              <bitOffset>21</bitOffset>
              <bitWidth>1</bitWidth>
            </field>
            <field>
              <name>IM86</name>
              <bitOffset>22</bitOffset>
              <bitWidth>1</bitWidth>
            </field>
            <field>
              <name>IM87</name>
              <bitOffset>23</bitOffset>
              <bitWidth>1</bitWidth>
            </field>
            <field>
              <name>IM88</name>
              <bitOffset>24</bitOffset>
              <bitWidth>1</bitWidth>
            </field>
            <field>
              <name>IM89</name>
              <bitOffset>25</bitOffset>
              <bitWidth>1</bitWidth>
            </field>
            <field>
              <name>IM90</name>
              <bitOffset>26</bitOffset>
              <bitWidth>1</bitWidth>
            </field>
            <field>
              <name>IM91</name>
              <bitOffset>27</bitOffset>
              <bitWidth>1</bitWidth>
            </field>
          </fields>
        </register>
        <register>
          <name>EMR3</name>
          <addressOffset>0xa4</addressOffset>
          <size>0x20</size>
          <fields>
            <field>
              <name>EM64</name>
              <bitOffset>0</bitOffset>
              <bitWidth>1</bitWidth>
            </field>
            <field>
              <name>EM65</name>
              <bitOffset>1</bitOffset>
              <bitWidth>1</bitWidth>
            </field>
            <field>
              <name>EM66</name>
              <bitOffset>2</bitOffset>
              <bitWidth>1</bitWidth>
            </field>
            <field>
              <name>EM67</name>
              <bitOffset>3</bitOffset>
              <bitWidth>1</bitWidth>
            </field>
            <field>
              <name>EM68</name>
              <bitOffset>4</bitOffset>
              <bitWidth>1</bitWidth>
            </field>
            <field>
              <name>EM69</name>
              <bitOffset>5</bitOffset>
              <bitWidth>1</bitWidth>
            </field>
            <field>
              <name>EM70</name>
              <bitOffset>6</bitOffset>
              <bitWidth>1</bitWidth>
            </field>
            <field>
              <name>EM71</name>
              <bitOffset>7</bitOffset>
              <bitWidth>1</bitWidth>
            </field>
            <field>
              <name>EM72</name>
              <bitOffset>8</bitOffset>
              <bitWidth>1</bitWidth>
            </field>
            <field>
              <name>EM73</name>
              <bitOffset>9</bitOffset>
              <bitWidth>1</bitWidth>
            </field>
            <field>
              <name>EM74</name>
              <bitOffset>10</bitOffset>
              <bitWidth>1</bitWidth>
            </field>
            <field>
              <name>EM75</name>
              <bitOffset>11</bitOffset>
              <bitWidth>1</bitWidth>
            </field>
            <field>
              <name>EM76</name>
              <bitOffset>12</bitOffset>
              <bitWidth>1</bitWidth>
            </field>
            <field>
              <name>EM77</name>
              <bitOffset>13</bitOffset>
              <bitWidth>1</bitWidth>
            </field>
            <field>
              <name>EM78</name>
              <bitOffset>14</bitOffset>
              <bitWidth>1</bitWidth>
            </field>
            <field>
              <name>EM80</name>
              <bitOffset>16</bitOffset>
              <bitWidth>1</bitWidth>
            </field>
            <field>
              <name>EM85</name>
              <bitOffset>21</bitOffset>
              <bitWidth>1</bitWidth>
            </field>
            <field>
              <name>EM86</name>
              <bitOffset>22</bitOffset>
              <bitWidth>1</bitWidth>
            </field>
            <field>
              <name>EM87</name>
              <bitOffset>23</bitOffset>
              <bitWidth>1</bitWidth>
            </field>
            <field>
              <name>EM88</name>
              <bitOffset>24</bitOffset>
              <bitWidth>1</bitWidth>
            </field>
            <field>
              <name>EM89</name>
              <bitOffset>25</bitOffset>
              <bitWidth>1</bitWidth>
            </field>
            <field>
              <name>EM90</name>
              <bitOffset>26</bitOffset>
              <bitWidth>1</bitWidth>
            </field>
            <field>
              <name>EM91</name>
              <bitOffset>27</bitOffset>
              <bitWidth>1</bitWidth>
            </field>
          </fields>
        </register>
        <register>
          <name>PR3</name>
          <addressOffset>0xa8</addressOffset>
          <size>0x20</size>
          <fields>
            <field>
              <name>PR84</name>
              <bitOffset>20</bitOffset>
              <bitWidth>1</bitWidth>
            </field>
            <field>
              <name>PR85</name>
              <bitOffset>21</bitOffset>
              <bitWidth>1</bitWidth>
            </field>
            <field>
              <name>PR86</name>
              <bitOffset>22</bitOffset>
              <bitWidth>1</bitWidth>
            </field>
          </fields>
        </register>
      </registers>
    </peripheral>
    <peripheral>
      <name>EXTI_D1</name>
      <baseAddress>0x58000080</baseAddress>
      <registers>
        <register>
          <name>IMR1</name>
          <addressOffset>0x0</addressOffset>
          <size>0x20</size>
          <fields>
            <field>
              <name>IM0</name>
              <bitOffset>0</bitOffset>
              <bitWidth>1</bitWidth>
            </field>
            <field>
              <name>IM1</name>
              <bitOffset>1</bitOffset>
              <bitWidth>1</bitWidth>
            </field>
            <field>
              <name>IM2</name>
              <bitOffset>2</bitOffset>
              <bitWidth>1</bitWidth>
            </field>
            <field>
              <name>IM3</name>
              <bitOffset>3</bitOffset>
              <bitWidth>1</bitWidth>
            </field>
            <field>
              <name>IM4</name>
              <bitOffset>4</bitOffset>
              <bitWidth>1</bitWidth>
            </field>
            <field>
              <name>IM5</name>
              <bitOffset>5</bitOffset>
              <bitWidth>1</bitWidth>
            </field>
            <field>
              <name>IM6</name>
              <bitOffset>6</bitOffset>
              <bitWidth>1</bitWidth>
            </field>
            <field>
              <name>IM7</name>
              <bitOffset>7</bitOffset>
              <bitWidth>1</bitWidth>
            </field>
            <field>
              <name>IM8</name>
              <bitOffset>8</bitOffset>
              <bitWidth>1</bitWidth>
            </field>
            <field>
              <name>IM9</name>
              <bitOffset>9</bitOffset>
              <bitWidth>1</bitWidth>
            </field>
            <field>
              <name>IM10</name>
              <bitOffset>10</bitOffset>
              <bitWidth>1</bitWidth>
            </field>
            <field>
              <name>IM11</name>
              <bitOffset>11</bitOffset>
              <bitWidth>1</bitWidth>
            </field>
            <field>
              <name>IM12</name>
              <bitOffset>12</bitOffset>
              <bitWidth>1</bitWidth>
            </field>
            <field>
              <name>IM13</name>
              <bitOffset>13</bitOffset>
              <bitWidth>1</bitWidth>
            </field>
            <field>
              <name>IM14</name>
              <bitOffset>14</bitOffset>
              <bitWidth>1</bitWidth>
            </field>
            <field>
              <name>IM15</name>
              <bitOffset>15</bitOffset>
              <bitWidth>1</bitWidth>
            </field>
            <field>
              <name>IM16</name>
              <bitOffset>16</bitOffset>
              <bitWidth>1</bitWidth>
            </field>
            <field>
              <name>IM17</name>
              <bitOffset>17</bitOffset>
              <bitWidth>1</bitWidth>
            </field>
            <field>
              <name>IM18</name>
              <bitOffset>18</bitOffset>
              <bitWidth>1</bitWidth>
            </field>
            <field>
              <name>IM19</name>
              <bitOffset>19</bitOffset>
              <bitWidth>1</bitWidth>
            </field>
            <field>
              <name>IM20</name>
              <bitOffset>20</bitOffset>
              <bitWidth>1</bitWidth>
            </field>
            <field>
              <name>IM21</name>
              <bitOffset>21</bitOffset>
              <bitWidth>1</bitWidth>
            </field>
            <field>
              <name>IM22</name>
              <bitOffset>22</bitOffset>
              <bitWidth>1</bitWidth>
            </field>
            <field>
              <name>IM23</name>
              <bitOffset>23</bitOffset>
              <bitWidth>1</bitWidth>
            </field>
            <field>
              <name>IM24</name>
              <bitOffset>24</bitOffset>
              <bitWidth>1</bitWidth>
            </field>
            <field>
              <name>IM25</name>
              <bitOffset>25</bitOffset>
              <bitWidth>1</bitWidth>
            </field>
            <field>
              <name>IM26</name>
              <bitOffset>26</bitOffset>
              <bitWidth>1</bitWidth>
            </field>
            <field>
              <name>IM27</name>
              <bitOffset>27</bitOffset>
              <bitWidth>1</bitWidth>
            </field>
            <field>
              <name>IM28</name>
              <bitOffset>28</bitOffset>
              <bitWidth>1</bitWidth>
            </field>
            <field>
              <name>IM29</name>
              <bitOffset>29</bitOffset>
              <bitWidth>1</bitWidth>
            </field>
            <field>
              <name>IM30</name>
              <bitOffset>30</bitOffset>
              <bitWidth>1</bitWidth>
            </field>
            <field>
              <name>IM31</name>
              <bitOffset>31</bitOffset>
              <bitWidth>1</bitWidth>
            </field>
          </fields>
        </register>
        <register>
          <name>EMR1</name>
          <addressOffset>0x4</addressOffset>
          <size>0x20</size>
          <fields>
            <field>
              <name>EM0</name>
              <bitOffset>0</bitOffset>
              <bitWidth>1</bitWidth>
            </field>
            <field>
              <name>EM1</name>
              <bitOffset>1</bitOffset>
              <bitWidth>1</bitWidth>
            </field>
            <field>
              <name>EM2</name>
              <bitOffset>2</bitOffset>
              <bitWidth>1</bitWidth>
            </field>
            <field>
              <name>EM3</name>
              <bitOffset>3</bitOffset>
              <bitWidth>1</bitWidth>
            </field>
            <field>
              <name>EM4</name>
              <bitOffset>4</bitOffset>
              <bitWidth>1</bitWidth>
            </field>
            <field>
              <name>EM5</name>
              <bitOffset>5</bitOffset>
              <bitWidth>1</bitWidth>
            </field>
            <field>
              <name>EM6</name>
              <bitOffset>6</bitOffset>
              <bitWidth>1</bitWidth>
            </field>
            <field>
              <name>EM7</name>
              <bitOffset>7</bitOffset>
              <bitWidth>1</bitWidth>
            </field>
            <field>
              <name>EM8</name>
              <bitOffset>8</bitOffset>
              <bitWidth>1</bitWidth>
            </field>
            <field>
              <name>EM9</name>
              <bitOffset>9</bitOffset>
              <bitWidth>1</bitWidth>
            </field>
            <field>
              <name>EM10</name>
              <bitOffset>10</bitOffset>
              <bitWidth>1</bitWidth>
            </field>
            <field>
              <name>EM11</name>
              <bitOffset>11</bitOffset>
              <bitWidth>1</bitWidth>
            </field>
            <field>
              <name>EM12</name>
              <bitOffset>12</bitOffset>
              <bitWidth>1</bitWidth>
            </field>
            <field>
              <name>EM13</name>
              <bitOffset>13</bitOffset>
              <bitWidth>1</bitWidth>
            </field>
            <field>
              <name>EM14</name>
              <bitOffset>14</bitOffset>
              <bitWidth>1</bitWidth>
            </field>
            <field>
              <name>EM15</name>
              <bitOffset>15</bitOffset>
              <bitWidth>1</bitWidth>
            </field>
            <field>
              <name>EM16</name>
              <bitOffset>16</bitOffset>
              <bitWidth>1</bitWidth>
            </field>
            <field>
              <name>EM17</name>
              <bitOffset>17</bitOffset>
              <bitWidth>1</bitWidth>
            </field>
            <field>
              <name>EM18</name>
              <bitOffset>18</bitOffset>
              <bitWidth>1</bitWidth>
            </field>
            <field>
              <name>EM20</name>
              <bitOffset>20</bitOffset>
              <bitWidth>1</bitWidth>
            </field>
            <field>
              <name>EM21</name>
              <bitOffset>21</bitOffset>
              <bitWidth>1</bitWidth>
            </field>
            <field>
              <name>EM22</name>
              <bitOffset>22</bitOffset>
              <bitWidth>1</bitWidth>
            </field>
            <field>
              <name>EM23</name>
              <bitOffset>23</bitOffset>
              <bitWidth>1</bitWidth>
            </field>
            <field>
              <name>EM24</name>
              <bitOffset>24</bitOffset>
              <bitWidth>1</bitWidth>
            </field>
            <field>
              <name>EM25</name>
              <bitOffset>25</bitOffset>
              <bitWidth>1</bitWidth>
            </field>
            <field>
              <name>EM26</name>
              <bitOffset>26</bitOffset>
              <bitWidth>1</bitWidth>
            </field>
            <field>
              <name>EM27</name>
              <bitOffset>27</bitOffset>
              <bitWidth>1</bitWidth>
            </field>
            <field>
              <name>EM28</name>
              <bitOffset>28</bitOffset>
              <bitWidth>1</bitWidth>
            </field>
            <field>
              <name>EM29</name>
              <bitOffset>29</bitOffset>
              <bitWidth>1</bitWidth>
            </field>
            <field>
              <name>EM30</name>
              <bitOffset>30</bitOffset>
              <bitWidth>1</bitWidth>
            </field>
            <field>
              <name>EM31</name>
              <bitOffset>31</bitOffset>
              <bitWidth>1</bitWidth>
            </field>
          </fields>
        </register>
        <register>
          <name>PR1</name>
          <addressOffset>0x8</addressOffset>
          <size>0x20</size>
          <fields>
            <field>
              <name>PR0</name>
              <bitOffset>0</bitOffset>
              <bitWidth>1</bitWidth>
            </field>
            <field>
              <name>PR1</name>
              <bitOffset>1</bitOffset>
              <bitWidth>1</bitWidth>
            </field>
            <field>
              <name>PR2</name>
              <bitOffset>2</bitOffset>
              <bitWidth>1</bitWidth>
            </field>
            <field>
              <name>PR3</name>
              <bitOffset>3</bitOffset>
              <bitWidth>1</bitWidth>
            </field>
            <field>
              <name>PR4</name>
              <bitOffset>4</bitOffset>
              <bitWidth>1</bitWidth>
            </field>
            <field>
              <name>PR5</name>
              <bitOffset>5</bitOffset>
              <bitWidth>1</bitWidth>
            </field>
            <field>
              <name>PR6</name>
              <bitOffset>6</bitOffset>
              <bitWidth>1</bitWidth>
            </field>
            <field>
              <name>PR7</name>
              <bitOffset>7</bitOffset>
              <bitWidth>1</bitWidth>
            </field>
            <field>
              <name>PR8</name>
              <bitOffset>8</bitOffset>
              <bitWidth>1</bitWidth>
            </field>
            <field>
              <name>PR9</name>
              <bitOffset>9</bitOffset>
              <bitWidth>1</bitWidth>
            </field>
            <field>
              <name>PR10</name>
              <bitOffset>10</bitOffset>
              <bitWidth>1</bitWidth>
            </field>
            <field>
              <name>PR11</name>
              <bitOffset>11</bitOffset>
              <bitWidth>1</bitWidth>
            </field>
            <field>
              <name>PR12</name>
              <bitOffset>12</bitOffset>
              <bitWidth>1</bitWidth>
            </field>
            <field>
              <name>PR13</name>
              <bitOffset>13</bitOffset>
              <bitWidth>1</bitWidth>
            </field>
            <field>
              <name>PR14</name>
              <bitOffset>14</bitOffset>
              <bitWidth>1</bitWidth>
            </field>
            <field>
              <name>PR15</name>
              <bitOffset>15</bitOffset>
              <bitWidth>1</bitWidth>
            </field>
            <field>
              <name>PR16</name>
              <bitOffset>16</bitOffset>
              <bitWidth>1</bitWidth>
            </field>
            <field>
              <name>PR17</name>
              <bitOffset>17</bitOffset>
              <bitWidth>1</bitWidth>
            </field>
            <field>
              <name>PR18</name>
              <bitOffset>18</bitOffset>
              <bitWidth>1</bitWidth>
            </field>
            <field>
              <name>PR19</name>
              <bitOffset>19</bitOffset>
              <bitWidth>1</bitWidth>
            </field>
            <field>
              <name>PR20</name>
              <bitOffset>20</bitOffset>
              <bitWidth>1</bitWidth>
            </field>
            <field>
              <name>PR21</name>
              <bitOffset>21</bitOffset>
              <bitWidth>1</bitWidth>
            </field>
          </fields>
        </register>
        <register>
          <name>IMR2</name>
          <addressOffset>0x10</addressOffset>
          <size>0x20</size>
          <fields>
            <field>
              <name>IM32</name>
              <bitOffset>0</bitOffset>
              <bitWidth>1</bitWidth>
            </field>
            <field>
              <name>IM33</name>
              <bitOffset>1</bitOffset>
              <bitWidth>1</bitWidth>
            </field>
            <field>
              <name>IM34</name>
              <bitOffset>2</bitOffset>
              <bitWidth>1</bitWidth>
            </field>
            <field>
              <name>IM35</name>
              <bitOffset>3</bitOffset>
              <bitWidth>1</bitWidth>
            </field>
            <field>
              <name>IM36</name>
              <bitOffset>4</bitOffset>
              <bitWidth>1</bitWidth>
            </field>
            <field>
              <name>IM37</name>
              <bitOffset>5</bitOffset>
              <bitWidth>1</bitWidth>
            </field>
            <field>
              <name>IM38</name>
              <bitOffset>6</bitOffset>
              <bitWidth>1</bitWidth>
            </field>
            <field>
              <name>IM39</name>
              <bitOffset>7</bitOffset>
              <bitWidth>1</bitWidth>
            </field>
            <field>
              <name>IM40</name>
              <bitOffset>8</bitOffset>
              <bitWidth>1</bitWidth>
            </field>
            <field>
              <name>IM41</name>
              <bitOffset>9</bitOffset>
              <bitWidth>1</bitWidth>
            </field>
            <field>
              <name>IM42</name>
              <bitOffset>10</bitOffset>
              <bitWidth>1</bitWidth>
            </field>
            <field>
              <name>IM43</name>
              <bitOffset>11</bitOffset>
              <bitWidth>1</bitWidth>
            </field>
            <field>
              <name>IM47</name>
              <bitOffset>15</bitOffset>
              <bitWidth>1</bitWidth>
            </field>
            <field>
              <name>IM48</name>
              <bitOffset>16</bitOffset>
              <bitWidth>1</bitWidth>
            </field>
            <field>
              <name>IM49</name>
              <bitOffset>17</bitOffset>
              <bitWidth>1</bitWidth>
            </field>
            <field>
              <name>IM50</name>
              <bitOffset>18</bitOffset>
              <bitWidth>1</bitWidth>
            </field>
            <field>
              <name>IM51</name>
              <bitOffset>19</bitOffset>
              <bitWidth>1</bitWidth>
            </field>
            <field>
              <name>IM52</name>
              <bitOffset>20</bitOffset>
              <bitWidth>1</bitWidth>
            </field>
            <field>
              <name>IM53</name>
              <bitOffset>21</bitOffset>
              <bitWidth>1</bitWidth>
            </field>
            <field>
              <name>IM54</name>
              <bitOffset>22</bitOffset>
              <bitWidth>1</bitWidth>
            </field>
            <field>
              <name>IM55</name>
              <bitOffset>23</bitOffset>
              <bitWidth>1</bitWidth>
            </field>
            <field>
              <name>IM56</name>
              <bitOffset>24</bitOffset>
              <bitWidth>1</bitWidth>
            </field>
            <field>
              <name>IM58</name>
              <bitOffset>26</bitOffset>
              <bitWidth>1</bitWidth>
            </field>
            <field>
              <name>IM60</name>
              <bitOffset>28</bitOffset>
              <bitWidth>1</bitWidth>
            </field>
            <field>
              <name>IM61</name>
              <bitOffset>29</bitOffset>
              <bitWidth>1</bitWidth>
            </field>
            <field>
              <name>IM62</name>
              <bitOffset>30</bitOffset>
              <bitWidth>1</bitWidth>
            </field>
            <field>
              <name>IM63</name>
              <bitOffset>31</bitOffset>
              <bitWidth>1</bitWidth>
            </field>
          </fields>
        </register>
        <register>
          <name>EMR2</name>
          <addressOffset>0x14</addressOffset>
          <size>0x20</size>
          <fields>
            <field>
              <name>EM32</name>
              <bitOffset>0</bitOffset>
              <bitWidth>1</bitWidth>
            </field>
            <field>
              <name>EM33</name>
              <bitOffset>1</bitOffset>
              <bitWidth>1</bitWidth>
            </field>
            <field>
              <name>EM34</name>
              <bitOffset>2</bitOffset>
              <bitWidth>1</bitWidth>
            </field>
            <field>
              <name>EM35</name>
              <bitOffset>3</bitOffset>
              <bitWidth>1</bitWidth>
            </field>
            <field>
              <name>EM36</name>
              <bitOffset>4</bitOffset>
              <bitWidth>1</bitWidth>
            </field>
            <field>
              <name>EM37</name>
              <bitOffset>5</bitOffset>
              <bitWidth>1</bitWidth>
            </field>
            <field>
              <name>EM38</name>
              <bitOffset>6</bitOffset>
              <bitWidth>1</bitWidth>
            </field>
            <field>
              <name>EM39</name>
              <bitOffset>7</bitOffset>
              <bitWidth>1</bitWidth>
            </field>
            <field>
              <name>EM40</name>
              <bitOffset>8</bitOffset>
              <bitWidth>1</bitWidth>
            </field>
            <field>
              <name>EM41</name>
              <bitOffset>9</bitOffset>
              <bitWidth>1</bitWidth>
            </field>
            <field>
              <name>EM42</name>
              <bitOffset>10</bitOffset>
              <bitWidth>1</bitWidth>
            </field>
            <field>
              <name>EM43</name>
              <bitOffset>11</bitOffset>
              <bitWidth>1</bitWidth>
            </field>
            <field>
              <name>EM47</name>
              <bitOffset>15</bitOffset>
              <bitWidth>1</bitWidth>
            </field>
            <field>
              <name>EM48</name>
              <bitOffset>16</bitOffset>
              <bitWidth>1</bitWidth>
            </field>
            <field>
              <name>EM49</name>
              <bitOffset>17</bitOffset>
              <bitWidth>1</bitWidth>
            </field>
            <field>
              <name>EM50</name>
              <bitOffset>18</bitOffset>
              <bitWidth>1</bitWidth>
            </field>
            <field>
              <name>EM51</name>
              <bitOffset>19</bitOffset>
              <bitWidth>1</bitWidth>
            </field>
            <field>
              <name>EM52</name>
              <bitOffset>20</bitOffset>
              <bitWidth>1</bitWidth>
            </field>
            <field>
              <name>EM53</name>
              <bitOffset>21</bitOffset>
              <bitWidth>1</bitWidth>
            </field>
            <field>
              <name>EM54</name>
              <bitOffset>22</bitOffset>
              <bitWidth>1</bitWidth>
            </field>
            <field>
              <name>EM55</name>
              <bitOffset>23</bitOffset>
              <bitWidth>1</bitWidth>
            </field>
            <field>
              <name>EM56</name>
              <bitOffset>24</bitOffset>
              <bitWidth>1</bitWidth>
            </field>
            <field>
              <name>EM58</name>
              <bitOffset>26</bitOffset>
              <bitWidth>1</bitWidth>
            </field>
            <field>
              <name>EM60</name>
              <bitOffset>28</bitOffset>
              <bitWidth>1</bitWidth>
            </field>
            <field>
              <name>EM61</name>
              <bitOffset>29</bitOffset>
              <bitWidth>1</bitWidth>
            </field>
            <field>
              <name>EM62</name>
              <bitOffset>30</bitOffset>
              <bitWidth>1</bitWidth>
            </field>
            <field>
              <name>EM63</name>
              <bitOffset>31</bitOffset>
              <bitWidth>1</bitWidth>
            </field>
          </fields>
        </register>
        <register>
          <name>PR2</name>
          <addressOffset>0x18</addressOffset>
          <size>0x20</size>
          <fields>
            <field>
              <name>PR49</name>
              <bitOffset>17</bitOffset>
              <bitWidth>1</bitWidth>
            </field>
            <field>
              <name>PR51</name>
              <bitOffset>19</bitOffset>
              <bitWidth>1</bitWidth>
            </field>
          </fields>
        </register>
        <register>
          <name>IMR3</name>
          <addressOffset>0x20</addressOffset>
          <size>0x20</size>
          <fields>
            <field>
              <name>IM64</name>
              <bitOffset>0</bitOffset>
              <bitWidth>1</bitWidth>
            </field>
            <field>
              <name>IM65</name>
              <bitOffset>1</bitOffset>
              <bitWidth>1</bitWidth>
            </field>
            <field>
              <name>IM66</name>
              <bitOffset>2</bitOffset>
              <bitWidth>1</bitWidth>
            </field>
            <field>
              <name>IM67</name>
              <bitOffset>3</bitOffset>
              <bitWidth>1</bitWidth>
            </field>
            <field>
              <name>IM68</name>
              <bitOffset>4</bitOffset>
              <bitWidth>1</bitWidth>
            </field>
            <field>
              <name>IM69</name>
              <bitOffset>5</bitOffset>
              <bitWidth>1</bitWidth>
            </field>
            <field>
              <name>IM70</name>
              <bitOffset>6</bitOffset>
              <bitWidth>1</bitWidth>
            </field>
            <field>
              <name>IM71</name>
              <bitOffset>7</bitOffset>
              <bitWidth>1</bitWidth>
            </field>
            <field>
              <name>IM72</name>
              <bitOffset>8</bitOffset>
              <bitWidth>1</bitWidth>
            </field>
            <field>
              <name>IM73</name>
              <bitOffset>9</bitOffset>
              <bitWidth>1</bitWidth>
            </field>
            <field>
              <name>IM74</name>
              <bitOffset>10</bitOffset>
              <bitWidth>1</bitWidth>
            </field>
            <field>
              <name>IM75</name>
              <bitOffset>11</bitOffset>
              <bitWidth>1</bitWidth>
            </field>
            <field>
              <name>IM76</name>
              <bitOffset>12</bitOffset>
              <bitWidth>1</bitWidth>
            </field>
            <field>
              <name>IM77</name>
              <bitOffset>13</bitOffset>
              <bitWidth>1</bitWidth>
            </field>
            <field>
              <name>IM78</name>
              <bitOffset>14</bitOffset>
              <bitWidth>1</bitWidth>
            </field>
            <field>
              <name>IM80</name>
              <bitOffset>16</bitOffset>
              <bitWidth>1</bitWidth>
            </field>
            <field>
              <name>IM85</name>
              <bitOffset>21</bitOffset>
              <bitWidth>1</bitWidth>
            </field>
            <field>
              <name>IM86</name>
              <bitOffset>22</bitOffset>
              <bitWidth>1</bitWidth>
            </field>
            <field>
              <name>IM87</name>
              <bitOffset>23</bitOffset>
              <bitWidth>1</bitWidth>
            </field>
            <field>
              <name>IM88</name>
              <bitOffset>24</bitOffset>
              <bitWidth>1</bitWidth>
            </field>
            <field>
              <name>IM89</name>
              <bitOffset>25</bitOffset>
              <bitWidth>1</bitWidth>
            </field>
            <field>
              <name>IM90</name>
              <bitOffset>26</bitOffset>
              <bitWidth>1</bitWidth>
            </field>
            <field>
              <name>IM91</name>
              <bitOffset>27</bitOffset>
              <bitWidth>1</bitWidth>
            </field>
          </fields>
        </register>
        <register>
          <name>EMR3</name>
          <addressOffset>0x24</addressOffset>
          <size>0x20</size>
          <fields>
            <field>
              <name>EM64</name>
              <bitOffset>0</bitOffset>
              <bitWidth>1</bitWidth>
            </field>
            <field>
              <name>EM65</name>
              <bitOffset>1</bitOffset>
              <bitWidth>1</bitWidth>
            </field>
            <field>
              <name>EM66</name>
              <bitOffset>2</bitOffset>
              <bitWidth>1</bitWidth>
            </field>
            <field>
              <name>EM67</name>
              <bitOffset>3</bitOffset>
              <bitWidth>1</bitWidth>
            </field>
            <field>
              <name>EM68</name>
              <bitOffset>4</bitOffset>
              <bitWidth>1</bitWidth>
            </field>
            <field>
              <name>EM69</name>
              <bitOffset>5</bitOffset>
              <bitWidth>1</bitWidth>
            </field>
            <field>
              <name>EM70</name>
              <bitOffset>6</bitOffset>
              <bitWidth>1</bitWidth>
            </field>
            <field>
              <name>EM71</name>
              <bitOffset>7</bitOffset>
              <bitWidth>1</bitWidth>
            </field>
            <field>
              <name>EM72</name>
              <bitOffset>8</bitOffset>
              <bitWidth>1</bitWidth>
            </field>
            <field>
              <name>EM73</name>
              <bitOffset>9</bitOffset>
              <bitWidth>1</bitWidth>
            </field>
            <field>
              <name>EM74</name>
              <bitOffset>10</bitOffset>
              <bitWidth>1</bitWidth>
            </field>
            <field>
              <name>EM75</name>
              <bitOffset>11</bitOffset>
              <bitWidth>1</bitWidth>
            </field>
            <field>
              <name>EM76</name>
              <bitOffset>12</bitOffset>
              <bitWidth>1</bitWidth>
            </field>
            <field>
              <name>EM77</name>
              <bitOffset>13</bitOffset>
              <bitWidth>1</bitWidth>
            </field>
            <field>
              <name>EM78</name>
              <bitOffset>14</bitOffset>
              <bitWidth>1</bitWidth>
            </field>
            <field>
              <name>EM80</name>
              <bitOffset>16</bitOffset>
              <bitWidth>1</bitWidth>
            </field>
            <field>
              <name>EM85</name>
              <bitOffset>21</bitOffset>
              <bitWidth>1</bitWidth>
            </field>
            <field>
              <name>EM86</name>
              <bitOffset>22</bitOffset>
              <bitWidth>1</bitWidth>
            </field>
            <field>
              <name>EM87</name>
              <bitOffset>23</bitOffset>
              <bitWidth>1</bitWidth>
            </field>
            <field>
              <name>EM88</name>
              <bitOffset>24</bitOffset>
              <bitWidth>1</bitWidth>
            </field>
            <field>
              <name>EM89</name>
              <bitOffset>25</bitOffset>
              <bitWidth>1</bitWidth>
            </field>
            <field>
              <name>EM90</name>
              <bitOffset>26</bitOffset>
              <bitWidth>1</bitWidth>
            </field>
            <field>
              <name>EM91</name>
              <bitOffset>27</bitOffset>
              <bitWidth>1</bitWidth>
            </field>
          </fields>
        </register>
        <register>
          <name>PR3</name>
          <addressOffset>0x28</addressOffset>
          <size>0x20</size>
          <fields>
            <field>
              <name>PR84</name>
              <bitOffset>20</bitOffset>
              <bitWidth>1</bitWidth>
            </field>
            <field>
              <name>PR85</name>
              <bitOffset>21</bitOffset>
              <bitWidth>1</bitWidth>
            </field>
            <field>
              <name>PR86</name>
              <bitOffset>22</bitOffset>
              <bitWidth>1</bitWidth>
            </field>
          </fields>
        </register>
      </registers>
    </peripheral>
    <peripheral>
      <name>EXTI_D2</name>
      <baseAddress>0x580000c0</baseAddress>
      <registers>
        <register>
          <name>IMR1</name>
          <addressOffset>0x0</addressOffset>
          <size>0x20</size>
          <fields>
            <field>
              <name>IM0</name>
              <bitOffset>0</bitOffset>
              <bitWidth>1</bitWidth>
            </field>
            <field>
              <name>IM1</name>
              <bitOffset>1</bitOffset>
              <bitWidth>1</bitWidth>
            </field>
            <field>
              <name>IM2</name>
              <bitOffset>2</bitOffset>
              <bitWidth>1</bitWidth>
            </field>
            <field>
              <name>IM3</name>
              <bitOffset>3</bitOffset>
              <bitWidth>1</bitWidth>
            </field>
            <field>
              <name>IM4</name>
              <bitOffset>4</bitOffset>
              <bitWidth>1</bitWidth>
            </field>
            <field>
              <name>IM5</name>
              <bitOffset>5</bitOffset>
              <bitWidth>1</bitWidth>
            </field>
            <field>
              <name>IM6</name>
              <bitOffset>6</bitOffset>
              <bitWidth>1</bitWidth>
            </field>
            <field>
              <name>IM7</name>
              <bitOffset>7</bitOffset>
              <bitWidth>1</bitWidth>
            </field>
            <field>
              <name>IM8</name>
              <bitOffset>8</bitOffset>
              <bitWidth>1</bitWidth>
            </field>
            <field>
              <name>IM9</name>
              <bitOffset>9</bitOffset>
              <bitWidth>1</bitWidth>
            </field>
            <field>
              <name>IM10</name>
              <bitOffset>10</bitOffset>
              <bitWidth>1</bitWidth>
            </field>
            <field>
              <name>IM11</name>
              <bitOffset>11</bitOffset>
              <bitWidth>1</bitWidth>
            </field>
            <field>
              <name>IM12</name>
              <bitOffset>12</bitOffset>
              <bitWidth>1</bitWidth>
            </field>
            <field>
              <name>IM13</name>
              <bitOffset>13</bitOffset>
              <bitWidth>1</bitWidth>
            </field>
            <field>
              <name>IM14</name>
              <bitOffset>14</bitOffset>
              <bitWidth>1</bitWidth>
            </field>
            <field>
              <name>IM15</name>
              <bitOffset>15</bitOffset>
              <bitWidth>1</bitWidth>
            </field>
            <field>
              <name>IM16</name>
              <bitOffset>16</bitOffset>
              <bitWidth>1</bitWidth>
            </field>
            <field>
              <name>IM17</name>
              <bitOffset>17</bitOffset>
              <bitWidth>1</bitWidth>
            </field>
            <field>
              <name>IM18</name>
              <bitOffset>18</bitOffset>
              <bitWidth>1</bitWidth>
            </field>
            <field>
              <name>IM19</name>
              <bitOffset>19</bitOffset>
              <bitWidth>1</bitWidth>
            </field>
            <field>
              <name>IM20</name>
              <bitOffset>20</bitOffset>
              <bitWidth>1</bitWidth>
            </field>
            <field>
              <name>IM21</name>
              <bitOffset>21</bitOffset>
              <bitWidth>1</bitWidth>
            </field>
            <field>
              <name>IM22</name>
              <bitOffset>22</bitOffset>
              <bitWidth>1</bitWidth>
            </field>
            <field>
              <name>IM23</name>
              <bitOffset>23</bitOffset>
              <bitWidth>1</bitWidth>
            </field>
            <field>
              <name>IM24</name>
              <bitOffset>24</bitOffset>
              <bitWidth>1</bitWidth>
            </field>
            <field>
              <name>IM25</name>
              <bitOffset>25</bitOffset>
              <bitWidth>1</bitWidth>
            </field>
            <field>
              <name>IM26</name>
              <bitOffset>26</bitOffset>
              <bitWidth>1</bitWidth>
            </field>
            <field>
              <name>IM27</name>
              <bitOffset>27</bitOffset>
              <bitWidth>1</bitWidth>
            </field>
            <field>
              <name>IM28</name>
              <bitOffset>28</bitOffset>
              <bitWidth>1</bitWidth>
            </field>
            <field>
              <name>IM29</name>
              <bitOffset>29</bitOffset>
              <bitWidth>1</bitWidth>
            </field>
            <field>
              <name>IM30</name>
              <bitOffset>30</bitOffset>
              <bitWidth>1</bitWidth>
            </field>
            <field>
              <name>IM31</name>
              <bitOffset>31</bitOffset>
              <bitWidth>1</bitWidth>
            </field>
          </fields>
        </register>
        <register>
          <name>EMR1</name>
          <addressOffset>0x4</addressOffset>
          <size>0x20</size>
          <fields>
            <field>
              <name>EM0</name>
              <bitOffset>0</bitOffset>
              <bitWidth>1</bitWidth>
            </field>
            <field>
              <name>EM1</name>
              <bitOffset>1</bitOffset>
              <bitWidth>1</bitWidth>
            </field>
            <field>
              <name>EM2</name>
              <bitOffset>2</bitOffset>
              <bitWidth>1</bitWidth>
            </field>
            <field>
              <name>EM3</name>
              <bitOffset>3</bitOffset>
              <bitWidth>1</bitWidth>
            </field>
            <field>
              <name>EM4</name>
              <bitOffset>4</bitOffset>
              <bitWidth>1</bitWidth>
            </field>
            <field>
              <name>EM5</name>
              <bitOffset>5</bitOffset>
              <bitWidth>1</bitWidth>
            </field>
            <field>
              <name>EM6</name>
              <bitOffset>6</bitOffset>
              <bitWidth>1</bitWidth>
            </field>
            <field>
              <name>EM7</name>
              <bitOffset>7</bitOffset>
              <bitWidth>1</bitWidth>
            </field>
            <field>
              <name>EM8</name>
              <bitOffset>8</bitOffset>
              <bitWidth>1</bitWidth>
            </field>
            <field>
              <name>EM9</name>
              <bitOffset>9</bitOffset>
              <bitWidth>1</bitWidth>
            </field>
            <field>
              <name>EM10</name>
              <bitOffset>10</bitOffset>
              <bitWidth>1</bitWidth>
            </field>
            <field>
              <name>EM11</name>
              <bitOffset>11</bitOffset>
              <bitWidth>1</bitWidth>
            </field>
            <field>
              <name>EM12</name>
              <bitOffset>12</bitOffset>
              <bitWidth>1</bitWidth>
            </field>
            <field>
              <name>EM13</name>
              <bitOffset>13</bitOffset>
              <bitWidth>1</bitWidth>
            </field>
            <field>
              <name>EM14</name>
              <bitOffset>14</bitOffset>
              <bitWidth>1</bitWidth>
            </field>
            <field>
              <name>EM15</name>
              <bitOffset>15</bitOffset>
              <bitWidth>1</bitWidth>
            </field>
            <field>
              <name>EM16</name>
              <bitOffset>16</bitOffset>
              <bitWidth>1</bitWidth>
            </field>
            <field>
              <name>EM17</name>
              <bitOffset>17</bitOffset>
              <bitWidth>1</bitWidth>
            </field>
            <field>
              <name>EM18</name>
              <bitOffset>18</bitOffset>
              <bitWidth>1</bitWidth>
            </field>
            <field>
              <name>EM20</name>
              <bitOffset>20</bitOffset>
              <bitWidth>1</bitWidth>
            </field>
            <field>
              <name>EM21</name>
              <bitOffset>21</bitOffset>
              <bitWidth>1</bitWidth>
            </field>
            <field>
              <name>EM22</name>
              <bitOffset>22</bitOffset>
              <bitWidth>1</bitWidth>
            </field>
            <field>
              <name>EM23</name>
              <bitOffset>23</bitOffset>
              <bitWidth>1</bitWidth>
            </field>
            <field>
              <name>EM24</name>
              <bitOffset>24</bitOffset>
              <bitWidth>1</bitWidth>
            </field>
            <field>
              <name>EM25</name>
              <bitOffset>25</bitOffset>
              <bitWidth>1</bitWidth>
            </field>
            <field>
              <name>EM26</name>
              <bitOffset>26</bitOffset>
              <bitWidth>1</bitWidth>
            </field>
            <field>
              <name>EM27</name>
              <bitOffset>27</bitOffset>
              <bitWidth>1</bitWidth>
            </field>
            <field>
              <name>EM28</name>
              <bitOffset>28</bitOffset>
              <bitWidth>1</bitWidth>
            </field>
            <field>
              <name>EM29</name>
              <bitOffset>29</bitOffset>
              <bitWidth>1</bitWidth>
            </field>
            <field>
              <name>EM30</name>
              <bitOffset>30</bitOffset>
              <bitWidth>1</bitWidth>
            </field>
            <field>
              <name>EM31</name>
              <bitOffset>31</bitOffset>
              <bitWidth>1</bitWidth>
            </field>
          </fields>
        </register>
        <register>
          <name>PR1</name>
          <addressOffset>0x8</addressOffset>
          <size>0x20</size>
          <fields>
            <field>
              <name>PR0</name>
              <bitOffset>0</bitOffset>
              <bitWidth>1</bitWidth>
            </field>
            <field>
              <name>PR1</name>
              <bitOffset>1</bitOffset>
              <bitWidth>1</bitWidth>
            </field>
            <field>
              <name>PR2</name>
              <bitOffset>2</bitOffset>
              <bitWidth>1</bitWidth>
            </field>
            <field>
              <name>PR3</name>
              <bitOffset>3</bitOffset>
              <bitWidth>1</bitWidth>
            </field>
            <field>
              <name>PR4</name>
              <bitOffset>4</bitOffset>
              <bitWidth>1</bitWidth>
            </field>
            <field>
              <name>PR5</name>
              <bitOffset>5</bitOffset>
              <bitWidth>1</bitWidth>
            </field>
            <field>
              <name>PR6</name>
              <bitOffset>6</bitOffset>
              <bitWidth>1</bitWidth>
            </field>
            <field>
              <name>PR7</name>
              <bitOffset>7</bitOffset>
              <bitWidth>1</bitWidth>
            </field>
            <field>
              <name>PR8</name>
              <bitOffset>8</bitOffset>
              <bitWidth>1</bitWidth>
            </field>
            <field>
              <name>PR9</name>
              <bitOffset>9</bitOffset>
              <bitWidth>1</bitWidth>
            </field>
            <field>
              <name>PR10</name>
              <bitOffset>10</bitOffset>
              <bitWidth>1</bitWidth>
            </field>
            <field>
              <name>PR11</name>
              <bitOffset>11</bitOffset>
              <bitWidth>1</bitWidth>
            </field>
            <field>
              <name>PR12</name>
              <bitOffset>12</bitOffset>
              <bitWidth>1</bitWidth>
            </field>
            <field>
              <name>PR13</name>
              <bitOffset>13</bitOffset>
              <bitWidth>1</bitWidth>
            </field>
            <field>
              <name>PR14</name>
              <bitOffset>14</bitOffset>
              <bitWidth>1</bitWidth>
            </field>
            <field>
              <name>PR15</name>
              <bitOffset>15</bitOffset>
              <bitWidth>1</bitWidth>
            </field>
            <field>
              <name>PR16</name>
              <bitOffset>16</bitOffset>
              <bitWidth>1</bitWidth>
            </field>
            <field>
              <name>PR17</name>
              <bitOffset>17</bitOffset>
              <bitWidth>1</bitWidth>
            </field>
            <field>
              <name>PR18</name>
              <bitOffset>18</bitOffset>
              <bitWidth>1</bitWidth>
            </field>
            <field>
              <name>PR19</name>
              <bitOffset>19</bitOffset>
              <bitWidth>1</bitWidth>
            </field>
            <field>
              <name>PR20</name>
              <bitOffset>20</bitOffset>
              <bitWidth>1</bitWidth>
            </field>
            <field>
              <name>PR21</name>
              <bitOffset>21</bitOffset>
              <bitWidth>1</bitWidth>
            </field>
          </fields>
        </register>
        <register>
          <name>IMR2</name>
          <addressOffset>0x10</addressOffset>
          <size>0x20</size>
          <fields>
            <field>
              <name>IM32</name>
              <bitOffset>0</bitOffset>
              <bitWidth>1</bitWidth>
            </field>
            <field>
              <name>IM33</name>
              <bitOffset>1</bitOffset>
              <bitWidth>1</bitWidth>
            </field>
            <field>
              <name>IM34</name>
              <bitOffset>2</bitOffset>
              <bitWidth>1</bitWidth>
            </field>
            <field>
              <name>IM35</name>
              <bitOffset>3</bitOffset>
              <bitWidth>1</bitWidth>
            </field>
            <field>
              <name>IM36</name>
              <bitOffset>4</bitOffset>
              <bitWidth>1</bitWidth>
            </field>
            <field>
              <name>IM37</name>
              <bitOffset>5</bitOffset>
              <bitWidth>1</bitWidth>
            </field>
            <field>
              <name>IM38</name>
              <bitOffset>6</bitOffset>
              <bitWidth>1</bitWidth>
            </field>
            <field>
              <name>IM39</name>
              <bitOffset>7</bitOffset>
              <bitWidth>1</bitWidth>
            </field>
            <field>
              <name>IM40</name>
              <bitOffset>8</bitOffset>
              <bitWidth>1</bitWidth>
            </field>
            <field>
              <name>IM41</name>
              <bitOffset>9</bitOffset>
              <bitWidth>1</bitWidth>
            </field>
            <field>
              <name>IM42</name>
              <bitOffset>10</bitOffset>
              <bitWidth>1</bitWidth>
            </field>
            <field>
              <name>IM43</name>
              <bitOffset>11</bitOffset>
              <bitWidth>1</bitWidth>
            </field>
            <field>
              <name>IM47</name>
              <bitOffset>15</bitOffset>
              <bitWidth>1</bitWidth>
            </field>
            <field>
              <name>IM48</name>
              <bitOffset>16</bitOffset>
              <bitWidth>1</bitWidth>
            </field>
            <field>
              <name>IM49</name>
              <bitOffset>17</bitOffset>
              <bitWidth>1</bitWidth>
            </field>
            <field>
              <name>IM50</name>
              <bitOffset>18</bitOffset>
              <bitWidth>1</bitWidth>
            </field>
            <field>
              <name>IM51</name>
              <bitOffset>19</bitOffset>
              <bitWidth>1</bitWidth>
            </field>
            <field>
              <name>IM52</name>
              <bitOffset>20</bitOffset>
              <bitWidth>1</bitWidth>
            </field>
            <field>
              <name>IM53</name>
              <bitOffset>21</bitOffset>
              <bitWidth>1</bitWidth>
            </field>
            <field>
              <name>IM54</name>
              <bitOffset>22</bitOffset>
              <bitWidth>1</bitWidth>
            </field>
            <field>
              <name>IM55</name>
              <bitOffset>23</bitOffset>
              <bitWidth>1</bitWidth>
            </field>
            <field>
              <name>IM56</name>
              <bitOffset>24</bitOffset>
              <bitWidth>1</bitWidth>
            </field>
            <field>
              <name>IM58</name>
              <bitOffset>26</bitOffset>
              <bitWidth>1</bitWidth>
            </field>
            <field>
              <name>IM60</name>
              <bitOffset>28</bitOffset>
              <bitWidth>1</bitWidth>
            </field>
            <field>
              <name>IM61</name>
              <bitOffset>29</bitOffset>
              <bitWidth>1</bitWidth>
            </field>
            <field>
              <name>IM62</name>
              <bitOffset>30</bitOffset>
              <bitWidth>1</bitWidth>
            </field>
            <field>
              <name>IM63</name>
              <bitOffset>31</bitOffset>
              <bitWidth>1</bitWidth>
            </field>
          </fields>
        </register>
        <register>
          <name>EMR2</name>
          <addressOffset>0x14</addressOffset>
          <size>0x20</size>
          <fields>
            <field>
              <name>EM32</name>
              <bitOffset>0</bitOffset>
              <bitWidth>1</bitWidth>
            </field>
            <field>
              <name>EM33</name>
              <bitOffset>1</bitOffset>
              <bitWidth>1</bitWidth>
            </field>
            <field>
              <name>EM34</name>
              <bitOffset>2</bitOffset>
              <bitWidth>1</bitWidth>
            </field>
            <field>
              <name>EM35</name>
              <bitOffset>3</bitOffset>
              <bitWidth>1</bitWidth>
            </field>
            <field>
              <name>EM36</name>
              <bitOffset>4</bitOffset>
              <bitWidth>1</bitWidth>
            </field>
            <field>
              <name>EM37</name>
              <bitOffset>5</bitOffset>
              <bitWidth>1</bitWidth>
            </field>
            <field>
              <name>EM38</name>
              <bitOffset>6</bitOffset>
              <bitWidth>1</bitWidth>
            </field>
            <field>
              <name>EM39</name>
              <bitOffset>7</bitOffset>
              <bitWidth>1</bitWidth>
            </field>
            <field>
              <name>EM40</name>
              <bitOffset>8</bitOffset>
              <bitWidth>1</bitWidth>
            </field>
            <field>
              <name>EM41</name>
              <bitOffset>9</bitOffset>
              <bitWidth>1</bitWidth>
            </field>
            <field>
              <name>EM42</name>
              <bitOffset>10</bitOffset>
              <bitWidth>1</bitWidth>
            </field>
            <field>
              <name>EM43</name>
              <bitOffset>11</bitOffset>
              <bitWidth>1</bitWidth>
            </field>
            <field>
              <name>EM47</name>
              <bitOffset>15</bitOffset>
              <bitWidth>1</bitWidth>
            </field>
            <field>
              <name>EM48</name>
              <bitOffset>16</bitOffset>
              <bitWidth>1</bitWidth>
            </field>
            <field>
              <name>EM49</name>
              <bitOffset>17</bitOffset>
              <bitWidth>1</bitWidth>
            </field>
            <field>
              <name>EM50</name>
              <bitOffset>18</bitOffset>
              <bitWidth>1</bitWidth>
            </field>
            <field>
              <name>EM51</name>
              <bitOffset>19</bitOffset>
              <bitWidth>1</bitWidth>
            </field>
            <field>
              <name>EM52</name>
              <bitOffset>20</bitOffset>
              <bitWidth>1</bitWidth>
            </field>
            <field>
              <name>EM53</name>
              <bitOffset>21</bitOffset>
              <bitWidth>1</bitWidth>
            </field>
            <field>
              <name>EM54</name>
              <bitOffset>22</bitOffset>
              <bitWidth>1</bitWidth>
            </field>
            <field>
              <name>EM55</name>
              <bitOffset>23</bitOffset>
              <bitWidth>1</bitWidth>
            </field>
            <field>
              <name>EM56</name>
              <bitOffset>24</bitOffset>
              <bitWidth>1</bitWidth>
            </field>
            <field>
              <name>EM58</name>
              <bitOffset>26</bitOffset>
              <bitWidth>1</bitWidth>
            </field>
            <field>
              <name>EM60</name>
              <bitOffset>28</bitOffset>
              <bitWidth>1</bitWidth>
            </field>
            <field>
              <name>EM61</name>
              <bitOffset>29</bitOffset>
              <bitWidth>1</bitWidth>
            </field>
            <field>
              <name>EM62</name>
              <bitOffset>30</bitOffset>
              <bitWidth>1</bitWidth>
            </field>
            <field>
              <name>EM63</name>
              <bitOffset>31</bitOffset>
              <bitWidth>1</bitWidth>
            </field>
          </fields>
        </register>
        <register>
          <name>PR2</name>
          <addressOffset>0x18</addressOffset>
          <size>0x20</size>
          <fields>
            <field>
              <name>PR49</name>
              <bitOffset>17</bitOffset>
              <bitWidth>1</bitWidth>
            </field>
            <field>
              <name>PR51</name>
              <bitOffset>19</bitOffset>
              <bitWidth>1</bitWidth>
            </field>
          </fields>
        </register>
        <register>
          <name>IMR3</name>
          <addressOffset>0x20</addressOffset>
          <size>0x20</size>
          <fields>
            <field>
              <name>IM64</name>
              <bitOffset>0</bitOffset>
              <bitWidth>1</bitWidth>
            </field>
            <field>
              <name>IM65</name>
              <bitOffset>1</bitOffset>
              <bitWidth>1</bitWidth>
            </field>
            <field>
              <name>IM66</name>
              <bitOffset>2</bitOffset>
              <bitWidth>1</bitWidth>
            </field>
            <field>
              <name>IM67</name>
              <bitOffset>3</bitOffset>
              <bitWidth>1</bitWidth>
            </field>
            <field>
              <name>IM68</name>
              <bitOffset>4</bitOffset>
              <bitWidth>1</bitWidth>
            </field>
            <field>
              <name>IM69</name>
              <bitOffset>5</bitOffset>
              <bitWidth>1</bitWidth>
            </field>
            <field>
              <name>IM70</name>
              <bitOffset>6</bitOffset>
              <bitWidth>1</bitWidth>
            </field>
            <field>
              <name>IM71</name>
              <bitOffset>7</bitOffset>
              <bitWidth>1</bitWidth>
            </field>
            <field>
              <name>IM72</name>
              <bitOffset>8</bitOffset>
              <bitWidth>1</bitWidth>
            </field>
            <field>
              <name>IM73</name>
              <bitOffset>9</bitOffset>
              <bitWidth>1</bitWidth>
            </field>
            <field>
              <name>IM74</name>
              <bitOffset>10</bitOffset>
              <bitWidth>1</bitWidth>
            </field>
            <field>
              <name>IM75</name>
              <bitOffset>11</bitOffset>
              <bitWidth>1</bitWidth>
            </field>
            <field>
              <name>IM76</name>
              <bitOffset>12</bitOffset>
              <bitWidth>1</bitWidth>
            </field>
            <field>
              <name>IM77</name>
              <bitOffset>13</bitOffset>
              <bitWidth>1</bitWidth>
            </field>
            <field>
              <name>IM78</name>
              <bitOffset>14</bitOffset>
              <bitWidth>1</bitWidth>
            </field>
            <field>
              <name>IM80</name>
              <bitOffset>16</bitOffset>
              <bitWidth>1</bitWidth>
            </field>
            <field>
              <name>IM85</name>
              <bitOffset>21</bitOffset>
              <bitWidth>1</bitWidth>
            </field>
            <field>
              <name>IM86</name>
              <bitOffset>22</bitOffset>
              <bitWidth>1</bitWidth>
            </field>
            <field>
              <name>IM87</name>
              <bitOffset>23</bitOffset>
              <bitWidth>1</bitWidth>
            </field>
            <field>
              <name>IM88</name>
              <bitOffset>24</bitOffset>
              <bitWidth>1</bitWidth>
            </field>
            <field>
              <name>IM89</name>
              <bitOffset>25</bitOffset>
              <bitWidth>1</bitWidth>
            </field>
            <field>
              <name>IM90</name>
              <bitOffset>26</bitOffset>
              <bitWidth>1</bitWidth>
            </field>
            <field>
              <name>IM91</name>
              <bitOffset>27</bitOffset>
              <bitWidth>1</bitWidth>
            </field>
          </fields>
        </register>
        <register>
          <name>EMR3</name>
          <addressOffset>0x24</addressOffset>
          <size>0x20</size>
          <fields>
            <field>
              <name>EM64</name>
              <bitOffset>0</bitOffset>
              <bitWidth>1</bitWidth>
            </field>
            <field>
              <name>EM65</name>
              <bitOffset>1</bitOffset>
              <bitWidth>1</bitWidth>
            </field>
            <field>
              <name>EM66</name>
              <bitOffset>2</bitOffset>
              <bitWidth>1</bitWidth>
            </field>
            <field>
              <name>EM67</name>
              <bitOffset>3</bitOffset>
              <bitWidth>1</bitWidth>
            </field>
            <field>
              <name>EM68</name>
              <bitOffset>4</bitOffset>
              <bitWidth>1</bitWidth>
            </field>
            <field>
              <name>EM69</name>
              <bitOffset>5</bitOffset>
              <bitWidth>1</bitWidth>
            </field>
            <field>
              <name>EM70</name>
              <bitOffset>6</bitOffset>
              <bitWidth>1</bitWidth>
            </field>
            <field>
              <name>EM71</name>
              <bitOffset>7</bitOffset>
              <bitWidth>1</bitWidth>
            </field>
            <field>
              <name>EM72</name>
              <bitOffset>8</bitOffset>
              <bitWidth>1</bitWidth>
            </field>
            <field>
              <name>EM73</name>
              <bitOffset>9</bitOffset>
              <bitWidth>1</bitWidth>
            </field>
            <field>
              <name>EM74</name>
              <bitOffset>10</bitOffset>
              <bitWidth>1</bitWidth>
            </field>
            <field>
              <name>EM75</name>
              <bitOffset>11</bitOffset>
              <bitWidth>1</bitWidth>
            </field>
            <field>
              <name>EM76</name>
              <bitOffset>12</bitOffset>
              <bitWidth>1</bitWidth>
            </field>
            <field>
              <name>EM77</name>
              <bitOffset>13</bitOffset>
              <bitWidth>1</bitWidth>
            </field>
            <field>
              <name>EM78</name>
              <bitOffset>14</bitOffset>
              <bitWidth>1</bitWidth>
            </field>
            <field>
              <name>EM80</name>
              <bitOffset>16</bitOffset>
              <bitWidth>1</bitWidth>
            </field>
            <field>
              <name>EM85</name>
              <bitOffset>21</bitOffset>
              <bitWidth>1</bitWidth>
            </field>
            <field>
              <name>EM86</name>
              <bitOffset>22</bitOffset>
              <bitWidth>1</bitWidth>
            </field>
            <field>
              <name>EM87</name>
              <bitOffset>23</bitOffset>
              <bitWidth>1</bitWidth>
            </field>
            <field>
              <name>EM88</name>
              <bitOffset>24</bitOffset>
              <bitWidth>1</bitWidth>
            </field>
            <field>
              <name>EM89</name>
              <bitOffset>25</bitOffset>
              <bitWidth>1</bitWidth>
            </field>
            <field>
              <name>EM90</name>
              <bitOffset>26</bitOffset>
              <bitWidth>1</bitWidth>
            </field>
            <field>
              <name>EM91</name>
              <bitOffset>27</bitOffset>
              <bitWidth>1</bitWidth>
            </field>
          </fields>
        </register>
        <register>
          <name>PR3</name>
          <addressOffset>0x28</addressOffset>
          <size>0x20</size>
          <fields>
            <field>
              <name>PR84</name>
              <bitOffset>20</bitOffset>
              <bitWidth>1</bitWidth>
            </field>
            <field>
              <name>PR85</name>
              <bitOffset>21</bitOffset>
              <bitWidth>1</bitWidth>
            </field>
            <field>
              <name>PR86</name>
              <bitOffset>22</bitOffset>
              <bitWidth>1</bitWidth>
            </field>
          </fields>
        </register>
      </registers>
    </peripheral>
    <peripheral>
      <name>SYSCFG</name>
      <baseAddress>0x58000400</baseAddress>
      <registers>
        <register>
          <name>PMCR</name>
          <addressOffset>0x4</addressOffset>
          <size>0x20</size>
          <fields>
            <field>
              <name>I2C1_FMP</name>
              <bitOffset>0</bitOffset>
              <bitWidth>1</bitWidth>
            </field>
            <field>
              <name>I2C2_FMP</name>
              <bitOffset>1</bitOffset>
              <bitWidth>1</bitWidth>
            </field>
            <field>
              <name>I2C3_FMP</name>
              <bitOffset>2</bitOffset>
              <bitWidth>1</bitWidth>
            </field>
            <field>
              <name>I2C4_FMP</name>
              <bitOffset>3</bitOffset>
              <bitWidth>1</bitWidth>
            </field>
            <field>
              <name>I2C_PB6_FMP</name>
              <bitOffset>4</bitOffset>
              <bitWidth>1</bitWidth>
            </field>
            <field>
              <name>I2C_PB7_FMP</name>
              <bitOffset>5</bitOffset>
              <bitWidth>1</bitWidth>
            </field>
            <field>
              <name>I2C_PB8_FMP</name>
              <bitOffset>6</bitOffset>
              <bitWidth>1</bitWidth>
            </field>
            <field>
              <name>I2C_PB9_FMP</name>
              <bitOffset>7</bitOffset>
              <bitWidth>1</bitWidth>
            </field>
            <field>
              <name>BOOSTEN</name>
              <bitOffset>8</bitOffset>
              <bitWidth>1</bitWidth>
            </field>
            <field>
              <name>BOOSTVDDSEL</name>
              <bitOffset>9</bitOffset>
              <bitWidth>1</bitWidth>
            </field>
            <field>
              <name>I2C5_FMP</name>
              <bitOffset>10</bitOffset>
              <bitWidth>1</bitWidth>
            </field>
            <field>
              <name>EPIS_SEL</name>
              <bitOffset>21</bitOffset>
              <bitWidth>3</bitWidth>
            </field>
            <field>
              <name>PA0SO</name>
              <bitOffset>24</bitOffset>
              <bitWidth>1</bitWidth>
            </field>
            <field>
              <name>PA1SO</name>
              <bitOffset>25</bitOffset>
              <bitWidth>1</bitWidth>
            </field>
            <field>
              <name>PC2SO</name>
              <bitOffset>26</bitOffset>
              <bitWidth>1</bitWidth>
            </field>
            <field>
              <name>PC3SO</name>
              <bitOffset>27</bitOffset>
              <bitWidth>1</bitWidth>
            </field>
          </fields>
        </register>
        <register>
          <name>EXTICR.0</name>
          <addressOffset>0x8</addressOffset>
          <size>0x20</size>
          <fields>
            <field>
              <name>EXTI0</name>
              <bitOffset>0</bitOffset>
              <bitWidth>4</bitWidth>
            </field>
            <field>
              <name>EXTI1</name>
              <bitOffset>4</bitOffset>
              <bitWidth>4</bitWidth>
            </field>
            <field>
              <name>EXTI2</name>
              <bitOffset>8</bitOffset>
              <bitWidth>4</bitWidth>
            </field>
            <field>
              <name>EXTI3</name>
              <bitOffset>12</bitOffset>
              <bitWidth>4</bitWidth>
            </field>
          </fields>
        </register>
        <register>
          <name>EXTICR.1</name>
          <addressOffset>0xc</addressOffset>
          <size>0x20</size>
          <fields>
            <field>
              <name>EXTI4</name>
              <bitOffset>0</bitOffset>
              <bitWidth>4</bitWidth>
            </field>
            <field>
              <name>EXTI5</name>
              <bitOffset>4</bitOffset>
              <bitWidth>4</bitWidth>
            </field>
            <field>
              <name>EXTI6</name>
              <bitOffset>8</bitOffset>
              <bitWidth>4</bitWidth>
            </field>
            <field>
              <name>EXTI7</name>
              <bitOffset>12</bitOffset>
              <bitWidth>4</bitWidth>
            </field>
          </fields>
        </register>
        <register>
          <name>EXTICR.2</name>
          <addressOffset>0x10</addressOffset>
          <size>0x20</size>
          <fields>
            <field>
              <name>EXTI8</name>
              <bitOffset>0</bitOffset>
              <bitWidth>4</bitWidth>
            </field>
            <field>
              <name>EXTI9</name>
              <bitOffset>4</bitOffset>
              <bitWidth>4</bitWidth>
            </field>
            <field>
              <name>EXTI10</name>
              <bitOffset>8</bitOffset>
              <bitWidth>4</bitWidth>
            </field>
            <field>
              <name>EXTI11</name>
              <bitOffset>12</bitOffset>
              <bitWidth>4</bitWidth>
            </field>
          </fields>
        </register>
        <register>
          <name>EXTICR.3</name>
          <addressOffset>0x14</addressOffset>
          <size>0x20</size>
          <fields>
            <field>
              <name>EXTI12</name>
              <bitOffset>0</bitOffset>
              <bitWidth>4</bitWidth>
            </field>
            <field>
              <name>EXTI13</name>
              <bitOffset>4</bitOffset>
              <bitWidth>4</bitWidth>
            </field>
            <field>
              <name>EXTI14</name>
              <bitOffset>8</bitOffset>
              <bitWidth>4</bitWidth>
            </field>
            <field>
              <name>EXTI15</name>
              <bitOffset>12</bitOffset>
              <bitWidth>4</bitWidth>
            </field>
          </fields>
        </register>
        <register>
          <name>CFGR</name>
          <addressOffset>0x18</addressOffset>
          <size>0x20</size>
          <fields>
            <field>
              <name>PVDL</name>
              <bitOffset>2</bitOffset>
              <bitWidth>1</bitWidth>
            </field>
            <field>
              <name>FLASHL</name>
              <bitOffset>3</bitOffset>
              <bitWidth>1</bitWidth>
            </field>
            <field>
              <name>CM7L</name>
              <bitOffset>6</bitOffset>
              <bitWidth>1</bitWidth>
            </field>
            <field>
              <name>BKRAML</name>
              <bitOffset>7</bitOffset>
              <bitWidth>1</bitWidth>
            </field>
            <field>
              <name>SRAM4L</name>
              <bitOffset>9</bitOffset>
              <bitWidth>1</bitWidth>
            </field>
            <field>
              <name>SRAM2L</name>
              <bitOffset>11</bitOffset>
              <bitWidth>1</bitWidth>
            </field>
            <field>
              <name>SRAM1L</name>
              <bitOffset>12</bitOffset>
              <bitWidth>1</bitWidth>
            </field>
            <field>
              <name>DTCML</name>
              <bitOffset>13</bitOffset>
              <bitWidth>1</bitWidth>
            </field>
            <field>
              <name>ITCML</name>
              <bitOffset>14</bitOffset>
              <bitWidth>1</bitWidth>
            </field>
            <field>
              <name>AXISRAML</name>
              <bitOffset>15</bitOffset>
              <bitWidth>1</bitWidth>
            </field>
          </fields>
        </register>
        <register>
          <name>CCCSR</name>
          <addressOffset>0x20</addressOffset>
          <size>0x20</size>
          <fields>
            <field>
              <name>EN</name>
              <bitOffset>0</bitOffset>
              <bitWidth>1</bitWidth>
            </field>
            <field>
              <name>CS</name>
              <bitOffset>1</bitOffset>
              <bitWidth>1</bitWidth>
            </field>
            <field>
              <name>READY</name>
              <bitOffset>8</bitOffset>
              <bitWidth>1</bitWidth>
            </field>
            <field>
              <name>HSLV</name>
              <bitOffset>16</bitOffset>
              <bitWidth>1</bitWidth>
            </field>
          </fields>
        </register>
        <register>
          <name>CCVR</name>
          <addressOffset>0x24</addressOffset>
          <size>0x20</size>
          <fields>
            <field>
              <name>NCV</name>
              <bitOffset>0</bitOffset>
              <bitWidth>4</bitWidth>
            </field>
            <field>
              <name>PCV</name>
              <bitOffset>4</bitOffset>
              <bitWidth>4</bitWidth>
            </field>
          </fields>
        </register>
        <register>
          <name>CCCR</name>
          <addressOffset>0x28</addressOffset>
          <size>0x20</size>
          <fields>
            <field>
              <name>NCC</name>
              <bitOffset>0</bitOffset>
              <bitWidth>4</bitWidth>
            </field>
            <field>
              <name>PCC</name>
              <bitOffset>4</bitOffset>
              <bitWidth>4</bitWidth>
            </field>
          </fields>
        </register>
        <register>
          <name>ADC2ALT</name>
          <addressOffset>0x30</addressOffset>
          <size>0x20</size>
          <fields>
            <field>
              <name>ADC2_ROUT0</name>
              <bitOffset>0</bitOffset>
              <bitWidth>1</bitWidth>
            </field>
            <field>
              <name>ADC2_ROUT1</name>
              <bitOffset>1</bitOffset>
              <bitWidth>1</bitWidth>
            </field>
          </fields>
        </register>
        <register>
          <name>PKGR</name>
          <addressOffset>0x124</addressOffset>
          <size>0x20</size>
          <fields>
            <field>
              <name>PKG</name>
              <bitOffset>0</bitOffset>
              <bitWidth>4</bitWidth>
            </field>
          </fields>
        </register>
        <register>
          <name>UR0</name>
          <addressOffset>0x300</addressOffset>
          <size>0x20</size>
          <fields>
            <field>
              <name>RDP</name>
              <bitOffset>16</bitOffset>
              <bitWidth>8</bitWidth>
            </field>
          </fields>
        </register>
        <register>
          <name>UR1</name>
          <addressOffset>0x304</addressOffset>
          <size>0x20</size>
        </register>
        <register>
          <name>UR2</name>
          <addressOffset>0x308</addressOffset>
          <size>0x20</size>
          <fields>
            <field>
              <name>BORH</name>
              <bitOffset>0</bitOffset>
              <bitWidth>2</bitWidth>
            </field>
            <field>
              <name>BOOT_ADD0</name>
              <bitOffset>16</bitOffset>
              <bitWidth>16</bitWidth>
            </field>
          </fields>
        </register>
        <register>
          <name>UR3</name>
          <addressOffset>0x30c</addressOffset>
          <size>0x20</size>
          <fields>
            <field>
              <name>BOOT_ADD1</name>
              <bitOffset>0</bitOffset>
              <bitWidth>16</bitWidth>
            </field>
          </fields>
        </register>
        <register>
          <name>UR4</name>
          <addressOffset>0x310</addressOffset>
          <size>0x20</size>
          <fields>
            <field>
              <name>MEPAD_BANK1</name>
              <bitOffset>16</bitOffset>
              <bitWidth>1</bitWidth>
            </field>
          </fields>
        </register>
        <register>
          <name>UR5</name>
          <addressOffset>0x314</addressOffset>
          <size>0x20</size>
          <fields>
            <field>
              <name>MESAD_BANK1</name>
              <bitOffset>0</bitOffset>
              <bitWidth>1</bitWidth>
            </field>
            <field>
              <name>WRPN_BANK1</name>
              <bitOffset>16</bitOffset>
              <bitWidth>8</bitWidth>
            </field>
          </fields>
        </register>
        <register>
          <name>UR6</name>
          <addressOffset>0x318</addressOffset>
          <size>0x20</size>
          <fields>
            <field>
              <name>PABEG_BANK1</name>
              <bitOffset>0</bitOffset>
              <bitWidth>12</bitWidth>
            </field>
            <field>
              <name>PAEND_BANK1</name>
              <bitOffset>16</bitOffset>
              <bitWidth>12</bitWidth>
            </field>
          </fields>
        </register>
        <register>
          <name>UR7</name>
          <addressOffset>0x31c</addressOffset>
          <size>0x20</size>
          <fields>
            <field>
              <name>SABEG_BANK1</name>
              <bitOffset>0</bitOffset>
              <bitWidth>12</bitWidth>
            </field>
            <field>
              <name>SAEND_BANK1</name>
              <bitOffset>16</bitOffset>
              <bitWidth>12</bitWidth>
            </field>
          </fields>
        </register>
        <register>
          <name>UR11</name>
          <addressOffset>0x32c</addressOffset>
          <size>0x20</size>
          <fields>
            <field>
              <name>IWDG1M</name>
              <bitOffset>16</bitOffset>
              <bitWidth>1</bitWidth>
            </field>
          </fields>
        </register>
        <register>
          <name>UR12</name>
          <addressOffset>0x330</addressOffset>
          <size>0x20</size>
          <fields>
            <field>
              <name>SECURE</name>
              <bitOffset>16</bitOffset>
              <bitWidth>1</bitWidth>
            </field>
          </fields>
        </register>
        <register>
          <name>UR13</name>
          <addressOffset>0x334</addressOffset>
          <size>0x20</size>
          <fields>
            <field>
              <name>SDRS</name>
              <bitOffset>0</bitOffset>
              <bitWidth>2</bitWidth>
            </field>
            <field>
              <name>D1SBRST</name>
              <bitOffset>16</bitOffset>
              <bitWidth>1</bitWidth>
            </field>
          </fields>
        </register>
        <register>
          <name>UR14</name>
          <addressOffset>0x338</addressOffset>
          <size>0x20</size>
          <fields>
            <field>
              <name>D1STPRST</name>
              <bitOffset>0</bitOffset>
              <bitWidth>1</bitWidth>
            </field>
          </fields>
        </register>
        <register>
          <name>UR15</name>
          <addressOffset>0x33c</addressOffset>
          <size>0x20</size>
          <fields>
            <field>
              <name>FZIWDGSTB</name>
              <bitOffset>16</bitOffset>
              <bitWidth>1</bitWidth>
            </field>
          </fields>
        </register>
        <register>
          <name>UR16</name>
          <addressOffset>0x340</addressOffset>
          <size>0x20</size>
          <fields>
            <field>
              <name>FZIWDGSTP</name>
              <bitOffset>0</bitOffset>
              <bitWidth>1</bitWidth>
            </field>
            <field>
              <name>PKP</name>
              <bitOffset>16</bitOffset>
              <bitWidth>1</bitWidth>
            </field>
          </fields>
        </register>
        <register>
          <name>UR17</name>
          <addressOffset>0x344</addressOffset>
          <size>0x20</size>
          <fields>
            <field>
              <name>IOHSLV</name>
              <bitOffset>0</bitOffset>
              <bitWidth>1</bitWidth>
            </field>
            <field>
              <name>TCM_AXI_CFG</name>
              <bitOffset>16</bitOffset>
              <bitWidth>2</bitWidth>
            </field>
          </fields>
        </register>
        <register>
          <name>UR18</name>
          <addressOffset>0x348</addressOffset>
          <size>0x20</size>
          <fields>
            <field>
              <name>CPU_FREQ_BOOST</name>
              <bitOffset>0</bitOffset>
              <bitWidth>1</bitWidth>
            </field>
          </fields>
        </register>
      </registers>
    </peripheral>
    <peripheral>
      <name>LPUART1</name>
      <baseAddress>0x58000c00</baseAddress>
      <registers>
        <register>
          <name>CR1</name>
          <addressOffset>0x0</addressOffset>
          <size>0x20</size>
          <fields>
            <field>
              <name>UE</name>
              <bitOffset>0</bitOffset>
              <bitWidth>1</bitWidth>
            </field>
            <field>
              <name>UESM</name>
              <bitOffset>1</bitOffset>
              <bitWidth>1</bitWidth>
            </field>
            <field>
              <name>RE</name>
              <bitOffset>2</bitOffset>
              <bitWidth>1</bitWidth>
            </field>
            <field>
              <name>TE</name>
              <bitOffset>3</bitOffset>
              <bitWidth>1</bitWidth>
            </field>
            <field>
              <name>IDLEIE</name>
              <bitOffset>4</bitOffset>
              <bitWidth>1</bitWidth>
            </field>
            <field>
              <name>RXNEIE_RXFNEIE</name>
              <bitOffset>5</bitOffset>
              <bitWidth>1</bitWidth>
            </field>
            <field>
              <name>TCIE</name>
              <bitOffset>6</bitOffset>
              <bitWidth>1</bitWidth>
            </field>
            <field>
              <name>TXEIE_TXFNFIE</name>
              <bitOffset>7</bitOffset>
              <bitWidth>1</bitWidth>
            </field>
            <field>
              <name>PEIE</name>
              <bitOffset>8</bitOffset>
              <bitWidth>1</bitWidth>
            </field>
            <field>
              <name>PS</name>
              <bitOffset>9</bitOffset>
              <bitWidth>1</bitWidth>
            </field>
            <field>
              <name>PCE</name>
              <bitOffset>10</bitOffset>
              <bitWidth>1</bitWidth>
            </field>
            <field>
              <name>WAKE</name>
              <bitOffset>11</bitOffset>
              <bitWidth>1</bitWidth>
            </field>
            <field>
              <name>M0</name>
              <bitOffset>12</bitOffset>
              <bitWidth>1</bitWidth>
            </field>
            <field>
              <name>MME</name>
              <bitOffset>13</bitOffset>
              <bitWidth>1</bitWidth>
            </field>
            <field>
              <name>CMIE</name>
              <bitOffset>14</bitOffset>
              <bitWidth>1</bitWidth>
            </field>
            <field>
              <name>OVER8</name>
              <bitOffset>15</bitOffset>
              <bitWidth>1</bitWidth>
            </field>
            <field>
              <name>DEDT</name>
              <bitOffset>16</bitOffset>
              <bitWidth>5</bitWidth>
            </field>
            <field>
              <name>DEAT</name>
              <bitOffset>21</bitOffset>
              <bitWidth>5</bitWidth>
            </field>
            <field>
              <name>RTOIE</name>
              <bitOffset>26</bitOffset>
              <bitWidth>1</bitWidth>
            </field>
            <field>
              <name>EOBIE</name>
              <bitOffset>27</bitOffset>
              <bitWidth>1</bitWidth>
            </field>
            <field>
              <name>M1</name>
              <bitOffset>28</bitOffset>
              <bitWidth>1</bitWidth>
            </field>
            <field>
              <name>FIFOEN</name>
              <bitOffset>29</bitOffset>
              <bitWidth>1</bitWidth>
            </field>
            <field>
              <name>TXFEIE</name>
              <bitOffset>30</bitOffset>
              <bitWidth>1</bitWidth>
            </field>
            <field>
              <name>RXFFIE</name>
              <bitOffset>31</bitOffset>
              <bitWidth>1</bitWidth>
            </field>
          </fields>
        </register>
        <register>
          <name>CR2</name>
          <addressOffset>0x4</addressOffset>
          <size>0x20</size>
          <fields>
            <field>
              <name>SLVEN</name>
              <bitOffset>0</bitOffset>
              <bitWidth>1</bitWidth>
            </field>
            <field>
              <name>DIS_NSS</name>
              <bitOffset>3</bitOffset>
              <bitWidth>1</bitWidth>
            </field>
            <field>
              <name>ADDM7</name>
              <bitOffset>4</bitOffset>
              <bitWidth>1</bitWidth>
            </field>
            <field>
              <name>LBDL</name>
              <bitOffset>5</bitOffset>
              <bitWidth>1</bitWidth>
            </field>
            <field>
              <name>LBDIE</name>
              <bitOffset>6</bitOffset>
              <bitWidth>1</bitWidth>
            </field>
            <field>
              <name>LBCL</name>
              <bitOffset>8</bitOffset>
              <bitWidth>1</bitWidth>
            </field>
            <field>
              <name>CPHA</name>
              <bitOffset>9</bitOffset>
              <bitWidth>1</bitWidth>
            </field>
            <field>
              <name>CPOL</name>
              <bitOffset>10</bitOffset>
              <bitWidth>1</bitWidth>
            </field>
            <field>
              <name>CLKEN</name>
              <bitOffset>11</bitOffset>
              <bitWidth>1</bitWidth>
            </field>
            <field>
              <name>STOP</name>
              <bitOffset>12</bitOffset>
              <bitWidth>2</bitWidth>
            </field>
            <field>
              <name>LINEN</name>
              <bitOffset>14</bitOffset>
              <bitWidth>1</bitWidth>
            </field>
            <field>
              <name>SWAP</name>
              <bitOffset>15</bitOffset>
              <bitWidth>1</bitWidth>
            </field>
            <field>
              <name>RXINV</name>
              <bitOffset>16</bitOffset>
              <bitWidth>1</bitWidth>
            </field>
            <field>
              <name>TXINV</name>
              <bitOffset>17</bitOffset>
              <bitWidth>1</bitWidth>
            </field>
            <field>
              <name>DATAINV</name>
              <bitOffset>18</bitOffset>
              <bitWidth>1</bitWidth>
            </field>
            <field>
              <name>MSBFIRST</name>
              <bitOffset>19</bitOffset>
              <bitWidth>1</bitWidth>
            </field>
            <field>
              <name>ABREN</name>
              <bitOffset>20</bitOffset>
              <bitWidth>1</bitWidth>
            </field>
            <field>
              <name>ABRMODE</name>
              <bitOffset>21</bitOffset>
              <bitWidth>2</bitWidth>
            </field>
            <field>
              <name>RTOEN</name>
              <bitOffset>23</bitOffset>
              <bitWidth>1</bitWidth>
            </field>
            <field>
              <name>ADD</name>
              <bitOffset>24</bitOffset>
              <bitWidth>8</bitWidth>
            </field>
          </fields>
        </register>
        <register>
          <name>CR3</name>
          <addressOffset>0x8</addressOffset>
          <size>0x20</size>
          <fields>
            <field>
              <name>EIE</name>
              <bitOffset>0</bitOffset>
              <bitWidth>1</bitWidth>
            </field>
            <field>
              <name>IREN</name>
              <bitOffset>1</bitOffset>
              <bitWidth>1</bitWidth>
            </field>
            <field>
              <name>IRLP</name>
              <bitOffset>2</bitOffset>
              <bitWidth>1</bitWidth>
            </field>
            <field>
              <name>HDSEL</name>
              <bitOffset>3</bitOffset>
              <bitWidth>1</bitWidth>
            </field>
            <field>
              <name>NACK</name>
              <bitOffset>4</bitOffset>
              <bitWidth>1</bitWidth>
            </field>
            <field>
              <name>SCEN</name>
              <bitOffset>5</bitOffset>
              <bitWidth>1</bitWidth>
            </field>
            <field>
              <name>DMAR</name>
              <bitOffset>6</bitOffset>
              <bitWidth>1</bitWidth>
            </field>
            <field>
              <name>DMAT</name>
              <bitOffset>7</bitOffset>
              <bitWidth>1</bitWidth>
            </field>
            <field>
              <name>RTSE</name>
              <bitOffset>8</bitOffset>
              <bitWidth>1</bitWidth>
            </field>
            <field>
              <name>CTSE</name>
              <bitOffset>9</bitOffset>
              <bitWidth>1</bitWidth>
            </field>
            <field>
              <name>CTSIE</name>
              <bitOffset>10</bitOffset>
              <bitWidth>1</bitWidth>
            </field>
            <field>
              <name>ONEBIT</name>
              <bitOffset>11</bitOffset>
              <bitWidth>1</bitWidth>
            </field>
            <field>
              <name>OVRDIS</name>
              <bitOffset>12</bitOffset>
              <bitWidth>1</bitWidth>
            </field>
            <field>
              <name>DDRE</name>
              <bitOffset>13</bitOffset>
              <bitWidth>1</bitWidth>
            </field>
            <field>
              <name>DEM</name>
              <bitOffset>14</bitOffset>
              <bitWidth>1</bitWidth>
            </field>
            <field>
              <name>DEP</name>
              <bitOffset>15</bitOffset>
              <bitWidth>1</bitWidth>
            </field>
            <field>
              <name>SCARCNT</name>
              <bitOffset>17</bitOffset>
              <bitWidth>3</bitWidth>
            </field>
            <field>
              <name>WUS</name>
              <bitOffset>20</bitOffset>
              <bitWidth>2</bitWidth>
            </field>
            <field>
              <name>WUFIE</name>
              <bitOffset>22</bitOffset>
              <bitWidth>1</bitWidth>
            </field>
            <field>
              <name>TXFTIE</name>
              <bitOffset>23</bitOffset>
              <bitWidth>1</bitWidth>
            </field>
            <field>
              <name>TCBGTIE</name>
              <bitOffset>24</bitOffset>
              <bitWidth>1</bitWidth>
            </field>
            <field>
              <name>RXFTCFG</name>
              <bitOffset>25</bitOffset>
              <bitWidth>3</bitWidth>
            </field>
            <field>
              <name>RXFTIE</name>
              <bitOffset>28</bitOffset>
              <bitWidth>1</bitWidth>
            </field>
            <field>
              <name>TXFTCFG</name>
              <bitOffset>29</bitOffset>
              <bitWidth>3</bitWidth>
            </field>
          </fields>
        </register>
        <register>
          <name>BRR</name>
          <addressOffset>0xc</addressOffset>
          <size>0x20</size>
          <fields>
            <field>
              <name>DIV_FRACTION</name>
              <bitOffset>0</bitOffset>
              <bitWidth>4</bitWidth>
            </field>
            <field>
              <name>DIV_MANTISSA</name>
              <bitOffset>4</bitOffset>
              <bitWidth>12</bitWidth>
            </field>
          </fields>
        </register>
        <register>
          <name>GTPR</name>
          <addressOffset>0x10</addressOffset>
          <size>0x20</size>
          <fields>
            <field>
              <name>PSC</name>
              <bitOffset>0</bitOffset>
              <bitWidth>8</bitWidth>
            </field>
            <field>
              <name>GT</name>
              <bitOffset>8</bitOffset>
              <bitWidth>8</bitWidth>
            </field>
          </fields>
        </register>
        <register>
          <name>RTOR</name>
          <addressOffset>0x14</addressOffset>
          <size>0x20</size>
          <fields>
            <field>
              <name>RTO</name>
              <bitOffset>0</bitOffset>
              <bitWidth>24</bitWidth>
            </field>
            <field>
              <name>BLEN</name>
              <bitOffset>24</bitOffset>
              <bitWidth>8</bitWidth>
            </field>
          </fields>
        </register>
        <register>
          <name>RQR</name>
          <addressOffset>0x18</addressOffset>
          <size>0x20</size>
          <fields>
            <field>
              <name>ABRRQ</name>
              <bitOffset>0</bitOffset>
              <bitWidth>1</bitWidth>
            </field>
            <field>
              <name>SBKRQ</name>
              <bitOffset>1</bitOffset>
              <bitWidth>1</bitWidth>
            </field>
            <field>
              <name>MMRQ</name>
              <bitOffset>2</bitOffset>
              <bitWidth>1</bitWidth>
            </field>
            <field>
              <name>RXFRQ</name>
              <bitOffset>3</bitOffset>
              <bitWidth>1</bitWidth>
            </field>
            <field>
              <name>TXFRQ</name>
              <bitOffset>4</bitOffset>
              <bitWidth>1</bitWidth>
            </field>
          </fields>
        </register>
        <register>
          <name>ISR</name>
          <addressOffset>0x1c</addressOffset>
          <size>0x20</size>
          <fields>
            <field>
              <name>PE</name>
              <bitOffset>0</bitOffset>
              <bitWidth>1</bitWidth>
            </field>
            <field>
              <name>FE</name>
              <bitOffset>1</bitOffset>
              <bitWidth>1</bitWidth>
            </field>
            <field>
              <name>NE</name>
              <bitOffset>2</bitOffset>
              <bitWidth>1</bitWidth>
            </field>
            <field>
              <name>ORE</name>
              <bitOffset>3</bitOffset>
              <bitWidth>1</bitWidth>
            </field>
            <field>
              <name>IDLE</name>
              <bitOffset>4</bitOffset>
              <bitWidth>1</bitWidth>
            </field>
            <field>
              <name>RXNE_RXFNE</name>
              <bitOffset>5</bitOffset>
              <bitWidth>1</bitWidth>
            </field>
            <field>
              <name>TC</name>
              <bitOffset>6</bitOffset>
              <bitWidth>1</bitWidth>
            </field>
            <field>
              <name>TXE_TXFNF</name>
              <bitOffset>7</bitOffset>
              <bitWidth>1</bitWidth>
            </field>
            <field>
              <name>LBDF</name>
              <bitOffset>8</bitOffset>
              <bitWidth>1</bitWidth>
            </field>
            <field>
              <name>CTSIF</name>
              <bitOffset>9</bitOffset>
              <bitWidth>1</bitWidth>
            </field>
            <field>
              <name>CTS</name>
              <bitOffset>10</bitOffset>
              <bitWidth>1</bitWidth>
            </field>
            <field>
              <name>RTOF</name>
              <bitOffset>11</bitOffset>
              <bitWidth>1</bitWidth>
            </field>
            <field>
              <name>EOBF</name>
              <bitOffset>12</bitOffset>
              <bitWidth>1</bitWidth>
            </field>
            <field>
              <name>UDR</name>
              <bitOffset>13</bitOffset>
              <bitWidth>1</bitWidth>
            </field>
            <field>
              <name>ABRE</name>
              <bitOffset>14</bitOffset>
              <bitWidth>1</bitWidth>
            </field>
            <field>
              <name>ABRF</name>
              <bitOffset>15</bitOffset>
              <bitWidth>1</bitWidth>
            </field>
            <field>
              <name>BUSY</name>
              <bitOffset>16</bitOffset>
              <bitWidth>1</bitWidth>
            </field>
            <field>
              <name>CMF</name>
              <bitOffset>17</bitOffset>
              <bitWidth>1</bitWidth>
            </field>
            <field>
              <name>SBKF</name>
              <bitOffset>18</bitOffset>
              <bitWidth>1</bitWidth>
            </field>
            <field>
              <name>RWU</name>
              <bitOffset>19</bitOffset>
              <bitWidth>1</bitWidth>
            </field>
            <field>
              <name>WUF</name>
              <bitOffset>20</bitOffset>
              <bitWidth>1</bitWidth>
            </field>
            <field>
              <name>TEACK</name>
              <bitOffset>21</bitOffset>
              <bitWidth>1</bitWidth>
            </field>
            <field>
              <name>REACK</name>
              <bitOffset>22</bitOffset>
              <bitWidth>1</bitWidth>
            </field>
            <field>
              <name>TXFE</name>
              <bitOffset>23</bitOffset>
              <bitWidth>1</bitWidth>
            </field>
            <field>
              <name>RXFF</name>
              <bitOffset>24</bitOffset>
              <bitWidth>1</bitWidth>
            </field>
            <field>
              <name>TCBGT</name>
              <bitOffset>25</bitOffset>
              <bitWidth>1</bitWidth>
            </field>
            <field>
              <name>RXFT</name>
              <bitOffset>26</bitOffset>
              <bitWidth>1</bitWidth>
            </field>
            <field>
              <name>TXFT</name>
              <bitOffset>27</bitOffset>
              <bitWidth>1</bitWidth>
            </field>
          </fields>
        </register>
        <register>
          <name>ICR</name>
          <addressOffset>0x20</addressOffset>
          <size>0x20</size>
          <fields>
            <field>
              <name>PECF</name>
              <bitOffset>0</bitOffset>
              <bitWidth>1</bitWidth>
            </field>
            <field>
              <name>FECF</name>
              <bitOffset>1</bitOffset>
              <bitWidth>1</bitWidth>
            </field>
            <field>
              <name>NECF</name>
              <bitOffset>2</bitOffset>
              <bitWidth>1</bitWidth>
            </field>
            <field>
              <name>ORECF</name>
              <bitOffset>3</bitOffset>
              <bitWidth>1</bitWidth>
            </field>
            <field>
              <name>IDLECF</name>
              <bitOffset>4</bitOffset>
              <bitWidth>1</bitWidth>
            </field>
            <field>
              <name>TXFECF</name>
              <bitOffset>5</bitOffset>
              <bitWidth>1</bitWidth>
            </field>
            <field>
              <name>TCCF</name>
              <bitOffset>6</bitOffset>
              <bitWidth>1</bitWidth>
            </field>
            <field>
              <name>TCBGTCF</name>
              <bitOffset>7</bitOffset>
              <bitWidth>1</bitWidth>
            </field>
            <field>
              <name>LBDCF</name>
              <bitOffset>8</bitOffset>
              <bitWidth>1</bitWidth>
            </field>
            <field>
              <name>CTSCF</name>
              <bitOffset>9</bitOffset>
              <bitWidth>1</bitWidth>
            </field>
            <field>
              <name>RTOCF</name>
              <bitOffset>11</bitOffset>
              <bitWidth>1</bitWidth>
            </field>
            <field>
              <name>EOBCF</name>
              <bitOffset>12</bitOffset>
              <bitWidth>1</bitWidth>
            </field>
            <field>
              <name>UDRCF</name>
              <bitOffset>13</bitOffset>
              <bitWidth>1</bitWidth>
            </field>
            <field>
              <name>CMCF</name>
              <bitOffset>17</bitOffset>
              <bitWidth>1</bitWidth>
            </field>
            <field>
              <name>WUCF</name>
              <bitOffset>20</bitOffset>
              <bitWidth>1</bitWidth>
            </field>
          </fields>
        </register>
        <register>
          <name>RDR</name>
          <addressOffset>0x24</addressOffset>
          <size>0x20</size>
          <fields>
            <field>
              <name>RDR</name>
              <bitOffset>0</bitOffset>
              <bitWidth>9</bitWidth>
            </field>
          </fields>
        </register>
        <register>
          <name>TDR</name>
          <addressOffset>0x28</addressOffset>
          <size>0x20</size>
          <fields>
            <field>
              <name>TDR</name>
              <bitOffset>0</bitOffset>
              <bitWidth>9</bitWidth>
            </field>
          </fields>
        </register>
        <register>
          <name>PRESC</name>
          <addressOffset>0x2c</addressOffset>
          <size>0x20</size>
          <fields>
            <field>
              <name>PRESCALER</name>
              <bitOffset>0</bitOffset>
              <bitWidth>4</bitWidth>
            </field>
          </fields>
        </register>
      </registers>
    </peripheral>
    <peripheral>
      <name>SPI6</name>
      <baseAddress>0x58001400</baseAddress>
      <registers>
        <register>
          <name>CR1</name>
          <addressOffset>0x0</addressOffset>
          <size>0x20</size>
          <fields>
            <field>
              <name>SPE</name>
              <bitOffset>0</bitOffset>
              <bitWidth>1</bitWidth>
            </field>
            <field>
              <name>MASRX</name>
              <bitOffset>8</bitOffset>
              <bitWidth>1</bitWidth>
            </field>
            <field>
              <name>CSTART</name>
              <bitOffset>9</bitOffset>
              <bitWidth>1</bitWidth>
            </field>
            <field>
              <name>CSUSP</name>
              <bitOffset>10</bitOffset>
              <bitWidth>1</bitWidth>
            </field>
            <field>
              <name>HDDIR</name>
              <bitOffset>11</bitOffset>
              <bitWidth>1</bitWidth>
            </field>
            <field>
              <name>SSI</name>
              <bitOffset>12</bitOffset>
              <bitWidth>1</bitWidth>
            </field>
            <field>
              <name>CRC33_17</name>
              <bitOffset>13</bitOffset>
              <bitWidth>1</bitWidth>
            </field>
            <field>
              <name>RCRCINI</name>
              <bitOffset>14</bitOffset>
              <bitWidth>1</bitWidth>
            </field>
            <field>
              <name>TCRCINI</name>
              <bitOffset>15</bitOffset>
              <bitWidth>1</bitWidth>
            </field>
            <field>
              <name>IOLOCK</name>
              <bitOffset>16</bitOffset>
              <bitWidth>1</bitWidth>
            </field>
          </fields>
        </register>
        <register>
          <name>CR2</name>
          <addressOffset>0x4</addressOffset>
          <size>0x20</size>
          <fields>
            <field>
              <name>TSIZE</name>
              <bitOffset>0</bitOffset>
              <bitWidth>16</bitWidth>
            </field>
            <field>
              <name>TSER</name>
              <bitOffset>16</bitOffset>
              <bitWidth>16</bitWidth>
            </field>
          </fields>
        </register>
        <register>
          <name>CFG1</name>
          <addressOffset>0x8</addressOffset>
          <size>0x20</size>
          <fields>
            <field>
              <name>DSIZE</name>
              <bitOffset>0</bitOffset>
              <bitWidth>5</bitWidth>
            </field>
            <field>
              <name>FTHLV</name>
              <bitOffset>5</bitOffset>
              <bitWidth>4</bitWidth>
            </field>
            <field>
              <name>UDRCFG</name>
              <bitOffset>9</bitOffset>
              <bitWidth>2</bitWidth>
            </field>
            <field>
              <name>UDRDET</name>
              <bitOffset>11</bitOffset>
              <bitWidth>2</bitWidth>
            </field>
            <field>
              <name>RXDMAEN</name>
              <bitOffset>14</bitOffset>
              <bitWidth>1</bitWidth>
            </field>
            <field>
              <name>TXDMAEN</name>
              <bitOffset>15</bitOffset>
              <bitWidth>1</bitWidth>
            </field>
            <field>
              <name>CRCSIZE</name>
              <bitOffset>16</bitOffset>
              <bitWidth>5</bitWidth>
            </field>
            <field>
              <name>CRCEN</name>
              <bitOffset>22</bitOffset>
              <bitWidth>1</bitWidth>
            </field>
            <field>
              <name>MBR</name>
              <bitOffset>28</bitOffset>
              <bitWidth>3</bitWidth>
            </field>
          </fields>
        </register>
        <register>
          <name>CFG2</name>
          <addressOffset>0xc</addressOffset>
          <size>0x20</size>
          <fields>
            <field>
              <name>MSSI</name>
              <bitOffset>0</bitOffset>
              <bitWidth>4</bitWidth>
            </field>
            <field>
              <name>MIDI</name>
              <bitOffset>4</bitOffset>
              <bitWidth>4</bitWidth>
            </field>
            <field>
              <name>IOSWP</name>
              <bitOffset>15</bitOffset>
              <bitWidth>1</bitWidth>
            </field>
            <field>
              <name>COMM</name>
              <bitOffset>17</bitOffset>
              <bitWidth>2</bitWidth>
            </field>
            <field>
              <name>SP</name>
              <bitOffset>19</bitOffset>
              <bitWidth>3</bitWidth>
            </field>
            <field>
              <name>MASTER</name>
              <bitOffset>22</bitOffset>
              <bitWidth>1</bitWidth>
            </field>
            <field>
              <name>LSBFRST</name>
              <bitOffset>23</bitOffset>
              <bitWidth>1</bitWidth>
            </field>
            <field>
              <name>CPHA</name>
              <bitOffset>24</bitOffset>
              <bitWidth>1</bitWidth>
            </field>
            <field>
              <name>CPOL</name>
              <bitOffset>25</bitOffset>
              <bitWidth>1</bitWidth>
            </field>
            <field>
              <name>SSM</name>
              <bitOffset>26</bitOffset>
              <bitWidth>1</bitWidth>
            </field>
            <field>
              <name>SSIOP</name>
              <bitOffset>28</bitOffset>
              <bitWidth>1</bitWidth>
            </field>
            <field>
              <name>SSOE</name>
              <bitOffset>29</bitOffset>
              <bitWidth>1</bitWidth>
            </field>
            <field>
              <name>SSOM</name>
              <bitOffset>30</bitOffset>
              <bitWidth>1</bitWidth>
            </field>
            <field>
              <name>AFCNTR</name>
              <bitOffset>31</bitOffset>
              <bitWidth>1</bitWidth>
            </field>
          </fields>
        </register>
        <register>
          <name>IER</name>
          <addressOffset>0x10</addressOffset>
          <size>0x20</size>
          <fields>
            <field>
              <name>RXPIE</name>
              <bitOffset>0</bitOffset>
              <bitWidth>1</bitWidth>
            </field>
            <field>
              <name>TXPIE</name>
              <bitOffset>1</bitOffset>
              <bitWidth>1</bitWidth>
            </field>
            <field>
              <name>DXPIE</name>
              <bitOffset>2</bitOffset>
              <bitWidth>1</bitWidth>
            </field>
            <field>
              <name>EOTIE</name>
              <bitOffset>3</bitOffset>
              <bitWidth>1</bitWidth>
            </field>
            <field>
              <name>TXTFIE</name>
              <bitOffset>4</bitOffset>
              <bitWidth>1</bitWidth>
            </field>
            <field>
              <name>UDRIE</name>
              <bitOffset>5</bitOffset>
              <bitWidth>1</bitWidth>
            </field>
            <field>
              <name>OVRIE</name>
              <bitOffset>6</bitOffset>
              <bitWidth>1</bitWidth>
            </field>
            <field>
              <name>CRCEIE</name>
              <bitOffset>7</bitOffset>
              <bitWidth>1</bitWidth>
            </field>
            <field>
              <name>TIFREIE</name>
              <bitOffset>8</bitOffset>
              <bitWidth>1</bitWidth>
            </field>
            <field>
              <name>MODFIE</name>
              <bitOffset>9</bitOffset>
              <bitWidth>1</bitWidth>
            </field>
            <field>
              <name>TSERFIE</name>
              <bitOffset>10</bitOffset>
              <bitWidth>1</bitWidth>
            </field>
          </fields>
        </register>
        <register>
          <name>SR</name>
          <addressOffset>0x14</addressOffset>
          <size>0x20</size>
          <fields>
            <field>
              <name>RXP</name>
              <bitOffset>0</bitOffset>
              <bitWidth>1</bitWidth>
            </field>
            <field>
              <name>TXP</name>
              <bitOffset>1</bitOffset>
              <bitWidth>1</bitWidth>
            </field>
            <field>
              <name>DXP</name>
              <bitOffset>2</bitOffset>
              <bitWidth>1</bitWidth>
            </field>
            <field>
              <name>EOT</name>
              <bitOffset>3</bitOffset>
              <bitWidth>1</bitWidth>
            </field>
            <field>
              <name>TXTF</name>
              <bitOffset>4</bitOffset>
              <bitWidth>1</bitWidth>
            </field>
            <field>
              <name>UDR</name>
              <bitOffset>5</bitOffset>
              <bitWidth>1</bitWidth>
            </field>
            <field>
              <name>OVR</name>
              <bitOffset>6</bitOffset>
              <bitWidth>1</bitWidth>
            </field>
            <field>
              <name>CRCE</name>
              <bitOffset>7</bitOffset>
              <bitWidth>1</bitWidth>
            </field>
            <field>
              <name>TIFRE</name>
              <bitOffset>8</bitOffset>
              <bitWidth>1</bitWidth>
            </field>
            <field>
              <name>MODF</name>
              <bitOffset>9</bitOffset>
              <bitWidth>1</bitWidth>
            </field>
            <field>
              <name>TSERF</name>
              <bitOffset>10</bitOffset>
              <bitWidth>1</bitWidth>
            </field>
            <field>
              <name>SUSP</name>
              <bitOffset>11</bitOffset>
              <bitWidth>1</bitWidth>
            </field>
            <field>
              <name>TXC</name>
              <bitOffset>12</bitOffset>
              <bitWidth>1</bitWidth>
            </field>
            <field>
              <name>RXPLVL</name>
              <bitOffset>13</bitOffset>
              <bitWidth>2</bitWidth>
            </field>
            <field>
              <name>RXWNE</name>
              <bitOffset>15</bitOffset>
              <bitWidth>1</bitWidth>
            </field>
            <field>
              <name>CTSIZE</name>
              <bitOffset>16</bitOffset>
              <bitWidth>16</bitWidth>
            </field>
          </fields>
        </register>
        <register>
          <name>IFCR</name>
          <addressOffset>0x18</addressOffset>
          <size>0x20</size>
          <fields>
            <field>
              <name>EOTC</name>
              <bitOffset>3</bitOffset>
              <bitWidth>1</bitWidth>
            </field>
            <field>
              <name>TXTFC</name>
              <bitOffset>4</bitOffset>
              <bitWidth>1</bitWidth>
            </field>
            <field>
              <name>UDRC</name>
              <bitOffset>5</bitOffset>
              <bitWidth>1</bitWidth>
            </field>
            <field>
              <name>OVRC</name>
              <bitOffset>6</bitOffset>
              <bitWidth>1</bitWidth>
            </field>
            <field>
              <name>CRCEC</name>
              <bitOffset>7</bitOffset>
              <bitWidth>1</bitWidth>
            </field>
            <field>
              <name>TIFREC</name>
              <bitOffset>8</bitOffset>
              <bitWidth>1</bitWidth>
            </field>
            <field>
              <name>MODFC</name>
              <bitOffset>9</bitOffset>
              <bitWidth>1</bitWidth>
            </field>
            <field>
              <name>TSERFC</name>
              <bitOffset>10</bitOffset>
              <bitWidth>1</bitWidth>
            </field>
            <field>
              <name>SUSPC</name>
              <bitOffset>11</bitOffset>
              <bitWidth>1</bitWidth>
            </field>
          </fields>
        </register>
        <register>
          <name>TXDR</name>
          <addressOffset>0x20</addressOffset>
          <size>0x20</size>
          <fields>
            <field>
              <name>TXDR</name>
              <bitOffset>0</bitOffset>
              <bitWidth>32</bitWidth>
            </field>
          </fields>
        </register>
        <register>
          <name>RXDR</name>
          <addressOffset>0x30</addressOffset>
          <size>0x20</size>
          <fields>
            <field>
              <name>RXDR</name>
              <bitOffset>0</bitOffset>
              <bitWidth>32</bitWidth>
            </field>
          </fields>
        </register>
        <register>
          <name>CRCPOLY</name>
          <addressOffset>0x40</addressOffset>
          <size>0x20</size>
          <fields>
            <field>
              <name>CRCPOLY</name>
              <bitOffset>0</bitOffset>
              <bitWidth>32</bitWidth>
            </field>
          </fields>
        </register>
        <register>
          <name>TXCRC</name>
          <addressOffset>0x44</addressOffset>
          <size>0x20</size>
          <fields>
            <field>
              <name>TXCRC</name>
              <bitOffset>0</bitOffset>
              <bitWidth>32</bitWidth>
            </field>
          </fields>
        </register>
        <register>
          <name>RXCRC</name>
          <addressOffset>0x48</addressOffset>
          <size>0x20</size>
          <fields>
            <field>
              <name>RXCRC</name>
              <bitOffset>0</bitOffset>
              <bitWidth>32</bitWidth>
            </field>
          </fields>
        </register>
        <register>
          <name>UDRDR</name>
          <addressOffset>0x4c</addressOffset>
          <size>0x20</size>
          <fields>
            <field>
              <name>UDRDR</name>
              <bitOffset>0</bitOffset>
              <bitWidth>32</bitWidth>
            </field>
          </fields>
        </register>
        <register>
          <name>I2SCFGR</name>
          <addressOffset>0x50</addressOffset>
          <size>0x20</size>
          <fields>
            <field>
              <name>I2SMOD</name>
              <bitOffset>0</bitOffset>
              <bitWidth>1</bitWidth>
            </field>
            <field>
              <name>I2SCFG</name>
              <bitOffset>1</bitOffset>
              <bitWidth>3</bitWidth>
            </field>
            <field>
              <name>I2SSTD</name>
              <bitOffset>4</bitOffset>
              <bitWidth>2</bitWidth>
            </field>
            <field>
              <name>PCMSYNC</name>
              <bitOffset>7</bitOffset>
              <bitWidth>1</bitWidth>
            </field>
            <field>
              <name>DATLEN</name>
              <bitOffset>8</bitOffset>
              <bitWidth>2</bitWidth>
            </field>
            <field>
              <name>CHLEN</name>
              <bitOffset>10</bitOffset>
              <bitWidth>1</bitWidth>
            </field>
            <field>
              <name>CKPOL</name>
              <bitOffset>11</bitOffset>
              <bitWidth>1</bitWidth>
            </field>
            <field>
              <name>FIXCH</name>
              <bitOffset>12</bitOffset>
              <bitWidth>1</bitWidth>
            </field>
            <field>
              <name>WSINV</name>
              <bitOffset>13</bitOffset>
              <bitWidth>1</bitWidth>
            </field>
            <field>
              <name>DATFMT</name>
              <bitOffset>14</bitOffset>
              <bitWidth>1</bitWidth>
            </field>
            <field>
              <name>I2SDIV</name>
              <bitOffset>16</bitOffset>
              <bitWidth>8</bitWidth>
            </field>
            <field>
              <name>ODD</name>
              <bitOffset>24</bitOffset>
              <bitWidth>1</bitWidth>
            </field>
            <field>
              <name>MCKOE</name>
              <bitOffset>25</bitOffset>
              <bitWidth>1</bitWidth>
            </field>
          </fields>
        </register>
      </registers>
    </peripheral>
    <peripheral>
      <name>I2C4</name>
      <baseAddress>0x58001c00</baseAddress>
      <registers>
        <register>
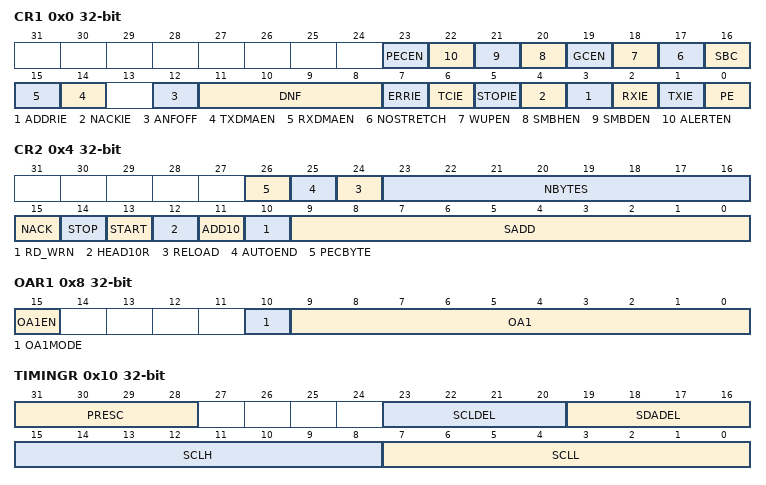
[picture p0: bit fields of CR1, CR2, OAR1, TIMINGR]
          <name>CR1</name>
          <addressOffset>0x0</addressOffset>
          <size>0x20</size>
          <fields>
            <field>
              <name>PE</name>
              <bitOffset>0</bitOffset>
              <bitWidth>1</bitWidth>
            </field>
            <field>
              <name>TXIE</name>
              <bitOffset>1</bitOffset>
              <bitWidth>1</bitWidth>
            </field>
            <field>
              <name>RXIE</name>
              <bitOffset>2</bitOffset>
              <bitWidth>1</bitWidth>
            </field>
            <field>
              <name>ADDRIE</name>
              <bitOffset>3</bitOffset>
              <bitWidth>1</bitWidth>
            </field>
            <field>
              <name>NACKIE</name>
              <bitOffset>4</bitOffset>
              <bitWidth>1</bitWidth>
            </field>
            <field>
              <name>STOPIE</name>
              <bitOffset>5</bitOffset>
              <bitWidth>1</bitWidth>
            </field>
            <field>
              <name>TCIE</name>
              <bitOffset>6</bitOffset>
              <bitWidth>1</bitWidth>
            </field>
            <field>
              <name>ERRIE</name>
              <bitOffset>7</bitOffset>
              <bitWidth>1</bitWidth>
            </field>
            <field>
              <name>DNF</name>
              <bitOffset>8</bitOffset>
              <bitWidth>4</bitWidth>
            </field>
            <field>
              <name>ANFOFF</name>
              <bitOffset>12</bitOffset>
              <bitWidth>1</bitWidth>
            </field>
            <field>
              <name>TXDMAEN</name>
              <bitOffset>14</bitOffset>
              <bitWidth>1</bitWidth>
            </field>
            <field>
              <name>RXDMAEN</name>
              <bitOffset>15</bitOffset>
              <bitWidth>1</bitWidth>
            </field>
            <field>
              <name>SBC</name>
              <bitOffset>16</bitOffset>
              <bitWidth>1</bitWidth>
            </field>
            <field>
              <name>NOSTRETCH</name>
              <bitOffset>17</bitOffset>
              <bitWidth>1</bitWidth>
            </field>
            <field>
              <name>WUPEN</name>
              <bitOffset>18</bitOffset>
              <bitWidth>1</bitWidth>
            </field>
            <field>
              <name>GCEN</name>
              <bitOffset>19</bitOffset>
              <bitWidth>1</bitWidth>
            </field>
            <field>
              <name>SMBHEN</name>
              <bitOffset>20</bitOffset>
              <bitWidth>1</bitWidth>
            </field>
            <field>
              <name>SMBDEN</name>
              <bitOffset>21</bitOffset>
              <bitWidth>1</bitWidth>
            </field>
            <field>
              <name>ALERTEN</name>
              <bitOffset>22</bitOffset>
              <bitWidth>1</bitWidth>
            </field>
            <field>
              <name>PECEN</name>
              <bitOffset>23</bitOffset>
              <bitWidth>1</bitWidth>
            </field>
          </fields>
        </register>
        <register>
          <name>CR2</name>
          <addressOffset>0x4</addressOffset>
          <size>0x20</size>
          <fields>
            <field>
              <name>SADD</name>
              <bitOffset>0</bitOffset>
              <bitWidth>10</bitWidth>
            </field>
            <field>
              <name>RD_WRN</name>
              <bitOffset>10</bitOffset>
              <bitWidth>1</bitWidth>
            </field>
            <field>
              <name>ADD10</name>
              <bitOffset>11</bitOffset>
              <bitWidth>1</bitWidth>
            </field>
            <field>
              <name>HEAD10R</name>
              <bitOffset>12</bitOffset>
              <bitWidth>1</bitWidth>
            </field>
            <field>
              <name>START</name>
              <bitOffset>13</bitOffset>
              <bitWidth>1</bitWidth>
            </field>
            <field>
              <name>STOP</name>
              <bitOffset>14</bitOffset>
              <bitWidth>1</bitWidth>
            </field>
            <field>
              <name>NACK</name>
              <bitOffset>15</bitOffset>
              <bitWidth>1</bitWidth>
            </field>
            <field>
              <name>NBYTES</name>
              <bitOffset>16</bitOffset>
              <bitWidth>8</bitWidth>
            </field>
            <field>
              <name>RELOAD</name>
              <bitOffset>24</bitOffset>
              <bitWidth>1</bitWidth>
            </field>
            <field>
              <name>AUTOEND</name>
              <bitOffset>25</bitOffset>
              <bitWidth>1</bitWidth>
            </field>
            <field>
              <name>PECBYTE</name>
              <bitOffset>26</bitOffset>
              <bitWidth>1</bitWidth>
            </field>
          </fields>
        </register>
        <register>
          <name>OAR1</name>
          <addressOffset>0x8</addressOffset>
          <size>0x20</size>
          <fields>
            <field>
              <name>OA1</name>
              <bitOffset>0</bitOffset>
              <bitWidth>10</bitWidth>
            </field>
            <field>
              <name>OA1MODE</name>
              <bitOffset>10</bitOffset>
              <bitWidth>1</bitWidth>
            </field>
            <field>
              <name>OA1EN</name>
              <bitOffset>15</bitOffset>
              <bitWidth>1</bitWidth>
            </field>
          </fields>
        </register>
        <register>
          <name>OAR2</name>
          <addressOffset>0xc</addressOffset>
          <size>0x20</size>
          <fields>
            <field>
              <name>OA2</name>
              <bitOffset>1</bitOffset>
              <bitWidth>7</bitWidth>
            </field>
            <field>
              <name>OA2MSK</name>
              <bitOffset>8</bitOffset>
              <bitWidth>3</bitWidth>
            </field>
            <field>
              <name>OA2MASK06</name>
              <bitOffset>9</bitOffset>
              <bitWidth>2</bitWidth>
            </field>
            <field>
              <name>OA2MASK04</name>
              <bitOffset>10</bitOffset>
              <bitWidth>1</bitWidth>
            </field>
            <field>
              <name>OA2EN</name>
              <bitOffset>15</bitOffset>
              <bitWidth>1</bitWidth>
            </field>
          </fields>
        </register>
        <register>
          <name>TIMINGR</name>
          <addressOffset>0x10</addressOffset>
          <size>0x20</size>
          <fields>
            <field>
              <name>SCLL</name>
              <bitOffset>0</bitOffset>
              <bitWidth>8</bitWidth>
            </field>
            <field>
              <name>SCLH</name>
              <bitOffset>8</bitOffset>
              <bitWidth>8</bitWidth>
            </field>
            <field>
              <name>SDADEL</name>
              <bitOffset>16</bitOffset>
              <bitWidth>4</bitWidth>
            </field>
            <field>
              <name>SCLDEL</name>
              <bitOffset>20</bitOffset>
              <bitWidth>4</bitWidth>
            </field>
            <field>
              <name>PRESC</name>
              <bitOffset>28</bitOffset>
              <bitWidth>4</bitWidth>
            </field>
          </fields>
        </register>
        <register>
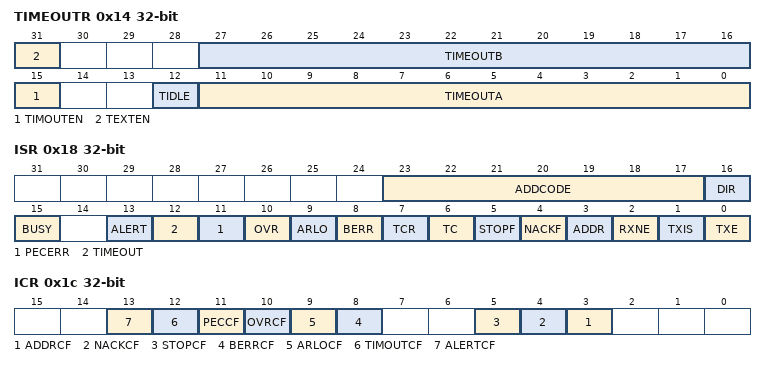
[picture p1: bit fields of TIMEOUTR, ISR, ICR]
          <name>TIMEOUTR</name>
          <addressOffset>0x14</addressOffset>
          <size>0x20</size>
          <fields>
            <field>
              <name>TIMEOUTA</name>
              <bitOffset>0</bitOffset>
              <bitWidth>12</bitWidth>
            </field>
            <field>
              <name>TIDLE</name>
              <bitOffset>12</bitOffset>
              <bitWidth>1</bitWidth>
            </field>
            <field>
              <name>TIMOUTEN</name>
              <bitOffset>15</bitOffset>
              <bitWidth>1</bitWidth>
            </field>
            <field>
              <name>TIMEOUTB</name>
              <bitOffset>16</bitOffset>
              <bitWidth>12</bitWidth>
            </field>
            <field>
              <name>TEXTEN</name>
              <bitOffset>31</bitOffset>
              <bitWidth>1</bitWidth>
            </field>
          </fields>
        </register>
        <register>
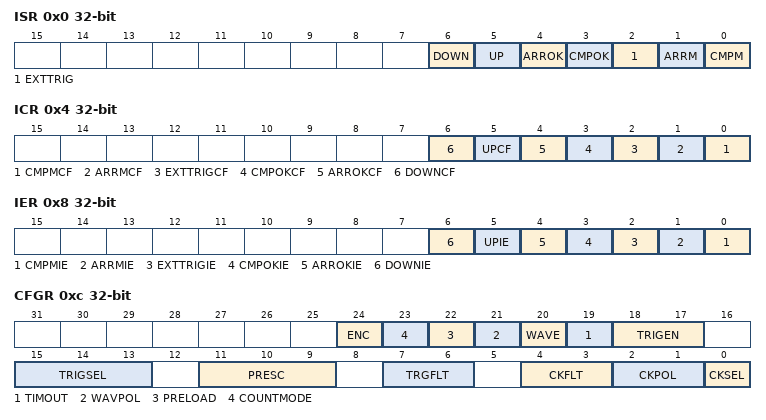
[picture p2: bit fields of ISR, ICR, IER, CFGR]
          <name>ISR</name>
          <addressOffset>0x18</addressOffset>
          <size>0x20</size>
          <fields>
            <field>
              <name>TXE</name>
              <bitOffset>0</bitOffset>
              <bitWidth>1</bitWidth>
            </field>
            <field>
              <name>TXIS</name>
              <bitOffset>1</bitOffset>
              <bitWidth>1</bitWidth>
            </field>
            <field>
              <name>RXNE</name>
              <bitOffset>2</bitOffset>
              <bitWidth>1</bitWidth>
            </field>
            <field>
              <name>ADDR</name>
              <bitOffset>3</bitOffset>
              <bitWidth>1</bitWidth>
            </field>
            <field>
              <name>NACKF</name>
              <bitOffset>4</bitOffset>
              <bitWidth>1</bitWidth>
            </field>
            <field>
              <name>STOPF</name>
              <bitOffset>5</bitOffset>
              <bitWidth>1</bitWidth>
            </field>
            <field>
              <name>TC</name>
              <bitOffset>6</bitOffset>
              <bitWidth>1</bitWidth>
            </field>
            <field>
              <name>TCR</name>
              <bitOffset>7</bitOffset>
              <bitWidth>1</bitWidth>
            </field>
            <field>
              <name>BERR</name>
              <bitOffset>8</bitOffset>
              <bitWidth>1</bitWidth>
            </field>
            <field>
              <name>ARLO</name>
              <bitOffset>9</bitOffset>
              <bitWidth>1</bitWidth>
            </field>
            <field>
              <name>OVR</name>
              <bitOffset>10</bitOffset>
              <bitWidth>1</bitWidth>
            </field>
            <field>
              <name>PECERR</name>
              <bitOffset>11</bitOffset>
              <bitWidth>1</bitWidth>
            </field>
            <field>
              <name>TIMEOUT</name>
              <bitOffset>12</bitOffset>
              <bitWidth>1</bitWidth>
            </field>
            <field>
              <name>ALERT</name>
              <bitOffset>13</bitOffset>
              <bitWidth>1</bitWidth>
            </field>
            <field>
              <name>BUSY</name>
              <bitOffset>15</bitOffset>
              <bitWidth>1</bitWidth>
            </field>
            <field>
              <name>DIR</name>
              <bitOffset>16</bitOffset>
              <bitWidth>1</bitWidth>
            </field>
            <field>
              <name>ADDCODE</name>
              <bitOffset>17</bitOffset>
              <bitWidth>7</bitWidth>
            </field>
          </fields>
        </register>
        <register>
          <name>ICR</name>
          <addressOffset>0x1c</addressOffset>
          <size>0x20</size>
          <fields>
            <field>
              <name>ADDRCF</name>
              <bitOffset>3</bitOffset>
              <bitWidth>1</bitWidth>
            </field>
            <field>
              <name>NACKCF</name>
              <bitOffset>4</bitOffset>
              <bitWidth>1</bitWidth>
            </field>
            <field>
              <name>STOPCF</name>
              <bitOffset>5</bitOffset>
              <bitWidth>1</bitWidth>
            </field>
            <field>
              <name>BERRCF</name>
              <bitOffset>8</bitOffset>
              <bitWidth>1</bitWidth>
            </field>
            <field>
              <name>ARLOCF</name>
              <bitOffset>9</bitOffset>
              <bitWidth>1</bitWidth>
            </field>
            <field>
              <name>OVRCF</name>
              <bitOffset>10</bitOffset>
              <bitWidth>1</bitWidth>
            </field>
            <field>
              <name>PECCF</name>
              <bitOffset>11</bitOffset>
              <bitWidth>1</bitWidth>
            </field>
            <field>
              <name>TIMOUTCF</name>
              <bitOffset>12</bitOffset>
              <bitWidth>1</bitWidth>
            </field>
            <field>
              <name>ALERTCF</name>
              <bitOffset>13</bitOffset>
              <bitWidth>1</bitWidth>
            </field>
          </fields>
        </register>
        <register>
          <name>PECR</name>
          <addressOffset>0x20</addressOffset>
          <size>0x20</size>
          <fields>
            <field>
              <name>PEC</name>
              <bitOffset>0</bitOffset>
              <bitWidth>8</bitWidth>
            </field>
          </fields>
        </register>
        <register>
          <name>RXDR</name>
          <addressOffset>0x24</addressOffset>
          <size>0x20</size>
          <fields>
            <field>
              <name>RXDATA</name>
              <bitOffset>0</bitOffset>
              <bitWidth>8</bitWidth>
            </field>
          </fields>
        </register>
        <register>
          <name>TXDR</name>
          <addressOffset>0x28</addressOffset>
          <size>0x20</size>
          <fields>
            <field>
              <name>TXDATA</name>
              <bitOffset>0</bitOffset>
              <bitWidth>8</bitWidth>
            </field>
          </fields>
        </register>
      </registers>
    </peripheral>
    <peripheral>
      <name>LPTIM2</name>
      <baseAddress>0x58002400</baseAddress>
      <registers>
        <register>
          <name>ISR</name>
          <addressOffset>0x0</addressOffset>
          <size>0x20</size>
          <fields>
            <field>
              <name>CMPM</name>
              <bitOffset>0</bitOffset>
              <bitWidth>1</bitWidth>
            </field>
            <field>
              <name>ARRM</name>
              <bitOffset>1</bitOffset>
              <bitWidth>1</bitWidth>
            </field>
            <field>
              <name>EXTTRIG</name>
              <bitOffset>2</bitOffset>
              <bitWidth>1</bitWidth>
            </field>
            <field>
              <name>CMPOK</name>
              <bitOffset>3</bitOffset>
              <bitWidth>1</bitWidth>
            </field>
            <field>
              <name>ARROK</name>
              <bitOffset>4</bitOffset>
              <bitWidth>1</bitWidth>
            </field>
            <field>
              <name>UP</name>
              <bitOffset>5</bitOffset>
              <bitWidth>1</bitWidth>
            </field>
            <field>
              <name>DOWN</name>
              <bitOffset>6</bitOffset>
              <bitWidth>1</bitWidth>
            </field>
          </fields>
        </register>
        <register>
          <name>ICR</name>
          <addressOffset>0x4</addressOffset>
          <size>0x20</size>
          <fields>
            <field>
              <name>CMPMCF</name>
              <bitOffset>0</bitOffset>
              <bitWidth>1</bitWidth>
            </field>
            <field>
              <name>ARRMCF</name>
              <bitOffset>1</bitOffset>
              <bitWidth>1</bitWidth>
            </field>
            <field>
              <name>EXTTRIGCF</name>
              <bitOffset>2</bitOffset>
              <bitWidth>1</bitWidth>
            </field>
            <field>
              <name>CMPOKCF</name>
              <bitOffset>3</bitOffset>
              <bitWidth>1</bitWidth>
            </field>
            <field>
              <name>ARROKCF</name>
              <bitOffset>4</bitOffset>
              <bitWidth>1</bitWidth>
            </field>
            <field>
              <name>UPCF</name>
              <bitOffset>5</bitOffset>
              <bitWidth>1</bitWidth>
            </field>
            <field>
              <name>DOWNCF</name>
              <bitOffset>6</bitOffset>
              <bitWidth>1</bitWidth>
            </field>
          </fields>
        </register>
        <register>
          <name>IER</name>
          <addressOffset>0x8</addressOffset>
          <size>0x20</size>
          <fields>
            <field>
              <name>CMPMIE</name>
              <bitOffset>0</bitOffset>
              <bitWidth>1</bitWidth>
            </field>
            <field>
              <name>ARRMIE</name>
              <bitOffset>1</bitOffset>
              <bitWidth>1</bitWidth>
            </field>
            <field>
              <name>EXTTRIGIE</name>
              <bitOffset>2</bitOffset>
              <bitWidth>1</bitWidth>
            </field>
            <field>
              <name>CMPOKIE</name>
              <bitOffset>3</bitOffset>
              <bitWidth>1</bitWidth>
            </field>
            <field>
              <name>ARROKIE</name>
              <bitOffset>4</bitOffset>
              <bitWidth>1</bitWidth>
            </field>
            <field>
              <name>UPIE</name>
              <bitOffset>5</bitOffset>
              <bitWidth>1</bitWidth>
            </field>
            <field>
              <name>DOWNIE</name>
              <bitOffset>6</bitOffset>
              <bitWidth>1</bitWidth>
            </field>
          </fields>
        </register>
        <register>
          <name>CFGR</name>
          <addressOffset>0xc</addressOffset>
          <size>0x20</size>
          <fields>
            <field>
              <name>CKSEL</name>
              <bitOffset>0</bitOffset>
              <bitWidth>1</bitWidth>
            </field>
            <field>
              <name>CKPOL</name>
              <bitOffset>1</bitOffset>
              <bitWidth>2</bitWidth>
            </field>
            <field>
              <name>CKFLT</name>
              <bitOffset>3</bitOffset>
              <bitWidth>2</bitWidth>
            </field>
            <field>
              <name>TRGFLT</name>
              <bitOffset>6</bitOffset>
              <bitWidth>2</bitWidth>
            </field>
            <field>
              <name>PRESC</name>
              <bitOffset>9</bitOffset>
              <bitWidth>3</bitWidth>
            </field>
            <field>
              <name>TRIGSEL</name>
              <bitOffset>13</bitOffset>
              <bitWidth>3</bitWidth>
            </field>
            <field>
              <name>TRIGEN</name>
              <bitOffset>17</bitOffset>
              <bitWidth>2</bitWidth>
            </field>
            <field>
              <name>TIMOUT</name>
              <bitOffset>19</bitOffset>
              <bitWidth>1</bitWidth>
            </field>
            <field>
              <name>WAVE</name>
              <bitOffset>20</bitOffset>
              <bitWidth>1</bitWidth>
            </field>
            <field>
              <name>WAVPOL</name>
              <bitOffset>21</bitOffset>
              <bitWidth>1</bitWidth>
            </field>
            <field>
              <name>PRELOAD</name>
              <bitOffset>22</bitOffset>
              <bitWidth>1</bitWidth>
            </field>
            <field>
              <name>COUNTMODE</name>
              <bitOffset>23</bitOffset>
              <bitWidth>1</bitWidth>
            </field>
            <field>
              <name>ENC</name>
              <bitOffset>24</bitOffset>
              <bitWidth>1</bitWidth>
            </field>
          </fields>
        </register>
        <register>
          <name>CR</name>
          <addressOffset>0x10</addressOffset>
          <size>0x20</size>
          <fields>
            <field>
              <name>ENABLE</name>
              <bitOffset>0</bitOffset>
              <bitWidth>1</bitWidth>
            </field>
            <field>
              <name>SNGSTRT</name>
              <bitOffset>1</bitOffset>
              <bitWidth>19</bitWidth>
            </field>
            <field>
              <name>CNTSTRT</name>
              <bitOffset>2</bitOffset>
              <bitWidth>1</bitWidth>
            </field>
            <field>
              <name>COUNTRST</name>
              <bitOffset>3</bitOffset>
              <bitWidth>1</bitWidth>
            </field>
            <field>
              <name>RSTARE</name>
              <bitOffset>4</bitOffset>
              <bitWidth>1</bitWidth>
            </field>
          </fields>
        </register>
        <register>
          <name>CMP</name>
          <addressOffset>0x14</addressOffset>
          <size>0x20</size>
          <fields>
            <field>
              <name>CMP</name>
              <bitOffset>0</bitOffset>
              <bitWidth>16</bitWidth>
            </field>
          </fields>
        </register>
        <register>
          <name>ARR</name>
          <addressOffset>0x18</addressOffset>
          <size>0x20</size>
          <fields>
            <field>
              <name>ARR</name>
              <bitOffset>0</bitOffset>
              <bitWidth>16</bitWidth>
            </field>
          </fields>
        </register>
        <register>
          <name>CNT</name>
          <addressOffset>0x1c</addressOffset>
          <size>0x20</size>
          <fields>
            <field>
              <name>CNT</name>
              <bitOffset>0</bitOffset>
              <bitWidth>16</bitWidth>
            </field>
          </fields>
        </register>
        <register>
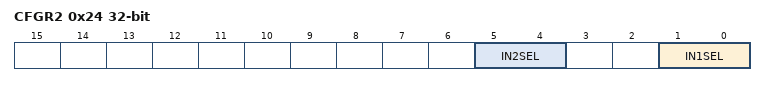
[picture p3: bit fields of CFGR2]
          <name>CFGR2</name>
          <addressOffset>0x24</addressOffset>
          <size>0x20</size>
          <fields>
            <field>
              <name>IN1SEL</name>
              <bitOffset>0</bitOffset>
              <bitWidth>2</bitWidth>
            </field>
            <field>
              <name>IN2SEL</name>
              <bitOffset>4</bitOffset>
              <bitWidth>2</bitWidth>
            </field>
          </fields>
        </register>
      </registers>
    </peripheral>
    <peripheral>
      <name>LPTIM3</name>
      <baseAddress>0x58002800</baseAddress>
      <registers>
        <register>
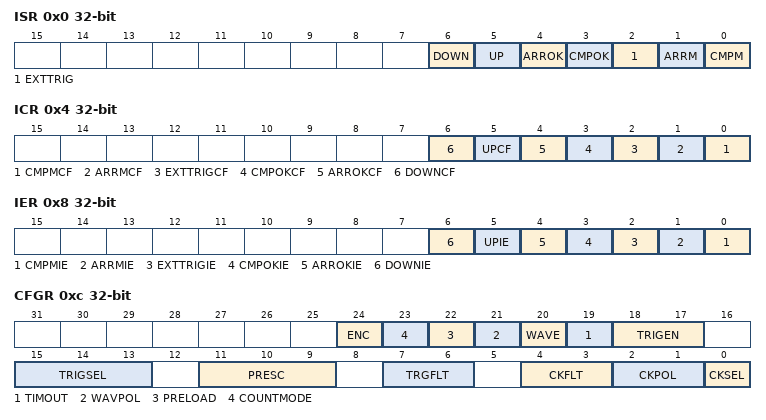
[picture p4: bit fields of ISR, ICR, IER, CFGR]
          <name>ISR</name>
          <addressOffset>0x0</addressOffset>
          <size>0x20</size>
          <fields>
            <field>
              <name>CMPM</name>
              <bitOffset>0</bitOffset>
              <bitWidth>1</bitWidth>
            </field>
            <field>
              <name>ARRM</name>
              <bitOffset>1</bitOffset>
              <bitWidth>1</bitWidth>
            </field>
            <field>
              <name>EXTTRIG</name>
              <bitOffset>2</bitOffset>
              <bitWidth>1</bitWidth>
            </field>
            <field>
              <name>CMPOK</name>
              <bitOffset>3</bitOffset>
              <bitWidth>1</bitWidth>
            </field>
            <field>
              <name>ARROK</name>
              <bitOffset>4</bitOffset>
              <bitWidth>1</bitWidth>
            </field>
            <field>
              <name>UP</name>
              <bitOffset>5</bitOffset>
              <bitWidth>1</bitWidth>
            </field>
            <field>
              <name>DOWN</name>
              <bitOffset>6</bitOffset>
              <bitWidth>1</bitWidth>
            </field>
          </fields>
        </register>
        <register>
          <name>ICR</name>
          <addressOffset>0x4</addressOffset>
          <size>0x20</size>
          <fields>
            <field>
              <name>CMPMCF</name>
              <bitOffset>0</bitOffset>
              <bitWidth>1</bitWidth>
            </field>
            <field>
              <name>ARRMCF</name>
              <bitOffset>1</bitOffset>
              <bitWidth>1</bitWidth>
            </field>
            <field>
              <name>EXTTRIGCF</name>
              <bitOffset>2</bitOffset>
              <bitWidth>1</bitWidth>
            </field>
            <field>
              <name>CMPOKCF</name>
              <bitOffset>3</bitOffset>
              <bitWidth>1</bitWidth>
            </field>
            <field>
              <name>ARROKCF</name>
              <bitOffset>4</bitOffset>
              <bitWidth>1</bitWidth>
            </field>
            <field>
              <name>UPCF</name>
              <bitOffset>5</bitOffset>
              <bitWidth>1</bitWidth>
            </field>
            <field>
              <name>DOWNCF</name>
              <bitOffset>6</bitOffset>
              <bitWidth>1</bitWidth>
            </field>
          </fields>
        </register>
        <register>
          <name>IER</name>
          <addressOffset>0x8</addressOffset>
          <size>0x20</size>
          <fields>
            <field>
              <name>CMPMIE</name>
              <bitOffset>0</bitOffset>
              <bitWidth>1</bitWidth>
            </field>
            <field>
              <name>ARRMIE</name>
              <bitOffset>1</bitOffset>
              <bitWidth>1</bitWidth>
            </field>
            <field>
              <name>EXTTRIGIE</name>
              <bitOffset>2</bitOffset>
              <bitWidth>1</bitWidth>
            </field>
            <field>
              <name>CMPOKIE</name>
              <bitOffset>3</bitOffset>
              <bitWidth>1</bitWidth>
            </field>
            <field>
              <name>ARROKIE</name>
              <bitOffset>4</bitOffset>
              <bitWidth>1</bitWidth>
            </field>
            <field>
              <name>UPIE</name>
              <bitOffset>5</bitOffset>
              <bitWidth>1</bitWidth>
            </field>
            <field>
              <name>DOWNIE</name>
              <bitOffset>6</bitOffset>
              <bitWidth>1</bitWidth>
            </field>
          </fields>
        </register>
        <register>
          <name>CFGR</name>
          <addressOffset>0xc</addressOffset>
          <size>0x20</size>
          <fields>
            <field>
              <name>CKSEL</name>
              <bitOffset>0</bitOffset>
              <bitWidth>1</bitWidth>
            </field>
            <field>
              <name>CKPOL</name>
              <bitOffset>1</bitOffset>
              <bitWidth>2</bitWidth>
            </field>
            <field>
              <name>CKFLT</name>
              <bitOffset>3</bitOffset>
              <bitWidth>2</bitWidth>
            </field>
            <field>
              <name>TRGFLT</name>
              <bitOffset>6</bitOffset>
              <bitWidth>2</bitWidth>
            </field>
            <field>
              <name>PRESC</name>
              <bitOffset>9</bitOffset>
              <bitWidth>3</bitWidth>
            </field>
            <field>
              <name>TRIGSEL</name>
              <bitOffset>13</bitOffset>
              <bitWidth>3</bitWidth>
            </field>
            <field>
              <name>TRIGEN</name>
              <bitOffset>17</bitOffset>
              <bitWidth>2</bitWidth>
            </field>
            <field>
              <name>TIMOUT</name>
              <bitOffset>19</bitOffset>
              <bitWidth>1</bitWidth>
            </field>
            <field>
              <name>WAVE</name>
              <bitOffset>20</bitOffset>
              <bitWidth>1</bitWidth>
            </field>
            <field>
              <name>WAVPOL</name>
              <bitOffset>21</bitOffset>
              <bitWidth>1</bitWidth>
            </field>
            <field>
              <name>PRELOAD</name>
              <bitOffset>22</bitOffset>
              <bitWidth>1</bitWidth>
            </field>
            <field>
              <name>COUNTMODE</name>
              <bitOffset>23</bitOffset>
              <bitWidth>1</bitWidth>
            </field>
            <field>
              <name>ENC</name>
              <bitOffset>24</bitOffset>
              <bitWidth>1</bitWidth>
            </field>
          </fields>
        </register>
        <register>
          <name>CR</name>
          <addressOffset>0x10</addressOffset>
          <size>0x20</size>
          <fields>
            <field>
              <name>ENABLE</name>
              <bitOffset>0</bitOffset>
              <bitWidth>1</bitWidth>
            </field>
            <field>
              <name>SNGSTRT</name>
              <bitOffset>1</bitOffset>
              <bitWidth>19</bitWidth>
            </field>
            <field>
              <name>CNTSTRT</name>
              <bitOffset>2</bitOffset>
              <bitWidth>1</bitWidth>
            </field>
            <field>
              <name>COUNTRST</name>
              <bitOffset>3</bitOffset>
              <bitWidth>1</bitWidth>
            </field>
            <field>
              <name>RSTARE</name>
              <bitOffset>4</bitOffset>
              <bitWidth>1</bitWidth>
            </field>
          </fields>
        </register>
        <register>
          <name>CMP</name>
          <addressOffset>0x14</addressOffset>
          <size>0x20</size>
          <fields>
            <field>
              <name>CMP</name>
              <bitOffset>0</bitOffset>
              <bitWidth>16</bitWidth>
            </field>
          </fields>
        </register>
        <register>
          <name>ARR</name>
          <addressOffset>0x18</addressOffset>
          <size>0x20</size>
          <fields>
            <field>
              <name>ARR</name>
              <bitOffset>0</bitOffset>
              <bitWidth>16</bitWidth>
            </field>
          </fields>
        </register>
        <register>
          <name>CNT</name>
          <addressOffset>0x1c</addressOffset>
          <size>0x20</size>
          <fields>
            <field>
              <name>CNT</name>
              <bitOffset>0</bitOffset>
              <bitWidth>16</bitWidth>
            </field>
          </fields>
        </register>
        <register>
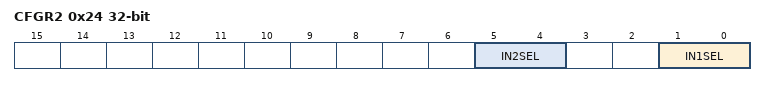
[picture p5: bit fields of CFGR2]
          <name>CFGR2</name>
          <addressOffset>0x24</addressOffset>
          <size>0x20</size>
          <fields>
            <field>
              <name>IN1SEL</name>
              <bitOffset>0</bitOffset>
              <bitWidth>2</bitWidth>
            </field>
            <field>
              <name>IN2SEL</name>
              <bitOffset>4</bitOffset>
              <bitWidth>2</bitWidth>
            </field>
          </fields>
        </register>
      </registers>
    </peripheral>
    <peripheral>
      <name>LPTIM4</name>
      <baseAddress>0x58002c00</baseAddress>
      <registers>
        <register>
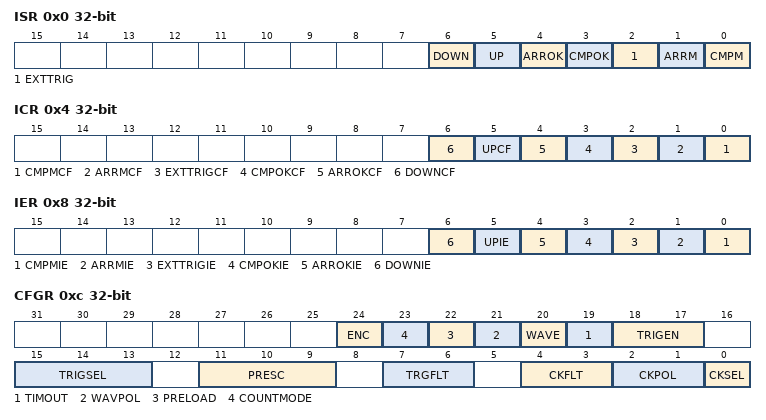
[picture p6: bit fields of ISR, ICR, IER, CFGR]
          <name>ISR</name>
          <addressOffset>0x0</addressOffset>
          <size>0x20</size>
          <fields>
            <field>
              <name>CMPM</name>
              <bitOffset>0</bitOffset>
              <bitWidth>1</bitWidth>
            </field>
            <field>
              <name>ARRM</name>
              <bitOffset>1</bitOffset>
              <bitWidth>1</bitWidth>
            </field>
            <field>
              <name>EXTTRIG</name>
              <bitOffset>2</bitOffset>
              <bitWidth>1</bitWidth>
            </field>
            <field>
              <name>CMPOK</name>
              <bitOffset>3</bitOffset>
              <bitWidth>1</bitWidth>
            </field>
            <field>
              <name>ARROK</name>
              <bitOffset>4</bitOffset>
              <bitWidth>1</bitWidth>
            </field>
            <field>
              <name>UP</name>
              <bitOffset>5</bitOffset>
              <bitWidth>1</bitWidth>
            </field>
            <field>
              <name>DOWN</name>
              <bitOffset>6</bitOffset>
              <bitWidth>1</bitWidth>
            </field>
          </fields>
        </register>
        <register>
          <name>ICR</name>
          <addressOffset>0x4</addressOffset>
          <size>0x20</size>
          <fields>
            <field>
              <name>CMPMCF</name>
              <bitOffset>0</bitOffset>
              <bitWidth>1</bitWidth>
            </field>
            <field>
              <name>ARRMCF</name>
              <bitOffset>1</bitOffset>
              <bitWidth>1</bitWidth>
            </field>
            <field>
              <name>EXTTRIGCF</name>
              <bitOffset>2</bitOffset>
              <bitWidth>1</bitWidth>
            </field>
            <field>
              <name>CMPOKCF</name>
              <bitOffset>3</bitOffset>
              <bitWidth>1</bitWidth>
            </field>
            <field>
              <name>ARROKCF</name>
              <bitOffset>4</bitOffset>
              <bitWidth>1</bitWidth>
            </field>
            <field>
              <name>UPCF</name>
              <bitOffset>5</bitOffset>
              <bitWidth>1</bitWidth>
            </field>
            <field>
              <name>DOWNCF</name>
              <bitOffset>6</bitOffset>
              <bitWidth>1</bitWidth>
            </field>
          </fields>
        </register>
        <register>
          <name>IER</name>
          <addressOffset>0x8</addressOffset>
          <size>0x20</size>
          <fields>
            <field>
              <name>CMPMIE</name>
              <bitOffset>0</bitOffset>
              <bitWidth>1</bitWidth>
            </field>
            <field>
              <name>ARRMIE</name>
              <bitOffset>1</bitOffset>
              <bitWidth>1</bitWidth>
            </field>
            <field>
              <name>EXTTRIGIE</name>
              <bitOffset>2</bitOffset>
              <bitWidth>1</bitWidth>
            </field>
            <field>
              <name>CMPOKIE</name>
              <bitOffset>3</bitOffset>
              <bitWidth>1</bitWidth>
            </field>
            <field>
              <name>ARROKIE</name>
              <bitOffset>4</bitOffset>
              <bitWidth>1</bitWidth>
            </field>
            <field>
              <name>UPIE</name>
              <bitOffset>5</bitOffset>
              <bitWidth>1</bitWidth>
            </field>
            <field>
              <name>DOWNIE</name>
              <bitOffset>6</bitOffset>
              <bitWidth>1</bitWidth>
            </field>
          </fields>
        </register>
        <register>
          <name>CFGR</name>
          <addressOffset>0xc</addressOffset>
          <size>0x20</size>
          <fields>
            <field>
              <name>CKSEL</name>
              <bitOffset>0</bitOffset>
              <bitWidth>1</bitWidth>
            </field>
            <field>
              <name>CKPOL</name>
              <bitOffset>1</bitOffset>
              <bitWidth>2</bitWidth>
            </field>
            <field>
              <name>CKFLT</name>
              <bitOffset>3</bitOffset>
              <bitWidth>2</bitWidth>
            </field>
            <field>
              <name>TRGFLT</name>
              <bitOffset>6</bitOffset>
              <bitWidth>2</bitWidth>
            </field>
            <field>
              <name>PRESC</name>
              <bitOffset>9</bitOffset>
              <bitWidth>3</bitWidth>
            </field>
            <field>
              <name>TRIGSEL</name>
              <bitOffset>13</bitOffset>
              <bitWidth>3</bitWidth>
            </field>
            <field>
              <name>TRIGEN</name>
              <bitOffset>17</bitOffset>
              <bitWidth>2</bitWidth>
            </field>
            <field>
              <name>TIMOUT</name>
              <bitOffset>19</bitOffset>
              <bitWidth>1</bitWidth>
            </field>
            <field>
              <name>WAVE</name>
              <bitOffset>20</bitOffset>
              <bitWidth>1</bitWidth>
            </field>
            <field>
              <name>WAVPOL</name>
              <bitOffset>21</bitOffset>
              <bitWidth>1</bitWidth>
            </field>
            <field>
              <name>PRELOAD</name>
              <bitOffset>22</bitOffset>
              <bitWidth>1</bitWidth>
            </field>
            <field>
              <name>COUNTMODE</name>
              <bitOffset>23</bitOffset>
              <bitWidth>1</bitWidth>
            </field>
            <field>
              <name>ENC</name>
              <bitOffset>24</bitOffset>
              <bitWidth>1</bitWidth>
            </field>
          </fields>
        </register>
        <register>
          <name>CR</name>
          <addressOffset>0x10</addressOffset>
          <size>0x20</size>
          <fields>
            <field>
              <name>ENABLE</name>
              <bitOffset>0</bitOffset>
              <bitWidth>1</bitWidth>
            </field>
            <field>
              <name>SNGSTRT</name>
              <bitOffset>1</bitOffset>
              <bitWidth>19</bitWidth>
            </field>
            <field>
              <name>CNTSTRT</name>
              <bitOffset>2</bitOffset>
              <bitWidth>1</bitWidth>
            </field>
            <field>
              <name>COUNTRST</name>
              <bitOffset>3</bitOffset>
              <bitWidth>1</bitWidth>
            </field>
            <field>
              <name>RSTARE</name>
              <bitOffset>4</bitOffset>
              <bitWidth>1</bitWidth>
            </field>
          </fields>
        </register>
        <register>
          <name>CMP</name>
          <addressOffset>0x14</addressOffset>
          <size>0x20</size>
          <fields>
            <field>
              <name>CMP</name>
              <bitOffset>0</bitOffset>
              <bitWidth>16</bitWidth>
            </field>
          </fields>
        </register>
        <register>
          <name>ARR</name>
          <addressOffset>0x18</addressOffset>
          <size>0x20</size>
          <fields>
            <field>
              <name>ARR</name>
              <bitOffset>0</bitOffset>
              <bitWidth>16</bitWidth>
            </field>
          </fields>
        </register>
        <register>
          <name>CNT</name>
          <addressOffset>0x1c</addressOffset>
          <size>0x20</size>
          <fields>
            <field>
              <name>CNT</name>
              <bitOffset>0</bitOffset>
              <bitWidth>16</bitWidth>
            </field>
          </fields>
        </register>
        <register>
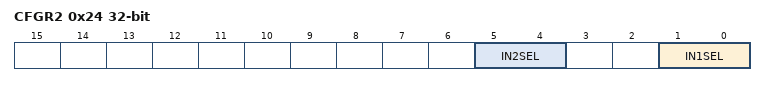
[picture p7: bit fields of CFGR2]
          <name>CFGR2</name>
          <addressOffset>0x24</addressOffset>
          <size>0x20</size>
          <fields>
            <field>
              <name>IN1SEL</name>
              <bitOffset>0</bitOffset>
              <bitWidth>2</bitWidth>
            </field>
            <field>
              <name>IN2SEL</name>
              <bitOffset>4</bitOffset>
              <bitWidth>2</bitWidth>
            </field>
          </fields>
        </register>
      </registers>
    </peripheral>
    <peripheral>
      <name>LPTIM5</name>
      <baseAddress>0x58003000</baseAddress>
      <registers>
        <register>
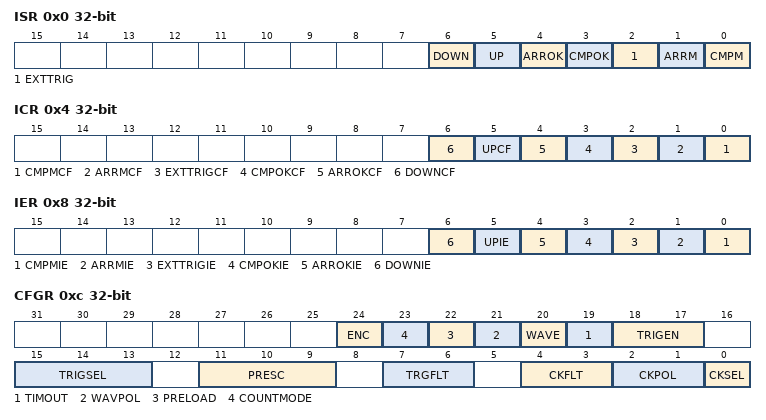
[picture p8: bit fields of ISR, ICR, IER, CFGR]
          <name>ISR</name>
          <addressOffset>0x0</addressOffset>
          <size>0x20</size>
          <fields>
            <field>
              <name>CMPM</name>
              <bitOffset>0</bitOffset>
              <bitWidth>1</bitWidth>
            </field>
            <field>
              <name>ARRM</name>
              <bitOffset>1</bitOffset>
              <bitWidth>1</bitWidth>
            </field>
            <field>
              <name>EXTTRIG</name>
              <bitOffset>2</bitOffset>
              <bitWidth>1</bitWidth>
            </field>
            <field>
              <name>CMPOK</name>
              <bitOffset>3</bitOffset>
              <bitWidth>1</bitWidth>
            </field>
            <field>
              <name>ARROK</name>
              <bitOffset>4</bitOffset>
              <bitWidth>1</bitWidth>
            </field>
            <field>
              <name>UP</name>
              <bitOffset>5</bitOffset>
              <bitWidth>1</bitWidth>
            </field>
            <field>
              <name>DOWN</name>
              <bitOffset>6</bitOffset>
              <bitWidth>1</bitWidth>
            </field>
          </fields>
        </register>
        <register>
          <name>ICR</name>
          <addressOffset>0x4</addressOffset>
          <size>0x20</size>
          <fields>
            <field>
              <name>CMPMCF</name>
              <bitOffset>0</bitOffset>
              <bitWidth>1</bitWidth>
            </field>
            <field>
              <name>ARRMCF</name>
              <bitOffset>1</bitOffset>
              <bitWidth>1</bitWidth>
            </field>
            <field>
              <name>EXTTRIGCF</name>
              <bitOffset>2</bitOffset>
              <bitWidth>1</bitWidth>
            </field>
            <field>
              <name>CMPOKCF</name>
              <bitOffset>3</bitOffset>
              <bitWidth>1</bitWidth>
            </field>
            <field>
              <name>ARROKCF</name>
              <bitOffset>4</bitOffset>
              <bitWidth>1</bitWidth>
            </field>
            <field>
              <name>UPCF</name>
              <bitOffset>5</bitOffset>
              <bitWidth>1</bitWidth>
            </field>
            <field>
              <name>DOWNCF</name>
              <bitOffset>6</bitOffset>
              <bitWidth>1</bitWidth>
            </field>
          </fields>
        </register>
        <register>
          <name>IER</name>
          <addressOffset>0x8</addressOffset>
          <size>0x20</size>
          <fields>
            <field>
              <name>CMPMIE</name>
              <bitOffset>0</bitOffset>
              <bitWidth>1</bitWidth>
            </field>
            <field>
              <name>ARRMIE</name>
              <bitOffset>1</bitOffset>
              <bitWidth>1</bitWidth>
            </field>
            <field>
              <name>EXTTRIGIE</name>
              <bitOffset>2</bitOffset>
              <bitWidth>1</bitWidth>
            </field>
            <field>
              <name>CMPOKIE</name>
              <bitOffset>3</bitOffset>
              <bitWidth>1</bitWidth>
            </field>
            <field>
              <name>ARROKIE</name>
              <bitOffset>4</bitOffset>
              <bitWidth>1</bitWidth>
            </field>
            <field>
              <name>UPIE</name>
              <bitOffset>5</bitOffset>
              <bitWidth>1</bitWidth>
            </field>
            <field>
              <name>DOWNIE</name>
              <bitOffset>6</bitOffset>
              <bitWidth>1</bitWidth>
            </field>
          </fields>
        </register>
        <register>
          <name>CFGR</name>
          <addressOffset>0xc</addressOffset>
          <size>0x20</size>
          <fields>
            <field>
              <name>CKSEL</name>
              <bitOffset>0</bitOffset>
              <bitWidth>1</bitWidth>
            </field>
            <field>
              <name>CKPOL</name>
              <bitOffset>1</bitOffset>
              <bitWidth>2</bitWidth>
            </field>
            <field>
              <name>CKFLT</name>
              <bitOffset>3</bitOffset>
              <bitWidth>2</bitWidth>
            </field>
            <field>
              <name>TRGFLT</name>
              <bitOffset>6</bitOffset>
              <bitWidth>2</bitWidth>
            </field>
            <field>
              <name>PRESC</name>
              <bitOffset>9</bitOffset>
              <bitWidth>3</bitWidth>
            </field>
            <field>
              <name>TRIGSEL</name>
              <bitOffset>13</bitOffset>
              <bitWidth>3</bitWidth>
            </field>
            <field>
              <name>TRIGEN</name>
              <bitOffset>17</bitOffset>
              <bitWidth>2</bitWidth>
            </field>
            <field>
              <name>TIMOUT</name>
              <bitOffset>19</bitOffset>
              <bitWidth>1</bitWidth>
            </field>
            <field>
              <name>WAVE</name>
              <bitOffset>20</bitOffset>
              <bitWidth>1</bitWidth>
            </field>
            <field>
              <name>WAVPOL</name>
              <bitOffset>21</bitOffset>
              <bitWidth>1</bitWidth>
            </field>
            <field>
              <name>PRELOAD</name>
              <bitOffset>22</bitOffset>
              <bitWidth>1</bitWidth>
            </field>
            <field>
              <name>COUNTMODE</name>
              <bitOffset>23</bitOffset>
              <bitWidth>1</bitWidth>
            </field>
            <field>
              <name>ENC</name>
              <bitOffset>24</bitOffset>
              <bitWidth>1</bitWidth>
            </field>
          </fields>
        </register>
        <register>
          <name>CR</name>
          <addressOffset>0x10</addressOffset>
          <size>0x20</size>
          <fields>
            <field>
              <name>ENABLE</name>
              <bitOffset>0</bitOffset>
              <bitWidth>1</bitWidth>
            </field>
            <field>
              <name>SNGSTRT</name>
              <bitOffset>1</bitOffset>
              <bitWidth>19</bitWidth>
            </field>
            <field>
              <name>CNTSTRT</name>
              <bitOffset>2</bitOffset>
              <bitWidth>1</bitWidth>
            </field>
            <field>
              <name>COUNTRST</name>
              <bitOffset>3</bitOffset>
              <bitWidth>1</bitWidth>
            </field>
            <field>
              <name>RSTARE</name>
              <bitOffset>4</bitOffset>
              <bitWidth>1</bitWidth>
            </field>
          </fields>
        </register>
        <register>
          <name>CMP</name>
          <addressOffset>0x14</addressOffset>
          <size>0x20</size>
          <fields>
            <field>
              <name>CMP</name>
              <bitOffset>0</bitOffset>
              <bitWidth>16</bitWidth>
            </field>
          </fields>
        </register>
        <register>
          <name>ARR</name>
          <addressOffset>0x18</addressOffset>
          <size>0x20</size>
          <fields>
            <field>
              <name>ARR</name>
              <bitOffset>0</bitOffset>
              <bitWidth>16</bitWidth>
            </field>
          </fields>
        </register>
        <register>
          <name>CNT</name>
          <addressOffset>0x1c</addressOffset>
          <size>0x20</size>
          <fields>
            <field>
              <name>CNT</name>
              <bitOffset>0</bitOffset>
              <bitWidth>16</bitWidth>
            </field>
          </fields>
        </register>
        <register>
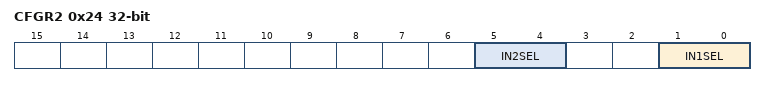
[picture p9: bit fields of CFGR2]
          <name>CFGR2</name>
          <addressOffset>0x24</addressOffset>
          <size>0x20</size>
          <fields>
            <field>
              <name>IN1SEL</name>
              <bitOffset>0</bitOffset>
              <bitWidth>2</bitWidth>
            </field>
            <field>
              <name>IN2SEL</name>
              <bitOffset>4</bitOffset>
              <bitWidth>2</bitWidth>
            </field>
          </fields>
        </register>
      </registers>
    </peripheral>
    <peripheral>
      <name>COMP12</name>
      <baseAddress>0x58003800</baseAddress>
      <registers>
        <register>
          <name>SR</name>
          <addressOffset>0x0</addressOffset>
          <size>0x20</size>
        </register>
        <register>
          <name>ICFR</name>
          <addressOffset>0x4</addressOffset>
          <size>0x20</size>
        </register>
        <register>
          <name>OR</name>
          <addressOffset>0x8</addressOffset>
          <size>0x20</size>
        </register>
      </registers>
    </peripheral>
    <peripheral>
      <name>COMP1</name>
      <baseAddress>0x5800380c</baseAddress>
      <registers>
        <register>
          <name>CFGR</name>
          <addressOffset>0x0</addressOffset>
          <size>0x20</size>
        </register>
      </registers>
    </peripheral>
    <peripheral>
      <name>COMP2</name>
      <baseAddress>0x58003810</baseAddress>
      <registers>
        <register>
          <name>CFGR</name>
          <addressOffset>0x0</addressOffset>
          <size>0x20</size>
        </register>
      </registers>
    </peripheral>
    <peripheral>
      <name>COMP12_COMMON</name>
      <baseAddress>0x58003810</baseAddress>
      <registers>
        <register>
          <name>CFGR</name>
          <addressOffset>0x0</addressOffset>
          <size>0x20</size>
        </register>
      </registers>
    </peripheral>
    <peripheral>
      <name>VREFBUF</name>
      <baseAddress>0x58003c00</baseAddress>
      <registers>
        <register>
          <name>CSR</name>
          <addressOffset>0x0</addressOffset>
          <size>0x20</size>
          <fields>
            <field>
              <name>ENVR</name>
              <bitOffset>0</bitOffset>
              <bitWidth>1</bitWidth>
            </field>
            <field>
              <name>HIZ</name>
              <bitOffset>1</bitOffset>
              <bitWidth>1</bitWidth>
            </field>
            <field>
              <name>VRR</name>
              <bitOffset>3</bitOffset>
              <bitWidth>1</bitWidth>
            </field>
            <field>
              <name>VRS_OUT4</name>
              <bitOffset>4</bitOffset>
              <bitWidth>2</bitWidth>
            </field>
            <field>
              <name>VRS_OUT3</name>
              <bitOffset>5</bitOffset>
              <bitWidth>1</bitWidth>
            </field>
          </fields>
        </register>
        <register>
          <name>CCR</name>
          <addressOffset>0x4</addressOffset>
          <size>0x20</size>
          <fields>
            <field>
              <name>TRIM</name>
              <bitOffset>0</bitOffset>
              <bitWidth>6</bitWidth>
            </field>
          </fields>
        </register>
      </registers>
    </peripheral>
    <peripheral>
      <name>RTC</name>
      <baseAddress>0x58004000</baseAddress>
      <registers>
        <register>
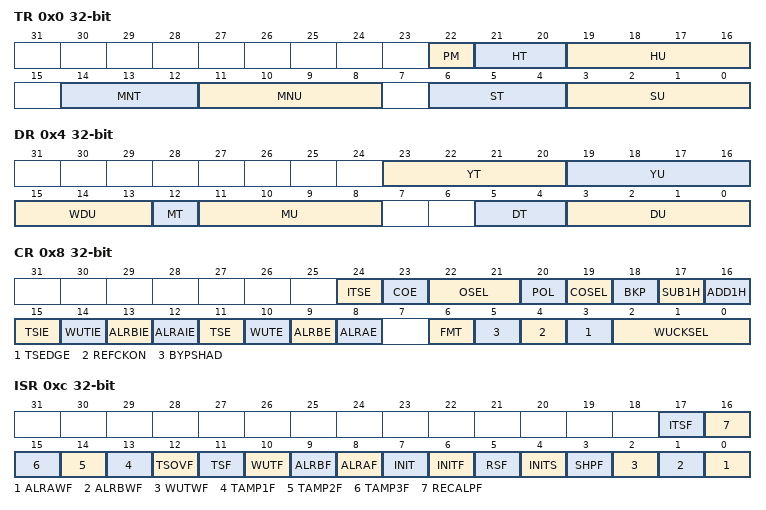
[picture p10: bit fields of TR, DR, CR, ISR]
          <name>TR</name>
          <addressOffset>0x0</addressOffset>
          <size>0x20</size>
          <fields>
            <field>
              <name>SU</name>
              <bitOffset>0</bitOffset>
              <bitWidth>4</bitWidth>
            </field>
            <field>
              <name>ST</name>
              <bitOffset>4</bitOffset>
              <bitWidth>3</bitWidth>
            </field>
            <field>
              <name>MNU</name>
              <bitOffset>8</bitOffset>
              <bitWidth>4</bitWidth>
            </field>
            <field>
              <name>MNT</name>
              <bitOffset>12</bitOffset>
              <bitWidth>3</bitWidth>
            </field>
            <field>
              <name>HU</name>
              <bitOffset>16</bitOffset>
              <bitWidth>4</bitWidth>
            </field>
            <field>
              <name>HT</name>
              <bitOffset>20</bitOffset>
              <bitWidth>2</bitWidth>
            </field>
            <field>
              <name>PM</name>
              <bitOffset>22</bitOffset>
              <bitWidth>1</bitWidth>
            </field>
          </fields>
        </register>
        <register>
          <name>DR</name>
          <addressOffset>0x4</addressOffset>
          <size>0x20</size>
          <fields>
            <field>
              <name>DU</name>
              <bitOffset>0</bitOffset>
              <bitWidth>4</bitWidth>
            </field>
            <field>
              <name>DT</name>
              <bitOffset>4</bitOffset>
              <bitWidth>2</bitWidth>
            </field>
            <field>
              <name>MU</name>
              <bitOffset>8</bitOffset>
              <bitWidth>4</bitWidth>
            </field>
            <field>
              <name>MT</name>
              <bitOffset>12</bitOffset>
              <bitWidth>1</bitWidth>
            </field>
            <field>
              <name>WDU</name>
              <bitOffset>13</bitOffset>
              <bitWidth>3</bitWidth>
            </field>
            <field>
              <name>YU</name>
              <bitOffset>16</bitOffset>
              <bitWidth>4</bitWidth>
            </field>
            <field>
              <name>YT</name>
              <bitOffset>20</bitOffset>
              <bitWidth>4</bitWidth>
            </field>
          </fields>
        </register>
        <register>
          <name>CR</name>
          <addressOffset>0x8</addressOffset>
          <size>0x20</size>
          <fields>
            <field>
              <name>WUCKSEL</name>
              <bitOffset>0</bitOffset>
              <bitWidth>3</bitWidth>
            </field>
            <field>
              <name>TSEDGE</name>
              <bitOffset>3</bitOffset>
              <bitWidth>1</bitWidth>
            </field>
            <field>
              <name>REFCKON</name>
              <bitOffset>4</bitOffset>
              <bitWidth>1</bitWidth>
            </field>
            <field>
              <name>BYPSHAD</name>
              <bitOffset>5</bitOffset>
              <bitWidth>1</bitWidth>
            </field>
            <field>
              <name>FMT</name>
              <bitOffset>6</bitOffset>
              <bitWidth>1</bitWidth>
            </field>
            <field>
              <name>ALRAE</name>
              <bitOffset>8</bitOffset>
              <bitWidth>1</bitWidth>
            </field>
            <field>
              <name>ALRBE</name>
              <bitOffset>9</bitOffset>
              <bitWidth>1</bitWidth>
            </field>
            <field>
              <name>WUTE</name>
              <bitOffset>10</bitOffset>
              <bitWidth>1</bitWidth>
            </field>
            <field>
              <name>TSE</name>
              <bitOffset>11</bitOffset>
              <bitWidth>1</bitWidth>
            </field>
            <field>
              <name>ALRAIE</name>
              <bitOffset>12</bitOffset>
              <bitWidth>1</bitWidth>
            </field>
            <field>
              <name>ALRBIE</name>
              <bitOffset>13</bitOffset>
              <bitWidth>1</bitWidth>
            </field>
            <field>
              <name>WUTIE</name>
              <bitOffset>14</bitOffset>
              <bitWidth>1</bitWidth>
            </field>
            <field>
              <name>TSIE</name>
              <bitOffset>15</bitOffset>
              <bitWidth>1</bitWidth>
            </field>
            <field>
              <name>ADD1H</name>
              <bitOffset>16</bitOffset>
              <bitWidth>1</bitWidth>
            </field>
            <field>
              <name>SUB1H</name>
              <bitOffset>17</bitOffset>
              <bitWidth>1</bitWidth>
            </field>
            <field>
              <name>BKP</name>
              <bitOffset>18</bitOffset>
              <bitWidth>1</bitWidth>
            </field>
            <field>
              <name>COSEL</name>
              <bitOffset>19</bitOffset>
              <bitWidth>1</bitWidth>
            </field>
            <field>
              <name>POL</name>
              <bitOffset>20</bitOffset>
              <bitWidth>1</bitWidth>
            </field>
            <field>
              <name>OSEL</name>
              <bitOffset>21</bitOffset>
              <bitWidth>2</bitWidth>
            </field>
            <field>
              <name>COE</name>
              <bitOffset>23</bitOffset>
              <bitWidth>1</bitWidth>
            </field>
            <field>
              <name>ITSE</name>
              <bitOffset>24</bitOffset>
              <bitWidth>1</bitWidth>
            </field>
          </fields>
        </register>
        <register>
          <name>ISR</name>
          <addressOffset>0xc</addressOffset>
          <size>0x20</size>
          <fields>
            <field>
              <name>ALRAWF</name>
              <bitOffset>0</bitOffset>
              <bitWidth>1</bitWidth>
            </field>
            <field>
              <name>ALRBWF</name>
              <bitOffset>1</bitOffset>
              <bitWidth>1</bitWidth>
            </field>
            <field>
              <name>WUTWF</name>
              <bitOffset>2</bitOffset>
              <bitWidth>1</bitWidth>
            </field>
            <field>
              <name>SHPF</name>
              <bitOffset>3</bitOffset>
              <bitWidth>1</bitWidth>
            </field>
            <field>
              <name>INITS</name>
              <bitOffset>4</bitOffset>
              <bitWidth>1</bitWidth>
            </field>
            <field>
              <name>RSF</name>
              <bitOffset>5</bitOffset>
              <bitWidth>1</bitWidth>
            </field>
            <field>
              <name>INITF</name>
              <bitOffset>6</bitOffset>
              <bitWidth>1</bitWidth>
            </field>
            <field>
              <name>INIT</name>
              <bitOffset>7</bitOffset>
              <bitWidth>1</bitWidth>
            </field>
            <field>
              <name>ALRAF</name>
              <bitOffset>8</bitOffset>
              <bitWidth>1</bitWidth>
            </field>
            <field>
              <name>ALRBF</name>
              <bitOffset>9</bitOffset>
              <bitWidth>1</bitWidth>
            </field>
            <field>
              <name>WUTF</name>
              <bitOffset>10</bitOffset>
              <bitWidth>1</bitWidth>
            </field>
            <field>
              <name>TSF</name>
              <bitOffset>11</bitOffset>
              <bitWidth>1</bitWidth>
            </field>
            <field>
              <name>TSOVF</name>
              <bitOffset>12</bitOffset>
              <bitWidth>1</bitWidth>
            </field>
            <field>
              <name>TAMP1F</name>
              <bitOffset>13</bitOffset>
              <bitWidth>1</bitWidth>
            </field>
            <field>
              <name>TAMP2F</name>
              <bitOffset>14</bitOffset>
              <bitWidth>1</bitWidth>
            </field>
            <field>
              <name>TAMP3F</name>
              <bitOffset>15</bitOffset>
              <bitWidth>1</bitWidth>
            </field>
            <field>
              <name>RECALPF</name>
              <bitOffset>16</bitOffset>
              <bitWidth>1</bitWidth>
            </field>
            <field>
              <name>ITSF</name>
              <bitOffset>17</bitOffset>
              <bitWidth>1</bitWidth>
            </field>
          </fields>
        </register>
        <register>
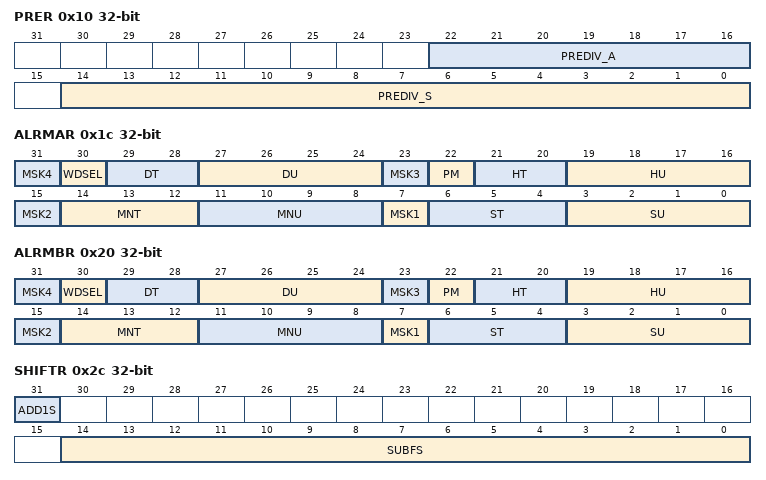
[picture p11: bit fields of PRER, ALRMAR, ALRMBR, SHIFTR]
          <name>PRER</name>
          <addressOffset>0x10</addressOffset>
          <size>0x20</size>
          <fields>
            <field>
              <name>PREDIV_S</name>
              <bitOffset>0</bitOffset>
              <bitWidth>15</bitWidth>
            </field>
            <field>
              <name>PREDIV_A</name>
              <bitOffset>16</bitOffset>
              <bitWidth>7</bitWidth>
            </field>
          </fields>
        </register>
        <register>
          <name>WUTR</name>
          <addressOffset>0x14</addressOffset>
          <size>0x20</size>
          <fields>
            <field>
              <name>WUT</name>
              <bitOffset>0</bitOffset>
              <bitWidth>16</bitWidth>
            </field>
          </fields>
        </register>
        <register>
          <name>ALRMAR</name>
          <addressOffset>0x1c</addressOffset>
          <size>0x20</size>
          <fields>
            <field>
              <name>SU</name>
              <bitOffset>0</bitOffset>
              <bitWidth>4</bitWidth>
            </field>
            <field>
              <name>ST</name>
              <bitOffset>4</bitOffset>
              <bitWidth>3</bitWidth>
            </field>
            <field>
              <name>MSK1</name>
              <bitOffset>7</bitOffset>
              <bitWidth>1</bitWidth>
            </field>
            <field>
              <name>MNU</name>
              <bitOffset>8</bitOffset>
              <bitWidth>4</bitWidth>
            </field>
            <field>
              <name>MNT</name>
              <bitOffset>12</bitOffset>
              <bitWidth>3</bitWidth>
            </field>
            <field>
              <name>MSK2</name>
              <bitOffset>15</bitOffset>
              <bitWidth>1</bitWidth>
            </field>
            <field>
              <name>HU</name>
              <bitOffset>16</bitOffset>
              <bitWidth>4</bitWidth>
            </field>
            <field>
              <name>HT</name>
              <bitOffset>20</bitOffset>
              <bitWidth>2</bitWidth>
            </field>
            <field>
              <name>PM</name>
              <bitOffset>22</bitOffset>
              <bitWidth>1</bitWidth>
            </field>
            <field>
              <name>MSK3</name>
              <bitOffset>23</bitOffset>
              <bitWidth>1</bitWidth>
            </field>
            <field>
              <name>DU</name>
              <bitOffset>24</bitOffset>
              <bitWidth>4</bitWidth>
            </field>
            <field>
              <name>DT</name>
              <bitOffset>28</bitOffset>
              <bitWidth>2</bitWidth>
            </field>
            <field>
              <name>WDSEL</name>
              <bitOffset>30</bitOffset>
              <bitWidth>1</bitWidth>
            </field>
            <field>
              <name>MSK4</name>
              <bitOffset>31</bitOffset>
              <bitWidth>1</bitWidth>
            </field>
          </fields>
        </register>
        <register>
          <name>ALRMBR</name>
          <addressOffset>0x20</addressOffset>
          <size>0x20</size>
          <fields>
            <field>
              <name>SU</name>
              <bitOffset>0</bitOffset>
              <bitWidth>4</bitWidth>
            </field>
            <field>
              <name>ST</name>
              <bitOffset>4</bitOffset>
              <bitWidth>3</bitWidth>
            </field>
            <field>
              <name>MSK1</name>
              <bitOffset>7</bitOffset>
              <bitWidth>1</bitWidth>
            </field>
            <field>
              <name>MNU</name>
              <bitOffset>8</bitOffset>
              <bitWidth>4</bitWidth>
            </field>
            <field>
              <name>MNT</name>
              <bitOffset>12</bitOffset>
              <bitWidth>3</bitWidth>
            </field>
            <field>
              <name>MSK2</name>
              <bitOffset>15</bitOffset>
              <bitWidth>1</bitWidth>
            </field>
            <field>
              <name>HU</name>
              <bitOffset>16</bitOffset>
              <bitWidth>4</bitWidth>
            </field>
            <field>
              <name>HT</name>
              <bitOffset>20</bitOffset>
              <bitWidth>2</bitWidth>
            </field>
            <field>
              <name>PM</name>
              <bitOffset>22</bitOffset>
              <bitWidth>1</bitWidth>
            </field>
            <field>
              <name>MSK3</name>
              <bitOffset>23</bitOffset>
              <bitWidth>1</bitWidth>
            </field>
            <field>
              <name>DU</name>
              <bitOffset>24</bitOffset>
              <bitWidth>4</bitWidth>
            </field>
            <field>
              <name>DT</name>
              <bitOffset>28</bitOffset>
              <bitWidth>2</bitWidth>
            </field>
            <field>
              <name>WDSEL</name>
              <bitOffset>30</bitOffset>
              <bitWidth>1</bitWidth>
            </field>
            <field>
              <name>MSK4</name>
              <bitOffset>31</bitOffset>
              <bitWidth>1</bitWidth>
            </field>
          </fields>
        </register>
        <register>
          <name>WPR</name>
          <addressOffset>0x24</addressOffset>
          <size>0x20</size>
          <fields>
            <field>
              <name>KEY</name>
              <bitOffset>0</bitOffset>
              <bitWidth>8</bitWidth>
            </field>
          </fields>
        </register>
        <register>
          <name>SSR</name>
          <addressOffset>0x28</addressOffset>
          <size>0x20</size>
          <fields>
            <field>
              <name>SS</name>
              <bitOffset>0</bitOffset>
              <bitWidth>16</bitWidth>
            </field>
          </fields>
        </register>
        <register>
          <name>SHIFTR</name>
          <addressOffset>0x2c</addressOffset>
          <size>0x20</size>
          <fields>
            <field>
              <name>SUBFS</name>
              <bitOffset>0</bitOffset>
              <bitWidth>15</bitWidth>
            </field>
            <field>
              <name>ADD1S</name>
              <bitOffset>31</bitOffset>
              <bitWidth>1</bitWidth>
            </field>
          </fields>
        </register>
        <register>
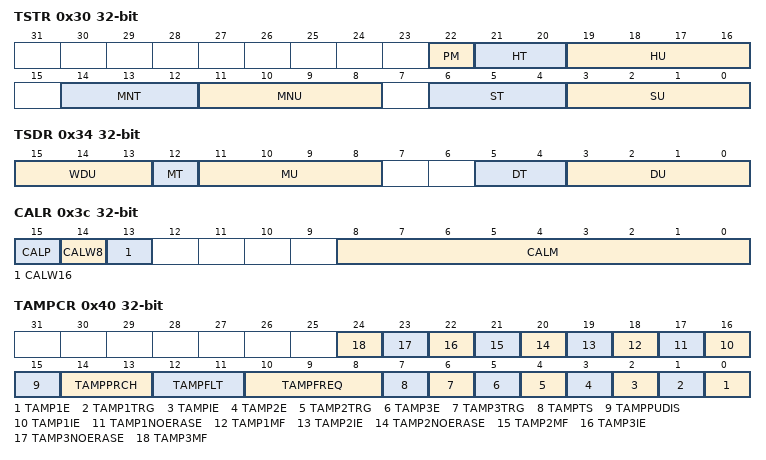
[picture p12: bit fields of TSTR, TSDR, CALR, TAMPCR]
          <name>TSTR</name>
          <addressOffset>0x30</addressOffset>
          <size>0x20</size>
          <fields>
            <field>
              <name>SU</name>
              <bitOffset>0</bitOffset>
              <bitWidth>4</bitWidth>
            </field>
            <field>
              <name>ST</name>
              <bitOffset>4</bitOffset>
              <bitWidth>3</bitWidth>
            </field>
            <field>
              <name>MNU</name>
              <bitOffset>8</bitOffset>
              <bitWidth>4</bitWidth>
            </field>
            <field>
              <name>MNT</name>
              <bitOffset>12</bitOffset>
              <bitWidth>3</bitWidth>
            </field>
            <field>
              <name>HU</name>
              <bitOffset>16</bitOffset>
              <bitWidth>4</bitWidth>
            </field>
            <field>
              <name>HT</name>
              <bitOffset>20</bitOffset>
              <bitWidth>2</bitWidth>
            </field>
            <field>
              <name>PM</name>
              <bitOffset>22</bitOffset>
              <bitWidth>1</bitWidth>
            </field>
          </fields>
        </register>
        <register>
          <name>TSDR</name>
          <addressOffset>0x34</addressOffset>
          <size>0x20</size>
          <fields>
            <field>
              <name>DU</name>
              <bitOffset>0</bitOffset>
              <bitWidth>4</bitWidth>
            </field>
            <field>
              <name>DT</name>
              <bitOffset>4</bitOffset>
              <bitWidth>2</bitWidth>
            </field>
            <field>
              <name>MU</name>
              <bitOffset>8</bitOffset>
              <bitWidth>4</bitWidth>
            </field>
            <field>
              <name>MT</name>
              <bitOffset>12</bitOffset>
              <bitWidth>1</bitWidth>
            </field>
            <field>
              <name>WDU</name>
              <bitOffset>13</bitOffset>
              <bitWidth>3</bitWidth>
            </field>
          </fields>
        </register>
        <register>
          <name>TSSSR</name>
          <addressOffset>0x38</addressOffset>
          <size>0x20</size>
          <fields>
            <field>
              <name>SS</name>
              <bitOffset>0</bitOffset>
              <bitWidth>16</bitWidth>
            </field>
          </fields>
        </register>
        <register>
          <name>CALR</name>
          <addressOffset>0x3c</addressOffset>
          <size>0x20</size>
          <fields>
            <field>
              <name>CALM</name>
              <bitOffset>0</bitOffset>
              <bitWidth>9</bitWidth>
            </field>
            <field>
              <name>CALW16</name>
              <bitOffset>13</bitOffset>
              <bitWidth>1</bitWidth>
            </field>
            <field>
              <name>CALW8</name>
              <bitOffset>14</bitOffset>
              <bitWidth>1</bitWidth>
            </field>
            <field>
              <name>CALP</name>
              <bitOffset>15</bitOffset>
              <bitWidth>1</bitWidth>
            </field>
          </fields>
        </register>
        <register>
          <name>TAMPCR</name>
          <addressOffset>0x40</addressOffset>
          <size>0x20</size>
          <fields>
            <field>
              <name>TAMP1E</name>
              <bitOffset>0</bitOffset>
              <bitWidth>1</bitWidth>
            </field>
            <field>
              <name>TAMP1TRG</name>
              <bitOffset>1</bitOffset>
              <bitWidth>1</bitWidth>
            </field>
            <field>
              <name>TAMPIE</name>
              <bitOffset>2</bitOffset>
              <bitWidth>1</bitWidth>
            </field>
            <field>
              <name>TAMP2E</name>
              <bitOffset>3</bitOffset>
              <bitWidth>1</bitWidth>
            </field>
            <field>
              <name>TAMP2TRG</name>
              <bitOffset>4</bitOffset>
              <bitWidth>1</bitWidth>
            </field>
            <field>
              <name>TAMP3E</name>
              <bitOffset>5</bitOffset>
              <bitWidth>1</bitWidth>
            </field>
            <field>
              <name>TAMP3TRG</name>
              <bitOffset>6</bitOffset>
              <bitWidth>1</bitWidth>
            </field>
            <field>
              <name>TAMPTS</name>
              <bitOffset>7</bitOffset>
              <bitWidth>1</bitWidth>
            </field>
            <field>
              <name>TAMPFREQ</name>
              <bitOffset>8</bitOffset>
              <bitWidth>3</bitWidth>
            </field>
            <field>
              <name>TAMPFLT</name>
              <bitOffset>11</bitOffset>
              <bitWidth>2</bitWidth>
            </field>
            <field>
              <name>TAMPPRCH</name>
              <bitOffset>13</bitOffset>
              <bitWidth>2</bitWidth>
            </field>
            <field>
              <name>TAMPPUDIS</name>
              <bitOffset>15</bitOffset>
              <bitWidth>1</bitWidth>
            </field>
            <field>
              <name>TAMP1IE</name>
              <bitOffset>16</bitOffset>
              <bitWidth>1</bitWidth>
            </field>
            <field>
              <name>TAMP1NOERASE</name>
              <bitOffset>17</bitOffset>
              <bitWidth>1</bitWidth>
            </field>
            <field>
              <name>TAMP1MF</name>
              <bitOffset>18</bitOffset>
              <bitWidth>1</bitWidth>
            </field>
            <field>
              <name>TAMP2IE</name>
              <bitOffset>19</bitOffset>
              <bitWidth>1</bitWidth>
            </field>
            <field>
              <name>TAMP2NOERASE</name>
              <bitOffset>20</bitOffset>
              <bitWidth>1</bitWidth>
            </field>
            <field>
              <name>TAMP2MF</name>
              <bitOffset>21</bitOffset>
              <bitWidth>1</bitWidth>
            </field>
            <field>
              <name>TAMP3IE</name>
              <bitOffset>22</bitOffset>
              <bitWidth>1</bitWidth>
            </field>
            <field>
              <name>TAMP3NOERASE</name>
              <bitOffset>23</bitOffset>
              <bitWidth>1</bitWidth>
            </field>
            <field>
              <name>TAMP3MF</name>
              <bitOffset>24</bitOffset>
              <bitWidth>1</bitWidth>
            </field>
          </fields>
        </register>
        <register>
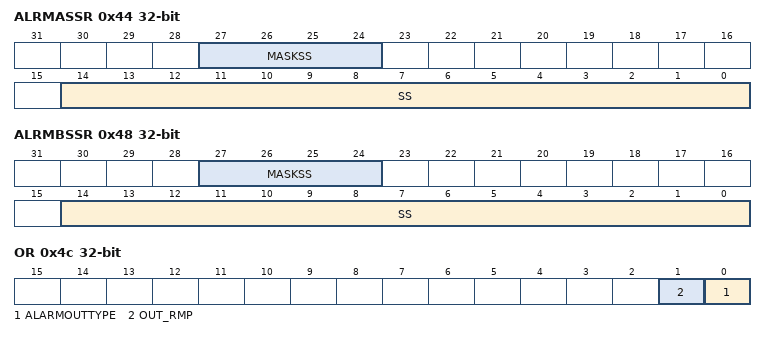
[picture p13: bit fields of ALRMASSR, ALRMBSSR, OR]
          <name>ALRMASSR</name>
          <addressOffset>0x44</addressOffset>
          <size>0x20</size>
          <fields>
            <field>
              <name>SS</name>
              <bitOffset>0</bitOffset>
              <bitWidth>15</bitWidth>
            </field>
            <field>
              <name>MASKSS</name>
              <bitOffset>24</bitOffset>
              <bitWidth>4</bitWidth>
            </field>
          </fields>
        </register>
        <register>
          <name>ALRMBSSR</name>
          <addressOffset>0x48</addressOffset>
          <size>0x20</size>
          <fields>
            <field>
              <name>SS</name>
              <bitOffset>0</bitOffset>
              <bitWidth>15</bitWidth>
            </field>
            <field>
              <name>MASKSS</name>
              <bitOffset>24</bitOffset>
              <bitWidth>4</bitWidth>
            </field>
          </fields>
        </register>
        <register>
          <name>OR</name>
          <addressOffset>0x4c</addressOffset>
          <size>0x20</size>
          <fields>
            <field>
              <name>ALARMOUTTYPE</name>
              <bitOffset>0</bitOffset>
              <bitWidth>1</bitWidth>
            </field>
            <field>
              <name>OUT_RMP</name>
              <bitOffset>1</bitOffset>
              <bitWidth>1</bitWidth>
            </field>
          </fields>
        </register>
        <register>
          <name>BKP0R</name>
          <addressOffset>0x50</addressOffset>
          <size>0x20</size>
        </register>
        <register>
          <name>BKP1R</name>
          <addressOffset>0x54</addressOffset>
          <size>0x20</size>
        </register>
        <register>
          <name>BKP2R</name>
          <addressOffset>0x58</addressOffset>
          <size>0x20</size>
        </register>
        <register>
          <name>BKP3R</name>
          <addressOffset>0x5c</addressOffset>
          <size>0x20</size>
        </register>
        <register>
          <name>BKP4R</name>
          <addressOffset>0x60</addressOffset>
          <size>0x20</size>
        </register>
        <register>
          <name>BKP5R</name>
          <addressOffset>0x64</addressOffset>
          <size>0x20</size>
        </register>
        <register>
          <name>BKP6R</name>
          <addressOffset>0x68</addressOffset>
          <size>0x20</size>
        </register>
        <register>
          <name>BKP7R</name>
          <addressOffset>0x6c</addressOffset>
          <size>0x20</size>
        </register>
        <register>
          <name>BKP8R</name>
          <addressOffset>0x70</addressOffset>
          <size>0x20</size>
        </register>
        <register>
          <name>BKP9R</name>
          <addressOffset>0x74</addressOffset>
          <size>0x20</size>
        </register>
        <register>
          <name>BKP10R</name>
          <addressOffset>0x78</addressOffset>
          <size>0x20</size>
        </register>
        <register>
          <name>BKP11R</name>
          <addressOffset>0x7c</addressOffset>
          <size>0x20</size>
        </register>
        <register>
          <name>BKP12R</name>
          <addressOffset>0x80</addressOffset>
          <size>0x20</size>
        </register>
        <register>
          <name>BKP13R</name>
          <addressOffset>0x84</addressOffset>
          <size>0x20</size>
        </register>
        <register>
          <name>BKP14R</name>
          <addressOffset>0x88</addressOffset>
          <size>0x20</size>
        </register>
        <register>
          <name>BKP15R</name>
          <addressOffset>0x8c</addressOffset>
          <size>0x20</size>
        </register>
        <register>
          <name>BKP16R</name>
          <addressOffset>0x90</addressOffset>
          <size>0x20</size>
        </register>
        <register>
          <name>BKP17R</name>
          <addressOffset>0x94</addressOffset>
          <size>0x20</size>
        </register>
        <register>
          <name>BKP18R</name>
          <addressOffset>0x98</addressOffset>
          <size>0x20</size>
        </register>
        <register>
          <name>BKP19R</name>
          <addressOffset>0x9c</addressOffset>
          <size>0x20</size>
        </register>
        <register>
          <name>BKP20R</name>
          <addressOffset>0xa0</addressOffset>
          <size>0x20</size>
        </register>
        <register>
          <name>BKP21R</name>
          <addressOffset>0xa4</addressOffset>
          <size>0x20</size>
        </register>
        <register>
          <name>BKP22R</name>
          <addressOffset>0xa8</addressOffset>
          <size>0x20</size>
        </register>
        <register>
          <name>BKP23R</name>
          <addressOffset>0xac</addressOffset>
          <size>0x20</size>
        </register>
        <register>
          <name>BKP24R</name>
          <addressOffset>0xb0</addressOffset>
          <size>0x20</size>
        </register>
        <register>
          <name>BKP25R</name>
          <addressOffset>0xb4</addressOffset>
          <size>0x20</size>
        </register>
        <register>
          <name>BKP26R</name>
          <addressOffset>0xb8</addressOffset>
          <size>0x20</size>
        </register>
        <register>
          <name>BKP27R</name>
          <addressOffset>0xbc</addressOffset>
          <size>0x20</size>
        </register>
        <register>
          <name>BKP28R</name>
          <addressOffset>0xc0</addressOffset>
          <size>0x20</size>
        </register>
        <register>
          <name>BKP29R</name>
          <addressOffset>0xc4</addressOffset>
          <size>0x20</size>
        </register>
        <register>
          <name>BKP30R</name>
          <addressOffset>0xc8</addressOffset>
          <size>0x20</size>
        </register>
        <register>
          <name>BKP31R</name>
          <addressOffset>0xcc</addressOffset>
          <size>0x20</size>
        </register>
      </registers>
    </peripheral>
    <peripheral>
      <name>IWDG1</name>
      <baseAddress>0x58004800</baseAddress>
      <registers>
        <register>
          <name>KR</name>
          <addressOffset>0x0</addressOffset>
          <size>0x20</size>
          <fields>
            <field>
              <name>KEY</name>
              <bitOffset>0</bitOffset>
              <bitWidth>16</bitWidth>
            </field>
          </fields>
        </register>
        <register>
          <name>PR</name>
          <addressOffset>0x4</addressOffset>
          <size>0x20</size>
          <fields>
            <field>
              <name>PR</name>
              <bitOffset>0</bitOffset>
              <bitWidth>3</bitWidth>
            </field>
          </fields>
        </register>
        <register>
          <name>RLR</name>
          <addressOffset>0x8</addressOffset>
          <size>0x20</size>
          <fields>
            <field>
              <name>RL</name>
              <bitOffset>0</bitOffset>
              <bitWidth>12</bitWidth>
            </field>
          </fields>
        </register>
        <register>
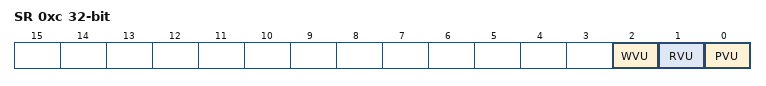
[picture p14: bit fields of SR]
          <name>SR</name>
          <addressOffset>0xc</addressOffset>
          <size>0x20</size>
          <fields>
            <field>
              <name>PVU</name>
              <bitOffset>0</bitOffset>
              <bitWidth>1</bitWidth>
            </field>
            <field>
              <name>RVU</name>
              <bitOffset>1</bitOffset>
              <bitWidth>1</bitWidth>
            </field>
            <field>
              <name>WVU</name>
              <bitOffset>2</bitOffset>
              <bitWidth>1</bitWidth>
            </field>
          </fields>
        </register>
        <register>
          <name>WINR</name>
          <addressOffset>0x10</addressOffset>
          <size>0x20</size>
          <fields>
            <field>
              <name>WIN</name>
              <bitOffset>0</bitOffset>
              <bitWidth>12</bitWidth>
            </field>
          </fields>
        </register>
      </registers>
    </peripheral>
    <peripheral>
      <name>SAI4</name>
      <baseAddress>0x58005400</baseAddress>
      <registers>
        <register>
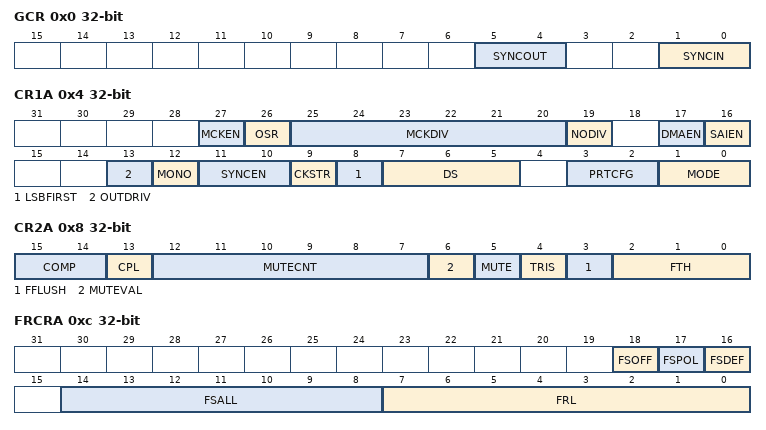
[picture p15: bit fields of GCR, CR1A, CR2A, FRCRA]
          <name>GCR</name>
          <addressOffset>0x0</addressOffset>
          <size>0x20</size>
          <fields>
            <field>
              <name>SYNCIN</name>
              <bitOffset>0</bitOffset>
              <bitWidth>2</bitWidth>
            </field>
            <field>
              <name>SYNCOUT</name>
              <bitOffset>4</bitOffset>
              <bitWidth>2</bitWidth>
            </field>
          </fields>
        </register>
        <register>
          <name>CR1A</name>
          <addressOffset>0x4</addressOffset>
          <size>0x20</size>
          <fields>
            <field>
              <name>MODE</name>
              <bitOffset>0</bitOffset>
              <bitWidth>2</bitWidth>
            </field>
            <field>
              <name>PRTCFG</name>
              <bitOffset>2</bitOffset>
              <bitWidth>2</bitWidth>
            </field>
            <field>
              <name>DS</name>
              <bitOffset>5</bitOffset>
              <bitWidth>3</bitWidth>
            </field>
            <field>
              <name>LSBFIRST</name>
              <bitOffset>8</bitOffset>
              <bitWidth>1</bitWidth>
            </field>
            <field>
              <name>CKSTR</name>
              <bitOffset>9</bitOffset>
              <bitWidth>1</bitWidth>
            </field>
            <field>
              <name>SYNCEN</name>
              <bitOffset>10</bitOffset>
              <bitWidth>2</bitWidth>
            </field>
            <field>
              <name>MONO</name>
              <bitOffset>12</bitOffset>
              <bitWidth>1</bitWidth>
            </field>
            <field>
              <name>OUTDRIV</name>
              <bitOffset>13</bitOffset>
              <bitWidth>1</bitWidth>
            </field>
            <field>
              <name>SAIEN</name>
              <bitOffset>16</bitOffset>
              <bitWidth>1</bitWidth>
            </field>
            <field>
              <name>DMAEN</name>
              <bitOffset>17</bitOffset>
              <bitWidth>1</bitWidth>
            </field>
            <field>
              <name>NODIV</name>
              <bitOffset>19</bitOffset>
              <bitWidth>1</bitWidth>
            </field>
            <field>
              <name>MCKDIV</name>
              <bitOffset>20</bitOffset>
              <bitWidth>6</bitWidth>
            </field>
            <field>
              <name>OSR</name>
              <bitOffset>26</bitOffset>
              <bitWidth>1</bitWidth>
            </field>
            <field>
              <name>MCKEN</name>
              <bitOffset>27</bitOffset>
              <bitWidth>1</bitWidth>
            </field>
          </fields>
        </register>
        <register>
          <name>CR1A</name>
          <addressOffset>0x4</addressOffset>
          <size>0x20</size>
          <fields>
            <field>
              <name>MODE</name>
              <bitOffset>0</bitOffset>
              <bitWidth>2</bitWidth>
            </field>
            <field>
              <name>PRTCFG</name>
              <bitOffset>2</bitOffset>
              <bitWidth>2</bitWidth>
            </field>
            <field>
              <name>DS</name>
              <bitOffset>5</bitOffset>
              <bitWidth>3</bitWidth>
            </field>
            <field>
              <name>LSBFIRST</name>
              <bitOffset>8</bitOffset>
              <bitWidth>1</bitWidth>
            </field>
            <field>
              <name>CKSTR</name>
              <bitOffset>9</bitOffset>
              <bitWidth>1</bitWidth>
            </field>
            <field>
              <name>SYNCEN</name>
              <bitOffset>10</bitOffset>
              <bitWidth>2</bitWidth>
            </field>
            <field>
              <name>MONO</name>
              <bitOffset>12</bitOffset>
              <bitWidth>1</bitWidth>
            </field>
            <field>
              <name>OUTDRIV</name>
              <bitOffset>13</bitOffset>
              <bitWidth>1</bitWidth>
            </field>
            <field>
              <name>SAIEN</name>
              <bitOffset>16</bitOffset>
              <bitWidth>1</bitWidth>
            </field>
            <field>
              <name>DMAEN</name>
              <bitOffset>17</bitOffset>
              <bitWidth>1</bitWidth>
            </field>
            <field>
              <name>NODIV</name>
              <bitOffset>19</bitOffset>
              <bitWidth>1</bitWidth>
            </field>
            <field>
              <name>MCKDIV</name>
              <bitOffset>20</bitOffset>
              <bitWidth>6</bitWidth>
            </field>
            <field>
              <name>OSR</name>
              <bitOffset>26</bitOffset>
              <bitWidth>1</bitWidth>
            </field>
            <field>
              <name>MCKEN</name>
              <bitOffset>27</bitOffset>
              <bitWidth>1</bitWidth>
            </field>
          </fields>
        </register>
        <register>
          <name>CR2A</name>
          <addressOffset>0x8</addressOffset>
          <size>0x20</size>
          <fields>
            <field>
              <name>FTH</name>
              <bitOffset>0</bitOffset>
              <bitWidth>3</bitWidth>
            </field>
            <field>
              <name>FFLUSH</name>
              <bitOffset>3</bitOffset>
              <bitWidth>1</bitWidth>
            </field>
            <field>
              <name>TRIS</name>
              <bitOffset>4</bitOffset>
              <bitWidth>1</bitWidth>
            </field>
            <field>
              <name>MUTE</name>
              <bitOffset>5</bitOffset>
              <bitWidth>1</bitWidth>
            </field>
            <field>
              <name>MUTEVAL</name>
              <bitOffset>6</bitOffset>
              <bitWidth>1</bitWidth>
            </field>
            <field>
              <name>MUTECNT</name>
              <bitOffset>7</bitOffset>
              <bitWidth>6</bitWidth>
            </field>
            <field>
              <name>CPL</name>
              <bitOffset>13</bitOffset>
              <bitWidth>1</bitWidth>
            </field>
            <field>
              <name>COMP</name>
              <bitOffset>14</bitOffset>
              <bitWidth>2</bitWidth>
            </field>
          </fields>
        </register>
        <register>
          <name>CR2A</name>
          <addressOffset>0x8</addressOffset>
          <size>0x20</size>
          <fields>
            <field>
              <name>FTH</name>
              <bitOffset>0</bitOffset>
              <bitWidth>3</bitWidth>
            </field>
            <field>
              <name>FFLUSH</name>
              <bitOffset>3</bitOffset>
              <bitWidth>1</bitWidth>
            </field>
            <field>
              <name>TRIS</name>
              <bitOffset>4</bitOffset>
              <bitWidth>1</bitWidth>
            </field>
            <field>
              <name>MUTE</name>
              <bitOffset>5</bitOffset>
              <bitWidth>1</bitWidth>
            </field>
            <field>
              <name>MUTEVAL</name>
              <bitOffset>6</bitOffset>
              <bitWidth>1</bitWidth>
            </field>
            <field>
              <name>MUTECNT</name>
              <bitOffset>7</bitOffset>
              <bitWidth>6</bitWidth>
            </field>
            <field>
              <name>CPL</name>
              <bitOffset>13</bitOffset>
              <bitWidth>1</bitWidth>
            </field>
            <field>
              <name>COMP</name>
              <bitOffset>14</bitOffset>
              <bitWidth>2</bitWidth>
            </field>
          </fields>
        </register>
        <register>
          <name>FRCRA</name>
          <addressOffset>0xc</addressOffset>
          <size>0x20</size>
          <fields>
            <field>
              <name>FRL</name>
              <bitOffset>0</bitOffset>
              <bitWidth>8</bitWidth>
            </field>
            <field>
              <name>FSALL</name>
              <bitOffset>8</bitOffset>
              <bitWidth>7</bitWidth>
            </field>
            <field>
              <name>FSDEF</name>
              <bitOffset>16</bitOffset>
              <bitWidth>1</bitWidth>
            </field>
            <field>
              <name>FSPOL</name>
              <bitOffset>17</bitOffset>
              <bitWidth>1</bitWidth>
            </field>
            <field>
              <name>FSOFF</name>
              <bitOffset>18</bitOffset>
              <bitWidth>1</bitWidth>
            </field>
          </fields>
        </register>
        <register>
          <name>FRCRA</name>
          <addressOffset>0xc</addressOffset>
          <size>0x20</size>
          <fields>
            <field>
              <name>FRL</name>
              <bitOffset>0</bitOffset>
              <bitWidth>8</bitWidth>
            </field>
            <field>
              <name>FSALL</name>
              <bitOffset>8</bitOffset>
              <bitWidth>7</bitWidth>
            </field>
            <field>
              <name>FSDEF</name>
              <bitOffset>16</bitOffset>
              <bitWidth>1</bitWidth>
            </field>
            <field>
              <name>FSPOL</name>
              <bitOffset>17</bitOffset>
              <bitWidth>1</bitWidth>
            </field>
            <field>
              <name>FSOFF</name>
              <bitOffset>18</bitOffset>
              <bitWidth>1</bitWidth>
            </field>
          </fields>
        </register>
        <register>
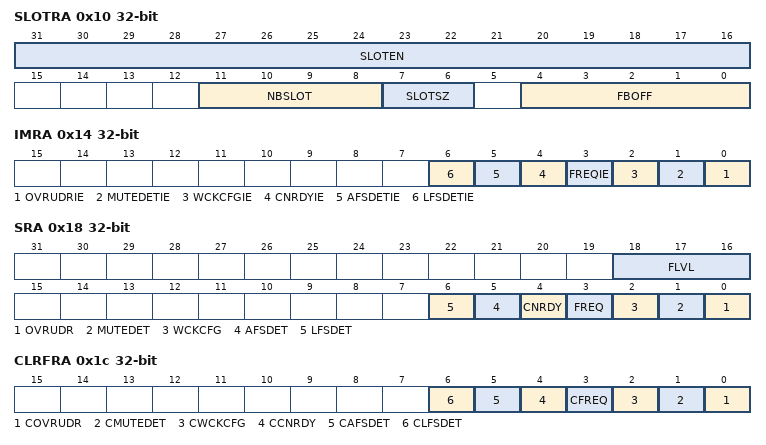
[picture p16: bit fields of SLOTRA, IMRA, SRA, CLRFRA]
          <name>SLOTRA</name>
          <addressOffset>0x10</addressOffset>
          <size>0x20</size>
          <fields>
            <field>
              <name>FBOFF</name>
              <bitOffset>0</bitOffset>
              <bitWidth>5</bitWidth>
            </field>
            <field>
              <name>SLOTSZ</name>
              <bitOffset>6</bitOffset>
              <bitWidth>2</bitWidth>
            </field>
            <field>
              <name>NBSLOT</name>
              <bitOffset>8</bitOffset>
              <bitWidth>4</bitWidth>
            </field>
            <field>
              <name>SLOTEN</name>
              <bitOffset>16</bitOffset>
              <bitWidth>16</bitWidth>
            </field>
          </fields>
        </register>
        <register>
          <name>SLOTRA</name>
          <addressOffset>0x10</addressOffset>
          <size>0x20</size>
          <fields>
            <field>
              <name>FBOFF</name>
              <bitOffset>0</bitOffset>
              <bitWidth>5</bitWidth>
            </field>
            <field>
              <name>SLOTSZ</name>
              <bitOffset>6</bitOffset>
              <bitWidth>2</bitWidth>
            </field>
            <field>
              <name>NBSLOT</name>
              <bitOffset>8</bitOffset>
              <bitWidth>4</bitWidth>
            </field>
            <field>
              <name>SLOTEN</name>
              <bitOffset>16</bitOffset>
              <bitWidth>16</bitWidth>
            </field>
          </fields>
        </register>
        <register>
          <name>IMRA</name>
          <addressOffset>0x14</addressOffset>
          <size>0x20</size>
          <fields>
            <field>
              <name>OVRUDRIE</name>
              <bitOffset>0</bitOffset>
              <bitWidth>1</bitWidth>
            </field>
            <field>
              <name>MUTEDETIE</name>
              <bitOffset>1</bitOffset>
              <bitWidth>1</bitWidth>
            </field>
            <field>
              <name>WCKCFGIE</name>
              <bitOffset>2</bitOffset>
              <bitWidth>1</bitWidth>
            </field>
            <field>
              <name>FREQIE</name>
              <bitOffset>3</bitOffset>
              <bitWidth>1</bitWidth>
            </field>
            <field>
              <name>CNRDYIE</name>
              <bitOffset>4</bitOffset>
              <bitWidth>1</bitWidth>
            </field>
            <field>
              <name>AFSDETIE</name>
              <bitOffset>5</bitOffset>
              <bitWidth>1</bitWidth>
            </field>
            <field>
              <name>LFSDETIE</name>
              <bitOffset>6</bitOffset>
              <bitWidth>1</bitWidth>
            </field>
          </fields>
        </register>
        <register>
          <name>IMRA</name>
          <addressOffset>0x14</addressOffset>
          <size>0x20</size>
          <fields>
            <field>
              <name>OVRUDRIE</name>
              <bitOffset>0</bitOffset>
              <bitWidth>1</bitWidth>
            </field>
            <field>
              <name>MUTEDETIE</name>
              <bitOffset>1</bitOffset>
              <bitWidth>1</bitWidth>
            </field>
            <field>
              <name>WCKCFGIE</name>
              <bitOffset>2</bitOffset>
              <bitWidth>1</bitWidth>
            </field>
            <field>
              <name>FREQIE</name>
              <bitOffset>3</bitOffset>
              <bitWidth>1</bitWidth>
            </field>
            <field>
              <name>CNRDYIE</name>
              <bitOffset>4</bitOffset>
              <bitWidth>1</bitWidth>
            </field>
            <field>
              <name>AFSDETIE</name>
              <bitOffset>5</bitOffset>
              <bitWidth>1</bitWidth>
            </field>
            <field>
              <name>LFSDETIE</name>
              <bitOffset>6</bitOffset>
              <bitWidth>1</bitWidth>
            </field>
          </fields>
        </register>
        <register>
          <name>SRA</name>
          <addressOffset>0x18</addressOffset>
          <size>0x20</size>
          <fields>
            <field>
              <name>OVRUDR</name>
              <bitOffset>0</bitOffset>
              <bitWidth>1</bitWidth>
            </field>
            <field>
              <name>MUTEDET</name>
              <bitOffset>1</bitOffset>
              <bitWidth>1</bitWidth>
            </field>
            <field>
              <name>WCKCFG</name>
              <bitOffset>2</bitOffset>
              <bitWidth>1</bitWidth>
            </field>
            <field>
              <name>FREQ</name>
              <bitOffset>3</bitOffset>
              <bitWidth>1</bitWidth>
            </field>
            <field>
              <name>CNRDY</name>
              <bitOffset>4</bitOffset>
              <bitWidth>1</bitWidth>
            </field>
            <field>
              <name>AFSDET</name>
              <bitOffset>5</bitOffset>
              <bitWidth>1</bitWidth>
            </field>
            <field>
              <name>LFSDET</name>
              <bitOffset>6</bitOffset>
              <bitWidth>1</bitWidth>
            </field>
            <field>
              <name>FLVL</name>
              <bitOffset>16</bitOffset>
              <bitWidth>3</bitWidth>
            </field>
          </fields>
        </register>
        <register>
          <name>SRA</name>
          <addressOffset>0x18</addressOffset>
          <size>0x20</size>
          <fields>
            <field>
              <name>OVRUDR</name>
              <bitOffset>0</bitOffset>
              <bitWidth>1</bitWidth>
            </field>
            <field>
              <name>MUTEDET</name>
              <bitOffset>1</bitOffset>
              <bitWidth>1</bitWidth>
            </field>
            <field>
              <name>WCKCFG</name>
              <bitOffset>2</bitOffset>
              <bitWidth>1</bitWidth>
            </field>
            <field>
              <name>FREQ</name>
              <bitOffset>3</bitOffset>
              <bitWidth>1</bitWidth>
            </field>
            <field>
              <name>CNRDY</name>
              <bitOffset>4</bitOffset>
              <bitWidth>1</bitWidth>
            </field>
            <field>
              <name>AFSDET</name>
              <bitOffset>5</bitOffset>
              <bitWidth>1</bitWidth>
            </field>
            <field>
              <name>LFSDET</name>
              <bitOffset>6</bitOffset>
              <bitWidth>1</bitWidth>
            </field>
            <field>
              <name>FLVL</name>
              <bitOffset>16</bitOffset>
              <bitWidth>3</bitWidth>
            </field>
          </fields>
        </register>
        <register>
          <name>CLRFRA</name>
          <addressOffset>0x1c</addressOffset>
          <size>0x20</size>
          <fields>
            <field>
              <name>COVRUDR</name>
              <bitOffset>0</bitOffset>
              <bitWidth>1</bitWidth>
            </field>
            <field>
              <name>CMUTEDET</name>
              <bitOffset>1</bitOffset>
              <bitWidth>1</bitWidth>
            </field>
            <field>
              <name>CWCKCFG</name>
              <bitOffset>2</bitOffset>
              <bitWidth>1</bitWidth>
            </field>
            <field>
              <name>CFREQ</name>
              <bitOffset>3</bitOffset>
              <bitWidth>1</bitWidth>
            </field>
            <field>
              <name>CCNRDY</name>
              <bitOffset>4</bitOffset>
              <bitWidth>1</bitWidth>
            </field>
            <field>
              <name>CAFSDET</name>
              <bitOffset>5</bitOffset>
              <bitWidth>1</bitWidth>
            </field>
            <field>
              <name>CLFSDET</name>
              <bitOffset>6</bitOffset>
              <bitWidth>1</bitWidth>
            </field>
          </fields>
        </register>
        <register>
          <name>CLRFRA</name>
          <addressOffset>0x1c</addressOffset>
          <size>0x20</size>
          <fields>
            <field>
              <name>COVRUDR</name>
              <bitOffset>0</bitOffset>
              <bitWidth>1</bitWidth>
            </field>
            <field>
              <name>CMUTEDET</name>
              <bitOffset>1</bitOffset>
              <bitWidth>1</bitWidth>
            </field>
            <field>
              <name>CWCKCFG</name>
              <bitOffset>2</bitOffset>
              <bitWidth>1</bitWidth>
            </field>
            <field>
              <name>CFREQ</name>
              <bitOffset>3</bitOffset>
              <bitWidth>1</bitWidth>
            </field>
            <field>
              <name>CCNRDY</name>
              <bitOffset>4</bitOffset>
              <bitWidth>1</bitWidth>
            </field>
            <field>
              <name>CAFSDET</name>
              <bitOffset>5</bitOffset>
              <bitWidth>1</bitWidth>
            </field>
            <field>
              <name>CLFSDET</name>
              <bitOffset>6</bitOffset>
              <bitWidth>1</bitWidth>
            </field>
          </fields>
        </register>
        <register>
          <name>DRA</name>
          <addressOffset>0x20</addressOffset>
          <size>0x20</size>
          <fields>
            <field>
              <name>DATA</name>
              <bitOffset>0</bitOffset>
              <bitWidth>32</bitWidth>
            </field>
          </fields>
        </register>
        <register>
          <name>DRA</name>
          <addressOffset>0x20</addressOffset>
          <size>0x20</size>
          <fields>
            <field>
              <name>DATA</name>
              <bitOffset>0</bitOffset>
              <bitWidth>32</bitWidth>
            </field>
          </fields>
        </register>
        <register>
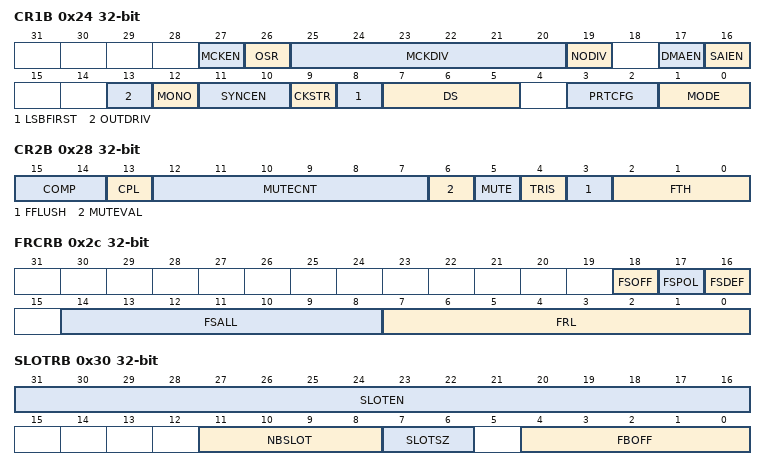
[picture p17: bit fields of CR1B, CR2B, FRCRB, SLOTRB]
          <name>CR1B</name>
          <addressOffset>0x24</addressOffset>
          <size>0x20</size>
          <fields>
            <field>
              <name>MODE</name>
              <bitOffset>0</bitOffset>
              <bitWidth>2</bitWidth>
            </field>
            <field>
              <name>PRTCFG</name>
              <bitOffset>2</bitOffset>
              <bitWidth>2</bitWidth>
            </field>
            <field>
              <name>DS</name>
              <bitOffset>5</bitOffset>
              <bitWidth>3</bitWidth>
            </field>
            <field>
              <name>LSBFIRST</name>
              <bitOffset>8</bitOffset>
              <bitWidth>1</bitWidth>
            </field>
            <field>
              <name>CKSTR</name>
              <bitOffset>9</bitOffset>
              <bitWidth>1</bitWidth>
            </field>
            <field>
              <name>SYNCEN</name>
              <bitOffset>10</bitOffset>
              <bitWidth>2</bitWidth>
            </field>
            <field>
              <name>MONO</name>
              <bitOffset>12</bitOffset>
              <bitWidth>1</bitWidth>
            </field>
            <field>
              <name>OUTDRIV</name>
              <bitOffset>13</bitOffset>
              <bitWidth>1</bitWidth>
            </field>
            <field>
              <name>SAIEN</name>
              <bitOffset>16</bitOffset>
              <bitWidth>1</bitWidth>
            </field>
            <field>
              <name>DMAEN</name>
              <bitOffset>17</bitOffset>
              <bitWidth>1</bitWidth>
            </field>
            <field>
              <name>NODIV</name>
              <bitOffset>19</bitOffset>
              <bitWidth>1</bitWidth>
            </field>
            <field>
              <name>MCKDIV</name>
              <bitOffset>20</bitOffset>
              <bitWidth>6</bitWidth>
            </field>
            <field>
              <name>OSR</name>
              <bitOffset>26</bitOffset>
              <bitWidth>1</bitWidth>
            </field>
            <field>
              <name>MCKEN</name>
              <bitOffset>27</bitOffset>
              <bitWidth>1</bitWidth>
            </field>
          </fields>
        </register>
        <register>
          <name>CR1B</name>
          <addressOffset>0x24</addressOffset>
          <size>0x20</size>
          <fields>
            <field>
              <name>MODE</name>
              <bitOffset>0</bitOffset>
              <bitWidth>2</bitWidth>
            </field>
            <field>
              <name>PRTCFG</name>
              <bitOffset>2</bitOffset>
              <bitWidth>2</bitWidth>
            </field>
            <field>
              <name>DS</name>
              <bitOffset>5</bitOffset>
              <bitWidth>3</bitWidth>
            </field>
            <field>
              <name>LSBFIRST</name>
              <bitOffset>8</bitOffset>
              <bitWidth>1</bitWidth>
            </field>
            <field>
              <name>CKSTR</name>
              <bitOffset>9</bitOffset>
              <bitWidth>1</bitWidth>
            </field>
            <field>
              <name>SYNCEN</name>
              <bitOffset>10</bitOffset>
              <bitWidth>2</bitWidth>
            </field>
            <field>
              <name>MONO</name>
              <bitOffset>12</bitOffset>
              <bitWidth>1</bitWidth>
            </field>
            <field>
              <name>OUTDRIV</name>
              <bitOffset>13</bitOffset>
              <bitWidth>1</bitWidth>
            </field>
            <field>
              <name>SAIEN</name>
              <bitOffset>16</bitOffset>
              <bitWidth>1</bitWidth>
            </field>
            <field>
              <name>DMAEN</name>
              <bitOffset>17</bitOffset>
              <bitWidth>1</bitWidth>
            </field>
            <field>
              <name>NODIV</name>
              <bitOffset>19</bitOffset>
              <bitWidth>1</bitWidth>
            </field>
            <field>
              <name>MCKDIV</name>
              <bitOffset>20</bitOffset>
              <bitWidth>6</bitWidth>
            </field>
            <field>
              <name>OSR</name>
              <bitOffset>26</bitOffset>
              <bitWidth>1</bitWidth>
            </field>
            <field>
              <name>MCKEN</name>
              <bitOffset>27</bitOffset>
              <bitWidth>1</bitWidth>
            </field>
          </fields>
        </register>
        <register>
          <name>CR2B</name>
          <addressOffset>0x28</addressOffset>
          <size>0x20</size>
          <fields>
            <field>
              <name>FTH</name>
              <bitOffset>0</bitOffset>
              <bitWidth>3</bitWidth>
            </field>
            <field>
              <name>FFLUSH</name>
              <bitOffset>3</bitOffset>
              <bitWidth>1</bitWidth>
            </field>
            <field>
              <name>TRIS</name>
              <bitOffset>4</bitOffset>
              <bitWidth>1</bitWidth>
            </field>
            <field>
              <name>MUTE</name>
              <bitOffset>5</bitOffset>
              <bitWidth>1</bitWidth>
            </field>
            <field>
              <name>MUTEVAL</name>
              <bitOffset>6</bitOffset>
              <bitWidth>1</bitWidth>
            </field>
            <field>
              <name>MUTECNT</name>
              <bitOffset>7</bitOffset>
              <bitWidth>6</bitWidth>
            </field>
            <field>
              <name>CPL</name>
              <bitOffset>13</bitOffset>
              <bitWidth>1</bitWidth>
            </field>
            <field>
              <name>COMP</name>
              <bitOffset>14</bitOffset>
              <bitWidth>2</bitWidth>
            </field>
          </fields>
        </register>
        <register>
          <name>CR2B</name>
          <addressOffset>0x28</addressOffset>
          <size>0x20</size>
          <fields>
            <field>
              <name>FTH</name>
              <bitOffset>0</bitOffset>
              <bitWidth>3</bitWidth>
            </field>
            <field>
              <name>FFLUSH</name>
              <bitOffset>3</bitOffset>
              <bitWidth>1</bitWidth>
            </field>
            <field>
              <name>TRIS</name>
              <bitOffset>4</bitOffset>
              <bitWidth>1</bitWidth>
            </field>
            <field>
              <name>MUTE</name>
              <bitOffset>5</bitOffset>
              <bitWidth>1</bitWidth>
            </field>
            <field>
              <name>MUTEVAL</name>
              <bitOffset>6</bitOffset>
              <bitWidth>1</bitWidth>
            </field>
            <field>
              <name>MUTECNT</name>
              <bitOffset>7</bitOffset>
              <bitWidth>6</bitWidth>
            </field>
            <field>
              <name>CPL</name>
              <bitOffset>13</bitOffset>
              <bitWidth>1</bitWidth>
            </field>
            <field>
              <name>COMP</name>
              <bitOffset>14</bitOffset>
              <bitWidth>2</bitWidth>
            </field>
          </fields>
        </register>
        <register>
          <name>FRCRB</name>
          <addressOffset>0x2c</addressOffset>
          <size>0x20</size>
          <fields>
            <field>
              <name>FRL</name>
              <bitOffset>0</bitOffset>
              <bitWidth>8</bitWidth>
            </field>
            <field>
              <name>FSALL</name>
              <bitOffset>8</bitOffset>
              <bitWidth>7</bitWidth>
            </field>
            <field>
              <name>FSDEF</name>
              <bitOffset>16</bitOffset>
              <bitWidth>1</bitWidth>
            </field>
            <field>
              <name>FSPOL</name>
              <bitOffset>17</bitOffset>
              <bitWidth>1</bitWidth>
            </field>
            <field>
              <name>FSOFF</name>
              <bitOffset>18</bitOffset>
              <bitWidth>1</bitWidth>
            </field>
          </fields>
        </register>
        <register>
          <name>FRCRB</name>
          <addressOffset>0x2c</addressOffset>
          <size>0x20</size>
          <fields>
            <field>
              <name>FRL</name>
              <bitOffset>0</bitOffset>
              <bitWidth>8</bitWidth>
            </field>
            <field>
              <name>FSALL</name>
              <bitOffset>8</bitOffset>
              <bitWidth>7</bitWidth>
            </field>
            <field>
              <name>FSDEF</name>
              <bitOffset>16</bitOffset>
              <bitWidth>1</bitWidth>
            </field>
            <field>
              <name>FSPOL</name>
              <bitOffset>17</bitOffset>
              <bitWidth>1</bitWidth>
            </field>
            <field>
              <name>FSOFF</name>
              <bitOffset>18</bitOffset>
              <bitWidth>1</bitWidth>
            </field>
          </fields>
        </register>
        <register>
          <name>SLOTRB</name>
          <addressOffset>0x30</addressOffset>
          <size>0x20</size>
          <fields>
            <field>
              <name>FBOFF</name>
              <bitOffset>0</bitOffset>
              <bitWidth>5</bitWidth>
            </field>
            <field>
              <name>SLOTSZ</name>
              <bitOffset>6</bitOffset>
              <bitWidth>2</bitWidth>
            </field>
            <field>
              <name>NBSLOT</name>
              <bitOffset>8</bitOffset>
              <bitWidth>4</bitWidth>
            </field>
            <field>
              <name>SLOTEN</name>
              <bitOffset>16</bitOffset>
              <bitWidth>16</bitWidth>
            </field>
          </fields>
        </register>
        <register>
          <name>SLOTRB</name>
          <addressOffset>0x30</addressOffset>
          <size>0x20</size>
          <fields>
            <field>
              <name>FBOFF</name>
              <bitOffset>0</bitOffset>
              <bitWidth>5</bitWidth>
            </field>
            <field>
              <name>SLOTSZ</name>
              <bitOffset>6</bitOffset>
              <bitWidth>2</bitWidth>
            </field>
            <field>
              <name>NBSLOT</name>
              <bitOffset>8</bitOffset>
              <bitWidth>4</bitWidth>
            </field>
            <field>
              <name>SLOTEN</name>
              <bitOffset>16</bitOffset>
              <bitWidth>16</bitWidth>
            </field>
          </fields>
        </register>
        <register>
          <name>IMRB</name>
          <addressOffset>0x34</addressOffset>
          <size>0x20</size>
          <fields>
            <field>
              <name>OVRUDRIE</name>
              <bitOffset>0</bitOffset>
              <bitWidth>1</bitWidth>
            </field>
            <field>
              <name>MUTEDETIE</name>
              <bitOffset>1</bitOffset>
              <bitWidth>1</bitWidth>
            </field>
            <field>
              <name>WCKCFGIE</name>
              <bitOffset>2</bitOffset>
              <bitWidth>1</bitWidth>
            </field>
            <field>
              <name>FREQIE</name>
              <bitOffset>3</bitOffset>
              <bitWidth>1</bitWidth>
            </field>
            <field>
              <name>CNRDYIE</name>
              <bitOffset>4</bitOffset>
              <bitWidth>1</bitWidth>
            </field>
            <field>
              <name>AFSDETIE</name>
              <bitOffset>5</bitOffset>
              <bitWidth>1</bitWidth>
            </field>
            <field>
              <name>LFSDETIE</name>
              <bitOffset>6</bitOffset>
              <bitWidth>1</bitWidth>
            </field>
          </fields>
        </register>
        <register>
          <name>IMRB</name>
          <addressOffset>0x34</addressOffset>
          <size>0x20</size>
          <fields>
            <field>
              <name>OVRUDRIE</name>
              <bitOffset>0</bitOffset>
              <bitWidth>1</bitWidth>
            </field>
            <field>
              <name>MUTEDETIE</name>
              <bitOffset>1</bitOffset>
              <bitWidth>1</bitWidth>
            </field>
            <field>
              <name>WCKCFGIE</name>
              <bitOffset>2</bitOffset>
              <bitWidth>1</bitWidth>
            </field>
            <field>
              <name>FREQIE</name>
              <bitOffset>3</bitOffset>
              <bitWidth>1</bitWidth>
            </field>
            <field>
              <name>CNRDYIE</name>
              <bitOffset>4</bitOffset>
              <bitWidth>1</bitWidth>
            </field>
            <field>
              <name>AFSDETIE</name>
              <bitOffset>5</bitOffset>
              <bitWidth>1</bitWidth>
            </field>
            <field>
              <name>LFSDETIE</name>
              <bitOffset>6</bitOffset>
              <bitWidth>1</bitWidth>
            </field>
          </fields>
        </register>
        <register>
          <name>SRB</name>
          <addressOffset>0x38</addressOffset>
          <size>0x20</size>
          <fields>
            <field>
              <name>OVRUDR</name>
              <bitOffset>0</bitOffset>
              <bitWidth>1</bitWidth>
            </field>
            <field>
              <name>MUTEDET</name>
              <bitOffset>1</bitOffset>
              <bitWidth>1</bitWidth>
            </field>
            <field>
              <name>WCKCFG</name>
              <bitOffset>2</bitOffset>
              <bitWidth>1</bitWidth>
            </field>
            <field>
              <name>FREQ</name>
              <bitOffset>3</bitOffset>
              <bitWidth>1</bitWidth>
            </field>
            <field>
              <name>CNRDY</name>
              <bitOffset>4</bitOffset>
              <bitWidth>1</bitWidth>
            </field>
            <field>
              <name>AFSDET</name>
              <bitOffset>5</bitOffset>
              <bitWidth>1</bitWidth>
            </field>
            <field>
              <name>LFSDET</name>
              <bitOffset>6</bitOffset>
              <bitWidth>1</bitWidth>
            </field>
            <field>
              <name>FLVL</name>
              <bitOffset>16</bitOffset>
              <bitWidth>3</bitWidth>
            </field>
          </fields>
        </register>
        <register>
          <name>SRB</name>
          <addressOffset>0x38</addressOffset>
          <size>0x20</size>
          <fields>
            <field>
              <name>OVRUDR</name>
              <bitOffset>0</bitOffset>
              <bitWidth>1</bitWidth>
            </field>
            <field>
              <name>MUTEDET</name>
              <bitOffset>1</bitOffset>
              <bitWidth>1</bitWidth>
            </field>
            <field>
              <name>WCKCFG</name>
              <bitOffset>2</bitOffset>
              <bitWidth>1</bitWidth>
            </field>
            <field>
              <name>FREQ</name>
              <bitOffset>3</bitOffset>
              <bitWidth>1</bitWidth>
            </field>
            <field>
              <name>CNRDY</name>
              <bitOffset>4</bitOffset>
              <bitWidth>1</bitWidth>
            </field>
            <field>
              <name>AFSDET</name>
              <bitOffset>5</bitOffset>
              <bitWidth>1</bitWidth>
            </field>
            <field>
              <name>LFSDET</name>
              <bitOffset>6</bitOffset>
              <bitWidth>1</bitWidth>
            </field>
            <field>
              <name>FLVL</name>
              <bitOffset>16</bitOffset>
              <bitWidth>3</bitWidth>
            </field>
          </fields>
        </register>
        <register>
          <name>CLRFRB</name>
          <addressOffset>0x3c</addressOffset>
          <size>0x20</size>
          <fields>
            <field>
              <name>COVRUDR</name>
              <bitOffset>0</bitOffset>
              <bitWidth>1</bitWidth>
            </field>
            <field>
              <name>CMUTEDET</name>
              <bitOffset>1</bitOffset>
              <bitWidth>1</bitWidth>
            </field>
            <field>
              <name>CWCKCFG</name>
              <bitOffset>2</bitOffset>
              <bitWidth>1</bitWidth>
            </field>
            <field>
              <name>CFREQ</name>
              <bitOffset>3</bitOffset>
              <bitWidth>1</bitWidth>
            </field>
            <field>
              <name>CCNRDY</name>
              <bitOffset>4</bitOffset>
              <bitWidth>1</bitWidth>
            </field>
            <field>
              <name>CAFSDET</name>
              <bitOffset>5</bitOffset>
              <bitWidth>1</bitWidth>
            </field>
            <field>
              <name>CLFSDET</name>
              <bitOffset>6</bitOffset>
              <bitWidth>1</bitWidth>
            </field>
          </fields>
        </register>
        <register>
          <name>CLRFRB</name>
          <addressOffset>0x3c</addressOffset>
          <size>0x20</size>
          <fields>
            <field>
              <name>COVRUDR</name>
              <bitOffset>0</bitOffset>
              <bitWidth>1</bitWidth>
            </field>
            <field>
              <name>CMUTEDET</name>
              <bitOffset>1</bitOffset>
              <bitWidth>1</bitWidth>
            </field>
            <field>
              <name>CWCKCFG</name>
              <bitOffset>2</bitOffset>
              <bitWidth>1</bitWidth>
            </field>
            <field>
              <name>CFREQ</name>
              <bitOffset>3</bitOffset>
              <bitWidth>1</bitWidth>
            </field>
            <field>
              <name>CCNRDY</name>
              <bitOffset>4</bitOffset>
              <bitWidth>1</bitWidth>
            </field>
            <field>
              <name>CAFSDET</name>
              <bitOffset>5</bitOffset>
              <bitWidth>1</bitWidth>
            </field>
            <field>
              <name>CLFSDET</name>
              <bitOffset>6</bitOffset>
              <bitWidth>1</bitWidth>
            </field>
          </fields>
        </register>
        <register>
          <name>DRB</name>
          <addressOffset>0x40</addressOffset>
          <size>0x20</size>
          <fields>
            <field>
              <name>DATA</name>
              <bitOffset>0</bitOffset>
              <bitWidth>32</bitWidth>
            </field>
          </fields>
        </register>
        <register>
          <name>DRB</name>
          <addressOffset>0x40</addressOffset>
          <size>0x20</size>
          <fields>
            <field>
              <name>DATA</name>
              <bitOffset>0</bitOffset>
              <bitWidth>32</bitWidth>
            </field>
          </fields>
        </register>
        <register>
          <name>PDMCR</name>
          <addressOffset>0x44</addressOffset>
          <size>0x20</size>
          <fields>
            <field>
              <name>PDMEN</name>
              <bitOffset>0</bitOffset>
              <bitWidth>1</bitWidth>
            </field>
            <field>
              <name>MICNBR</name>
              <bitOffset>4</bitOffset>
              <bitWidth>2</bitWidth>
            </field>
            <field>
              <name>CKEN1</name>
              <bitOffset>8</bitOffset>
              <bitWidth>1</bitWidth>
            </field>
            <field>
              <name>CKEN2</name>
              <bitOffset>9</bitOffset>
              <bitWidth>1</bitWidth>
            </field>
            <field>
              <name>CKEN3</name>
              <bitOffset>10</bitOffset>
              <bitWidth>1</bitWidth>
            </field>
            <field>
              <name>CKEN4</name>
              <bitOffset>11</bitOffset>
              <bitWidth>1</bitWidth>
            </field>
          </fields>
        </register>
        <register>
          <name>PDMDLY</name>
          <addressOffset>0x48</addressOffset>
          <size>0x20</size>
          <fields>
            <field>
              <name>DLYM1L</name>
              <bitOffset>0</bitOffset>
              <bitWidth>3</bitWidth>
            </field>
            <field>
              <name>DLYM1R</name>
              <bitOffset>4</bitOffset>
              <bitWidth>3</bitWidth>
            </field>
            <field>
              <name>DLYM2L</name>
              <bitOffset>8</bitOffset>
              <bitWidth>3</bitWidth>
            </field>
            <field>
              <name>DLYM2R</name>
              <bitOffset>12</bitOffset>
              <bitWidth>3</bitWidth>
            </field>
            <field>
              <name>DLYM3L</name>
              <bitOffset>16</bitOffset>
              <bitWidth>3</bitWidth>
            </field>
            <field>
              <name>DLYM3R</name>
              <bitOffset>20</bitOffset>
              <bitWidth>3</bitWidth>
            </field>
            <field>
              <name>DLYM4L</name>
              <bitOffset>24</bitOffset>
              <bitWidth>3</bitWidth>
            </field>
            <field>
              <name>DLYM4R</name>
              <bitOffset>28</bitOffset>
              <bitWidth>3</bitWidth>
            </field>
          </fields>
        </register>
      </registers>
    </peripheral>
    <peripheral>
      <name>DTS</name>
      <baseAddress>0x58006800</baseAddress>
      <registers>
        <register>
          <name>CFGR1</name>
          <addressOffset>0x0</addressOffset>
          <size>0x20</size>
          <fields>
            <field>
              <name>TS1_EN</name>
              <bitOffset>0</bitOffset>
              <bitWidth>1</bitWidth>
            </field>
            <field>
              <name>TS1_START</name>
              <bitOffset>4</bitOffset>
              <bitWidth>1</bitWidth>
            </field>
            <field>
              <name>TS1_INTRIG_SEL</name>
              <bitOffset>8</bitOffset>
              <bitWidth>4</bitWidth>
            </field>
            <field>
              <name>TS1_SMP_TIME</name>
              <bitOffset>16</bitOffset>
              <bitWidth>4</bitWidth>
            </field>
            <field>
              <name>REFCLK_SEL</name>
              <bitOffset>20</bitOffset>
              <bitWidth>1</bitWidth>
            </field>
            <field>
              <name>Q_MEAS_OPT</name>
              <bitOffset>21</bitOffset>
              <bitWidth>1</bitWidth>
            </field>
            <field>
              <name>HSREF_CLK_DIV</name>
              <bitOffset>24</bitOffset>
              <bitWidth>7</bitWidth>
            </field>
          </fields>
        </register>
        <register>
          <name>T0VALR1</name>
          <addressOffset>0x8</addressOffset>
          <size>0x20</size>
          <fields>
            <field>
              <name>TS1_FMT0</name>
              <bitOffset>0</bitOffset>
              <bitWidth>16</bitWidth>
            </field>
            <field>
              <name>TS1_T0</name>
              <bitOffset>16</bitOffset>
              <bitWidth>2</bitWidth>
            </field>
          </fields>
        </register>
        <register>
          <name>RAMPVALR</name>
          <addressOffset>0x10</addressOffset>
          <size>0x20</size>
          <fields>
            <field>
              <name>TS1_RAMP_COEFF</name>
              <bitOffset>0</bitOffset>
              <bitWidth>16</bitWidth>
            </field>
          </fields>
        </register>
        <register>
          <name>ITR1</name>
          <addressOffset>0x14</addressOffset>
          <size>0x20</size>
          <fields>
            <field>
              <name>TS1_LITTHD</name>
              <bitOffset>0</bitOffset>
              <bitWidth>16</bitWidth>
            </field>
            <field>
              <name>TS1_HITTHD</name>
              <bitOffset>16</bitOffset>
              <bitWidth>16</bitWidth>
            </field>
          </fields>
        </register>
        <register>
          <name>DR</name>
          <addressOffset>0x1c</addressOffset>
          <size>0x20</size>
          <fields>
            <field>
              <name>TS1_MFREQ</name>
              <bitOffset>0</bitOffset>
              <bitWidth>16</bitWidth>
            </field>
          </fields>
        </register>
        <register>
          <name>SR</name>
          <addressOffset>0x20</addressOffset>
          <size>0x20</size>
          <fields>
            <field>
              <name>TS1_ITEF</name>
              <bitOffset>0</bitOffset>
              <bitWidth>1</bitWidth>
            </field>
            <field>
              <name>TS1_ITLF</name>
              <bitOffset>1</bitOffset>
              <bitWidth>1</bitWidth>
            </field>
            <field>
              <name>TS1_ITHF</name>
              <bitOffset>2</bitOffset>
              <bitWidth>1</bitWidth>
            </field>
            <field>
              <name>TS1_AITEF</name>
              <bitOffset>4</bitOffset>
              <bitWidth>1</bitWidth>
            </field>
            <field>
              <name>TS1_AITLF</name>
              <bitOffset>5</bitOffset>
              <bitWidth>1</bitWidth>
            </field>
            <field>
              <name>TS1_AITHF</name>
              <bitOffset>6</bitOffset>
              <bitWidth>1</bitWidth>
            </field>
            <field>
              <name>TS1_RDY</name>
              <bitOffset>15</bitOffset>
              <bitWidth>1</bitWidth>
            </field>
          </fields>
        </register>
        <register>
          <name>ITENR</name>
          <addressOffset>0x24</addressOffset>
          <size>0x20</size>
          <fields>
            <field>
              <name>TS1_ITEEN</name>
              <bitOffset>0</bitOffset>
              <bitWidth>1</bitWidth>
            </field>
            <field>
              <name>TS1_ITLEN</name>
              <bitOffset>1</bitOffset>
              <bitWidth>1</bitWidth>
            </field>
            <field>
              <name>TS1_ITHEN</name>
              <bitOffset>2</bitOffset>
              <bitWidth>1</bitWidth>
            </field>
            <field>
              <name>TS1_AITEEN</name>
              <bitOffset>4</bitOffset>
              <bitWidth>1</bitWidth>
            </field>
            <field>
              <name>TS1_AITLEN</name>
              <bitOffset>5</bitOffset>
              <bitWidth>1</bitWidth>
            </field>
            <field>
              <name>TS1_AITHEN</name>
              <bitOffset>6</bitOffset>
              <bitWidth>1</bitWidth>
            </field>
          </fields>
        </register>
        <register>
          <name>ICIFR</name>
          <addressOffset>0x28</addressOffset>
          <size>0x20</size>
          <fields>
            <field>
              <name>TS1_CITEF</name>
              <bitOffset>0</bitOffset>
              <bitWidth>1</bitWidth>
            </field>
            <field>
              <name>TS1_CITLF</name>
              <bitOffset>1</bitOffset>
              <bitWidth>1</bitWidth>
            </field>
            <field>
              <name>TS1_CITHF</name>
              <bitOffset>2</bitOffset>
              <bitWidth>1</bitWidth>
            </field>
            <field>
              <name>TS1_CAITEF</name>
              <bitOffset>4</bitOffset>
              <bitWidth>1</bitWidth>
            </field>
            <field>
              <name>TS1_CAITLF</name>
              <bitOffset>5</bitOffset>
              <bitWidth>1</bitWidth>
            </field>
            <field>
              <name>TS1_CAITHF</name>
              <bitOffset>6</bitOffset>
              <bitWidth>1</bitWidth>
            </field>
          </fields>
        </register>
        <register>
          <name>OR</name>
          <addressOffset>0x2c</addressOffset>
          <size>0x20</size>
        </register>
      </registers>
    </peripheral>
    <peripheral>
      <name>GPIOA</name>
      <baseAddress>0x58020000</baseAddress>
      <registers>
        <register>
          <name>MODER</name>
          <addressOffset>0x0</addressOffset>
          <size>0x20</size>
          <fields>
            <field>
              <name>MODE0</name>
              <bitOffset>0</bitOffset>
              <bitWidth>2</bitWidth>
            </field>
            <field>
              <name>MODE1</name>
              <bitOffset>2</bitOffset>
              <bitWidth>2</bitWidth>
            </field>
            <field>
              <name>MODE2</name>
              <bitOffset>4</bitOffset>
              <bitWidth>2</bitWidth>
            </field>
            <field>
              <name>MODE3</name>
              <bitOffset>6</bitOffset>
              <bitWidth>2</bitWidth>
            </field>
            <field>
              <name>MODE4</name>
              <bitOffset>8</bitOffset>
              <bitWidth>2</bitWidth>
            </field>
            <field>
              <name>MODE5</name>
              <bitOffset>10</bitOffset>
              <bitWidth>2</bitWidth>
            </field>
            <field>
              <name>MODE6</name>
              <bitOffset>12</bitOffset>
              <bitWidth>2</bitWidth>
            </field>
            <field>
              <name>MODE7</name>
              <bitOffset>14</bitOffset>
              <bitWidth>2</bitWidth>
            </field>
            <field>
              <name>MODE8</name>
              <bitOffset>16</bitOffset>
              <bitWidth>2</bitWidth>
            </field>
            <field>
              <name>MODE9</name>
              <bitOffset>18</bitOffset>
              <bitWidth>2</bitWidth>
            </field>
            <field>
              <name>MODE10</name>
              <bitOffset>20</bitOffset>
              <bitWidth>2</bitWidth>
            </field>
            <field>
              <name>MODE11</name>
              <bitOffset>22</bitOffset>
              <bitWidth>2</bitWidth>
            </field>
            <field>
              <name>MODE12</name>
              <bitOffset>24</bitOffset>
              <bitWidth>2</bitWidth>
            </field>
            <field>
              <name>MODE13</name>
              <bitOffset>26</bitOffset>
              <bitWidth>2</bitWidth>
            </field>
            <field>
              <name>MODE14</name>
              <bitOffset>28</bitOffset>
              <bitWidth>2</bitWidth>
            </field>
            <field>
              <name>MODE15</name>
              <bitOffset>30</bitOffset>
              <bitWidth>2</bitWidth>
            </field>
          </fields>
        </register>
        <register>
          <name>OTYPER</name>
          <addressOffset>0x4</addressOffset>
          <size>0x20</size>
          <fields>
            <field>
              <name>OT0</name>
              <bitOffset>0</bitOffset>
              <bitWidth>1</bitWidth>
            </field>
            <field>
              <name>OT1</name>
              <bitOffset>1</bitOffset>
              <bitWidth>1</bitWidth>
            </field>
            <field>
              <name>OT2</name>
              <bitOffset>2</bitOffset>
              <bitWidth>1</bitWidth>
            </field>
            <field>
              <name>OT3</name>
              <bitOffset>3</bitOffset>
              <bitWidth>1</bitWidth>
            </field>
            <field>
              <name>OT4</name>
              <bitOffset>4</bitOffset>
              <bitWidth>1</bitWidth>
            </field>
            <field>
              <name>OT5</name>
              <bitOffset>5</bitOffset>
              <bitWidth>1</bitWidth>
            </field>
            <field>
              <name>OT6</name>
              <bitOffset>6</bitOffset>
              <bitWidth>1</bitWidth>
            </field>
            <field>
              <name>OT7</name>
              <bitOffset>7</bitOffset>
              <bitWidth>1</bitWidth>
            </field>
            <field>
              <name>OT8</name>
              <bitOffset>8</bitOffset>
              <bitWidth>1</bitWidth>
            </field>
            <field>
              <name>OT9</name>
              <bitOffset>9</bitOffset>
              <bitWidth>1</bitWidth>
            </field>
            <field>
              <name>OT10</name>
              <bitOffset>10</bitOffset>
              <bitWidth>1</bitWidth>
            </field>
            <field>
              <name>OT11</name>
              <bitOffset>11</bitOffset>
              <bitWidth>1</bitWidth>
            </field>
            <field>
              <name>OT12</name>
              <bitOffset>12</bitOffset>
              <bitWidth>1</bitWidth>
            </field>
            <field>
              <name>OT13</name>
              <bitOffset>13</bitOffset>
              <bitWidth>1</bitWidth>
            </field>
            <field>
              <name>OT14</name>
              <bitOffset>14</bitOffset>
              <bitWidth>1</bitWidth>
            </field>
            <field>
              <name>OT15</name>
              <bitOffset>15</bitOffset>
              <bitWidth>1</bitWidth>
            </field>
          </fields>
        </register>
        <register>
          <name>OSPEEDR</name>
          <addressOffset>0x8</addressOffset>
          <size>0x20</size>
          <fields>
            <field>
              <name>OSPEED0</name>
              <bitOffset>0</bitOffset>
              <bitWidth>2</bitWidth>
            </field>
            <field>
              <name>OSPEED1</name>
              <bitOffset>2</bitOffset>
              <bitWidth>2</bitWidth>
            </field>
            <field>
              <name>OSPEED2</name>
              <bitOffset>4</bitOffset>
              <bitWidth>2</bitWidth>
            </field>
            <field>
              <name>OSPEED3</name>
              <bitOffset>6</bitOffset>
              <bitWidth>2</bitWidth>
            </field>
            <field>
              <name>OSPEED4</name>
              <bitOffset>8</bitOffset>
              <bitWidth>2</bitWidth>
            </field>
            <field>
              <name>OSPEED5</name>
              <bitOffset>10</bitOffset>
              <bitWidth>2</bitWidth>
            </field>
            <field>
              <name>OSPEED6</name>
              <bitOffset>12</bitOffset>
              <bitWidth>2</bitWidth>
            </field>
            <field>
              <name>OSPEED7</name>
              <bitOffset>14</bitOffset>
              <bitWidth>2</bitWidth>
            </field>
            <field>
              <name>OSPEED8</name>
              <bitOffset>16</bitOffset>
              <bitWidth>2</bitWidth>
            </field>
            <field>
              <name>OSPEED9</name>
              <bitOffset>18</bitOffset>
              <bitWidth>2</bitWidth>
            </field>
            <field>
              <name>OSPEED10</name>
              <bitOffset>20</bitOffset>
              <bitWidth>2</bitWidth>
            </field>
            <field>
              <name>OSPEED11</name>
              <bitOffset>22</bitOffset>
              <bitWidth>2</bitWidth>
            </field>
            <field>
              <name>OSPEED12</name>
              <bitOffset>24</bitOffset>
              <bitWidth>2</bitWidth>
            </field>
            <field>
              <name>OSPEED13</name>
              <bitOffset>26</bitOffset>
              <bitWidth>2</bitWidth>
            </field>
            <field>
              <name>OSPEED14</name>
              <bitOffset>28</bitOffset>
              <bitWidth>2</bitWidth>
            </field>
            <field>
              <name>OSPEED15</name>
              <bitOffset>30</bitOffset>
              <bitWidth>2</bitWidth>
            </field>
          </fields>
        </register>
        <register>
          <name>PUPDR</name>
          <addressOffset>0xc</addressOffset>
          <size>0x20</size>
          <fields>
            <field>
              <name>PUPD0</name>
              <bitOffset>0</bitOffset>
              <bitWidth>2</bitWidth>
            </field>
            <field>
              <name>PUPD1</name>
              <bitOffset>2</bitOffset>
              <bitWidth>2</bitWidth>
            </field>
            <field>
              <name>PUPD2</name>
              <bitOffset>4</bitOffset>
              <bitWidth>2</bitWidth>
            </field>
            <field>
              <name>PUPD3</name>
              <bitOffset>6</bitOffset>
              <bitWidth>2</bitWidth>
            </field>
            <field>
              <name>PUPD4</name>
              <bitOffset>8</bitOffset>
              <bitWidth>2</bitWidth>
            </field>
            <field>
              <name>PUPD5</name>
              <bitOffset>10</bitOffset>
              <bitWidth>2</bitWidth>
            </field>
            <field>
              <name>PUPD6</name>
              <bitOffset>12</bitOffset>
              <bitWidth>2</bitWidth>
            </field>
            <field>
              <name>PUPD7</name>
              <bitOffset>14</bitOffset>
              <bitWidth>2</bitWidth>
            </field>
            <field>
              <name>PUPD8</name>
              <bitOffset>16</bitOffset>
              <bitWidth>2</bitWidth>
            </field>
            <field>
              <name>PUPD9</name>
              <bitOffset>18</bitOffset>
              <bitWidth>2</bitWidth>
            </field>
            <field>
              <name>PUPD10</name>
              <bitOffset>20</bitOffset>
              <bitWidth>2</bitWidth>
            </field>
            <field>
              <name>PUPD11</name>
              <bitOffset>22</bitOffset>
              <bitWidth>2</bitWidth>
            </field>
            <field>
              <name>PUPD12</name>
              <bitOffset>24</bitOffset>
              <bitWidth>2</bitWidth>
            </field>
            <field>
              <name>PUPD13</name>
              <bitOffset>26</bitOffset>
              <bitWidth>2</bitWidth>
            </field>
            <field>
              <name>PUPD14</name>
              <bitOffset>28</bitOffset>
              <bitWidth>2</bitWidth>
            </field>
            <field>
              <name>PUPD15</name>
              <bitOffset>30</bitOffset>
              <bitWidth>2</bitWidth>
            </field>
          </fields>
        </register>
        <register>
          <name>IDR</name>
          <addressOffset>0x10</addressOffset>
          <size>0x20</size>
          <fields>
            <field>
              <name>ID0</name>
              <bitOffset>0</bitOffset>
              <bitWidth>1</bitWidth>
            </field>
            <field>
              <name>ID1</name>
              <bitOffset>1</bitOffset>
              <bitWidth>1</bitWidth>
            </field>
            <field>
              <name>ID2</name>
              <bitOffset>2</bitOffset>
              <bitWidth>1</bitWidth>
            </field>
            <field>
              <name>ID3</name>
              <bitOffset>3</bitOffset>
              <bitWidth>1</bitWidth>
            </field>
            <field>
              <name>ID4</name>
              <bitOffset>4</bitOffset>
              <bitWidth>1</bitWidth>
            </field>
            <field>
              <name>ID5</name>
              <bitOffset>5</bitOffset>
              <bitWidth>1</bitWidth>
            </field>
            <field>
              <name>ID6</name>
              <bitOffset>6</bitOffset>
              <bitWidth>1</bitWidth>
            </field>
            <field>
              <name>ID7</name>
              <bitOffset>7</bitOffset>
              <bitWidth>1</bitWidth>
            </field>
            <field>
              <name>ID8</name>
              <bitOffset>8</bitOffset>
              <bitWidth>1</bitWidth>
            </field>
            <field>
              <name>ID9</name>
              <bitOffset>9</bitOffset>
              <bitWidth>1</bitWidth>
            </field>
            <field>
              <name>ID10</name>
              <bitOffset>10</bitOffset>
              <bitWidth>1</bitWidth>
            </field>
            <field>
              <name>ID11</name>
              <bitOffset>11</bitOffset>
              <bitWidth>1</bitWidth>
            </field>
            <field>
              <name>ID12</name>
              <bitOffset>12</bitOffset>
              <bitWidth>1</bitWidth>
            </field>
            <field>
              <name>ID13</name>
              <bitOffset>13</bitOffset>
              <bitWidth>1</bitWidth>
            </field>
            <field>
              <name>ID14</name>
              <bitOffset>14</bitOffset>
              <bitWidth>1</bitWidth>
            </field>
            <field>
              <name>ID15</name>
              <bitOffset>15</bitOffset>
              <bitWidth>1</bitWidth>
            </field>
          </fields>
        </register>
        <register>
          <name>ODR</name>
          <addressOffset>0x14</addressOffset>
          <size>0x20</size>
          <fields>
            <field>
              <name>OD0</name>
              <bitOffset>0</bitOffset>
              <bitWidth>1</bitWidth>
            </field>
            <field>
              <name>OD1</name>
              <bitOffset>1</bitOffset>
              <bitWidth>1</bitWidth>
            </field>
            <field>
              <name>OD2</name>
              <bitOffset>2</bitOffset>
              <bitWidth>1</bitWidth>
            </field>
            <field>
              <name>OD3</name>
              <bitOffset>3</bitOffset>
              <bitWidth>1</bitWidth>
            </field>
            <field>
              <name>OD4</name>
              <bitOffset>4</bitOffset>
              <bitWidth>1</bitWidth>
            </field>
            <field>
              <name>OD5</name>
              <bitOffset>5</bitOffset>
              <bitWidth>1</bitWidth>
            </field>
            <field>
              <name>OD6</name>
              <bitOffset>6</bitOffset>
              <bitWidth>1</bitWidth>
            </field>
            <field>
              <name>OD7</name>
              <bitOffset>7</bitOffset>
              <bitWidth>1</bitWidth>
            </field>
            <field>
              <name>OD8</name>
              <bitOffset>8</bitOffset>
              <bitWidth>1</bitWidth>
            </field>
            <field>
              <name>OD9</name>
              <bitOffset>9</bitOffset>
              <bitWidth>1</bitWidth>
            </field>
            <field>
              <name>OD10</name>
              <bitOffset>10</bitOffset>
              <bitWidth>1</bitWidth>
            </field>
            <field>
              <name>OD11</name>
              <bitOffset>11</bitOffset>
              <bitWidth>1</bitWidth>
            </field>
            <field>
              <name>OD12</name>
              <bitOffset>12</bitOffset>
              <bitWidth>1</bitWidth>
            </field>
            <field>
              <name>OD13</name>
              <bitOffset>13</bitOffset>
              <bitWidth>1</bitWidth>
            </field>
            <field>
              <name>OD14</name>
              <bitOffset>14</bitOffset>
              <bitWidth>1</bitWidth>
            </field>
            <field>
              <name>OD15</name>
              <bitOffset>15</bitOffset>
              <bitWidth>1</bitWidth>
            </field>
          </fields>
        </register>
        <register>
          <name>BSRR</name>
          <addressOffset>0x18</addressOffset>
          <size>0x20</size>
          <fields>
            <field>
              <name>BS0</name>
              <bitOffset>0</bitOffset>
              <bitWidth>1</bitWidth>
            </field>
            <field>
              <name>BS1</name>
              <bitOffset>1</bitOffset>
              <bitWidth>1</bitWidth>
            </field>
            <field>
              <name>BS2</name>
              <bitOffset>2</bitOffset>
              <bitWidth>1</bitWidth>
            </field>
            <field>
              <name>BS3</name>
              <bitOffset>3</bitOffset>
              <bitWidth>1</bitWidth>
            </field>
            <field>
              <name>BS4</name>
              <bitOffset>4</bitOffset>
              <bitWidth>1</bitWidth>
            </field>
            <field>
              <name>BS5</name>
              <bitOffset>5</bitOffset>
              <bitWidth>1</bitWidth>
            </field>
            <field>
              <name>BS6</name>
              <bitOffset>6</bitOffset>
              <bitWidth>1</bitWidth>
            </field>
            <field>
              <name>BS7</name>
              <bitOffset>7</bitOffset>
              <bitWidth>1</bitWidth>
            </field>
            <field>
              <name>BS8</name>
              <bitOffset>8</bitOffset>
              <bitWidth>1</bitWidth>
            </field>
            <field>
              <name>BS9</name>
              <bitOffset>9</bitOffset>
              <bitWidth>1</bitWidth>
            </field>
            <field>
              <name>BS10</name>
              <bitOffset>10</bitOffset>
              <bitWidth>1</bitWidth>
            </field>
            <field>
              <name>BS11</name>
              <bitOffset>11</bitOffset>
              <bitWidth>1</bitWidth>
            </field>
            <field>
              <name>BS12</name>
              <bitOffset>12</bitOffset>
              <bitWidth>1</bitWidth>
            </field>
            <field>
              <name>BS13</name>
              <bitOffset>13</bitOffset>
              <bitWidth>1</bitWidth>
            </field>
            <field>
              <name>BS14</name>
              <bitOffset>14</bitOffset>
              <bitWidth>1</bitWidth>
            </field>
            <field>
              <name>BS15</name>
              <bitOffset>15</bitOffset>
              <bitWidth>1</bitWidth>
            </field>
            <field>
              <name>BR0</name>
              <bitOffset>16</bitOffset>
              <bitWidth>1</bitWidth>
            </field>
            <field>
              <name>BR1</name>
              <bitOffset>17</bitOffset>
              <bitWidth>1</bitWidth>
            </field>
            <field>
              <name>BR2</name>
              <bitOffset>18</bitOffset>
              <bitWidth>1</bitWidth>
            </field>
            <field>
              <name>BR3</name>
              <bitOffset>19</bitOffset>
              <bitWidth>1</bitWidth>
            </field>
            <field>
              <name>BR4</name>
              <bitOffset>20</bitOffset>
              <bitWidth>1</bitWidth>
            </field>
            <field>
              <name>BR5</name>
              <bitOffset>21</bitOffset>
              <bitWidth>1</bitWidth>
            </field>
            <field>
              <name>BR6</name>
              <bitOffset>22</bitOffset>
              <bitWidth>1</bitWidth>
            </field>
            <field>
              <name>BR7</name>
              <bitOffset>23</bitOffset>
              <bitWidth>1</bitWidth>
            </field>
            <field>
              <name>BR8</name>
              <bitOffset>24</bitOffset>
              <bitWidth>1</bitWidth>
            </field>
            <field>
              <name>BR9</name>
              <bitOffset>25</bitOffset>
              <bitWidth>1</bitWidth>
            </field>
            <field>
              <name>BR10</name>
              <bitOffset>26</bitOffset>
              <bitWidth>1</bitWidth>
            </field>
            <field>
              <name>BR11</name>
              <bitOffset>27</bitOffset>
              <bitWidth>1</bitWidth>
            </field>
            <field>
              <name>BR12</name>
              <bitOffset>28</bitOffset>
              <bitWidth>1</bitWidth>
            </field>
            <field>
              <name>BR13</name>
              <bitOffset>29</bitOffset>
              <bitWidth>1</bitWidth>
            </field>
            <field>
              <name>BR14</name>
              <bitOffset>30</bitOffset>
              <bitWidth>1</bitWidth>
            </field>
            <field>
              <name>BR15</name>
              <bitOffset>31</bitOffset>
              <bitWidth>1</bitWidth>
            </field>
          </fields>
        </register>
        <register>
          <name>LCKR</name>
          <addressOffset>0x1c</addressOffset>
          <size>0x20</size>
          <fields>
            <field>
              <name>LCK0</name>
              <bitOffset>0</bitOffset>
              <bitWidth>1</bitWidth>
            </field>
            <field>
              <name>LCK1</name>
              <bitOffset>1</bitOffset>
              <bitWidth>1</bitWidth>
            </field>
            <field>
              <name>LCK2</name>
              <bitOffset>2</bitOffset>
              <bitWidth>1</bitWidth>
            </field>
            <field>
              <name>LCK3</name>
              <bitOffset>3</bitOffset>
              <bitWidth>1</bitWidth>
            </field>
            <field>
              <name>LCK4</name>
              <bitOffset>4</bitOffset>
              <bitWidth>1</bitWidth>
            </field>
            <field>
              <name>LCK5</name>
              <bitOffset>5</bitOffset>
              <bitWidth>1</bitWidth>
            </field>
            <field>
              <name>LCK6</name>
              <bitOffset>6</bitOffset>
              <bitWidth>1</bitWidth>
            </field>
            <field>
              <name>LCK7</name>
              <bitOffset>7</bitOffset>
              <bitWidth>1</bitWidth>
            </field>
            <field>
              <name>LCK8</name>
              <bitOffset>8</bitOffset>
              <bitWidth>1</bitWidth>
            </field>
            <field>
              <name>LCK9</name>
              <bitOffset>9</bitOffset>
              <bitWidth>1</bitWidth>
            </field>
            <field>
              <name>LCK10</name>
              <bitOffset>10</bitOffset>
              <bitWidth>1</bitWidth>
            </field>
            <field>
              <name>LCK11</name>
              <bitOffset>11</bitOffset>
              <bitWidth>1</bitWidth>
            </field>
            <field>
              <name>LCK12</name>
              <bitOffset>12</bitOffset>
              <bitWidth>1</bitWidth>
            </field>
            <field>
              <name>LCK13</name>
              <bitOffset>13</bitOffset>
              <bitWidth>1</bitWidth>
            </field>
            <field>
              <name>LCK14</name>
              <bitOffset>14</bitOffset>
              <bitWidth>1</bitWidth>
            </field>
            <field>
              <name>LCK15</name>
              <bitOffset>15</bitOffset>
              <bitWidth>1</bitWidth>
            </field>
            <field>
              <name>LCKK</name>
              <bitOffset>16</bitOffset>
              <bitWidth>1</bitWidth>
            </field>
          </fields>
        </register>
        <register>
          <name>AFR.0</name>
          <addressOffset>0x20</addressOffset>
          <size>0x20</size>
          <fields>
            <field>
              <name>AFSEL0</name>
              <bitOffset>0</bitOffset>
              <bitWidth>4</bitWidth>
            </field>
            <field>
              <name>AFSEL1</name>
              <bitOffset>4</bitOffset>
              <bitWidth>4</bitWidth>
            </field>
            <field>
              <name>AFSEL2</name>
              <bitOffset>8</bitOffset>
              <bitWidth>4</bitWidth>
            </field>
            <field>
              <name>AFSEL3</name>
              <bitOffset>12</bitOffset>
              <bitWidth>4</bitWidth>
            </field>
            <field>
              <name>AFSEL4</name>
              <bitOffset>16</bitOffset>
              <bitWidth>4</bitWidth>
            </field>
            <field>
              <name>AFSEL5</name>
              <bitOffset>20</bitOffset>
              <bitWidth>4</bitWidth>
            </field>
            <field>
              <name>AFSEL6</name>
              <bitOffset>24</bitOffset>
              <bitWidth>4</bitWidth>
            </field>
            <field>
              <name>AFSEL7</name>
              <bitOffset>28</bitOffset>
              <bitWidth>4</bitWidth>
            </field>
          </fields>
        </register>
        <register>
          <name>AFR.1</name>
          <addressOffset>0x24</addressOffset>
          <size>0x20</size>
          <fields>
            <field>
              <name>AFSEL8</name>
              <bitOffset>0</bitOffset>
              <bitWidth>4</bitWidth>
            </field>
            <field>
              <name>AFSEL9</name>
              <bitOffset>4</bitOffset>
              <bitWidth>4</bitWidth>
            </field>
            <field>
              <name>AFSEL10</name>
              <bitOffset>8</bitOffset>
              <bitWidth>4</bitWidth>
            </field>
            <field>
              <name>AFSEL11</name>
              <bitOffset>12</bitOffset>
              <bitWidth>4</bitWidth>
            </field>
            <field>
              <name>AFSEL12</name>
              <bitOffset>16</bitOffset>
              <bitWidth>4</bitWidth>
            </field>
            <field>
              <name>AFSEL13</name>
              <bitOffset>20</bitOffset>
              <bitWidth>4</bitWidth>
            </field>
            <field>
              <name>AFSEL14</name>
              <bitOffset>24</bitOffset>
              <bitWidth>4</bitWidth>
            </field>
            <field>
              <name>AFSEL15</name>
              <bitOffset>28</bitOffset>
              <bitWidth>4</bitWidth>
            </field>
          </fields>
        </register>
      </registers>
    </peripheral>
    <peripheral>
      <name>GPIOB</name>
      <baseAddress>0x58020400</baseAddress>
      <registers>
        <register>
          <name>MODER</name>
          <addressOffset>0x0</addressOffset>
          <size>0x20</size>
          <fields>
            <field>
              <name>MODE0</name>
              <bitOffset>0</bitOffset>
              <bitWidth>2</bitWidth>
            </field>
            <field>
              <name>MODE1</name>
              <bitOffset>2</bitOffset>
              <bitWidth>2</bitWidth>
            </field>
            <field>
              <name>MODE2</name>
              <bitOffset>4</bitOffset>
              <bitWidth>2</bitWidth>
            </field>
            <field>
              <name>MODE3</name>
              <bitOffset>6</bitOffset>
              <bitWidth>2</bitWidth>
            </field>
            <field>
              <name>MODE4</name>
              <bitOffset>8</bitOffset>
              <bitWidth>2</bitWidth>
            </field>
            <field>
              <name>MODE5</name>
              <bitOffset>10</bitOffset>
              <bitWidth>2</bitWidth>
            </field>
            <field>
              <name>MODE6</name>
              <bitOffset>12</bitOffset>
              <bitWidth>2</bitWidth>
            </field>
            <field>
              <name>MODE7</name>
              <bitOffset>14</bitOffset>
              <bitWidth>2</bitWidth>
            </field>
            <field>
              <name>MODE8</name>
              <bitOffset>16</bitOffset>
              <bitWidth>2</bitWidth>
            </field>
            <field>
              <name>MODE9</name>
              <bitOffset>18</bitOffset>
              <bitWidth>2</bitWidth>
            </field>
            <field>
              <name>MODE10</name>
              <bitOffset>20</bitOffset>
              <bitWidth>2</bitWidth>
            </field>
            <field>
              <name>MODE11</name>
              <bitOffset>22</bitOffset>
              <bitWidth>2</bitWidth>
            </field>
            <field>
              <name>MODE12</name>
              <bitOffset>24</bitOffset>
              <bitWidth>2</bitWidth>
            </field>
            <field>
              <name>MODE13</name>
              <bitOffset>26</bitOffset>
              <bitWidth>2</bitWidth>
            </field>
            <field>
              <name>MODE14</name>
              <bitOffset>28</bitOffset>
              <bitWidth>2</bitWidth>
            </field>
            <field>
              <name>MODE15</name>
              <bitOffset>30</bitOffset>
              <bitWidth>2</bitWidth>
            </field>
          </fields>
        </register>
        <register>
          <name>OTYPER</name>
          <addressOffset>0x4</addressOffset>
          <size>0x20</size>
          <fields>
            <field>
              <name>OT0</name>
              <bitOffset>0</bitOffset>
              <bitWidth>1</bitWidth>
            </field>
            <field>
              <name>OT1</name>
              <bitOffset>1</bitOffset>
              <bitWidth>1</bitWidth>
            </field>
            <field>
              <name>OT2</name>
              <bitOffset>2</bitOffset>
              <bitWidth>1</bitWidth>
            </field>
            <field>
              <name>OT3</name>
              <bitOffset>3</bitOffset>
              <bitWidth>1</bitWidth>
            </field>
            <field>
              <name>OT4</name>
              <bitOffset>4</bitOffset>
              <bitWidth>1</bitWidth>
            </field>
            <field>
              <name>OT5</name>
              <bitOffset>5</bitOffset>
              <bitWidth>1</bitWidth>
            </field>
            <field>
              <name>OT6</name>
              <bitOffset>6</bitOffset>
              <bitWidth>1</bitWidth>
            </field>
            <field>
              <name>OT7</name>
              <bitOffset>7</bitOffset>
              <bitWidth>1</bitWidth>
            </field>
            <field>
              <name>OT8</name>
              <bitOffset>8</bitOffset>
              <bitWidth>1</bitWidth>
            </field>
            <field>
              <name>OT9</name>
              <bitOffset>9</bitOffset>
              <bitWidth>1</bitWidth>
            </field>
            <field>
              <name>OT10</name>
              <bitOffset>10</bitOffset>
              <bitWidth>1</bitWidth>
            </field>
            <field>
              <name>OT11</name>
              <bitOffset>11</bitOffset>
              <bitWidth>1</bitWidth>
            </field>
            <field>
              <name>OT12</name>
              <bitOffset>12</bitOffset>
              <bitWidth>1</bitWidth>
            </field>
            <field>
              <name>OT13</name>
              <bitOffset>13</bitOffset>
              <bitWidth>1</bitWidth>
            </field>
            <field>
              <name>OT14</name>
              <bitOffset>14</bitOffset>
              <bitWidth>1</bitWidth>
            </field>
            <field>
              <name>OT15</name>
              <bitOffset>15</bitOffset>
              <bitWidth>1</bitWidth>
            </field>
          </fields>
        </register>
        <register>
          <name>OSPEEDR</name>
          <addressOffset>0x8</addressOffset>
          <size>0x20</size>
          <fields>
            <field>
              <name>OSPEED0</name>
              <bitOffset>0</bitOffset>
              <bitWidth>2</bitWidth>
            </field>
            <field>
              <name>OSPEED1</name>
              <bitOffset>2</bitOffset>
              <bitWidth>2</bitWidth>
            </field>
            <field>
              <name>OSPEED2</name>
              <bitOffset>4</bitOffset>
              <bitWidth>2</bitWidth>
            </field>
            <field>
              <name>OSPEED3</name>
              <bitOffset>6</bitOffset>
              <bitWidth>2</bitWidth>
            </field>
            <field>
              <name>OSPEED4</name>
              <bitOffset>8</bitOffset>
              <bitWidth>2</bitWidth>
            </field>
            <field>
              <name>OSPEED5</name>
              <bitOffset>10</bitOffset>
              <bitWidth>2</bitWidth>
            </field>
            <field>
              <name>OSPEED6</name>
              <bitOffset>12</bitOffset>
              <bitWidth>2</bitWidth>
            </field>
            <field>
              <name>OSPEED7</name>
              <bitOffset>14</bitOffset>
              <bitWidth>2</bitWidth>
            </field>
            <field>
              <name>OSPEED8</name>
              <bitOffset>16</bitOffset>
              <bitWidth>2</bitWidth>
            </field>
            <field>
              <name>OSPEED9</name>
              <bitOffset>18</bitOffset>
              <bitWidth>2</bitWidth>
            </field>
            <field>
              <name>OSPEED10</name>
              <bitOffset>20</bitOffset>
              <bitWidth>2</bitWidth>
            </field>
            <field>
              <name>OSPEED11</name>
              <bitOffset>22</bitOffset>
              <bitWidth>2</bitWidth>
            </field>
            <field>
              <name>OSPEED12</name>
              <bitOffset>24</bitOffset>
              <bitWidth>2</bitWidth>
            </field>
            <field>
              <name>OSPEED13</name>
              <bitOffset>26</bitOffset>
              <bitWidth>2</bitWidth>
            </field>
            <field>
              <name>OSPEED14</name>
              <bitOffset>28</bitOffset>
              <bitWidth>2</bitWidth>
            </field>
            <field>
              <name>OSPEED15</name>
              <bitOffset>30</bitOffset>
              <bitWidth>2</bitWidth>
            </field>
          </fields>
        </register>
        <register>
          <name>PUPDR</name>
          <addressOffset>0xc</addressOffset>
          <size>0x20</size>
          <fields>
            <field>
              <name>PUPD0</name>
              <bitOffset>0</bitOffset>
              <bitWidth>2</bitWidth>
            </field>
            <field>
              <name>PUPD1</name>
              <bitOffset>2</bitOffset>
              <bitWidth>2</bitWidth>
            </field>
            <field>
              <name>PUPD2</name>
              <bitOffset>4</bitOffset>
              <bitWidth>2</bitWidth>
            </field>
            <field>
              <name>PUPD3</name>
              <bitOffset>6</bitOffset>
              <bitWidth>2</bitWidth>
            </field>
            <field>
              <name>PUPD4</name>
              <bitOffset>8</bitOffset>
              <bitWidth>2</bitWidth>
            </field>
            <field>
              <name>PUPD5</name>
              <bitOffset>10</bitOffset>
              <bitWidth>2</bitWidth>
            </field>
            <field>
              <name>PUPD6</name>
              <bitOffset>12</bitOffset>
              <bitWidth>2</bitWidth>
            </field>
            <field>
              <name>PUPD7</name>
              <bitOffset>14</bitOffset>
              <bitWidth>2</bitWidth>
            </field>
            <field>
              <name>PUPD8</name>
              <bitOffset>16</bitOffset>
              <bitWidth>2</bitWidth>
            </field>
            <field>
              <name>PUPD9</name>
              <bitOffset>18</bitOffset>
              <bitWidth>2</bitWidth>
            </field>
            <field>
              <name>PUPD10</name>
              <bitOffset>20</bitOffset>
              <bitWidth>2</bitWidth>
            </field>
            <field>
              <name>PUPD11</name>
              <bitOffset>22</bitOffset>
              <bitWidth>2</bitWidth>
            </field>
            <field>
              <name>PUPD12</name>
              <bitOffset>24</bitOffset>
              <bitWidth>2</bitWidth>
            </field>
            <field>
              <name>PUPD13</name>
              <bitOffset>26</bitOffset>
              <bitWidth>2</bitWidth>
            </field>
            <field>
              <name>PUPD14</name>
              <bitOffset>28</bitOffset>
              <bitWidth>2</bitWidth>
            </field>
            <field>
              <name>PUPD15</name>
              <bitOffset>30</bitOffset>
              <bitWidth>2</bitWidth>
            </field>
          </fields>
        </register>
        <register>
          <name>IDR</name>
          <addressOffset>0x10</addressOffset>
          <size>0x20</size>
          <fields>
            <field>
              <name>ID0</name>
              <bitOffset>0</bitOffset>
              <bitWidth>1</bitWidth>
            </field>
            <field>
              <name>ID1</name>
              <bitOffset>1</bitOffset>
              <bitWidth>1</bitWidth>
            </field>
            <field>
              <name>ID2</name>
              <bitOffset>2</bitOffset>
              <bitWidth>1</bitWidth>
            </field>
            <field>
              <name>ID3</name>
              <bitOffset>3</bitOffset>
              <bitWidth>1</bitWidth>
            </field>
            <field>
              <name>ID4</name>
              <bitOffset>4</bitOffset>
              <bitWidth>1</bitWidth>
            </field>
            <field>
              <name>ID5</name>
              <bitOffset>5</bitOffset>
              <bitWidth>1</bitWidth>
            </field>
            <field>
              <name>ID6</name>
              <bitOffset>6</bitOffset>
              <bitWidth>1</bitWidth>
            </field>
            <field>
              <name>ID7</name>
              <bitOffset>7</bitOffset>
              <bitWidth>1</bitWidth>
            </field>
            <field>
              <name>ID8</name>
              <bitOffset>8</bitOffset>
              <bitWidth>1</bitWidth>
            </field>
            <field>
              <name>ID9</name>
              <bitOffset>9</bitOffset>
              <bitWidth>1</bitWidth>
            </field>
            <field>
              <name>ID10</name>
              <bitOffset>10</bitOffset>
              <bitWidth>1</bitWidth>
            </field>
            <field>
              <name>ID11</name>
              <bitOffset>11</bitOffset>
              <bitWidth>1</bitWidth>
            </field>
            <field>
              <name>ID12</name>
              <bitOffset>12</bitOffset>
              <bitWidth>1</bitWidth>
            </field>
            <field>
              <name>ID13</name>
              <bitOffset>13</bitOffset>
              <bitWidth>1</bitWidth>
            </field>
            <field>
              <name>ID14</name>
              <bitOffset>14</bitOffset>
              <bitWidth>1</bitWidth>
            </field>
            <field>
              <name>ID15</name>
              <bitOffset>15</bitOffset>
              <bitWidth>1</bitWidth>
            </field>
          </fields>
        </register>
        <register>
          <name>ODR</name>
          <addressOffset>0x14</addressOffset>
          <size>0x20</size>
          <fields>
            <field>
              <name>OD0</name>
              <bitOffset>0</bitOffset>
              <bitWidth>1</bitWidth>
            </field>
            <field>
              <name>OD1</name>
              <bitOffset>1</bitOffset>
              <bitWidth>1</bitWidth>
            </field>
            <field>
              <name>OD2</name>
              <bitOffset>2</bitOffset>
              <bitWidth>1</bitWidth>
            </field>
            <field>
              <name>OD3</name>
              <bitOffset>3</bitOffset>
              <bitWidth>1</bitWidth>
            </field>
            <field>
              <name>OD4</name>
              <bitOffset>4</bitOffset>
              <bitWidth>1</bitWidth>
            </field>
            <field>
              <name>OD5</name>
              <bitOffset>5</bitOffset>
              <bitWidth>1</bitWidth>
            </field>
            <field>
              <name>OD6</name>
              <bitOffset>6</bitOffset>
              <bitWidth>1</bitWidth>
            </field>
            <field>
              <name>OD7</name>
              <bitOffset>7</bitOffset>
              <bitWidth>1</bitWidth>
            </field>
            <field>
              <name>OD8</name>
              <bitOffset>8</bitOffset>
              <bitWidth>1</bitWidth>
            </field>
            <field>
              <name>OD9</name>
              <bitOffset>9</bitOffset>
              <bitWidth>1</bitWidth>
            </field>
            <field>
              <name>OD10</name>
              <bitOffset>10</bitOffset>
              <bitWidth>1</bitWidth>
            </field>
            <field>
              <name>OD11</name>
              <bitOffset>11</bitOffset>
              <bitWidth>1</bitWidth>
            </field>
            <field>
              <name>OD12</name>
              <bitOffset>12</bitOffset>
              <bitWidth>1</bitWidth>
            </field>
            <field>
              <name>OD13</name>
              <bitOffset>13</bitOffset>
              <bitWidth>1</bitWidth>
            </field>
            <field>
              <name>OD14</name>
              <bitOffset>14</bitOffset>
              <bitWidth>1</bitWidth>
            </field>
            <field>
              <name>OD15</name>
              <bitOffset>15</bitOffset>
              <bitWidth>1</bitWidth>
            </field>
          </fields>
        </register>
        <register>
          <name>BSRR</name>
          <addressOffset>0x18</addressOffset>
          <size>0x20</size>
          <fields>
            <field>
              <name>BS0</name>
              <bitOffset>0</bitOffset>
              <bitWidth>1</bitWidth>
            </field>
            <field>
              <name>BS1</name>
              <bitOffset>1</bitOffset>
              <bitWidth>1</bitWidth>
            </field>
            <field>
              <name>BS2</name>
              <bitOffset>2</bitOffset>
              <bitWidth>1</bitWidth>
            </field>
            <field>
              <name>BS3</name>
              <bitOffset>3</bitOffset>
              <bitWidth>1</bitWidth>
            </field>
            <field>
              <name>BS4</name>
              <bitOffset>4</bitOffset>
              <bitWidth>1</bitWidth>
            </field>
            <field>
              <name>BS5</name>
              <bitOffset>5</bitOffset>
              <bitWidth>1</bitWidth>
            </field>
            <field>
              <name>BS6</name>
              <bitOffset>6</bitOffset>
              <bitWidth>1</bitWidth>
            </field>
            <field>
              <name>BS7</name>
              <bitOffset>7</bitOffset>
              <bitWidth>1</bitWidth>
            </field>
            <field>
              <name>BS8</name>
              <bitOffset>8</bitOffset>
              <bitWidth>1</bitWidth>
            </field>
            <field>
              <name>BS9</name>
              <bitOffset>9</bitOffset>
              <bitWidth>1</bitWidth>
            </field>
            <field>
              <name>BS10</name>
              <bitOffset>10</bitOffset>
              <bitWidth>1</bitWidth>
            </field>
            <field>
              <name>BS11</name>
              <bitOffset>11</bitOffset>
              <bitWidth>1</bitWidth>
            </field>
            <field>
              <name>BS12</name>
              <bitOffset>12</bitOffset>
              <bitWidth>1</bitWidth>
            </field>
            <field>
              <name>BS13</name>
              <bitOffset>13</bitOffset>
              <bitWidth>1</bitWidth>
            </field>
            <field>
              <name>BS14</name>
              <bitOffset>14</bitOffset>
              <bitWidth>1</bitWidth>
            </field>
            <field>
              <name>BS15</name>
              <bitOffset>15</bitOffset>
              <bitWidth>1</bitWidth>
            </field>
            <field>
              <name>BR0</name>
              <bitOffset>16</bitOffset>
              <bitWidth>1</bitWidth>
            </field>
            <field>
              <name>BR1</name>
              <bitOffset>17</bitOffset>
              <bitWidth>1</bitWidth>
            </field>
            <field>
              <name>BR2</name>
              <bitOffset>18</bitOffset>
              <bitWidth>1</bitWidth>
            </field>
            <field>
              <name>BR3</name>
              <bitOffset>19</bitOffset>
              <bitWidth>1</bitWidth>
            </field>
            <field>
              <name>BR4</name>
              <bitOffset>20</bitOffset>
              <bitWidth>1</bitWidth>
            </field>
            <field>
              <name>BR5</name>
              <bitOffset>21</bitOffset>
              <bitWidth>1</bitWidth>
            </field>
            <field>
              <name>BR6</name>
              <bitOffset>22</bitOffset>
              <bitWidth>1</bitWidth>
            </field>
            <field>
              <name>BR7</name>
              <bitOffset>23</bitOffset>
              <bitWidth>1</bitWidth>
            </field>
            <field>
              <name>BR8</name>
              <bitOffset>24</bitOffset>
              <bitWidth>1</bitWidth>
            </field>
            <field>
              <name>BR9</name>
              <bitOffset>25</bitOffset>
              <bitWidth>1</bitWidth>
            </field>
            <field>
              <name>BR10</name>
              <bitOffset>26</bitOffset>
              <bitWidth>1</bitWidth>
            </field>
            <field>
              <name>BR11</name>
              <bitOffset>27</bitOffset>
              <bitWidth>1</bitWidth>
            </field>
            <field>
              <name>BR12</name>
              <bitOffset>28</bitOffset>
              <bitWidth>1</bitWidth>
            </field>
            <field>
              <name>BR13</name>
              <bitOffset>29</bitOffset>
              <bitWidth>1</bitWidth>
            </field>
            <field>
              <name>BR14</name>
              <bitOffset>30</bitOffset>
              <bitWidth>1</bitWidth>
            </field>
            <field>
              <name>BR15</name>
              <bitOffset>31</bitOffset>
              <bitWidth>1</bitWidth>
            </field>
          </fields>
        </register>
        <register>
          <name>LCKR</name>
          <addressOffset>0x1c</addressOffset>
          <size>0x20</size>
          <fields>
            <field>
              <name>LCK0</name>
              <bitOffset>0</bitOffset>
              <bitWidth>1</bitWidth>
            </field>
            <field>
              <name>LCK1</name>
              <bitOffset>1</bitOffset>
              <bitWidth>1</bitWidth>
            </field>
            <field>
              <name>LCK2</name>
              <bitOffset>2</bitOffset>
              <bitWidth>1</bitWidth>
            </field>
            <field>
              <name>LCK3</name>
              <bitOffset>3</bitOffset>
              <bitWidth>1</bitWidth>
            </field>
            <field>
              <name>LCK4</name>
              <bitOffset>4</bitOffset>
              <bitWidth>1</bitWidth>
            </field>
            <field>
              <name>LCK5</name>
              <bitOffset>5</bitOffset>
              <bitWidth>1</bitWidth>
            </field>
            <field>
              <name>LCK6</name>
              <bitOffset>6</bitOffset>
              <bitWidth>1</bitWidth>
            </field>
            <field>
              <name>LCK7</name>
              <bitOffset>7</bitOffset>
              <bitWidth>1</bitWidth>
            </field>
            <field>
              <name>LCK8</name>
              <bitOffset>8</bitOffset>
              <bitWidth>1</bitWidth>
            </field>
            <field>
              <name>LCK9</name>
              <bitOffset>9</bitOffset>
              <bitWidth>1</bitWidth>
            </field>
            <field>
              <name>LCK10</name>
              <bitOffset>10</bitOffset>
              <bitWidth>1</bitWidth>
            </field>
            <field>
              <name>LCK11</name>
              <bitOffset>11</bitOffset>
              <bitWidth>1</bitWidth>
            </field>
            <field>
              <name>LCK12</name>
              <bitOffset>12</bitOffset>
              <bitWidth>1</bitWidth>
            </field>
            <field>
              <name>LCK13</name>
              <bitOffset>13</bitOffset>
              <bitWidth>1</bitWidth>
            </field>
            <field>
              <name>LCK14</name>
              <bitOffset>14</bitOffset>
              <bitWidth>1</bitWidth>
            </field>
            <field>
              <name>LCK15</name>
              <bitOffset>15</bitOffset>
              <bitWidth>1</bitWidth>
            </field>
            <field>
              <name>LCKK</name>
              <bitOffset>16</bitOffset>
              <bitWidth>1</bitWidth>
            </field>
          </fields>
        </register>
        <register>
          <name>AFR.0</name>
          <addressOffset>0x20</addressOffset>
          <size>0x20</size>
          <fields>
            <field>
              <name>AFSEL0</name>
              <bitOffset>0</bitOffset>
              <bitWidth>4</bitWidth>
            </field>
            <field>
              <name>AFSEL1</name>
              <bitOffset>4</bitOffset>
              <bitWidth>4</bitWidth>
            </field>
            <field>
              <name>AFSEL2</name>
              <bitOffset>8</bitOffset>
              <bitWidth>4</bitWidth>
            </field>
            <field>
              <name>AFSEL3</name>
              <bitOffset>12</bitOffset>
              <bitWidth>4</bitWidth>
            </field>
            <field>
              <name>AFSEL4</name>
              <bitOffset>16</bitOffset>
              <bitWidth>4</bitWidth>
            </field>
            <field>
              <name>AFSEL5</name>
              <bitOffset>20</bitOffset>
              <bitWidth>4</bitWidth>
            </field>
            <field>
              <name>AFSEL6</name>
              <bitOffset>24</bitOffset>
              <bitWidth>4</bitWidth>
            </field>
            <field>
              <name>AFSEL7</name>
              <bitOffset>28</bitOffset>
              <bitWidth>4</bitWidth>
            </field>
          </fields>
        </register>
        <register>
          <name>AFR.1</name>
          <addressOffset>0x24</addressOffset>
          <size>0x20</size>
          <fields>
            <field>
              <name>AFSEL8</name>
              <bitOffset>0</bitOffset>
              <bitWidth>4</bitWidth>
            </field>
            <field>
              <name>AFSEL9</name>
              <bitOffset>4</bitOffset>
              <bitWidth>4</bitWidth>
            </field>
            <field>
              <name>AFSEL10</name>
              <bitOffset>8</bitOffset>
              <bitWidth>4</bitWidth>
            </field>
            <field>
              <name>AFSEL11</name>
              <bitOffset>12</bitOffset>
              <bitWidth>4</bitWidth>
            </field>
            <field>
              <name>AFSEL12</name>
              <bitOffset>16</bitOffset>
              <bitWidth>4</bitWidth>
            </field>
            <field>
              <name>AFSEL13</name>
              <bitOffset>20</bitOffset>
              <bitWidth>4</bitWidth>
            </field>
            <field>
              <name>AFSEL14</name>
              <bitOffset>24</bitOffset>
              <bitWidth>4</bitWidth>
            </field>
            <field>
              <name>AFSEL15</name>
              <bitOffset>28</bitOffset>
              <bitWidth>4</bitWidth>
            </field>
          </fields>
        </register>
      </registers>
    </peripheral>
    <peripheral>
      <name>GPIOC</name>
      <baseAddress>0x58020800</baseAddress>
      <registers>
        <register>
          <name>MODER</name>
          <addressOffset>0x0</addressOffset>
          <size>0x20</size>
          <fields>
            <field>
              <name>MODE0</name>
              <bitOffset>0</bitOffset>
              <bitWidth>2</bitWidth>
            </field>
            <field>
              <name>MODE1</name>
              <bitOffset>2</bitOffset>
              <bitWidth>2</bitWidth>
            </field>
            <field>
              <name>MODE2</name>
              <bitOffset>4</bitOffset>
              <bitWidth>2</bitWidth>
            </field>
            <field>
              <name>MODE3</name>
              <bitOffset>6</bitOffset>
              <bitWidth>2</bitWidth>
            </field>
            <field>
              <name>MODE4</name>
              <bitOffset>8</bitOffset>
              <bitWidth>2</bitWidth>
            </field>
            <field>
              <name>MODE5</name>
              <bitOffset>10</bitOffset>
              <bitWidth>2</bitWidth>
            </field>
            <field>
              <name>MODE6</name>
              <bitOffset>12</bitOffset>
              <bitWidth>2</bitWidth>
            </field>
            <field>
              <name>MODE7</name>
              <bitOffset>14</bitOffset>
              <bitWidth>2</bitWidth>
            </field>
            <field>
              <name>MODE8</name>
              <bitOffset>16</bitOffset>
              <bitWidth>2</bitWidth>
            </field>
            <field>
              <name>MODE9</name>
              <bitOffset>18</bitOffset>
              <bitWidth>2</bitWidth>
            </field>
            <field>
              <name>MODE10</name>
              <bitOffset>20</bitOffset>
              <bitWidth>2</bitWidth>
            </field>
            <field>
              <name>MODE11</name>
              <bitOffset>22</bitOffset>
              <bitWidth>2</bitWidth>
            </field>
            <field>
              <name>MODE12</name>
              <bitOffset>24</bitOffset>
              <bitWidth>2</bitWidth>
            </field>
            <field>
              <name>MODE13</name>
              <bitOffset>26</bitOffset>
              <bitWidth>2</bitWidth>
            </field>
            <field>
              <name>MODE14</name>
              <bitOffset>28</bitOffset>
              <bitWidth>2</bitWidth>
            </field>
            <field>
              <name>MODE15</name>
              <bitOffset>30</bitOffset>
              <bitWidth>2</bitWidth>
            </field>
          </fields>
        </register>
        <register>
          <name>OTYPER</name>
          <addressOffset>0x4</addressOffset>
          <size>0x20</size>
          <fields>
            <field>
              <name>OT0</name>
              <bitOffset>0</bitOffset>
              <bitWidth>1</bitWidth>
            </field>
            <field>
              <name>OT1</name>
              <bitOffset>1</bitOffset>
              <bitWidth>1</bitWidth>
            </field>
            <field>
              <name>OT2</name>
              <bitOffset>2</bitOffset>
              <bitWidth>1</bitWidth>
            </field>
            <field>
              <name>OT3</name>
              <bitOffset>3</bitOffset>
              <bitWidth>1</bitWidth>
            </field>
            <field>
              <name>OT4</name>
              <bitOffset>4</bitOffset>
              <bitWidth>1</bitWidth>
            </field>
            <field>
              <name>OT5</name>
              <bitOffset>5</bitOffset>
              <bitWidth>1</bitWidth>
            </field>
            <field>
              <name>OT6</name>
              <bitOffset>6</bitOffset>
              <bitWidth>1</bitWidth>
            </field>
            <field>
              <name>OT7</name>
              <bitOffset>7</bitOffset>
              <bitWidth>1</bitWidth>
            </field>
            <field>
              <name>OT8</name>
              <bitOffset>8</bitOffset>
              <bitWidth>1</bitWidth>
            </field>
            <field>
              <name>OT9</name>
              <bitOffset>9</bitOffset>
              <bitWidth>1</bitWidth>
            </field>
            <field>
              <name>OT10</name>
              <bitOffset>10</bitOffset>
              <bitWidth>1</bitWidth>
            </field>
            <field>
              <name>OT11</name>
              <bitOffset>11</bitOffset>
              <bitWidth>1</bitWidth>
            </field>
            <field>
              <name>OT12</name>
              <bitOffset>12</bitOffset>
              <bitWidth>1</bitWidth>
            </field>
            <field>
              <name>OT13</name>
              <bitOffset>13</bitOffset>
              <bitWidth>1</bitWidth>
            </field>
            <field>
              <name>OT14</name>
              <bitOffset>14</bitOffset>
              <bitWidth>1</bitWidth>
            </field>
            <field>
              <name>OT15</name>
              <bitOffset>15</bitOffset>
              <bitWidth>1</bitWidth>
            </field>
          </fields>
        </register>
        <register>
          <name>OSPEEDR</name>
          <addressOffset>0x8</addressOffset>
          <size>0x20</size>
          <fields>
            <field>
              <name>OSPEED0</name>
              <bitOffset>0</bitOffset>
              <bitWidth>2</bitWidth>
            </field>
            <field>
              <name>OSPEED1</name>
              <bitOffset>2</bitOffset>
              <bitWidth>2</bitWidth>
            </field>
            <field>
              <name>OSPEED2</name>
              <bitOffset>4</bitOffset>
              <bitWidth>2</bitWidth>
            </field>
            <field>
              <name>OSPEED3</name>
              <bitOffset>6</bitOffset>
              <bitWidth>2</bitWidth>
            </field>
            <field>
              <name>OSPEED4</name>
              <bitOffset>8</bitOffset>
              <bitWidth>2</bitWidth>
            </field>
            <field>
              <name>OSPEED5</name>
              <bitOffset>10</bitOffset>
              <bitWidth>2</bitWidth>
            </field>
            <field>
              <name>OSPEED6</name>
              <bitOffset>12</bitOffset>
              <bitWidth>2</bitWidth>
            </field>
            <field>
              <name>OSPEED7</name>
              <bitOffset>14</bitOffset>
              <bitWidth>2</bitWidth>
            </field>
            <field>
              <name>OSPEED8</name>
              <bitOffset>16</bitOffset>
              <bitWidth>2</bitWidth>
            </field>
            <field>
              <name>OSPEED9</name>
              <bitOffset>18</bitOffset>
              <bitWidth>2</bitWidth>
            </field>
            <field>
              <name>OSPEED10</name>
              <bitOffset>20</bitOffset>
              <bitWidth>2</bitWidth>
            </field>
            <field>
              <name>OSPEED11</name>
              <bitOffset>22</bitOffset>
              <bitWidth>2</bitWidth>
            </field>
            <field>
              <name>OSPEED12</name>
              <bitOffset>24</bitOffset>
              <bitWidth>2</bitWidth>
            </field>
            <field>
              <name>OSPEED13</name>
              <bitOffset>26</bitOffset>
              <bitWidth>2</bitWidth>
            </field>
            <field>
              <name>OSPEED14</name>
              <bitOffset>28</bitOffset>
              <bitWidth>2</bitWidth>
            </field>
            <field>
              <name>OSPEED15</name>
              <bitOffset>30</bitOffset>
              <bitWidth>2</bitWidth>
            </field>
          </fields>
        </register>
        <register>
          <name>PUPDR</name>
          <addressOffset>0xc</addressOffset>
          <size>0x20</size>
          <fields>
            <field>
              <name>PUPD0</name>
              <bitOffset>0</bitOffset>
              <bitWidth>2</bitWidth>
            </field>
            <field>
              <name>PUPD1</name>
              <bitOffset>2</bitOffset>
              <bitWidth>2</bitWidth>
            </field>
            <field>
              <name>PUPD2</name>
              <bitOffset>4</bitOffset>
              <bitWidth>2</bitWidth>
            </field>
            <field>
              <name>PUPD3</name>
              <bitOffset>6</bitOffset>
              <bitWidth>2</bitWidth>
            </field>
            <field>
              <name>PUPD4</name>
              <bitOffset>8</bitOffset>
              <bitWidth>2</bitWidth>
            </field>
            <field>
              <name>PUPD5</name>
              <bitOffset>10</bitOffset>
              <bitWidth>2</bitWidth>
            </field>
            <field>
              <name>PUPD6</name>
              <bitOffset>12</bitOffset>
              <bitWidth>2</bitWidth>
            </field>
            <field>
              <name>PUPD7</name>
              <bitOffset>14</bitOffset>
              <bitWidth>2</bitWidth>
            </field>
            <field>
              <name>PUPD8</name>
              <bitOffset>16</bitOffset>
              <bitWidth>2</bitWidth>
            </field>
            <field>
              <name>PUPD9</name>
              <bitOffset>18</bitOffset>
              <bitWidth>2</bitWidth>
            </field>
            <field>
              <name>PUPD10</name>
              <bitOffset>20</bitOffset>
              <bitWidth>2</bitWidth>
            </field>
            <field>
              <name>PUPD11</name>
              <bitOffset>22</bitOffset>
              <bitWidth>2</bitWidth>
            </field>
            <field>
              <name>PUPD12</name>
              <bitOffset>24</bitOffset>
              <bitWidth>2</bitWidth>
            </field>
            <field>
              <name>PUPD13</name>
              <bitOffset>26</bitOffset>
              <bitWidth>2</bitWidth>
            </field>
            <field>
              <name>PUPD14</name>
              <bitOffset>28</bitOffset>
              <bitWidth>2</bitWidth>
            </field>
            <field>
              <name>PUPD15</name>
              <bitOffset>30</bitOffset>
              <bitWidth>2</bitWidth>
            </field>
          </fields>
        </register>
        <register>
          <name>IDR</name>
          <addressOffset>0x10</addressOffset>
          <size>0x20</size>
          <fields>
            <field>
              <name>ID0</name>
              <bitOffset>0</bitOffset>
              <bitWidth>1</bitWidth>
            </field>
            <field>
              <name>ID1</name>
              <bitOffset>1</bitOffset>
              <bitWidth>1</bitWidth>
            </field>
            <field>
              <name>ID2</name>
              <bitOffset>2</bitOffset>
              <bitWidth>1</bitWidth>
            </field>
            <field>
              <name>ID3</name>
              <bitOffset>3</bitOffset>
              <bitWidth>1</bitWidth>
            </field>
            <field>
              <name>ID4</name>
              <bitOffset>4</bitOffset>
              <bitWidth>1</bitWidth>
            </field>
            <field>
              <name>ID5</name>
              <bitOffset>5</bitOffset>
              <bitWidth>1</bitWidth>
            </field>
            <field>
              <name>ID6</name>
              <bitOffset>6</bitOffset>
              <bitWidth>1</bitWidth>
            </field>
            <field>
              <name>ID7</name>
              <bitOffset>7</bitOffset>
              <bitWidth>1</bitWidth>
            </field>
            <field>
              <name>ID8</name>
              <bitOffset>8</bitOffset>
              <bitWidth>1</bitWidth>
            </field>
            <field>
              <name>ID9</name>
              <bitOffset>9</bitOffset>
              <bitWidth>1</bitWidth>
            </field>
            <field>
              <name>ID10</name>
              <bitOffset>10</bitOffset>
              <bitWidth>1</bitWidth>
            </field>
            <field>
              <name>ID11</name>
              <bitOffset>11</bitOffset>
              <bitWidth>1</bitWidth>
            </field>
            <field>
              <name>ID12</name>
              <bitOffset>12</bitOffset>
              <bitWidth>1</bitWidth>
            </field>
            <field>
              <name>ID13</name>
              <bitOffset>13</bitOffset>
              <bitWidth>1</bitWidth>
            </field>
            <field>
              <name>ID14</name>
              <bitOffset>14</bitOffset>
              <bitWidth>1</bitWidth>
            </field>
            <field>
              <name>ID15</name>
              <bitOffset>15</bitOffset>
              <bitWidth>1</bitWidth>
            </field>
          </fields>
        </register>
        <register>
          <name>ODR</name>
          <addressOffset>0x14</addressOffset>
          <size>0x20</size>
          <fields>
            <field>
              <name>OD0</name>
              <bitOffset>0</bitOffset>
              <bitWidth>1</bitWidth>
            </field>
            <field>
              <name>OD1</name>
              <bitOffset>1</bitOffset>
              <bitWidth>1</bitWidth>
            </field>
            <field>
              <name>OD2</name>
              <bitOffset>2</bitOffset>
              <bitWidth>1</bitWidth>
            </field>
            <field>
              <name>OD3</name>
              <bitOffset>3</bitOffset>
              <bitWidth>1</bitWidth>
            </field>
            <field>
              <name>OD4</name>
              <bitOffset>4</bitOffset>
              <bitWidth>1</bitWidth>
            </field>
            <field>
              <name>OD5</name>
              <bitOffset>5</bitOffset>
              <bitWidth>1</bitWidth>
            </field>
            <field>
              <name>OD6</name>
              <bitOffset>6</bitOffset>
              <bitWidth>1</bitWidth>
            </field>
            <field>
              <name>OD7</name>
              <bitOffset>7</bitOffset>
              <bitWidth>1</bitWidth>
            </field>
            <field>
              <name>OD8</name>
              <bitOffset>8</bitOffset>
              <bitWidth>1</bitWidth>
            </field>
            <field>
              <name>OD9</name>
              <bitOffset>9</bitOffset>
              <bitWidth>1</bitWidth>
            </field>
            <field>
              <name>OD10</name>
              <bitOffset>10</bitOffset>
              <bitWidth>1</bitWidth>
            </field>
            <field>
              <name>OD11</name>
              <bitOffset>11</bitOffset>
              <bitWidth>1</bitWidth>
            </field>
            <field>
              <name>OD12</name>
              <bitOffset>12</bitOffset>
              <bitWidth>1</bitWidth>
            </field>
            <field>
              <name>OD13</name>
              <bitOffset>13</bitOffset>
              <bitWidth>1</bitWidth>
            </field>
            <field>
              <name>OD14</name>
              <bitOffset>14</bitOffset>
              <bitWidth>1</bitWidth>
            </field>
            <field>
              <name>OD15</name>
              <bitOffset>15</bitOffset>
              <bitWidth>1</bitWidth>
            </field>
          </fields>
        </register>
        <register>
          <name>BSRR</name>
          <addressOffset>0x18</addressOffset>
          <size>0x20</size>
          <fields>
            <field>
              <name>BS0</name>
              <bitOffset>0</bitOffset>
              <bitWidth>1</bitWidth>
            </field>
            <field>
              <name>BS1</name>
              <bitOffset>1</bitOffset>
              <bitWidth>1</bitWidth>
            </field>
            <field>
              <name>BS2</name>
              <bitOffset>2</bitOffset>
              <bitWidth>1</bitWidth>
            </field>
            <field>
              <name>BS3</name>
              <bitOffset>3</bitOffset>
              <bitWidth>1</bitWidth>
            </field>
            <field>
              <name>BS4</name>
              <bitOffset>4</bitOffset>
              <bitWidth>1</bitWidth>
            </field>
            <field>
              <name>BS5</name>
              <bitOffset>5</bitOffset>
              <bitWidth>1</bitWidth>
            </field>
            <field>
              <name>BS6</name>
              <bitOffset>6</bitOffset>
              <bitWidth>1</bitWidth>
            </field>
            <field>
              <name>BS7</name>
              <bitOffset>7</bitOffset>
              <bitWidth>1</bitWidth>
            </field>
            <field>
              <name>BS8</name>
              <bitOffset>8</bitOffset>
              <bitWidth>1</bitWidth>
            </field>
            <field>
              <name>BS9</name>
              <bitOffset>9</bitOffset>
              <bitWidth>1</bitWidth>
            </field>
            <field>
              <name>BS10</name>
              <bitOffset>10</bitOffset>
              <bitWidth>1</bitWidth>
            </field>
            <field>
              <name>BS11</name>
              <bitOffset>11</bitOffset>
              <bitWidth>1</bitWidth>
            </field>
            <field>
              <name>BS12</name>
              <bitOffset>12</bitOffset>
              <bitWidth>1</bitWidth>
            </field>
            <field>
              <name>BS13</name>
              <bitOffset>13</bitOffset>
              <bitWidth>1</bitWidth>
            </field>
            <field>
              <name>BS14</name>
              <bitOffset>14</bitOffset>
              <bitWidth>1</bitWidth>
            </field>
            <field>
              <name>BS15</name>
              <bitOffset>15</bitOffset>
              <bitWidth>1</bitWidth>
            </field>
            <field>
              <name>BR0</name>
              <bitOffset>16</bitOffset>
              <bitWidth>1</bitWidth>
            </field>
            <field>
              <name>BR1</name>
              <bitOffset>17</bitOffset>
              <bitWidth>1</bitWidth>
            </field>
            <field>
              <name>BR2</name>
              <bitOffset>18</bitOffset>
              <bitWidth>1</bitWidth>
            </field>
            <field>
              <name>BR3</name>
              <bitOffset>19</bitOffset>
              <bitWidth>1</bitWidth>
            </field>
            <field>
              <name>BR4</name>
              <bitOffset>20</bitOffset>
              <bitWidth>1</bitWidth>
            </field>
            <field>
              <name>BR5</name>
              <bitOffset>21</bitOffset>
              <bitWidth>1</bitWidth>
            </field>
            <field>
              <name>BR6</name>
              <bitOffset>22</bitOffset>
              <bitWidth>1</bitWidth>
            </field>
            <field>
              <name>BR7</name>
              <bitOffset>23</bitOffset>
              <bitWidth>1</bitWidth>
            </field>
            <field>
              <name>BR8</name>
              <bitOffset>24</bitOffset>
              <bitWidth>1</bitWidth>
            </field>
            <field>
              <name>BR9</name>
              <bitOffset>25</bitOffset>
              <bitWidth>1</bitWidth>
            </field>
            <field>
              <name>BR10</name>
              <bitOffset>26</bitOffset>
              <bitWidth>1</bitWidth>
            </field>
            <field>
              <name>BR11</name>
              <bitOffset>27</bitOffset>
              <bitWidth>1</bitWidth>
            </field>
            <field>
              <name>BR12</name>
              <bitOffset>28</bitOffset>
              <bitWidth>1</bitWidth>
            </field>
            <field>
              <name>BR13</name>
              <bitOffset>29</bitOffset>
              <bitWidth>1</bitWidth>
            </field>
            <field>
              <name>BR14</name>
              <bitOffset>30</bitOffset>
              <bitWidth>1</bitWidth>
            </field>
            <field>
              <name>BR15</name>
              <bitOffset>31</bitOffset>
              <bitWidth>1</bitWidth>
            </field>
          </fields>
        </register>
        <register>
          <name>LCKR</name>
          <addressOffset>0x1c</addressOffset>
          <size>0x20</size>
          <fields>
            <field>
              <name>LCK0</name>
              <bitOffset>0</bitOffset>
              <bitWidth>1</bitWidth>
            </field>
            <field>
              <name>LCK1</name>
              <bitOffset>1</bitOffset>
              <bitWidth>1</bitWidth>
            </field>
            <field>
              <name>LCK2</name>
              <bitOffset>2</bitOffset>
              <bitWidth>1</bitWidth>
            </field>
            <field>
              <name>LCK3</name>
              <bitOffset>3</bitOffset>
              <bitWidth>1</bitWidth>
            </field>
            <field>
              <name>LCK4</name>
              <bitOffset>4</bitOffset>
              <bitWidth>1</bitWidth>
            </field>
            <field>
              <name>LCK5</name>
              <bitOffset>5</bitOffset>
              <bitWidth>1</bitWidth>
            </field>
            <field>
              <name>LCK6</name>
              <bitOffset>6</bitOffset>
              <bitWidth>1</bitWidth>
            </field>
            <field>
              <name>LCK7</name>
              <bitOffset>7</bitOffset>
              <bitWidth>1</bitWidth>
            </field>
            <field>
              <name>LCK8</name>
              <bitOffset>8</bitOffset>
              <bitWidth>1</bitWidth>
            </field>
            <field>
              <name>LCK9</name>
              <bitOffset>9</bitOffset>
              <bitWidth>1</bitWidth>
            </field>
            <field>
              <name>LCK10</name>
              <bitOffset>10</bitOffset>
              <bitWidth>1</bitWidth>
            </field>
            <field>
              <name>LCK11</name>
              <bitOffset>11</bitOffset>
              <bitWidth>1</bitWidth>
            </field>
            <field>
              <name>LCK12</name>
              <bitOffset>12</bitOffset>
              <bitWidth>1</bitWidth>
            </field>
            <field>
              <name>LCK13</name>
              <bitOffset>13</bitOffset>
              <bitWidth>1</bitWidth>
            </field>
            <field>
              <name>LCK14</name>
              <bitOffset>14</bitOffset>
              <bitWidth>1</bitWidth>
            </field>
            <field>
              <name>LCK15</name>
              <bitOffset>15</bitOffset>
              <bitWidth>1</bitWidth>
            </field>
            <field>
              <name>LCKK</name>
              <bitOffset>16</bitOffset>
              <bitWidth>1</bitWidth>
            </field>
          </fields>
        </register>
        <register>
          <name>AFR.0</name>
          <addressOffset>0x20</addressOffset>
          <size>0x20</size>
          <fields>
            <field>
              <name>AFSEL0</name>
              <bitOffset>0</bitOffset>
              <bitWidth>4</bitWidth>
            </field>
            <field>
              <name>AFSEL1</name>
              <bitOffset>4</bitOffset>
              <bitWidth>4</bitWidth>
            </field>
            <field>
              <name>AFSEL2</name>
              <bitOffset>8</bitOffset>
              <bitWidth>4</bitWidth>
            </field>
            <field>
              <name>AFSEL3</name>
              <bitOffset>12</bitOffset>
              <bitWidth>4</bitWidth>
            </field>
            <field>
              <name>AFSEL4</name>
              <bitOffset>16</bitOffset>
              <bitWidth>4</bitWidth>
            </field>
            <field>
              <name>AFSEL5</name>
              <bitOffset>20</bitOffset>
              <bitWidth>4</bitWidth>
            </field>
            <field>
              <name>AFSEL6</name>
              <bitOffset>24</bitOffset>
              <bitWidth>4</bitWidth>
            </field>
            <field>
              <name>AFSEL7</name>
              <bitOffset>28</bitOffset>
              <bitWidth>4</bitWidth>
            </field>
          </fields>
        </register>
        <register>
          <name>AFR.1</name>
          <addressOffset>0x24</addressOffset>
          <size>0x20</size>
          <fields>
            <field>
              <name>AFSEL8</name>
              <bitOffset>0</bitOffset>
              <bitWidth>4</bitWidth>
            </field>
            <field>
              <name>AFSEL9</name>
              <bitOffset>4</bitOffset>
              <bitWidth>4</bitWidth>
            </field>
            <field>
              <name>AFSEL10</name>
              <bitOffset>8</bitOffset>
              <bitWidth>4</bitWidth>
            </field>
            <field>
              <name>AFSEL11</name>
              <bitOffset>12</bitOffset>
              <bitWidth>4</bitWidth>
            </field>
            <field>
              <name>AFSEL12</name>
              <bitOffset>16</bitOffset>
              <bitWidth>4</bitWidth>
            </field>
            <field>
              <name>AFSEL13</name>
              <bitOffset>20</bitOffset>
              <bitWidth>4</bitWidth>
            </field>
            <field>
              <name>AFSEL14</name>
              <bitOffset>24</bitOffset>
              <bitWidth>4</bitWidth>
            </field>
            <field>
              <name>AFSEL15</name>
              <bitOffset>28</bitOffset>
              <bitWidth>4</bitWidth>
            </field>
          </fields>
        </register>
      </registers>
    </peripheral>
    <peripheral>
      <name>GPIOD</name>
      <baseAddress>0x58020c00</baseAddress>
      <registers>
        <register>
          <name>MODER</name>
          <addressOffset>0x0</addressOffset>
          <size>0x20</size>
          <fields>
            <field>
              <name>MODE0</name>
              <bitOffset>0</bitOffset>
              <bitWidth>2</bitWidth>
            </field>
            <field>
              <name>MODE1</name>
              <bitOffset>2</bitOffset>
              <bitWidth>2</bitWidth>
            </field>
            <field>
              <name>MODE2</name>
              <bitOffset>4</bitOffset>
              <bitWidth>2</bitWidth>
            </field>
            <field>
              <name>MODE3</name>
              <bitOffset>6</bitOffset>
              <bitWidth>2</bitWidth>
            </field>
            <field>
              <name>MODE4</name>
              <bitOffset>8</bitOffset>
              <bitWidth>2</bitWidth>
            </field>
            <field>
              <name>MODE5</name>
              <bitOffset>10</bitOffset>
              <bitWidth>2</bitWidth>
            </field>
            <field>
              <name>MODE6</name>
              <bitOffset>12</bitOffset>
              <bitWidth>2</bitWidth>
            </field>
            <field>
              <name>MODE7</name>
              <bitOffset>14</bitOffset>
              <bitWidth>2</bitWidth>
            </field>
            <field>
              <name>MODE8</name>
              <bitOffset>16</bitOffset>
              <bitWidth>2</bitWidth>
            </field>
            <field>
              <name>MODE9</name>
              <bitOffset>18</bitOffset>
              <bitWidth>2</bitWidth>
            </field>
            <field>
              <name>MODE10</name>
              <bitOffset>20</bitOffset>
              <bitWidth>2</bitWidth>
            </field>
            <field>
              <name>MODE11</name>
              <bitOffset>22</bitOffset>
              <bitWidth>2</bitWidth>
            </field>
            <field>
              <name>MODE12</name>
              <bitOffset>24</bitOffset>
              <bitWidth>2</bitWidth>
            </field>
            <field>
              <name>MODE13</name>
              <bitOffset>26</bitOffset>
              <bitWidth>2</bitWidth>
            </field>
            <field>
              <name>MODE14</name>
              <bitOffset>28</bitOffset>
              <bitWidth>2</bitWidth>
            </field>
            <field>
              <name>MODE15</name>
              <bitOffset>30</bitOffset>
              <bitWidth>2</bitWidth>
            </field>
          </fields>
        </register>
        <register>
          <name>OTYPER</name>
          <addressOffset>0x4</addressOffset>
          <size>0x20</size>
          <fields>
            <field>
              <name>OT0</name>
              <bitOffset>0</bitOffset>
              <bitWidth>1</bitWidth>
            </field>
            <field>
              <name>OT1</name>
              <bitOffset>1</bitOffset>
              <bitWidth>1</bitWidth>
            </field>
            <field>
              <name>OT2</name>
              <bitOffset>2</bitOffset>
              <bitWidth>1</bitWidth>
            </field>
            <field>
              <name>OT3</name>
              <bitOffset>3</bitOffset>
              <bitWidth>1</bitWidth>
            </field>
            <field>
              <name>OT4</name>
              <bitOffset>4</bitOffset>
              <bitWidth>1</bitWidth>
            </field>
            <field>
              <name>OT5</name>
              <bitOffset>5</bitOffset>
              <bitWidth>1</bitWidth>
            </field>
            <field>
              <name>OT6</name>
              <bitOffset>6</bitOffset>
              <bitWidth>1</bitWidth>
            </field>
            <field>
              <name>OT7</name>
              <bitOffset>7</bitOffset>
              <bitWidth>1</bitWidth>
            </field>
            <field>
              <name>OT8</name>
              <bitOffset>8</bitOffset>
              <bitWidth>1</bitWidth>
            </field>
            <field>
              <name>OT9</name>
              <bitOffset>9</bitOffset>
              <bitWidth>1</bitWidth>
            </field>
            <field>
              <name>OT10</name>
              <bitOffset>10</bitOffset>
              <bitWidth>1</bitWidth>
            </field>
            <field>
              <name>OT11</name>
              <bitOffset>11</bitOffset>
              <bitWidth>1</bitWidth>
            </field>
            <field>
              <name>OT12</name>
              <bitOffset>12</bitOffset>
              <bitWidth>1</bitWidth>
            </field>
            <field>
              <name>OT13</name>
              <bitOffset>13</bitOffset>
              <bitWidth>1</bitWidth>
            </field>
            <field>
              <name>OT14</name>
              <bitOffset>14</bitOffset>
              <bitWidth>1</bitWidth>
            </field>
            <field>
              <name>OT15</name>
              <bitOffset>15</bitOffset>
              <bitWidth>1</bitWidth>
            </field>
          </fields>
        </register>
        <register>
          <name>OSPEEDR</name>
          <addressOffset>0x8</addressOffset>
          <size>0x20</size>
          <fields>
            <field>
              <name>OSPEED0</name>
              <bitOffset>0</bitOffset>
              <bitWidth>2</bitWidth>
            </field>
            <field>
              <name>OSPEED1</name>
              <bitOffset>2</bitOffset>
              <bitWidth>2</bitWidth>
            </field>
            <field>
              <name>OSPEED2</name>
              <bitOffset>4</bitOffset>
              <bitWidth>2</bitWidth>
            </field>
            <field>
              <name>OSPEED3</name>
              <bitOffset>6</bitOffset>
              <bitWidth>2</bitWidth>
            </field>
            <field>
              <name>OSPEED4</name>
              <bitOffset>8</bitOffset>
              <bitWidth>2</bitWidth>
            </field>
            <field>
              <name>OSPEED5</name>
              <bitOffset>10</bitOffset>
              <bitWidth>2</bitWidth>
            </field>
            <field>
              <name>OSPEED6</name>
              <bitOffset>12</bitOffset>
              <bitWidth>2</bitWidth>
            </field>
            <field>
              <name>OSPEED7</name>
              <bitOffset>14</bitOffset>
              <bitWidth>2</bitWidth>
            </field>
            <field>
              <name>OSPEED8</name>
              <bitOffset>16</bitOffset>
              <bitWidth>2</bitWidth>
            </field>
            <field>
              <name>OSPEED9</name>
              <bitOffset>18</bitOffset>
              <bitWidth>2</bitWidth>
            </field>
            <field>
              <name>OSPEED10</name>
              <bitOffset>20</bitOffset>
              <bitWidth>2</bitWidth>
            </field>
            <field>
              <name>OSPEED11</name>
              <bitOffset>22</bitOffset>
              <bitWidth>2</bitWidth>
            </field>
            <field>
              <name>OSPEED12</name>
              <bitOffset>24</bitOffset>
              <bitWidth>2</bitWidth>
            </field>
            <field>
              <name>OSPEED13</name>
              <bitOffset>26</bitOffset>
              <bitWidth>2</bitWidth>
            </field>
            <field>
              <name>OSPEED14</name>
              <bitOffset>28</bitOffset>
              <bitWidth>2</bitWidth>
            </field>
            <field>
              <name>OSPEED15</name>
              <bitOffset>30</bitOffset>
              <bitWidth>2</bitWidth>
            </field>
          </fields>
        </register>
        <register>
          <name>PUPDR</name>
          <addressOffset>0xc</addressOffset>
          <size>0x20</size>
          <fields>
            <field>
              <name>PUPD0</name>
              <bitOffset>0</bitOffset>
              <bitWidth>2</bitWidth>
            </field>
            <field>
              <name>PUPD1</name>
              <bitOffset>2</bitOffset>
              <bitWidth>2</bitWidth>
            </field>
            <field>
              <name>PUPD2</name>
              <bitOffset>4</bitOffset>
              <bitWidth>2</bitWidth>
            </field>
            <field>
              <name>PUPD3</name>
              <bitOffset>6</bitOffset>
              <bitWidth>2</bitWidth>
            </field>
            <field>
              <name>PUPD4</name>
              <bitOffset>8</bitOffset>
              <bitWidth>2</bitWidth>
            </field>
            <field>
              <name>PUPD5</name>
              <bitOffset>10</bitOffset>
              <bitWidth>2</bitWidth>
            </field>
            <field>
              <name>PUPD6</name>
              <bitOffset>12</bitOffset>
              <bitWidth>2</bitWidth>
            </field>
            <field>
              <name>PUPD7</name>
              <bitOffset>14</bitOffset>
              <bitWidth>2</bitWidth>
            </field>
            <field>
              <name>PUPD8</name>
              <bitOffset>16</bitOffset>
              <bitWidth>2</bitWidth>
            </field>
            <field>
              <name>PUPD9</name>
              <bitOffset>18</bitOffset>
              <bitWidth>2</bitWidth>
            </field>
            <field>
              <name>PUPD10</name>
              <bitOffset>20</bitOffset>
              <bitWidth>2</bitWidth>
            </field>
            <field>
              <name>PUPD11</name>
              <bitOffset>22</bitOffset>
              <bitWidth>2</bitWidth>
            </field>
            <field>
              <name>PUPD12</name>
              <bitOffset>24</bitOffset>
              <bitWidth>2</bitWidth>
            </field>
            <field>
              <name>PUPD13</name>
              <bitOffset>26</bitOffset>
              <bitWidth>2</bitWidth>
            </field>
            <field>
              <name>PUPD14</name>
              <bitOffset>28</bitOffset>
              <bitWidth>2</bitWidth>
            </field>
            <field>
              <name>PUPD15</name>
              <bitOffset>30</bitOffset>
              <bitWidth>2</bitWidth>
            </field>
          </fields>
        </register>
        <register>
          <name>IDR</name>
          <addressOffset>0x10</addressOffset>
          <size>0x20</size>
          <fields>
            <field>
              <name>ID0</name>
              <bitOffset>0</bitOffset>
              <bitWidth>1</bitWidth>
            </field>
            <field>
              <name>ID1</name>
              <bitOffset>1</bitOffset>
              <bitWidth>1</bitWidth>
            </field>
            <field>
              <name>ID2</name>
              <bitOffset>2</bitOffset>
              <bitWidth>1</bitWidth>
            </field>
            <field>
              <name>ID3</name>
              <bitOffset>3</bitOffset>
              <bitWidth>1</bitWidth>
            </field>
            <field>
              <name>ID4</name>
              <bitOffset>4</bitOffset>
              <bitWidth>1</bitWidth>
            </field>
            <field>
              <name>ID5</name>
              <bitOffset>5</bitOffset>
              <bitWidth>1</bitWidth>
            </field>
            <field>
              <name>ID6</name>
              <bitOffset>6</bitOffset>
              <bitWidth>1</bitWidth>
            </field>
            <field>
              <name>ID7</name>
              <bitOffset>7</bitOffset>
              <bitWidth>1</bitWidth>
            </field>
            <field>
              <name>ID8</name>
              <bitOffset>8</bitOffset>
              <bitWidth>1</bitWidth>
            </field>
            <field>
              <name>ID9</name>
              <bitOffset>9</bitOffset>
              <bitWidth>1</bitWidth>
            </field>
            <field>
              <name>ID10</name>
              <bitOffset>10</bitOffset>
              <bitWidth>1</bitWidth>
            </field>
            <field>
              <name>ID11</name>
              <bitOffset>11</bitOffset>
              <bitWidth>1</bitWidth>
            </field>
            <field>
              <name>ID12</name>
              <bitOffset>12</bitOffset>
              <bitWidth>1</bitWidth>
            </field>
            <field>
              <name>ID13</name>
              <bitOffset>13</bitOffset>
              <bitWidth>1</bitWidth>
            </field>
            <field>
              <name>ID14</name>
              <bitOffset>14</bitOffset>
              <bitWidth>1</bitWidth>
            </field>
            <field>
              <name>ID15</name>
              <bitOffset>15</bitOffset>
              <bitWidth>1</bitWidth>
            </field>
          </fields>
        </register>
        <register>
          <name>ODR</name>
          <addressOffset>0x14</addressOffset>
          <size>0x20</size>
          <fields>
            <field>
              <name>OD0</name>
              <bitOffset>0</bitOffset>
              <bitWidth>1</bitWidth>
            </field>
            <field>
              <name>OD1</name>
              <bitOffset>1</bitOffset>
              <bitWidth>1</bitWidth>
            </field>
            <field>
              <name>OD2</name>
              <bitOffset>2</bitOffset>
              <bitWidth>1</bitWidth>
            </field>
            <field>
              <name>OD3</name>
              <bitOffset>3</bitOffset>
              <bitWidth>1</bitWidth>
            </field>
            <field>
              <name>OD4</name>
              <bitOffset>4</bitOffset>
              <bitWidth>1</bitWidth>
            </field>
            <field>
              <name>OD5</name>
              <bitOffset>5</bitOffset>
              <bitWidth>1</bitWidth>
            </field>
            <field>
              <name>OD6</name>
              <bitOffset>6</bitOffset>
              <bitWidth>1</bitWidth>
            </field>
            <field>
              <name>OD7</name>
              <bitOffset>7</bitOffset>
              <bitWidth>1</bitWidth>
            </field>
            <field>
              <name>OD8</name>
              <bitOffset>8</bitOffset>
              <bitWidth>1</bitWidth>
            </field>
            <field>
              <name>OD9</name>
              <bitOffset>9</bitOffset>
              <bitWidth>1</bitWidth>
            </field>
            <field>
              <name>OD10</name>
              <bitOffset>10</bitOffset>
              <bitWidth>1</bitWidth>
            </field>
            <field>
              <name>OD11</name>
              <bitOffset>11</bitOffset>
              <bitWidth>1</bitWidth>
            </field>
            <field>
              <name>OD12</name>
              <bitOffset>12</bitOffset>
              <bitWidth>1</bitWidth>
            </field>
            <field>
              <name>OD13</name>
              <bitOffset>13</bitOffset>
              <bitWidth>1</bitWidth>
            </field>
            <field>
              <name>OD14</name>
              <bitOffset>14</bitOffset>
              <bitWidth>1</bitWidth>
            </field>
            <field>
              <name>OD15</name>
              <bitOffset>15</bitOffset>
              <bitWidth>1</bitWidth>
            </field>
          </fields>
        </register>
        <register>
          <name>BSRR</name>
          <addressOffset>0x18</addressOffset>
          <size>0x20</size>
          <fields>
            <field>
              <name>BS0</name>
              <bitOffset>0</bitOffset>
              <bitWidth>1</bitWidth>
            </field>
            <field>
              <name>BS1</name>
              <bitOffset>1</bitOffset>
              <bitWidth>1</bitWidth>
            </field>
            <field>
              <name>BS2</name>
              <bitOffset>2</bitOffset>
              <bitWidth>1</bitWidth>
            </field>
            <field>
              <name>BS3</name>
              <bitOffset>3</bitOffset>
              <bitWidth>1</bitWidth>
            </field>
            <field>
              <name>BS4</name>
              <bitOffset>4</bitOffset>
              <bitWidth>1</bitWidth>
            </field>
            <field>
              <name>BS5</name>
              <bitOffset>5</bitOffset>
              <bitWidth>1</bitWidth>
            </field>
            <field>
              <name>BS6</name>
              <bitOffset>6</bitOffset>
              <bitWidth>1</bitWidth>
            </field>
            <field>
              <name>BS7</name>
              <bitOffset>7</bitOffset>
              <bitWidth>1</bitWidth>
            </field>
            <field>
              <name>BS8</name>
              <bitOffset>8</bitOffset>
              <bitWidth>1</bitWidth>
            </field>
            <field>
              <name>BS9</name>
              <bitOffset>9</bitOffset>
              <bitWidth>1</bitWidth>
            </field>
            <field>
              <name>BS10</name>
              <bitOffset>10</bitOffset>
              <bitWidth>1</bitWidth>
            </field>
            <field>
              <name>BS11</name>
              <bitOffset>11</bitOffset>
              <bitWidth>1</bitWidth>
            </field>
            <field>
              <name>BS12</name>
              <bitOffset>12</bitOffset>
              <bitWidth>1</bitWidth>
            </field>
            <field>
              <name>BS13</name>
              <bitOffset>13</bitOffset>
              <bitWidth>1</bitWidth>
            </field>
            <field>
              <name>BS14</name>
              <bitOffset>14</bitOffset>
              <bitWidth>1</bitWidth>
            </field>
            <field>
              <name>BS15</name>
              <bitOffset>15</bitOffset>
              <bitWidth>1</bitWidth>
            </field>
            <field>
              <name>BR0</name>
              <bitOffset>16</bitOffset>
              <bitWidth>1</bitWidth>
            </field>
            <field>
              <name>BR1</name>
              <bitOffset>17</bitOffset>
              <bitWidth>1</bitWidth>
            </field>
            <field>
              <name>BR2</name>
              <bitOffset>18</bitOffset>
              <bitWidth>1</bitWidth>
            </field>
            <field>
              <name>BR3</name>
              <bitOffset>19</bitOffset>
              <bitWidth>1</bitWidth>
            </field>
            <field>
              <name>BR4</name>
              <bitOffset>20</bitOffset>
              <bitWidth>1</bitWidth>
            </field>
            <field>
              <name>BR5</name>
              <bitOffset>21</bitOffset>
              <bitWidth>1</bitWidth>
            </field>
            <field>
              <name>BR6</name>
              <bitOffset>22</bitOffset>
              <bitWidth>1</bitWidth>
            </field>
            <field>
              <name>BR7</name>
              <bitOffset>23</bitOffset>
              <bitWidth>1</bitWidth>
            </field>
            <field>
              <name>BR8</name>
              <bitOffset>24</bitOffset>
              <bitWidth>1</bitWidth>
            </field>
            <field>
              <name>BR9</name>
              <bitOffset>25</bitOffset>
              <bitWidth>1</bitWidth>
            </field>
            <field>
              <name>BR10</name>
              <bitOffset>26</bitOffset>
              <bitWidth>1</bitWidth>
            </field>
            <field>
              <name>BR11</name>
              <bitOffset>27</bitOffset>
              <bitWidth>1</bitWidth>
            </field>
            <field>
              <name>BR12</name>
              <bitOffset>28</bitOffset>
              <bitWidth>1</bitWidth>
            </field>
            <field>
              <name>BR13</name>
              <bitOffset>29</bitOffset>
              <bitWidth>1</bitWidth>
            </field>
            <field>
              <name>BR14</name>
              <bitOffset>30</bitOffset>
              <bitWidth>1</bitWidth>
            </field>
            <field>
              <name>BR15</name>
              <bitOffset>31</bitOffset>
              <bitWidth>1</bitWidth>
            </field>
          </fields>
        </register>
        <register>
          <name>LCKR</name>
          <addressOffset>0x1c</addressOffset>
          <size>0x20</size>
          <fields>
            <field>
              <name>LCK0</name>
              <bitOffset>0</bitOffset>
              <bitWidth>1</bitWidth>
            </field>
            <field>
              <name>LCK1</name>
              <bitOffset>1</bitOffset>
              <bitWidth>1</bitWidth>
            </field>
            <field>
              <name>LCK2</name>
              <bitOffset>2</bitOffset>
              <bitWidth>1</bitWidth>
            </field>
            <field>
              <name>LCK3</name>
              <bitOffset>3</bitOffset>
              <bitWidth>1</bitWidth>
            </field>
            <field>
              <name>LCK4</name>
              <bitOffset>4</bitOffset>
              <bitWidth>1</bitWidth>
            </field>
            <field>
              <name>LCK5</name>
              <bitOffset>5</bitOffset>
              <bitWidth>1</bitWidth>
            </field>
            <field>
              <name>LCK6</name>
              <bitOffset>6</bitOffset>
              <bitWidth>1</bitWidth>
            </field>
            <field>
              <name>LCK7</name>
              <bitOffset>7</bitOffset>
              <bitWidth>1</bitWidth>
            </field>
            <field>
              <name>LCK8</name>
              <bitOffset>8</bitOffset>
              <bitWidth>1</bitWidth>
            </field>
            <field>
              <name>LCK9</name>
              <bitOffset>9</bitOffset>
              <bitWidth>1</bitWidth>
            </field>
            <field>
              <name>LCK10</name>
              <bitOffset>10</bitOffset>
              <bitWidth>1</bitWidth>
            </field>
            <field>
              <name>LCK11</name>
              <bitOffset>11</bitOffset>
              <bitWidth>1</bitWidth>
            </field>
            <field>
              <name>LCK12</name>
              <bitOffset>12</bitOffset>
              <bitWidth>1</bitWidth>
            </field>
            <field>
              <name>LCK13</name>
              <bitOffset>13</bitOffset>
              <bitWidth>1</bitWidth>
            </field>
            <field>
              <name>LCK14</name>
              <bitOffset>14</bitOffset>
              <bitWidth>1</bitWidth>
            </field>
            <field>
              <name>LCK15</name>
              <bitOffset>15</bitOffset>
              <bitWidth>1</bitWidth>
            </field>
            <field>
              <name>LCKK</name>
              <bitOffset>16</bitOffset>
              <bitWidth>1</bitWidth>
            </field>
          </fields>
        </register>
        <register>
          <name>AFR.0</name>
          <addressOffset>0x20</addressOffset>
          <size>0x20</size>
          <fields>
            <field>
              <name>AFSEL0</name>
              <bitOffset>0</bitOffset>
              <bitWidth>4</bitWidth>
            </field>
            <field>
              <name>AFSEL1</name>
              <bitOffset>4</bitOffset>
              <bitWidth>4</bitWidth>
            </field>
            <field>
              <name>AFSEL2</name>
              <bitOffset>8</bitOffset>
              <bitWidth>4</bitWidth>
            </field>
            <field>
              <name>AFSEL3</name>
              <bitOffset>12</bitOffset>
              <bitWidth>4</bitWidth>
            </field>
            <field>
              <name>AFSEL4</name>
              <bitOffset>16</bitOffset>
              <bitWidth>4</bitWidth>
            </field>
            <field>
              <name>AFSEL5</name>
              <bitOffset>20</bitOffset>
              <bitWidth>4</bitWidth>
            </field>
            <field>
              <name>AFSEL6</name>
              <bitOffset>24</bitOffset>
              <bitWidth>4</bitWidth>
            </field>
            <field>
              <name>AFSEL7</name>
              <bitOffset>28</bitOffset>
              <bitWidth>4</bitWidth>
            </field>
          </fields>
        </register>
        <register>
          <name>AFR.1</name>
          <addressOffset>0x24</addressOffset>
          <size>0x20</size>
          <fields>
            <field>
              <name>AFSEL8</name>
              <bitOffset>0</bitOffset>
              <bitWidth>4</bitWidth>
            </field>
            <field>
              <name>AFSEL9</name>
              <bitOffset>4</bitOffset>
              <bitWidth>4</bitWidth>
            </field>
            <field>
              <name>AFSEL10</name>
              <bitOffset>8</bitOffset>
              <bitWidth>4</bitWidth>
            </field>
            <field>
              <name>AFSEL11</name>
              <bitOffset>12</bitOffset>
              <bitWidth>4</bitWidth>
            </field>
            <field>
              <name>AFSEL12</name>
              <bitOffset>16</bitOffset>
              <bitWidth>4</bitWidth>
            </field>
            <field>
              <name>AFSEL13</name>
              <bitOffset>20</bitOffset>
              <bitWidth>4</bitWidth>
            </field>
            <field>
              <name>AFSEL14</name>
              <bitOffset>24</bitOffset>
              <bitWidth>4</bitWidth>
            </field>
            <field>
              <name>AFSEL15</name>
              <bitOffset>28</bitOffset>
              <bitWidth>4</bitWidth>
            </field>
          </fields>
        </register>
      </registers>
    </peripheral>
    <peripheral>
      <name>GPIOE</name>
      <baseAddress>0x58021000</baseAddress>
      <registers>
        <register>
          <name>MODER</name>
          <addressOffset>0x0</addressOffset>
          <size>0x20</size>
          <fields>
            <field>
              <name>MODE0</name>
              <bitOffset>0</bitOffset>
              <bitWidth>2</bitWidth>
            </field>
            <field>
              <name>MODE1</name>
              <bitOffset>2</bitOffset>
              <bitWidth>2</bitWidth>
            </field>
            <field>
              <name>MODE2</name>
              <bitOffset>4</bitOffset>
              <bitWidth>2</bitWidth>
            </field>
            <field>
              <name>MODE3</name>
              <bitOffset>6</bitOffset>
              <bitWidth>2</bitWidth>
            </field>
            <field>
              <name>MODE4</name>
              <bitOffset>8</bitOffset>
              <bitWidth>2</bitWidth>
            </field>
            <field>
              <name>MODE5</name>
              <bitOffset>10</bitOffset>
              <bitWidth>2</bitWidth>
            </field>
            <field>
              <name>MODE6</name>
              <bitOffset>12</bitOffset>
              <bitWidth>2</bitWidth>
            </field>
            <field>
              <name>MODE7</name>
              <bitOffset>14</bitOffset>
              <bitWidth>2</bitWidth>
            </field>
            <field>
              <name>MODE8</name>
              <bitOffset>16</bitOffset>
              <bitWidth>2</bitWidth>
            </field>
            <field>
              <name>MODE9</name>
              <bitOffset>18</bitOffset>
              <bitWidth>2</bitWidth>
            </field>
            <field>
              <name>MODE10</name>
              <bitOffset>20</bitOffset>
              <bitWidth>2</bitWidth>
            </field>
            <field>
              <name>MODE11</name>
              <bitOffset>22</bitOffset>
              <bitWidth>2</bitWidth>
            </field>
            <field>
              <name>MODE12</name>
              <bitOffset>24</bitOffset>
              <bitWidth>2</bitWidth>
            </field>
            <field>
              <name>MODE13</name>
              <bitOffset>26</bitOffset>
              <bitWidth>2</bitWidth>
            </field>
            <field>
              <name>MODE14</name>
              <bitOffset>28</bitOffset>
              <bitWidth>2</bitWidth>
            </field>
            <field>
              <name>MODE15</name>
              <bitOffset>30</bitOffset>
              <bitWidth>2</bitWidth>
            </field>
          </fields>
        </register>
        <register>
          <name>OTYPER</name>
          <addressOffset>0x4</addressOffset>
          <size>0x20</size>
          <fields>
            <field>
              <name>OT0</name>
              <bitOffset>0</bitOffset>
              <bitWidth>1</bitWidth>
            </field>
            <field>
              <name>OT1</name>
              <bitOffset>1</bitOffset>
              <bitWidth>1</bitWidth>
            </field>
            <field>
              <name>OT2</name>
              <bitOffset>2</bitOffset>
              <bitWidth>1</bitWidth>
            </field>
            <field>
              <name>OT3</name>
              <bitOffset>3</bitOffset>
              <bitWidth>1</bitWidth>
            </field>
            <field>
              <name>OT4</name>
              <bitOffset>4</bitOffset>
              <bitWidth>1</bitWidth>
            </field>
            <field>
              <name>OT5</name>
              <bitOffset>5</bitOffset>
              <bitWidth>1</bitWidth>
            </field>
            <field>
              <name>OT6</name>
              <bitOffset>6</bitOffset>
              <bitWidth>1</bitWidth>
            </field>
            <field>
              <name>OT7</name>
              <bitOffset>7</bitOffset>
              <bitWidth>1</bitWidth>
            </field>
            <field>
              <name>OT8</name>
              <bitOffset>8</bitOffset>
              <bitWidth>1</bitWidth>
            </field>
            <field>
              <name>OT9</name>
              <bitOffset>9</bitOffset>
              <bitWidth>1</bitWidth>
            </field>
            <field>
              <name>OT10</name>
              <bitOffset>10</bitOffset>
              <bitWidth>1</bitWidth>
            </field>
            <field>
              <name>OT11</name>
              <bitOffset>11</bitOffset>
              <bitWidth>1</bitWidth>
            </field>
            <field>
              <name>OT12</name>
              <bitOffset>12</bitOffset>
              <bitWidth>1</bitWidth>
            </field>
            <field>
              <name>OT13</name>
              <bitOffset>13</bitOffset>
              <bitWidth>1</bitWidth>
            </field>
            <field>
              <name>OT14</name>
              <bitOffset>14</bitOffset>
              <bitWidth>1</bitWidth>
            </field>
            <field>
              <name>OT15</name>
              <bitOffset>15</bitOffset>
              <bitWidth>1</bitWidth>
            </field>
          </fields>
        </register>
        <register>
          <name>OSPEEDR</name>
          <addressOffset>0x8</addressOffset>
          <size>0x20</size>
          <fields>
            <field>
              <name>OSPEED0</name>
              <bitOffset>0</bitOffset>
              <bitWidth>2</bitWidth>
            </field>
            <field>
              <name>OSPEED1</name>
              <bitOffset>2</bitOffset>
              <bitWidth>2</bitWidth>
            </field>
            <field>
              <name>OSPEED2</name>
              <bitOffset>4</bitOffset>
              <bitWidth>2</bitWidth>
            </field>
            <field>
              <name>OSPEED3</name>
              <bitOffset>6</bitOffset>
              <bitWidth>2</bitWidth>
            </field>
            <field>
              <name>OSPEED4</name>
              <bitOffset>8</bitOffset>
              <bitWidth>2</bitWidth>
            </field>
            <field>
              <name>OSPEED5</name>
              <bitOffset>10</bitOffset>
              <bitWidth>2</bitWidth>
            </field>
            <field>
              <name>OSPEED6</name>
              <bitOffset>12</bitOffset>
              <bitWidth>2</bitWidth>
            </field>
            <field>
              <name>OSPEED7</name>
              <bitOffset>14</bitOffset>
              <bitWidth>2</bitWidth>
            </field>
            <field>
              <name>OSPEED8</name>
              <bitOffset>16</bitOffset>
              <bitWidth>2</bitWidth>
            </field>
            <field>
              <name>OSPEED9</name>
              <bitOffset>18</bitOffset>
              <bitWidth>2</bitWidth>
            </field>
            <field>
              <name>OSPEED10</name>
              <bitOffset>20</bitOffset>
              <bitWidth>2</bitWidth>
            </field>
            <field>
              <name>OSPEED11</name>
              <bitOffset>22</bitOffset>
              <bitWidth>2</bitWidth>
            </field>
            <field>
              <name>OSPEED12</name>
              <bitOffset>24</bitOffset>
              <bitWidth>2</bitWidth>
            </field>
            <field>
              <name>OSPEED13</name>
              <bitOffset>26</bitOffset>
              <bitWidth>2</bitWidth>
            </field>
            <field>
              <name>OSPEED14</name>
              <bitOffset>28</bitOffset>
              <bitWidth>2</bitWidth>
            </field>
            <field>
              <name>OSPEED15</name>
              <bitOffset>30</bitOffset>
              <bitWidth>2</bitWidth>
            </field>
          </fields>
        </register>
        <register>
          <name>PUPDR</name>
          <addressOffset>0xc</addressOffset>
          <size>0x20</size>
          <fields>
            <field>
              <name>PUPD0</name>
              <bitOffset>0</bitOffset>
              <bitWidth>2</bitWidth>
            </field>
            <field>
              <name>PUPD1</name>
              <bitOffset>2</bitOffset>
              <bitWidth>2</bitWidth>
            </field>
            <field>
              <name>PUPD2</name>
              <bitOffset>4</bitOffset>
              <bitWidth>2</bitWidth>
            </field>
            <field>
              <name>PUPD3</name>
              <bitOffset>6</bitOffset>
              <bitWidth>2</bitWidth>
            </field>
            <field>
              <name>PUPD4</name>
              <bitOffset>8</bitOffset>
              <bitWidth>2</bitWidth>
            </field>
            <field>
              <name>PUPD5</name>
              <bitOffset>10</bitOffset>
              <bitWidth>2</bitWidth>
            </field>
            <field>
              <name>PUPD6</name>
              <bitOffset>12</bitOffset>
              <bitWidth>2</bitWidth>
            </field>
            <field>
              <name>PUPD7</name>
              <bitOffset>14</bitOffset>
              <bitWidth>2</bitWidth>
            </field>
            <field>
              <name>PUPD8</name>
              <bitOffset>16</bitOffset>
              <bitWidth>2</bitWidth>
            </field>
            <field>
              <name>PUPD9</name>
              <bitOffset>18</bitOffset>
              <bitWidth>2</bitWidth>
            </field>
            <field>
              <name>PUPD10</name>
              <bitOffset>20</bitOffset>
              <bitWidth>2</bitWidth>
            </field>
            <field>
              <name>PUPD11</name>
              <bitOffset>22</bitOffset>
              <bitWidth>2</bitWidth>
            </field>
            <field>
              <name>PUPD12</name>
              <bitOffset>24</bitOffset>
              <bitWidth>2</bitWidth>
            </field>
            <field>
              <name>PUPD13</name>
              <bitOffset>26</bitOffset>
              <bitWidth>2</bitWidth>
            </field>
            <field>
              <name>PUPD14</name>
              <bitOffset>28</bitOffset>
              <bitWidth>2</bitWidth>
            </field>
            <field>
              <name>PUPD15</name>
              <bitOffset>30</bitOffset>
              <bitWidth>2</bitWidth>
            </field>
          </fields>
        </register>
        <register>
          <name>IDR</name>
          <addressOffset>0x10</addressOffset>
          <size>0x20</size>
          <fields>
            <field>
              <name>ID0</name>
              <bitOffset>0</bitOffset>
              <bitWidth>1</bitWidth>
            </field>
            <field>
              <name>ID1</name>
              <bitOffset>1</bitOffset>
              <bitWidth>1</bitWidth>
            </field>
            <field>
              <name>ID2</name>
              <bitOffset>2</bitOffset>
              <bitWidth>1</bitWidth>
            </field>
            <field>
              <name>ID3</name>
              <bitOffset>3</bitOffset>
              <bitWidth>1</bitWidth>
            </field>
            <field>
              <name>ID4</name>
              <bitOffset>4</bitOffset>
              <bitWidth>1</bitWidth>
            </field>
            <field>
              <name>ID5</name>
              <bitOffset>5</bitOffset>
              <bitWidth>1</bitWidth>
            </field>
            <field>
              <name>ID6</name>
              <bitOffset>6</bitOffset>
              <bitWidth>1</bitWidth>
            </field>
            <field>
              <name>ID7</name>
              <bitOffset>7</bitOffset>
              <bitWidth>1</bitWidth>
            </field>
            <field>
              <name>ID8</name>
              <bitOffset>8</bitOffset>
              <bitWidth>1</bitWidth>
            </field>
            <field>
              <name>ID9</name>
              <bitOffset>9</bitOffset>
              <bitWidth>1</bitWidth>
            </field>
            <field>
              <name>ID10</name>
              <bitOffset>10</bitOffset>
              <bitWidth>1</bitWidth>
            </field>
            <field>
              <name>ID11</name>
              <bitOffset>11</bitOffset>
              <bitWidth>1</bitWidth>
            </field>
            <field>
              <name>ID12</name>
              <bitOffset>12</bitOffset>
              <bitWidth>1</bitWidth>
            </field>
            <field>
              <name>ID13</name>
              <bitOffset>13</bitOffset>
              <bitWidth>1</bitWidth>
            </field>
            <field>
              <name>ID14</name>
              <bitOffset>14</bitOffset>
              <bitWidth>1</bitWidth>
            </field>
            <field>
              <name>ID15</name>
              <bitOffset>15</bitOffset>
              <bitWidth>1</bitWidth>
            </field>
          </fields>
        </register>
        <register>
          <name>ODR</name>
          <addressOffset>0x14</addressOffset>
          <size>0x20</size>
          <fields>
            <field>
              <name>OD0</name>
              <bitOffset>0</bitOffset>
              <bitWidth>1</bitWidth>
            </field>
            <field>
              <name>OD1</name>
              <bitOffset>1</bitOffset>
              <bitWidth>1</bitWidth>
            </field>
            <field>
              <name>OD2</name>
              <bitOffset>2</bitOffset>
              <bitWidth>1</bitWidth>
            </field>
            <field>
              <name>OD3</name>
              <bitOffset>3</bitOffset>
              <bitWidth>1</bitWidth>
            </field>
            <field>
              <name>OD4</name>
              <bitOffset>4</bitOffset>
              <bitWidth>1</bitWidth>
            </field>
            <field>
              <name>OD5</name>
              <bitOffset>5</bitOffset>
              <bitWidth>1</bitWidth>
            </field>
            <field>
              <name>OD6</name>
              <bitOffset>6</bitOffset>
              <bitWidth>1</bitWidth>
            </field>
            <field>
              <name>OD7</name>
              <bitOffset>7</bitOffset>
              <bitWidth>1</bitWidth>
            </field>
            <field>
              <name>OD8</name>
              <bitOffset>8</bitOffset>
              <bitWidth>1</bitWidth>
            </field>
            <field>
              <name>OD9</name>
              <bitOffset>9</bitOffset>
              <bitWidth>1</bitWidth>
            </field>
            <field>
              <name>OD10</name>
              <bitOffset>10</bitOffset>
              <bitWidth>1</bitWidth>
            </field>
            <field>
              <name>OD11</name>
              <bitOffset>11</bitOffset>
              <bitWidth>1</bitWidth>
            </field>
            <field>
              <name>OD12</name>
              <bitOffset>12</bitOffset>
              <bitWidth>1</bitWidth>
            </field>
            <field>
              <name>OD13</name>
              <bitOffset>13</bitOffset>
              <bitWidth>1</bitWidth>
            </field>
            <field>
              <name>OD14</name>
              <bitOffset>14</bitOffset>
              <bitWidth>1</bitWidth>
            </field>
            <field>
              <name>OD15</name>
              <bitOffset>15</bitOffset>
              <bitWidth>1</bitWidth>
            </field>
          </fields>
        </register>
        <register>
          <name>BSRR</name>
          <addressOffset>0x18</addressOffset>
          <size>0x20</size>
          <fields>
            <field>
              <name>BS0</name>
              <bitOffset>0</bitOffset>
              <bitWidth>1</bitWidth>
            </field>
            <field>
              <name>BS1</name>
              <bitOffset>1</bitOffset>
              <bitWidth>1</bitWidth>
            </field>
            <field>
              <name>BS2</name>
              <bitOffset>2</bitOffset>
              <bitWidth>1</bitWidth>
            </field>
            <field>
              <name>BS3</name>
              <bitOffset>3</bitOffset>
              <bitWidth>1</bitWidth>
            </field>
            <field>
              <name>BS4</name>
              <bitOffset>4</bitOffset>
              <bitWidth>1</bitWidth>
            </field>
            <field>
              <name>BS5</name>
              <bitOffset>5</bitOffset>
              <bitWidth>1</bitWidth>
            </field>
            <field>
              <name>BS6</name>
              <bitOffset>6</bitOffset>
              <bitWidth>1</bitWidth>
            </field>
            <field>
              <name>BS7</name>
              <bitOffset>7</bitOffset>
              <bitWidth>1</bitWidth>
            </field>
            <field>
              <name>BS8</name>
              <bitOffset>8</bitOffset>
              <bitWidth>1</bitWidth>
            </field>
            <field>
              <name>BS9</name>
              <bitOffset>9</bitOffset>
              <bitWidth>1</bitWidth>
            </field>
            <field>
              <name>BS10</name>
              <bitOffset>10</bitOffset>
              <bitWidth>1</bitWidth>
            </field>
            <field>
              <name>BS11</name>
              <bitOffset>11</bitOffset>
              <bitWidth>1</bitWidth>
            </field>
            <field>
              <name>BS12</name>
              <bitOffset>12</bitOffset>
              <bitWidth>1</bitWidth>
            </field>
            <field>
              <name>BS13</name>
              <bitOffset>13</bitOffset>
              <bitWidth>1</bitWidth>
            </field>
            <field>
              <name>BS14</name>
              <bitOffset>14</bitOffset>
              <bitWidth>1</bitWidth>
            </field>
            <field>
              <name>BS15</name>
              <bitOffset>15</bitOffset>
              <bitWidth>1</bitWidth>
            </field>
            <field>
              <name>BR0</name>
              <bitOffset>16</bitOffset>
              <bitWidth>1</bitWidth>
            </field>
            <field>
              <name>BR1</name>
              <bitOffset>17</bitOffset>
              <bitWidth>1</bitWidth>
            </field>
            <field>
              <name>BR2</name>
              <bitOffset>18</bitOffset>
              <bitWidth>1</bitWidth>
            </field>
            <field>
              <name>BR3</name>
              <bitOffset>19</bitOffset>
              <bitWidth>1</bitWidth>
            </field>
            <field>
              <name>BR4</name>
              <bitOffset>20</bitOffset>
              <bitWidth>1</bitWidth>
            </field>
            <field>
              <name>BR5</name>
              <bitOffset>21</bitOffset>
              <bitWidth>1</bitWidth>
            </field>
            <field>
              <name>BR6</name>
              <bitOffset>22</bitOffset>
              <bitWidth>1</bitWidth>
            </field>
            <field>
              <name>BR7</name>
              <bitOffset>23</bitOffset>
              <bitWidth>1</bitWidth>
            </field>
            <field>
              <name>BR8</name>
              <bitOffset>24</bitOffset>
              <bitWidth>1</bitWidth>
            </field>
            <field>
              <name>BR9</name>
              <bitOffset>25</bitOffset>
              <bitWidth>1</bitWidth>
            </field>
            <field>
              <name>BR10</name>
              <bitOffset>26</bitOffset>
              <bitWidth>1</bitWidth>
            </field>
            <field>
              <name>BR11</name>
              <bitOffset>27</bitOffset>
              <bitWidth>1</bitWidth>
            </field>
            <field>
              <name>BR12</name>
              <bitOffset>28</bitOffset>
              <bitWidth>1</bitWidth>
            </field>
            <field>
              <name>BR13</name>
              <bitOffset>29</bitOffset>
              <bitWidth>1</bitWidth>
            </field>
            <field>
              <name>BR14</name>
              <bitOffset>30</bitOffset>
              <bitWidth>1</bitWidth>
            </field>
            <field>
              <name>BR15</name>
              <bitOffset>31</bitOffset>
              <bitWidth>1</bitWidth>
            </field>
          </fields>
        </register>
        <register>
          <name>LCKR</name>
          <addressOffset>0x1c</addressOffset>
          <size>0x20</size>
          <fields>
            <field>
              <name>LCK0</name>
              <bitOffset>0</bitOffset>
              <bitWidth>1</bitWidth>
            </field>
            <field>
              <name>LCK1</name>
              <bitOffset>1</bitOffset>
              <bitWidth>1</bitWidth>
            </field>
            <field>
              <name>LCK2</name>
              <bitOffset>2</bitOffset>
              <bitWidth>1</bitWidth>
            </field>
            <field>
              <name>LCK3</name>
              <bitOffset>3</bitOffset>
              <bitWidth>1</bitWidth>
            </field>
            <field>
              <name>LCK4</name>
              <bitOffset>4</bitOffset>
              <bitWidth>1</bitWidth>
            </field>
            <field>
              <name>LCK5</name>
              <bitOffset>5</bitOffset>
              <bitWidth>1</bitWidth>
            </field>
            <field>
              <name>LCK6</name>
              <bitOffset>6</bitOffset>
              <bitWidth>1</bitWidth>
            </field>
            <field>
              <name>LCK7</name>
              <bitOffset>7</bitOffset>
              <bitWidth>1</bitWidth>
            </field>
            <field>
              <name>LCK8</name>
              <bitOffset>8</bitOffset>
              <bitWidth>1</bitWidth>
            </field>
            <field>
              <name>LCK9</name>
              <bitOffset>9</bitOffset>
              <bitWidth>1</bitWidth>
            </field>
            <field>
              <name>LCK10</name>
              <bitOffset>10</bitOffset>
              <bitWidth>1</bitWidth>
            </field>
            <field>
              <name>LCK11</name>
              <bitOffset>11</bitOffset>
              <bitWidth>1</bitWidth>
            </field>
            <field>
              <name>LCK12</name>
              <bitOffset>12</bitOffset>
              <bitWidth>1</bitWidth>
            </field>
            <field>
              <name>LCK13</name>
              <bitOffset>13</bitOffset>
              <bitWidth>1</bitWidth>
            </field>
            <field>
              <name>LCK14</name>
              <bitOffset>14</bitOffset>
              <bitWidth>1</bitWidth>
            </field>
            <field>
              <name>LCK15</name>
              <bitOffset>15</bitOffset>
              <bitWidth>1</bitWidth>
            </field>
            <field>
              <name>LCKK</name>
              <bitOffset>16</bitOffset>
              <bitWidth>1</bitWidth>
            </field>
          </fields>
        </register>
        <register>
          <name>AFR.0</name>
          <addressOffset>0x20</addressOffset>
          <size>0x20</size>
          <fields>
            <field>
              <name>AFSEL0</name>
              <bitOffset>0</bitOffset>
              <bitWidth>4</bitWidth>
            </field>
            <field>
              <name>AFSEL1</name>
              <bitOffset>4</bitOffset>
              <bitWidth>4</bitWidth>
            </field>
            <field>
              <name>AFSEL2</name>
              <bitOffset>8</bitOffset>
              <bitWidth>4</bitWidth>
            </field>
            <field>
              <name>AFSEL3</name>
              <bitOffset>12</bitOffset>
              <bitWidth>4</bitWidth>
            </field>
            <field>
              <name>AFSEL4</name>
              <bitOffset>16</bitOffset>
              <bitWidth>4</bitWidth>
            </field>
            <field>
              <name>AFSEL5</name>
              <bitOffset>20</bitOffset>
              <bitWidth>4</bitWidth>
            </field>
            <field>
              <name>AFSEL6</name>
              <bitOffset>24</bitOffset>
              <bitWidth>4</bitWidth>
            </field>
            <field>
              <name>AFSEL7</name>
              <bitOffset>28</bitOffset>
              <bitWidth>4</bitWidth>
            </field>
          </fields>
        </register>
        <register>
          <name>AFR.1</name>
          <addressOffset>0x24</addressOffset>
          <size>0x20</size>
          <fields>
            <field>
              <name>AFSEL8</name>
              <bitOffset>0</bitOffset>
              <bitWidth>4</bitWidth>
            </field>
            <field>
              <name>AFSEL9</name>
              <bitOffset>4</bitOffset>
              <bitWidth>4</bitWidth>
            </field>
            <field>
              <name>AFSEL10</name>
              <bitOffset>8</bitOffset>
              <bitWidth>4</bitWidth>
            </field>
            <field>
              <name>AFSEL11</name>
              <bitOffset>12</bitOffset>
              <bitWidth>4</bitWidth>
            </field>
            <field>
              <name>AFSEL12</name>
              <bitOffset>16</bitOffset>
              <bitWidth>4</bitWidth>
            </field>
            <field>
              <name>AFSEL13</name>
              <bitOffset>20</bitOffset>
              <bitWidth>4</bitWidth>
            </field>
            <field>
              <name>AFSEL14</name>
              <bitOffset>24</bitOffset>
              <bitWidth>4</bitWidth>
            </field>
            <field>
              <name>AFSEL15</name>
              <bitOffset>28</bitOffset>
              <bitWidth>4</bitWidth>
            </field>
          </fields>
        </register>
      </registers>
    </peripheral>
    <peripheral>
      <name>GPIOF</name>
      <baseAddress>0x58021400</baseAddress>
      <registers>
        <register>
          <name>MODER</name>
          <addressOffset>0x0</addressOffset>
          <size>0x20</size>
          <fields>
            <field>
              <name>MODE0</name>
              <bitOffset>0</bitOffset>
              <bitWidth>2</bitWidth>
            </field>
            <field>
              <name>MODE1</name>
              <bitOffset>2</bitOffset>
              <bitWidth>2</bitWidth>
            </field>
            <field>
              <name>MODE2</name>
              <bitOffset>4</bitOffset>
              <bitWidth>2</bitWidth>
            </field>
            <field>
              <name>MODE3</name>
              <bitOffset>6</bitOffset>
              <bitWidth>2</bitWidth>
            </field>
            <field>
              <name>MODE4</name>
              <bitOffset>8</bitOffset>
              <bitWidth>2</bitWidth>
            </field>
            <field>
              <name>MODE5</name>
              <bitOffset>10</bitOffset>
              <bitWidth>2</bitWidth>
            </field>
            <field>
              <name>MODE6</name>
              <bitOffset>12</bitOffset>
              <bitWidth>2</bitWidth>
            </field>
            <field>
              <name>MODE7</name>
              <bitOffset>14</bitOffset>
              <bitWidth>2</bitWidth>
            </field>
            <field>
              <name>MODE8</name>
              <bitOffset>16</bitOffset>
              <bitWidth>2</bitWidth>
            </field>
            <field>
              <name>MODE9</name>
              <bitOffset>18</bitOffset>
              <bitWidth>2</bitWidth>
            </field>
            <field>
              <name>MODE10</name>
              <bitOffset>20</bitOffset>
              <bitWidth>2</bitWidth>
            </field>
            <field>
              <name>MODE11</name>
              <bitOffset>22</bitOffset>
              <bitWidth>2</bitWidth>
            </field>
            <field>
              <name>MODE12</name>
              <bitOffset>24</bitOffset>
              <bitWidth>2</bitWidth>
            </field>
            <field>
              <name>MODE13</name>
              <bitOffset>26</bitOffset>
              <bitWidth>2</bitWidth>
            </field>
            <field>
              <name>MODE14</name>
              <bitOffset>28</bitOffset>
              <bitWidth>2</bitWidth>
            </field>
            <field>
              <name>MODE15</name>
              <bitOffset>30</bitOffset>
              <bitWidth>2</bitWidth>
            </field>
          </fields>
        </register>
        <register>
          <name>OTYPER</name>
          <addressOffset>0x4</addressOffset>
          <size>0x20</size>
          <fields>
            <field>
              <name>OT0</name>
              <bitOffset>0</bitOffset>
              <bitWidth>1</bitWidth>
            </field>
            <field>
              <name>OT1</name>
              <bitOffset>1</bitOffset>
              <bitWidth>1</bitWidth>
            </field>
            <field>
              <name>OT2</name>
              <bitOffset>2</bitOffset>
              <bitWidth>1</bitWidth>
            </field>
            <field>
              <name>OT3</name>
              <bitOffset>3</bitOffset>
              <bitWidth>1</bitWidth>
            </field>
            <field>
              <name>OT4</name>
              <bitOffset>4</bitOffset>
              <bitWidth>1</bitWidth>
            </field>
            <field>
              <name>OT5</name>
              <bitOffset>5</bitOffset>
              <bitWidth>1</bitWidth>
            </field>
            <field>
              <name>OT6</name>
              <bitOffset>6</bitOffset>
              <bitWidth>1</bitWidth>
            </field>
            <field>
              <name>OT7</name>
              <bitOffset>7</bitOffset>
              <bitWidth>1</bitWidth>
            </field>
            <field>
              <name>OT8</name>
              <bitOffset>8</bitOffset>
              <bitWidth>1</bitWidth>
            </field>
            <field>
              <name>OT9</name>
              <bitOffset>9</bitOffset>
              <bitWidth>1</bitWidth>
            </field>
            <field>
              <name>OT10</name>
              <bitOffset>10</bitOffset>
              <bitWidth>1</bitWidth>
            </field>
            <field>
              <name>OT11</name>
              <bitOffset>11</bitOffset>
              <bitWidth>1</bitWidth>
            </field>
            <field>
              <name>OT12</name>
              <bitOffset>12</bitOffset>
              <bitWidth>1</bitWidth>
            </field>
            <field>
              <name>OT13</name>
              <bitOffset>13</bitOffset>
              <bitWidth>1</bitWidth>
            </field>
            <field>
              <name>OT14</name>
              <bitOffset>14</bitOffset>
              <bitWidth>1</bitWidth>
            </field>
            <field>
              <name>OT15</name>
              <bitOffset>15</bitOffset>
              <bitWidth>1</bitWidth>
            </field>
          </fields>
        </register>
        <register>
          <name>OSPEEDR</name>
          <addressOffset>0x8</addressOffset>
          <size>0x20</size>
          <fields>
            <field>
              <name>OSPEED0</name>
              <bitOffset>0</bitOffset>
              <bitWidth>2</bitWidth>
            </field>
            <field>
              <name>OSPEED1</name>
              <bitOffset>2</bitOffset>
              <bitWidth>2</bitWidth>
            </field>
            <field>
              <name>OSPEED2</name>
              <bitOffset>4</bitOffset>
              <bitWidth>2</bitWidth>
            </field>
            <field>
              <name>OSPEED3</name>
              <bitOffset>6</bitOffset>
              <bitWidth>2</bitWidth>
            </field>
            <field>
              <name>OSPEED4</name>
              <bitOffset>8</bitOffset>
              <bitWidth>2</bitWidth>
            </field>
            <field>
              <name>OSPEED5</name>
              <bitOffset>10</bitOffset>
              <bitWidth>2</bitWidth>
            </field>
            <field>
              <name>OSPEED6</name>
              <bitOffset>12</bitOffset>
              <bitWidth>2</bitWidth>
            </field>
            <field>
              <name>OSPEED7</name>
              <bitOffset>14</bitOffset>
              <bitWidth>2</bitWidth>
            </field>
            <field>
              <name>OSPEED8</name>
              <bitOffset>16</bitOffset>
              <bitWidth>2</bitWidth>
            </field>
            <field>
              <name>OSPEED9</name>
              <bitOffset>18</bitOffset>
              <bitWidth>2</bitWidth>
            </field>
            <field>
              <name>OSPEED10</name>
              <bitOffset>20</bitOffset>
              <bitWidth>2</bitWidth>
            </field>
            <field>
              <name>OSPEED11</name>
              <bitOffset>22</bitOffset>
              <bitWidth>2</bitWidth>
            </field>
            <field>
              <name>OSPEED12</name>
              <bitOffset>24</bitOffset>
              <bitWidth>2</bitWidth>
            </field>
            <field>
              <name>OSPEED13</name>
              <bitOffset>26</bitOffset>
              <bitWidth>2</bitWidth>
            </field>
            <field>
              <name>OSPEED14</name>
              <bitOffset>28</bitOffset>
              <bitWidth>2</bitWidth>
            </field>
            <field>
              <name>OSPEED15</name>
              <bitOffset>30</bitOffset>
              <bitWidth>2</bitWidth>
            </field>
          </fields>
        </register>
        <register>
          <name>PUPDR</name>
          <addressOffset>0xc</addressOffset>
          <size>0x20</size>
          <fields>
            <field>
              <name>PUPD0</name>
              <bitOffset>0</bitOffset>
              <bitWidth>2</bitWidth>
            </field>
            <field>
              <name>PUPD1</name>
              <bitOffset>2</bitOffset>
              <bitWidth>2</bitWidth>
            </field>
            <field>
              <name>PUPD2</name>
              <bitOffset>4</bitOffset>
              <bitWidth>2</bitWidth>
            </field>
            <field>
              <name>PUPD3</name>
              <bitOffset>6</bitOffset>
              <bitWidth>2</bitWidth>
            </field>
            <field>
              <name>PUPD4</name>
              <bitOffset>8</bitOffset>
              <bitWidth>2</bitWidth>
            </field>
            <field>
              <name>PUPD5</name>
              <bitOffset>10</bitOffset>
              <bitWidth>2</bitWidth>
            </field>
            <field>
              <name>PUPD6</name>
              <bitOffset>12</bitOffset>
              <bitWidth>2</bitWidth>
            </field>
            <field>
              <name>PUPD7</name>
              <bitOffset>14</bitOffset>
              <bitWidth>2</bitWidth>
            </field>
            <field>
              <name>PUPD8</name>
              <bitOffset>16</bitOffset>
              <bitWidth>2</bitWidth>
            </field>
            <field>
              <name>PUPD9</name>
              <bitOffset>18</bitOffset>
              <bitWidth>2</bitWidth>
            </field>
            <field>
              <name>PUPD10</name>
              <bitOffset>20</bitOffset>
              <bitWidth>2</bitWidth>
            </field>
            <field>
              <name>PUPD11</name>
              <bitOffset>22</bitOffset>
              <bitWidth>2</bitWidth>
            </field>
            <field>
              <name>PUPD12</name>
              <bitOffset>24</bitOffset>
              <bitWidth>2</bitWidth>
            </field>
            <field>
              <name>PUPD13</name>
              <bitOffset>26</bitOffset>
              <bitWidth>2</bitWidth>
            </field>
            <field>
              <name>PUPD14</name>
              <bitOffset>28</bitOffset>
              <bitWidth>2</bitWidth>
            </field>
            <field>
              <name>PUPD15</name>
              <bitOffset>30</bitOffset>
              <bitWidth>2</bitWidth>
            </field>
          </fields>
        </register>
        <register>
          <name>IDR</name>
          <addressOffset>0x10</addressOffset>
          <size>0x20</size>
          <fields>
            <field>
              <name>ID0</name>
              <bitOffset>0</bitOffset>
              <bitWidth>1</bitWidth>
            </field>
            <field>
              <name>ID1</name>
              <bitOffset>1</bitOffset>
              <bitWidth>1</bitWidth>
            </field>
            <field>
              <name>ID2</name>
              <bitOffset>2</bitOffset>
              <bitWidth>1</bitWidth>
            </field>
            <field>
              <name>ID3</name>
              <bitOffset>3</bitOffset>
              <bitWidth>1</bitWidth>
            </field>
            <field>
              <name>ID4</name>
              <bitOffset>4</bitOffset>
              <bitWidth>1</bitWidth>
            </field>
            <field>
              <name>ID5</name>
              <bitOffset>5</bitOffset>
              <bitWidth>1</bitWidth>
            </field>
            <field>
              <name>ID6</name>
              <bitOffset>6</bitOffset>
              <bitWidth>1</bitWidth>
            </field>
            <field>
              <name>ID7</name>
              <bitOffset>7</bitOffset>
              <bitWidth>1</bitWidth>
            </field>
            <field>
              <name>ID8</name>
              <bitOffset>8</bitOffset>
              <bitWidth>1</bitWidth>
            </field>
            <field>
              <name>ID9</name>
              <bitOffset>9</bitOffset>
              <bitWidth>1</bitWidth>
            </field>
            <field>
              <name>ID10</name>
              <bitOffset>10</bitOffset>
              <bitWidth>1</bitWidth>
            </field>
            <field>
              <name>ID11</name>
              <bitOffset>11</bitOffset>
              <bitWidth>1</bitWidth>
            </field>
            <field>
              <name>ID12</name>
              <bitOffset>12</bitOffset>
              <bitWidth>1</bitWidth>
            </field>
            <field>
              <name>ID13</name>
              <bitOffset>13</bitOffset>
              <bitWidth>1</bitWidth>
            </field>
            <field>
              <name>ID14</name>
              <bitOffset>14</bitOffset>
              <bitWidth>1</bitWidth>
            </field>
            <field>
              <name>ID15</name>
              <bitOffset>15</bitOffset>
              <bitWidth>1</bitWidth>
            </field>
          </fields>
        </register>
        <register>
          <name>ODR</name>
          <addressOffset>0x14</addressOffset>
          <size>0x20</size>
          <fields>
            <field>
              <name>OD0</name>
              <bitOffset>0</bitOffset>
              <bitWidth>1</bitWidth>
            </field>
            <field>
              <name>OD1</name>
              <bitOffset>1</bitOffset>
              <bitWidth>1</bitWidth>
            </field>
            <field>
              <name>OD2</name>
              <bitOffset>2</bitOffset>
              <bitWidth>1</bitWidth>
            </field>
            <field>
              <name>OD3</name>
              <bitOffset>3</bitOffset>
              <bitWidth>1</bitWidth>
            </field>
            <field>
              <name>OD4</name>
              <bitOffset>4</bitOffset>
              <bitWidth>1</bitWidth>
            </field>
            <field>
              <name>OD5</name>
              <bitOffset>5</bitOffset>
              <bitWidth>1</bitWidth>
            </field>
            <field>
              <name>OD6</name>
              <bitOffset>6</bitOffset>
              <bitWidth>1</bitWidth>
            </field>
            <field>
              <name>OD7</name>
              <bitOffset>7</bitOffset>
              <bitWidth>1</bitWidth>
            </field>
            <field>
              <name>OD8</name>
              <bitOffset>8</bitOffset>
              <bitWidth>1</bitWidth>
            </field>
            <field>
              <name>OD9</name>
              <bitOffset>9</bitOffset>
              <bitWidth>1</bitWidth>
            </field>
            <field>
              <name>OD10</name>
              <bitOffset>10</bitOffset>
              <bitWidth>1</bitWidth>
            </field>
            <field>
              <name>OD11</name>
              <bitOffset>11</bitOffset>
              <bitWidth>1</bitWidth>
            </field>
            <field>
              <name>OD12</name>
              <bitOffset>12</bitOffset>
              <bitWidth>1</bitWidth>
            </field>
            <field>
              <name>OD13</name>
              <bitOffset>13</bitOffset>
              <bitWidth>1</bitWidth>
            </field>
            <field>
              <name>OD14</name>
              <bitOffset>14</bitOffset>
              <bitWidth>1</bitWidth>
            </field>
            <field>
              <name>OD15</name>
              <bitOffset>15</bitOffset>
              <bitWidth>1</bitWidth>
            </field>
          </fields>
        </register>
        <register>
          <name>BSRR</name>
          <addressOffset>0x18</addressOffset>
          <size>0x20</size>
          <fields>
            <field>
              <name>BS0</name>
              <bitOffset>0</bitOffset>
              <bitWidth>1</bitWidth>
            </field>
            <field>
              <name>BS1</name>
              <bitOffset>1</bitOffset>
              <bitWidth>1</bitWidth>
            </field>
            <field>
              <name>BS2</name>
              <bitOffset>2</bitOffset>
              <bitWidth>1</bitWidth>
            </field>
            <field>
              <name>BS3</name>
              <bitOffset>3</bitOffset>
              <bitWidth>1</bitWidth>
            </field>
            <field>
              <name>BS4</name>
              <bitOffset>4</bitOffset>
              <bitWidth>1</bitWidth>
            </field>
            <field>
              <name>BS5</name>
              <bitOffset>5</bitOffset>
              <bitWidth>1</bitWidth>
            </field>
            <field>
              <name>BS6</name>
              <bitOffset>6</bitOffset>
              <bitWidth>1</bitWidth>
            </field>
            <field>
              <name>BS7</name>
              <bitOffset>7</bitOffset>
              <bitWidth>1</bitWidth>
            </field>
            <field>
              <name>BS8</name>
              <bitOffset>8</bitOffset>
              <bitWidth>1</bitWidth>
            </field>
            <field>
              <name>BS9</name>
              <bitOffset>9</bitOffset>
              <bitWidth>1</bitWidth>
            </field>
            <field>
              <name>BS10</name>
              <bitOffset>10</bitOffset>
              <bitWidth>1</bitWidth>
            </field>
            <field>
              <name>BS11</name>
              <bitOffset>11</bitOffset>
              <bitWidth>1</bitWidth>
            </field>
            <field>
              <name>BS12</name>
              <bitOffset>12</bitOffset>
              <bitWidth>1</bitWidth>
            </field>
            <field>
              <name>BS13</name>
              <bitOffset>13</bitOffset>
              <bitWidth>1</bitWidth>
            </field>
            <field>
              <name>BS14</name>
              <bitOffset>14</bitOffset>
              <bitWidth>1</bitWidth>
            </field>
            <field>
              <name>BS15</name>
              <bitOffset>15</bitOffset>
              <bitWidth>1</bitWidth>
            </field>
            <field>
              <name>BR0</name>
              <bitOffset>16</bitOffset>
              <bitWidth>1</bitWidth>
            </field>
            <field>
              <name>BR1</name>
              <bitOffset>17</bitOffset>
              <bitWidth>1</bitWidth>
            </field>
            <field>
              <name>BR2</name>
              <bitOffset>18</bitOffset>
              <bitWidth>1</bitWidth>
            </field>
            <field>
              <name>BR3</name>
              <bitOffset>19</bitOffset>
              <bitWidth>1</bitWidth>
            </field>
            <field>
              <name>BR4</name>
              <bitOffset>20</bitOffset>
              <bitWidth>1</bitWidth>
            </field>
            <field>
              <name>BR5</name>
              <bitOffset>21</bitOffset>
              <bitWidth>1</bitWidth>
            </field>
            <field>
              <name>BR6</name>
              <bitOffset>22</bitOffset>
              <bitWidth>1</bitWidth>
            </field>
            <field>
              <name>BR7</name>
              <bitOffset>23</bitOffset>
              <bitWidth>1</bitWidth>
            </field>
            <field>
              <name>BR8</name>
              <bitOffset>24</bitOffset>
              <bitWidth>1</bitWidth>
            </field>
            <field>
              <name>BR9</name>
              <bitOffset>25</bitOffset>
              <bitWidth>1</bitWidth>
            </field>
            <field>
              <name>BR10</name>
              <bitOffset>26</bitOffset>
              <bitWidth>1</bitWidth>
            </field>
            <field>
              <name>BR11</name>
              <bitOffset>27</bitOffset>
              <bitWidth>1</bitWidth>
            </field>
            <field>
              <name>BR12</name>
              <bitOffset>28</bitOffset>
              <bitWidth>1</bitWidth>
            </field>
            <field>
              <name>BR13</name>
              <bitOffset>29</bitOffset>
              <bitWidth>1</bitWidth>
            </field>
            <field>
              <name>BR14</name>
              <bitOffset>30</bitOffset>
              <bitWidth>1</bitWidth>
            </field>
            <field>
              <name>BR15</name>
              <bitOffset>31</bitOffset>
              <bitWidth>1</bitWidth>
            </field>
          </fields>
        </register>
        <register>
          <name>LCKR</name>
          <addressOffset>0x1c</addressOffset>
          <size>0x20</size>
          <fields>
            <field>
              <name>LCK0</name>
              <bitOffset>0</bitOffset>
              <bitWidth>1</bitWidth>
            </field>
            <field>
              <name>LCK1</name>
              <bitOffset>1</bitOffset>
              <bitWidth>1</bitWidth>
            </field>
            <field>
              <name>LCK2</name>
              <bitOffset>2</bitOffset>
              <bitWidth>1</bitWidth>
            </field>
            <field>
              <name>LCK3</name>
              <bitOffset>3</bitOffset>
              <bitWidth>1</bitWidth>
            </field>
            <field>
              <name>LCK4</name>
              <bitOffset>4</bitOffset>
              <bitWidth>1</bitWidth>
            </field>
            <field>
              <name>LCK5</name>
              <bitOffset>5</bitOffset>
              <bitWidth>1</bitWidth>
            </field>
            <field>
              <name>LCK6</name>
              <bitOffset>6</bitOffset>
              <bitWidth>1</bitWidth>
            </field>
            <field>
              <name>LCK7</name>
              <bitOffset>7</bitOffset>
              <bitWidth>1</bitWidth>
            </field>
            <field>
              <name>LCK8</name>
              <bitOffset>8</bitOffset>
              <bitWidth>1</bitWidth>
            </field>
            <field>
              <name>LCK9</name>
              <bitOffset>9</bitOffset>
              <bitWidth>1</bitWidth>
            </field>
            <field>
              <name>LCK10</name>
              <bitOffset>10</bitOffset>
              <bitWidth>1</bitWidth>
            </field>
            <field>
              <name>LCK11</name>
              <bitOffset>11</bitOffset>
              <bitWidth>1</bitWidth>
            </field>
            <field>
              <name>LCK12</name>
              <bitOffset>12</bitOffset>
              <bitWidth>1</bitWidth>
            </field>
            <field>
              <name>LCK13</name>
              <bitOffset>13</bitOffset>
              <bitWidth>1</bitWidth>
            </field>
            <field>
              <name>LCK14</name>
              <bitOffset>14</bitOffset>
              <bitWidth>1</bitWidth>
            </field>
            <field>
              <name>LCK15</name>
              <bitOffset>15</bitOffset>
              <bitWidth>1</bitWidth>
            </field>
            <field>
              <name>LCKK</name>
              <bitOffset>16</bitOffset>
              <bitWidth>1</bitWidth>
            </field>
          </fields>
        </register>
        <register>
          <name>AFR.0</name>
          <addressOffset>0x20</addressOffset>
          <size>0x20</size>
          <fields>
            <field>
              <name>AFSEL0</name>
              <bitOffset>0</bitOffset>
              <bitWidth>4</bitWidth>
            </field>
            <field>
              <name>AFSEL1</name>
              <bitOffset>4</bitOffset>
              <bitWidth>4</bitWidth>
            </field>
            <field>
              <name>AFSEL2</name>
              <bitOffset>8</bitOffset>
              <bitWidth>4</bitWidth>
            </field>
            <field>
              <name>AFSEL3</name>
              <bitOffset>12</bitOffset>
              <bitWidth>4</bitWidth>
            </field>
            <field>
              <name>AFSEL4</name>
              <bitOffset>16</bitOffset>
              <bitWidth>4</bitWidth>
            </field>
            <field>
              <name>AFSEL5</name>
              <bitOffset>20</bitOffset>
              <bitWidth>4</bitWidth>
            </field>
            <field>
              <name>AFSEL6</name>
              <bitOffset>24</bitOffset>
              <bitWidth>4</bitWidth>
            </field>
            <field>
              <name>AFSEL7</name>
              <bitOffset>28</bitOffset>
              <bitWidth>4</bitWidth>
            </field>
          </fields>
        </register>
        <register>
          <name>AFR.1</name>
          <addressOffset>0x24</addressOffset>
          <size>0x20</size>
          <fields>
            <field>
              <name>AFSEL8</name>
              <bitOffset>0</bitOffset>
              <bitWidth>4</bitWidth>
            </field>
            <field>
              <name>AFSEL9</name>
              <bitOffset>4</bitOffset>
              <bitWidth>4</bitWidth>
            </field>
            <field>
              <name>AFSEL10</name>
              <bitOffset>8</bitOffset>
              <bitWidth>4</bitWidth>
            </field>
            <field>
              <name>AFSEL11</name>
              <bitOffset>12</bitOffset>
              <bitWidth>4</bitWidth>
            </field>
            <field>
              <name>AFSEL12</name>
              <bitOffset>16</bitOffset>
              <bitWidth>4</bitWidth>
            </field>
            <field>
              <name>AFSEL13</name>
              <bitOffset>20</bitOffset>
              <bitWidth>4</bitWidth>
            </field>
            <field>
              <name>AFSEL14</name>
              <bitOffset>24</bitOffset>
              <bitWidth>4</bitWidth>
            </field>
            <field>
              <name>AFSEL15</name>
              <bitOffset>28</bitOffset>
              <bitWidth>4</bitWidth>
            </field>
          </fields>
        </register>
      </registers>
    </peripheral>
    <peripheral>
      <name>GPIOG</name>
      <baseAddress>0x58021800</baseAddress>
      <registers>
        <register>
          <name>MODER</name>
          <addressOffset>0x0</addressOffset>
          <size>0x20</size>
          <fields>
            <field>
              <name>MODE0</name>
              <bitOffset>0</bitOffset>
              <bitWidth>2</bitWidth>
            </field>
            <field>
              <name>MODE1</name>
              <bitOffset>2</bitOffset>
              <bitWidth>2</bitWidth>
            </field>
            <field>
              <name>MODE2</name>
              <bitOffset>4</bitOffset>
              <bitWidth>2</bitWidth>
            </field>
            <field>
              <name>MODE3</name>
              <bitOffset>6</bitOffset>
              <bitWidth>2</bitWidth>
            </field>
            <field>
              <name>MODE4</name>
              <bitOffset>8</bitOffset>
              <bitWidth>2</bitWidth>
            </field>
            <field>
              <name>MODE5</name>
              <bitOffset>10</bitOffset>
              <bitWidth>2</bitWidth>
            </field>
            <field>
              <name>MODE6</name>
              <bitOffset>12</bitOffset>
              <bitWidth>2</bitWidth>
            </field>
            <field>
              <name>MODE7</name>
              <bitOffset>14</bitOffset>
              <bitWidth>2</bitWidth>
            </field>
            <field>
              <name>MODE8</name>
              <bitOffset>16</bitOffset>
              <bitWidth>2</bitWidth>
            </field>
            <field>
              <name>MODE9</name>
              <bitOffset>18</bitOffset>
              <bitWidth>2</bitWidth>
            </field>
            <field>
              <name>MODE10</name>
              <bitOffset>20</bitOffset>
              <bitWidth>2</bitWidth>
            </field>
            <field>
              <name>MODE11</name>
              <bitOffset>22</bitOffset>
              <bitWidth>2</bitWidth>
            </field>
            <field>
              <name>MODE12</name>
              <bitOffset>24</bitOffset>
              <bitWidth>2</bitWidth>
            </field>
            <field>
              <name>MODE13</name>
              <bitOffset>26</bitOffset>
              <bitWidth>2</bitWidth>
            </field>
            <field>
              <name>MODE14</name>
              <bitOffset>28</bitOffset>
              <bitWidth>2</bitWidth>
            </field>
            <field>
              <name>MODE15</name>
              <bitOffset>30</bitOffset>
              <bitWidth>2</bitWidth>
            </field>
          </fields>
        </register>
        <register>
          <name>OTYPER</name>
          <addressOffset>0x4</addressOffset>
          <size>0x20</size>
          <fields>
            <field>
              <name>OT0</name>
              <bitOffset>0</bitOffset>
              <bitWidth>1</bitWidth>
            </field>
            <field>
              <name>OT1</name>
              <bitOffset>1</bitOffset>
              <bitWidth>1</bitWidth>
            </field>
            <field>
              <name>OT2</name>
              <bitOffset>2</bitOffset>
              <bitWidth>1</bitWidth>
            </field>
            <field>
              <name>OT3</name>
              <bitOffset>3</bitOffset>
              <bitWidth>1</bitWidth>
            </field>
            <field>
              <name>OT4</name>
              <bitOffset>4</bitOffset>
              <bitWidth>1</bitWidth>
            </field>
            <field>
              <name>OT5</name>
              <bitOffset>5</bitOffset>
              <bitWidth>1</bitWidth>
            </field>
            <field>
              <name>OT6</name>
              <bitOffset>6</bitOffset>
              <bitWidth>1</bitWidth>
            </field>
            <field>
              <name>OT7</name>
              <bitOffset>7</bitOffset>
              <bitWidth>1</bitWidth>
            </field>
            <field>
              <name>OT8</name>
              <bitOffset>8</bitOffset>
              <bitWidth>1</bitWidth>
            </field>
            <field>
              <name>OT9</name>
              <bitOffset>9</bitOffset>
              <bitWidth>1</bitWidth>
            </field>
            <field>
              <name>OT10</name>
              <bitOffset>10</bitOffset>
              <bitWidth>1</bitWidth>
            </field>
            <field>
              <name>OT11</name>
              <bitOffset>11</bitOffset>
              <bitWidth>1</bitWidth>
            </field>
            <field>
              <name>OT12</name>
              <bitOffset>12</bitOffset>
              <bitWidth>1</bitWidth>
            </field>
            <field>
              <name>OT13</name>
              <bitOffset>13</bitOffset>
              <bitWidth>1</bitWidth>
            </field>
            <field>
              <name>OT14</name>
              <bitOffset>14</bitOffset>
              <bitWidth>1</bitWidth>
            </field>
            <field>
              <name>OT15</name>
              <bitOffset>15</bitOffset>
              <bitWidth>1</bitWidth>
            </field>
          </fields>
        </register>
        <register>
          <name>OSPEEDR</name>
          <addressOffset>0x8</addressOffset>
          <size>0x20</size>
          <fields>
            <field>
              <name>OSPEED0</name>
              <bitOffset>0</bitOffset>
              <bitWidth>2</bitWidth>
            </field>
            <field>
              <name>OSPEED1</name>
              <bitOffset>2</bitOffset>
              <bitWidth>2</bitWidth>
            </field>
            <field>
              <name>OSPEED2</name>
              <bitOffset>4</bitOffset>
              <bitWidth>2</bitWidth>
            </field>
            <field>
              <name>OSPEED3</name>
              <bitOffset>6</bitOffset>
              <bitWidth>2</bitWidth>
            </field>
            <field>
              <name>OSPEED4</name>
              <bitOffset>8</bitOffset>
              <bitWidth>2</bitWidth>
            </field>
            <field>
              <name>OSPEED5</name>
              <bitOffset>10</bitOffset>
              <bitWidth>2</bitWidth>
            </field>
            <field>
              <name>OSPEED6</name>
              <bitOffset>12</bitOffset>
              <bitWidth>2</bitWidth>
            </field>
            <field>
              <name>OSPEED7</name>
              <bitOffset>14</bitOffset>
              <bitWidth>2</bitWidth>
            </field>
            <field>
              <name>OSPEED8</name>
              <bitOffset>16</bitOffset>
              <bitWidth>2</bitWidth>
            </field>
            <field>
              <name>OSPEED9</name>
              <bitOffset>18</bitOffset>
              <bitWidth>2</bitWidth>
            </field>
            <field>
              <name>OSPEED10</name>
              <bitOffset>20</bitOffset>
              <bitWidth>2</bitWidth>
            </field>
            <field>
              <name>OSPEED11</name>
              <bitOffset>22</bitOffset>
              <bitWidth>2</bitWidth>
            </field>
            <field>
              <name>OSPEED12</name>
              <bitOffset>24</bitOffset>
              <bitWidth>2</bitWidth>
            </field>
            <field>
              <name>OSPEED13</name>
              <bitOffset>26</bitOffset>
              <bitWidth>2</bitWidth>
            </field>
            <field>
              <name>OSPEED14</name>
              <bitOffset>28</bitOffset>
              <bitWidth>2</bitWidth>
            </field>
            <field>
              <name>OSPEED15</name>
              <bitOffset>30</bitOffset>
              <bitWidth>2</bitWidth>
            </field>
          </fields>
        </register>
        <register>
          <name>PUPDR</name>
          <addressOffset>0xc</addressOffset>
          <size>0x20</size>
          <fields>
            <field>
              <name>PUPD0</name>
              <bitOffset>0</bitOffset>
              <bitWidth>2</bitWidth>
            </field>
            <field>
              <name>PUPD1</name>
              <bitOffset>2</bitOffset>
              <bitWidth>2</bitWidth>
            </field>
            <field>
              <name>PUPD2</name>
              <bitOffset>4</bitOffset>
              <bitWidth>2</bitWidth>
            </field>
            <field>
              <name>PUPD3</name>
              <bitOffset>6</bitOffset>
              <bitWidth>2</bitWidth>
            </field>
            <field>
              <name>PUPD4</name>
              <bitOffset>8</bitOffset>
              <bitWidth>2</bitWidth>
            </field>
            <field>
              <name>PUPD5</name>
              <bitOffset>10</bitOffset>
              <bitWidth>2</bitWidth>
            </field>
            <field>
              <name>PUPD6</name>
              <bitOffset>12</bitOffset>
              <bitWidth>2</bitWidth>
            </field>
            <field>
              <name>PUPD7</name>
              <bitOffset>14</bitOffset>
              <bitWidth>2</bitWidth>
            </field>
            <field>
              <name>PUPD8</name>
              <bitOffset>16</bitOffset>
              <bitWidth>2</bitWidth>
            </field>
            <field>
              <name>PUPD9</name>
              <bitOffset>18</bitOffset>
              <bitWidth>2</bitWidth>
            </field>
            <field>
              <name>PUPD10</name>
              <bitOffset>20</bitOffset>
              <bitWidth>2</bitWidth>
            </field>
            <field>
              <name>PUPD11</name>
              <bitOffset>22</bitOffset>
              <bitWidth>2</bitWidth>
            </field>
            <field>
              <name>PUPD12</name>
              <bitOffset>24</bitOffset>
              <bitWidth>2</bitWidth>
            </field>
            <field>
              <name>PUPD13</name>
              <bitOffset>26</bitOffset>
              <bitWidth>2</bitWidth>
            </field>
            <field>
              <name>PUPD14</name>
              <bitOffset>28</bitOffset>
              <bitWidth>2</bitWidth>
            </field>
            <field>
              <name>PUPD15</name>
              <bitOffset>30</bitOffset>
              <bitWidth>2</bitWidth>
            </field>
          </fields>
        </register>
        <register>
          <name>IDR</name>
          <addressOffset>0x10</addressOffset>
          <size>0x20</size>
          <fields>
            <field>
              <name>ID0</name>
              <bitOffset>0</bitOffset>
              <bitWidth>1</bitWidth>
            </field>
            <field>
              <name>ID1</name>
              <bitOffset>1</bitOffset>
              <bitWidth>1</bitWidth>
            </field>
            <field>
              <name>ID2</name>
              <bitOffset>2</bitOffset>
              <bitWidth>1</bitWidth>
            </field>
            <field>
              <name>ID3</name>
              <bitOffset>3</bitOffset>
              <bitWidth>1</bitWidth>
            </field>
            <field>
              <name>ID4</name>
              <bitOffset>4</bitOffset>
              <bitWidth>1</bitWidth>
            </field>
            <field>
              <name>ID5</name>
              <bitOffset>5</bitOffset>
              <bitWidth>1</bitWidth>
            </field>
            <field>
              <name>ID6</name>
              <bitOffset>6</bitOffset>
              <bitWidth>1</bitWidth>
            </field>
            <field>
              <name>ID7</name>
              <bitOffset>7</bitOffset>
              <bitWidth>1</bitWidth>
            </field>
            <field>
              <name>ID8</name>
              <bitOffset>8</bitOffset>
              <bitWidth>1</bitWidth>
            </field>
            <field>
              <name>ID9</name>
              <bitOffset>9</bitOffset>
              <bitWidth>1</bitWidth>
            </field>
            <field>
              <name>ID10</name>
              <bitOffset>10</bitOffset>
              <bitWidth>1</bitWidth>
            </field>
            <field>
              <name>ID11</name>
              <bitOffset>11</bitOffset>
              <bitWidth>1</bitWidth>
            </field>
            <field>
              <name>ID12</name>
              <bitOffset>12</bitOffset>
              <bitWidth>1</bitWidth>
            </field>
            <field>
              <name>ID13</name>
              <bitOffset>13</bitOffset>
              <bitWidth>1</bitWidth>
            </field>
            <field>
              <name>ID14</name>
              <bitOffset>14</bitOffset>
              <bitWidth>1</bitWidth>
            </field>
            <field>
              <name>ID15</name>
              <bitOffset>15</bitOffset>
              <bitWidth>1</bitWidth>
            </field>
          </fields>
        </register>
        <register>
          <name>ODR</name>
          <addressOffset>0x14</addressOffset>
          <size>0x20</size>
          <fields>
            <field>
              <name>OD0</name>
              <bitOffset>0</bitOffset>
              <bitWidth>1</bitWidth>
            </field>
            <field>
              <name>OD1</name>
              <bitOffset>1</bitOffset>
              <bitWidth>1</bitWidth>
            </field>
            <field>
              <name>OD2</name>
              <bitOffset>2</bitOffset>
              <bitWidth>1</bitWidth>
            </field>
            <field>
              <name>OD3</name>
              <bitOffset>3</bitOffset>
              <bitWidth>1</bitWidth>
            </field>
            <field>
              <name>OD4</name>
              <bitOffset>4</bitOffset>
              <bitWidth>1</bitWidth>
            </field>
            <field>
              <name>OD5</name>
              <bitOffset>5</bitOffset>
              <bitWidth>1</bitWidth>
            </field>
            <field>
              <name>OD6</name>
              <bitOffset>6</bitOffset>
              <bitWidth>1</bitWidth>
            </field>
            <field>
              <name>OD7</name>
              <bitOffset>7</bitOffset>
              <bitWidth>1</bitWidth>
            </field>
            <field>
              <name>OD8</name>
              <bitOffset>8</bitOffset>
              <bitWidth>1</bitWidth>
            </field>
            <field>
              <name>OD9</name>
              <bitOffset>9</bitOffset>
              <bitWidth>1</bitWidth>
            </field>
            <field>
              <name>OD10</name>
              <bitOffset>10</bitOffset>
              <bitWidth>1</bitWidth>
            </field>
            <field>
              <name>OD11</name>
              <bitOffset>11</bitOffset>
              <bitWidth>1</bitWidth>
            </field>
            <field>
              <name>OD12</name>
              <bitOffset>12</bitOffset>
              <bitWidth>1</bitWidth>
            </field>
            <field>
              <name>OD13</name>
              <bitOffset>13</bitOffset>
              <bitWidth>1</bitWidth>
            </field>
            <field>
              <name>OD14</name>
              <bitOffset>14</bitOffset>
              <bitWidth>1</bitWidth>
            </field>
            <field>
              <name>OD15</name>
              <bitOffset>15</bitOffset>
              <bitWidth>1</bitWidth>
            </field>
          </fields>
        </register>
        <register>
          <name>BSRR</name>
          <addressOffset>0x18</addressOffset>
          <size>0x20</size>
          <fields>
            <field>
              <name>BS0</name>
              <bitOffset>0</bitOffset>
              <bitWidth>1</bitWidth>
            </field>
            <field>
              <name>BS1</name>
              <bitOffset>1</bitOffset>
              <bitWidth>1</bitWidth>
            </field>
            <field>
              <name>BS2</name>
              <bitOffset>2</bitOffset>
              <bitWidth>1</bitWidth>
            </field>
            <field>
              <name>BS3</name>
              <bitOffset>3</bitOffset>
              <bitWidth>1</bitWidth>
            </field>
            <field>
              <name>BS4</name>
              <bitOffset>4</bitOffset>
              <bitWidth>1</bitWidth>
            </field>
            <field>
              <name>BS5</name>
              <bitOffset>5</bitOffset>
              <bitWidth>1</bitWidth>
            </field>
            <field>
              <name>BS6</name>
              <bitOffset>6</bitOffset>
              <bitWidth>1</bitWidth>
            </field>
            <field>
              <name>BS7</name>
              <bitOffset>7</bitOffset>
              <bitWidth>1</bitWidth>
            </field>
            <field>
              <name>BS8</name>
              <bitOffset>8</bitOffset>
              <bitWidth>1</bitWidth>
            </field>
            <field>
              <name>BS9</name>
              <bitOffset>9</bitOffset>
              <bitWidth>1</bitWidth>
            </field>
            <field>
              <name>BS10</name>
              <bitOffset>10</bitOffset>
              <bitWidth>1</bitWidth>
            </field>
            <field>
              <name>BS11</name>
              <bitOffset>11</bitOffset>
              <bitWidth>1</bitWidth>
            </field>
            <field>
              <name>BS12</name>
              <bitOffset>12</bitOffset>
              <bitWidth>1</bitWidth>
            </field>
            <field>
              <name>BS13</name>
              <bitOffset>13</bitOffset>
              <bitWidth>1</bitWidth>
            </field>
            <field>
              <name>BS14</name>
              <bitOffset>14</bitOffset>
              <bitWidth>1</bitWidth>
            </field>
            <field>
              <name>BS15</name>
              <bitOffset>15</bitOffset>
              <bitWidth>1</bitWidth>
            </field>
            <field>
              <name>BR0</name>
              <bitOffset>16</bitOffset>
              <bitWidth>1</bitWidth>
            </field>
            <field>
              <name>BR1</name>
              <bitOffset>17</bitOffset>
              <bitWidth>1</bitWidth>
            </field>
            <field>
              <name>BR2</name>
              <bitOffset>18</bitOffset>
              <bitWidth>1</bitWidth>
            </field>
            <field>
              <name>BR3</name>
              <bitOffset>19</bitOffset>
              <bitWidth>1</bitWidth>
            </field>
            <field>
              <name>BR4</name>
              <bitOffset>20</bitOffset>
              <bitWidth>1</bitWidth>
            </field>
            <field>
              <name>BR5</name>
              <bitOffset>21</bitOffset>
              <bitWidth>1</bitWidth>
            </field>
            <field>
              <name>BR6</name>
              <bitOffset>22</bitOffset>
              <bitWidth>1</bitWidth>
            </field>
            <field>
              <name>BR7</name>
              <bitOffset>23</bitOffset>
              <bitWidth>1</bitWidth>
            </field>
            <field>
              <name>BR8</name>
              <bitOffset>24</bitOffset>
              <bitWidth>1</bitWidth>
            </field>
            <field>
              <name>BR9</name>
              <bitOffset>25</bitOffset>
              <bitWidth>1</bitWidth>
            </field>
            <field>
              <name>BR10</name>
              <bitOffset>26</bitOffset>
              <bitWidth>1</bitWidth>
            </field>
            <field>
              <name>BR11</name>
              <bitOffset>27</bitOffset>
              <bitWidth>1</bitWidth>
            </field>
            <field>
              <name>BR12</name>
              <bitOffset>28</bitOffset>
              <bitWidth>1</bitWidth>
            </field>
            <field>
              <name>BR13</name>
              <bitOffset>29</bitOffset>
              <bitWidth>1</bitWidth>
            </field>
            <field>
              <name>BR14</name>
              <bitOffset>30</bitOffset>
              <bitWidth>1</bitWidth>
            </field>
            <field>
              <name>BR15</name>
              <bitOffset>31</bitOffset>
              <bitWidth>1</bitWidth>
            </field>
          </fields>
        </register>
        <register>
          <name>LCKR</name>
          <addressOffset>0x1c</addressOffset>
          <size>0x20</size>
          <fields>
            <field>
              <name>LCK0</name>
              <bitOffset>0</bitOffset>
              <bitWidth>1</bitWidth>
            </field>
            <field>
              <name>LCK1</name>
              <bitOffset>1</bitOffset>
              <bitWidth>1</bitWidth>
            </field>
            <field>
              <name>LCK2</name>
              <bitOffset>2</bitOffset>
              <bitWidth>1</bitWidth>
            </field>
            <field>
              <name>LCK3</name>
              <bitOffset>3</bitOffset>
              <bitWidth>1</bitWidth>
            </field>
            <field>
              <name>LCK4</name>
              <bitOffset>4</bitOffset>
              <bitWidth>1</bitWidth>
            </field>
            <field>
              <name>LCK5</name>
              <bitOffset>5</bitOffset>
              <bitWidth>1</bitWidth>
            </field>
            <field>
              <name>LCK6</name>
              <bitOffset>6</bitOffset>
              <bitWidth>1</bitWidth>
            </field>
            <field>
              <name>LCK7</name>
              <bitOffset>7</bitOffset>
              <bitWidth>1</bitWidth>
            </field>
            <field>
              <name>LCK8</name>
              <bitOffset>8</bitOffset>
              <bitWidth>1</bitWidth>
            </field>
            <field>
              <name>LCK9</name>
              <bitOffset>9</bitOffset>
              <bitWidth>1</bitWidth>
            </field>
            <field>
              <name>LCK10</name>
              <bitOffset>10</bitOffset>
              <bitWidth>1</bitWidth>
            </field>
            <field>
              <name>LCK11</name>
              <bitOffset>11</bitOffset>
              <bitWidth>1</bitWidth>
            </field>
            <field>
              <name>LCK12</name>
              <bitOffset>12</bitOffset>
              <bitWidth>1</bitWidth>
            </field>
            <field>
              <name>LCK13</name>
              <bitOffset>13</bitOffset>
              <bitWidth>1</bitWidth>
            </field>
            <field>
              <name>LCK14</name>
              <bitOffset>14</bitOffset>
              <bitWidth>1</bitWidth>
            </field>
            <field>
              <name>LCK15</name>
              <bitOffset>15</bitOffset>
              <bitWidth>1</bitWidth>
            </field>
            <field>
              <name>LCKK</name>
              <bitOffset>16</bitOffset>
              <bitWidth>1</bitWidth>
            </field>
          </fields>
        </register>
        <register>
          <name>AFR.0</name>
          <addressOffset>0x20</addressOffset>
          <size>0x20</size>
          <fields>
            <field>
              <name>AFSEL0</name>
              <bitOffset>0</bitOffset>
              <bitWidth>4</bitWidth>
            </field>
            <field>
              <name>AFSEL1</name>
              <bitOffset>4</bitOffset>
              <bitWidth>4</bitWidth>
            </field>
            <field>
              <name>AFSEL2</name>
              <bitOffset>8</bitOffset>
              <bitWidth>4</bitWidth>
            </field>
            <field>
              <name>AFSEL3</name>
              <bitOffset>12</bitOffset>
              <bitWidth>4</bitWidth>
            </field>
            <field>
              <name>AFSEL4</name>
              <bitOffset>16</bitOffset>
              <bitWidth>4</bitWidth>
            </field>
            <field>
              <name>AFSEL5</name>
              <bitOffset>20</bitOffset>
              <bitWidth>4</bitWidth>
            </field>
            <field>
              <name>AFSEL6</name>
              <bitOffset>24</bitOffset>
              <bitWidth>4</bitWidth>
            </field>
            <field>
              <name>AFSEL7</name>
              <bitOffset>28</bitOffset>
              <bitWidth>4</bitWidth>
            </field>
          </fields>
        </register>
        <register>
          <name>AFR.1</name>
          <addressOffset>0x24</addressOffset>
          <size>0x20</size>
          <fields>
            <field>
              <name>AFSEL8</name>
              <bitOffset>0</bitOffset>
              <bitWidth>4</bitWidth>
            </field>
            <field>
              <name>AFSEL9</name>
              <bitOffset>4</bitOffset>
              <bitWidth>4</bitWidth>
            </field>
            <field>
              <name>AFSEL10</name>
              <bitOffset>8</bitOffset>
              <bitWidth>4</bitWidth>
            </field>
            <field>
              <name>AFSEL11</name>
              <bitOffset>12</bitOffset>
              <bitWidth>4</bitWidth>
            </field>
            <field>
              <name>AFSEL12</name>
              <bitOffset>16</bitOffset>
              <bitWidth>4</bitWidth>
            </field>
            <field>
              <name>AFSEL13</name>
              <bitOffset>20</bitOffset>
              <bitWidth>4</bitWidth>
            </field>
            <field>
              <name>AFSEL14</name>
              <bitOffset>24</bitOffset>
              <bitWidth>4</bitWidth>
            </field>
            <field>
              <name>AFSEL15</name>
              <bitOffset>28</bitOffset>
              <bitWidth>4</bitWidth>
            </field>
          </fields>
        </register>
      </registers>
    </peripheral>
    <peripheral>
      <name>GPIOH</name>
      <baseAddress>0x58021c00</baseAddress>
      <registers>
        <register>
          <name>MODER</name>
          <addressOffset>0x0</addressOffset>
          <size>0x20</size>
          <fields>
            <field>
              <name>MODE0</name>
              <bitOffset>0</bitOffset>
              <bitWidth>2</bitWidth>
            </field>
            <field>
              <name>MODE1</name>
              <bitOffset>2</bitOffset>
              <bitWidth>2</bitWidth>
            </field>
            <field>
              <name>MODE2</name>
              <bitOffset>4</bitOffset>
              <bitWidth>2</bitWidth>
            </field>
            <field>
              <name>MODE3</name>
              <bitOffset>6</bitOffset>
              <bitWidth>2</bitWidth>
            </field>
            <field>
              <name>MODE4</name>
              <bitOffset>8</bitOffset>
              <bitWidth>2</bitWidth>
            </field>
            <field>
              <name>MODE5</name>
              <bitOffset>10</bitOffset>
              <bitWidth>2</bitWidth>
            </field>
            <field>
              <name>MODE6</name>
              <bitOffset>12</bitOffset>
              <bitWidth>2</bitWidth>
            </field>
            <field>
              <name>MODE7</name>
              <bitOffset>14</bitOffset>
              <bitWidth>2</bitWidth>
            </field>
            <field>
              <name>MODE8</name>
              <bitOffset>16</bitOffset>
              <bitWidth>2</bitWidth>
            </field>
            <field>
              <name>MODE9</name>
              <bitOffset>18</bitOffset>
              <bitWidth>2</bitWidth>
            </field>
            <field>
              <name>MODE10</name>
              <bitOffset>20</bitOffset>
              <bitWidth>2</bitWidth>
            </field>
            <field>
              <name>MODE11</name>
              <bitOffset>22</bitOffset>
              <bitWidth>2</bitWidth>
            </field>
            <field>
              <name>MODE12</name>
              <bitOffset>24</bitOffset>
              <bitWidth>2</bitWidth>
            </field>
            <field>
              <name>MODE13</name>
              <bitOffset>26</bitOffset>
              <bitWidth>2</bitWidth>
            </field>
            <field>
              <name>MODE14</name>
              <bitOffset>28</bitOffset>
              <bitWidth>2</bitWidth>
            </field>
            <field>
              <name>MODE15</name>
              <bitOffset>30</bitOffset>
              <bitWidth>2</bitWidth>
            </field>
          </fields>
        </register>
        <register>
          <name>OTYPER</name>
          <addressOffset>0x4</addressOffset>
          <size>0x20</size>
          <fields>
            <field>
              <name>OT0</name>
              <bitOffset>0</bitOffset>
              <bitWidth>1</bitWidth>
            </field>
            <field>
              <name>OT1</name>
              <bitOffset>1</bitOffset>
              <bitWidth>1</bitWidth>
            </field>
            <field>
              <name>OT2</name>
              <bitOffset>2</bitOffset>
              <bitWidth>1</bitWidth>
            </field>
            <field>
              <name>OT3</name>
              <bitOffset>3</bitOffset>
              <bitWidth>1</bitWidth>
            </field>
            <field>
              <name>OT4</name>
              <bitOffset>4</bitOffset>
              <bitWidth>1</bitWidth>
            </field>
            <field>
              <name>OT5</name>
              <bitOffset>5</bitOffset>
              <bitWidth>1</bitWidth>
            </field>
            <field>
              <name>OT6</name>
              <bitOffset>6</bitOffset>
              <bitWidth>1</bitWidth>
            </field>
            <field>
              <name>OT7</name>
              <bitOffset>7</bitOffset>
              <bitWidth>1</bitWidth>
            </field>
            <field>
              <name>OT8</name>
              <bitOffset>8</bitOffset>
              <bitWidth>1</bitWidth>
            </field>
            <field>
              <name>OT9</name>
              <bitOffset>9</bitOffset>
              <bitWidth>1</bitWidth>
            </field>
            <field>
              <name>OT10</name>
              <bitOffset>10</bitOffset>
              <bitWidth>1</bitWidth>
            </field>
            <field>
              <name>OT11</name>
              <bitOffset>11</bitOffset>
              <bitWidth>1</bitWidth>
            </field>
            <field>
              <name>OT12</name>
              <bitOffset>12</bitOffset>
              <bitWidth>1</bitWidth>
            </field>
            <field>
              <name>OT13</name>
              <bitOffset>13</bitOffset>
              <bitWidth>1</bitWidth>
            </field>
            <field>
              <name>OT14</name>
              <bitOffset>14</bitOffset>
              <bitWidth>1</bitWidth>
            </field>
            <field>
              <name>OT15</name>
              <bitOffset>15</bitOffset>
              <bitWidth>1</bitWidth>
            </field>
          </fields>
        </register>
        <register>
          <name>OSPEEDR</name>
          <addressOffset>0x8</addressOffset>
          <size>0x20</size>
          <fields>
            <field>
              <name>OSPEED0</name>
              <bitOffset>0</bitOffset>
              <bitWidth>2</bitWidth>
            </field>
            <field>
              <name>OSPEED1</name>
              <bitOffset>2</bitOffset>
              <bitWidth>2</bitWidth>
            </field>
            <field>
              <name>OSPEED2</name>
              <bitOffset>4</bitOffset>
              <bitWidth>2</bitWidth>
            </field>
            <field>
              <name>OSPEED3</name>
              <bitOffset>6</bitOffset>
              <bitWidth>2</bitWidth>
            </field>
            <field>
              <name>OSPEED4</name>
              <bitOffset>8</bitOffset>
              <bitWidth>2</bitWidth>
            </field>
            <field>
              <name>OSPEED5</name>
              <bitOffset>10</bitOffset>
              <bitWidth>2</bitWidth>
            </field>
            <field>
              <name>OSPEED6</name>
              <bitOffset>12</bitOffset>
              <bitWidth>2</bitWidth>
            </field>
            <field>
              <name>OSPEED7</name>
              <bitOffset>14</bitOffset>
              <bitWidth>2</bitWidth>
            </field>
            <field>
              <name>OSPEED8</name>
              <bitOffset>16</bitOffset>
              <bitWidth>2</bitWidth>
            </field>
            <field>
              <name>OSPEED9</name>
              <bitOffset>18</bitOffset>
              <bitWidth>2</bitWidth>
            </field>
            <field>
              <name>OSPEED10</name>
              <bitOffset>20</bitOffset>
              <bitWidth>2</bitWidth>
            </field>
            <field>
              <name>OSPEED11</name>
              <bitOffset>22</bitOffset>
              <bitWidth>2</bitWidth>
            </field>
            <field>
              <name>OSPEED12</name>
              <bitOffset>24</bitOffset>
              <bitWidth>2</bitWidth>
            </field>
            <field>
              <name>OSPEED13</name>
              <bitOffset>26</bitOffset>
              <bitWidth>2</bitWidth>
            </field>
            <field>
              <name>OSPEED14</name>
              <bitOffset>28</bitOffset>
              <bitWidth>2</bitWidth>
            </field>
            <field>
              <name>OSPEED15</name>
              <bitOffset>30</bitOffset>
              <bitWidth>2</bitWidth>
            </field>
          </fields>
        </register>
        <register>
          <name>PUPDR</name>
          <addressOffset>0xc</addressOffset>
          <size>0x20</size>
          <fields>
            <field>
              <name>PUPD0</name>
              <bitOffset>0</bitOffset>
              <bitWidth>2</bitWidth>
            </field>
            <field>
              <name>PUPD1</name>
              <bitOffset>2</bitOffset>
              <bitWidth>2</bitWidth>
            </field>
            <field>
              <name>PUPD2</name>
              <bitOffset>4</bitOffset>
              <bitWidth>2</bitWidth>
            </field>
            <field>
              <name>PUPD3</name>
              <bitOffset>6</bitOffset>
              <bitWidth>2</bitWidth>
            </field>
            <field>
              <name>PUPD4</name>
              <bitOffset>8</bitOffset>
              <bitWidth>2</bitWidth>
            </field>
            <field>
              <name>PUPD5</name>
              <bitOffset>10</bitOffset>
              <bitWidth>2</bitWidth>
            </field>
            <field>
              <name>PUPD6</name>
              <bitOffset>12</bitOffset>
              <bitWidth>2</bitWidth>
            </field>
            <field>
              <name>PUPD7</name>
              <bitOffset>14</bitOffset>
              <bitWidth>2</bitWidth>
            </field>
            <field>
              <name>PUPD8</name>
              <bitOffset>16</bitOffset>
              <bitWidth>2</bitWidth>
            </field>
            <field>
              <name>PUPD9</name>
              <bitOffset>18</bitOffset>
              <bitWidth>2</bitWidth>
            </field>
            <field>
              <name>PUPD10</name>
              <bitOffset>20</bitOffset>
              <bitWidth>2</bitWidth>
            </field>
            <field>
              <name>PUPD11</name>
              <bitOffset>22</bitOffset>
              <bitWidth>2</bitWidth>
            </field>
            <field>
              <name>PUPD12</name>
              <bitOffset>24</bitOffset>
              <bitWidth>2</bitWidth>
            </field>
            <field>
              <name>PUPD13</name>
              <bitOffset>26</bitOffset>
              <bitWidth>2</bitWidth>
            </field>
            <field>
              <name>PUPD14</name>
              <bitOffset>28</bitOffset>
              <bitWidth>2</bitWidth>
            </field>
            <field>
              <name>PUPD15</name>
              <bitOffset>30</bitOffset>
              <bitWidth>2</bitWidth>
            </field>
          </fields>
        </register>
        <register>
          <name>IDR</name>
          <addressOffset>0x10</addressOffset>
          <size>0x20</size>
          <fields>
            <field>
              <name>ID0</name>
              <bitOffset>0</bitOffset>
              <bitWidth>1</bitWidth>
            </field>
            <field>
              <name>ID1</name>
              <bitOffset>1</bitOffset>
              <bitWidth>1</bitWidth>
            </field>
            <field>
              <name>ID2</name>
              <bitOffset>2</bitOffset>
              <bitWidth>1</bitWidth>
            </field>
            <field>
              <name>ID3</name>
              <bitOffset>3</bitOffset>
              <bitWidth>1</bitWidth>
            </field>
            <field>
              <name>ID4</name>
              <bitOffset>4</bitOffset>
              <bitWidth>1</bitWidth>
            </field>
            <field>
              <name>ID5</name>
              <bitOffset>5</bitOffset>
              <bitWidth>1</bitWidth>
            </field>
            <field>
              <name>ID6</name>
              <bitOffset>6</bitOffset>
              <bitWidth>1</bitWidth>
            </field>
            <field>
              <name>ID7</name>
              <bitOffset>7</bitOffset>
              <bitWidth>1</bitWidth>
            </field>
            <field>
              <name>ID8</name>
              <bitOffset>8</bitOffset>
              <bitWidth>1</bitWidth>
            </field>
            <field>
              <name>ID9</name>
              <bitOffset>9</bitOffset>
              <bitWidth>1</bitWidth>
            </field>
            <field>
              <name>ID10</name>
              <bitOffset>10</bitOffset>
              <bitWidth>1</bitWidth>
            </field>
            <field>
              <name>ID11</name>
              <bitOffset>11</bitOffset>
              <bitWidth>1</bitWidth>
            </field>
            <field>
              <name>ID12</name>
              <bitOffset>12</bitOffset>
              <bitWidth>1</bitWidth>
            </field>
            <field>
              <name>ID13</name>
              <bitOffset>13</bitOffset>
              <bitWidth>1</bitWidth>
            </field>
            <field>
              <name>ID14</name>
              <bitOffset>14</bitOffset>
              <bitWidth>1</bitWidth>
            </field>
            <field>
              <name>ID15</name>
              <bitOffset>15</bitOffset>
              <bitWidth>1</bitWidth>
            </field>
          </fields>
        </register>
        <register>
          <name>ODR</name>
          <addressOffset>0x14</addressOffset>
          <size>0x20</size>
          <fields>
            <field>
              <name>OD0</name>
              <bitOffset>0</bitOffset>
              <bitWidth>1</bitWidth>
            </field>
            <field>
              <name>OD1</name>
              <bitOffset>1</bitOffset>
              <bitWidth>1</bitWidth>
            </field>
            <field>
              <name>OD2</name>
              <bitOffset>2</bitOffset>
              <bitWidth>1</bitWidth>
            </field>
            <field>
              <name>OD3</name>
              <bitOffset>3</bitOffset>
              <bitWidth>1</bitWidth>
            </field>
            <field>
              <name>OD4</name>
              <bitOffset>4</bitOffset>
              <bitWidth>1</bitWidth>
            </field>
            <field>
              <name>OD5</name>
              <bitOffset>5</bitOffset>
              <bitWidth>1</bitWidth>
            </field>
            <field>
              <name>OD6</name>
              <bitOffset>6</bitOffset>
              <bitWidth>1</bitWidth>
            </field>
            <field>
              <name>OD7</name>
              <bitOffset>7</bitOffset>
              <bitWidth>1</bitWidth>
            </field>
            <field>
              <name>OD8</name>
              <bitOffset>8</bitOffset>
              <bitWidth>1</bitWidth>
            </field>
            <field>
              <name>OD9</name>
              <bitOffset>9</bitOffset>
              <bitWidth>1</bitWidth>
            </field>
            <field>
              <name>OD10</name>
              <bitOffset>10</bitOffset>
              <bitWidth>1</bitWidth>
            </field>
            <field>
              <name>OD11</name>
              <bitOffset>11</bitOffset>
              <bitWidth>1</bitWidth>
            </field>
            <field>
              <name>OD12</name>
              <bitOffset>12</bitOffset>
              <bitWidth>1</bitWidth>
            </field>
            <field>
              <name>OD13</name>
              <bitOffset>13</bitOffset>
              <bitWidth>1</bitWidth>
            </field>
            <field>
              <name>OD14</name>
              <bitOffset>14</bitOffset>
              <bitWidth>1</bitWidth>
            </field>
            <field>
              <name>OD15</name>
              <bitOffset>15</bitOffset>
              <bitWidth>1</bitWidth>
            </field>
          </fields>
        </register>
        <register>
          <name>BSRR</name>
          <addressOffset>0x18</addressOffset>
          <size>0x20</size>
          <fields>
            <field>
              <name>BS0</name>
              <bitOffset>0</bitOffset>
              <bitWidth>1</bitWidth>
            </field>
            <field>
              <name>BS1</name>
              <bitOffset>1</bitOffset>
              <bitWidth>1</bitWidth>
            </field>
            <field>
              <name>BS2</name>
              <bitOffset>2</bitOffset>
              <bitWidth>1</bitWidth>
            </field>
            <field>
              <name>BS3</name>
              <bitOffset>3</bitOffset>
              <bitWidth>1</bitWidth>
            </field>
            <field>
              <name>BS4</name>
              <bitOffset>4</bitOffset>
              <bitWidth>1</bitWidth>
            </field>
            <field>
              <name>BS5</name>
              <bitOffset>5</bitOffset>
              <bitWidth>1</bitWidth>
            </field>
            <field>
              <name>BS6</name>
              <bitOffset>6</bitOffset>
              <bitWidth>1</bitWidth>
            </field>
            <field>
              <name>BS7</name>
              <bitOffset>7</bitOffset>
              <bitWidth>1</bitWidth>
            </field>
            <field>
              <name>BS8</name>
              <bitOffset>8</bitOffset>
              <bitWidth>1</bitWidth>
            </field>
            <field>
              <name>BS9</name>
              <bitOffset>9</bitOffset>
              <bitWidth>1</bitWidth>
            </field>
            <field>
              <name>BS10</name>
              <bitOffset>10</bitOffset>
              <bitWidth>1</bitWidth>
            </field>
            <field>
              <name>BS11</name>
              <bitOffset>11</bitOffset>
              <bitWidth>1</bitWidth>
            </field>
            <field>
              <name>BS12</name>
              <bitOffset>12</bitOffset>
              <bitWidth>1</bitWidth>
            </field>
            <field>
              <name>BS13</name>
              <bitOffset>13</bitOffset>
              <bitWidth>1</bitWidth>
            </field>
            <field>
              <name>BS14</name>
              <bitOffset>14</bitOffset>
              <bitWidth>1</bitWidth>
            </field>
            <field>
              <name>BS15</name>
              <bitOffset>15</bitOffset>
              <bitWidth>1</bitWidth>
            </field>
            <field>
              <name>BR0</name>
              <bitOffset>16</bitOffset>
              <bitWidth>1</bitWidth>
            </field>
            <field>
              <name>BR1</name>
              <bitOffset>17</bitOffset>
              <bitWidth>1</bitWidth>
            </field>
            <field>
              <name>BR2</name>
              <bitOffset>18</bitOffset>
              <bitWidth>1</bitWidth>
            </field>
            <field>
              <name>BR3</name>
              <bitOffset>19</bitOffset>
              <bitWidth>1</bitWidth>
            </field>
            <field>
              <name>BR4</name>
              <bitOffset>20</bitOffset>
              <bitWidth>1</bitWidth>
            </field>
            <field>
              <name>BR5</name>
              <bitOffset>21</bitOffset>
              <bitWidth>1</bitWidth>
            </field>
            <field>
              <name>BR6</name>
              <bitOffset>22</bitOffset>
              <bitWidth>1</bitWidth>
            </field>
            <field>
              <name>BR7</name>
              <bitOffset>23</bitOffset>
              <bitWidth>1</bitWidth>
            </field>
            <field>
              <name>BR8</name>
              <bitOffset>24</bitOffset>
              <bitWidth>1</bitWidth>
            </field>
            <field>
              <name>BR9</name>
              <bitOffset>25</bitOffset>
              <bitWidth>1</bitWidth>
            </field>
            <field>
              <name>BR10</name>
              <bitOffset>26</bitOffset>
              <bitWidth>1</bitWidth>
            </field>
            <field>
              <name>BR11</name>
              <bitOffset>27</bitOffset>
              <bitWidth>1</bitWidth>
            </field>
            <field>
              <name>BR12</name>
              <bitOffset>28</bitOffset>
              <bitWidth>1</bitWidth>
            </field>
            <field>
              <name>BR13</name>
              <bitOffset>29</bitOffset>
              <bitWidth>1</bitWidth>
            </field>
            <field>
              <name>BR14</name>
              <bitOffset>30</bitOffset>
              <bitWidth>1</bitWidth>
            </field>
            <field>
              <name>BR15</name>
              <bitOffset>31</bitOffset>
              <bitWidth>1</bitWidth>
            </field>
          </fields>
        </register>
        <register>
          <name>LCKR</name>
          <addressOffset>0x1c</addressOffset>
          <size>0x20</size>
          <fields>
            <field>
              <name>LCK0</name>
              <bitOffset>0</bitOffset>
              <bitWidth>1</bitWidth>
            </field>
            <field>
              <name>LCK1</name>
              <bitOffset>1</bitOffset>
              <bitWidth>1</bitWidth>
            </field>
            <field>
              <name>LCK2</name>
              <bitOffset>2</bitOffset>
              <bitWidth>1</bitWidth>
            </field>
            <field>
              <name>LCK3</name>
              <bitOffset>3</bitOffset>
              <bitWidth>1</bitWidth>
            </field>
            <field>
              <name>LCK4</name>
              <bitOffset>4</bitOffset>
              <bitWidth>1</bitWidth>
            </field>
            <field>
              <name>LCK5</name>
              <bitOffset>5</bitOffset>
              <bitWidth>1</bitWidth>
            </field>
            <field>
              <name>LCK6</name>
              <bitOffset>6</bitOffset>
              <bitWidth>1</bitWidth>
            </field>
            <field>
              <name>LCK7</name>
              <bitOffset>7</bitOffset>
              <bitWidth>1</bitWidth>
            </field>
            <field>
              <name>LCK8</name>
              <bitOffset>8</bitOffset>
              <bitWidth>1</bitWidth>
            </field>
            <field>
              <name>LCK9</name>
              <bitOffset>9</bitOffset>
              <bitWidth>1</bitWidth>
            </field>
            <field>
              <name>LCK10</name>
              <bitOffset>10</bitOffset>
              <bitWidth>1</bitWidth>
            </field>
            <field>
              <name>LCK11</name>
              <bitOffset>11</bitOffset>
              <bitWidth>1</bitWidth>
            </field>
            <field>
              <name>LCK12</name>
              <bitOffset>12</bitOffset>
              <bitWidth>1</bitWidth>
            </field>
            <field>
              <name>LCK13</name>
              <bitOffset>13</bitOffset>
              <bitWidth>1</bitWidth>
            </field>
            <field>
              <name>LCK14</name>
              <bitOffset>14</bitOffset>
              <bitWidth>1</bitWidth>
            </field>
            <field>
              <name>LCK15</name>
              <bitOffset>15</bitOffset>
              <bitWidth>1</bitWidth>
            </field>
            <field>
              <name>LCKK</name>
              <bitOffset>16</bitOffset>
              <bitWidth>1</bitWidth>
            </field>
          </fields>
        </register>
        <register>
          <name>AFR.0</name>
          <addressOffset>0x20</addressOffset>
          <size>0x20</size>
          <fields>
            <field>
              <name>AFSEL0</name>
              <bitOffset>0</bitOffset>
              <bitWidth>4</bitWidth>
            </field>
            <field>
              <name>AFSEL1</name>
              <bitOffset>4</bitOffset>
              <bitWidth>4</bitWidth>
            </field>
            <field>
              <name>AFSEL2</name>
              <bitOffset>8</bitOffset>
              <bitWidth>4</bitWidth>
            </field>
            <field>
              <name>AFSEL3</name>
              <bitOffset>12</bitOffset>
              <bitWidth>4</bitWidth>
            </field>
            <field>
              <name>AFSEL4</name>
              <bitOffset>16</bitOffset>
              <bitWidth>4</bitWidth>
            </field>
            <field>
              <name>AFSEL5</name>
              <bitOffset>20</bitOffset>
              <bitWidth>4</bitWidth>
            </field>
            <field>
              <name>AFSEL6</name>
              <bitOffset>24</bitOffset>
              <bitWidth>4</bitWidth>
            </field>
            <field>
              <name>AFSEL7</name>
              <bitOffset>28</bitOffset>
              <bitWidth>4</bitWidth>
            </field>
          </fields>
        </register>
        <register>
          <name>AFR.1</name>
          <addressOffset>0x24</addressOffset>
          <size>0x20</size>
          <fields>
            <field>
              <name>AFSEL8</name>
              <bitOffset>0</bitOffset>
              <bitWidth>4</bitWidth>
            </field>
            <field>
              <name>AFSEL9</name>
              <bitOffset>4</bitOffset>
              <bitWidth>4</bitWidth>
            </field>
            <field>
              <name>AFSEL10</name>
              <bitOffset>8</bitOffset>
              <bitWidth>4</bitWidth>
            </field>
            <field>
              <name>AFSEL11</name>
              <bitOffset>12</bitOffset>
              <bitWidth>4</bitWidth>
            </field>
            <field>
              <name>AFSEL12</name>
              <bitOffset>16</bitOffset>
              <bitWidth>4</bitWidth>
            </field>
            <field>
              <name>AFSEL13</name>
              <bitOffset>20</bitOffset>
              <bitWidth>4</bitWidth>
            </field>
            <field>
              <name>AFSEL14</name>
              <bitOffset>24</bitOffset>
              <bitWidth>4</bitWidth>
            </field>
            <field>
              <name>AFSEL15</name>
              <bitOffset>28</bitOffset>
              <bitWidth>4</bitWidth>
            </field>
          </fields>
        </register>
      </registers>
    </peripheral>
    <peripheral>
      <name>GPIOJ</name>
      <baseAddress>0x58022400</baseAddress>
      <registers>
        <register>
          <name>MODER</name>
          <addressOffset>0x0</addressOffset>
          <size>0x20</size>
          <fields>
            <field>
              <name>MODE0</name>
              <bitOffset>0</bitOffset>
              <bitWidth>2</bitWidth>
            </field>
            <field>
              <name>MODE1</name>
              <bitOffset>2</bitOffset>
              <bitWidth>2</bitWidth>
            </field>
            <field>
              <name>MODE2</name>
              <bitOffset>4</bitOffset>
              <bitWidth>2</bitWidth>
            </field>
            <field>
              <name>MODE3</name>
              <bitOffset>6</bitOffset>
              <bitWidth>2</bitWidth>
            </field>
            <field>
              <name>MODE4</name>
              <bitOffset>8</bitOffset>
              <bitWidth>2</bitWidth>
            </field>
            <field>
              <name>MODE5</name>
              <bitOffset>10</bitOffset>
              <bitWidth>2</bitWidth>
            </field>
            <field>
              <name>MODE6</name>
              <bitOffset>12</bitOffset>
              <bitWidth>2</bitWidth>
            </field>
            <field>
              <name>MODE7</name>
              <bitOffset>14</bitOffset>
              <bitWidth>2</bitWidth>
            </field>
            <field>
              <name>MODE8</name>
              <bitOffset>16</bitOffset>
              <bitWidth>2</bitWidth>
            </field>
            <field>
              <name>MODE9</name>
              <bitOffset>18</bitOffset>
              <bitWidth>2</bitWidth>
            </field>
            <field>
              <name>MODE10</name>
              <bitOffset>20</bitOffset>
              <bitWidth>2</bitWidth>
            </field>
            <field>
              <name>MODE11</name>
              <bitOffset>22</bitOffset>
              <bitWidth>2</bitWidth>
            </field>
            <field>
              <name>MODE12</name>
              <bitOffset>24</bitOffset>
              <bitWidth>2</bitWidth>
            </field>
            <field>
              <name>MODE13</name>
              <bitOffset>26</bitOffset>
              <bitWidth>2</bitWidth>
            </field>
            <field>
              <name>MODE14</name>
              <bitOffset>28</bitOffset>
              <bitWidth>2</bitWidth>
            </field>
            <field>
              <name>MODE15</name>
              <bitOffset>30</bitOffset>
              <bitWidth>2</bitWidth>
            </field>
          </fields>
        </register>
        <register>
          <name>OTYPER</name>
          <addressOffset>0x4</addressOffset>
          <size>0x20</size>
          <fields>
            <field>
              <name>OT0</name>
              <bitOffset>0</bitOffset>
              <bitWidth>1</bitWidth>
            </field>
            <field>
              <name>OT1</name>
              <bitOffset>1</bitOffset>
              <bitWidth>1</bitWidth>
            </field>
            <field>
              <name>OT2</name>
              <bitOffset>2</bitOffset>
              <bitWidth>1</bitWidth>
            </field>
            <field>
              <name>OT3</name>
              <bitOffset>3</bitOffset>
              <bitWidth>1</bitWidth>
            </field>
            <field>
              <name>OT4</name>
              <bitOffset>4</bitOffset>
              <bitWidth>1</bitWidth>
            </field>
            <field>
              <name>OT5</name>
              <bitOffset>5</bitOffset>
              <bitWidth>1</bitWidth>
            </field>
            <field>
              <name>OT6</name>
              <bitOffset>6</bitOffset>
              <bitWidth>1</bitWidth>
            </field>
            <field>
              <name>OT7</name>
              <bitOffset>7</bitOffset>
              <bitWidth>1</bitWidth>
            </field>
            <field>
              <name>OT8</name>
              <bitOffset>8</bitOffset>
              <bitWidth>1</bitWidth>
            </field>
            <field>
              <name>OT9</name>
              <bitOffset>9</bitOffset>
              <bitWidth>1</bitWidth>
            </field>
            <field>
              <name>OT10</name>
              <bitOffset>10</bitOffset>
              <bitWidth>1</bitWidth>
            </field>
            <field>
              <name>OT11</name>
              <bitOffset>11</bitOffset>
              <bitWidth>1</bitWidth>
            </field>
            <field>
              <name>OT12</name>
              <bitOffset>12</bitOffset>
              <bitWidth>1</bitWidth>
            </field>
            <field>
              <name>OT13</name>
              <bitOffset>13</bitOffset>
              <bitWidth>1</bitWidth>
            </field>
            <field>
              <name>OT14</name>
              <bitOffset>14</bitOffset>
              <bitWidth>1</bitWidth>
            </field>
            <field>
              <name>OT15</name>
              <bitOffset>15</bitOffset>
              <bitWidth>1</bitWidth>
            </field>
          </fields>
        </register>
        <register>
          <name>OSPEEDR</name>
          <addressOffset>0x8</addressOffset>
          <size>0x20</size>
          <fields>
            <field>
              <name>OSPEED0</name>
              <bitOffset>0</bitOffset>
              <bitWidth>2</bitWidth>
            </field>
            <field>
              <name>OSPEED1</name>
              <bitOffset>2</bitOffset>
              <bitWidth>2</bitWidth>
            </field>
            <field>
              <name>OSPEED2</name>
              <bitOffset>4</bitOffset>
              <bitWidth>2</bitWidth>
            </field>
            <field>
              <name>OSPEED3</name>
              <bitOffset>6</bitOffset>
              <bitWidth>2</bitWidth>
            </field>
            <field>
              <name>OSPEED4</name>
              <bitOffset>8</bitOffset>
              <bitWidth>2</bitWidth>
            </field>
            <field>
              <name>OSPEED5</name>
              <bitOffset>10</bitOffset>
              <bitWidth>2</bitWidth>
            </field>
            <field>
              <name>OSPEED6</name>
              <bitOffset>12</bitOffset>
              <bitWidth>2</bitWidth>
            </field>
            <field>
              <name>OSPEED7</name>
              <bitOffset>14</bitOffset>
              <bitWidth>2</bitWidth>
            </field>
            <field>
              <name>OSPEED8</name>
              <bitOffset>16</bitOffset>
              <bitWidth>2</bitWidth>
            </field>
            <field>
              <name>OSPEED9</name>
              <bitOffset>18</bitOffset>
              <bitWidth>2</bitWidth>
            </field>
            <field>
              <name>OSPEED10</name>
              <bitOffset>20</bitOffset>
              <bitWidth>2</bitWidth>
            </field>
            <field>
              <name>OSPEED11</name>
              <bitOffset>22</bitOffset>
              <bitWidth>2</bitWidth>
            </field>
            <field>
              <name>OSPEED12</name>
              <bitOffset>24</bitOffset>
              <bitWidth>2</bitWidth>
            </field>
            <field>
              <name>OSPEED13</name>
              <bitOffset>26</bitOffset>
              <bitWidth>2</bitWidth>
            </field>
            <field>
              <name>OSPEED14</name>
              <bitOffset>28</bitOffset>
              <bitWidth>2</bitWidth>
            </field>
            <field>
              <name>OSPEED15</name>
              <bitOffset>30</bitOffset>
              <bitWidth>2</bitWidth>
            </field>
          </fields>
        </register>
        <register>
          <name>PUPDR</name>
          <addressOffset>0xc</addressOffset>
          <size>0x20</size>
          <fields>
            <field>
              <name>PUPD0</name>
              <bitOffset>0</bitOffset>
              <bitWidth>2</bitWidth>
            </field>
            <field>
              <name>PUPD1</name>
              <bitOffset>2</bitOffset>
              <bitWidth>2</bitWidth>
            </field>
            <field>
              <name>PUPD2</name>
              <bitOffset>4</bitOffset>
              <bitWidth>2</bitWidth>
            </field>
            <field>
              <name>PUPD3</name>
              <bitOffset>6</bitOffset>
              <bitWidth>2</bitWidth>
            </field>
            <field>
              <name>PUPD4</name>
              <bitOffset>8</bitOffset>
              <bitWidth>2</bitWidth>
            </field>
            <field>
              <name>PUPD5</name>
              <bitOffset>10</bitOffset>
              <bitWidth>2</bitWidth>
            </field>
            <field>
              <name>PUPD6</name>
              <bitOffset>12</bitOffset>
              <bitWidth>2</bitWidth>
            </field>
            <field>
              <name>PUPD7</name>
              <bitOffset>14</bitOffset>
              <bitWidth>2</bitWidth>
            </field>
            <field>
              <name>PUPD8</name>
              <bitOffset>16</bitOffset>
              <bitWidth>2</bitWidth>
            </field>
            <field>
              <name>PUPD9</name>
              <bitOffset>18</bitOffset>
              <bitWidth>2</bitWidth>
            </field>
            <field>
              <name>PUPD10</name>
              <bitOffset>20</bitOffset>
              <bitWidth>2</bitWidth>
            </field>
            <field>
              <name>PUPD11</name>
              <bitOffset>22</bitOffset>
              <bitWidth>2</bitWidth>
            </field>
            <field>
              <name>PUPD12</name>
              <bitOffset>24</bitOffset>
              <bitWidth>2</bitWidth>
            </field>
            <field>
              <name>PUPD13</name>
              <bitOffset>26</bitOffset>
              <bitWidth>2</bitWidth>
            </field>
            <field>
              <name>PUPD14</name>
              <bitOffset>28</bitOffset>
              <bitWidth>2</bitWidth>
            </field>
            <field>
              <name>PUPD15</name>
              <bitOffset>30</bitOffset>
              <bitWidth>2</bitWidth>
            </field>
          </fields>
        </register>
        <register>
          <name>IDR</name>
          <addressOffset>0x10</addressOffset>
          <size>0x20</size>
          <fields>
            <field>
              <name>ID0</name>
              <bitOffset>0</bitOffset>
              <bitWidth>1</bitWidth>
            </field>
            <field>
              <name>ID1</name>
              <bitOffset>1</bitOffset>
              <bitWidth>1</bitWidth>
            </field>
            <field>
              <name>ID2</name>
              <bitOffset>2</bitOffset>
              <bitWidth>1</bitWidth>
            </field>
            <field>
              <name>ID3</name>
              <bitOffset>3</bitOffset>
              <bitWidth>1</bitWidth>
            </field>
            <field>
              <name>ID4</name>
              <bitOffset>4</bitOffset>
              <bitWidth>1</bitWidth>
            </field>
            <field>
              <name>ID5</name>
              <bitOffset>5</bitOffset>
              <bitWidth>1</bitWidth>
            </field>
            <field>
              <name>ID6</name>
              <bitOffset>6</bitOffset>
              <bitWidth>1</bitWidth>
            </field>
            <field>
              <name>ID7</name>
              <bitOffset>7</bitOffset>
              <bitWidth>1</bitWidth>
            </field>
            <field>
              <name>ID8</name>
              <bitOffset>8</bitOffset>
              <bitWidth>1</bitWidth>
            </field>
            <field>
              <name>ID9</name>
              <bitOffset>9</bitOffset>
              <bitWidth>1</bitWidth>
            </field>
            <field>
              <name>ID10</name>
              <bitOffset>10</bitOffset>
              <bitWidth>1</bitWidth>
            </field>
            <field>
              <name>ID11</name>
              <bitOffset>11</bitOffset>
              <bitWidth>1</bitWidth>
            </field>
            <field>
              <name>ID12</name>
              <bitOffset>12</bitOffset>
              <bitWidth>1</bitWidth>
            </field>
            <field>
              <name>ID13</name>
              <bitOffset>13</bitOffset>
              <bitWidth>1</bitWidth>
            </field>
            <field>
              <name>ID14</name>
              <bitOffset>14</bitOffset>
              <bitWidth>1</bitWidth>
            </field>
            <field>
              <name>ID15</name>
              <bitOffset>15</bitOffset>
              <bitWidth>1</bitWidth>
            </field>
          </fields>
        </register>
        <register>
          <name>ODR</name>
          <addressOffset>0x14</addressOffset>
          <size>0x20</size>
          <fields>
            <field>
              <name>OD0</name>
              <bitOffset>0</bitOffset>
              <bitWidth>1</bitWidth>
            </field>
            <field>
              <name>OD1</name>
              <bitOffset>1</bitOffset>
              <bitWidth>1</bitWidth>
            </field>
            <field>
              <name>OD2</name>
              <bitOffset>2</bitOffset>
              <bitWidth>1</bitWidth>
            </field>
            <field>
              <name>OD3</name>
              <bitOffset>3</bitOffset>
              <bitWidth>1</bitWidth>
            </field>
            <field>
              <name>OD4</name>
              <bitOffset>4</bitOffset>
              <bitWidth>1</bitWidth>
            </field>
            <field>
              <name>OD5</name>
              <bitOffset>5</bitOffset>
              <bitWidth>1</bitWidth>
            </field>
            <field>
              <name>OD6</name>
              <bitOffset>6</bitOffset>
              <bitWidth>1</bitWidth>
            </field>
            <field>
              <name>OD7</name>
              <bitOffset>7</bitOffset>
              <bitWidth>1</bitWidth>
            </field>
            <field>
              <name>OD8</name>
              <bitOffset>8</bitOffset>
              <bitWidth>1</bitWidth>
            </field>
            <field>
              <name>OD9</name>
              <bitOffset>9</bitOffset>
              <bitWidth>1</bitWidth>
            </field>
            <field>
              <name>OD10</name>
              <bitOffset>10</bitOffset>
              <bitWidth>1</bitWidth>
            </field>
            <field>
              <name>OD11</name>
              <bitOffset>11</bitOffset>
              <bitWidth>1</bitWidth>
            </field>
            <field>
              <name>OD12</name>
              <bitOffset>12</bitOffset>
              <bitWidth>1</bitWidth>
            </field>
            <field>
              <name>OD13</name>
              <bitOffset>13</bitOffset>
              <bitWidth>1</bitWidth>
            </field>
            <field>
              <name>OD14</name>
              <bitOffset>14</bitOffset>
              <bitWidth>1</bitWidth>
            </field>
            <field>
              <name>OD15</name>
              <bitOffset>15</bitOffset>
              <bitWidth>1</bitWidth>
            </field>
          </fields>
        </register>
        <register>
          <name>BSRR</name>
          <addressOffset>0x18</addressOffset>
          <size>0x20</size>
          <fields>
            <field>
              <name>BS0</name>
              <bitOffset>0</bitOffset>
              <bitWidth>1</bitWidth>
            </field>
            <field>
              <name>BS1</name>
              <bitOffset>1</bitOffset>
              <bitWidth>1</bitWidth>
            </field>
            <field>
              <name>BS2</name>
              <bitOffset>2</bitOffset>
              <bitWidth>1</bitWidth>
            </field>
            <field>
              <name>BS3</name>
              <bitOffset>3</bitOffset>
              <bitWidth>1</bitWidth>
            </field>
            <field>
              <name>BS4</name>
              <bitOffset>4</bitOffset>
              <bitWidth>1</bitWidth>
            </field>
            <field>
              <name>BS5</name>
              <bitOffset>5</bitOffset>
              <bitWidth>1</bitWidth>
            </field>
            <field>
              <name>BS6</name>
              <bitOffset>6</bitOffset>
              <bitWidth>1</bitWidth>
            </field>
            <field>
              <name>BS7</name>
              <bitOffset>7</bitOffset>
              <bitWidth>1</bitWidth>
            </field>
            <field>
              <name>BS8</name>
              <bitOffset>8</bitOffset>
              <bitWidth>1</bitWidth>
            </field>
            <field>
              <name>BS9</name>
              <bitOffset>9</bitOffset>
              <bitWidth>1</bitWidth>
            </field>
            <field>
              <name>BS10</name>
              <bitOffset>10</bitOffset>
              <bitWidth>1</bitWidth>
            </field>
            <field>
              <name>BS11</name>
              <bitOffset>11</bitOffset>
              <bitWidth>1</bitWidth>
            </field>
            <field>
              <name>BS12</name>
              <bitOffset>12</bitOffset>
              <bitWidth>1</bitWidth>
            </field>
            <field>
              <name>BS13</name>
              <bitOffset>13</bitOffset>
              <bitWidth>1</bitWidth>
            </field>
            <field>
              <name>BS14</name>
              <bitOffset>14</bitOffset>
              <bitWidth>1</bitWidth>
            </field>
            <field>
              <name>BS15</name>
              <bitOffset>15</bitOffset>
              <bitWidth>1</bitWidth>
            </field>
            <field>
              <name>BR0</name>
              <bitOffset>16</bitOffset>
              <bitWidth>1</bitWidth>
            </field>
            <field>
              <name>BR1</name>
              <bitOffset>17</bitOffset>
              <bitWidth>1</bitWidth>
            </field>
            <field>
              <name>BR2</name>
              <bitOffset>18</bitOffset>
              <bitWidth>1</bitWidth>
            </field>
            <field>
              <name>BR3</name>
              <bitOffset>19</bitOffset>
              <bitWidth>1</bitWidth>
            </field>
            <field>
              <name>BR4</name>
              <bitOffset>20</bitOffset>
              <bitWidth>1</bitWidth>
            </field>
            <field>
              <name>BR5</name>
              <bitOffset>21</bitOffset>
              <bitWidth>1</bitWidth>
            </field>
            <field>
              <name>BR6</name>
              <bitOffset>22</bitOffset>
              <bitWidth>1</bitWidth>
            </field>
            <field>
              <name>BR7</name>
              <bitOffset>23</bitOffset>
              <bitWidth>1</bitWidth>
            </field>
            <field>
              <name>BR8</name>
              <bitOffset>24</bitOffset>
              <bitWidth>1</bitWidth>
            </field>
            <field>
              <name>BR9</name>
              <bitOffset>25</bitOffset>
              <bitWidth>1</bitWidth>
            </field>
            <field>
              <name>BR10</name>
              <bitOffset>26</bitOffset>
              <bitWidth>1</bitWidth>
            </field>
            <field>
              <name>BR11</name>
              <bitOffset>27</bitOffset>
              <bitWidth>1</bitWidth>
            </field>
            <field>
              <name>BR12</name>
              <bitOffset>28</bitOffset>
              <bitWidth>1</bitWidth>
            </field>
            <field>
              <name>BR13</name>
              <bitOffset>29</bitOffset>
              <bitWidth>1</bitWidth>
            </field>
            <field>
              <name>BR14</name>
              <bitOffset>30</bitOffset>
              <bitWidth>1</bitWidth>
            </field>
            <field>
              <name>BR15</name>
              <bitOffset>31</bitOffset>
              <bitWidth>1</bitWidth>
            </field>
          </fields>
        </register>
        <register>
          <name>LCKR</name>
          <addressOffset>0x1c</addressOffset>
          <size>0x20</size>
          <fields>
            <field>
              <name>LCK0</name>
              <bitOffset>0</bitOffset>
              <bitWidth>1</bitWidth>
            </field>
            <field>
              <name>LCK1</name>
              <bitOffset>1</bitOffset>
              <bitWidth>1</bitWidth>
            </field>
            <field>
              <name>LCK2</name>
              <bitOffset>2</bitOffset>
              <bitWidth>1</bitWidth>
            </field>
            <field>
              <name>LCK3</name>
              <bitOffset>3</bitOffset>
              <bitWidth>1</bitWidth>
            </field>
            <field>
              <name>LCK4</name>
              <bitOffset>4</bitOffset>
              <bitWidth>1</bitWidth>
            </field>
            <field>
              <name>LCK5</name>
              <bitOffset>5</bitOffset>
              <bitWidth>1</bitWidth>
            </field>
            <field>
              <name>LCK6</name>
              <bitOffset>6</bitOffset>
              <bitWidth>1</bitWidth>
            </field>
            <field>
              <name>LCK7</name>
              <bitOffset>7</bitOffset>
              <bitWidth>1</bitWidth>
            </field>
            <field>
              <name>LCK8</name>
              <bitOffset>8</bitOffset>
              <bitWidth>1</bitWidth>
            </field>
            <field>
              <name>LCK9</name>
              <bitOffset>9</bitOffset>
              <bitWidth>1</bitWidth>
            </field>
            <field>
              <name>LCK10</name>
              <bitOffset>10</bitOffset>
              <bitWidth>1</bitWidth>
            </field>
            <field>
              <name>LCK11</name>
              <bitOffset>11</bitOffset>
              <bitWidth>1</bitWidth>
            </field>
            <field>
              <name>LCK12</name>
              <bitOffset>12</bitOffset>
              <bitWidth>1</bitWidth>
            </field>
            <field>
              <name>LCK13</name>
              <bitOffset>13</bitOffset>
              <bitWidth>1</bitWidth>
            </field>
            <field>
              <name>LCK14</name>
              <bitOffset>14</bitOffset>
              <bitWidth>1</bitWidth>
            </field>
            <field>
              <name>LCK15</name>
              <bitOffset>15</bitOffset>
              <bitWidth>1</bitWidth>
            </field>
            <field>
              <name>LCKK</name>
              <bitOffset>16</bitOffset>
              <bitWidth>1</bitWidth>
            </field>
          </fields>
        </register>
        <register>
          <name>AFR.0</name>
          <addressOffset>0x20</addressOffset>
          <size>0x20</size>
          <fields>
            <field>
              <name>AFSEL0</name>
              <bitOffset>0</bitOffset>
              <bitWidth>4</bitWidth>
            </field>
            <field>
              <name>AFSEL1</name>
              <bitOffset>4</bitOffset>
              <bitWidth>4</bitWidth>
            </field>
            <field>
              <name>AFSEL2</name>
              <bitOffset>8</bitOffset>
              <bitWidth>4</bitWidth>
            </field>
            <field>
              <name>AFSEL3</name>
              <bitOffset>12</bitOffset>
              <bitWidth>4</bitWidth>
            </field>
            <field>
              <name>AFSEL4</name>
              <bitOffset>16</bitOffset>
              <bitWidth>4</bitWidth>
            </field>
            <field>
              <name>AFSEL5</name>
              <bitOffset>20</bitOffset>
              <bitWidth>4</bitWidth>
            </field>
            <field>
              <name>AFSEL6</name>
              <bitOffset>24</bitOffset>
              <bitWidth>4</bitWidth>
            </field>
            <field>
              <name>AFSEL7</name>
              <bitOffset>28</bitOffset>
              <bitWidth>4</bitWidth>
            </field>
          </fields>
        </register>
        <register>
          <name>AFR.1</name>
          <addressOffset>0x24</addressOffset>
          <size>0x20</size>
          <fields>
            <field>
              <name>AFSEL8</name>
              <bitOffset>0</bitOffset>
              <bitWidth>4</bitWidth>
            </field>
            <field>
              <name>AFSEL9</name>
              <bitOffset>4</bitOffset>
              <bitWidth>4</bitWidth>
            </field>
            <field>
              <name>AFSEL10</name>
              <bitOffset>8</bitOffset>
              <bitWidth>4</bitWidth>
            </field>
            <field>
              <name>AFSEL11</name>
              <bitOffset>12</bitOffset>
              <bitWidth>4</bitWidth>
            </field>
            <field>
              <name>AFSEL12</name>
              <bitOffset>16</bitOffset>
              <bitWidth>4</bitWidth>
            </field>
            <field>
              <name>AFSEL13</name>
              <bitOffset>20</bitOffset>
              <bitWidth>4</bitWidth>
            </field>
            <field>
              <name>AFSEL14</name>
              <bitOffset>24</bitOffset>
              <bitWidth>4</bitWidth>
            </field>
            <field>
              <name>AFSEL15</name>
              <bitOffset>28</bitOffset>
              <bitWidth>4</bitWidth>
            </field>
          </fields>
        </register>
      </registers>
    </peripheral>
    <peripheral>
      <name>GPIOK</name>
      <baseAddress>0x58022800</baseAddress>
      <registers>
        <register>
          <name>MODER</name>
          <addressOffset>0x0</addressOffset>
          <size>0x20</size>
          <fields>
            <field>
              <name>MODE0</name>
              <bitOffset>0</bitOffset>
              <bitWidth>2</bitWidth>
            </field>
            <field>
              <name>MODE1</name>
              <bitOffset>2</bitOffset>
              <bitWidth>2</bitWidth>
            </field>
            <field>
              <name>MODE2</name>
              <bitOffset>4</bitOffset>
              <bitWidth>2</bitWidth>
            </field>
            <field>
              <name>MODE3</name>
              <bitOffset>6</bitOffset>
              <bitWidth>2</bitWidth>
            </field>
            <field>
              <name>MODE4</name>
              <bitOffset>8</bitOffset>
              <bitWidth>2</bitWidth>
            </field>
            <field>
              <name>MODE5</name>
              <bitOffset>10</bitOffset>
              <bitWidth>2</bitWidth>
            </field>
            <field>
              <name>MODE6</name>
              <bitOffset>12</bitOffset>
              <bitWidth>2</bitWidth>
            </field>
            <field>
              <name>MODE7</name>
              <bitOffset>14</bitOffset>
              <bitWidth>2</bitWidth>
            </field>
            <field>
              <name>MODE8</name>
              <bitOffset>16</bitOffset>
              <bitWidth>2</bitWidth>
            </field>
            <field>
              <name>MODE9</name>
              <bitOffset>18</bitOffset>
              <bitWidth>2</bitWidth>
            </field>
            <field>
              <name>MODE10</name>
              <bitOffset>20</bitOffset>
              <bitWidth>2</bitWidth>
            </field>
            <field>
              <name>MODE11</name>
              <bitOffset>22</bitOffset>
              <bitWidth>2</bitWidth>
            </field>
            <field>
              <name>MODE12</name>
              <bitOffset>24</bitOffset>
              <bitWidth>2</bitWidth>
            </field>
            <field>
              <name>MODE13</name>
              <bitOffset>26</bitOffset>
              <bitWidth>2</bitWidth>
            </field>
            <field>
              <name>MODE14</name>
              <bitOffset>28</bitOffset>
              <bitWidth>2</bitWidth>
            </field>
            <field>
              <name>MODE15</name>
              <bitOffset>30</bitOffset>
              <bitWidth>2</bitWidth>
            </field>
          </fields>
        </register>
        <register>
          <name>OTYPER</name>
          <addressOffset>0x4</addressOffset>
          <size>0x20</size>
          <fields>
            <field>
              <name>OT0</name>
              <bitOffset>0</bitOffset>
              <bitWidth>1</bitWidth>
            </field>
            <field>
              <name>OT1</name>
              <bitOffset>1</bitOffset>
              <bitWidth>1</bitWidth>
            </field>
            <field>
              <name>OT2</name>
              <bitOffset>2</bitOffset>
              <bitWidth>1</bitWidth>
            </field>
            <field>
              <name>OT3</name>
              <bitOffset>3</bitOffset>
              <bitWidth>1</bitWidth>
            </field>
            <field>
              <name>OT4</name>
              <bitOffset>4</bitOffset>
              <bitWidth>1</bitWidth>
            </field>
            <field>
              <name>OT5</name>
              <bitOffset>5</bitOffset>
              <bitWidth>1</bitWidth>
            </field>
            <field>
              <name>OT6</name>
              <bitOffset>6</bitOffset>
              <bitWidth>1</bitWidth>
            </field>
            <field>
              <name>OT7</name>
              <bitOffset>7</bitOffset>
              <bitWidth>1</bitWidth>
            </field>
            <field>
              <name>OT8</name>
              <bitOffset>8</bitOffset>
              <bitWidth>1</bitWidth>
            </field>
            <field>
              <name>OT9</name>
              <bitOffset>9</bitOffset>
              <bitWidth>1</bitWidth>
            </field>
            <field>
              <name>OT10</name>
              <bitOffset>10</bitOffset>
              <bitWidth>1</bitWidth>
            </field>
            <field>
              <name>OT11</name>
              <bitOffset>11</bitOffset>
              <bitWidth>1</bitWidth>
            </field>
            <field>
              <name>OT12</name>
              <bitOffset>12</bitOffset>
              <bitWidth>1</bitWidth>
            </field>
            <field>
              <name>OT13</name>
              <bitOffset>13</bitOffset>
              <bitWidth>1</bitWidth>
            </field>
            <field>
              <name>OT14</name>
              <bitOffset>14</bitOffset>
              <bitWidth>1</bitWidth>
            </field>
            <field>
              <name>OT15</name>
              <bitOffset>15</bitOffset>
              <bitWidth>1</bitWidth>
            </field>
          </fields>
        </register>
        <register>
          <name>OSPEEDR</name>
          <addressOffset>0x8</addressOffset>
          <size>0x20</size>
          <fields>
            <field>
              <name>OSPEED0</name>
              <bitOffset>0</bitOffset>
              <bitWidth>2</bitWidth>
            </field>
            <field>
              <name>OSPEED1</name>
              <bitOffset>2</bitOffset>
              <bitWidth>2</bitWidth>
            </field>
            <field>
              <name>OSPEED2</name>
              <bitOffset>4</bitOffset>
              <bitWidth>2</bitWidth>
            </field>
            <field>
              <name>OSPEED3</name>
              <bitOffset>6</bitOffset>
              <bitWidth>2</bitWidth>
            </field>
            <field>
              <name>OSPEED4</name>
              <bitOffset>8</bitOffset>
              <bitWidth>2</bitWidth>
            </field>
            <field>
              <name>OSPEED5</name>
              <bitOffset>10</bitOffset>
              <bitWidth>2</bitWidth>
            </field>
            <field>
              <name>OSPEED6</name>
              <bitOffset>12</bitOffset>
              <bitWidth>2</bitWidth>
            </field>
            <field>
              <name>OSPEED7</name>
              <bitOffset>14</bitOffset>
              <bitWidth>2</bitWidth>
            </field>
            <field>
              <name>OSPEED8</name>
              <bitOffset>16</bitOffset>
              <bitWidth>2</bitWidth>
            </field>
            <field>
              <name>OSPEED9</name>
              <bitOffset>18</bitOffset>
              <bitWidth>2</bitWidth>
            </field>
            <field>
              <name>OSPEED10</name>
              <bitOffset>20</bitOffset>
              <bitWidth>2</bitWidth>
            </field>
            <field>
              <name>OSPEED11</name>
              <bitOffset>22</bitOffset>
              <bitWidth>2</bitWidth>
            </field>
            <field>
              <name>OSPEED12</name>
              <bitOffset>24</bitOffset>
              <bitWidth>2</bitWidth>
            </field>
            <field>
              <name>OSPEED13</name>
              <bitOffset>26</bitOffset>
              <bitWidth>2</bitWidth>
            </field>
            <field>
              <name>OSPEED14</name>
              <bitOffset>28</bitOffset>
              <bitWidth>2</bitWidth>
            </field>
            <field>
              <name>OSPEED15</name>
              <bitOffset>30</bitOffset>
              <bitWidth>2</bitWidth>
            </field>
          </fields>
        </register>
        <register>
          <name>PUPDR</name>
          <addressOffset>0xc</addressOffset>
          <size>0x20</size>
          <fields>
            <field>
              <name>PUPD0</name>
              <bitOffset>0</bitOffset>
              <bitWidth>2</bitWidth>
            </field>
            <field>
              <name>PUPD1</name>
              <bitOffset>2</bitOffset>
              <bitWidth>2</bitWidth>
            </field>
            <field>
              <name>PUPD2</name>
              <bitOffset>4</bitOffset>
              <bitWidth>2</bitWidth>
            </field>
            <field>
              <name>PUPD3</name>
              <bitOffset>6</bitOffset>
              <bitWidth>2</bitWidth>
            </field>
            <field>
              <name>PUPD4</name>
              <bitOffset>8</bitOffset>
              <bitWidth>2</bitWidth>
            </field>
            <field>
              <name>PUPD5</name>
              <bitOffset>10</bitOffset>
              <bitWidth>2</bitWidth>
            </field>
            <field>
              <name>PUPD6</name>
              <bitOffset>12</bitOffset>
              <bitWidth>2</bitWidth>
            </field>
            <field>
              <name>PUPD7</name>
              <bitOffset>14</bitOffset>
              <bitWidth>2</bitWidth>
            </field>
            <field>
              <name>PUPD8</name>
              <bitOffset>16</bitOffset>
              <bitWidth>2</bitWidth>
            </field>
            <field>
              <name>PUPD9</name>
              <bitOffset>18</bitOffset>
              <bitWidth>2</bitWidth>
            </field>
            <field>
              <name>PUPD10</name>
              <bitOffset>20</bitOffset>
              <bitWidth>2</bitWidth>
            </field>
            <field>
              <name>PUPD11</name>
              <bitOffset>22</bitOffset>
              <bitWidth>2</bitWidth>
            </field>
            <field>
              <name>PUPD12</name>
              <bitOffset>24</bitOffset>
              <bitWidth>2</bitWidth>
            </field>
            <field>
              <name>PUPD13</name>
              <bitOffset>26</bitOffset>
              <bitWidth>2</bitWidth>
            </field>
            <field>
              <name>PUPD14</name>
              <bitOffset>28</bitOffset>
              <bitWidth>2</bitWidth>
            </field>
            <field>
              <name>PUPD15</name>
              <bitOffset>30</bitOffset>
              <bitWidth>2</bitWidth>
            </field>
          </fields>
        </register>
        <register>
          <name>IDR</name>
          <addressOffset>0x10</addressOffset>
          <size>0x20</size>
          <fields>
            <field>
              <name>ID0</name>
              <bitOffset>0</bitOffset>
              <bitWidth>1</bitWidth>
            </field>
            <field>
              <name>ID1</name>
              <bitOffset>1</bitOffset>
              <bitWidth>1</bitWidth>
            </field>
            <field>
              <name>ID2</name>
              <bitOffset>2</bitOffset>
              <bitWidth>1</bitWidth>
            </field>
            <field>
              <name>ID3</name>
              <bitOffset>3</bitOffset>
              <bitWidth>1</bitWidth>
            </field>
            <field>
              <name>ID4</name>
              <bitOffset>4</bitOffset>
              <bitWidth>1</bitWidth>
            </field>
            <field>
              <name>ID5</name>
              <bitOffset>5</bitOffset>
              <bitWidth>1</bitWidth>
            </field>
            <field>
              <name>ID6</name>
              <bitOffset>6</bitOffset>
              <bitWidth>1</bitWidth>
            </field>
            <field>
              <name>ID7</name>
              <bitOffset>7</bitOffset>
              <bitWidth>1</bitWidth>
            </field>
            <field>
              <name>ID8</name>
              <bitOffset>8</bitOffset>
              <bitWidth>1</bitWidth>
            </field>
            <field>
              <name>ID9</name>
              <bitOffset>9</bitOffset>
              <bitWidth>1</bitWidth>
            </field>
            <field>
              <name>ID10</name>
              <bitOffset>10</bitOffset>
              <bitWidth>1</bitWidth>
            </field>
            <field>
              <name>ID11</name>
              <bitOffset>11</bitOffset>
              <bitWidth>1</bitWidth>
            </field>
            <field>
              <name>ID12</name>
              <bitOffset>12</bitOffset>
              <bitWidth>1</bitWidth>
            </field>
            <field>
              <name>ID13</name>
              <bitOffset>13</bitOffset>
              <bitWidth>1</bitWidth>
            </field>
            <field>
              <name>ID14</name>
              <bitOffset>14</bitOffset>
              <bitWidth>1</bitWidth>
            </field>
            <field>
              <name>ID15</name>
              <bitOffset>15</bitOffset>
              <bitWidth>1</bitWidth>
            </field>
          </fields>
        </register>
        <register>
          <name>ODR</name>
          <addressOffset>0x14</addressOffset>
          <size>0x20</size>
          <fields>
            <field>
              <name>OD0</name>
              <bitOffset>0</bitOffset>
              <bitWidth>1</bitWidth>
            </field>
            <field>
              <name>OD1</name>
              <bitOffset>1</bitOffset>
              <bitWidth>1</bitWidth>
            </field>
            <field>
              <name>OD2</name>
              <bitOffset>2</bitOffset>
              <bitWidth>1</bitWidth>
            </field>
            <field>
              <name>OD3</name>
              <bitOffset>3</bitOffset>
              <bitWidth>1</bitWidth>
            </field>
            <field>
              <name>OD4</name>
              <bitOffset>4</bitOffset>
              <bitWidth>1</bitWidth>
            </field>
            <field>
              <name>OD5</name>
              <bitOffset>5</bitOffset>
              <bitWidth>1</bitWidth>
            </field>
            <field>
              <name>OD6</name>
              <bitOffset>6</bitOffset>
              <bitWidth>1</bitWidth>
            </field>
            <field>
              <name>OD7</name>
              <bitOffset>7</bitOffset>
              <bitWidth>1</bitWidth>
            </field>
            <field>
              <name>OD8</name>
              <bitOffset>8</bitOffset>
              <bitWidth>1</bitWidth>
            </field>
            <field>
              <name>OD9</name>
              <bitOffset>9</bitOffset>
              <bitWidth>1</bitWidth>
            </field>
            <field>
              <name>OD10</name>
              <bitOffset>10</bitOffset>
              <bitWidth>1</bitWidth>
            </field>
            <field>
              <name>OD11</name>
              <bitOffset>11</bitOffset>
              <bitWidth>1</bitWidth>
            </field>
            <field>
              <name>OD12</name>
              <bitOffset>12</bitOffset>
              <bitWidth>1</bitWidth>
            </field>
            <field>
              <name>OD13</name>
              <bitOffset>13</bitOffset>
              <bitWidth>1</bitWidth>
            </field>
            <field>
              <name>OD14</name>
              <bitOffset>14</bitOffset>
              <bitWidth>1</bitWidth>
            </field>
            <field>
              <name>OD15</name>
              <bitOffset>15</bitOffset>
              <bitWidth>1</bitWidth>
            </field>
          </fields>
        </register>
        <register>
          <name>BSRR</name>
          <addressOffset>0x18</addressOffset>
          <size>0x20</size>
          <fields>
            <field>
              <name>BS0</name>
              <bitOffset>0</bitOffset>
              <bitWidth>1</bitWidth>
            </field>
            <field>
              <name>BS1</name>
              <bitOffset>1</bitOffset>
              <bitWidth>1</bitWidth>
            </field>
            <field>
              <name>BS2</name>
              <bitOffset>2</bitOffset>
              <bitWidth>1</bitWidth>
            </field>
            <field>
              <name>BS3</name>
              <bitOffset>3</bitOffset>
              <bitWidth>1</bitWidth>
            </field>
            <field>
              <name>BS4</name>
              <bitOffset>4</bitOffset>
              <bitWidth>1</bitWidth>
            </field>
            <field>
              <name>BS5</name>
              <bitOffset>5</bitOffset>
              <bitWidth>1</bitWidth>
            </field>
            <field>
              <name>BS6</name>
              <bitOffset>6</bitOffset>
              <bitWidth>1</bitWidth>
            </field>
            <field>
              <name>BS7</name>
              <bitOffset>7</bitOffset>
              <bitWidth>1</bitWidth>
            </field>
            <field>
              <name>BS8</name>
              <bitOffset>8</bitOffset>
              <bitWidth>1</bitWidth>
            </field>
            <field>
              <name>BS9</name>
              <bitOffset>9</bitOffset>
              <bitWidth>1</bitWidth>
            </field>
            <field>
              <name>BS10</name>
              <bitOffset>10</bitOffset>
              <bitWidth>1</bitWidth>
            </field>
            <field>
              <name>BS11</name>
              <bitOffset>11</bitOffset>
              <bitWidth>1</bitWidth>
            </field>
            <field>
              <name>BS12</name>
              <bitOffset>12</bitOffset>
              <bitWidth>1</bitWidth>
            </field>
            <field>
              <name>BS13</name>
              <bitOffset>13</bitOffset>
              <bitWidth>1</bitWidth>
            </field>
            <field>
              <name>BS14</name>
              <bitOffset>14</bitOffset>
              <bitWidth>1</bitWidth>
            </field>
            <field>
              <name>BS15</name>
              <bitOffset>15</bitOffset>
              <bitWidth>1</bitWidth>
            </field>
            <field>
              <name>BR0</name>
              <bitOffset>16</bitOffset>
              <bitWidth>1</bitWidth>
            </field>
            <field>
              <name>BR1</name>
              <bitOffset>17</bitOffset>
              <bitWidth>1</bitWidth>
            </field>
            <field>
              <name>BR2</name>
              <bitOffset>18</bitOffset>
              <bitWidth>1</bitWidth>
            </field>
            <field>
              <name>BR3</name>
              <bitOffset>19</bitOffset>
              <bitWidth>1</bitWidth>
            </field>
            <field>
              <name>BR4</name>
              <bitOffset>20</bitOffset>
              <bitWidth>1</bitWidth>
            </field>
            <field>
              <name>BR5</name>
              <bitOffset>21</bitOffset>
              <bitWidth>1</bitWidth>
            </field>
            <field>
              <name>BR6</name>
              <bitOffset>22</bitOffset>
              <bitWidth>1</bitWidth>
            </field>
            <field>
              <name>BR7</name>
              <bitOffset>23</bitOffset>
              <bitWidth>1</bitWidth>
            </field>
            <field>
              <name>BR8</name>
              <bitOffset>24</bitOffset>
              <bitWidth>1</bitWidth>
            </field>
            <field>
              <name>BR9</name>
              <bitOffset>25</bitOffset>
              <bitWidth>1</bitWidth>
            </field>
            <field>
              <name>BR10</name>
              <bitOffset>26</bitOffset>
              <bitWidth>1</bitWidth>
            </field>
            <field>
              <name>BR11</name>
              <bitOffset>27</bitOffset>
              <bitWidth>1</bitWidth>
            </field>
            <field>
              <name>BR12</name>
              <bitOffset>28</bitOffset>
              <bitWidth>1</bitWidth>
            </field>
            <field>
              <name>BR13</name>
              <bitOffset>29</bitOffset>
              <bitWidth>1</bitWidth>
            </field>
            <field>
              <name>BR14</name>
              <bitOffset>30</bitOffset>
              <bitWidth>1</bitWidth>
            </field>
            <field>
              <name>BR15</name>
              <bitOffset>31</bitOffset>
              <bitWidth>1</bitWidth>
            </field>
          </fields>
        </register>
        <register>
          <name>LCKR</name>
          <addressOffset>0x1c</addressOffset>
          <size>0x20</size>
          <fields>
            <field>
              <name>LCK0</name>
              <bitOffset>0</bitOffset>
              <bitWidth>1</bitWidth>
            </field>
            <field>
              <name>LCK1</name>
              <bitOffset>1</bitOffset>
              <bitWidth>1</bitWidth>
            </field>
            <field>
              <name>LCK2</name>
              <bitOffset>2</bitOffset>
              <bitWidth>1</bitWidth>
            </field>
            <field>
              <name>LCK3</name>
              <bitOffset>3</bitOffset>
              <bitWidth>1</bitWidth>
            </field>
            <field>
              <name>LCK4</name>
              <bitOffset>4</bitOffset>
              <bitWidth>1</bitWidth>
            </field>
            <field>
              <name>LCK5</name>
              <bitOffset>5</bitOffset>
              <bitWidth>1</bitWidth>
            </field>
            <field>
              <name>LCK6</name>
              <bitOffset>6</bitOffset>
              <bitWidth>1</bitWidth>
            </field>
            <field>
              <name>LCK7</name>
              <bitOffset>7</bitOffset>
              <bitWidth>1</bitWidth>
            </field>
            <field>
              <name>LCK8</name>
              <bitOffset>8</bitOffset>
              <bitWidth>1</bitWidth>
            </field>
            <field>
              <name>LCK9</name>
              <bitOffset>9</bitOffset>
              <bitWidth>1</bitWidth>
            </field>
            <field>
              <name>LCK10</name>
              <bitOffset>10</bitOffset>
              <bitWidth>1</bitWidth>
            </field>
            <field>
              <name>LCK11</name>
              <bitOffset>11</bitOffset>
              <bitWidth>1</bitWidth>
            </field>
            <field>
              <name>LCK12</name>
              <bitOffset>12</bitOffset>
              <bitWidth>1</bitWidth>
            </field>
            <field>
              <name>LCK13</name>
              <bitOffset>13</bitOffset>
              <bitWidth>1</bitWidth>
            </field>
            <field>
              <name>LCK14</name>
              <bitOffset>14</bitOffset>
              <bitWidth>1</bitWidth>
            </field>
            <field>
              <name>LCK15</name>
              <bitOffset>15</bitOffset>
              <bitWidth>1</bitWidth>
            </field>
            <field>
              <name>LCKK</name>
              <bitOffset>16</bitOffset>
              <bitWidth>1</bitWidth>
            </field>
          </fields>
        </register>
        <register>
          <name>AFR.0</name>
          <addressOffset>0x20</addressOffset>
          <size>0x20</size>
          <fields>
            <field>
              <name>AFSEL0</name>
              <bitOffset>0</bitOffset>
              <bitWidth>4</bitWidth>
            </field>
            <field>
              <name>AFSEL1</name>
              <bitOffset>4</bitOffset>
              <bitWidth>4</bitWidth>
            </field>
            <field>
              <name>AFSEL2</name>
              <bitOffset>8</bitOffset>
              <bitWidth>4</bitWidth>
            </field>
            <field>
              <name>AFSEL3</name>
              <bitOffset>12</bitOffset>
              <bitWidth>4</bitWidth>
            </field>
            <field>
              <name>AFSEL4</name>
              <bitOffset>16</bitOffset>
              <bitWidth>4</bitWidth>
            </field>
            <field>
              <name>AFSEL5</name>
              <bitOffset>20</bitOffset>
              <bitWidth>4</bitWidth>
            </field>
            <field>
              <name>AFSEL6</name>
              <bitOffset>24</bitOffset>
              <bitWidth>4</bitWidth>
            </field>
            <field>
              <name>AFSEL7</name>
              <bitOffset>28</bitOffset>
              <bitWidth>4</bitWidth>
            </field>
          </fields>
        </register>
        <register>
          <name>AFR.1</name>
          <addressOffset>0x24</addressOffset>
          <size>0x20</size>
          <fields>
            <field>
              <name>AFSEL8</name>
              <bitOffset>0</bitOffset>
              <bitWidth>4</bitWidth>
            </field>
            <field>
              <name>AFSEL9</name>
              <bitOffset>4</bitOffset>
              <bitWidth>4</bitWidth>
            </field>
            <field>
              <name>AFSEL10</name>
              <bitOffset>8</bitOffset>
              <bitWidth>4</bitWidth>
            </field>
            <field>
              <name>AFSEL11</name>
              <bitOffset>12</bitOffset>
              <bitWidth>4</bitWidth>
            </field>
            <field>
              <name>AFSEL12</name>
              <bitOffset>16</bitOffset>
              <bitWidth>4</bitWidth>
            </field>
            <field>
              <name>AFSEL13</name>
              <bitOffset>20</bitOffset>
              <bitWidth>4</bitWidth>
            </field>
            <field>
              <name>AFSEL14</name>
              <bitOffset>24</bitOffset>
              <bitWidth>4</bitWidth>
            </field>
            <field>
              <name>AFSEL15</name>
              <bitOffset>28</bitOffset>
              <bitWidth>4</bitWidth>
            </field>
          </fields>
        </register>
      </registers>
    </peripheral>
    <peripheral>
      <name>RCC</name>
      <baseAddress>0x58024400</baseAddress>
      <registers>
        <register>
          <name>CR</name>
          <addressOffset>0x0</addressOffset>
          <size>0x20</size>
          <fields>
            <field>
              <name>HSION</name>
              <bitOffset>0</bitOffset>
              <bitWidth>1</bitWidth>
            </field>
            <field>
              <name>HSIKERON</name>
              <bitOffset>1</bitOffset>
              <bitWidth>1</bitWidth>
            </field>
            <field>
              <name>HSIRDY</name>
              <bitOffset>2</bitOffset>
              <bitWidth>1</bitWidth>
            </field>
            <field>
              <name>HSIDIV</name>
              <bitOffset>3</bitOffset>
              <bitWidth>2</bitWidth>
            </field>
            <field>
              <name>HSIDIVF</name>
              <bitOffset>5</bitOffset>
              <bitWidth>1</bitWidth>
            </field>
            <field>
              <name>CSION</name>
              <bitOffset>7</bitOffset>
              <bitWidth>1</bitWidth>
            </field>
            <field>
              <name>CSIRDY</name>
              <bitOffset>8</bitOffset>
              <bitWidth>1</bitWidth>
            </field>
            <field>
              <name>CSIKERON</name>
              <bitOffset>9</bitOffset>
              <bitWidth>1</bitWidth>
            </field>
            <field>
              <name>HSI48ON</name>
              <bitOffset>12</bitOffset>
              <bitWidth>1</bitWidth>
            </field>
            <field>
              <name>HSI48RDY</name>
              <bitOffset>13</bitOffset>
              <bitWidth>1</bitWidth>
            </field>
            <field>
              <name>D1CKRDY</name>
              <bitOffset>14</bitOffset>
              <bitWidth>1</bitWidth>
            </field>
            <field>
              <name>D2CKRDY</name>
              <bitOffset>15</bitOffset>
              <bitWidth>1</bitWidth>
            </field>
            <field>
              <name>HSEON</name>
              <bitOffset>16</bitOffset>
              <bitWidth>1</bitWidth>
            </field>
            <field>
              <name>HSERDY</name>
              <bitOffset>17</bitOffset>
              <bitWidth>1</bitWidth>
            </field>
            <field>
              <name>HSEBYP</name>
              <bitOffset>18</bitOffset>
              <bitWidth>1</bitWidth>
            </field>
            <field>
              <name>CSSHSEON</name>
              <bitOffset>19</bitOffset>
              <bitWidth>1</bitWidth>
            </field>
            <field>
              <name>PLLON</name>
              <bitOffset>24</bitOffset>
              <bitWidth>1</bitWidth>
            </field>
            <field>
              <name>PLLRDY</name>
              <bitOffset>25</bitOffset>
              <bitWidth>1</bitWidth>
            </field>
            <field>
              <name>PLL2ON</name>
              <bitOffset>26</bitOffset>
              <bitWidth>1</bitWidth>
            </field>
            <field>
              <name>PLL2RDY</name>
              <bitOffset>27</bitOffset>
              <bitWidth>1</bitWidth>
            </field>
            <field>
              <name>PLL3ON</name>
              <bitOffset>28</bitOffset>
              <bitWidth>1</bitWidth>
            </field>
            <field>
              <name>PLL3RDY</name>
              <bitOffset>29</bitOffset>
              <bitWidth>1</bitWidth>
            </field>
          </fields>
        </register>
        <register>
          <name>HSICFGR</name>
          <addressOffset>0x4</addressOffset>
          <size>0x20</size>
          <fields>
            <field>
              <name>HSICAL</name>
              <bitOffset>0</bitOffset>
              <bitWidth>12</bitWidth>
            </field>
            <field>
              <name>HSITRIM</name>
              <bitOffset>24</bitOffset>
              <bitWidth>7</bitWidth>
            </field>
          </fields>
        </register>
        <register>
          <name>CRRCR</name>
          <addressOffset>0x8</addressOffset>
          <size>0x20</size>
          <fields>
            <field>
              <name>HSI48CAL</name>
              <bitOffset>0</bitOffset>
              <bitWidth>10</bitWidth>
            </field>
          </fields>
        </register>
        <register>
          <name>CSICFGR</name>
          <addressOffset>0xc</addressOffset>
          <size>0x20</size>
          <fields>
            <field>
              <name>CSICAL</name>
              <bitOffset>0</bitOffset>
              <bitWidth>8</bitWidth>
            </field>
            <field>
              <name>CSITRIM</name>
              <bitOffset>24</bitOffset>
              <bitWidth>6</bitWidth>
            </field>
          </fields>
        </register>
        <register>
          <name>CFGR</name>
          <addressOffset>0x10</addressOffset>
          <size>0x20</size>
          <fields>
            <field>
              <name>SW</name>
              <bitOffset>0</bitOffset>
              <bitWidth>3</bitWidth>
            </field>
            <field>
              <name>SWS</name>
              <bitOffset>3</bitOffset>
              <bitWidth>3</bitWidth>
            </field>
            <field>
              <name>STOPWUCK</name>
              <bitOffset>6</bitOffset>
              <bitWidth>1</bitWidth>
            </field>
            <field>
              <name>STOPKERWUCK</name>
              <bitOffset>7</bitOffset>
              <bitWidth>1</bitWidth>
            </field>
            <field>
              <name>RTCPRE</name>
              <bitOffset>8</bitOffset>
              <bitWidth>6</bitWidth>
            </field>
            <field>
              <name>TIMPRE</name>
              <bitOffset>15</bitOffset>
              <bitWidth>1</bitWidth>
            </field>
            <field>
              <name>MCO1PRE</name>
              <bitOffset>18</bitOffset>
              <bitWidth>4</bitWidth>
            </field>
            <field>
              <name>MCO1</name>
              <bitOffset>22</bitOffset>
              <bitWidth>3</bitWidth>
            </field>
            <field>
              <name>MCO2PRE</name>
              <bitOffset>25</bitOffset>
              <bitWidth>4</bitWidth>
            </field>
            <field>
              <name>MCO2</name>
              <bitOffset>29</bitOffset>
              <bitWidth>3</bitWidth>
            </field>
          </fields>
        </register>
        <register>
          <name>D1CFGR</name>
          <addressOffset>0x18</addressOffset>
          <size>0x20</size>
          <fields>
            <field>
              <name>HPRE_DIV512</name>
              <bitOffset>0</bitOffset>
              <bitWidth>4</bitWidth>
            </field>
            <field>
              <name>HPRE_DIV8</name>
              <bitOffset>1</bitOffset>
              <bitWidth>3</bitWidth>
            </field>
            <field>
              <name>HPRE_DIV64</name>
              <bitOffset>2</bitOffset>
              <bitWidth>2</bitWidth>
            </field>
            <field>
              <name>HPRE_DIV2</name>
              <bitOffset>3</bitOffset>
              <bitWidth>1</bitWidth>
            </field>
            <field>
              <name>D1PPRE_DIV4</name>
              <bitOffset>4</bitOffset>
              <bitWidth>3</bitWidth>
            </field>
            <field>
              <name>D1PPRE_DIV8</name>
              <bitOffset>5</bitOffset>
              <bitWidth>2</bitWidth>
            </field>
            <field>
              <name>D1PPRE_DIV2</name>
              <bitOffset>6</bitOffset>
              <bitWidth>1</bitWidth>
            </field>
            <field>
              <name>D1CPRE_DIV512</name>
              <bitOffset>8</bitOffset>
              <bitWidth>4</bitWidth>
            </field>
            <field>
              <name>D1CPRE_DIV8</name>
              <bitOffset>9</bitOffset>
              <bitWidth>3</bitWidth>
            </field>
            <field>
              <name>D1CPRE_DIV64</name>
              <bitOffset>10</bitOffset>
              <bitWidth>2</bitWidth>
            </field>
            <field>
              <name>D1CPRE_DIV2</name>
              <bitOffset>11</bitOffset>
              <bitWidth>1</bitWidth>
            </field>
          </fields>
        </register>
        <register>
          <name>D2CFGR</name>
          <addressOffset>0x1c</addressOffset>
          <size>0x20</size>
          <fields>
            <field>
              <name>D2PPRE1_DIV4</name>
              <bitOffset>4</bitOffset>
              <bitWidth>3</bitWidth>
            </field>
            <field>
              <name>D2PPRE1_DIV8</name>
              <bitOffset>5</bitOffset>
              <bitWidth>2</bitWidth>
            </field>
            <field>
              <name>D2PPRE1_DIV2</name>
              <bitOffset>6</bitOffset>
              <bitWidth>1</bitWidth>
            </field>
            <field>
              <name>D2PPRE2_DIV4</name>
              <bitOffset>8</bitOffset>
              <bitWidth>3</bitWidth>
            </field>
            <field>
              <name>D2PPRE2_DIV8</name>
              <bitOffset>9</bitOffset>
              <bitWidth>2</bitWidth>
            </field>
            <field>
              <name>D2PPRE2_DIV2</name>
              <bitOffset>10</bitOffset>
              <bitWidth>1</bitWidth>
            </field>
          </fields>
        </register>
        <register>
          <name>D3CFGR</name>
          <addressOffset>0x20</addressOffset>
          <size>0x20</size>
          <fields>
            <field>
              <name>D3PPRE_DIV4</name>
              <bitOffset>4</bitOffset>
              <bitWidth>3</bitWidth>
            </field>
            <field>
              <name>D3PPRE_DIV8</name>
              <bitOffset>5</bitOffset>
              <bitWidth>2</bitWidth>
            </field>
            <field>
              <name>D3PPRE_DIV2</name>
              <bitOffset>6</bitOffset>
              <bitWidth>1</bitWidth>
            </field>
          </fields>
        </register>
        <register>
          <name>PLLCKSELR</name>
          <addressOffset>0x28</addressOffset>
          <size>0x20</size>
          <fields>
            <field>
              <name>PLLSRC_NONE</name>
              <bitOffset>0</bitOffset>
              <bitWidth>2</bitWidth>
            </field>
            <field>
              <name>PLLSRC_HSE</name>
              <bitOffset>1</bitOffset>
              <bitWidth>1</bitWidth>
            </field>
            <field>
              <name>DIVM1</name>
              <bitOffset>4</bitOffset>
              <bitWidth>6</bitWidth>
            </field>
            <field>
              <name>DIVM2</name>
              <bitOffset>12</bitOffset>
              <bitWidth>6</bitWidth>
            </field>
            <field>
              <name>DIVM3</name>
              <bitOffset>20</bitOffset>
              <bitWidth>6</bitWidth>
            </field>
          </fields>
        </register>
        <register>
          <name>PLLCFGR</name>
          <addressOffset>0x2c</addressOffset>
          <size>0x20</size>
          <fields>
            <field>
              <name>PLL1FRACEN</name>
              <bitOffset>0</bitOffset>
              <bitWidth>1</bitWidth>
            </field>
            <field>
              <name>PLL1VCOSEL</name>
              <bitOffset>1</bitOffset>
              <bitWidth>1</bitWidth>
            </field>
            <field>
              <name>PLL1RGE</name>
              <bitOffset>2</bitOffset>
              <bitWidth>2</bitWidth>
            </field>
            <field>
              <name>PLL2FRACEN</name>
              <bitOffset>4</bitOffset>
              <bitWidth>1</bitWidth>
            </field>
            <field>
              <name>PLL2VCOSEL</name>
              <bitOffset>5</bitOffset>
              <bitWidth>1</bitWidth>
            </field>
            <field>
              <name>PLL2RGE</name>
              <bitOffset>6</bitOffset>
              <bitWidth>2</bitWidth>
            </field>
            <field>
              <name>PLL3FRACEN</name>
              <bitOffset>8</bitOffset>
              <bitWidth>1</bitWidth>
            </field>
            <field>
              <name>PLL3VCOSEL</name>
              <bitOffset>9</bitOffset>
              <bitWidth>1</bitWidth>
            </field>
            <field>
              <name>PLL3RGE</name>
              <bitOffset>10</bitOffset>
              <bitWidth>2</bitWidth>
            </field>
            <field>
              <name>DIVP1EN</name>
              <bitOffset>16</bitOffset>
              <bitWidth>1</bitWidth>
            </field>
            <field>
              <name>DIVQ1EN</name>
              <bitOffset>17</bitOffset>
              <bitWidth>1</bitWidth>
            </field>
            <field>
              <name>DIVR1EN</name>
              <bitOffset>18</bitOffset>
              <bitWidth>1</bitWidth>
            </field>
            <field>
              <name>DIVP2EN</name>
              <bitOffset>19</bitOffset>
              <bitWidth>1</bitWidth>
            </field>
            <field>
              <name>DIVQ2EN</name>
              <bitOffset>20</bitOffset>
              <bitWidth>1</bitWidth>
            </field>
            <field>
              <name>DIVR2EN</name>
              <bitOffset>21</bitOffset>
              <bitWidth>1</bitWidth>
            </field>
            <field>
              <name>DIVP3EN</name>
              <bitOffset>22</bitOffset>
              <bitWidth>1</bitWidth>
            </field>
            <field>
              <name>DIVQ3EN</name>
              <bitOffset>23</bitOffset>
              <bitWidth>1</bitWidth>
            </field>
            <field>
              <name>DIVR3EN</name>
              <bitOffset>24</bitOffset>
              <bitWidth>1</bitWidth>
            </field>
          </fields>
        </register>
        <register>
          <name>PLL1DIVR</name>
          <addressOffset>0x30</addressOffset>
          <size>0x20</size>
          <fields>
            <field>
              <name>N1</name>
              <bitOffset>0</bitOffset>
              <bitWidth>9</bitWidth>
            </field>
            <field>
              <name>P1</name>
              <bitOffset>9</bitOffset>
              <bitWidth>7</bitWidth>
            </field>
            <field>
              <name>Q1</name>
              <bitOffset>16</bitOffset>
              <bitWidth>7</bitWidth>
            </field>
            <field>
              <name>R1</name>
              <bitOffset>24</bitOffset>
              <bitWidth>7</bitWidth>
            </field>
          </fields>
        </register>
        <register>
          <name>PLL1FRACR</name>
          <addressOffset>0x34</addressOffset>
          <size>0x20</size>
          <fields>
            <field>
              <name>FRACN1</name>
              <bitOffset>3</bitOffset>
              <bitWidth>13</bitWidth>
            </field>
          </fields>
        </register>
        <register>
          <name>PLL2DIVR</name>
          <addressOffset>0x38</addressOffset>
          <size>0x20</size>
          <fields>
            <field>
              <name>N2</name>
              <bitOffset>0</bitOffset>
              <bitWidth>9</bitWidth>
            </field>
            <field>
              <name>P2</name>
              <bitOffset>9</bitOffset>
              <bitWidth>7</bitWidth>
            </field>
            <field>
              <name>Q2</name>
              <bitOffset>16</bitOffset>
              <bitWidth>7</bitWidth>
            </field>
            <field>
              <name>R2</name>
              <bitOffset>24</bitOffset>
              <bitWidth>7</bitWidth>
            </field>
          </fields>
        </register>
        <register>
          <name>PLL2FRACR</name>
          <addressOffset>0x3c</addressOffset>
          <size>0x20</size>
          <fields>
            <field>
              <name>FRACN2</name>
              <bitOffset>3</bitOffset>
              <bitWidth>13</bitWidth>
            </field>
          </fields>
        </register>
        <register>
          <name>PLL3DIVR</name>
          <addressOffset>0x40</addressOffset>
          <size>0x20</size>
          <fields>
            <field>
              <name>N3</name>
              <bitOffset>0</bitOffset>
              <bitWidth>9</bitWidth>
            </field>
            <field>
              <name>P3</name>
              <bitOffset>9</bitOffset>
              <bitWidth>7</bitWidth>
            </field>
            <field>
              <name>Q3</name>
              <bitOffset>16</bitOffset>
              <bitWidth>7</bitWidth>
            </field>
            <field>
              <name>R3</name>
              <bitOffset>24</bitOffset>
              <bitWidth>7</bitWidth>
            </field>
          </fields>
        </register>
        <register>
          <name>PLL3FRACR</name>
          <addressOffset>0x44</addressOffset>
          <size>0x20</size>
          <fields>
            <field>
              <name>FRACN3</name>
              <bitOffset>3</bitOffset>
              <bitWidth>13</bitWidth>
            </field>
          </fields>
        </register>
        <register>
          <name>D1CCIPR</name>
          <addressOffset>0x4c</addressOffset>
          <size>0x20</size>
          <fields>
            <field>
              <name>FMCSEL</name>
              <bitOffset>0</bitOffset>
              <bitWidth>2</bitWidth>
            </field>
            <field>
              <name>OCTOSPISEL</name>
              <bitOffset>4</bitOffset>
              <bitWidth>2</bitWidth>
            </field>
            <field>
              <name>SDMMCSEL</name>
              <bitOffset>16</bitOffset>
              <bitWidth>1</bitWidth>
            </field>
            <field>
              <name>CKPERSEL</name>
              <bitOffset>28</bitOffset>
              <bitWidth>2</bitWidth>
            </field>
          </fields>
        </register>
        <register>
          <name>D2CCIP1R</name>
          <addressOffset>0x50</addressOffset>
          <size>0x20</size>
          <fields>
            <field>
              <name>SAI1SEL</name>
              <bitOffset>0</bitOffset>
              <bitWidth>3</bitWidth>
            </field>
            <field>
              <name>SPI123SEL</name>
              <bitOffset>12</bitOffset>
              <bitWidth>3</bitWidth>
            </field>
            <field>
              <name>SPI45SEL</name>
              <bitOffset>16</bitOffset>
              <bitWidth>3</bitWidth>
            </field>
            <field>
              <name>SPDIFSEL</name>
              <bitOffset>20</bitOffset>
              <bitWidth>2</bitWidth>
            </field>
            <field>
              <name>DFSDM1SEL</name>
              <bitOffset>24</bitOffset>
              <bitWidth>1</bitWidth>
            </field>
            <field>
              <name>FDCANSEL</name>
              <bitOffset>28</bitOffset>
              <bitWidth>2</bitWidth>
            </field>
            <field>
              <name>SWPSEL</name>
              <bitOffset>31</bitOffset>
              <bitWidth>1</bitWidth>
            </field>
          </fields>
        </register>
        <register>
          <name>D2CCIP2R</name>
          <addressOffset>0x54</addressOffset>
          <size>0x20</size>
          <fields>
            <field>
              <name>USART28SEL</name>
              <bitOffset>0</bitOffset>
              <bitWidth>3</bitWidth>
            </field>
            <field>
              <name>USART16910SEL</name>
              <bitOffset>3</bitOffset>
              <bitWidth>3</bitWidth>
            </field>
            <field>
              <name>RNGSEL</name>
              <bitOffset>8</bitOffset>
              <bitWidth>2</bitWidth>
            </field>
            <field>
              <name>I2C1235SEL</name>
              <bitOffset>12</bitOffset>
              <bitWidth>2</bitWidth>
            </field>
            <field>
              <name>USBSEL</name>
              <bitOffset>20</bitOffset>
              <bitWidth>2</bitWidth>
            </field>
            <field>
              <name>CECSEL</name>
              <bitOffset>22</bitOffset>
              <bitWidth>2</bitWidth>
            </field>
            <field>
              <name>LPTIM1SEL</name>
              <bitOffset>28</bitOffset>
              <bitWidth>3</bitWidth>
            </field>
          </fields>
        </register>
        <register>
          <name>D3CCIPR</name>
          <addressOffset>0x58</addressOffset>
          <size>0x20</size>
          <fields>
            <field>
              <name>LPUART1SEL</name>
              <bitOffset>0</bitOffset>
              <bitWidth>3</bitWidth>
            </field>
            <field>
              <name>I2C4SEL</name>
              <bitOffset>8</bitOffset>
              <bitWidth>2</bitWidth>
            </field>
            <field>
              <name>LPTIM2SEL</name>
              <bitOffset>10</bitOffset>
              <bitWidth>3</bitWidth>
            </field>
            <field>
              <name>LPTIM345SEL</name>
              <bitOffset>13</bitOffset>
              <bitWidth>3</bitWidth>
            </field>
            <field>
              <name>ADCSEL</name>
              <bitOffset>16</bitOffset>
              <bitWidth>2</bitWidth>
            </field>
            <field>
              <name>SAI4ASEL</name>
              <bitOffset>21</bitOffset>
              <bitWidth>3</bitWidth>
            </field>
            <field>
              <name>SAI4BSEL</name>
              <bitOffset>24</bitOffset>
              <bitWidth>3</bitWidth>
            </field>
            <field>
              <name>SPI6SEL</name>
              <bitOffset>28</bitOffset>
              <bitWidth>3</bitWidth>
            </field>
          </fields>
        </register>
        <register>
          <name>CIER</name>
          <addressOffset>0x60</addressOffset>
          <size>0x20</size>
          <fields>
            <field>
              <name>LSIRDYIE</name>
              <bitOffset>0</bitOffset>
              <bitWidth>1</bitWidth>
            </field>
            <field>
              <name>LSERDYIE</name>
              <bitOffset>1</bitOffset>
              <bitWidth>1</bitWidth>
            </field>
            <field>
              <name>HSIRDYIE</name>
              <bitOffset>2</bitOffset>
              <bitWidth>1</bitWidth>
            </field>
            <field>
              <name>HSERDYIE</name>
              <bitOffset>3</bitOffset>
              <bitWidth>1</bitWidth>
            </field>
            <field>
              <name>CSIRDYIE</name>
              <bitOffset>4</bitOffset>
              <bitWidth>1</bitWidth>
            </field>
            <field>
              <name>HSI48RDYIE</name>
              <bitOffset>5</bitOffset>
              <bitWidth>1</bitWidth>
            </field>
            <field>
              <name>PLL1RDYIE</name>
              <bitOffset>6</bitOffset>
              <bitWidth>1</bitWidth>
            </field>
            <field>
              <name>PLL2RDYIE</name>
              <bitOffset>7</bitOffset>
              <bitWidth>1</bitWidth>
            </field>
            <field>
              <name>PLL3RDYIE</name>
              <bitOffset>8</bitOffset>
              <bitWidth>1</bitWidth>
            </field>
            <field>
              <name>LSECSSIE</name>
              <bitOffset>9</bitOffset>
              <bitWidth>1</bitWidth>
            </field>
          </fields>
        </register>
        <register>
          <name>CIFR</name>
          <addressOffset>0x64</addressOffset>
          <size>0x20</size>
          <fields>
            <field>
              <name>LSIRDYF</name>
              <bitOffset>0</bitOffset>
              <bitWidth>1</bitWidth>
            </field>
            <field>
              <name>LSERDYF</name>
              <bitOffset>1</bitOffset>
              <bitWidth>1</bitWidth>
            </field>
            <field>
              <name>HSIRDYF</name>
              <bitOffset>2</bitOffset>
              <bitWidth>1</bitWidth>
            </field>
            <field>
              <name>HSERDYF</name>
              <bitOffset>3</bitOffset>
              <bitWidth>1</bitWidth>
            </field>
            <field>
              <name>CSIRDYF</name>
              <bitOffset>4</bitOffset>
              <bitWidth>1</bitWidth>
            </field>
            <field>
              <name>HSI48RDYF</name>
              <bitOffset>5</bitOffset>
              <bitWidth>1</bitWidth>
            </field>
            <field>
              <name>PLLRDYF</name>
              <bitOffset>6</bitOffset>
              <bitWidth>1</bitWidth>
            </field>
            <field>
              <name>PLL2RDYF</name>
              <bitOffset>7</bitOffset>
              <bitWidth>1</bitWidth>
            </field>
            <field>
              <name>PLL3RDYF</name>
              <bitOffset>8</bitOffset>
              <bitWidth>1</bitWidth>
            </field>
            <field>
              <name>LSECSSF</name>
              <bitOffset>9</bitOffset>
              <bitWidth>1</bitWidth>
            </field>
            <field>
              <name>HSECSSF</name>
              <bitOffset>10</bitOffset>
              <bitWidth>1</bitWidth>
            </field>
          </fields>
        </register>
        <register>
          <name>CICR</name>
          <addressOffset>0x68</addressOffset>
          <size>0x20</size>
          <fields>
            <field>
              <name>LSIRDYC</name>
              <bitOffset>0</bitOffset>
              <bitWidth>1</bitWidth>
            </field>
            <field>
              <name>LSERDYC</name>
              <bitOffset>1</bitOffset>
              <bitWidth>1</bitWidth>
            </field>
            <field>
              <name>HSIRDYC</name>
              <bitOffset>2</bitOffset>
              <bitWidth>1</bitWidth>
            </field>
            <field>
              <name>HSERDYC</name>
              <bitOffset>3</bitOffset>
              <bitWidth>1</bitWidth>
            </field>
            <field>
              <name>CSIRDYC</name>
              <bitOffset>4</bitOffset>
              <bitWidth>1</bitWidth>
            </field>
            <field>
              <name>HSI48RDYC</name>
              <bitOffset>5</bitOffset>
              <bitWidth>1</bitWidth>
            </field>
            <field>
              <name>PLLRDYC</name>
              <bitOffset>6</bitOffset>
              <bitWidth>1</bitWidth>
            </field>
            <field>
              <name>PLL2RDYC</name>
              <bitOffset>7</bitOffset>
              <bitWidth>1</bitWidth>
            </field>
            <field>
              <name>PLL3RDYC</name>
              <bitOffset>8</bitOffset>
              <bitWidth>1</bitWidth>
            </field>
            <field>
              <name>LSECSSC</name>
              <bitOffset>9</bitOffset>
              <bitWidth>1</bitWidth>
            </field>
            <field>
              <name>HSECSSC</name>
              <bitOffset>10</bitOffset>
              <bitWidth>1</bitWidth>
            </field>
          </fields>
        </register>
        <register>
          <name>BDCR</name>
          <addressOffset>0x70</addressOffset>
          <size>0x20</size>
          <fields>
            <field>
              <name>LSEON</name>
              <bitOffset>0</bitOffset>
              <bitWidth>1</bitWidth>
            </field>
            <field>
              <name>LSERDY</name>
              <bitOffset>1</bitOffset>
              <bitWidth>1</bitWidth>
            </field>
            <field>
              <name>LSEBYP</name>
              <bitOffset>2</bitOffset>
              <bitWidth>1</bitWidth>
            </field>
            <field>
              <name>LSEDRV</name>
              <bitOffset>3</bitOffset>
              <bitWidth>2</bitWidth>
            </field>
            <field>
              <name>LSECSSON</name>
              <bitOffset>5</bitOffset>
              <bitWidth>1</bitWidth>
            </field>
            <field>
              <name>LSECSSD</name>
              <bitOffset>6</bitOffset>
              <bitWidth>1</bitWidth>
            </field>
            <field>
              <name>RTCSEL</name>
              <bitOffset>8</bitOffset>
              <bitWidth>2</bitWidth>
            </field>
            <field>
              <name>RTCEN</name>
              <bitOffset>15</bitOffset>
              <bitWidth>1</bitWidth>
            </field>
            <field>
              <name>VSWRST</name>
              <bitOffset>16</bitOffset>
              <bitWidth>1</bitWidth>
            </field>
          </fields>
        </register>
        <register>
          <name>CSR</name>
          <addressOffset>0x74</addressOffset>
          <size>0x20</size>
          <fields>
            <field>
              <name>LSION</name>
              <bitOffset>0</bitOffset>
              <bitWidth>1</bitWidth>
            </field>
            <field>
              <name>LSIRDY</name>
              <bitOffset>1</bitOffset>
              <bitWidth>1</bitWidth>
            </field>
          </fields>
        </register>
        <register>
          <name>AHB3RSTR</name>
          <addressOffset>0x7c</addressOffset>
          <size>0x20</size>
          <fields>
            <field>
              <name>MDMARST</name>
              <bitOffset>0</bitOffset>
              <bitWidth>1</bitWidth>
            </field>
            <field>
              <name>DMA2DRST</name>
              <bitOffset>4</bitOffset>
              <bitWidth>1</bitWidth>
            </field>
            <field>
              <name>FMCRST</name>
              <bitOffset>12</bitOffset>
              <bitWidth>1</bitWidth>
            </field>
            <field>
              <name>OSPI1RST</name>
              <bitOffset>14</bitOffset>
              <bitWidth>1</bitWidth>
            </field>
            <field>
              <name>SDMMC1RST</name>
              <bitOffset>16</bitOffset>
              <bitWidth>1</bitWidth>
            </field>
            <field>
              <name>OSPI2RST</name>
              <bitOffset>19</bitOffset>
              <bitWidth>1</bitWidth>
            </field>
            <field>
              <name>IOMNGRRST</name>
              <bitOffset>21</bitOffset>
              <bitWidth>1</bitWidth>
            </field>
            <field>
              <name>CPURST</name>
              <bitOffset>31</bitOffset>
              <bitWidth>1</bitWidth>
            </field>
          </fields>
        </register>
        <register>
          <name>AHB1RSTR</name>
          <addressOffset>0x80</addressOffset>
          <size>0x20</size>
          <fields>
            <field>
              <name>DMA1RST</name>
              <bitOffset>0</bitOffset>
              <bitWidth>1</bitWidth>
            </field>
            <field>
              <name>DMA2RST</name>
              <bitOffset>1</bitOffset>
              <bitWidth>1</bitWidth>
            </field>
            <field>
              <name>ADC12RST</name>
              <bitOffset>5</bitOffset>
              <bitWidth>1</bitWidth>
            </field>
            <field>
              <name>ETH1MACRST</name>
              <bitOffset>15</bitOffset>
              <bitWidth>1</bitWidth>
            </field>
            <field>
              <name>USB1OTGHSRST</name>
              <bitOffset>25</bitOffset>
              <bitWidth>1</bitWidth>
            </field>
          </fields>
        </register>
        <register>
          <name>AHB2RSTR</name>
          <addressOffset>0x84</addressOffset>
          <size>0x20</size>
          <fields>
            <field>
              <name>DCMI_PSSIRST</name>
              <bitOffset>0</bitOffset>
              <bitWidth>1</bitWidth>
            </field>
            <field>
              <name>RNGRST</name>
              <bitOffset>6</bitOffset>
              <bitWidth>1</bitWidth>
            </field>
            <field>
              <name>SDMMC2RST</name>
              <bitOffset>9</bitOffset>
              <bitWidth>1</bitWidth>
            </field>
            <field>
              <name>FMACRST</name>
              <bitOffset>16</bitOffset>
              <bitWidth>1</bitWidth>
            </field>
            <field>
              <name>CORDICRST</name>
              <bitOffset>17</bitOffset>
              <bitWidth>1</bitWidth>
            </field>
          </fields>
        </register>
        <register>
          <name>AHB4RSTR</name>
          <addressOffset>0x88</addressOffset>
          <size>0x20</size>
          <fields>
            <field>
              <name>GPIOARST</name>
              <bitOffset>0</bitOffset>
              <bitWidth>1</bitWidth>
            </field>
            <field>
              <name>GPIOBRST</name>
              <bitOffset>1</bitOffset>
              <bitWidth>1</bitWidth>
            </field>
            <field>
              <name>GPIOCRST</name>
              <bitOffset>2</bitOffset>
              <bitWidth>1</bitWidth>
            </field>
            <field>
              <name>GPIODRST</name>
              <bitOffset>3</bitOffset>
              <bitWidth>1</bitWidth>
            </field>
            <field>
              <name>GPIOERST</name>
              <bitOffset>4</bitOffset>
              <bitWidth>1</bitWidth>
            </field>
            <field>
              <name>GPIOFRST</name>
              <bitOffset>5</bitOffset>
              <bitWidth>1</bitWidth>
            </field>
            <field>
              <name>GPIOGRST</name>
              <bitOffset>6</bitOffset>
              <bitWidth>1</bitWidth>
            </field>
            <field>
              <name>GPIOHRST</name>
              <bitOffset>7</bitOffset>
              <bitWidth>1</bitWidth>
            </field>
            <field>
              <name>GPIOJRST</name>
              <bitOffset>9</bitOffset>
              <bitWidth>1</bitWidth>
            </field>
            <field>
              <name>GPIOKRST</name>
              <bitOffset>10</bitOffset>
              <bitWidth>1</bitWidth>
            </field>
            <field>
              <name>CRCRST</name>
              <bitOffset>19</bitOffset>
              <bitWidth>1</bitWidth>
            </field>
            <field>
              <name>BDMARST</name>
              <bitOffset>21</bitOffset>
              <bitWidth>1</bitWidth>
            </field>
            <field>
              <name>ADC3RST</name>
              <bitOffset>24</bitOffset>
              <bitWidth>1</bitWidth>
            </field>
            <field>
              <name>HSEMRST</name>
              <bitOffset>25</bitOffset>
              <bitWidth>1</bitWidth>
            </field>
          </fields>
        </register>
        <register>
          <name>APB3RSTR</name>
          <addressOffset>0x8c</addressOffset>
          <size>0x20</size>
          <fields>
            <field>
              <name>LTDCRST</name>
              <bitOffset>3</bitOffset>
              <bitWidth>1</bitWidth>
            </field>
          </fields>
        </register>
        <register>
          <name>APB1LRSTR</name>
          <addressOffset>0x90</addressOffset>
          <size>0x20</size>
          <fields>
            <field>
              <name>TIM2RST</name>
              <bitOffset>0</bitOffset>
              <bitWidth>1</bitWidth>
            </field>
            <field>
              <name>TIM3RST</name>
              <bitOffset>1</bitOffset>
              <bitWidth>1</bitWidth>
            </field>
            <field>
              <name>TIM4RST</name>
              <bitOffset>2</bitOffset>
              <bitWidth>1</bitWidth>
            </field>
            <field>
              <name>TIM5RST</name>
              <bitOffset>3</bitOffset>
              <bitWidth>1</bitWidth>
            </field>
            <field>
              <name>TIM6RST</name>
              <bitOffset>4</bitOffset>
              <bitWidth>1</bitWidth>
            </field>
            <field>
              <name>TIM7RST</name>
              <bitOffset>5</bitOffset>
              <bitWidth>1</bitWidth>
            </field>
            <field>
              <name>TIM12RST</name>
              <bitOffset>6</bitOffset>
              <bitWidth>1</bitWidth>
            </field>
            <field>
              <name>TIM13RST</name>
              <bitOffset>7</bitOffset>
              <bitWidth>1</bitWidth>
            </field>
            <field>
              <name>TIM14RST</name>
              <bitOffset>8</bitOffset>
              <bitWidth>1</bitWidth>
            </field>
            <field>
              <name>LPTIM1RST</name>
              <bitOffset>9</bitOffset>
              <bitWidth>1</bitWidth>
            </field>
            <field>
              <name>SPI2RST</name>
              <bitOffset>14</bitOffset>
              <bitWidth>1</bitWidth>
            </field>
            <field>
              <name>SPI3RST</name>
              <bitOffset>15</bitOffset>
              <bitWidth>1</bitWidth>
            </field>
            <field>
              <name>SPDIFRXRST</name>
              <bitOffset>16</bitOffset>
              <bitWidth>1</bitWidth>
            </field>
            <field>
              <name>USART2RST</name>
              <bitOffset>17</bitOffset>
              <bitWidth>1</bitWidth>
            </field>
            <field>
              <name>USART3RST</name>
              <bitOffset>18</bitOffset>
              <bitWidth>1</bitWidth>
            </field>
            <field>
              <name>UART4RST</name>
              <bitOffset>19</bitOffset>
              <bitWidth>1</bitWidth>
            </field>
            <field>
              <name>UART5RST</name>
              <bitOffset>20</bitOffset>
              <bitWidth>1</bitWidth>
            </field>
            <field>
              <name>I2C1RST</name>
              <bitOffset>21</bitOffset>
              <bitWidth>1</bitWidth>
            </field>
            <field>
              <name>I2C2RST</name>
              <bitOffset>22</bitOffset>
              <bitWidth>1</bitWidth>
            </field>
            <field>
              <name>I2C3RST</name>
              <bitOffset>23</bitOffset>
              <bitWidth>1</bitWidth>
            </field>
            <field>
              <name>I2C5RST</name>
              <bitOffset>25</bitOffset>
              <bitWidth>1</bitWidth>
            </field>
            <field>
              <name>HDMICECRST</name>
              <bitOffset>27</bitOffset>
              <bitWidth>1</bitWidth>
            </field>
            <field>
              <name>DAC12RST</name>
              <bitOffset>29</bitOffset>
              <bitWidth>1</bitWidth>
            </field>
            <field>
              <name>UART7RST</name>
              <bitOffset>30</bitOffset>
              <bitWidth>1</bitWidth>
            </field>
            <field>
              <name>UART8RST</name>
              <bitOffset>31</bitOffset>
              <bitWidth>1</bitWidth>
            </field>
          </fields>
        </register>
        <register>
          <name>APB1HRSTR</name>
          <addressOffset>0x94</addressOffset>
          <size>0x20</size>
          <fields>
            <field>
              <name>CRSRST</name>
              <bitOffset>1</bitOffset>
              <bitWidth>1</bitWidth>
            </field>
            <field>
              <name>SWPMIRST</name>
              <bitOffset>2</bitOffset>
              <bitWidth>1</bitWidth>
            </field>
            <field>
              <name>OPAMPRST</name>
              <bitOffset>4</bitOffset>
              <bitWidth>1</bitWidth>
            </field>
            <field>
              <name>MDIOSRST</name>
              <bitOffset>5</bitOffset>
              <bitWidth>1</bitWidth>
            </field>
            <field>
              <name>FDCANRST</name>
              <bitOffset>8</bitOffset>
              <bitWidth>1</bitWidth>
            </field>
            <field>
              <name>TIM23RST</name>
              <bitOffset>24</bitOffset>
              <bitWidth>1</bitWidth>
            </field>
            <field>
              <name>TIM24RST</name>
              <bitOffset>25</bitOffset>
              <bitWidth>1</bitWidth>
            </field>
          </fields>
        </register>
        <register>
          <name>APB2RSTR</name>
          <addressOffset>0x98</addressOffset>
          <size>0x20</size>
          <fields>
            <field>
              <name>TIM1RST</name>
              <bitOffset>0</bitOffset>
              <bitWidth>1</bitWidth>
            </field>
            <field>
              <name>TIM8RST</name>
              <bitOffset>1</bitOffset>
              <bitWidth>1</bitWidth>
            </field>
            <field>
              <name>USART1RST</name>
              <bitOffset>4</bitOffset>
              <bitWidth>1</bitWidth>
            </field>
            <field>
              <name>USART6RST</name>
              <bitOffset>5</bitOffset>
              <bitWidth>1</bitWidth>
            </field>
            <field>
              <name>UART9RST</name>
              <bitOffset>6</bitOffset>
              <bitWidth>1</bitWidth>
            </field>
            <field>
              <name>USART10RST</name>
              <bitOffset>7</bitOffset>
              <bitWidth>1</bitWidth>
            </field>
            <field>
              <name>SPI1RST</name>
              <bitOffset>12</bitOffset>
              <bitWidth>1</bitWidth>
            </field>
            <field>
              <name>SPI4RST</name>
              <bitOffset>13</bitOffset>
              <bitWidth>1</bitWidth>
            </field>
            <field>
              <name>TIM15RST</name>
              <bitOffset>16</bitOffset>
              <bitWidth>1</bitWidth>
            </field>
            <field>
              <name>TIM16RST</name>
              <bitOffset>17</bitOffset>
              <bitWidth>1</bitWidth>
            </field>
            <field>
              <name>TIM17RST</name>
              <bitOffset>18</bitOffset>
              <bitWidth>1</bitWidth>
            </field>
            <field>
              <name>SPI5RST</name>
              <bitOffset>20</bitOffset>
              <bitWidth>1</bitWidth>
            </field>
            <field>
              <name>SAI1RST</name>
              <bitOffset>22</bitOffset>
              <bitWidth>1</bitWidth>
            </field>
            <field>
              <name>DFSDM1RST</name>
              <bitOffset>30</bitOffset>
              <bitWidth>1</bitWidth>
            </field>
          </fields>
        </register>
        <register>
          <name>APB4RSTR</name>
          <addressOffset>0x9c</addressOffset>
          <size>0x20</size>
          <fields>
            <field>
              <name>SYSCFGRST</name>
              <bitOffset>1</bitOffset>
              <bitWidth>1</bitWidth>
            </field>
            <field>
              <name>LPUART1RST</name>
              <bitOffset>3</bitOffset>
              <bitWidth>1</bitWidth>
            </field>
            <field>
              <name>SPI6RST</name>
              <bitOffset>5</bitOffset>
              <bitWidth>1</bitWidth>
            </field>
            <field>
              <name>I2C4RST</name>
              <bitOffset>7</bitOffset>
              <bitWidth>1</bitWidth>
            </field>
            <field>
              <name>LPTIM2RST</name>
              <bitOffset>9</bitOffset>
              <bitWidth>1</bitWidth>
            </field>
            <field>
              <name>LPTIM3RST</name>
              <bitOffset>10</bitOffset>
              <bitWidth>1</bitWidth>
            </field>
            <field>
              <name>LPTIM4RST</name>
              <bitOffset>11</bitOffset>
              <bitWidth>1</bitWidth>
            </field>
            <field>
              <name>LPTIM5RST</name>
              <bitOffset>12</bitOffset>
              <bitWidth>1</bitWidth>
            </field>
            <field>
              <name>COMP12RST</name>
              <bitOffset>14</bitOffset>
              <bitWidth>1</bitWidth>
            </field>
            <field>
              <name>VREFRST</name>
              <bitOffset>15</bitOffset>
              <bitWidth>1</bitWidth>
            </field>
            <field>
              <name>SAI4RST</name>
              <bitOffset>21</bitOffset>
              <bitWidth>1</bitWidth>
            </field>
            <field>
              <name>DTSRST</name>
              <bitOffset>26</bitOffset>
              <bitWidth>1</bitWidth>
            </field>
          </fields>
        </register>
        <register>
          <name>GCR</name>
          <addressOffset>0xa0</addressOffset>
          <size>0x20</size>
          <fields>
            <field>
              <name>WW1RSC</name>
              <bitOffset>0</bitOffset>
              <bitWidth>1</bitWidth>
            </field>
          </fields>
        </register>
        <register>
          <name>D3AMR</name>
          <addressOffset>0xa8</addressOffset>
          <size>0x20</size>
          <fields>
            <field>
              <name>BDMAAMEN</name>
              <bitOffset>0</bitOffset>
              <bitWidth>1</bitWidth>
            </field>
            <field>
              <name>LPUART1AMEN</name>
              <bitOffset>3</bitOffset>
              <bitWidth>1</bitWidth>
            </field>
            <field>
              <name>SPI6AMEN</name>
              <bitOffset>5</bitOffset>
              <bitWidth>1</bitWidth>
            </field>
            <field>
              <name>I2C4AMEN</name>
              <bitOffset>7</bitOffset>
              <bitWidth>1</bitWidth>
            </field>
            <field>
              <name>LPTIM2AMEN</name>
              <bitOffset>9</bitOffset>
              <bitWidth>1</bitWidth>
            </field>
            <field>
              <name>LPTIM3AMEN</name>
              <bitOffset>10</bitOffset>
              <bitWidth>1</bitWidth>
            </field>
            <field>
              <name>LPTIM4AMEN</name>
              <bitOffset>11</bitOffset>
              <bitWidth>1</bitWidth>
            </field>
            <field>
              <name>LPTIM5AMEN</name>
              <bitOffset>12</bitOffset>
              <bitWidth>1</bitWidth>
            </field>
            <field>
              <name>COMP12AMEN</name>
              <bitOffset>14</bitOffset>
              <bitWidth>1</bitWidth>
            </field>
            <field>
              <name>VREFAMEN</name>
              <bitOffset>15</bitOffset>
              <bitWidth>1</bitWidth>
            </field>
            <field>
              <name>RTCAMEN</name>
              <bitOffset>16</bitOffset>
              <bitWidth>1</bitWidth>
            </field>
            <field>
              <name>CRCAMEN</name>
              <bitOffset>19</bitOffset>
              <bitWidth>1</bitWidth>
            </field>
            <field>
              <name>SAI4AMEN</name>
              <bitOffset>21</bitOffset>
              <bitWidth>1</bitWidth>
            </field>
            <field>
              <name>ADC3AMEN</name>
              <bitOffset>24</bitOffset>
              <bitWidth>1</bitWidth>
            </field>
            <field>
              <name>DTSAMEN</name>
              <bitOffset>26</bitOffset>
              <bitWidth>1</bitWidth>
            </field>
            <field>
              <name>BKPRAMAMEN</name>
              <bitOffset>28</bitOffset>
              <bitWidth>1</bitWidth>
            </field>
            <field>
              <name>SRAM4AMEN</name>
              <bitOffset>29</bitOffset>
              <bitWidth>1</bitWidth>
            </field>
          </fields>
        </register>
        <register>
          <name>RSR</name>
          <addressOffset>0xd0</addressOffset>
          <size>0x20</size>
          <fields>
            <field>
              <name>RMVF</name>
              <bitOffset>16</bitOffset>
              <bitWidth>1</bitWidth>
            </field>
            <field>
              <name>CPURSTF</name>
              <bitOffset>17</bitOffset>
              <bitWidth>1</bitWidth>
            </field>
            <field>
              <name>D1RSTF</name>
              <bitOffset>19</bitOffset>
              <bitWidth>1</bitWidth>
            </field>
            <field>
              <name>D2RSTF</name>
              <bitOffset>20</bitOffset>
              <bitWidth>1</bitWidth>
            </field>
            <field>
              <name>BORRSTF</name>
              <bitOffset>21</bitOffset>
              <bitWidth>1</bitWidth>
            </field>
            <field>
              <name>PINRSTF</name>
              <bitOffset>22</bitOffset>
              <bitWidth>1</bitWidth>
            </field>
            <field>
              <name>PORRSTF</name>
              <bitOffset>23</bitOffset>
              <bitWidth>1</bitWidth>
            </field>
            <field>
              <name>SFTRSTF</name>
              <bitOffset>24</bitOffset>
              <bitWidth>1</bitWidth>
            </field>
            <field>
              <name>IWDG1RSTF</name>
              <bitOffset>26</bitOffset>
              <bitWidth>1</bitWidth>
            </field>
            <field>
              <name>WWDG1RSTF</name>
              <bitOffset>28</bitOffset>
              <bitWidth>1</bitWidth>
            </field>
            <field>
              <name>LPWRRSTF</name>
              <bitOffset>30</bitOffset>
              <bitWidth>1</bitWidth>
            </field>
          </fields>
        </register>
        <register>
          <name>AHB3ENR</name>
          <addressOffset>0xd4</addressOffset>
          <size>0x20</size>
          <fields>
            <field>
              <name>MDMAEN</name>
              <bitOffset>0</bitOffset>
              <bitWidth>1</bitWidth>
            </field>
            <field>
              <name>DMA2DEN</name>
              <bitOffset>4</bitOffset>
              <bitWidth>1</bitWidth>
            </field>
            <field>
              <name>FMCEN</name>
              <bitOffset>12</bitOffset>
              <bitWidth>1</bitWidth>
            </field>
            <field>
              <name>OSPI1EN</name>
              <bitOffset>14</bitOffset>
              <bitWidth>1</bitWidth>
            </field>
            <field>
              <name>SDMMC1EN</name>
              <bitOffset>16</bitOffset>
              <bitWidth>1</bitWidth>
            </field>
            <field>
              <name>OSPI2EN</name>
              <bitOffset>19</bitOffset>
              <bitWidth>1</bitWidth>
            </field>
            <field>
              <name>IOMNGREN</name>
              <bitOffset>21</bitOffset>
              <bitWidth>1</bitWidth>
            </field>
          </fields>
        </register>
        <register>
          <name>AHB1ENR</name>
          <addressOffset>0xd8</addressOffset>
          <size>0x20</size>
          <fields>
            <field>
              <name>DMA1EN</name>
              <bitOffset>0</bitOffset>
              <bitWidth>1</bitWidth>
            </field>
            <field>
              <name>DMA2EN</name>
              <bitOffset>1</bitOffset>
              <bitWidth>1</bitWidth>
            </field>
            <field>
              <name>ADC12EN</name>
              <bitOffset>5</bitOffset>
              <bitWidth>1</bitWidth>
            </field>
            <field>
              <name>ETH1MACEN</name>
              <bitOffset>15</bitOffset>
              <bitWidth>1</bitWidth>
            </field>
            <field>
              <name>ETH1TXEN</name>
              <bitOffset>16</bitOffset>
              <bitWidth>1</bitWidth>
            </field>
            <field>
              <name>ETH1RXEN</name>
              <bitOffset>17</bitOffset>
              <bitWidth>1</bitWidth>
            </field>
            <field>
              <name>USB1OTGHSEN</name>
              <bitOffset>25</bitOffset>
              <bitWidth>1</bitWidth>
            </field>
            <field>
              <name>USB1OTGHSULPIEN</name>
              <bitOffset>26</bitOffset>
              <bitWidth>1</bitWidth>
            </field>
          </fields>
        </register>
        <register>
          <name>AHB2ENR</name>
          <addressOffset>0xdc</addressOffset>
          <size>0x20</size>
          <fields>
            <field>
              <name>DCMI_PSSIEN</name>
              <bitOffset>0</bitOffset>
              <bitWidth>1</bitWidth>
            </field>
            <field>
              <name>RNGEN</name>
              <bitOffset>6</bitOffset>
              <bitWidth>1</bitWidth>
            </field>
            <field>
              <name>SDMMC2EN</name>
              <bitOffset>9</bitOffset>
              <bitWidth>1</bitWidth>
            </field>
            <field>
              <name>FMACEN</name>
              <bitOffset>16</bitOffset>
              <bitWidth>1</bitWidth>
            </field>
            <field>
              <name>CORDICEN</name>
              <bitOffset>17</bitOffset>
              <bitWidth>1</bitWidth>
            </field>
            <field>
              <name>SRAM1EN</name>
              <bitOffset>29</bitOffset>
              <bitWidth>1</bitWidth>
            </field>
            <field>
              <name>SRAM2EN</name>
              <bitOffset>30</bitOffset>
              <bitWidth>1</bitWidth>
            </field>
          </fields>
        </register>
        <register>
          <name>AHB4ENR</name>
          <addressOffset>0xe0</addressOffset>
          <size>0x20</size>
          <fields>
            <field>
              <name>GPIOAEN</name>
              <bitOffset>0</bitOffset>
              <bitWidth>1</bitWidth>
            </field>
            <field>
              <name>GPIOBEN</name>
              <bitOffset>1</bitOffset>
              <bitWidth>1</bitWidth>
            </field>
            <field>
              <name>GPIOCEN</name>
              <bitOffset>2</bitOffset>
              <bitWidth>1</bitWidth>
            </field>
            <field>
              <name>GPIODEN</name>
              <bitOffset>3</bitOffset>
              <bitWidth>1</bitWidth>
            </field>
            <field>
              <name>GPIOEEN</name>
              <bitOffset>4</bitOffset>
              <bitWidth>1</bitWidth>
            </field>
            <field>
              <name>GPIOFEN</name>
              <bitOffset>5</bitOffset>
              <bitWidth>1</bitWidth>
            </field>
            <field>
              <name>GPIOGEN</name>
              <bitOffset>6</bitOffset>
              <bitWidth>1</bitWidth>
            </field>
            <field>
              <name>GPIOHEN</name>
              <bitOffset>7</bitOffset>
              <bitWidth>1</bitWidth>
            </field>
            <field>
              <name>GPIOJEN</name>
              <bitOffset>9</bitOffset>
              <bitWidth>1</bitWidth>
            </field>
            <field>
              <name>GPIOKEN</name>
              <bitOffset>10</bitOffset>
              <bitWidth>1</bitWidth>
            </field>
            <field>
              <name>CRCEN</name>
              <bitOffset>19</bitOffset>
              <bitWidth>1</bitWidth>
            </field>
            <field>
              <name>BDMAEN</name>
              <bitOffset>21</bitOffset>
              <bitWidth>1</bitWidth>
            </field>
            <field>
              <name>ADC3EN</name>
              <bitOffset>24</bitOffset>
              <bitWidth>1</bitWidth>
            </field>
            <field>
              <name>HSEMEN</name>
              <bitOffset>25</bitOffset>
              <bitWidth>1</bitWidth>
            </field>
            <field>
              <name>BKPRAMEN</name>
              <bitOffset>28</bitOffset>
              <bitWidth>1</bitWidth>
            </field>
          </fields>
        </register>
        <register>
          <name>APB3ENR</name>
          <addressOffset>0xe4</addressOffset>
          <size>0x20</size>
          <fields>
            <field>
              <name>LTDCEN</name>
              <bitOffset>3</bitOffset>
              <bitWidth>1</bitWidth>
            </field>
            <field>
              <name>WWDG1EN</name>
              <bitOffset>6</bitOffset>
              <bitWidth>1</bitWidth>
            </field>
          </fields>
        </register>
        <register>
          <name>APB1LENR</name>
          <addressOffset>0xe8</addressOffset>
          <size>0x20</size>
          <fields>
            <field>
              <name>TIM2EN</name>
              <bitOffset>0</bitOffset>
              <bitWidth>1</bitWidth>
            </field>
            <field>
              <name>TIM3EN</name>
              <bitOffset>1</bitOffset>
              <bitWidth>1</bitWidth>
            </field>
            <field>
              <name>TIM4EN</name>
              <bitOffset>2</bitOffset>
              <bitWidth>1</bitWidth>
            </field>
            <field>
              <name>TIM5EN</name>
              <bitOffset>3</bitOffset>
              <bitWidth>1</bitWidth>
            </field>
            <field>
              <name>TIM6EN</name>
              <bitOffset>4</bitOffset>
              <bitWidth>1</bitWidth>
            </field>
            <field>
              <name>TIM7EN</name>
              <bitOffset>5</bitOffset>
              <bitWidth>1</bitWidth>
            </field>
            <field>
              <name>TIM12EN</name>
              <bitOffset>6</bitOffset>
              <bitWidth>1</bitWidth>
            </field>
            <field>
              <name>TIM13EN</name>
              <bitOffset>7</bitOffset>
              <bitWidth>1</bitWidth>
            </field>
            <field>
              <name>TIM14EN</name>
              <bitOffset>8</bitOffset>
              <bitWidth>1</bitWidth>
            </field>
            <field>
              <name>LPTIM1EN</name>
              <bitOffset>9</bitOffset>
              <bitWidth>1</bitWidth>
            </field>
            <field>
              <name>SPI2EN</name>
              <bitOffset>14</bitOffset>
              <bitWidth>1</bitWidth>
            </field>
            <field>
              <name>SPI3EN</name>
              <bitOffset>15</bitOffset>
              <bitWidth>1</bitWidth>
            </field>
            <field>
              <name>SPDIFRXEN</name>
              <bitOffset>16</bitOffset>
              <bitWidth>1</bitWidth>
            </field>
            <field>
              <name>USART2EN</name>
              <bitOffset>17</bitOffset>
              <bitWidth>1</bitWidth>
            </field>
            <field>
              <name>USART3EN</name>
              <bitOffset>18</bitOffset>
              <bitWidth>1</bitWidth>
            </field>
            <field>
              <name>UART4EN</name>
              <bitOffset>19</bitOffset>
              <bitWidth>1</bitWidth>
            </field>
            <field>
              <name>UART5EN</name>
              <bitOffset>20</bitOffset>
              <bitWidth>1</bitWidth>
            </field>
            <field>
              <name>I2C1EN</name>
              <bitOffset>21</bitOffset>
              <bitWidth>1</bitWidth>
            </field>
            <field>
              <name>I2C2EN</name>
              <bitOffset>22</bitOffset>
              <bitWidth>1</bitWidth>
            </field>
            <field>
              <name>I2C3EN</name>
              <bitOffset>23</bitOffset>
              <bitWidth>1</bitWidth>
            </field>
            <field>
              <name>I2C5EN</name>
              <bitOffset>25</bitOffset>
              <bitWidth>1</bitWidth>
            </field>
            <field>
              <name>HDMICECEN</name>
              <bitOffset>27</bitOffset>
              <bitWidth>1</bitWidth>
            </field>
            <field>
              <name>DAC12EN</name>
              <bitOffset>29</bitOffset>
              <bitWidth>1</bitWidth>
            </field>
            <field>
              <name>UART7EN</name>
              <bitOffset>30</bitOffset>
              <bitWidth>1</bitWidth>
            </field>
            <field>
              <name>UART8EN</name>
              <bitOffset>31</bitOffset>
              <bitWidth>1</bitWidth>
            </field>
          </fields>
        </register>
        <register>
          <name>APB1HENR</name>
          <addressOffset>0xec</addressOffset>
          <size>0x20</size>
          <fields>
            <field>
              <name>CRSEN</name>
              <bitOffset>1</bitOffset>
              <bitWidth>1</bitWidth>
            </field>
            <field>
              <name>SWPMIEN</name>
              <bitOffset>2</bitOffset>
              <bitWidth>1</bitWidth>
            </field>
            <field>
              <name>OPAMPEN</name>
              <bitOffset>4</bitOffset>
              <bitWidth>1</bitWidth>
            </field>
            <field>
              <name>MDIOSEN</name>
              <bitOffset>5</bitOffset>
              <bitWidth>1</bitWidth>
            </field>
            <field>
              <name>FDCANEN</name>
              <bitOffset>8</bitOffset>
              <bitWidth>1</bitWidth>
            </field>
            <field>
              <name>TIM23EN</name>
              <bitOffset>24</bitOffset>
              <bitWidth>1</bitWidth>
            </field>
            <field>
              <name>TIM24EN</name>
              <bitOffset>25</bitOffset>
              <bitWidth>1</bitWidth>
            </field>
          </fields>
        </register>
        <register>
          <name>APB2ENR</name>
          <addressOffset>0xf0</addressOffset>
          <size>0x20</size>
          <fields>
            <field>
              <name>TIM1EN</name>
              <bitOffset>0</bitOffset>
              <bitWidth>1</bitWidth>
            </field>
            <field>
              <name>TIM8EN</name>
              <bitOffset>1</bitOffset>
              <bitWidth>1</bitWidth>
            </field>
            <field>
              <name>USART1EN</name>
              <bitOffset>4</bitOffset>
              <bitWidth>1</bitWidth>
            </field>
            <field>
              <name>USART6EN</name>
              <bitOffset>5</bitOffset>
              <bitWidth>1</bitWidth>
            </field>
            <field>
              <name>UART9EN</name>
              <bitOffset>6</bitOffset>
              <bitWidth>1</bitWidth>
            </field>
            <field>
              <name>USART10EN</name>
              <bitOffset>7</bitOffset>
              <bitWidth>1</bitWidth>
            </field>
            <field>
              <name>SPI1EN</name>
              <bitOffset>12</bitOffset>
              <bitWidth>1</bitWidth>
            </field>
            <field>
              <name>SPI4EN</name>
              <bitOffset>13</bitOffset>
              <bitWidth>1</bitWidth>
            </field>
            <field>
              <name>TIM15EN</name>
              <bitOffset>16</bitOffset>
              <bitWidth>1</bitWidth>
            </field>
            <field>
              <name>TIM16EN</name>
              <bitOffset>17</bitOffset>
              <bitWidth>1</bitWidth>
            </field>
            <field>
              <name>TIM17EN</name>
              <bitOffset>18</bitOffset>
              <bitWidth>1</bitWidth>
            </field>
            <field>
              <name>SPI5EN</name>
              <bitOffset>20</bitOffset>
              <bitWidth>1</bitWidth>
            </field>
            <field>
              <name>SAI1EN</name>
              <bitOffset>22</bitOffset>
              <bitWidth>1</bitWidth>
            </field>
            <field>
              <name>DFSDM1EN</name>
              <bitOffset>30</bitOffset>
              <bitWidth>1</bitWidth>
            </field>
          </fields>
        </register>
        <register>
          <name>APB4ENR</name>
          <addressOffset>0xf4</addressOffset>
          <size>0x20</size>
          <fields>
            <field>
              <name>SYSCFGEN</name>
              <bitOffset>1</bitOffset>
              <bitWidth>1</bitWidth>
            </field>
            <field>
              <name>LPUART1EN</name>
              <bitOffset>3</bitOffset>
              <bitWidth>1</bitWidth>
            </field>
            <field>
              <name>SPI6EN</name>
              <bitOffset>5</bitOffset>
              <bitWidth>1</bitWidth>
            </field>
            <field>
              <name>I2C4EN</name>
              <bitOffset>7</bitOffset>
              <bitWidth>1</bitWidth>
            </field>
            <field>
              <name>LPTIM2EN</name>
              <bitOffset>9</bitOffset>
              <bitWidth>1</bitWidth>
            </field>
            <field>
              <name>LPTIM3EN</name>
              <bitOffset>10</bitOffset>
              <bitWidth>1</bitWidth>
            </field>
            <field>
              <name>LPTIM4EN</name>
              <bitOffset>11</bitOffset>
              <bitWidth>1</bitWidth>
            </field>
            <field>
              <name>LPTIM5EN</name>
              <bitOffset>12</bitOffset>
              <bitWidth>1</bitWidth>
            </field>
            <field>
              <name>COMP12EN</name>
              <bitOffset>14</bitOffset>
              <bitWidth>1</bitWidth>
            </field>
            <field>
              <name>VREFEN</name>
              <bitOffset>15</bitOffset>
              <bitWidth>1</bitWidth>
            </field>
            <field>
              <name>RTCAPBEN</name>
              <bitOffset>16</bitOffset>
              <bitWidth>1</bitWidth>
            </field>
            <field>
              <name>SAI4EN</name>
              <bitOffset>21</bitOffset>
              <bitWidth>1</bitWidth>
            </field>
            <field>
              <name>DTSEN</name>
              <bitOffset>26</bitOffset>
              <bitWidth>1</bitWidth>
            </field>
          </fields>
        </register>
        <register>
          <name>AHB3LPENR</name>
          <addressOffset>0xfc</addressOffset>
          <size>0x20</size>
          <fields>
            <field>
              <name>MDMALPEN</name>
              <bitOffset>0</bitOffset>
              <bitWidth>1</bitWidth>
            </field>
            <field>
              <name>DMA2DLPEN</name>
              <bitOffset>4</bitOffset>
              <bitWidth>1</bitWidth>
            </field>
            <field>
              <name>FLASHLPEN</name>
              <bitOffset>8</bitOffset>
              <bitWidth>1</bitWidth>
            </field>
            <field>
              <name>FMCLPEN</name>
              <bitOffset>12</bitOffset>
              <bitWidth>1</bitWidth>
            </field>
            <field>
              <name>OSPI1LPEN</name>
              <bitOffset>14</bitOffset>
              <bitWidth>1</bitWidth>
            </field>
            <field>
              <name>SDMMC1LPEN</name>
              <bitOffset>16</bitOffset>
              <bitWidth>1</bitWidth>
            </field>
            <field>
              <name>OSPI2LPEN</name>
              <bitOffset>19</bitOffset>
              <bitWidth>1</bitWidth>
            </field>
            <field>
              <name>IOMNGRLPEN</name>
              <bitOffset>21</bitOffset>
              <bitWidth>1</bitWidth>
            </field>
            <field>
              <name>DTCM1LPEN</name>
              <bitOffset>28</bitOffset>
              <bitWidth>1</bitWidth>
            </field>
            <field>
              <name>DTCM2LPEN</name>
              <bitOffset>29</bitOffset>
              <bitWidth>1</bitWidth>
            </field>
            <field>
              <name>ITCMLPEN</name>
              <bitOffset>30</bitOffset>
              <bitWidth>1</bitWidth>
            </field>
            <field>
              <name>AXISRAMLPEN</name>
              <bitOffset>31</bitOffset>
              <bitWidth>1</bitWidth>
            </field>
          </fields>
        </register>
        <register>
          <name>AHB1LPENR</name>
          <addressOffset>0x100</addressOffset>
          <size>0x20</size>
          <fields>
            <field>
              <name>DMA1LPEN</name>
              <bitOffset>0</bitOffset>
              <bitWidth>1</bitWidth>
            </field>
            <field>
              <name>DMA2LPEN</name>
              <bitOffset>1</bitOffset>
              <bitWidth>1</bitWidth>
            </field>
            <field>
              <name>ADC12LPEN</name>
              <bitOffset>5</bitOffset>
              <bitWidth>1</bitWidth>
            </field>
            <field>
              <name>ETH1MACLPEN</name>
              <bitOffset>15</bitOffset>
              <bitWidth>1</bitWidth>
            </field>
            <field>
              <name>ETH1TXLPEN</name>
              <bitOffset>16</bitOffset>
              <bitWidth>1</bitWidth>
            </field>
            <field>
              <name>ETH1RXLPEN</name>
              <bitOffset>17</bitOffset>
              <bitWidth>1</bitWidth>
            </field>
            <field>
              <name>USB1OTGHSLPEN</name>
              <bitOffset>25</bitOffset>
              <bitWidth>1</bitWidth>
            </field>
            <field>
              <name>USB1OTGHSULPILPEN</name>
              <bitOffset>26</bitOffset>
              <bitWidth>1</bitWidth>
            </field>
          </fields>
        </register>
        <register>
          <name>AHB2LPENR</name>
          <addressOffset>0x104</addressOffset>
          <size>0x20</size>
          <fields>
            <field>
              <name>DCMI_PSSILPEN</name>
              <bitOffset>0</bitOffset>
              <bitWidth>1</bitWidth>
            </field>
            <field>
              <name>RNGLPEN</name>
              <bitOffset>6</bitOffset>
              <bitWidth>1</bitWidth>
            </field>
            <field>
              <name>SDMMC2LPEN</name>
              <bitOffset>9</bitOffset>
              <bitWidth>1</bitWidth>
            </field>
            <field>
              <name>FMACLPEN</name>
              <bitOffset>16</bitOffset>
              <bitWidth>1</bitWidth>
            </field>
            <field>
              <name>CORDICLPEN</name>
              <bitOffset>17</bitOffset>
              <bitWidth>1</bitWidth>
            </field>
            <field>
              <name>SRAM1LPEN</name>
              <bitOffset>29</bitOffset>
              <bitWidth>1</bitWidth>
            </field>
            <field>
              <name>SRAM2LPEN</name>
              <bitOffset>30</bitOffset>
              <bitWidth>1</bitWidth>
            </field>
          </fields>
        </register>
        <register>
          <name>AHB4LPENR</name>
          <addressOffset>0x108</addressOffset>
          <size>0x20</size>
          <fields>
            <field>
              <name>GPIOALPEN</name>
              <bitOffset>0</bitOffset>
              <bitWidth>1</bitWidth>
            </field>
            <field>
              <name>GPIOBLPEN</name>
              <bitOffset>1</bitOffset>
              <bitWidth>1</bitWidth>
            </field>
            <field>
              <name>GPIOCLPEN</name>
              <bitOffset>2</bitOffset>
              <bitWidth>1</bitWidth>
            </field>
            <field>
              <name>GPIODLPEN</name>
              <bitOffset>3</bitOffset>
              <bitWidth>1</bitWidth>
            </field>
            <field>
              <name>GPIOELPEN</name>
              <bitOffset>4</bitOffset>
              <bitWidth>1</bitWidth>
            </field>
            <field>
              <name>GPIOFLPEN</name>
              <bitOffset>5</bitOffset>
              <bitWidth>1</bitWidth>
            </field>
            <field>
              <name>GPIOGLPEN</name>
              <bitOffset>6</bitOffset>
              <bitWidth>1</bitWidth>
            </field>
            <field>
              <name>GPIOHLPEN</name>
              <bitOffset>7</bitOffset>
              <bitWidth>1</bitWidth>
            </field>
            <field>
              <name>GPIOJLPEN</name>
              <bitOffset>9</bitOffset>
              <bitWidth>1</bitWidth>
            </field>
            <field>
              <name>GPIOKLPEN</name>
              <bitOffset>10</bitOffset>
              <bitWidth>1</bitWidth>
            </field>
            <field>
              <name>CRCLPEN</name>
              <bitOffset>19</bitOffset>
              <bitWidth>1</bitWidth>
            </field>
            <field>
              <name>BDMALPEN</name>
              <bitOffset>21</bitOffset>
              <bitWidth>1</bitWidth>
            </field>
            <field>
              <name>ADC3LPEN</name>
              <bitOffset>24</bitOffset>
              <bitWidth>1</bitWidth>
            </field>
            <field>
              <name>BKPRAMLPEN</name>
              <bitOffset>28</bitOffset>
              <bitWidth>1</bitWidth>
            </field>
            <field>
              <name>SRAM4LPEN</name>
              <bitOffset>29</bitOffset>
              <bitWidth>1</bitWidth>
            </field>
          </fields>
        </register>
        <register>
          <name>APB3LPENR</name>
          <addressOffset>0x10c</addressOffset>
          <size>0x20</size>
          <fields>
            <field>
              <name>LTDCLPEN</name>
              <bitOffset>3</bitOffset>
              <bitWidth>1</bitWidth>
            </field>
            <field>
              <name>WWDG1LPEN</name>
              <bitOffset>6</bitOffset>
              <bitWidth>1</bitWidth>
            </field>
          </fields>
        </register>
        <register>
          <name>APB1LLPENR</name>
          <addressOffset>0x110</addressOffset>
          <size>0x20</size>
          <fields>
            <field>
              <name>TIM2LPEN</name>
              <bitOffset>0</bitOffset>
              <bitWidth>1</bitWidth>
            </field>
            <field>
              <name>TIM3LPEN</name>
              <bitOffset>1</bitOffset>
              <bitWidth>1</bitWidth>
            </field>
            <field>
              <name>TIM4LPEN</name>
              <bitOffset>2</bitOffset>
              <bitWidth>1</bitWidth>
            </field>
            <field>
              <name>TIM5LPEN</name>
              <bitOffset>3</bitOffset>
              <bitWidth>1</bitWidth>
            </field>
            <field>
              <name>TIM6LPEN</name>
              <bitOffset>4</bitOffset>
              <bitWidth>1</bitWidth>
            </field>
            <field>
              <name>TIM7LPEN</name>
              <bitOffset>5</bitOffset>
              <bitWidth>1</bitWidth>
            </field>
            <field>
              <name>TIM12LPEN</name>
              <bitOffset>6</bitOffset>
              <bitWidth>1</bitWidth>
            </field>
            <field>
              <name>TIM13LPEN</name>
              <bitOffset>7</bitOffset>
              <bitWidth>1</bitWidth>
            </field>
            <field>
              <name>TIM14LPEN</name>
              <bitOffset>8</bitOffset>
              <bitWidth>1</bitWidth>
            </field>
            <field>
              <name>LPTIM1LPEN</name>
              <bitOffset>9</bitOffset>
              <bitWidth>1</bitWidth>
            </field>
            <field>
              <name>SPI2LPEN</name>
              <bitOffset>14</bitOffset>
              <bitWidth>1</bitWidth>
            </field>
            <field>
              <name>SPI3LPEN</name>
              <bitOffset>15</bitOffset>
              <bitWidth>1</bitWidth>
            </field>
            <field>
              <name>SPDIFRXLPEN</name>
              <bitOffset>16</bitOffset>
              <bitWidth>1</bitWidth>
            </field>
            <field>
              <name>USART2LPEN</name>
              <bitOffset>17</bitOffset>
              <bitWidth>1</bitWidth>
            </field>
            <field>
              <name>USART3LPEN</name>
              <bitOffset>18</bitOffset>
              <bitWidth>1</bitWidth>
            </field>
            <field>
              <name>UART4LPEN</name>
              <bitOffset>19</bitOffset>
              <bitWidth>1</bitWidth>
            </field>
            <field>
              <name>UART5LPEN</name>
              <bitOffset>20</bitOffset>
              <bitWidth>1</bitWidth>
            </field>
            <field>
              <name>I2C1LPEN</name>
              <bitOffset>21</bitOffset>
              <bitWidth>1</bitWidth>
            </field>
            <field>
              <name>I2C2LPEN</name>
              <bitOffset>22</bitOffset>
              <bitWidth>1</bitWidth>
            </field>
            <field>
              <name>I2C3LPEN</name>
              <bitOffset>23</bitOffset>
              <bitWidth>1</bitWidth>
            </field>
            <field>
              <name>I2C5LPEN</name>
              <bitOffset>25</bitOffset>
              <bitWidth>1</bitWidth>
            </field>
            <field>
              <name>HDMICECEN</name>
              <bitOffset>27</bitOffset>
              <bitWidth>1</bitWidth>
            </field>
            <field>
              <name>DAC12LPEN</name>
              <bitOffset>29</bitOffset>
              <bitWidth>1</bitWidth>
            </field>
            <field>
              <name>UART7LPEN</name>
              <bitOffset>30</bitOffset>
              <bitWidth>1</bitWidth>
            </field>
            <field>
              <name>UART8LPEN</name>
              <bitOffset>31</bitOffset>
              <bitWidth>1</bitWidth>
            </field>
          </fields>
        </register>
        <register>
          <name>APB1HLPENR</name>
          <addressOffset>0x114</addressOffset>
          <size>0x20</size>
          <fields>
            <field>
              <name>CRSLPEN</name>
              <bitOffset>1</bitOffset>
              <bitWidth>1</bitWidth>
            </field>
            <field>
              <name>SWPMILPEN</name>
              <bitOffset>2</bitOffset>
              <bitWidth>1</bitWidth>
            </field>
            <field>
              <name>OPAMPLPEN</name>
              <bitOffset>4</bitOffset>
              <bitWidth>1</bitWidth>
            </field>
            <field>
              <name>MDIOSLPEN</name>
              <bitOffset>5</bitOffset>
              <bitWidth>1</bitWidth>
            </field>
            <field>
              <name>FDCANLPEN</name>
              <bitOffset>8</bitOffset>
              <bitWidth>1</bitWidth>
            </field>
            <field>
              <name>TIM23LPEN</name>
              <bitOffset>24</bitOffset>
              <bitWidth>1</bitWidth>
            </field>
            <field>
              <name>TIM24LPEN</name>
              <bitOffset>25</bitOffset>
              <bitWidth>1</bitWidth>
            </field>
          </fields>
        </register>
        <register>
          <name>APB2LPENR</name>
          <addressOffset>0x118</addressOffset>
          <size>0x20</size>
          <fields>
            <field>
              <name>TIM1LPEN</name>
              <bitOffset>0</bitOffset>
              <bitWidth>1</bitWidth>
            </field>
            <field>
              <name>TIM8LPEN</name>
              <bitOffset>1</bitOffset>
              <bitWidth>1</bitWidth>
            </field>
            <field>
              <name>USART1LPEN</name>
              <bitOffset>4</bitOffset>
              <bitWidth>1</bitWidth>
            </field>
            <field>
              <name>USART6LPEN</name>
              <bitOffset>5</bitOffset>
              <bitWidth>1</bitWidth>
            </field>
            <field>
              <name>UART9LPEN</name>
              <bitOffset>6</bitOffset>
              <bitWidth>1</bitWidth>
            </field>
            <field>
              <name>USART10LPEN</name>
              <bitOffset>7</bitOffset>
              <bitWidth>1</bitWidth>
            </field>
            <field>
              <name>SPI1LPEN</name>
              <bitOffset>12</bitOffset>
              <bitWidth>1</bitWidth>
            </field>
            <field>
              <name>SPI4LPEN</name>
              <bitOffset>13</bitOffset>
              <bitWidth>1</bitWidth>
            </field>
            <field>
              <name>TIM15LPEN</name>
              <bitOffset>16</bitOffset>
              <bitWidth>1</bitWidth>
            </field>
            <field>
              <name>TIM16LPEN</name>
              <bitOffset>17</bitOffset>
              <bitWidth>1</bitWidth>
            </field>
            <field>
              <name>TIM17LPEN</name>
              <bitOffset>18</bitOffset>
              <bitWidth>1</bitWidth>
            </field>
            <field>
              <name>SPI5LPEN</name>
              <bitOffset>20</bitOffset>
              <bitWidth>1</bitWidth>
            </field>
            <field>
              <name>SAI1LPEN</name>
              <bitOffset>22</bitOffset>
              <bitWidth>1</bitWidth>
            </field>
            <field>
              <name>DFSDM1LPEN</name>
              <bitOffset>30</bitOffset>
              <bitWidth>1</bitWidth>
            </field>
          </fields>
        </register>
        <register>
          <name>APB4LPENR</name>
          <addressOffset>0x11c</addressOffset>
          <size>0x20</size>
          <fields>
            <field>
              <name>SYSCFGLPEN</name>
              <bitOffset>1</bitOffset>
              <bitWidth>1</bitWidth>
            </field>
            <field>
              <name>LPUART1LPEN</name>
              <bitOffset>3</bitOffset>
              <bitWidth>1</bitWidth>
            </field>
            <field>
              <name>SPI6LPEN</name>
              <bitOffset>5</bitOffset>
              <bitWidth>1</bitWidth>
            </field>
            <field>
              <name>I2C4LPEN</name>
              <bitOffset>7</bitOffset>
              <bitWidth>1</bitWidth>
            </field>
            <field>
              <name>LPTIM2LPEN</name>
              <bitOffset>9</bitOffset>
              <bitWidth>1</bitWidth>
            </field>
            <field>
              <name>LPTIM3LPEN</name>
              <bitOffset>10</bitOffset>
              <bitWidth>1</bitWidth>
            </field>
            <field>
              <name>LPTIM4LPEN</name>
              <bitOffset>11</bitOffset>
              <bitWidth>1</bitWidth>
            </field>
            <field>
              <name>LPTIM5LPEN</name>
              <bitOffset>12</bitOffset>
              <bitWidth>1</bitWidth>
            </field>
            <field>
              <name>COMP12LPEN</name>
              <bitOffset>14</bitOffset>
              <bitWidth>1</bitWidth>
            </field>
            <field>
              <name>VREFLPEN</name>
              <bitOffset>15</bitOffset>
              <bitWidth>1</bitWidth>
            </field>
            <field>
              <name>RTCAPBLPEN</name>
              <bitOffset>16</bitOffset>
              <bitWidth>1</bitWidth>
            </field>
            <field>
              <name>SAI4LPEN</name>
              <bitOffset>21</bitOffset>
              <bitWidth>1</bitWidth>
            </field>
            <field>
              <name>DTSLPEN</name>
              <bitOffset>26</bitOffset>
              <bitWidth>1</bitWidth>
            </field>
          </fields>
        </register>
      </registers>
    </peripheral>
    <peripheral>
      <name>PWR</name>
      <baseAddress>0x58024800</baseAddress>
      <registers>
        <register>
          <name>CR1</name>
          <addressOffset>0x0</addressOffset>
          <size>0x20</size>
          <fields>
            <field>
              <name>LPDS</name>
              <bitOffset>0</bitOffset>
              <bitWidth>1</bitWidth>
            </field>
            <field>
              <name>PVDEN</name>
              <bitOffset>4</bitOffset>
              <bitWidth>1</bitWidth>
            </field>
            <field>
              <name>PLS_LEV7</name>
              <bitOffset>5</bitOffset>
              <bitWidth>3</bitWidth>
            </field>
            <field>
              <name>PLS_LEV6</name>
              <bitOffset>6</bitOffset>
              <bitWidth>2</bitWidth>
            </field>
            <field>
              <name>PLS_LEV4</name>
              <bitOffset>7</bitOffset>
              <bitWidth>1</bitWidth>
            </field>
            <field>
              <name>DBP</name>
              <bitOffset>8</bitOffset>
              <bitWidth>1</bitWidth>
            </field>
            <field>
              <name>FLPS</name>
              <bitOffset>9</bitOffset>
              <bitWidth>1</bitWidth>
            </field>
            <field>
              <name>SVOS</name>
              <bitOffset>14</bitOffset>
              <bitWidth>2</bitWidth>
            </field>
            <field>
              <name>AVDEN</name>
              <bitOffset>16</bitOffset>
              <bitWidth>1</bitWidth>
            </field>
            <field>
              <name>ALS_LEV3</name>
              <bitOffset>17</bitOffset>
              <bitWidth>2</bitWidth>
            </field>
            <field>
              <name>ALS_LEV2</name>
              <bitOffset>18</bitOffset>
              <bitWidth>1</bitWidth>
            </field>
          </fields>
        </register>
        <register>
          <name>CSR1</name>
          <addressOffset>0x4</addressOffset>
          <size>0x20</size>
          <fields>
            <field>
              <name>PVDO</name>
              <bitOffset>4</bitOffset>
              <bitWidth>1</bitWidth>
            </field>
            <field>
              <name>ACTVOSRDY</name>
              <bitOffset>13</bitOffset>
              <bitWidth>1</bitWidth>
            </field>
            <field>
              <name>ACTVOS</name>
              <bitOffset>14</bitOffset>
              <bitWidth>2</bitWidth>
            </field>
            <field>
              <name>AVDO</name>
              <bitOffset>16</bitOffset>
              <bitWidth>1</bitWidth>
            </field>
          </fields>
        </register>
        <register>
          <name>CR2</name>
          <addressOffset>0x8</addressOffset>
          <size>0x20</size>
          <fields>
            <field>
              <name>BREN</name>
              <bitOffset>0</bitOffset>
              <bitWidth>1</bitWidth>
            </field>
            <field>
              <name>MONEN</name>
              <bitOffset>4</bitOffset>
              <bitWidth>1</bitWidth>
            </field>
            <field>
              <name>BRRDY</name>
              <bitOffset>16</bitOffset>
              <bitWidth>1</bitWidth>
            </field>
            <field>
              <name>VBATL</name>
              <bitOffset>20</bitOffset>
              <bitWidth>1</bitWidth>
            </field>
            <field>
              <name>VBATH</name>
              <bitOffset>21</bitOffset>
              <bitWidth>1</bitWidth>
            </field>
            <field>
              <name>TEMPL</name>
              <bitOffset>22</bitOffset>
              <bitWidth>1</bitWidth>
            </field>
            <field>
              <name>TEMPH</name>
              <bitOffset>23</bitOffset>
              <bitWidth>1</bitWidth>
            </field>
          </fields>
        </register>
        <register>
          <name>CR3</name>
          <addressOffset>0xc</addressOffset>
          <size>0x20</size>
          <fields>
            <field>
              <name>BYPASS</name>
              <bitOffset>0</bitOffset>
              <bitWidth>1</bitWidth>
            </field>
            <field>
              <name>LDOEN</name>
              <bitOffset>1</bitOffset>
              <bitWidth>1</bitWidth>
            </field>
            <field>
              <name>SCUEN</name>
              <bitOffset>2</bitOffset>
              <bitWidth>1</bitWidth>
            </field>
            <field>
              <name>VBE</name>
              <bitOffset>8</bitOffset>
              <bitWidth>1</bitWidth>
            </field>
            <field>
              <name>VBRS</name>
              <bitOffset>9</bitOffset>
              <bitWidth>1</bitWidth>
            </field>
            <field>
              <name>USB33DEN</name>
              <bitOffset>24</bitOffset>
              <bitWidth>1</bitWidth>
            </field>
            <field>
              <name>USBREGEN</name>
              <bitOffset>25</bitOffset>
              <bitWidth>1</bitWidth>
            </field>
            <field>
              <name>USB33RDY</name>
              <bitOffset>26</bitOffset>
              <bitWidth>1</bitWidth>
            </field>
          </fields>
        </register>
        <register>
          <name>CPUCR</name>
          <addressOffset>0x10</addressOffset>
          <size>0x20</size>
          <fields>
            <field>
              <name>PDDS_D1</name>
              <bitOffset>0</bitOffset>
              <bitWidth>1</bitWidth>
            </field>
            <field>
              <name>PDDS_D2</name>
              <bitOffset>1</bitOffset>
              <bitWidth>1</bitWidth>
            </field>
            <field>
              <name>PDDS_D3</name>
              <bitOffset>2</bitOffset>
              <bitWidth>1</bitWidth>
            </field>
            <field>
              <name>STOPF</name>
              <bitOffset>5</bitOffset>
              <bitWidth>1</bitWidth>
            </field>
            <field>
              <name>SBF</name>
              <bitOffset>6</bitOffset>
              <bitWidth>1</bitWidth>
            </field>
            <field>
              <name>SBF_D1</name>
              <bitOffset>7</bitOffset>
              <bitWidth>1</bitWidth>
            </field>
            <field>
              <name>SBF_D2</name>
              <bitOffset>8</bitOffset>
              <bitWidth>1</bitWidth>
            </field>
            <field>
              <name>CSSF</name>
              <bitOffset>9</bitOffset>
              <bitWidth>1</bitWidth>
            </field>
            <field>
              <name>RUN_D3</name>
              <bitOffset>11</bitOffset>
              <bitWidth>1</bitWidth>
            </field>
          </fields>
        </register>
        <register>
          <name>D3CR</name>
          <addressOffset>0x18</addressOffset>
          <size>0x20</size>
          <fields>
            <field>
              <name>VOSRDY</name>
              <bitOffset>13</bitOffset>
              <bitWidth>1</bitWidth>
            </field>
            <field>
              <name>VOS</name>
              <bitOffset>14</bitOffset>
              <bitWidth>2</bitWidth>
            </field>
          </fields>
        </register>
        <register>
          <name>WKUPCR</name>
          <addressOffset>0x20</addressOffset>
          <size>0x20</size>
          <fields>
            <field>
              <name>WKUPC1</name>
              <bitOffset>0</bitOffset>
              <bitWidth>1</bitWidth>
            </field>
            <field>
              <name>WKUPC2</name>
              <bitOffset>1</bitOffset>
              <bitWidth>1</bitWidth>
            </field>
            <field>
              <name>WKUPC4</name>
              <bitOffset>3</bitOffset>
              <bitWidth>1</bitWidth>
            </field>
            <field>
              <name>WKUPC6</name>
              <bitOffset>5</bitOffset>
              <bitWidth>1</bitWidth>
            </field>
          </fields>
        </register>
        <register>
          <name>WKUPFR</name>
          <addressOffset>0x24</addressOffset>
          <size>0x20</size>
          <fields>
            <field>
              <name>WKUPF1</name>
              <bitOffset>0</bitOffset>
              <bitWidth>1</bitWidth>
            </field>
            <field>
              <name>WKUPF2</name>
              <bitOffset>1</bitOffset>
              <bitWidth>1</bitWidth>
            </field>
            <field>
              <name>WKUPF4</name>
              <bitOffset>3</bitOffset>
              <bitWidth>1</bitWidth>
            </field>
            <field>
              <name>WKUPF6</name>
              <bitOffset>5</bitOffset>
              <bitWidth>1</bitWidth>
            </field>
          </fields>
        </register>
        <register>
          <name>WKUPEPR</name>
          <addressOffset>0x28</addressOffset>
          <size>0x20</size>
          <fields>
            <field>
              <name>WKUPEN1</name>
              <bitOffset>0</bitOffset>
              <bitWidth>1</bitWidth>
            </field>
            <field>
              <name>WKUPEN2</name>
              <bitOffset>1</bitOffset>
              <bitWidth>1</bitWidth>
            </field>
            <field>
              <name>WKUPEN4</name>
              <bitOffset>3</bitOffset>
              <bitWidth>1</bitWidth>
            </field>
            <field>
              <name>WKUPEN6</name>
              <bitOffset>5</bitOffset>
              <bitWidth>1</bitWidth>
            </field>
            <field>
              <name>WKUPP1</name>
              <bitOffset>8</bitOffset>
              <bitWidth>1</bitWidth>
            </field>
            <field>
              <name>WKUPP2</name>
              <bitOffset>9</bitOffset>
              <bitWidth>1</bitWidth>
            </field>
            <field>
              <name>WKUPP4</name>
              <bitOffset>11</bitOffset>
              <bitWidth>1</bitWidth>
            </field>
            <field>
              <name>WKUPP6</name>
              <bitOffset>13</bitOffset>
              <bitWidth>1</bitWidth>
            </field>
            <field>
              <name>WKUPPUPD1</name>
              <bitOffset>16</bitOffset>
              <bitWidth>2</bitWidth>
            </field>
            <field>
              <name>WKUPPUPD2</name>
              <bitOffset>18</bitOffset>
              <bitWidth>2</bitWidth>
            </field>
            <field>
              <name>WKUPPUPD4</name>
              <bitOffset>22</bitOffset>
              <bitWidth>2</bitWidth>
            </field>
            <field>
              <name>WKUPPUPD6</name>
              <bitOffset>26</bitOffset>
              <bitWidth>2</bitWidth>
            </field>
          </fields>
        </register>
      </registers>
    </peripheral>
    <peripheral>
      <name>CRC</name>
      <baseAddress>0x58024c00</baseAddress>
      <registers>
        <register>
          <name>DR</name>
          <addressOffset>0x0</addressOffset>
          <size>0x20</size>
          <fields>
            <field>
              <name>DR</name>
              <bitOffset>0</bitOffset>
              <bitWidth>32</bitWidth>
            </field>
          </fields>
        </register>
        <register>
          <name>IDR</name>
          <addressOffset>0x4</addressOffset>
          <size>0x20</size>
          <fields>
            <field>
              <name>IDR</name>
              <bitOffset>0</bitOffset>
              <bitWidth>32</bitWidth>
            </field>
          </fields>
        </register>
        <register>
          <name>CR</name>
          <addressOffset>0x8</addressOffset>
          <size>0x20</size>
          <fields>
            <field>
              <name>RESET</name>
              <bitOffset>0</bitOffset>
              <bitWidth>1</bitWidth>
            </field>
            <field>
              <name>POLYSIZE</name>
              <bitOffset>3</bitOffset>
              <bitWidth>2</bitWidth>
            </field>
            <field>
              <name>REV_IN</name>
              <bitOffset>5</bitOffset>
              <bitWidth>2</bitWidth>
            </field>
            <field>
              <name>REV_OUT</name>
              <bitOffset>7</bitOffset>
              <bitWidth>1</bitWidth>
            </field>
          </fields>
        </register>
        <register>
          <name>INIT</name>
          <addressOffset>0x10</addressOffset>
          <size>0x20</size>
          <fields>
            <field>
              <name>INIT</name>
              <bitOffset>0</bitOffset>
              <bitWidth>32</bitWidth>
            </field>
          </fields>
        </register>
        <register>
          <name>POL</name>
          <addressOffset>0x14</addressOffset>
          <size>0x20</size>
          <fields>
            <field>
              <name>POL</name>
              <bitOffset>0</bitOffset>
              <bitWidth>32</bitWidth>
            </field>
          </fields>
        </register>
      </registers>
    </peripheral>
    <peripheral>
      <name>BDMA</name>
      <baseAddress>0x58025400</baseAddress>
      <registers>
        <register>
          <name>ISR</name>
          <addressOffset>0x0</addressOffset>
          <size>0x20</size>
          <fields>
            <field>
              <name>GIF0</name>
              <bitOffset>0</bitOffset>
              <bitWidth>1</bitWidth>
            </field>
            <field>
              <name>TCIF0</name>
              <bitOffset>1</bitOffset>
              <bitWidth>1</bitWidth>
            </field>
            <field>
              <name>HTIF0</name>
              <bitOffset>2</bitOffset>
              <bitWidth>1</bitWidth>
            </field>
            <field>
              <name>TEIF0</name>
              <bitOffset>3</bitOffset>
              <bitWidth>1</bitWidth>
            </field>
            <field>
              <name>GIF1</name>
              <bitOffset>4</bitOffset>
              <bitWidth>1</bitWidth>
            </field>
            <field>
              <name>TCIF1</name>
              <bitOffset>5</bitOffset>
              <bitWidth>1</bitWidth>
            </field>
            <field>
              <name>HTIF1</name>
              <bitOffset>6</bitOffset>
              <bitWidth>1</bitWidth>
            </field>
            <field>
              <name>TEIF1</name>
              <bitOffset>7</bitOffset>
              <bitWidth>1</bitWidth>
            </field>
            <field>
              <name>GIF2</name>
              <bitOffset>8</bitOffset>
              <bitWidth>1</bitWidth>
            </field>
            <field>
              <name>TCIF2</name>
              <bitOffset>9</bitOffset>
              <bitWidth>1</bitWidth>
            </field>
            <field>
              <name>HTIF2</name>
              <bitOffset>10</bitOffset>
              <bitWidth>1</bitWidth>
            </field>
            <field>
              <name>TEIF2</name>
              <bitOffset>11</bitOffset>
              <bitWidth>1</bitWidth>
            </field>
            <field>
              <name>GIF3</name>
              <bitOffset>12</bitOffset>
              <bitWidth>1</bitWidth>
            </field>
            <field>
              <name>TCIF3</name>
              <bitOffset>13</bitOffset>
              <bitWidth>1</bitWidth>
            </field>
            <field>
              <name>HTIF3</name>
              <bitOffset>14</bitOffset>
              <bitWidth>1</bitWidth>
            </field>
            <field>
              <name>TEIF3</name>
              <bitOffset>15</bitOffset>
              <bitWidth>1</bitWidth>
            </field>
            <field>
              <name>GIF4</name>
              <bitOffset>16</bitOffset>
              <bitWidth>1</bitWidth>
            </field>
            <field>
              <name>TCIF4</name>
              <bitOffset>17</bitOffset>
              <bitWidth>1</bitWidth>
            </field>
            <field>
              <name>HTIF4</name>
              <bitOffset>18</bitOffset>
              <bitWidth>1</bitWidth>
            </field>
            <field>
              <name>TEIF4</name>
              <bitOffset>19</bitOffset>
              <bitWidth>1</bitWidth>
            </field>
            <field>
              <name>GIF5</name>
              <bitOffset>20</bitOffset>
              <bitWidth>1</bitWidth>
            </field>
            <field>
              <name>TCIF5</name>
              <bitOffset>21</bitOffset>
              <bitWidth>1</bitWidth>
            </field>
            <field>
              <name>HTIF5</name>
              <bitOffset>22</bitOffset>
              <bitWidth>1</bitWidth>
            </field>
            <field>
              <name>TEIF5</name>
              <bitOffset>23</bitOffset>
              <bitWidth>1</bitWidth>
            </field>
            <field>
              <name>GIF6</name>
              <bitOffset>24</bitOffset>
              <bitWidth>1</bitWidth>
            </field>
            <field>
              <name>TCIF6</name>
              <bitOffset>25</bitOffset>
              <bitWidth>1</bitWidth>
            </field>
            <field>
              <name>HTIF6</name>
              <bitOffset>26</bitOffset>
              <bitWidth>1</bitWidth>
            </field>
            <field>
              <name>TEIF6</name>
              <bitOffset>27</bitOffset>
              <bitWidth>1</bitWidth>
            </field>
            <field>
              <name>GIF7</name>
              <bitOffset>28</bitOffset>
              <bitWidth>1</bitWidth>
            </field>
            <field>
              <name>TCIF7</name>
              <bitOffset>29</bitOffset>
              <bitWidth>1</bitWidth>
            </field>
            <field>
              <name>HTIF7</name>
              <bitOffset>30</bitOffset>
              <bitWidth>1</bitWidth>
            </field>
            <field>
              <name>TEIF7</name>
              <bitOffset>31</bitOffset>
              <bitWidth>1</bitWidth>
            </field>
          </fields>
        </register>
        <register>
          <name>IFCR</name>
          <addressOffset>0x4</addressOffset>
          <size>0x20</size>
          <fields>
            <field>
              <name>CGIF0</name>
              <bitOffset>0</bitOffset>
              <bitWidth>1</bitWidth>
            </field>
            <field>
              <name>CTCIF0</name>
              <bitOffset>1</bitOffset>
              <bitWidth>1</bitWidth>
            </field>
            <field>
              <name>CHTIF0</name>
              <bitOffset>2</bitOffset>
              <bitWidth>1</bitWidth>
            </field>
            <field>
              <name>CTEIF0</name>
              <bitOffset>3</bitOffset>
              <bitWidth>1</bitWidth>
            </field>
            <field>
              <name>CGIF1</name>
              <bitOffset>4</bitOffset>
              <bitWidth>1</bitWidth>
            </field>
            <field>
              <name>CTCIF1</name>
              <bitOffset>5</bitOffset>
              <bitWidth>1</bitWidth>
            </field>
            <field>
              <name>CHTIF1</name>
              <bitOffset>6</bitOffset>
              <bitWidth>1</bitWidth>
            </field>
            <field>
              <name>CTEIF1</name>
              <bitOffset>7</bitOffset>
              <bitWidth>1</bitWidth>
            </field>
            <field>
              <name>CGIF2</name>
              <bitOffset>8</bitOffset>
              <bitWidth>1</bitWidth>
            </field>
            <field>
              <name>CTCIF2</name>
              <bitOffset>9</bitOffset>
              <bitWidth>1</bitWidth>
            </field>
            <field>
              <name>CHTIF2</name>
              <bitOffset>10</bitOffset>
              <bitWidth>1</bitWidth>
            </field>
            <field>
              <name>CTEIF2</name>
              <bitOffset>11</bitOffset>
              <bitWidth>1</bitWidth>
            </field>
            <field>
              <name>CGIF3</name>
              <bitOffset>12</bitOffset>
              <bitWidth>1</bitWidth>
            </field>
            <field>
              <name>CTCIF3</name>
              <bitOffset>13</bitOffset>
              <bitWidth>1</bitWidth>
            </field>
            <field>
              <name>CHTIF3</name>
              <bitOffset>14</bitOffset>
              <bitWidth>1</bitWidth>
            </field>
            <field>
              <name>CTEIF3</name>
              <bitOffset>15</bitOffset>
              <bitWidth>1</bitWidth>
            </field>
            <field>
              <name>CGIF4</name>
              <bitOffset>16</bitOffset>
              <bitWidth>1</bitWidth>
            </field>
            <field>
              <name>CTCIF4</name>
              <bitOffset>17</bitOffset>
              <bitWidth>1</bitWidth>
            </field>
            <field>
              <name>CHTIF4</name>
              <bitOffset>18</bitOffset>
              <bitWidth>1</bitWidth>
            </field>
            <field>
              <name>CTEIF4</name>
              <bitOffset>19</bitOffset>
              <bitWidth>1</bitWidth>
            </field>
            <field>
              <name>CGIF5</name>
              <bitOffset>20</bitOffset>
              <bitWidth>1</bitWidth>
            </field>
            <field>
              <name>CTCIF5</name>
              <bitOffset>21</bitOffset>
              <bitWidth>1</bitWidth>
            </field>
            <field>
              <name>CHTIF5</name>
              <bitOffset>22</bitOffset>
              <bitWidth>1</bitWidth>
            </field>
            <field>
              <name>CTEIF5</name>
              <bitOffset>23</bitOffset>
              <bitWidth>1</bitWidth>
            </field>
            <field>
              <name>CGIF6</name>
              <bitOffset>24</bitOffset>
              <bitWidth>1</bitWidth>
            </field>
            <field>
              <name>CTCIF6</name>
              <bitOffset>25</bitOffset>
              <bitWidth>1</bitWidth>
            </field>
            <field>
              <name>CHTIF6</name>
              <bitOffset>26</bitOffset>
              <bitWidth>1</bitWidth>
            </field>
            <field>
              <name>CTEIF6</name>
              <bitOffset>27</bitOffset>
              <bitWidth>1</bitWidth>
            </field>
            <field>
              <name>CGIF7</name>
              <bitOffset>28</bitOffset>
              <bitWidth>1</bitWidth>
            </field>
            <field>
              <name>CTCIF7</name>
              <bitOffset>29</bitOffset>
              <bitWidth>1</bitWidth>
            </field>
            <field>
              <name>CHTIF7</name>
              <bitOffset>30</bitOffset>
              <bitWidth>1</bitWidth>
            </field>
            <field>
              <name>CTEIF7</name>
              <bitOffset>31</bitOffset>
              <bitWidth>1</bitWidth>
            </field>
          </fields>
        </register>
        <register>
          <name>CCR0</name>
          <addressOffset>0x8</addressOffset>
          <size>0x20</size>
          <fields>
            <field>
              <name>EN</name>
              <bitOffset>0</bitOffset>
              <bitWidth>1</bitWidth>
            </field>
            <field>
              <name>TCIE</name>
              <bitOffset>1</bitOffset>
              <bitWidth>1</bitWidth>
            </field>
            <field>
              <name>HTIE</name>
              <bitOffset>2</bitOffset>
              <bitWidth>1</bitWidth>
            </field>
            <field>
              <name>TEIE</name>
              <bitOffset>3</bitOffset>
              <bitWidth>1</bitWidth>
            </field>
            <field>
              <name>DIR</name>
              <bitOffset>4</bitOffset>
              <bitWidth>1</bitWidth>
            </field>
            <field>
              <name>CIRC</name>
              <bitOffset>5</bitOffset>
              <bitWidth>1</bitWidth>
            </field>
            <field>
              <name>PINC</name>
              <bitOffset>6</bitOffset>
              <bitWidth>1</bitWidth>
            </field>
            <field>
              <name>MINC</name>
              <bitOffset>7</bitOffset>
              <bitWidth>1</bitWidth>
            </field>
            <field>
              <name>PSIZE</name>
              <bitOffset>8</bitOffset>
              <bitWidth>2</bitWidth>
            </field>
            <field>
              <name>MSIZE</name>
              <bitOffset>10</bitOffset>
              <bitWidth>2</bitWidth>
            </field>
            <field>
              <name>PL</name>
              <bitOffset>12</bitOffset>
              <bitWidth>2</bitWidth>
            </field>
            <field>
              <name>MEM2MEM</name>
              <bitOffset>14</bitOffset>
              <bitWidth>1</bitWidth>
            </field>
            <field>
              <name>DBM</name>
              <bitOffset>15</bitOffset>
              <bitWidth>1</bitWidth>
            </field>
            <field>
              <name>CT</name>
              <bitOffset>16</bitOffset>
              <bitWidth>1</bitWidth>
            </field>
          </fields>
        </register>
        <register>
          <name>CNDTR0</name>
          <addressOffset>0xc</addressOffset>
          <size>0x20</size>
          <fields>
            <field>
              <name>NDT</name>
              <bitOffset>0</bitOffset>
              <bitWidth>16</bitWidth>
            </field>
          </fields>
        </register>
        <register>
          <name>CPAR0</name>
          <addressOffset>0x10</addressOffset>
          <size>0x20</size>
          <fields>
            <field>
              <name>PA</name>
              <bitOffset>0</bitOffset>
              <bitWidth>32</bitWidth>
            </field>
          </fields>
        </register>
        <register>
          <name>CM0AR0</name>
          <addressOffset>0x14</addressOffset>
          <size>0x20</size>
          <fields>
            <field>
              <name>MA</name>
              <bitOffset>0</bitOffset>
              <bitWidth>32</bitWidth>
            </field>
          </fields>
        </register>
        <register>
          <name>CM1AR0</name>
          <addressOffset>0x18</addressOffset>
          <size>0x20</size>
          <fields>
            <field>
              <name>MA</name>
              <bitOffset>0</bitOffset>
              <bitWidth>32</bitWidth>
            </field>
          </fields>
        </register>
        <register>
          <name>CCR1</name>
          <addressOffset>0x1c</addressOffset>
          <size>0x20</size>
          <fields>
            <field>
              <name>EN</name>
              <bitOffset>0</bitOffset>
              <bitWidth>1</bitWidth>
            </field>
            <field>
              <name>TCIE</name>
              <bitOffset>1</bitOffset>
              <bitWidth>1</bitWidth>
            </field>
            <field>
              <name>HTIE</name>
              <bitOffset>2</bitOffset>
              <bitWidth>1</bitWidth>
            </field>
            <field>
              <name>TEIE</name>
              <bitOffset>3</bitOffset>
              <bitWidth>1</bitWidth>
            </field>
            <field>
              <name>DIR</name>
              <bitOffset>4</bitOffset>
              <bitWidth>1</bitWidth>
            </field>
            <field>
              <name>CIRC</name>
              <bitOffset>5</bitOffset>
              <bitWidth>1</bitWidth>
            </field>
            <field>
              <name>PINC</name>
              <bitOffset>6</bitOffset>
              <bitWidth>1</bitWidth>
            </field>
            <field>
              <name>MINC</name>
              <bitOffset>7</bitOffset>
              <bitWidth>1</bitWidth>
            </field>
            <field>
              <name>PSIZE</name>
              <bitOffset>8</bitOffset>
              <bitWidth>2</bitWidth>
            </field>
            <field>
              <name>MSIZE</name>
              <bitOffset>10</bitOffset>
              <bitWidth>2</bitWidth>
            </field>
            <field>
              <name>PL</name>
              <bitOffset>12</bitOffset>
              <bitWidth>2</bitWidth>
            </field>
            <field>
              <name>MEM2MEM</name>
              <bitOffset>14</bitOffset>
              <bitWidth>1</bitWidth>
            </field>
            <field>
              <name>DBM</name>
              <bitOffset>15</bitOffset>
              <bitWidth>1</bitWidth>
            </field>
            <field>
              <name>CT</name>
              <bitOffset>16</bitOffset>
              <bitWidth>1</bitWidth>
            </field>
          </fields>
        </register>
        <register>
          <name>CNDTR1</name>
          <addressOffset>0x20</addressOffset>
          <size>0x20</size>
          <fields>
            <field>
              <name>NDT</name>
              <bitOffset>0</bitOffset>
              <bitWidth>16</bitWidth>
            </field>
          </fields>
        </register>
        <register>
          <name>CPAR1</name>
          <addressOffset>0x24</addressOffset>
          <size>0x20</size>
          <fields>
            <field>
              <name>PA</name>
              <bitOffset>0</bitOffset>
              <bitWidth>32</bitWidth>
            </field>
          </fields>
        </register>
        <register>
          <name>CM0AR1</name>
          <addressOffset>0x28</addressOffset>
          <size>0x20</size>
          <fields>
            <field>
              <name>MA</name>
              <bitOffset>0</bitOffset>
              <bitWidth>32</bitWidth>
            </field>
          </fields>
        </register>
        <register>
          <name>CM1AR1</name>
          <addressOffset>0x2c</addressOffset>
          <size>0x20</size>
          <fields>
            <field>
              <name>MA</name>
              <bitOffset>0</bitOffset>
              <bitWidth>32</bitWidth>
            </field>
          </fields>
        </register>
        <register>
          <name>CCR2</name>
          <addressOffset>0x30</addressOffset>
          <size>0x20</size>
          <fields>
            <field>
              <name>EN</name>
              <bitOffset>0</bitOffset>
              <bitWidth>1</bitWidth>
            </field>
            <field>
              <name>TCIE</name>
              <bitOffset>1</bitOffset>
              <bitWidth>1</bitWidth>
            </field>
            <field>
              <name>HTIE</name>
              <bitOffset>2</bitOffset>
              <bitWidth>1</bitWidth>
            </field>
            <field>
              <name>TEIE</name>
              <bitOffset>3</bitOffset>
              <bitWidth>1</bitWidth>
            </field>
            <field>
              <name>DIR</name>
              <bitOffset>4</bitOffset>
              <bitWidth>1</bitWidth>
            </field>
            <field>
              <name>CIRC</name>
              <bitOffset>5</bitOffset>
              <bitWidth>1</bitWidth>
            </field>
            <field>
              <name>PINC</name>
              <bitOffset>6</bitOffset>
              <bitWidth>1</bitWidth>
            </field>
            <field>
              <name>MINC</name>
              <bitOffset>7</bitOffset>
              <bitWidth>1</bitWidth>
            </field>
            <field>
              <name>PSIZE</name>
              <bitOffset>8</bitOffset>
              <bitWidth>2</bitWidth>
            </field>
            <field>
              <name>MSIZE</name>
              <bitOffset>10</bitOffset>
              <bitWidth>2</bitWidth>
            </field>
            <field>
              <name>PL</name>
              <bitOffset>12</bitOffset>
              <bitWidth>2</bitWidth>
            </field>
            <field>
              <name>MEM2MEM</name>
              <bitOffset>14</bitOffset>
              <bitWidth>1</bitWidth>
            </field>
            <field>
              <name>DBM</name>
              <bitOffset>15</bitOffset>
              <bitWidth>1</bitWidth>
            </field>
            <field>
              <name>CT</name>
              <bitOffset>16</bitOffset>
              <bitWidth>1</bitWidth>
            </field>
          </fields>
        </register>
        <register>
          <name>CNDTR2</name>
          <addressOffset>0x34</addressOffset>
          <size>0x20</size>
          <fields>
            <field>
              <name>NDT</name>
              <bitOffset>0</bitOffset>
              <bitWidth>16</bitWidth>
            </field>
          </fields>
        </register>
        <register>
          <name>CPAR2</name>
          <addressOffset>0x38</addressOffset>
          <size>0x20</size>
          <fields>
            <field>
              <name>PA</name>
              <bitOffset>0</bitOffset>
              <bitWidth>32</bitWidth>
            </field>
          </fields>
        </register>
        <register>
          <name>CM0AR2</name>
          <addressOffset>0x3c</addressOffset>
          <size>0x20</size>
          <fields>
            <field>
              <name>MA</name>
              <bitOffset>0</bitOffset>
              <bitWidth>32</bitWidth>
            </field>
          </fields>
        </register>
        <register>
          <name>CM1AR2</name>
          <addressOffset>0x40</addressOffset>
          <size>0x20</size>
          <fields>
            <field>
              <name>MA</name>
              <bitOffset>0</bitOffset>
              <bitWidth>32</bitWidth>
            </field>
          </fields>
        </register>
        <register>
          <name>CCR3</name>
          <addressOffset>0x44</addressOffset>
          <size>0x20</size>
          <fields>
            <field>
              <name>EN</name>
              <bitOffset>0</bitOffset>
              <bitWidth>1</bitWidth>
            </field>
            <field>
              <name>TCIE</name>
              <bitOffset>1</bitOffset>
              <bitWidth>1</bitWidth>
            </field>
            <field>
              <name>HTIE</name>
              <bitOffset>2</bitOffset>
              <bitWidth>1</bitWidth>
            </field>
            <field>
              <name>TEIE</name>
              <bitOffset>3</bitOffset>
              <bitWidth>1</bitWidth>
            </field>
            <field>
              <name>DIR</name>
              <bitOffset>4</bitOffset>
              <bitWidth>1</bitWidth>
            </field>
            <field>
              <name>CIRC</name>
              <bitOffset>5</bitOffset>
              <bitWidth>1</bitWidth>
            </field>
            <field>
              <name>PINC</name>
              <bitOffset>6</bitOffset>
              <bitWidth>1</bitWidth>
            </field>
            <field>
              <name>MINC</name>
              <bitOffset>7</bitOffset>
              <bitWidth>1</bitWidth>
            </field>
            <field>
              <name>PSIZE</name>
              <bitOffset>8</bitOffset>
              <bitWidth>2</bitWidth>
            </field>
            <field>
              <name>MSIZE</name>
              <bitOffset>10</bitOffset>
              <bitWidth>2</bitWidth>
            </field>
            <field>
              <name>PL</name>
              <bitOffset>12</bitOffset>
              <bitWidth>2</bitWidth>
            </field>
            <field>
              <name>MEM2MEM</name>
              <bitOffset>14</bitOffset>
              <bitWidth>1</bitWidth>
            </field>
            <field>
              <name>DBM</name>
              <bitOffset>15</bitOffset>
              <bitWidth>1</bitWidth>
            </field>
            <field>
              <name>CT</name>
              <bitOffset>16</bitOffset>
              <bitWidth>1</bitWidth>
            </field>
          </fields>
        </register>
        <register>
          <name>CNDTR3</name>
          <addressOffset>0x48</addressOffset>
          <size>0x20</size>
          <fields>
            <field>
              <name>NDT</name>
              <bitOffset>0</bitOffset>
              <bitWidth>16</bitWidth>
            </field>
          </fields>
        </register>
        <register>
          <name>CPAR3</name>
          <addressOffset>0x4c</addressOffset>
          <size>0x20</size>
          <fields>
            <field>
              <name>PA</name>
              <bitOffset>0</bitOffset>
              <bitWidth>32</bitWidth>
            </field>
          </fields>
        </register>
        <register>
          <name>CM0AR3</name>
          <addressOffset>0x50</addressOffset>
          <size>0x20</size>
          <fields>
            <field>
              <name>MA</name>
              <bitOffset>0</bitOffset>
              <bitWidth>32</bitWidth>
            </field>
          </fields>
        </register>
        <register>
          <name>CM1AR3</name>
          <addressOffset>0x54</addressOffset>
          <size>0x20</size>
          <fields>
            <field>
              <name>MA</name>
              <bitOffset>0</bitOffset>
              <bitWidth>32</bitWidth>
            </field>
          </fields>
        </register>
        <register>
          <name>CCR4</name>
          <addressOffset>0x58</addressOffset>
          <size>0x20</size>
          <fields>
            <field>
              <name>EN</name>
              <bitOffset>0</bitOffset>
              <bitWidth>1</bitWidth>
            </field>
            <field>
              <name>TCIE</name>
              <bitOffset>1</bitOffset>
              <bitWidth>1</bitWidth>
            </field>
            <field>
              <name>HTIE</name>
              <bitOffset>2</bitOffset>
              <bitWidth>1</bitWidth>
            </field>
            <field>
              <name>TEIE</name>
              <bitOffset>3</bitOffset>
              <bitWidth>1</bitWidth>
            </field>
            <field>
              <name>DIR</name>
              <bitOffset>4</bitOffset>
              <bitWidth>1</bitWidth>
            </field>
            <field>
              <name>CIRC</name>
              <bitOffset>5</bitOffset>
              <bitWidth>1</bitWidth>
            </field>
            <field>
              <name>PINC</name>
              <bitOffset>6</bitOffset>
              <bitWidth>1</bitWidth>
            </field>
            <field>
              <name>MINC</name>
              <bitOffset>7</bitOffset>
              <bitWidth>1</bitWidth>
            </field>
            <field>
              <name>PSIZE</name>
              <bitOffset>8</bitOffset>
              <bitWidth>2</bitWidth>
            </field>
            <field>
              <name>MSIZE</name>
              <bitOffset>10</bitOffset>
              <bitWidth>2</bitWidth>
            </field>
            <field>
              <name>PL</name>
              <bitOffset>12</bitOffset>
              <bitWidth>2</bitWidth>
            </field>
            <field>
              <name>MEM2MEM</name>
              <bitOffset>14</bitOffset>
              <bitWidth>1</bitWidth>
            </field>
            <field>
              <name>DBM</name>
              <bitOffset>15</bitOffset>
              <bitWidth>1</bitWidth>
            </field>
            <field>
              <name>CT</name>
              <bitOffset>16</bitOffset>
              <bitWidth>1</bitWidth>
            </field>
          </fields>
        </register>
        <register>
          <name>CNDTR4</name>
          <addressOffset>0x5c</addressOffset>
          <size>0x20</size>
          <fields>
            <field>
              <name>NDT</name>
              <bitOffset>0</bitOffset>
              <bitWidth>16</bitWidth>
            </field>
          </fields>
        </register>
        <register>
          <name>CPAR4</name>
          <addressOffset>0x60</addressOffset>
          <size>0x20</size>
          <fields>
            <field>
              <name>PA</name>
              <bitOffset>0</bitOffset>
              <bitWidth>32</bitWidth>
            </field>
          </fields>
        </register>
        <register>
          <name>CM0AR4</name>
          <addressOffset>0x64</addressOffset>
          <size>0x20</size>
          <fields>
            <field>
              <name>MA</name>
              <bitOffset>0</bitOffset>
              <bitWidth>32</bitWidth>
            </field>
          </fields>
        </register>
        <register>
          <name>CM1AR4</name>
          <addressOffset>0x68</addressOffset>
          <size>0x20</size>
          <fields>
            <field>
              <name>MA</name>
              <bitOffset>0</bitOffset>
              <bitWidth>32</bitWidth>
            </field>
          </fields>
        </register>
        <register>
          <name>CCR5</name>
          <addressOffset>0x6c</addressOffset>
          <size>0x20</size>
          <fields>
            <field>
              <name>EN</name>
              <bitOffset>0</bitOffset>
              <bitWidth>1</bitWidth>
            </field>
            <field>
              <name>TCIE</name>
              <bitOffset>1</bitOffset>
              <bitWidth>1</bitWidth>
            </field>
            <field>
              <name>HTIE</name>
              <bitOffset>2</bitOffset>
              <bitWidth>1</bitWidth>
            </field>
            <field>
              <name>TEIE</name>
              <bitOffset>3</bitOffset>
              <bitWidth>1</bitWidth>
            </field>
            <field>
              <name>DIR</name>
              <bitOffset>4</bitOffset>
              <bitWidth>1</bitWidth>
            </field>
            <field>
              <name>CIRC</name>
              <bitOffset>5</bitOffset>
              <bitWidth>1</bitWidth>
            </field>
            <field>
              <name>PINC</name>
              <bitOffset>6</bitOffset>
              <bitWidth>1</bitWidth>
            </field>
            <field>
              <name>MINC</name>
              <bitOffset>7</bitOffset>
              <bitWidth>1</bitWidth>
            </field>
            <field>
              <name>PSIZE</name>
              <bitOffset>8</bitOffset>
              <bitWidth>2</bitWidth>
            </field>
            <field>
              <name>MSIZE</name>
              <bitOffset>10</bitOffset>
              <bitWidth>2</bitWidth>
            </field>
            <field>
              <name>PL</name>
              <bitOffset>12</bitOffset>
              <bitWidth>2</bitWidth>
            </field>
            <field>
              <name>MEM2MEM</name>
              <bitOffset>14</bitOffset>
              <bitWidth>1</bitWidth>
            </field>
            <field>
              <name>DBM</name>
              <bitOffset>15</bitOffset>
              <bitWidth>1</bitWidth>
            </field>
            <field>
              <name>CT</name>
              <bitOffset>16</bitOffset>
              <bitWidth>1</bitWidth>
            </field>
          </fields>
        </register>
        <register>
          <name>CNDTR5</name>
          <addressOffset>0x70</addressOffset>
          <size>0x20</size>
          <fields>
            <field>
              <name>NDT</name>
              <bitOffset>0</bitOffset>
              <bitWidth>16</bitWidth>
            </field>
          </fields>
        </register>
        <register>
          <name>CPAR5</name>
          <addressOffset>0x74</addressOffset>
          <size>0x20</size>
          <fields>
            <field>
              <name>PA</name>
              <bitOffset>0</bitOffset>
              <bitWidth>32</bitWidth>
            </field>
          </fields>
        </register>
        <register>
          <name>CM0AR5</name>
          <addressOffset>0x78</addressOffset>
          <size>0x20</size>
          <fields>
            <field>
              <name>MA</name>
              <bitOffset>0</bitOffset>
              <bitWidth>32</bitWidth>
            </field>
          </fields>
        </register>
        <register>
          <name>CM1AR5</name>
          <addressOffset>0x7c</addressOffset>
          <size>0x20</size>
          <fields>
            <field>
              <name>MA</name>
              <bitOffset>0</bitOffset>
              <bitWidth>32</bitWidth>
            </field>
          </fields>
        </register>
        <register>
          <name>CCR6</name>
          <addressOffset>0x80</addressOffset>
          <size>0x20</size>
          <fields>
            <field>
              <name>EN</name>
              <bitOffset>0</bitOffset>
              <bitWidth>1</bitWidth>
            </field>
            <field>
              <name>TCIE</name>
              <bitOffset>1</bitOffset>
              <bitWidth>1</bitWidth>
            </field>
            <field>
              <name>HTIE</name>
              <bitOffset>2</bitOffset>
              <bitWidth>1</bitWidth>
            </field>
            <field>
              <name>TEIE</name>
              <bitOffset>3</bitOffset>
              <bitWidth>1</bitWidth>
            </field>
            <field>
              <name>DIR</name>
              <bitOffset>4</bitOffset>
              <bitWidth>1</bitWidth>
            </field>
            <field>
              <name>CIRC</name>
              <bitOffset>5</bitOffset>
              <bitWidth>1</bitWidth>
            </field>
            <field>
              <name>PINC</name>
              <bitOffset>6</bitOffset>
              <bitWidth>1</bitWidth>
            </field>
            <field>
              <name>MINC</name>
              <bitOffset>7</bitOffset>
              <bitWidth>1</bitWidth>
            </field>
            <field>
              <name>PSIZE</name>
              <bitOffset>8</bitOffset>
              <bitWidth>2</bitWidth>
            </field>
            <field>
              <name>MSIZE</name>
              <bitOffset>10</bitOffset>
              <bitWidth>2</bitWidth>
            </field>
            <field>
              <name>PL</name>
              <bitOffset>12</bitOffset>
              <bitWidth>2</bitWidth>
            </field>
            <field>
              <name>MEM2MEM</name>
              <bitOffset>14</bitOffset>
              <bitWidth>1</bitWidth>
            </field>
            <field>
              <name>DBM</name>
              <bitOffset>15</bitOffset>
              <bitWidth>1</bitWidth>
            </field>
            <field>
              <name>CT</name>
              <bitOffset>16</bitOffset>
              <bitWidth>1</bitWidth>
            </field>
          </fields>
        </register>
        <register>
          <name>CNDTR6</name>
          <addressOffset>0x84</addressOffset>
          <size>0x20</size>
          <fields>
            <field>
              <name>NDT</name>
              <bitOffset>0</bitOffset>
              <bitWidth>16</bitWidth>
            </field>
          </fields>
        </register>
        <register>
          <name>CPAR6</name>
          <addressOffset>0x88</addressOffset>
          <size>0x20</size>
          <fields>
            <field>
              <name>PA</name>
              <bitOffset>0</bitOffset>
              <bitWidth>32</bitWidth>
            </field>
          </fields>
        </register>
        <register>
          <name>CM0AR6</name>
          <addressOffset>0x8c</addressOffset>
          <size>0x20</size>
          <fields>
            <field>
              <name>MA</name>
              <bitOffset>0</bitOffset>
              <bitWidth>32</bitWidth>
            </field>
          </fields>
        </register>
        <register>
          <name>CM1AR6</name>
          <addressOffset>0x90</addressOffset>
          <size>0x20</size>
          <fields>
            <field>
              <name>MA</name>
              <bitOffset>0</bitOffset>
              <bitWidth>32</bitWidth>
            </field>
          </fields>
        </register>
        <register>
          <name>CCR7</name>
          <addressOffset>0x94</addressOffset>
          <size>0x20</size>
          <fields>
            <field>
              <name>EN</name>
              <bitOffset>0</bitOffset>
              <bitWidth>1</bitWidth>
            </field>
            <field>
              <name>TCIE</name>
              <bitOffset>1</bitOffset>
              <bitWidth>1</bitWidth>
            </field>
            <field>
              <name>HTIE</name>
              <bitOffset>2</bitOffset>
              <bitWidth>1</bitWidth>
            </field>
            <field>
              <name>TEIE</name>
              <bitOffset>3</bitOffset>
              <bitWidth>1</bitWidth>
            </field>
            <field>
              <name>DIR</name>
              <bitOffset>4</bitOffset>
              <bitWidth>1</bitWidth>
            </field>
            <field>
              <name>CIRC</name>
              <bitOffset>5</bitOffset>
              <bitWidth>1</bitWidth>
            </field>
            <field>
              <name>PINC</name>
              <bitOffset>6</bitOffset>
              <bitWidth>1</bitWidth>
            </field>
            <field>
              <name>MINC</name>
              <bitOffset>7</bitOffset>
              <bitWidth>1</bitWidth>
            </field>
            <field>
              <name>PSIZE</name>
              <bitOffset>8</bitOffset>
              <bitWidth>2</bitWidth>
            </field>
            <field>
              <name>MSIZE</name>
              <bitOffset>10</bitOffset>
              <bitWidth>2</bitWidth>
            </field>
            <field>
              <name>PL</name>
              <bitOffset>12</bitOffset>
              <bitWidth>2</bitWidth>
            </field>
            <field>
              <name>MEM2MEM</name>
              <bitOffset>14</bitOffset>
              <bitWidth>1</bitWidth>
            </field>
            <field>
              <name>DBM</name>
              <bitOffset>15</bitOffset>
              <bitWidth>1</bitWidth>
            </field>
            <field>
              <name>CT</name>
              <bitOffset>16</bitOffset>
              <bitWidth>1</bitWidth>
            </field>
          </fields>
        </register>
        <register>
          <name>CNDTR7</name>
          <addressOffset>0x98</addressOffset>
          <size>0x20</size>
          <fields>
            <field>
              <name>NDT</name>
              <bitOffset>0</bitOffset>
              <bitWidth>16</bitWidth>
            </field>
          </fields>
        </register>
        <register>
          <name>CPAR7</name>
          <addressOffset>0x9c</addressOffset>
          <size>0x20</size>
          <fields>
            <field>
              <name>PA</name>
              <bitOffset>0</bitOffset>
              <bitWidth>32</bitWidth>
            </field>
          </fields>
        </register>
        <register>
          <name>CM0AR7</name>
          <addressOffset>0xa0</addressOffset>
          <size>0x20</size>
          <fields>
            <field>
              <name>MA</name>
              <bitOffset>0</bitOffset>
              <bitWidth>32</bitWidth>
            </field>
          </fields>
        </register>
        <register>
          <name>CM1AR7</name>
          <addressOffset>0xa4</addressOffset>
          <size>0x20</size>
          <fields>
            <field>
              <name>MA</name>
              <bitOffset>0</bitOffset>
              <bitWidth>32</bitWidth>
            </field>
          </fields>
        </register>
      </registers>
    </peripheral>
    <peripheral>
      <name>DMAMUX2</name>
      <baseAddress>0x58025800</baseAddress>
      <registers>
        <register>
          <name>CCR0</name>
          <addressOffset>0x0</addressOffset>
          <size>0x20</size>
        </register>
        <register>
          <name>CCR0</name>
          <addressOffset>0x0</addressOffset>
          <size>0x20</size>
        </register>
        <register>
          <name>CCR1</name>
          <addressOffset>0x4</addressOffset>
          <size>0x20</size>
        </register>
        <register>
          <name>CCR1</name>
          <addressOffset>0x4</addressOffset>
          <size>0x20</size>
        </register>
        <register>
          <name>CCR2</name>
          <addressOffset>0x8</addressOffset>
          <size>0x20</size>
        </register>
        <register>
          <name>CCR2</name>
          <addressOffset>0x8</addressOffset>
          <size>0x20</size>
        </register>
        <register>
          <name>CCR3</name>
          <addressOffset>0xc</addressOffset>
          <size>0x20</size>
        </register>
        <register>
          <name>CCR3</name>
          <addressOffset>0xc</addressOffset>
          <size>0x20</size>
        </register>
        <register>
          <name>CCR4</name>
          <addressOffset>0x10</addressOffset>
          <size>0x20</size>
        </register>
        <register>
          <name>CCR4</name>
          <addressOffset>0x10</addressOffset>
          <size>0x20</size>
        </register>
        <register>
          <name>CCR5</name>
          <addressOffset>0x14</addressOffset>
          <size>0x20</size>
        </register>
        <register>
          <name>CCR5</name>
          <addressOffset>0x14</addressOffset>
          <size>0x20</size>
        </register>
        <register>
          <name>CCR6</name>
          <addressOffset>0x18</addressOffset>
          <size>0x20</size>
        </register>
        <register>
          <name>CCR6</name>
          <addressOffset>0x18</addressOffset>
          <size>0x20</size>
        </register>
        <register>
          <name>CCR7</name>
          <addressOffset>0x1c</addressOffset>
          <size>0x20</size>
        </register>
        <register>
          <name>CCR7</name>
          <addressOffset>0x1c</addressOffset>
          <size>0x20</size>
        </register>
        <register>
          <name>CCR8</name>
          <addressOffset>0x20</addressOffset>
          <size>0x20</size>
        </register>
        <register>
          <name>CCR9</name>
          <addressOffset>0x24</addressOffset>
          <size>0x20</size>
        </register>
        <register>
          <name>CCR0</name>
          <addressOffset>0x28</addressOffset>
          <size>0x20</size>
        </register>
        <register>
          <name>CCR1</name>
          <addressOffset>0x2c</addressOffset>
          <size>0x20</size>
        </register>
        <register>
          <name>CCR2</name>
          <addressOffset>0x30</addressOffset>
          <size>0x20</size>
        </register>
        <register>
          <name>CCR3</name>
          <addressOffset>0x34</addressOffset>
          <size>0x20</size>
        </register>
        <register>
          <name>CCR4</name>
          <addressOffset>0x38</addressOffset>
          <size>0x20</size>
        </register>
        <register>
          <name>CCR5</name>
          <addressOffset>0x3c</addressOffset>
          <size>0x20</size>
        </register>
        <register>
          <name>CCRs</name>
          <addressOffset>0x80</addressOffset>
          <size>0x20</size>
        </register>
        <register>
          <name>CCRs</name>
          <addressOffset>0x80</addressOffset>
          <size>0x20</size>
        </register>
        <register>
          <name>CCR0</name>
          <addressOffset>0x100</addressOffset>
          <size>0x20</size>
        </register>
        <register>
          <name>CCR0</name>
          <addressOffset>0x100</addressOffset>
          <size>0x20</size>
        </register>
        <register>
          <name>CCR1</name>
          <addressOffset>0x104</addressOffset>
          <size>0x20</size>
        </register>
        <register>
          <name>CCR1</name>
          <addressOffset>0x104</addressOffset>
          <size>0x20</size>
        </register>
        <register>
          <name>CCR2</name>
          <addressOffset>0x108</addressOffset>
          <size>0x20</size>
        </register>
        <register>
          <name>CCR2</name>
          <addressOffset>0x108</addressOffset>
          <size>0x20</size>
        </register>
        <register>
          <name>CCR3</name>
          <addressOffset>0x10c</addressOffset>
          <size>0x20</size>
        </register>
        <register>
          <name>CCR3</name>
          <addressOffset>0x10c</addressOffset>
          <size>0x20</size>
        </register>
        <register>
          <name>CCR4</name>
          <addressOffset>0x110</addressOffset>
          <size>0x20</size>
        </register>
        <register>
          <name>CCR4</name>
          <addressOffset>0x110</addressOffset>
          <size>0x20</size>
        </register>
        <register>
          <name>CCR5</name>
          <addressOffset>0x114</addressOffset>
          <size>0x20</size>
        </register>
        <register>
          <name>CCR5</name>
          <addressOffset>0x114</addressOffset>
          <size>0x20</size>
        </register>
        <register>
          <name>CCR6</name>
          <addressOffset>0x118</addressOffset>
          <size>0x20</size>
        </register>
        <register>
          <name>CCR6</name>
          <addressOffset>0x118</addressOffset>
          <size>0x20</size>
        </register>
        <register>
          <name>CCR7</name>
          <addressOffset>0x11c</addressOffset>
          <size>0x20</size>
        </register>
        <register>
          <name>CCR7</name>
          <addressOffset>0x11c</addressOffset>
          <size>0x20</size>
        </register>
        <register>
          <name>CCRs</name>
          <addressOffset>0x140</addressOffset>
          <size>0x20</size>
        </register>
        <register>
          <name>CCRs</name>
          <addressOffset>0x140</addressOffset>
          <size>0x20</size>
        </register>
      </registers>
    </peripheral>
    <peripheral>
      <name>ADC3</name>
      <baseAddress>0x58026000</baseAddress>
      <registers>
        <register>
          <name>ISR</name>
          <addressOffset>0x0</addressOffset>
          <size>0x20</size>
          <fields>
            <field>
              <name>ADRDY</name>
              <bitOffset>0</bitOffset>
              <bitWidth>1</bitWidth>
            </field>
            <field>
              <name>EOSMP</name>
              <bitOffset>1</bitOffset>
              <bitWidth>1</bitWidth>
            </field>
            <field>
              <name>EOC</name>
              <bitOffset>2</bitOffset>
              <bitWidth>1</bitWidth>
            </field>
            <field>
              <name>EOS</name>
              <bitOffset>3</bitOffset>
              <bitWidth>1</bitWidth>
            </field>
            <field>
              <name>OVR</name>
              <bitOffset>4</bitOffset>
              <bitWidth>1</bitWidth>
            </field>
            <field>
              <name>JEOC</name>
              <bitOffset>5</bitOffset>
              <bitWidth>1</bitWidth>
            </field>
            <field>
              <name>JEOS</name>
              <bitOffset>6</bitOffset>
              <bitWidth>1</bitWidth>
            </field>
            <field>
              <name>AWD1</name>
              <bitOffset>7</bitOffset>
              <bitWidth>1</bitWidth>
            </field>
            <field>
              <name>AWD2</name>
              <bitOffset>8</bitOffset>
              <bitWidth>1</bitWidth>
            </field>
            <field>
              <name>AWD3</name>
              <bitOffset>9</bitOffset>
              <bitWidth>1</bitWidth>
            </field>
            <field>
              <name>JQOVF</name>
              <bitOffset>10</bitOffset>
              <bitWidth>1</bitWidth>
            </field>
            <field>
              <name>LDORDY</name>
              <bitOffset>12</bitOffset>
              <bitWidth>1</bitWidth>
            </field>
          </fields>
        </register>
        <register>
          <name>IER</name>
          <addressOffset>0x4</addressOffset>
          <size>0x20</size>
          <fields>
            <field>
              <name>ADRDYIE</name>
              <bitOffset>0</bitOffset>
              <bitWidth>1</bitWidth>
            </field>
            <field>
              <name>EOSMPIE</name>
              <bitOffset>1</bitOffset>
              <bitWidth>1</bitWidth>
            </field>
            <field>
              <name>EOCIE</name>
              <bitOffset>2</bitOffset>
              <bitWidth>1</bitWidth>
            </field>
            <field>
              <name>EOSIE</name>
              <bitOffset>3</bitOffset>
              <bitWidth>1</bitWidth>
            </field>
            <field>
              <name>OVRIE</name>
              <bitOffset>4</bitOffset>
              <bitWidth>1</bitWidth>
            </field>
            <field>
              <name>JEOCIE</name>
              <bitOffset>5</bitOffset>
              <bitWidth>1</bitWidth>
            </field>
            <field>
              <name>JEOSIE</name>
              <bitOffset>6</bitOffset>
              <bitWidth>1</bitWidth>
            </field>
            <field>
              <name>AWD1IE</name>
              <bitOffset>7</bitOffset>
              <bitWidth>1</bitWidth>
            </field>
            <field>
              <name>AWD2IE</name>
              <bitOffset>8</bitOffset>
              <bitWidth>1</bitWidth>
            </field>
            <field>
              <name>AWD3IE</name>
              <bitOffset>9</bitOffset>
              <bitWidth>1</bitWidth>
            </field>
            <field>
              <name>JQOVFIE</name>
              <bitOffset>10</bitOffset>
              <bitWidth>1</bitWidth>
            </field>
          </fields>
        </register>
        <register>
          <name>CR</name>
          <addressOffset>0x8</addressOffset>
          <size>0x20</size>
          <fields>
            <field>
              <name>ADEN</name>
              <bitOffset>0</bitOffset>
              <bitWidth>1</bitWidth>
            </field>
            <field>
              <name>ADDIS</name>
              <bitOffset>1</bitOffset>
              <bitWidth>1</bitWidth>
            </field>
            <field>
              <name>ADSTART</name>
              <bitOffset>2</bitOffset>
              <bitWidth>1</bitWidth>
            </field>
            <field>
              <name>JADSTART</name>
              <bitOffset>3</bitOffset>
              <bitWidth>1</bitWidth>
            </field>
            <field>
              <name>ADSTP</name>
              <bitOffset>4</bitOffset>
              <bitWidth>1</bitWidth>
            </field>
            <field>
              <name>JADSTP</name>
              <bitOffset>5</bitOffset>
              <bitWidth>1</bitWidth>
            </field>
            <field>
              <name>BOOST</name>
              <bitOffset>8</bitOffset>
              <bitWidth>2</bitWidth>
            </field>
            <field>
              <name>ADCALLIN</name>
              <bitOffset>16</bitOffset>
              <bitWidth>1</bitWidth>
            </field>
            <field>
              <name>LINCALRDYW1</name>
              <bitOffset>22</bitOffset>
              <bitWidth>1</bitWidth>
            </field>
            <field>
              <name>LINCALRDYW2</name>
              <bitOffset>23</bitOffset>
              <bitWidth>1</bitWidth>
            </field>
            <field>
              <name>LINCALRDYW3</name>
              <bitOffset>24</bitOffset>
              <bitWidth>1</bitWidth>
            </field>
            <field>
              <name>LINCALRDYW4</name>
              <bitOffset>25</bitOffset>
              <bitWidth>1</bitWidth>
            </field>
            <field>
              <name>LINCALRDYW5</name>
              <bitOffset>26</bitOffset>
              <bitWidth>1</bitWidth>
            </field>
            <field>
              <name>LINCALRDYW6</name>
              <bitOffset>27</bitOffset>
              <bitWidth>1</bitWidth>
            </field>
            <field>
              <name>ADVREGEN</name>
              <bitOffset>28</bitOffset>
              <bitWidth>1</bitWidth>
            </field>
            <field>
              <name>DEEPPWD</name>
              <bitOffset>29</bitOffset>
              <bitWidth>1</bitWidth>
            </field>
            <field>
              <name>ADCALDIF</name>
              <bitOffset>30</bitOffset>
              <bitWidth>1</bitWidth>
            </field>
            <field>
              <name>ADCAL</name>
              <bitOffset>31</bitOffset>
              <bitWidth>1</bitWidth>
            </field>
          </fields>
        </register>
        <register>
          <name>CFGR</name>
          <addressOffset>0xc</addressOffset>
          <size>0x20</size>
          <fields>
            <field>
              <name>DMNGT</name>
              <bitOffset>0</bitOffset>
              <bitWidth>2</bitWidth>
            </field>
            <field>
              <name>RES</name>
              <bitOffset>2</bitOffset>
              <bitWidth>3</bitWidth>
            </field>
            <field>
              <name>EXTSEL</name>
              <bitOffset>5</bitOffset>
              <bitWidth>5</bitWidth>
            </field>
            <field>
              <name>EXTEN</name>
              <bitOffset>10</bitOffset>
              <bitWidth>2</bitWidth>
            </field>
            <field>
              <name>OVRMOD</name>
              <bitOffset>12</bitOffset>
              <bitWidth>1</bitWidth>
            </field>
            <field>
              <name>CONT</name>
              <bitOffset>13</bitOffset>
              <bitWidth>1</bitWidth>
            </field>
            <field>
              <name>AUTDLY</name>
              <bitOffset>14</bitOffset>
              <bitWidth>1</bitWidth>
            </field>
            <field>
              <name>DISCEN</name>
              <bitOffset>16</bitOffset>
              <bitWidth>1</bitWidth>
            </field>
            <field>
              <name>DISCNUM</name>
              <bitOffset>17</bitOffset>
              <bitWidth>3</bitWidth>
            </field>
            <field>
              <name>JDISCEN</name>
              <bitOffset>20</bitOffset>
              <bitWidth>1</bitWidth>
            </field>
            <field>
              <name>JQM</name>
              <bitOffset>21</bitOffset>
              <bitWidth>1</bitWidth>
            </field>
            <field>
              <name>AWD1SGL</name>
              <bitOffset>22</bitOffset>
              <bitWidth>1</bitWidth>
            </field>
            <field>
              <name>AWD1EN</name>
              <bitOffset>23</bitOffset>
              <bitWidth>1</bitWidth>
            </field>
            <field>
              <name>JAWD1EN</name>
              <bitOffset>24</bitOffset>
              <bitWidth>1</bitWidth>
            </field>
            <field>
              <name>JAUTO</name>
              <bitOffset>25</bitOffset>
              <bitWidth>1</bitWidth>
            </field>
            <field>
              <name>AWD1CH</name>
              <bitOffset>26</bitOffset>
              <bitWidth>5</bitWidth>
            </field>
            <field>
              <name>JQDIS</name>
              <bitOffset>31</bitOffset>
              <bitWidth>1</bitWidth>
            </field>
          </fields>
        </register>
        <register>
          <name>CFGR2</name>
          <addressOffset>0x10</addressOffset>
          <size>0x20</size>
          <fields>
            <field>
              <name>ROVSE</name>
              <bitOffset>0</bitOffset>
              <bitWidth>1</bitWidth>
            </field>
            <field>
              <name>JOVSE</name>
              <bitOffset>1</bitOffset>
              <bitWidth>1</bitWidth>
            </field>
            <field>
              <name>OVSS</name>
              <bitOffset>5</bitOffset>
              <bitWidth>4</bitWidth>
            </field>
            <field>
              <name>TROVS</name>
              <bitOffset>9</bitOffset>
              <bitWidth>1</bitWidth>
            </field>
            <field>
              <name>ROVSM</name>
              <bitOffset>10</bitOffset>
              <bitWidth>1</bitWidth>
            </field>
            <field>
              <name>RSHIFT1</name>
              <bitOffset>11</bitOffset>
              <bitWidth>1</bitWidth>
            </field>
            <field>
              <name>RSHIFT2</name>
              <bitOffset>12</bitOffset>
              <bitWidth>1</bitWidth>
            </field>
            <field>
              <name>RSHIFT3</name>
              <bitOffset>13</bitOffset>
              <bitWidth>1</bitWidth>
            </field>
            <field>
              <name>RSHIFT4</name>
              <bitOffset>14</bitOffset>
              <bitWidth>1</bitWidth>
            </field>
            <field>
              <name>OVSR</name>
              <bitOffset>16</bitOffset>
              <bitWidth>10</bitWidth>
            </field>
            <field>
              <name>LSHIFT</name>
              <bitOffset>28</bitOffset>
              <bitWidth>4</bitWidth>
            </field>
          </fields>
        </register>
        <register>
          <name>SMPR1</name>
          <addressOffset>0x14</addressOffset>
          <size>0x20</size>
          <fields>
            <field>
              <name>SMP0</name>
              <bitOffset>0</bitOffset>
              <bitWidth>3</bitWidth>
            </field>
            <field>
              <name>SMP1</name>
              <bitOffset>3</bitOffset>
              <bitWidth>3</bitWidth>
            </field>
            <field>
              <name>SMP2</name>
              <bitOffset>6</bitOffset>
              <bitWidth>3</bitWidth>
            </field>
            <field>
              <name>SMP3</name>
              <bitOffset>9</bitOffset>
              <bitWidth>3</bitWidth>
            </field>
            <field>
              <name>SMP4</name>
              <bitOffset>12</bitOffset>
              <bitWidth>3</bitWidth>
            </field>
            <field>
              <name>SMP5</name>
              <bitOffset>15</bitOffset>
              <bitWidth>3</bitWidth>
            </field>
            <field>
              <name>SMP6</name>
              <bitOffset>18</bitOffset>
              <bitWidth>3</bitWidth>
            </field>
            <field>
              <name>SMP7</name>
              <bitOffset>21</bitOffset>
              <bitWidth>3</bitWidth>
            </field>
            <field>
              <name>SMP8</name>
              <bitOffset>24</bitOffset>
              <bitWidth>3</bitWidth>
            </field>
            <field>
              <name>SMP9</name>
              <bitOffset>27</bitOffset>
              <bitWidth>3</bitWidth>
            </field>
          </fields>
        </register>
        <register>
          <name>SMPR2</name>
          <addressOffset>0x18</addressOffset>
          <size>0x20</size>
          <fields>
            <field>
              <name>SMP10</name>
              <bitOffset>0</bitOffset>
              <bitWidth>3</bitWidth>
            </field>
            <field>
              <name>SMP11</name>
              <bitOffset>3</bitOffset>
              <bitWidth>3</bitWidth>
            </field>
            <field>
              <name>SMP12</name>
              <bitOffset>6</bitOffset>
              <bitWidth>3</bitWidth>
            </field>
            <field>
              <name>SMP13</name>
              <bitOffset>9</bitOffset>
              <bitWidth>3</bitWidth>
            </field>
            <field>
              <name>SMP14</name>
              <bitOffset>12</bitOffset>
              <bitWidth>3</bitWidth>
            </field>
            <field>
              <name>SMP15</name>
              <bitOffset>15</bitOffset>
              <bitWidth>3</bitWidth>
            </field>
            <field>
              <name>SMP16</name>
              <bitOffset>18</bitOffset>
              <bitWidth>3</bitWidth>
            </field>
            <field>
              <name>SMP17</name>
              <bitOffset>21</bitOffset>
              <bitWidth>3</bitWidth>
            </field>
            <field>
              <name>SMP18</name>
              <bitOffset>24</bitOffset>
              <bitWidth>3</bitWidth>
            </field>
            <field>
              <name>SMP19</name>
              <bitOffset>27</bitOffset>
              <bitWidth>3</bitWidth>
            </field>
          </fields>
        </register>
        <register>
          <name>PCSEL_RES0</name>
          <addressOffset>0x1c</addressOffset>
          <size>0x20</size>
        </register>
        <register>
          <name>LTR1_TR1</name>
          <addressOffset>0x20</addressOffset>
          <size>0x20</size>
        </register>
        <register>
          <name>HTR1_TR2</name>
          <addressOffset>0x24</addressOffset>
          <size>0x20</size>
        </register>
        <register>
          <name>RES1_TR3</name>
          <addressOffset>0x28</addressOffset>
          <size>0x20</size>
        </register>
        <register>
          <name>SQR1</name>
          <addressOffset>0x30</addressOffset>
          <size>0x20</size>
          <fields>
            <field>
              <name>L</name>
              <bitOffset>0</bitOffset>
              <bitWidth>4</bitWidth>
            </field>
            <field>
              <name>SQ1</name>
              <bitOffset>6</bitOffset>
              <bitWidth>5</bitWidth>
            </field>
            <field>
              <name>SQ2</name>
              <bitOffset>12</bitOffset>
              <bitWidth>5</bitWidth>
            </field>
            <field>
              <name>SQ3</name>
              <bitOffset>18</bitOffset>
              <bitWidth>5</bitWidth>
            </field>
            <field>
              <name>SQ4</name>
              <bitOffset>24</bitOffset>
              <bitWidth>5</bitWidth>
            </field>
          </fields>
        </register>
        <register>
          <name>SQR2</name>
          <addressOffset>0x34</addressOffset>
          <size>0x20</size>
          <fields>
            <field>
              <name>SQ5</name>
              <bitOffset>0</bitOffset>
              <bitWidth>5</bitWidth>
            </field>
            <field>
              <name>SQ6</name>
              <bitOffset>6</bitOffset>
              <bitWidth>5</bitWidth>
            </field>
            <field>
              <name>SQ7</name>
              <bitOffset>12</bitOffset>
              <bitWidth>5</bitWidth>
            </field>
            <field>
              <name>SQ8</name>
              <bitOffset>18</bitOffset>
              <bitWidth>5</bitWidth>
            </field>
            <field>
              <name>SQ9</name>
              <bitOffset>24</bitOffset>
              <bitWidth>5</bitWidth>
            </field>
          </fields>
        </register>
        <register>
          <name>SQR3</name>
          <addressOffset>0x38</addressOffset>
          <size>0x20</size>
          <fields>
            <field>
              <name>SQ10</name>
              <bitOffset>0</bitOffset>
              <bitWidth>5</bitWidth>
            </field>
            <field>
              <name>SQ11</name>
              <bitOffset>6</bitOffset>
              <bitWidth>5</bitWidth>
            </field>
            <field>
              <name>SQ12</name>
              <bitOffset>12</bitOffset>
              <bitWidth>5</bitWidth>
            </field>
            <field>
              <name>SQ13</name>
              <bitOffset>18</bitOffset>
              <bitWidth>5</bitWidth>
            </field>
            <field>
              <name>SQ14</name>
              <bitOffset>24</bitOffset>
              <bitWidth>5</bitWidth>
            </field>
          </fields>
        </register>
        <register>
          <name>SQR4</name>
          <addressOffset>0x3c</addressOffset>
          <size>0x20</size>
          <fields>
            <field>
              <name>SQ15</name>
              <bitOffset>0</bitOffset>
              <bitWidth>5</bitWidth>
            </field>
            <field>
              <name>SQ16</name>
              <bitOffset>6</bitOffset>
              <bitWidth>5</bitWidth>
            </field>
          </fields>
        </register>
        <register>
          <name>DR</name>
          <addressOffset>0x40</addressOffset>
          <size>0x20</size>
          <fields>
            <field>
              <name>RDATA</name>
              <bitOffset>0</bitOffset>
              <bitWidth>32</bitWidth>
            </field>
          </fields>
        </register>
        <register>
          <name>JSQR</name>
          <addressOffset>0x4c</addressOffset>
          <size>0x20</size>
          <fields>
            <field>
              <name>JL</name>
              <bitOffset>0</bitOffset>
              <bitWidth>2</bitWidth>
            </field>
            <field>
              <name>JEXTSEL</name>
              <bitOffset>2</bitOffset>
              <bitWidth>5</bitWidth>
            </field>
            <field>
              <name>JEXTEN</name>
              <bitOffset>7</bitOffset>
              <bitWidth>2</bitWidth>
            </field>
            <field>
              <name>JSQ1</name>
              <bitOffset>9</bitOffset>
              <bitWidth>5</bitWidth>
            </field>
            <field>
              <name>JSQ2</name>
              <bitOffset>15</bitOffset>
              <bitWidth>5</bitWidth>
            </field>
            <field>
              <name>JSQ3</name>
              <bitOffset>21</bitOffset>
              <bitWidth>5</bitWidth>
            </field>
            <field>
              <name>JSQ4</name>
              <bitOffset>27</bitOffset>
              <bitWidth>5</bitWidth>
            </field>
          </fields>
        </register>
        <register>
          <name>OFR1</name>
          <addressOffset>0x60</addressOffset>
          <size>0x20</size>
          <fields>
            <field>
              <name>OFFSET1</name>
              <bitOffset>0</bitOffset>
              <bitWidth>26</bitWidth>
            </field>
            <field>
              <name>OFFSET1_CH</name>
              <bitOffset>26</bitOffset>
              <bitWidth>5</bitWidth>
            </field>
            <field>
              <name>SSATE</name>
              <bitOffset>31</bitOffset>
              <bitWidth>1</bitWidth>
            </field>
          </fields>
        </register>
        <register>
          <name>OFR2</name>
          <addressOffset>0x64</addressOffset>
          <size>0x20</size>
          <fields>
            <field>
              <name>OFFSET2</name>
              <bitOffset>0</bitOffset>
              <bitWidth>26</bitWidth>
            </field>
            <field>
              <name>OFFSET2_CH</name>
              <bitOffset>26</bitOffset>
              <bitWidth>5</bitWidth>
            </field>
            <field>
              <name>SSATE</name>
              <bitOffset>31</bitOffset>
              <bitWidth>1</bitWidth>
            </field>
          </fields>
        </register>
        <register>
          <name>OFR3</name>
          <addressOffset>0x68</addressOffset>
          <size>0x20</size>
          <fields>
            <field>
              <name>OFFSET3</name>
              <bitOffset>0</bitOffset>
              <bitWidth>26</bitWidth>
            </field>
            <field>
              <name>OFFSET3_CH</name>
              <bitOffset>26</bitOffset>
              <bitWidth>5</bitWidth>
            </field>
            <field>
              <name>SSATE</name>
              <bitOffset>31</bitOffset>
              <bitWidth>1</bitWidth>
            </field>
          </fields>
        </register>
        <register>
          <name>OFR4</name>
          <addressOffset>0x6c</addressOffset>
          <size>0x20</size>
          <fields>
            <field>
              <name>OFFSET4</name>
              <bitOffset>0</bitOffset>
              <bitWidth>26</bitWidth>
            </field>
            <field>
              <name>OFFSET4_CH</name>
              <bitOffset>26</bitOffset>
              <bitWidth>5</bitWidth>
            </field>
            <field>
              <name>SSATE</name>
              <bitOffset>31</bitOffset>
              <bitWidth>1</bitWidth>
            </field>
          </fields>
        </register>
        <register>
          <name>JDR1</name>
          <addressOffset>0x80</addressOffset>
          <size>0x20</size>
          <fields>
            <field>
              <name>JDATA</name>
              <bitOffset>0</bitOffset>
              <bitWidth>32</bitWidth>
            </field>
          </fields>
        </register>
        <register>
          <name>JDR2</name>
          <addressOffset>0x84</addressOffset>
          <size>0x20</size>
          <fields>
            <field>
              <name>JDATA</name>
              <bitOffset>0</bitOffset>
              <bitWidth>32</bitWidth>
            </field>
          </fields>
        </register>
        <register>
          <name>JDR3</name>
          <addressOffset>0x88</addressOffset>
          <size>0x20</size>
          <fields>
            <field>
              <name>JDATA</name>
              <bitOffset>0</bitOffset>
              <bitWidth>32</bitWidth>
            </field>
          </fields>
        </register>
        <register>
          <name>JDR4</name>
          <addressOffset>0x8c</addressOffset>
          <size>0x20</size>
          <fields>
            <field>
              <name>JDATA</name>
              <bitOffset>0</bitOffset>
              <bitWidth>32</bitWidth>
            </field>
          </fields>
        </register>
        <register>
          <name>AWD2CR</name>
          <addressOffset>0xa0</addressOffset>
          <size>0x20</size>
          <fields>
            <field>
              <name>AWD2CH</name>
              <bitOffset>0</bitOffset>
              <bitWidth>20</bitWidth>
            </field>
          </fields>
        </register>
        <register>
          <name>AWD3CR</name>
          <addressOffset>0xa4</addressOffset>
          <size>0x20</size>
          <fields>
            <field>
              <name>AWD3CH</name>
              <bitOffset>0</bitOffset>
              <bitWidth>20</bitWidth>
            </field>
          </fields>
        </register>
        <register>
          <name>LTR2_DIFSEL</name>
          <addressOffset>0xb0</addressOffset>
          <size>0x20</size>
        </register>
        <register>
          <name>HTR2_CALFACT</name>
          <addressOffset>0xb4</addressOffset>
          <size>0x20</size>
        </register>
        <register>
          <name>LTR3_RES10</name>
          <addressOffset>0xb8</addressOffset>
          <size>0x20</size>
        </register>
        <register>
          <name>HTR3_RES11</name>
          <addressOffset>0xbc</addressOffset>
          <size>0x20</size>
        </register>
        <register>
          <name>DIFSEL_RES12</name>
          <addressOffset>0xc0</addressOffset>
          <size>0x20</size>
        </register>
        <register>
          <name>CALFACT_RES13</name>
          <addressOffset>0xc4</addressOffset>
          <size>0x20</size>
        </register>
        <register>
          <name>CALFACT2_RES14</name>
          <addressOffset>0xc8</addressOffset>
          <size>0x20</size>
        </register>
      </registers>
    </peripheral>
    <peripheral>
      <name>ADC3_COMMON</name>
      <baseAddress>0x58026300</baseAddress>
      <registers>
        <register>
          <name>CSR</name>
          <addressOffset>0x0</addressOffset>
          <size>0x20</size>
          <fields>
            <field>
              <name>ADRDY_MST</name>
              <bitOffset>0</bitOffset>
              <bitWidth>1</bitWidth>
            </field>
            <field>
              <name>EOSMP_MST</name>
              <bitOffset>1</bitOffset>
              <bitWidth>1</bitWidth>
            </field>
            <field>
              <name>EOC_MST</name>
              <bitOffset>2</bitOffset>
              <bitWidth>1</bitWidth>
            </field>
            <field>
              <name>EOS_MST</name>
              <bitOffset>3</bitOffset>
              <bitWidth>1</bitWidth>
            </field>
            <field>
              <name>OVR_MST</name>
              <bitOffset>4</bitOffset>
              <bitWidth>1</bitWidth>
            </field>
            <field>
              <name>JEOC_MST</name>
              <bitOffset>5</bitOffset>
              <bitWidth>1</bitWidth>
            </field>
            <field>
              <name>JEOS_MST</name>
              <bitOffset>6</bitOffset>
              <bitWidth>1</bitWidth>
            </field>
            <field>
              <name>AWD1_MST</name>
              <bitOffset>7</bitOffset>
              <bitWidth>1</bitWidth>
            </field>
            <field>
              <name>AWD2_MST</name>
              <bitOffset>8</bitOffset>
              <bitWidth>1</bitWidth>
            </field>
            <field>
              <name>AWD3_MST</name>
              <bitOffset>9</bitOffset>
              <bitWidth>1</bitWidth>
            </field>
            <field>
              <name>JQOVF_MST</name>
              <bitOffset>10</bitOffset>
              <bitWidth>1</bitWidth>
            </field>
            <field>
              <name>ADRDY_SLV</name>
              <bitOffset>16</bitOffset>
              <bitWidth>1</bitWidth>
            </field>
            <field>
              <name>EOSMP_SLV</name>
              <bitOffset>17</bitOffset>
              <bitWidth>1</bitWidth>
            </field>
            <field>
              <name>EOC_SLV</name>
              <bitOffset>18</bitOffset>
              <bitWidth>1</bitWidth>
            </field>
            <field>
              <name>EOS_SLV</name>
              <bitOffset>19</bitOffset>
              <bitWidth>1</bitWidth>
            </field>
            <field>
              <name>OVR_SLV</name>
              <bitOffset>20</bitOffset>
              <bitWidth>1</bitWidth>
            </field>
            <field>
              <name>JEOC_SLV</name>
              <bitOffset>21</bitOffset>
              <bitWidth>1</bitWidth>
            </field>
            <field>
              <name>JEOS_SLV</name>
              <bitOffset>22</bitOffset>
              <bitWidth>1</bitWidth>
            </field>
            <field>
              <name>AWD1_SLV</name>
              <bitOffset>23</bitOffset>
              <bitWidth>1</bitWidth>
            </field>
            <field>
              <name>AWD2_SLV</name>
              <bitOffset>24</bitOffset>
              <bitWidth>1</bitWidth>
            </field>
            <field>
              <name>AWD3_SLV</name>
              <bitOffset>25</bitOffset>
              <bitWidth>1</bitWidth>
            </field>
            <field>
              <name>JQOVF_SLV</name>
              <bitOffset>26</bitOffset>
              <bitWidth>1</bitWidth>
            </field>
          </fields>
        </register>
        <register>
          <name>CCR</name>
          <addressOffset>0x8</addressOffset>
          <size>0x20</size>
          <fields>
            <field>
              <name>DUAL</name>
              <bitOffset>0</bitOffset>
              <bitWidth>5</bitWidth>
            </field>
            <field>
              <name>DELAY</name>
              <bitOffset>8</bitOffset>
              <bitWidth>4</bitWidth>
            </field>
            <field>
              <name>DAMDF</name>
              <bitOffset>14</bitOffset>
              <bitWidth>2</bitWidth>
            </field>
            <field>
              <name>CKMODE</name>
              <bitOffset>16</bitOffset>
              <bitWidth>2</bitWidth>
            </field>
            <field>
              <name>PRESC</name>
              <bitOffset>18</bitOffset>
              <bitWidth>4</bitWidth>
            </field>
            <field>
              <name>VREFEN</name>
              <bitOffset>22</bitOffset>
              <bitWidth>1</bitWidth>
            </field>
            <field>
              <name>TSEN</name>
              <bitOffset>23</bitOffset>
              <bitWidth>1</bitWidth>
            </field>
            <field>
              <name>VBATEN</name>
              <bitOffset>24</bitOffset>
              <bitWidth>1</bitWidth>
            </field>
          </fields>
        </register>
        <register>
          <name>CDR</name>
          <addressOffset>0xc</addressOffset>
          <size>0x20</size>
          <fields>
            <field>
              <name>RDATA_MST</name>
              <bitOffset>0</bitOffset>
              <bitWidth>16</bitWidth>
            </field>
            <field>
              <name>RDATA_SLV</name>
              <bitOffset>16</bitOffset>
              <bitWidth>16</bitWidth>
            </field>
          </fields>
        </register>
        <register>
          <name>CDR2</name>
          <addressOffset>0x10</addressOffset>
          <size>0x20</size>
          <fields>
            <field>
              <name>RDATA_ALT</name>
              <bitOffset>0</bitOffset>
              <bitWidth>32</bitWidth>
            </field>
          </fields>
        </register>
      </registers>
    </peripheral>
    <peripheral>
      <name>HSEM</name>
      <baseAddress>0x58026400</baseAddress>
      <registers>
        <register>
          <name>R.0</name>
          <addressOffset>0x0</addressOffset>
          <size>0x20</size>
          <fields>
            <field>
              <name>PROCID</name>
              <bitOffset>0</bitOffset>
              <bitWidth>8</bitWidth>
            </field>
            <field>
              <name>COREID</name>
              <bitOffset>8</bitOffset>
              <bitWidth>8</bitWidth>
            </field>
            <field>
              <name>LOCK</name>
              <bitOffset>31</bitOffset>
              <bitWidth>1</bitWidth>
            </field>
          </fields>
        </register>
        <register>
          <name>R.1</name>
          <addressOffset>0x4</addressOffset>
          <size>0x20</size>
          <fields>
            <field>
              <name>PROCID</name>
              <bitOffset>0</bitOffset>
              <bitWidth>8</bitWidth>
            </field>
            <field>
              <name>COREID</name>
              <bitOffset>8</bitOffset>
              <bitWidth>8</bitWidth>
            </field>
            <field>
              <name>LOCK</name>
              <bitOffset>31</bitOffset>
              <bitWidth>1</bitWidth>
            </field>
          </fields>
        </register>
        <register>
          <name>R.2</name>
          <addressOffset>0x8</addressOffset>
          <size>0x20</size>
          <fields>
            <field>
              <name>PROCID</name>
              <bitOffset>0</bitOffset>
              <bitWidth>8</bitWidth>
            </field>
            <field>
              <name>COREID</name>
              <bitOffset>8</bitOffset>
              <bitWidth>8</bitWidth>
            </field>
            <field>
              <name>LOCK</name>
              <bitOffset>31</bitOffset>
              <bitWidth>1</bitWidth>
            </field>
          </fields>
        </register>
        <register>
          <name>R.3</name>
          <addressOffset>0xc</addressOffset>
          <size>0x20</size>
          <fields>
            <field>
              <name>PROCID</name>
              <bitOffset>0</bitOffset>
              <bitWidth>8</bitWidth>
            </field>
            <field>
              <name>COREID</name>
              <bitOffset>8</bitOffset>
              <bitWidth>8</bitWidth>
            </field>
            <field>
              <name>LOCK</name>
              <bitOffset>31</bitOffset>
              <bitWidth>1</bitWidth>
            </field>
          </fields>
        </register>
        <register>
          <name>R.4</name>
          <addressOffset>0x10</addressOffset>
          <size>0x20</size>
          <fields>
            <field>
              <name>PROCID</name>
              <bitOffset>0</bitOffset>
              <bitWidth>8</bitWidth>
            </field>
            <field>
              <name>COREID</name>
              <bitOffset>8</bitOffset>
              <bitWidth>8</bitWidth>
            </field>
            <field>
              <name>LOCK</name>
              <bitOffset>31</bitOffset>
              <bitWidth>1</bitWidth>
            </field>
          </fields>
        </register>
        <register>
          <name>R.5</name>
          <addressOffset>0x14</addressOffset>
          <size>0x20</size>
          <fields>
            <field>
              <name>PROCID</name>
              <bitOffset>0</bitOffset>
              <bitWidth>8</bitWidth>
            </field>
            <field>
              <name>COREID</name>
              <bitOffset>8</bitOffset>
              <bitWidth>8</bitWidth>
            </field>
            <field>
              <name>LOCK</name>
              <bitOffset>31</bitOffset>
              <bitWidth>1</bitWidth>
            </field>
          </fields>
        </register>
        <register>
          <name>R.6</name>
          <addressOffset>0x18</addressOffset>
          <size>0x20</size>
          <fields>
            <field>
              <name>PROCID</name>
              <bitOffset>0</bitOffset>
              <bitWidth>8</bitWidth>
            </field>
            <field>
              <name>COREID</name>
              <bitOffset>8</bitOffset>
              <bitWidth>8</bitWidth>
            </field>
            <field>
              <name>LOCK</name>
              <bitOffset>31</bitOffset>
              <bitWidth>1</bitWidth>
            </field>
          </fields>
        </register>
        <register>
          <name>R.7</name>
          <addressOffset>0x1c</addressOffset>
          <size>0x20</size>
          <fields>
            <field>
              <name>PROCID</name>
              <bitOffset>0</bitOffset>
              <bitWidth>8</bitWidth>
            </field>
            <field>
              <name>COREID</name>
              <bitOffset>8</bitOffset>
              <bitWidth>8</bitWidth>
            </field>
            <field>
              <name>LOCK</name>
              <bitOffset>31</bitOffset>
              <bitWidth>1</bitWidth>
            </field>
          </fields>
        </register>
        <register>
          <name>R.8</name>
          <addressOffset>0x20</addressOffset>
          <size>0x20</size>
          <fields>
            <field>
              <name>PROCID</name>
              <bitOffset>0</bitOffset>
              <bitWidth>8</bitWidth>
            </field>
            <field>
              <name>COREID</name>
              <bitOffset>8</bitOffset>
              <bitWidth>8</bitWidth>
            </field>
            <field>
              <name>LOCK</name>
              <bitOffset>31</bitOffset>
              <bitWidth>1</bitWidth>
            </field>
          </fields>
        </register>
        <register>
          <name>R.9</name>
          <addressOffset>0x24</addressOffset>
          <size>0x20</size>
          <fields>
            <field>
              <name>PROCID</name>
              <bitOffset>0</bitOffset>
              <bitWidth>8</bitWidth>
            </field>
            <field>
              <name>COREID</name>
              <bitOffset>8</bitOffset>
              <bitWidth>8</bitWidth>
            </field>
            <field>
              <name>LOCK</name>
              <bitOffset>31</bitOffset>
              <bitWidth>1</bitWidth>
            </field>
          </fields>
        </register>
        <register>
          <name>R.10</name>
          <addressOffset>0x28</addressOffset>
          <size>0x20</size>
          <fields>
            <field>
              <name>PROCID</name>
              <bitOffset>0</bitOffset>
              <bitWidth>8</bitWidth>
            </field>
            <field>
              <name>COREID</name>
              <bitOffset>8</bitOffset>
              <bitWidth>8</bitWidth>
            </field>
            <field>
              <name>LOCK</name>
              <bitOffset>31</bitOffset>
              <bitWidth>1</bitWidth>
            </field>
          </fields>
        </register>
        <register>
          <name>R.11</name>
          <addressOffset>0x2c</addressOffset>
          <size>0x20</size>
          <fields>
            <field>
              <name>PROCID</name>
              <bitOffset>0</bitOffset>
              <bitWidth>8</bitWidth>
            </field>
            <field>
              <name>COREID</name>
              <bitOffset>8</bitOffset>
              <bitWidth>8</bitWidth>
            </field>
            <field>
              <name>LOCK</name>
              <bitOffset>31</bitOffset>
              <bitWidth>1</bitWidth>
            </field>
          </fields>
        </register>
        <register>
          <name>R.12</name>
          <addressOffset>0x30</addressOffset>
          <size>0x20</size>
          <fields>
            <field>
              <name>PROCID</name>
              <bitOffset>0</bitOffset>
              <bitWidth>8</bitWidth>
            </field>
            <field>
              <name>COREID</name>
              <bitOffset>8</bitOffset>
              <bitWidth>8</bitWidth>
            </field>
            <field>
              <name>LOCK</name>
              <bitOffset>31</bitOffset>
              <bitWidth>1</bitWidth>
            </field>
          </fields>
        </register>
        <register>
          <name>R.13</name>
          <addressOffset>0x34</addressOffset>
          <size>0x20</size>
          <fields>
            <field>
              <name>PROCID</name>
              <bitOffset>0</bitOffset>
              <bitWidth>8</bitWidth>
            </field>
            <field>
              <name>COREID</name>
              <bitOffset>8</bitOffset>
              <bitWidth>8</bitWidth>
            </field>
            <field>
              <name>LOCK</name>
              <bitOffset>31</bitOffset>
              <bitWidth>1</bitWidth>
            </field>
          </fields>
        </register>
        <register>
          <name>R.14</name>
          <addressOffset>0x38</addressOffset>
          <size>0x20</size>
          <fields>
            <field>
              <name>PROCID</name>
              <bitOffset>0</bitOffset>
              <bitWidth>8</bitWidth>
            </field>
            <field>
              <name>COREID</name>
              <bitOffset>8</bitOffset>
              <bitWidth>8</bitWidth>
            </field>
            <field>
              <name>LOCK</name>
              <bitOffset>31</bitOffset>
              <bitWidth>1</bitWidth>
            </field>
          </fields>
        </register>
        <register>
          <name>R.15</name>
          <addressOffset>0x3c</addressOffset>
          <size>0x20</size>
          <fields>
            <field>
              <name>PROCID</name>
              <bitOffset>0</bitOffset>
              <bitWidth>8</bitWidth>
            </field>
            <field>
              <name>COREID</name>
              <bitOffset>8</bitOffset>
              <bitWidth>8</bitWidth>
            </field>
            <field>
              <name>LOCK</name>
              <bitOffset>31</bitOffset>
              <bitWidth>1</bitWidth>
            </field>
          </fields>
        </register>
        <register>
          <name>R.16</name>
          <addressOffset>0x40</addressOffset>
          <size>0x20</size>
          <fields>
            <field>
              <name>PROCID</name>
              <bitOffset>0</bitOffset>
              <bitWidth>8</bitWidth>
            </field>
            <field>
              <name>COREID</name>
              <bitOffset>8</bitOffset>
              <bitWidth>8</bitWidth>
            </field>
            <field>
              <name>LOCK</name>
              <bitOffset>31</bitOffset>
              <bitWidth>1</bitWidth>
            </field>
          </fields>
        </register>
        <register>
          <name>R.17</name>
          <addressOffset>0x44</addressOffset>
          <size>0x20</size>
          <fields>
            <field>
              <name>PROCID</name>
              <bitOffset>0</bitOffset>
              <bitWidth>8</bitWidth>
            </field>
            <field>
              <name>COREID</name>
              <bitOffset>8</bitOffset>
              <bitWidth>8</bitWidth>
            </field>
            <field>
              <name>LOCK</name>
              <bitOffset>31</bitOffset>
              <bitWidth>1</bitWidth>
            </field>
          </fields>
        </register>
        <register>
          <name>R.18</name>
          <addressOffset>0x48</addressOffset>
          <size>0x20</size>
          <fields>
            <field>
              <name>PROCID</name>
              <bitOffset>0</bitOffset>
              <bitWidth>8</bitWidth>
            </field>
            <field>
              <name>COREID</name>
              <bitOffset>8</bitOffset>
              <bitWidth>8</bitWidth>
            </field>
            <field>
              <name>LOCK</name>
              <bitOffset>31</bitOffset>
              <bitWidth>1</bitWidth>
            </field>
          </fields>
        </register>
        <register>
          <name>R.19</name>
          <addressOffset>0x4c</addressOffset>
          <size>0x20</size>
          <fields>
            <field>
              <name>PROCID</name>
              <bitOffset>0</bitOffset>
              <bitWidth>8</bitWidth>
            </field>
            <field>
              <name>COREID</name>
              <bitOffset>8</bitOffset>
              <bitWidth>8</bitWidth>
            </field>
            <field>
              <name>LOCK</name>
              <bitOffset>31</bitOffset>
              <bitWidth>1</bitWidth>
            </field>
          </fields>
        </register>
        <register>
          <name>R.20</name>
          <addressOffset>0x50</addressOffset>
          <size>0x20</size>
          <fields>
            <field>
              <name>PROCID</name>
              <bitOffset>0</bitOffset>
              <bitWidth>8</bitWidth>
            </field>
            <field>
              <name>COREID</name>
              <bitOffset>8</bitOffset>
              <bitWidth>8</bitWidth>
            </field>
            <field>
              <name>LOCK</name>
              <bitOffset>31</bitOffset>
              <bitWidth>1</bitWidth>
            </field>
          </fields>
        </register>
        <register>
          <name>R.21</name>
          <addressOffset>0x54</addressOffset>
          <size>0x20</size>
          <fields>
            <field>
              <name>PROCID</name>
              <bitOffset>0</bitOffset>
              <bitWidth>8</bitWidth>
            </field>
            <field>
              <name>COREID</name>
              <bitOffset>8</bitOffset>
              <bitWidth>8</bitWidth>
            </field>
            <field>
              <name>LOCK</name>
              <bitOffset>31</bitOffset>
              <bitWidth>1</bitWidth>
            </field>
          </fields>
        </register>
        <register>
          <name>R.22</name>
          <addressOffset>0x58</addressOffset>
          <size>0x20</size>
          <fields>
            <field>
              <name>PROCID</name>
              <bitOffset>0</bitOffset>
              <bitWidth>8</bitWidth>
            </field>
            <field>
              <name>COREID</name>
              <bitOffset>8</bitOffset>
              <bitWidth>8</bitWidth>
            </field>
            <field>
              <name>LOCK</name>
              <bitOffset>31</bitOffset>
              <bitWidth>1</bitWidth>
            </field>
          </fields>
        </register>
        <register>
          <name>R.23</name>
          <addressOffset>0x5c</addressOffset>
          <size>0x20</size>
          <fields>
            <field>
              <name>PROCID</name>
              <bitOffset>0</bitOffset>
              <bitWidth>8</bitWidth>
            </field>
            <field>
              <name>COREID</name>
              <bitOffset>8</bitOffset>
              <bitWidth>8</bitWidth>
            </field>
            <field>
              <name>LOCK</name>
              <bitOffset>31</bitOffset>
              <bitWidth>1</bitWidth>
            </field>
          </fields>
        </register>
        <register>
          <name>R.24</name>
          <addressOffset>0x60</addressOffset>
          <size>0x20</size>
          <fields>
            <field>
              <name>PROCID</name>
              <bitOffset>0</bitOffset>
              <bitWidth>8</bitWidth>
            </field>
            <field>
              <name>COREID</name>
              <bitOffset>8</bitOffset>
              <bitWidth>8</bitWidth>
            </field>
            <field>
              <name>LOCK</name>
              <bitOffset>31</bitOffset>
              <bitWidth>1</bitWidth>
            </field>
          </fields>
        </register>
        <register>
          <name>R.25</name>
          <addressOffset>0x64</addressOffset>
          <size>0x20</size>
          <fields>
            <field>
              <name>PROCID</name>
              <bitOffset>0</bitOffset>
              <bitWidth>8</bitWidth>
            </field>
            <field>
              <name>COREID</name>
              <bitOffset>8</bitOffset>
              <bitWidth>8</bitWidth>
            </field>
            <field>
              <name>LOCK</name>
              <bitOffset>31</bitOffset>
              <bitWidth>1</bitWidth>
            </field>
          </fields>
        </register>
        <register>
          <name>R.26</name>
          <addressOffset>0x68</addressOffset>
          <size>0x20</size>
          <fields>
            <field>
              <name>PROCID</name>
              <bitOffset>0</bitOffset>
              <bitWidth>8</bitWidth>
            </field>
            <field>
              <name>COREID</name>
              <bitOffset>8</bitOffset>
              <bitWidth>8</bitWidth>
            </field>
            <field>
              <name>LOCK</name>
              <bitOffset>31</bitOffset>
              <bitWidth>1</bitWidth>
            </field>
          </fields>
        </register>
        <register>
          <name>R.27</name>
          <addressOffset>0x6c</addressOffset>
          <size>0x20</size>
          <fields>
            <field>
              <name>PROCID</name>
              <bitOffset>0</bitOffset>
              <bitWidth>8</bitWidth>
            </field>
            <field>
              <name>COREID</name>
              <bitOffset>8</bitOffset>
              <bitWidth>8</bitWidth>
            </field>
            <field>
              <name>LOCK</name>
              <bitOffset>31</bitOffset>
              <bitWidth>1</bitWidth>
            </field>
          </fields>
        </register>
        <register>
          <name>R.28</name>
          <addressOffset>0x70</addressOffset>
          <size>0x20</size>
          <fields>
            <field>
              <name>PROCID</name>
              <bitOffset>0</bitOffset>
              <bitWidth>8</bitWidth>
            </field>
            <field>
              <name>COREID</name>
              <bitOffset>8</bitOffset>
              <bitWidth>8</bitWidth>
            </field>
            <field>
              <name>LOCK</name>
              <bitOffset>31</bitOffset>
              <bitWidth>1</bitWidth>
            </field>
          </fields>
        </register>
        <register>
          <name>R.29</name>
          <addressOffset>0x74</addressOffset>
          <size>0x20</size>
          <fields>
            <field>
              <name>PROCID</name>
              <bitOffset>0</bitOffset>
              <bitWidth>8</bitWidth>
            </field>
            <field>
              <name>COREID</name>
              <bitOffset>8</bitOffset>
              <bitWidth>8</bitWidth>
            </field>
            <field>
              <name>LOCK</name>
              <bitOffset>31</bitOffset>
              <bitWidth>1</bitWidth>
            </field>
          </fields>
        </register>
        <register>
          <name>R.30</name>
          <addressOffset>0x78</addressOffset>
          <size>0x20</size>
          <fields>
            <field>
              <name>PROCID</name>
              <bitOffset>0</bitOffset>
              <bitWidth>8</bitWidth>
            </field>
            <field>
              <name>COREID</name>
              <bitOffset>8</bitOffset>
              <bitWidth>8</bitWidth>
            </field>
            <field>
              <name>LOCK</name>
              <bitOffset>31</bitOffset>
              <bitWidth>1</bitWidth>
            </field>
          </fields>
        </register>
        <register>
          <name>R.31</name>
          <addressOffset>0x7c</addressOffset>
          <size>0x20</size>
          <fields>
            <field>
              <name>PROCID</name>
              <bitOffset>0</bitOffset>
              <bitWidth>8</bitWidth>
            </field>
            <field>
              <name>COREID</name>
              <bitOffset>8</bitOffset>
              <bitWidth>8</bitWidth>
            </field>
            <field>
              <name>LOCK</name>
              <bitOffset>31</bitOffset>
              <bitWidth>1</bitWidth>
            </field>
          </fields>
        </register>
        <register>
          <name>RLR.0</name>
          <addressOffset>0x80</addressOffset>
          <size>0x20</size>
          <fields>
            <field>
              <name>PROCID</name>
              <bitOffset>0</bitOffset>
              <bitWidth>8</bitWidth>
            </field>
            <field>
              <name>COREID</name>
              <bitOffset>8</bitOffset>
              <bitWidth>8</bitWidth>
            </field>
            <field>
              <name>LOCK</name>
              <bitOffset>31</bitOffset>
              <bitWidth>1</bitWidth>
            </field>
          </fields>
        </register>
        <register>
          <name>RLR.1</name>
          <addressOffset>0x84</addressOffset>
          <size>0x20</size>
          <fields>
            <field>
              <name>PROCID</name>
              <bitOffset>0</bitOffset>
              <bitWidth>8</bitWidth>
            </field>
            <field>
              <name>COREID</name>
              <bitOffset>8</bitOffset>
              <bitWidth>8</bitWidth>
            </field>
            <field>
              <name>LOCK</name>
              <bitOffset>31</bitOffset>
              <bitWidth>1</bitWidth>
            </field>
          </fields>
        </register>
        <register>
          <name>RLR.2</name>
          <addressOffset>0x88</addressOffset>
          <size>0x20</size>
          <fields>
            <field>
              <name>PROCID</name>
              <bitOffset>0</bitOffset>
              <bitWidth>8</bitWidth>
            </field>
            <field>
              <name>COREID</name>
              <bitOffset>8</bitOffset>
              <bitWidth>8</bitWidth>
            </field>
            <field>
              <name>LOCK</name>
              <bitOffset>31</bitOffset>
              <bitWidth>1</bitWidth>
            </field>
          </fields>
        </register>
        <register>
          <name>RLR.3</name>
          <addressOffset>0x8c</addressOffset>
          <size>0x20</size>
          <fields>
            <field>
              <name>PROCID</name>
              <bitOffset>0</bitOffset>
              <bitWidth>8</bitWidth>
            </field>
            <field>
              <name>COREID</name>
              <bitOffset>8</bitOffset>
              <bitWidth>8</bitWidth>
            </field>
            <field>
              <name>LOCK</name>
              <bitOffset>31</bitOffset>
              <bitWidth>1</bitWidth>
            </field>
          </fields>
        </register>
        <register>
          <name>RLR.4</name>
          <addressOffset>0x90</addressOffset>
          <size>0x20</size>
          <fields>
            <field>
              <name>PROCID</name>
              <bitOffset>0</bitOffset>
              <bitWidth>8</bitWidth>
            </field>
            <field>
              <name>COREID</name>
              <bitOffset>8</bitOffset>
              <bitWidth>8</bitWidth>
            </field>
            <field>
              <name>LOCK</name>
              <bitOffset>31</bitOffset>
              <bitWidth>1</bitWidth>
            </field>
          </fields>
        </register>
        <register>
          <name>RLR.5</name>
          <addressOffset>0x94</addressOffset>
          <size>0x20</size>
          <fields>
            <field>
              <name>PROCID</name>
              <bitOffset>0</bitOffset>
              <bitWidth>8</bitWidth>
            </field>
            <field>
              <name>COREID</name>
              <bitOffset>8</bitOffset>
              <bitWidth>8</bitWidth>
            </field>
            <field>
              <name>LOCK</name>
              <bitOffset>31</bitOffset>
              <bitWidth>1</bitWidth>
            </field>
          </fields>
        </register>
        <register>
          <name>RLR.6</name>
          <addressOffset>0x98</addressOffset>
          <size>0x20</size>
          <fields>
            <field>
              <name>PROCID</name>
              <bitOffset>0</bitOffset>
              <bitWidth>8</bitWidth>
            </field>
            <field>
              <name>COREID</name>
              <bitOffset>8</bitOffset>
              <bitWidth>8</bitWidth>
            </field>
            <field>
              <name>LOCK</name>
              <bitOffset>31</bitOffset>
              <bitWidth>1</bitWidth>
            </field>
          </fields>
        </register>
        <register>
          <name>RLR.7</name>
          <addressOffset>0x9c</addressOffset>
          <size>0x20</size>
          <fields>
            <field>
              <name>PROCID</name>
              <bitOffset>0</bitOffset>
              <bitWidth>8</bitWidth>
            </field>
            <field>
              <name>COREID</name>
              <bitOffset>8</bitOffset>
              <bitWidth>8</bitWidth>
            </field>
            <field>
              <name>LOCK</name>
              <bitOffset>31</bitOffset>
              <bitWidth>1</bitWidth>
            </field>
          </fields>
        </register>
        <register>
          <name>RLR.8</name>
          <addressOffset>0xa0</addressOffset>
          <size>0x20</size>
          <fields>
            <field>
              <name>PROCID</name>
              <bitOffset>0</bitOffset>
              <bitWidth>8</bitWidth>
            </field>
            <field>
              <name>COREID</name>
              <bitOffset>8</bitOffset>
              <bitWidth>8</bitWidth>
            </field>
            <field>
              <name>LOCK</name>
              <bitOffset>31</bitOffset>
              <bitWidth>1</bitWidth>
            </field>
          </fields>
        </register>
        <register>
          <name>RLR.9</name>
          <addressOffset>0xa4</addressOffset>
          <size>0x20</size>
          <fields>
            <field>
              <name>PROCID</name>
              <bitOffset>0</bitOffset>
              <bitWidth>8</bitWidth>
            </field>
            <field>
              <name>COREID</name>
              <bitOffset>8</bitOffset>
              <bitWidth>8</bitWidth>
            </field>
            <field>
              <name>LOCK</name>
              <bitOffset>31</bitOffset>
              <bitWidth>1</bitWidth>
            </field>
          </fields>
        </register>
        <register>
          <name>RLR.10</name>
          <addressOffset>0xa8</addressOffset>
          <size>0x20</size>
          <fields>
            <field>
              <name>PROCID</name>
              <bitOffset>0</bitOffset>
              <bitWidth>8</bitWidth>
            </field>
            <field>
              <name>COREID</name>
              <bitOffset>8</bitOffset>
              <bitWidth>8</bitWidth>
            </field>
            <field>
              <name>LOCK</name>
              <bitOffset>31</bitOffset>
              <bitWidth>1</bitWidth>
            </field>
          </fields>
        </register>
        <register>
          <name>RLR.11</name>
          <addressOffset>0xac</addressOffset>
          <size>0x20</size>
          <fields>
            <field>
              <name>PROCID</name>
              <bitOffset>0</bitOffset>
              <bitWidth>8</bitWidth>
            </field>
            <field>
              <name>COREID</name>
              <bitOffset>8</bitOffset>
              <bitWidth>8</bitWidth>
            </field>
            <field>
              <name>LOCK</name>
              <bitOffset>31</bitOffset>
              <bitWidth>1</bitWidth>
            </field>
          </fields>
        </register>
        <register>
          <name>RLR.12</name>
          <addressOffset>0xb0</addressOffset>
          <size>0x20</size>
          <fields>
            <field>
              <name>PROCID</name>
              <bitOffset>0</bitOffset>
              <bitWidth>8</bitWidth>
            </field>
            <field>
              <name>COREID</name>
              <bitOffset>8</bitOffset>
              <bitWidth>8</bitWidth>
            </field>
            <field>
              <name>LOCK</name>
              <bitOffset>31</bitOffset>
              <bitWidth>1</bitWidth>
            </field>
          </fields>
        </register>
        <register>
          <name>RLR.13</name>
          <addressOffset>0xb4</addressOffset>
          <size>0x20</size>
          <fields>
            <field>
              <name>PROCID</name>
              <bitOffset>0</bitOffset>
              <bitWidth>8</bitWidth>
            </field>
            <field>
              <name>COREID</name>
              <bitOffset>8</bitOffset>
              <bitWidth>8</bitWidth>
            </field>
            <field>
              <name>LOCK</name>
              <bitOffset>31</bitOffset>
              <bitWidth>1</bitWidth>
            </field>
          </fields>
        </register>
        <register>
          <name>RLR.14</name>
          <addressOffset>0xb8</addressOffset>
          <size>0x20</size>
          <fields>
            <field>
              <name>PROCID</name>
              <bitOffset>0</bitOffset>
              <bitWidth>8</bitWidth>
            </field>
            <field>
              <name>COREID</name>
              <bitOffset>8</bitOffset>
              <bitWidth>8</bitWidth>
            </field>
            <field>
              <name>LOCK</name>
              <bitOffset>31</bitOffset>
              <bitWidth>1</bitWidth>
            </field>
          </fields>
        </register>
        <register>
          <name>RLR.15</name>
          <addressOffset>0xbc</addressOffset>
          <size>0x20</size>
          <fields>
            <field>
              <name>PROCID</name>
              <bitOffset>0</bitOffset>
              <bitWidth>8</bitWidth>
            </field>
            <field>
              <name>COREID</name>
              <bitOffset>8</bitOffset>
              <bitWidth>8</bitWidth>
            </field>
            <field>
              <name>LOCK</name>
              <bitOffset>31</bitOffset>
              <bitWidth>1</bitWidth>
            </field>
          </fields>
        </register>
        <register>
          <name>RLR.16</name>
          <addressOffset>0xc0</addressOffset>
          <size>0x20</size>
          <fields>
            <field>
              <name>PROCID</name>
              <bitOffset>0</bitOffset>
              <bitWidth>8</bitWidth>
            </field>
            <field>
              <name>COREID</name>
              <bitOffset>8</bitOffset>
              <bitWidth>8</bitWidth>
            </field>
            <field>
              <name>LOCK</name>
              <bitOffset>31</bitOffset>
              <bitWidth>1</bitWidth>
            </field>
          </fields>
        </register>
        <register>
          <name>RLR.17</name>
          <addressOffset>0xc4</addressOffset>
          <size>0x20</size>
          <fields>
            <field>
              <name>PROCID</name>
              <bitOffset>0</bitOffset>
              <bitWidth>8</bitWidth>
            </field>
            <field>
              <name>COREID</name>
              <bitOffset>8</bitOffset>
              <bitWidth>8</bitWidth>
            </field>
            <field>
              <name>LOCK</name>
              <bitOffset>31</bitOffset>
              <bitWidth>1</bitWidth>
            </field>
          </fields>
        </register>
        <register>
          <name>RLR.18</name>
          <addressOffset>0xc8</addressOffset>
          <size>0x20</size>
          <fields>
            <field>
              <name>PROCID</name>
              <bitOffset>0</bitOffset>
              <bitWidth>8</bitWidth>
            </field>
            <field>
              <name>COREID</name>
              <bitOffset>8</bitOffset>
              <bitWidth>8</bitWidth>
            </field>
            <field>
              <name>LOCK</name>
              <bitOffset>31</bitOffset>
              <bitWidth>1</bitWidth>
            </field>
          </fields>
        </register>
        <register>
          <name>RLR.19</name>
          <addressOffset>0xcc</addressOffset>
          <size>0x20</size>
          <fields>
            <field>
              <name>PROCID</name>
              <bitOffset>0</bitOffset>
              <bitWidth>8</bitWidth>
            </field>
            <field>
              <name>COREID</name>
              <bitOffset>8</bitOffset>
              <bitWidth>8</bitWidth>
            </field>
            <field>
              <name>LOCK</name>
              <bitOffset>31</bitOffset>
              <bitWidth>1</bitWidth>
            </field>
          </fields>
        </register>
        <register>
          <name>RLR.20</name>
          <addressOffset>0xd0</addressOffset>
          <size>0x20</size>
          <fields>
            <field>
              <name>PROCID</name>
              <bitOffset>0</bitOffset>
              <bitWidth>8</bitWidth>
            </field>
            <field>
              <name>COREID</name>
              <bitOffset>8</bitOffset>
              <bitWidth>8</bitWidth>
            </field>
            <field>
              <name>LOCK</name>
              <bitOffset>31</bitOffset>
              <bitWidth>1</bitWidth>
            </field>
          </fields>
        </register>
        <register>
          <name>RLR.21</name>
          <addressOffset>0xd4</addressOffset>
          <size>0x20</size>
          <fields>
            <field>
              <name>PROCID</name>
              <bitOffset>0</bitOffset>
              <bitWidth>8</bitWidth>
            </field>
            <field>
              <name>COREID</name>
              <bitOffset>8</bitOffset>
              <bitWidth>8</bitWidth>
            </field>
            <field>
              <name>LOCK</name>
              <bitOffset>31</bitOffset>
              <bitWidth>1</bitWidth>
            </field>
          </fields>
        </register>
        <register>
          <name>RLR.22</name>
          <addressOffset>0xd8</addressOffset>
          <size>0x20</size>
          <fields>
            <field>
              <name>PROCID</name>
              <bitOffset>0</bitOffset>
              <bitWidth>8</bitWidth>
            </field>
            <field>
              <name>COREID</name>
              <bitOffset>8</bitOffset>
              <bitWidth>8</bitWidth>
            </field>
            <field>
              <name>LOCK</name>
              <bitOffset>31</bitOffset>
              <bitWidth>1</bitWidth>
            </field>
          </fields>
        </register>
        <register>
          <name>RLR.23</name>
          <addressOffset>0xdc</addressOffset>
          <size>0x20</size>
          <fields>
            <field>
              <name>PROCID</name>
              <bitOffset>0</bitOffset>
              <bitWidth>8</bitWidth>
            </field>
            <field>
              <name>COREID</name>
              <bitOffset>8</bitOffset>
              <bitWidth>8</bitWidth>
            </field>
            <field>
              <name>LOCK</name>
              <bitOffset>31</bitOffset>
              <bitWidth>1</bitWidth>
            </field>
          </fields>
        </register>
        <register>
          <name>RLR.24</name>
          <addressOffset>0xe0</addressOffset>
          <size>0x20</size>
          <fields>
            <field>
              <name>PROCID</name>
              <bitOffset>0</bitOffset>
              <bitWidth>8</bitWidth>
            </field>
            <field>
              <name>COREID</name>
              <bitOffset>8</bitOffset>
              <bitWidth>8</bitWidth>
            </field>
            <field>
              <name>LOCK</name>
              <bitOffset>31</bitOffset>
              <bitWidth>1</bitWidth>
            </field>
          </fields>
        </register>
        <register>
          <name>RLR.25</name>
          <addressOffset>0xe4</addressOffset>
          <size>0x20</size>
          <fields>
            <field>
              <name>PROCID</name>
              <bitOffset>0</bitOffset>
              <bitWidth>8</bitWidth>
            </field>
            <field>
              <name>COREID</name>
              <bitOffset>8</bitOffset>
              <bitWidth>8</bitWidth>
            </field>
            <field>
              <name>LOCK</name>
              <bitOffset>31</bitOffset>
              <bitWidth>1</bitWidth>
            </field>
          </fields>
        </register>
        <register>
          <name>RLR.26</name>
          <addressOffset>0xe8</addressOffset>
          <size>0x20</size>
          <fields>
            <field>
              <name>PROCID</name>
              <bitOffset>0</bitOffset>
              <bitWidth>8</bitWidth>
            </field>
            <field>
              <name>COREID</name>
              <bitOffset>8</bitOffset>
              <bitWidth>8</bitWidth>
            </field>
            <field>
              <name>LOCK</name>
              <bitOffset>31</bitOffset>
              <bitWidth>1</bitWidth>
            </field>
          </fields>
        </register>
        <register>
          <name>RLR.27</name>
          <addressOffset>0xec</addressOffset>
          <size>0x20</size>
          <fields>
            <field>
              <name>PROCID</name>
              <bitOffset>0</bitOffset>
              <bitWidth>8</bitWidth>
            </field>
            <field>
              <name>COREID</name>
              <bitOffset>8</bitOffset>
              <bitWidth>8</bitWidth>
            </field>
            <field>
              <name>LOCK</name>
              <bitOffset>31</bitOffset>
              <bitWidth>1</bitWidth>
            </field>
          </fields>
        </register>
        <register>
          <name>RLR.28</name>
          <addressOffset>0xf0</addressOffset>
          <size>0x20</size>
          <fields>
            <field>
              <name>PROCID</name>
              <bitOffset>0</bitOffset>
              <bitWidth>8</bitWidth>
            </field>
            <field>
              <name>COREID</name>
              <bitOffset>8</bitOffset>
              <bitWidth>8</bitWidth>
            </field>
            <field>
              <name>LOCK</name>
              <bitOffset>31</bitOffset>
              <bitWidth>1</bitWidth>
            </field>
          </fields>
        </register>
        <register>
          <name>RLR.29</name>
          <addressOffset>0xf4</addressOffset>
          <size>0x20</size>
          <fields>
            <field>
              <name>PROCID</name>
              <bitOffset>0</bitOffset>
              <bitWidth>8</bitWidth>
            </field>
            <field>
              <name>COREID</name>
              <bitOffset>8</bitOffset>
              <bitWidth>8</bitWidth>
            </field>
            <field>
              <name>LOCK</name>
              <bitOffset>31</bitOffset>
              <bitWidth>1</bitWidth>
            </field>
          </fields>
        </register>
        <register>
          <name>RLR.30</name>
          <addressOffset>0xf8</addressOffset>
          <size>0x20</size>
          <fields>
            <field>
              <name>PROCID</name>
              <bitOffset>0</bitOffset>
              <bitWidth>8</bitWidth>
            </field>
            <field>
              <name>COREID</name>
              <bitOffset>8</bitOffset>
              <bitWidth>8</bitWidth>
            </field>
            <field>
              <name>LOCK</name>
              <bitOffset>31</bitOffset>
              <bitWidth>1</bitWidth>
            </field>
          </fields>
        </register>
        <register>
          <name>RLR.31</name>
          <addressOffset>0xfc</addressOffset>
          <size>0x20</size>
          <fields>
            <field>
              <name>PROCID</name>
              <bitOffset>0</bitOffset>
              <bitWidth>8</bitWidth>
            </field>
            <field>
              <name>COREID</name>
              <bitOffset>8</bitOffset>
              <bitWidth>8</bitWidth>
            </field>
            <field>
              <name>LOCK</name>
              <bitOffset>31</bitOffset>
              <bitWidth>1</bitWidth>
            </field>
          </fields>
        </register>
        <register>
          <name>C1IER</name>
          <addressOffset>0x100</addressOffset>
          <size>0x20</size>
          <fields>
            <field>
              <name>ISE0</name>
              <bitOffset>0</bitOffset>
              <bitWidth>1</bitWidth>
            </field>
            <field>
              <name>ISE1</name>
              <bitOffset>1</bitOffset>
              <bitWidth>1</bitWidth>
            </field>
            <field>
              <name>ISE2</name>
              <bitOffset>2</bitOffset>
              <bitWidth>1</bitWidth>
            </field>
            <field>
              <name>ISE3</name>
              <bitOffset>3</bitOffset>
              <bitWidth>1</bitWidth>
            </field>
            <field>
              <name>ISE4</name>
              <bitOffset>4</bitOffset>
              <bitWidth>1</bitWidth>
            </field>
            <field>
              <name>ISE5</name>
              <bitOffset>5</bitOffset>
              <bitWidth>1</bitWidth>
            </field>
            <field>
              <name>ISE6</name>
              <bitOffset>6</bitOffset>
              <bitWidth>1</bitWidth>
            </field>
            <field>
              <name>ISE7</name>
              <bitOffset>7</bitOffset>
              <bitWidth>1</bitWidth>
            </field>
            <field>
              <name>ISE8</name>
              <bitOffset>8</bitOffset>
              <bitWidth>1</bitWidth>
            </field>
            <field>
              <name>ISE9</name>
              <bitOffset>9</bitOffset>
              <bitWidth>1</bitWidth>
            </field>
            <field>
              <name>ISE10</name>
              <bitOffset>10</bitOffset>
              <bitWidth>1</bitWidth>
            </field>
            <field>
              <name>ISE11</name>
              <bitOffset>11</bitOffset>
              <bitWidth>1</bitWidth>
            </field>
            <field>
              <name>ISE12</name>
              <bitOffset>12</bitOffset>
              <bitWidth>1</bitWidth>
            </field>
            <field>
              <name>ISE13</name>
              <bitOffset>13</bitOffset>
              <bitWidth>1</bitWidth>
            </field>
            <field>
              <name>ISE14</name>
              <bitOffset>14</bitOffset>
              <bitWidth>1</bitWidth>
            </field>
            <field>
              <name>ISE15</name>
              <bitOffset>15</bitOffset>
              <bitWidth>1</bitWidth>
            </field>
            <field>
              <name>ISE16</name>
              <bitOffset>16</bitOffset>
              <bitWidth>1</bitWidth>
            </field>
            <field>
              <name>ISE17</name>
              <bitOffset>17</bitOffset>
              <bitWidth>1</bitWidth>
            </field>
            <field>
              <name>ISE18</name>
              <bitOffset>18</bitOffset>
              <bitWidth>1</bitWidth>
            </field>
            <field>
              <name>ISE19</name>
              <bitOffset>19</bitOffset>
              <bitWidth>1</bitWidth>
            </field>
            <field>
              <name>ISE20</name>
              <bitOffset>20</bitOffset>
              <bitWidth>1</bitWidth>
            </field>
            <field>
              <name>ISE21</name>
              <bitOffset>21</bitOffset>
              <bitWidth>1</bitWidth>
            </field>
            <field>
              <name>ISE22</name>
              <bitOffset>22</bitOffset>
              <bitWidth>1</bitWidth>
            </field>
            <field>
              <name>ISE23</name>
              <bitOffset>23</bitOffset>
              <bitWidth>1</bitWidth>
            </field>
            <field>
              <name>ISE24</name>
              <bitOffset>24</bitOffset>
              <bitWidth>1</bitWidth>
            </field>
            <field>
              <name>ISE25</name>
              <bitOffset>25</bitOffset>
              <bitWidth>1</bitWidth>
            </field>
            <field>
              <name>ISE26</name>
              <bitOffset>26</bitOffset>
              <bitWidth>1</bitWidth>
            </field>
            <field>
              <name>ISE27</name>
              <bitOffset>27</bitOffset>
              <bitWidth>1</bitWidth>
            </field>
            <field>
              <name>ISE28</name>
              <bitOffset>28</bitOffset>
              <bitWidth>1</bitWidth>
            </field>
            <field>
              <name>ISE29</name>
              <bitOffset>29</bitOffset>
              <bitWidth>1</bitWidth>
            </field>
            <field>
              <name>ISE30</name>
              <bitOffset>30</bitOffset>
              <bitWidth>1</bitWidth>
            </field>
            <field>
              <name>ISE31</name>
              <bitOffset>31</bitOffset>
              <bitWidth>1</bitWidth>
            </field>
          </fields>
        </register>
        <register>
          <name>C1ICR</name>
          <addressOffset>0x104</addressOffset>
          <size>0x20</size>
          <fields>
            <field>
              <name>ISC0</name>
              <bitOffset>0</bitOffset>
              <bitWidth>1</bitWidth>
            </field>
            <field>
              <name>ISC1</name>
              <bitOffset>1</bitOffset>
              <bitWidth>1</bitWidth>
            </field>
            <field>
              <name>ISC2</name>
              <bitOffset>2</bitOffset>
              <bitWidth>1</bitWidth>
            </field>
            <field>
              <name>ISC3</name>
              <bitOffset>3</bitOffset>
              <bitWidth>1</bitWidth>
            </field>
            <field>
              <name>ISC4</name>
              <bitOffset>4</bitOffset>
              <bitWidth>1</bitWidth>
            </field>
            <field>
              <name>ISC5</name>
              <bitOffset>5</bitOffset>
              <bitWidth>1</bitWidth>
            </field>
            <field>
              <name>ISC6</name>
              <bitOffset>6</bitOffset>
              <bitWidth>1</bitWidth>
            </field>
            <field>
              <name>ISC7</name>
              <bitOffset>7</bitOffset>
              <bitWidth>1</bitWidth>
            </field>
            <field>
              <name>ISC8</name>
              <bitOffset>8</bitOffset>
              <bitWidth>1</bitWidth>
            </field>
            <field>
              <name>ISC9</name>
              <bitOffset>9</bitOffset>
              <bitWidth>1</bitWidth>
            </field>
            <field>
              <name>ISC10</name>
              <bitOffset>10</bitOffset>
              <bitWidth>1</bitWidth>
            </field>
            <field>
              <name>ISC11</name>
              <bitOffset>11</bitOffset>
              <bitWidth>1</bitWidth>
            </field>
            <field>
              <name>ISC12</name>
              <bitOffset>12</bitOffset>
              <bitWidth>1</bitWidth>
            </field>
            <field>
              <name>ISC13</name>
              <bitOffset>13</bitOffset>
              <bitWidth>1</bitWidth>
            </field>
            <field>
              <name>ISC14</name>
              <bitOffset>14</bitOffset>
              <bitWidth>1</bitWidth>
            </field>
            <field>
              <name>ISC15</name>
              <bitOffset>15</bitOffset>
              <bitWidth>1</bitWidth>
            </field>
            <field>
              <name>ISC16</name>
              <bitOffset>16</bitOffset>
              <bitWidth>1</bitWidth>
            </field>
            <field>
              <name>ISC17</name>
              <bitOffset>17</bitOffset>
              <bitWidth>1</bitWidth>
            </field>
            <field>
              <name>ISC18</name>
              <bitOffset>18</bitOffset>
              <bitWidth>1</bitWidth>
            </field>
            <field>
              <name>ISC19</name>
              <bitOffset>19</bitOffset>
              <bitWidth>1</bitWidth>
            </field>
            <field>
              <name>ISC20</name>
              <bitOffset>20</bitOffset>
              <bitWidth>1</bitWidth>
            </field>
            <field>
              <name>ISC21</name>
              <bitOffset>21</bitOffset>
              <bitWidth>1</bitWidth>
            </field>
            <field>
              <name>ISC22</name>
              <bitOffset>22</bitOffset>
              <bitWidth>1</bitWidth>
            </field>
            <field>
              <name>ISC23</name>
              <bitOffset>23</bitOffset>
              <bitWidth>1</bitWidth>
            </field>
            <field>
              <name>ISC24</name>
              <bitOffset>24</bitOffset>
              <bitWidth>1</bitWidth>
            </field>
            <field>
              <name>ISC25</name>
              <bitOffset>25</bitOffset>
              <bitWidth>1</bitWidth>
            </field>
            <field>
              <name>ISC26</name>
              <bitOffset>26</bitOffset>
              <bitWidth>1</bitWidth>
            </field>
            <field>
              <name>ISC27</name>
              <bitOffset>27</bitOffset>
              <bitWidth>1</bitWidth>
            </field>
            <field>
              <name>ISC28</name>
              <bitOffset>28</bitOffset>
              <bitWidth>1</bitWidth>
            </field>
            <field>
              <name>ISC29</name>
              <bitOffset>29</bitOffset>
              <bitWidth>1</bitWidth>
            </field>
            <field>
              <name>ISC30</name>
              <bitOffset>30</bitOffset>
              <bitWidth>1</bitWidth>
            </field>
            <field>
              <name>ISC31</name>
              <bitOffset>31</bitOffset>
              <bitWidth>1</bitWidth>
            </field>
          </fields>
        </register>
        <register>
          <name>C1ISR</name>
          <addressOffset>0x108</addressOffset>
          <size>0x20</size>
          <fields>
            <field>
              <name>ISF0</name>
              <bitOffset>0</bitOffset>
              <bitWidth>1</bitWidth>
            </field>
            <field>
              <name>ISF1</name>
              <bitOffset>1</bitOffset>
              <bitWidth>1</bitWidth>
            </field>
            <field>
              <name>ISF2</name>
              <bitOffset>2</bitOffset>
              <bitWidth>1</bitWidth>
            </field>
            <field>
              <name>ISF3</name>
              <bitOffset>3</bitOffset>
              <bitWidth>1</bitWidth>
            </field>
            <field>
              <name>ISF4</name>
              <bitOffset>4</bitOffset>
              <bitWidth>1</bitWidth>
            </field>
            <field>
              <name>ISF5</name>
              <bitOffset>5</bitOffset>
              <bitWidth>1</bitWidth>
            </field>
            <field>
              <name>ISF6</name>
              <bitOffset>6</bitOffset>
              <bitWidth>1</bitWidth>
            </field>
            <field>
              <name>ISF7</name>
              <bitOffset>7</bitOffset>
              <bitWidth>1</bitWidth>
            </field>
            <field>
              <name>ISF8</name>
              <bitOffset>8</bitOffset>
              <bitWidth>1</bitWidth>
            </field>
            <field>
              <name>ISF9</name>
              <bitOffset>9</bitOffset>
              <bitWidth>1</bitWidth>
            </field>
            <field>
              <name>ISF10</name>
              <bitOffset>10</bitOffset>
              <bitWidth>1</bitWidth>
            </field>
            <field>
              <name>ISF11</name>
              <bitOffset>11</bitOffset>
              <bitWidth>1</bitWidth>
            </field>
            <field>
              <name>ISF12</name>
              <bitOffset>12</bitOffset>
              <bitWidth>1</bitWidth>
            </field>
            <field>
              <name>ISF13</name>
              <bitOffset>13</bitOffset>
              <bitWidth>1</bitWidth>
            </field>
            <field>
              <name>ISF14</name>
              <bitOffset>14</bitOffset>
              <bitWidth>1</bitWidth>
            </field>
            <field>
              <name>ISF15</name>
              <bitOffset>15</bitOffset>
              <bitWidth>1</bitWidth>
            </field>
            <field>
              <name>ISF16</name>
              <bitOffset>16</bitOffset>
              <bitWidth>1</bitWidth>
            </field>
            <field>
              <name>ISF17</name>
              <bitOffset>17</bitOffset>
              <bitWidth>1</bitWidth>
            </field>
            <field>
              <name>ISF18</name>
              <bitOffset>18</bitOffset>
              <bitWidth>1</bitWidth>
            </field>
            <field>
              <name>ISF19</name>
              <bitOffset>19</bitOffset>
              <bitWidth>1</bitWidth>
            </field>
            <field>
              <name>ISF20</name>
              <bitOffset>20</bitOffset>
              <bitWidth>1</bitWidth>
            </field>
            <field>
              <name>ISF21</name>
              <bitOffset>21</bitOffset>
              <bitWidth>1</bitWidth>
            </field>
            <field>
              <name>ISF22</name>
              <bitOffset>22</bitOffset>
              <bitWidth>1</bitWidth>
            </field>
            <field>
              <name>ISF23</name>
              <bitOffset>23</bitOffset>
              <bitWidth>1</bitWidth>
            </field>
            <field>
              <name>ISF24</name>
              <bitOffset>24</bitOffset>
              <bitWidth>1</bitWidth>
            </field>
            <field>
              <name>ISF25</name>
              <bitOffset>25</bitOffset>
              <bitWidth>1</bitWidth>
            </field>
            <field>
              <name>ISF26</name>
              <bitOffset>26</bitOffset>
              <bitWidth>1</bitWidth>
            </field>
            <field>
              <name>ISF27</name>
              <bitOffset>27</bitOffset>
              <bitWidth>1</bitWidth>
            </field>
            <field>
              <name>ISF28</name>
              <bitOffset>28</bitOffset>
              <bitWidth>1</bitWidth>
            </field>
            <field>
              <name>ISF29</name>
              <bitOffset>29</bitOffset>
              <bitWidth>1</bitWidth>
            </field>
            <field>
              <name>ISF30</name>
              <bitOffset>30</bitOffset>
              <bitWidth>1</bitWidth>
            </field>
            <field>
              <name>ISF31</name>
              <bitOffset>31</bitOffset>
              <bitWidth>1</bitWidth>
            </field>
          </fields>
        </register>
        <register>
          <name>C1MISR</name>
          <addressOffset>0x10c</addressOffset>
          <size>0x20</size>
          <fields>
            <field>
              <name>MISF0</name>
              <bitOffset>0</bitOffset>
              <bitWidth>1</bitWidth>
            </field>
            <field>
              <name>MISF1</name>
              <bitOffset>1</bitOffset>
              <bitWidth>1</bitWidth>
            </field>
            <field>
              <name>MISF2</name>
              <bitOffset>2</bitOffset>
              <bitWidth>1</bitWidth>
            </field>
            <field>
              <name>MISF3</name>
              <bitOffset>3</bitOffset>
              <bitWidth>1</bitWidth>
            </field>
            <field>
              <name>MISF4</name>
              <bitOffset>4</bitOffset>
              <bitWidth>1</bitWidth>
            </field>
            <field>
              <name>MISF5</name>
              <bitOffset>5</bitOffset>
              <bitWidth>1</bitWidth>
            </field>
            <field>
              <name>MISF6</name>
              <bitOffset>6</bitOffset>
              <bitWidth>1</bitWidth>
            </field>
            <field>
              <name>MISF7</name>
              <bitOffset>7</bitOffset>
              <bitWidth>1</bitWidth>
            </field>
            <field>
              <name>MISF8</name>
              <bitOffset>8</bitOffset>
              <bitWidth>1</bitWidth>
            </field>
            <field>
              <name>MISF9</name>
              <bitOffset>9</bitOffset>
              <bitWidth>1</bitWidth>
            </field>
            <field>
              <name>MISF10</name>
              <bitOffset>10</bitOffset>
              <bitWidth>1</bitWidth>
            </field>
            <field>
              <name>MISF11</name>
              <bitOffset>11</bitOffset>
              <bitWidth>1</bitWidth>
            </field>
            <field>
              <name>MISF12</name>
              <bitOffset>12</bitOffset>
              <bitWidth>1</bitWidth>
            </field>
            <field>
              <name>MISF13</name>
              <bitOffset>13</bitOffset>
              <bitWidth>1</bitWidth>
            </field>
            <field>
              <name>MISF14</name>
              <bitOffset>14</bitOffset>
              <bitWidth>1</bitWidth>
            </field>
            <field>
              <name>MISF15</name>
              <bitOffset>15</bitOffset>
              <bitWidth>1</bitWidth>
            </field>
            <field>
              <name>MISF16</name>
              <bitOffset>16</bitOffset>
              <bitWidth>1</bitWidth>
            </field>
            <field>
              <name>MISF17</name>
              <bitOffset>17</bitOffset>
              <bitWidth>1</bitWidth>
            </field>
            <field>
              <name>MISF18</name>
              <bitOffset>18</bitOffset>
              <bitWidth>1</bitWidth>
            </field>
            <field>
              <name>MISF19</name>
              <bitOffset>19</bitOffset>
              <bitWidth>1</bitWidth>
            </field>
            <field>
              <name>MISF20</name>
              <bitOffset>20</bitOffset>
              <bitWidth>1</bitWidth>
            </field>
            <field>
              <name>MISF21</name>
              <bitOffset>21</bitOffset>
              <bitWidth>1</bitWidth>
            </field>
            <field>
              <name>MISF22</name>
              <bitOffset>22</bitOffset>
              <bitWidth>1</bitWidth>
            </field>
            <field>
              <name>MISF23</name>
              <bitOffset>23</bitOffset>
              <bitWidth>1</bitWidth>
            </field>
            <field>
              <name>MISF24</name>
              <bitOffset>24</bitOffset>
              <bitWidth>1</bitWidth>
            </field>
            <field>
              <name>MISF25</name>
              <bitOffset>25</bitOffset>
              <bitWidth>1</bitWidth>
            </field>
            <field>
              <name>MISF26</name>
              <bitOffset>26</bitOffset>
              <bitWidth>1</bitWidth>
            </field>
            <field>
              <name>MISF27</name>
              <bitOffset>27</bitOffset>
              <bitWidth>1</bitWidth>
            </field>
            <field>
              <name>MISF28</name>
              <bitOffset>28</bitOffset>
              <bitWidth>1</bitWidth>
            </field>
            <field>
              <name>MISF29</name>
              <bitOffset>29</bitOffset>
              <bitWidth>1</bitWidth>
            </field>
            <field>
              <name>MISF30</name>
              <bitOffset>30</bitOffset>
              <bitWidth>1</bitWidth>
            </field>
            <field>
              <name>MISF31</name>
              <bitOffset>31</bitOffset>
              <bitWidth>1</bitWidth>
            </field>
          </fields>
        </register>
        <register>
          <name>CR</name>
          <addressOffset>0x140</addressOffset>
          <size>0x20</size>
          <fields>
            <field>
              <name>COREID</name>
              <bitOffset>8</bitOffset>
              <bitWidth>8</bitWidth>
            </field>
            <field>
              <name>KEY</name>
              <bitOffset>16</bitOffset>
              <bitWidth>16</bitWidth>
            </field>
          </fields>
        </register>
        <register>
          <name>KEYR</name>
          <addressOffset>0x144</addressOffset>
          <size>0x20</size>
          <fields>
            <field>
              <name>KEY</name>
              <bitOffset>16</bitOffset>
              <bitWidth>16</bitWidth>
            </field>
          </fields>
        </register>
      </registers>
    </peripheral>
    <peripheral>
      <name>HSEM_COMMON</name>
      <baseAddress>0x58026500</baseAddress>
      <registers>
        <register>
          <name>IER</name>
          <addressOffset>0x0</addressOffset>
          <size>0x20</size>
        </register>
        <register>
          <name>ICR</name>
          <addressOffset>0x4</addressOffset>
          <size>0x20</size>
        </register>
        <register>
          <name>ISR</name>
          <addressOffset>0x8</addressOffset>
          <size>0x20</size>
        </register>
        <register>
          <name>MISR</name>
          <addressOffset>0xc</addressOffset>
          <size>0x20</size>
        </register>
      </registers>
    </peripheral>
    <peripheral>
      <name>RAMECC3</name>
      <baseAddress>0x58027000</baseAddress>
      <registers>
        <register>
          <name>IER</name>
          <addressOffset>0x0</addressOffset>
          <size>0x20</size>
          <fields>
            <field>
              <name>GIE</name>
              <bitOffset>0</bitOffset>
              <bitWidth>1</bitWidth>
            </field>
            <field>
              <name>GECCSEIE</name>
              <bitOffset>1</bitOffset>
              <bitWidth>1</bitWidth>
            </field>
            <field>
              <name>GECCDEIE</name>
              <bitOffset>2</bitOffset>
              <bitWidth>1</bitWidth>
            </field>
            <field>
              <name>GECCDEBWIE</name>
              <bitOffset>3</bitOffset>
              <bitWidth>1</bitWidth>
            </field>
          </fields>
        </register>
        <register>
          <name>CR1</name>
          <addressOffset>0x20</addressOffset>
          <size>0x20</size>
          <fields>
            <field>
              <name>ECCSEIE</name>
              <bitOffset>2</bitOffset>
              <bitWidth>1</bitWidth>
            </field>
            <field>
              <name>ECCDEIE</name>
              <bitOffset>3</bitOffset>
              <bitWidth>1</bitWidth>
            </field>
            <field>
              <name>ECCDEBWIE</name>
              <bitOffset>4</bitOffset>
              <bitWidth>1</bitWidth>
            </field>
            <field>
              <name>ECCELEN</name>
              <bitOffset>5</bitOffset>
              <bitWidth>1</bitWidth>
            </field>
          </fields>
        </register>
        <register>
          <name>CR1</name>
          <addressOffset>0x20</addressOffset>
          <size>0x20</size>
          <fields>
            <field>
              <name>ECCSEIE</name>
              <bitOffset>2</bitOffset>
              <bitWidth>1</bitWidth>
            </field>
            <field>
              <name>ECCDEIE</name>
              <bitOffset>3</bitOffset>
              <bitWidth>1</bitWidth>
            </field>
            <field>
              <name>ECCDEBWIE</name>
              <bitOffset>4</bitOffset>
              <bitWidth>1</bitWidth>
            </field>
            <field>
              <name>ECCELEN</name>
              <bitOffset>5</bitOffset>
              <bitWidth>1</bitWidth>
            </field>
          </fields>
        </register>
        <register>
          <name>CR1</name>
          <addressOffset>0x20</addressOffset>
          <size>0x20</size>
          <fields>
            <field>
              <name>ECCSEIE</name>
              <bitOffset>2</bitOffset>
              <bitWidth>1</bitWidth>
            </field>
            <field>
              <name>ECCDEIE</name>
              <bitOffset>3</bitOffset>
              <bitWidth>1</bitWidth>
            </field>
            <field>
              <name>ECCDEBWIE</name>
              <bitOffset>4</bitOffset>
              <bitWidth>1</bitWidth>
            </field>
            <field>
              <name>ECCELEN</name>
              <bitOffset>5</bitOffset>
              <bitWidth>1</bitWidth>
            </field>
          </fields>
        </register>
        <register>
          <name>SR1</name>
          <addressOffset>0x24</addressOffset>
          <size>0x20</size>
          <fields>
            <field>
              <name>SEDCF</name>
              <bitOffset>0</bitOffset>
              <bitWidth>1</bitWidth>
            </field>
            <field>
              <name>DEDF</name>
              <bitOffset>1</bitOffset>
              <bitWidth>1</bitWidth>
            </field>
            <field>
              <name>DEBWDF</name>
              <bitOffset>2</bitOffset>
              <bitWidth>1</bitWidth>
            </field>
          </fields>
        </register>
        <register>
          <name>SR1</name>
          <addressOffset>0x24</addressOffset>
          <size>0x20</size>
          <fields>
            <field>
              <name>SEDCF</name>
              <bitOffset>0</bitOffset>
              <bitWidth>1</bitWidth>
            </field>
            <field>
              <name>DEDF</name>
              <bitOffset>1</bitOffset>
              <bitWidth>1</bitWidth>
            </field>
            <field>
              <name>DEBWDF</name>
              <bitOffset>2</bitOffset>
              <bitWidth>1</bitWidth>
            </field>
          </fields>
        </register>
        <register>
          <name>SR1</name>
          <addressOffset>0x24</addressOffset>
          <size>0x20</size>
          <fields>
            <field>
              <name>SEDCF</name>
              <bitOffset>0</bitOffset>
              <bitWidth>1</bitWidth>
            </field>
            <field>
              <name>DEDF</name>
              <bitOffset>1</bitOffset>
              <bitWidth>1</bitWidth>
            </field>
            <field>
              <name>DEBWDF</name>
              <bitOffset>2</bitOffset>
              <bitWidth>1</bitWidth>
            </field>
          </fields>
        </register>
        <register>
          <name>FAR1</name>
          <addressOffset>0x28</addressOffset>
          <size>0x20</size>
          <fields>
            <field>
              <name>FDATAL</name>
              <bitOffset>0</bitOffset>
              <bitWidth>32</bitWidth>
            </field>
          </fields>
        </register>
        <register>
          <name>FAR1</name>
          <addressOffset>0x28</addressOffset>
          <size>0x20</size>
          <fields>
            <field>
              <name>FDATAL</name>
              <bitOffset>0</bitOffset>
              <bitWidth>32</bitWidth>
            </field>
          </fields>
        </register>
        <register>
          <name>FAR1</name>
          <addressOffset>0x28</addressOffset>
          <size>0x20</size>
          <fields>
            <field>
              <name>FDATAL</name>
              <bitOffset>0</bitOffset>
              <bitWidth>32</bitWidth>
            </field>
          </fields>
        </register>
        <register>
          <name>FDRL1</name>
          <addressOffset>0x2c</addressOffset>
          <size>0x20</size>
        </register>
        <register>
          <name>FDRL1</name>
          <addressOffset>0x2c</addressOffset>
          <size>0x20</size>
        </register>
        <register>
          <name>FDRL1</name>
          <addressOffset>0x2c</addressOffset>
          <size>0x20</size>
        </register>
        <register>
          <name>FDRH1</name>
          <addressOffset>0x30</addressOffset>
          <size>0x20</size>
        </register>
        <register>
          <name>FDRH1</name>
          <addressOffset>0x30</addressOffset>
          <size>0x20</size>
        </register>
        <register>
          <name>FDRH1</name>
          <addressOffset>0x30</addressOffset>
          <size>0x20</size>
        </register>
        <register>
          <name>FECR1</name>
          <addressOffset>0x34</addressOffset>
          <size>0x20</size>
          <fields>
            <field>
              <name>FEC</name>
              <bitOffset>0</bitOffset>
              <bitWidth>32</bitWidth>
            </field>
          </fields>
        </register>
        <register>
          <name>FECR1</name>
          <addressOffset>0x34</addressOffset>
          <size>0x20</size>
          <fields>
            <field>
              <name>FEC</name>
              <bitOffset>0</bitOffset>
              <bitWidth>32</bitWidth>
            </field>
          </fields>
        </register>
        <register>
          <name>FECR1</name>
          <addressOffset>0x34</addressOffset>
          <size>0x20</size>
          <fields>
            <field>
              <name>FEC</name>
              <bitOffset>0</bitOffset>
              <bitWidth>32</bitWidth>
            </field>
          </fields>
        </register>
        <register>
          <name>CR2</name>
          <addressOffset>0x40</addressOffset>
          <size>0x20</size>
          <fields>
            <field>
              <name>ECCSEIE</name>
              <bitOffset>2</bitOffset>
              <bitWidth>1</bitWidth>
            </field>
            <field>
              <name>ECCDEIE</name>
              <bitOffset>3</bitOffset>
              <bitWidth>1</bitWidth>
            </field>
            <field>
              <name>ECCDEBWIE</name>
              <bitOffset>4</bitOffset>
              <bitWidth>1</bitWidth>
            </field>
            <field>
              <name>ECCELEN</name>
              <bitOffset>5</bitOffset>
              <bitWidth>1</bitWidth>
            </field>
          </fields>
        </register>
        <register>
          <name>CR2</name>
          <addressOffset>0x40</addressOffset>
          <size>0x20</size>
          <fields>
            <field>
              <name>ECCSEIE</name>
              <bitOffset>2</bitOffset>
              <bitWidth>1</bitWidth>
            </field>
            <field>
              <name>ECCDEIE</name>
              <bitOffset>3</bitOffset>
              <bitWidth>1</bitWidth>
            </field>
            <field>
              <name>ECCDEBWIE</name>
              <bitOffset>4</bitOffset>
              <bitWidth>1</bitWidth>
            </field>
            <field>
              <name>ECCELEN</name>
              <bitOffset>5</bitOffset>
              <bitWidth>1</bitWidth>
            </field>
          </fields>
        </register>
        <register>
          <name>CR2</name>
          <addressOffset>0x40</addressOffset>
          <size>0x20</size>
          <fields>
            <field>
              <name>ECCSEIE</name>
              <bitOffset>2</bitOffset>
              <bitWidth>1</bitWidth>
            </field>
            <field>
              <name>ECCDEIE</name>
              <bitOffset>3</bitOffset>
              <bitWidth>1</bitWidth>
            </field>
            <field>
              <name>ECCDEBWIE</name>
              <bitOffset>4</bitOffset>
              <bitWidth>1</bitWidth>
            </field>
            <field>
              <name>ECCELEN</name>
              <bitOffset>5</bitOffset>
              <bitWidth>1</bitWidth>
            </field>
          </fields>
        </register>
        <register>
          <name>SR2</name>
          <addressOffset>0x44</addressOffset>
          <size>0x20</size>
          <fields>
            <field>
              <name>SEDCF</name>
              <bitOffset>0</bitOffset>
              <bitWidth>1</bitWidth>
            </field>
            <field>
              <name>DEDF</name>
              <bitOffset>1</bitOffset>
              <bitWidth>1</bitWidth>
            </field>
            <field>
              <name>DEBWDF</name>
              <bitOffset>2</bitOffset>
              <bitWidth>1</bitWidth>
            </field>
          </fields>
        </register>
        <register>
          <name>SR2</name>
          <addressOffset>0x44</addressOffset>
          <size>0x20</size>
          <fields>
            <field>
              <name>SEDCF</name>
              <bitOffset>0</bitOffset>
              <bitWidth>1</bitWidth>
            </field>
            <field>
              <name>DEDF</name>
              <bitOffset>1</bitOffset>
              <bitWidth>1</bitWidth>
            </field>
            <field>
              <name>DEBWDF</name>
              <bitOffset>2</bitOffset>
              <bitWidth>1</bitWidth>
            </field>
          </fields>
        </register>
        <register>
          <name>SR2</name>
          <addressOffset>0x44</addressOffset>
          <size>0x20</size>
          <fields>
            <field>
              <name>SEDCF</name>
              <bitOffset>0</bitOffset>
              <bitWidth>1</bitWidth>
            </field>
            <field>
              <name>DEDF</name>
              <bitOffset>1</bitOffset>
              <bitWidth>1</bitWidth>
            </field>
            <field>
              <name>DEBWDF</name>
              <bitOffset>2</bitOffset>
              <bitWidth>1</bitWidth>
            </field>
          </fields>
        </register>
        <register>
          <name>FAR2</name>
          <addressOffset>0x48</addressOffset>
          <size>0x20</size>
          <fields>
            <field>
              <name>FDATAL</name>
              <bitOffset>0</bitOffset>
              <bitWidth>32</bitWidth>
            </field>
          </fields>
        </register>
        <register>
          <name>FAR2</name>
          <addressOffset>0x48</addressOffset>
          <size>0x20</size>
          <fields>
            <field>
              <name>FDATAL</name>
              <bitOffset>0</bitOffset>
              <bitWidth>32</bitWidth>
            </field>
          </fields>
        </register>
        <register>
          <name>FAR2</name>
          <addressOffset>0x48</addressOffset>
          <size>0x20</size>
          <fields>
            <field>
              <name>FDATAL</name>
              <bitOffset>0</bitOffset>
              <bitWidth>32</bitWidth>
            </field>
          </fields>
        </register>
        <register>
          <name>FDRL2</name>
          <addressOffset>0x4c</addressOffset>
          <size>0x20</size>
        </register>
        <register>
          <name>FDRL2</name>
          <addressOffset>0x4c</addressOffset>
          <size>0x20</size>
        </register>
        <register>
          <name>FDRL2</name>
          <addressOffset>0x4c</addressOffset>
          <size>0x20</size>
        </register>
        <register>
          <name>FDRH2</name>
          <addressOffset>0x50</addressOffset>
          <size>0x20</size>
        </register>
        <register>
          <name>FDRH2</name>
          <addressOffset>0x50</addressOffset>
          <size>0x20</size>
        </register>
        <register>
          <name>FDRH2</name>
          <addressOffset>0x50</addressOffset>
          <size>0x20</size>
        </register>
        <register>
          <name>FECR2</name>
          <addressOffset>0x54</addressOffset>
          <size>0x20</size>
          <fields>
            <field>
              <name>FEC</name>
              <bitOffset>0</bitOffset>
              <bitWidth>32</bitWidth>
            </field>
          </fields>
        </register>
        <register>
          <name>FECR2</name>
          <addressOffset>0x54</addressOffset>
          <size>0x20</size>
          <fields>
            <field>
              <name>FEC</name>
              <bitOffset>0</bitOffset>
              <bitWidth>32</bitWidth>
            </field>
          </fields>
        </register>
        <register>
          <name>FECR2</name>
          <addressOffset>0x54</addressOffset>
          <size>0x20</size>
          <fields>
            <field>
              <name>FEC</name>
              <bitOffset>0</bitOffset>
              <bitWidth>32</bitWidth>
            </field>
          </fields>
        </register>
        <register>
          <name>CR3</name>
          <addressOffset>0x60</addressOffset>
          <size>0x20</size>
          <fields>
            <field>
              <name>ECCSEIE</name>
              <bitOffset>2</bitOffset>
              <bitWidth>1</bitWidth>
            </field>
            <field>
              <name>ECCDEIE</name>
              <bitOffset>3</bitOffset>
              <bitWidth>1</bitWidth>
            </field>
            <field>
              <name>ECCDEBWIE</name>
              <bitOffset>4</bitOffset>
              <bitWidth>1</bitWidth>
            </field>
            <field>
              <name>ECCELEN</name>
              <bitOffset>5</bitOffset>
              <bitWidth>1</bitWidth>
            </field>
          </fields>
        </register>
        <register>
          <name>CR3</name>
          <addressOffset>0x60</addressOffset>
          <size>0x20</size>
          <fields>
            <field>
              <name>ECCSEIE</name>
              <bitOffset>2</bitOffset>
              <bitWidth>1</bitWidth>
            </field>
            <field>
              <name>ECCDEIE</name>
              <bitOffset>3</bitOffset>
              <bitWidth>1</bitWidth>
            </field>
            <field>
              <name>ECCDEBWIE</name>
              <bitOffset>4</bitOffset>
              <bitWidth>1</bitWidth>
            </field>
            <field>
              <name>ECCELEN</name>
              <bitOffset>5</bitOffset>
              <bitWidth>1</bitWidth>
            </field>
          </fields>
        </register>
        <register>
          <name>SR3</name>
          <addressOffset>0x64</addressOffset>
          <size>0x20</size>
          <fields>
            <field>
              <name>SEDCF</name>
              <bitOffset>0</bitOffset>
              <bitWidth>1</bitWidth>
            </field>
            <field>
              <name>DEDF</name>
              <bitOffset>1</bitOffset>
              <bitWidth>1</bitWidth>
            </field>
            <field>
              <name>DEBWDF</name>
              <bitOffset>2</bitOffset>
              <bitWidth>1</bitWidth>
            </field>
          </fields>
        </register>
        <register>
          <name>SR3</name>
          <addressOffset>0x64</addressOffset>
          <size>0x20</size>
          <fields>
            <field>
              <name>SEDCF</name>
              <bitOffset>0</bitOffset>
              <bitWidth>1</bitWidth>
            </field>
            <field>
              <name>DEDF</name>
              <bitOffset>1</bitOffset>
              <bitWidth>1</bitWidth>
            </field>
            <field>
              <name>DEBWDF</name>
              <bitOffset>2</bitOffset>
              <bitWidth>1</bitWidth>
            </field>
          </fields>
        </register>
        <register>
          <name>FAR3</name>
          <addressOffset>0x68</addressOffset>
          <size>0x20</size>
          <fields>
            <field>
              <name>FDATAL</name>
              <bitOffset>0</bitOffset>
              <bitWidth>32</bitWidth>
            </field>
          </fields>
        </register>
        <register>
          <name>FAR3</name>
          <addressOffset>0x68</addressOffset>
          <size>0x20</size>
          <fields>
            <field>
              <name>FDATAL</name>
              <bitOffset>0</bitOffset>
              <bitWidth>32</bitWidth>
            </field>
          </fields>
        </register>
        <register>
          <name>FDRL3</name>
          <addressOffset>0x6c</addressOffset>
          <size>0x20</size>
        </register>
        <register>
          <name>FDRL3</name>
          <addressOffset>0x6c</addressOffset>
          <size>0x20</size>
        </register>
        <register>
          <name>FDRH3</name>
          <addressOffset>0x70</addressOffset>
          <size>0x20</size>
        </register>
        <register>
          <name>FDRH3</name>
          <addressOffset>0x70</addressOffset>
          <size>0x20</size>
        </register>
        <register>
          <name>FECR3</name>
          <addressOffset>0x74</addressOffset>
          <size>0x20</size>
          <fields>
            <field>
              <name>FEC</name>
              <bitOffset>0</bitOffset>
              <bitWidth>32</bitWidth>
            </field>
          </fields>
        </register>
        <register>
          <name>FECR3</name>
          <addressOffset>0x74</addressOffset>
          <size>0x20</size>
          <fields>
            <field>
              <name>FEC</name>
              <bitOffset>0</bitOffset>
              <bitWidth>32</bitWidth>
            </field>
          </fields>
        </register>
        <register>
          <name>CR4</name>
          <addressOffset>0x80</addressOffset>
          <size>0x20</size>
          <fields>
            <field>
              <name>ECCSEIE</name>
              <bitOffset>2</bitOffset>
              <bitWidth>1</bitWidth>
            </field>
            <field>
              <name>ECCDEIE</name>
              <bitOffset>3</bitOffset>
              <bitWidth>1</bitWidth>
            </field>
            <field>
              <name>ECCDEBWIE</name>
              <bitOffset>4</bitOffset>
              <bitWidth>1</bitWidth>
            </field>
            <field>
              <name>ECCELEN</name>
              <bitOffset>5</bitOffset>
              <bitWidth>1</bitWidth>
            </field>
          </fields>
        </register>
        <register>
          <name>SR4</name>
          <addressOffset>0x84</addressOffset>
          <size>0x20</size>
          <fields>
            <field>
              <name>SEDCF</name>
              <bitOffset>0</bitOffset>
              <bitWidth>1</bitWidth>
            </field>
            <field>
              <name>DEDF</name>
              <bitOffset>1</bitOffset>
              <bitWidth>1</bitWidth>
            </field>
            <field>
              <name>DEBWDF</name>
              <bitOffset>2</bitOffset>
              <bitWidth>1</bitWidth>
            </field>
          </fields>
        </register>
        <register>
          <name>FAR4</name>
          <addressOffset>0x88</addressOffset>
          <size>0x20</size>
          <fields>
            <field>
              <name>FDATAL</name>
              <bitOffset>0</bitOffset>
              <bitWidth>32</bitWidth>
            </field>
          </fields>
        </register>
        <register>
          <name>FDRL4</name>
          <addressOffset>0x8c</addressOffset>
          <size>0x20</size>
        </register>
        <register>
          <name>FDRH4</name>
          <addressOffset>0x90</addressOffset>
          <size>0x20</size>
        </register>
        <register>
          <name>FECR4</name>
          <addressOffset>0x94</addressOffset>
          <size>0x20</size>
          <fields>
            <field>
              <name>FEC</name>
              <bitOffset>0</bitOffset>
              <bitWidth>32</bitWidth>
            </field>
          </fields>
        </register>
        <register>
          <name>CR5</name>
          <addressOffset>0xa0</addressOffset>
          <size>0x20</size>
          <fields>
            <field>
              <name>ECCSEIE</name>
              <bitOffset>2</bitOffset>
              <bitWidth>1</bitWidth>
            </field>
            <field>
              <name>ECCDEIE</name>
              <bitOffset>3</bitOffset>
              <bitWidth>1</bitWidth>
            </field>
            <field>
              <name>ECCDEBWIE</name>
              <bitOffset>4</bitOffset>
              <bitWidth>1</bitWidth>
            </field>
            <field>
              <name>ECCELEN</name>
              <bitOffset>5</bitOffset>
              <bitWidth>1</bitWidth>
            </field>
          </fields>
        </register>
        <register>
          <name>SR5</name>
          <addressOffset>0xa4</addressOffset>
          <size>0x20</size>
          <fields>
            <field>
              <name>SEDCF</name>
              <bitOffset>0</bitOffset>
              <bitWidth>1</bitWidth>
            </field>
            <field>
              <name>DEDF</name>
              <bitOffset>1</bitOffset>
              <bitWidth>1</bitWidth>
            </field>
            <field>
              <name>DEBWDF</name>
              <bitOffset>2</bitOffset>
              <bitWidth>1</bitWidth>
            </field>
          </fields>
        </register>
        <register>
          <name>FAR5</name>
          <addressOffset>0xa8</addressOffset>
          <size>0x20</size>
          <fields>
            <field>
              <name>FDATAL</name>
              <bitOffset>0</bitOffset>
              <bitWidth>32</bitWidth>
            </field>
          </fields>
        </register>
        <register>
          <name>FDRL5</name>
          <addressOffset>0xac</addressOffset>
          <size>0x20</size>
        </register>
        <register>
          <name>FDRH5</name>
          <addressOffset>0xb0</addressOffset>
          <size>0x20</size>
        </register>
        <register>
          <name>FECR5</name>
          <addressOffset>0xb4</addressOffset>
          <size>0x20</size>
          <fields>
            <field>
              <name>FEC</name>
              <bitOffset>0</bitOffset>
              <bitWidth>32</bitWidth>
            </field>
          </fields>
        </register>
        <register>
          <name>CR6</name>
          <addressOffset>0xc0</addressOffset>
          <size>0x20</size>
          <fields>
            <field>
              <name>ECCSEIE</name>
              <bitOffset>2</bitOffset>
              <bitWidth>1</bitWidth>
            </field>
            <field>
              <name>ECCDEIE</name>
              <bitOffset>3</bitOffset>
              <bitWidth>1</bitWidth>
            </field>
            <field>
              <name>ECCDEBWIE</name>
              <bitOffset>4</bitOffset>
              <bitWidth>1</bitWidth>
            </field>
            <field>
              <name>ECCELEN</name>
              <bitOffset>5</bitOffset>
              <bitWidth>1</bitWidth>
            </field>
          </fields>
        </register>
        <register>
          <name>SR6</name>
          <addressOffset>0xc4</addressOffset>
          <size>0x20</size>
          <fields>
            <field>
              <name>SEDCF</name>
              <bitOffset>0</bitOffset>
              <bitWidth>1</bitWidth>
            </field>
            <field>
              <name>DEDF</name>
              <bitOffset>1</bitOffset>
              <bitWidth>1</bitWidth>
            </field>
            <field>
              <name>DEBWDF</name>
              <bitOffset>2</bitOffset>
              <bitWidth>1</bitWidth>
            </field>
          </fields>
        </register>
        <register>
          <name>FAR6</name>
          <addressOffset>0xc8</addressOffset>
          <size>0x20</size>
          <fields>
            <field>
              <name>FDATAL</name>
              <bitOffset>0</bitOffset>
              <bitWidth>32</bitWidth>
            </field>
          </fields>
        </register>
        <register>
          <name>FDRL6</name>
          <addressOffset>0xcc</addressOffset>
          <size>0x20</size>
        </register>
        <register>
          <name>FDRH6</name>
          <addressOffset>0xd0</addressOffset>
          <size>0x20</size>
        </register>
        <register>
          <name>FECR6</name>
          <addressOffset>0xd4</addressOffset>
          <size>0x20</size>
          <fields>
            <field>
              <name>FEC</name>
              <bitOffset>0</bitOffset>
              <bitWidth>32</bitWidth>
            </field>
          </fields>
        </register>
      </registers>
    </peripheral>
    <peripheral>
      <name>DBGMCU</name>
      <baseAddress>0x5c001000</baseAddress>
      <registers>
        <register>
          <name>IDCODE</name>
          <addressOffset>0x0</addressOffset>
          <size>0x20</size>
          <fields>
            <field>
              <name>DEV_ID</name>
              <bitOffset>0</bitOffset>
              <bitWidth>12</bitWidth>
            </field>
            <field>
              <name>REV_ID</name>
              <bitOffset>16</bitOffset>
              <bitWidth>16</bitWidth>
            </field>
          </fields>
        </register>
        <register>
          <name>CR</name>
          <addressOffset>0x4</addressOffset>
          <size>0x20</size>
          <fields>
            <field>
              <name>DBG_SLEEPD1</name>
              <bitOffset>0</bitOffset>
              <bitWidth>1</bitWidth>
            </field>
            <field>
              <name>DBG_STOPD1</name>
              <bitOffset>1</bitOffset>
              <bitWidth>1</bitWidth>
            </field>
            <field>
              <name>DBG_STANDBYD1</name>
              <bitOffset>2</bitOffset>
              <bitWidth>1</bitWidth>
            </field>
            <field>
              <name>DBG_STOPD3</name>
              <bitOffset>7</bitOffset>
              <bitWidth>1</bitWidth>
            </field>
            <field>
              <name>DBG_STANDBYD3</name>
              <bitOffset>8</bitOffset>
              <bitWidth>1</bitWidth>
            </field>
            <field>
              <name>DBG_TRACECKEN</name>
              <bitOffset>20</bitOffset>
              <bitWidth>1</bitWidth>
            </field>
            <field>
              <name>DBG_CKD1EN</name>
              <bitOffset>21</bitOffset>
              <bitWidth>1</bitWidth>
            </field>
            <field>
              <name>DBG_CKD3EN</name>
              <bitOffset>22</bitOffset>
              <bitWidth>1</bitWidth>
            </field>
            <field>
              <name>DBG_TRGOEN</name>
              <bitOffset>28</bitOffset>
              <bitWidth>1</bitWidth>
            </field>
          </fields>
        </register>
        <register>
          <name>APB3FZ1</name>
          <addressOffset>0x34</addressOffset>
          <size>0x20</size>
          <fields>
            <field>
              <name>DBG_WWDG1</name>
              <bitOffset>6</bitOffset>
              <bitWidth>1</bitWidth>
            </field>
          </fields>
        </register>
        <register>
          <name>APB1LFZ1</name>
          <addressOffset>0x3c</addressOffset>
          <size>0x20</size>
          <fields>
            <field>
              <name>DBG_TIM2</name>
              <bitOffset>0</bitOffset>
              <bitWidth>1</bitWidth>
            </field>
            <field>
              <name>DBG_TIM3</name>
              <bitOffset>1</bitOffset>
              <bitWidth>1</bitWidth>
            </field>
            <field>
              <name>DBG_TIM4</name>
              <bitOffset>2</bitOffset>
              <bitWidth>1</bitWidth>
            </field>
            <field>
              <name>DBG_TIM5</name>
              <bitOffset>3</bitOffset>
              <bitWidth>1</bitWidth>
            </field>
            <field>
              <name>DBG_TIM6</name>
              <bitOffset>4</bitOffset>
              <bitWidth>1</bitWidth>
            </field>
            <field>
              <name>DBG_TIM7</name>
              <bitOffset>5</bitOffset>
              <bitWidth>1</bitWidth>
            </field>
            <field>
              <name>DBG_TIM12</name>
              <bitOffset>6</bitOffset>
              <bitWidth>1</bitWidth>
            </field>
            <field>
              <name>DBG_TIM13</name>
              <bitOffset>7</bitOffset>
              <bitWidth>1</bitWidth>
            </field>
            <field>
              <name>DBG_TIM14</name>
              <bitOffset>8</bitOffset>
              <bitWidth>1</bitWidth>
            </field>
            <field>
              <name>DBG_LPTIM1</name>
              <bitOffset>9</bitOffset>
              <bitWidth>1</bitWidth>
            </field>
            <field>
              <name>DBG_I2C1</name>
              <bitOffset>21</bitOffset>
              <bitWidth>1</bitWidth>
            </field>
            <field>
              <name>DBG_I2C2</name>
              <bitOffset>22</bitOffset>
              <bitWidth>1</bitWidth>
            </field>
            <field>
              <name>DBG_I2C3</name>
              <bitOffset>23</bitOffset>
              <bitWidth>1</bitWidth>
            </field>
            <field>
              <name>DBG_I2C5</name>
              <bitOffset>25</bitOffset>
              <bitWidth>1</bitWidth>
            </field>
          </fields>
        </register>
        <register>
          <name>APB1HFZ1</name>
          <addressOffset>0x44</addressOffset>
          <size>0x20</size>
          <fields>
            <field>
              <name>DBG_TIM24</name>
              <bitOffset>24</bitOffset>
              <bitWidth>1</bitWidth>
            </field>
          </fields>
        </register>
        <register>
          <name>APB2FZ1</name>
          <addressOffset>0x4c</addressOffset>
          <size>0x20</size>
          <fields>
            <field>
              <name>DBG_TIM1</name>
              <bitOffset>0</bitOffset>
              <bitWidth>1</bitWidth>
            </field>
            <field>
              <name>DBG_TIM8</name>
              <bitOffset>1</bitOffset>
              <bitWidth>1</bitWidth>
            </field>
            <field>
              <name>DBG_TIM15</name>
              <bitOffset>16</bitOffset>
              <bitWidth>1</bitWidth>
            </field>
            <field>
              <name>DBG_TIM16</name>
              <bitOffset>17</bitOffset>
              <bitWidth>1</bitWidth>
            </field>
            <field>
              <name>DBG_TIM17</name>
              <bitOffset>18</bitOffset>
              <bitWidth>1</bitWidth>
            </field>
          </fields>
        </register>
        <register>
          <name>APB4FZ1</name>
          <addressOffset>0x54</addressOffset>
          <size>0x20</size>
          <fields>
            <field>
              <name>DBG_I2C4</name>
              <bitOffset>7</bitOffset>
              <bitWidth>1</bitWidth>
            </field>
            <field>
              <name>DBG_LPTIM2</name>
              <bitOffset>9</bitOffset>
              <bitWidth>1</bitWidth>
            </field>
            <field>
              <name>DBG_LPTIM3</name>
              <bitOffset>10</bitOffset>
              <bitWidth>1</bitWidth>
            </field>
            <field>
              <name>DBG_LPTIM4</name>
              <bitOffset>11</bitOffset>
              <bitWidth>1</bitWidth>
            </field>
            <field>
              <name>DBG_LPTIM5</name>
              <bitOffset>12</bitOffset>
              <bitWidth>1</bitWidth>
            </field>
            <field>
              <name>DBG_RTC</name>
              <bitOffset>16</bitOffset>
              <bitWidth>1</bitWidth>
            </field>
            <field>
              <name>DBG_IWDG1</name>
              <bitOffset>18</bitOffset>
              <bitWidth>1</bitWidth>
            </field>
          </fields>
        </register>
        <register>
          <name>PIDR4</name>
          <addressOffset>0xfd0</addressOffset>
          <size>0x20</size>
          <fields>
            <field>
              <name>JEP106CON</name>
              <bitOffset>0</bitOffset>
              <bitWidth>4</bitWidth>
            </field>
            <field>
              <name>4KCOUNT</name>
              <bitOffset>4</bitOffset>
              <bitWidth>4</bitWidth>
            </field>
          </fields>
        </register>
        <register>
          <name>PIDR0</name>
          <addressOffset>0xfe0</addressOffset>
          <size>0x20</size>
          <fields>
            <field>
              <name>PARTNUM</name>
              <bitOffset>0</bitOffset>
              <bitWidth>8</bitWidth>
            </field>
          </fields>
        </register>
        <register>
          <name>PIDR1</name>
          <addressOffset>0xfe4</addressOffset>
          <size>0x20</size>
          <fields>
            <field>
              <name>PARTNUM</name>
              <bitOffset>0</bitOffset>
              <bitWidth>4</bitWidth>
            </field>
            <field>
              <name>JEP106ID</name>
              <bitOffset>4</bitOffset>
              <bitWidth>4</bitWidth>
            </field>
          </fields>
        </register>
        <register>
          <name>PIDR2</name>
          <addressOffset>0xfe8</addressOffset>
          <size>0x20</size>
          <fields>
            <field>
              <name>JEP106ID</name>
              <bitOffset>0</bitOffset>
              <bitWidth>3</bitWidth>
            </field>
            <field>
              <name>JEDEC</name>
              <bitOffset>3</bitOffset>
              <bitWidth>1</bitWidth>
            </field>
            <field>
              <name>REVISION</name>
              <bitOffset>4</bitOffset>
              <bitWidth>4</bitWidth>
            </field>
          </fields>
        </register>
        <register>
          <name>PIDR3</name>
          <addressOffset>0xfec</addressOffset>
          <size>0x20</size>
          <fields>
            <field>
              <name>CMOD</name>
              <bitOffset>0</bitOffset>
              <bitWidth>4</bitWidth>
            </field>
            <field>
              <name>REVAND</name>
              <bitOffset>4</bitOffset>
              <bitWidth>4</bitWidth>
            </field>
          </fields>
        </register>
        <register>
          <name>CIDR0</name>
          <addressOffset>0xff0</addressOffset>
          <size>0x20</size>
        </register>
        <register>
          <name>CIDR1</name>
          <addressOffset>0xff4</addressOffset>
          <size>0x20</size>
        </register>
        <register>
          <name>CIDR2</name>
          <addressOffset>0xff8</addressOffset>
          <size>0x20</size>
        </register>
        <register>
          <name>CIDR3</name>
          <addressOffset>0xffc</addressOffset>
          <size>0x20</size>
        </register>
      </registers>
    </peripheral>
  </peripherals>
</device>
